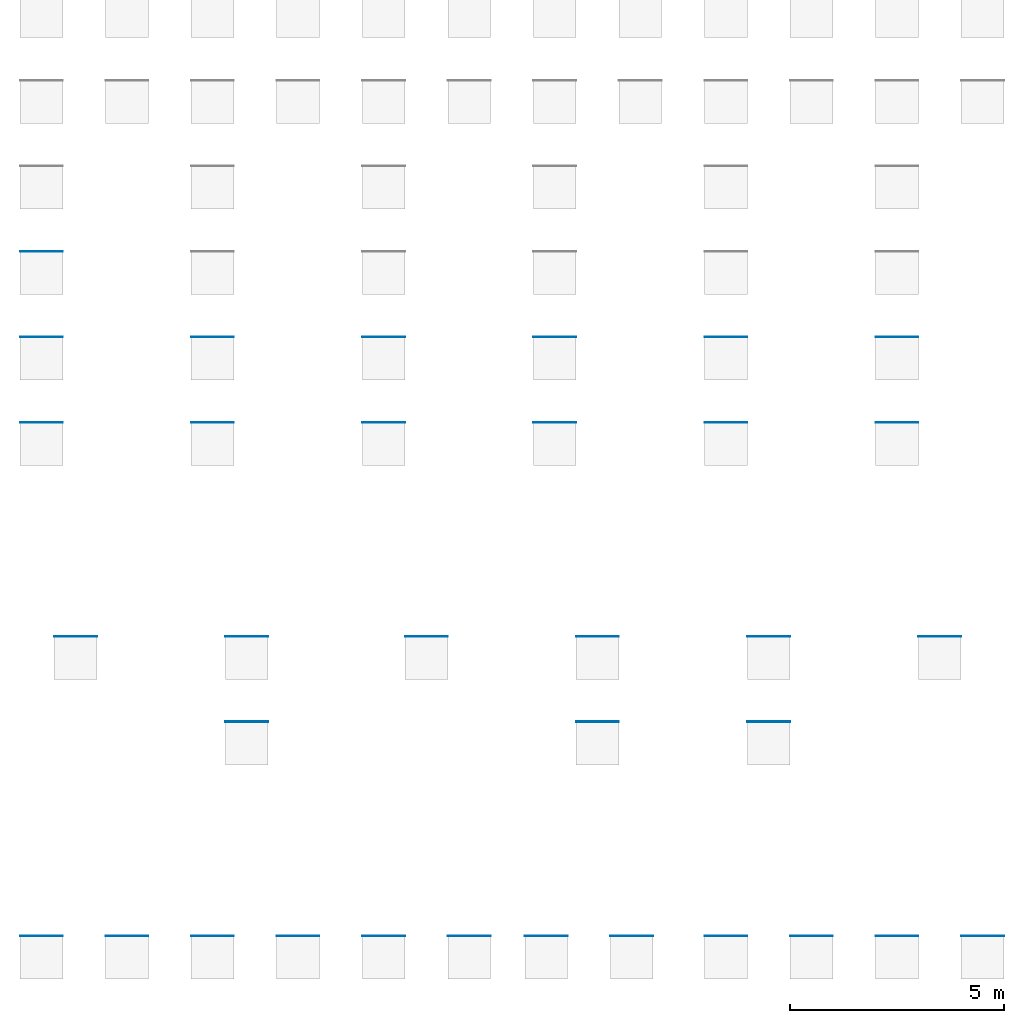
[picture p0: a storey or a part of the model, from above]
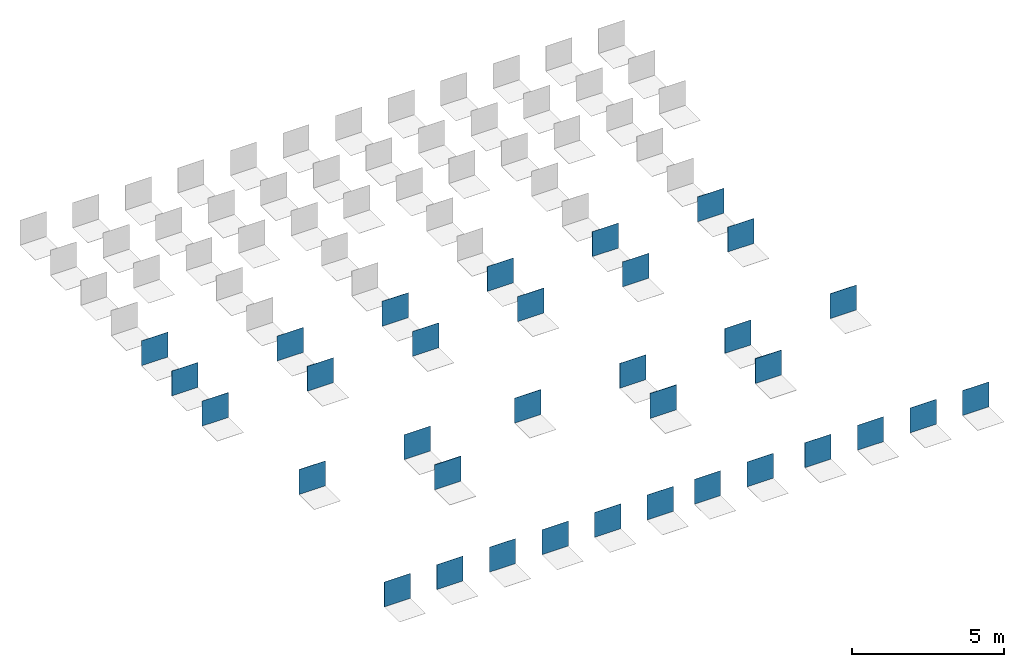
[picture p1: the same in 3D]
Properties of the parts of a building model (IFC2X3), part 1 of 12

# File
Description: ViewDefinition [CoordinationView_V2.0]
Time: 2025-06-20T15:58:34
Written by: The EXPRESS Data Manager Version 5.02.0100.07 : 28 Aug 2013
Made in: 21.1.90.15 - Exporter 21.1.90.15 - Alternate UI 21.1.90.15
Comment: STEP Physical File produced by: The EXPRESS Data Manager Version 5.02.0100.07 : 28 Aug 2013 * Module: EDMstepFileFactory/EDMstandAlone * Creation date: Fri Jun 20 15:58:34 2025 * Host: STB002 * Database: C:\Users\LARISS~1\AppData\Local\Temp\234e31d9-e186-458c-9206-d387dea7a233\3d1c4d9d-6237-41bf-87b0-bd08b7a5a8ec\ifc * Database version: 5507 * Database creation date: Fri Jun 20 15:58:30 2025 * Schema: IFC2X3 * Model: DataRepository.ifc * Model creation date: Fri Jun 20 15:58:30 2025 * Header model: DataRepository.ifc_HeaderModel * Header model creation date: Fri Jun 20 15:58:30 2025 * EDMuser: sdai-user * EDMgroup: sdai-group * License ID and type: 5605 : Permanent license. Expiry date: * EDMstepFileFactory options: 020000

# IfcSite, Default
RefLatitude: 42, 24, 53, 508911; RefLongitude: -71, -15, -29, -58837; RefElevation: 0 mm
Pset_ProductRequirements - Category: Project Information

# IfcBuilding
Pset_BuildingCommon - NumberOfStoreys: 1
Pset_ProductRequirements - Category: Project Information

# IfcBuildingStorey: Level:Level 1, Level 1
LongName: Level 1; Elevation: 0 mm
Pset_AirSideSystemInformation - Name: Level 1
Pset_ProductRequirements - Name: Level 1; Category: Levels

# IfcCovering: Floor:REVIGRÉS-URBAN-BASE-29,5X29,5-RECT-ANTRACITE, Floor:REVIGRÉS-URBAN-BASE-29,5X29,5-RECT-ANTRACITE:18907
In: Level 1
Type - PredefinedType: CLADDING; Material: REVIGRÉS-URBAN-BASE-30X30-RECT-ANTRACITE 7.7 mm
Type - Pset_CoveringCommon - Reference: 31211248U1; Material: Grés porcelânico
Type - Pset_ElementShading - Roughness: 304.8 mm
Type - Pset_ManufacturerTypeInformation - Manufacturer: REVIGRÉS
Type - Pset_ProductRequirements - Category: Floors
Type - Pset_QuantityTakeOff - Reference: 31211248U1
Type - IFC.REVIGRÉS-Dados do fabricante-Floor Covering - FabricanteURL: https://www.revigres.pt/; ReferenciaModelo: Urban; NumeroGlobalDeItemComercial: 31211248U1; Acabamento: RECT; Material: Grés porcelânico; IdentificadorDoOperadorEconomico: 501840856; UrlFabricanteArtigo: https://www.revigres.pt/colecoes/urban; PaisOrigem: Portugal
Type - IFC.REVIGRÉS-Dados de desempenho-Floor Covering - Rectilinearidade: ± 0.2% máx.± 0.8 mm; Ortogonalidade: ± 0.2% máx.± 1.5 mm; PlanaridadeDaSuperficie: ± 0.3% máx. ± 1.8 mm; QualidadeDaSuperficie: Cumpre; AbsorcaoDeAgua: < 0.05%; ModuloDeRuptura: > 45 N/mm²; ResistenciaAFlexao: > 1500 N; ResistenciaAAbrasaoProfunda: < 120 mm³; DilatacaoTermicaLinear: ≤ 8,0x10-6 °C-1; ResistenciaAoChoqueTermico: Resiste; DurabilidadeResistenciaAoGeloDegelo: Resiste; ResistenciaAoEscorregamentoDIN51130: R9; ResistenciaAoEscorregamentoDIN51097: A; ResistenciaAoEscorregamentoENV51097: A; ResistenciaAoEscorregamentoENV12633: Class 1; ResistenciaAoEscorregamentoANSIA1371: ≥0,42; ResistenciaAoDeslizamentoENV12633: Class 1; ResistenciaAsManchas: Class 5; ResistenciaABaixasConcentracoesDeAcidosEAlcalis: Classe LA; ResistenciaAAltasConcentracoesDeAcidosEAlcalis: Classe HA; LibertacaoDeCadmio: 0; LibertacaoDeChumbo: 0
Type - IFC.REVIGRÉS-Dados de especificação-Floor Covering - VariacaoTonalidade: 2; NivelDeTrafego: 5; EPavimento: Sim; ERevestimento: Sim; EExterno: Sim
Type - IFC.REVIGRÉS-Dados geométricos-Floor Covering - AlturaNominal: 7.7 mm; ComprimentoNominal: 29.5 mm; LarguraNominal: 29.5 mm
Type - IFC.REVIGRÉS-Dados de sustentabilidade-Floor Covering - EnergiaTermicaExportada: 0; ItemENovo: Sim; ItemEParcialmenteReciclado: 0.29; ItemEReciclado: Sim; VidaÚtilEsperada: 50; SubstanciasPerigosas: Não; PotencialDeEsgotamentoAbioticoDosRecursosFosseis: 203; PotencialDeEsgotamentoAbioticoDosRecursosNaoFosseisMineraisEMetais: 0.000701; PotencialDeAquecimentoGlobalBiogenico: -0.48; CombustiveisFosseisComPotencialDeAquecimentoGlobal: 13.9; PotencialDeAquecimentoGlobalUsoDoSoloEMudancaDeUsoDoSolo: 0.0246; PotencialDeEutrofizacaoFraccaoDeNutrientesQueAtingemOCompartimentoFinalDeAguaDoce: 0.000189; PotencialDeEutrofizacaoFraccaoDeNutrientesQueAtingemOCompartimentoFinalMarinho: 0.0122; EnergiaRecuperada: 0.00739; ConsumoDeAguaDoce: 0.113; UtilizacaoLiquidaDeAguaDoce: 0.113; ResiduosPerigososEliminados: 0.00221; ResiduosNaoPerigososEliminados: 1.83; MassaTotalDeResiduosRadioactivosEliminados: 0.000394; EnergiaElectricaExportada: 1.55; MateriaisParaRecuperacaoDeEnergia: 0.00739; MateriaisParaReciclagem: 0.0253; UnidadeEPD: 1 m²
Type - IFC.REVIGRÉS-Dados gerais-Floor Covering - Nome: REVIGRÉS-URBAN-BASE-29.5X29.5-RECT-URBAN ANTRACITE; TipoProduto: Prensado a seco: grupo BIa UGL | Grés porcelânico técnico; NumeroDeRegistoDAP: EPD-REV-20240006-CCC1-EN; ReferenciaDAP: -; UrlDOP: -
Classification: C3020 (Uniformat)
Pset_CoveringCommon - TotalThickness: 7.7 mm
IFC.REVIGRÉS-Dados do fabricante-Floor Covering - Type: Floor: REVIGRÉS-URBAN-BASE-29,5X29,5-RECT-ANTRACITE
IFC.REVIGRÉS-Dados de desempenho-Floor Covering - Type: Floor: REVIGRÉS-URBAN-BASE-29,5X29,5-RECT-ANTRACITE
IFC.REVIGRÉS-Dados de especificação-Floor Covering - Type: Floor: REVIGRÉS-URBAN-BASE-29,5X29,5-RECT-ANTRACITE
IFC.REVIGRÉS-Dados geométricos-Floor Covering - Type: Floor: REVIGRÉS-URBAN-BASE-29,5X29,5-RECT-ANTRACITE
IFC.REVIGRÉS-Dados de sustentabilidade-Floor Covering - Type: Floor: REVIGRÉS-URBAN-BASE-29,5X29,5-RECT-ANTRACITE

# IfcCovering: Floor:REVIGRÉS-URBAN-BASE-29,5X29,5-RECT-BONE, Floor:REVIGRÉS-URBAN-BASE-29,5X29,5-RECT-BONE:21508
In: Level 1
Type - PredefinedType: CLADDING; Material: REVIGRÉS-URBAN-BASE-30X30-RECT-BONE 7.7 mm
Type - Pset_CoveringCommon - Reference: 312112X671; Material: Grés porcelânico
Type - Pset_ElementShading - Roughness: 304.8 mm
Type - Pset_ManufacturerTypeInformation - Manufacturer: REVIGRÉS
Type - Pset_ProductRequirements - Category: Floors
Type - Pset_QuantityTakeOff - Reference: 312112X671
Type - IFC.REVIGRÉS-Dados do fabricante-Floor Covering - FabricanteURL: https://www.revigres.pt/; ReferenciaModelo: Urban; NumeroGlobalDeItemComercial: 312112X671; Acabamento: RECT; Material: Grés porcelânico; IdentificadorDoOperadorEconomico: 501840856; UrlFabricanteArtigo: https://www.revigres.pt/colecoes/urban; PaisOrigem: Portugal
Type - IFC.REVIGRÉS-Dados de desempenho-Floor Covering - Rectilinearidade: ± 0.2% máx.± 0.8 mm; Ortogonalidade: ± 0.2% máx.± 1.5 mm; PlanaridadeDaSuperficie: ± 0.3% máx. ± 1.8 mm; QualidadeDaSuperficie: Cumpre; AbsorcaoDeAgua: < 0.05%; ModuloDeRuptura: > 45 N/mm²; ResistenciaAFlexao: > 1500 N; ResistenciaAAbrasaoProfunda: < 120 mm³; DilatacaoTermicaLinear: ≤ 8,0x10-6 °C-1; ResistenciaAoChoqueTermico: Resiste; DurabilidadeResistenciaAoGeloDegelo: Resiste; ResistenciaAoEscorregamentoDIN51130: R9; ResistenciaAoEscorregamentoDIN51097: A; ResistenciaAoEscorregamentoENV51097: A; ResistenciaAoEscorregamentoENV12633: Class 1; ResistenciaAoEscorregamentoANSIA1371: ≥0,42; ResistenciaAoDeslizamentoENV12633: Class 1; ResistenciaAsManchas: Class 5; ResistenciaABaixasConcentracoesDeAcidosEAlcalis: Classe LA; ResistenciaAAltasConcentracoesDeAcidosEAlcalis: Classe HA; LibertacaoDeCadmio: 0; LibertacaoDeChumbo: 0
Type - IFC.REVIGRÉS-Dados de especificação-Floor Covering - VariacaoTonalidade: 2; NivelDeTrafego: 5; EPavimento: Sim; ERevestimento: Sim; EExterno: Sim
Type - IFC.REVIGRÉS-Dados geométricos-Floor Covering - AlturaNominal: 7.7 mm; ComprimentoNominal: 29.5 mm; LarguraNominal: 29.5 mm
Type - IFC.REVIGRÉS-Dados de sustentabilidade-Floor Covering - EnergiaTermicaExportada: 0; ItemENovo: Sim; ItemEParcialmenteReciclado: 0.03; ItemEReciclado: Sim; VidaÚtilEsperada: 50; SubstanciasPerigosas: Não; PotencialDeEsgotamentoAbioticoDosRecursosFosseis: 203; PotencialDeEsgotamentoAbioticoDosRecursosNaoFosseisMineraisEMetais: 0.000701; PotencialDeAquecimentoGlobalBiogenico: -0.48; CombustiveisFosseisComPotencialDeAquecimentoGlobal: 13.9; PotencialDeAquecimentoGlobalUsoDoSoloEMudancaDeUsoDoSolo: 0.0246; PotencialDeEutrofizacaoFraccaoDeNutrientesQueAtingemOCompartimentoFinalDeAguaDoce: 0.000189; PotencialDeEutrofizacaoFraccaoDeNutrientesQueAtingemOCompartimentoFinalMarinho: 0.0122; EnergiaRecuperada: 0.00739; ConsumoDeAguaDoce: 0.113; UtilizacaoLiquidaDeAguaDoce: 0.113; ResiduosPerigososEliminados: 0.00221; ResiduosNaoPerigososEliminados: 1.83; MassaTotalDeResiduosRadioactivosEliminados: 0.000394; EnergiaElectricaExportada: 1.55; MateriaisParaRecuperacaoDeEnergia: 0.00739; MateriaisParaReciclagem: 0.0253; UnidadeEPD: 1 m²
Type - IFC.REVIGRÉS-Dados gerais-Floor Covering - Nome: REVIGRÉS-URBAN-BASE-29.5X29.5-RECT-URBAN BONE; TipoProduto: Prensado a seco: grupo BIa UGL | Grés porcelânico técnico; NumeroDeRegistoDAP: EPD-REV-20240006-CCC1-EN; ReferenciaDAP: -; UrlDOP: -
Classification: C3020 (Uniformat)
Pset_CoveringCommon - TotalThickness: 7.7 mm
IFC.REVIGRÉS-Dados do fabricante-Floor Covering - Type: Floor: REVIGRÉS-URBAN-BASE-29,5X29,5-RECT-BONE
IFC.REVIGRÉS-Dados de desempenho-Floor Covering - Type: Floor: REVIGRÉS-URBAN-BASE-29,5X29,5-RECT-BONE
IFC.REVIGRÉS-Dados de especificação-Floor Covering - Type: Floor: REVIGRÉS-URBAN-BASE-29,5X29,5-RECT-BONE
IFC.REVIGRÉS-Dados geométricos-Floor Covering - Type: Floor: REVIGRÉS-URBAN-BASE-29,5X29,5-RECT-BONE
IFC.REVIGRÉS-Dados de sustentabilidade-Floor Covering - Type: Floor: REVIGRÉS-URBAN-BASE-29,5X29,5-RECT-BONE

# IfcCovering: Floor:REVIGRÉS-URBAN-BASE-29,5X29,5-RECT-CRAFT, Floor:REVIGRÉS-URBAN-BASE-29,5X29,5-RECT-CRAFT:21530
In: Level 1
Type - PredefinedType: CLADDING; Material: REVIGRÉS-URBAN-BASE-30X30-RECT-CRAFT 7.7 mm
Type - Pset_CoveringCommon - Reference: 31211224T1; Material: Grés porcelânico
Type - Pset_ElementShading - Roughness: 304.8 mm
Type - Pset_ManufacturerTypeInformation - Manufacturer: REVIGRÉS
Type - Pset_ProductRequirements - Category: Floors
Type - Pset_QuantityTakeOff - Reference: 31211224T1
Type - IFC.REVIGRÉS-Dados do fabricante-Floor Covering - FabricanteURL: https://www.revigres.pt/; ReferenciaModelo: Urban; NumeroGlobalDeItemComercial: 31211224T1; Acabamento: RECT; Material: Grés porcelânico; IdentificadorDoOperadorEconomico: 501840856; UrlFabricanteArtigo: https://www.revigres.pt/colecoes/urban; PaisOrigem: Portugal
Type - IFC.REVIGRÉS-Dados de desempenho-Floor Covering - Rectilinearidade: ± 0.2% máx.± 0.8 mm; Ortogonalidade: ± 0.2% máx.± 1.5 mm; PlanaridadeDaSuperficie: ± 0.3% máx. ± 1.8 mm; QualidadeDaSuperficie: Cumpre; AbsorcaoDeAgua: < 0.05%; ModuloDeRuptura: > 45 N/mm²; ResistenciaAFlexao: > 1500 N; ResistenciaAAbrasaoProfunda: < 120 mm³; DilatacaoTermicaLinear: ≤ 8,0x10-6 °C-1; ResistenciaAoChoqueTermico: Resiste; DurabilidadeResistenciaAoGeloDegelo: Resiste; ResistenciaAoEscorregamentoDIN51130: R9; ResistenciaAoEscorregamentoDIN51097: A; ResistenciaAoEscorregamentoENV51097: A; ResistenciaAoEscorregamentoENV12633: Class 1; ResistenciaAoEscorregamentoANSIA1371: ≥0,42; ResistenciaAoDeslizamentoENV12633: Class 1; ResistenciaAsManchas: Class 5; ResistenciaABaixasConcentracoesDeAcidosEAlcalis: Classe LA; ResistenciaAAltasConcentracoesDeAcidosEAlcalis: Classe HA; LibertacaoDeCadmio: 0; LibertacaoDeChumbo: 0
Type - IFC.REVIGRÉS-Dados de especificação-Floor Covering - VariacaoTonalidade: 2; NivelDeTrafego: 5; EPavimento: Sim; ERevestimento: Sim; EExterno: Sim
Type - IFC.REVIGRÉS-Dados geométricos-Floor Covering - AlturaNominal: 7.7 mm; ComprimentoNominal: 29.5 mm; LarguraNominal: 29.5 mm
Type - IFC.REVIGRÉS-Dados de sustentabilidade-Floor Covering - EnergiaTermicaExportada: 0; ItemENovo: Sim; ItemEParcialmenteReciclado: 0.19; ItemEReciclado: Sim; VidaÚtilEsperada: 50; SubstanciasPerigosas: Não; PotencialDeEsgotamentoAbioticoDosRecursosFosseis: 203; PotencialDeEsgotamentoAbioticoDosRecursosNaoFosseisMineraisEMetais: 0.000701; PotencialDeAquecimentoGlobalBiogenico: -0.48; CombustiveisFosseisComPotencialDeAquecimentoGlobal: 13.9; PotencialDeAquecimentoGlobalUsoDoSoloEMudancaDeUsoDoSolo: 0.0246; PotencialDeEutrofizacaoFraccaoDeNutrientesQueAtingemOCompartimentoFinalDeAguaDoce: 0.000189; PotencialDeEutrofizacaoFraccaoDeNutrientesQueAtingemOCompartimentoFinalMarinho: 0.0122; EnergiaRecuperada: 0.00739; ConsumoDeAguaDoce: 0.113; UtilizacaoLiquidaDeAguaDoce: 0.113; ResiduosPerigososEliminados: 0.00221; ResiduosNaoPerigososEliminados: 1.83; MassaTotalDeResiduosRadioactivosEliminados: 0.000394; EnergiaElectricaExportada: 1.55; MateriaisParaRecuperacaoDeEnergia: 0.00739; MateriaisParaReciclagem: 0.0253; UnidadeEPD: 1 m²
Type - IFC.REVIGRÉS-Dados gerais-Floor Covering - Nome: REVIGRÉS-URBAN-BASE-29.5X29.5-RECT-URBAN CRAFT; TipoProduto: Prensado a seco: grupo BIa UGL | Grés porcelânico técnico; NumeroDeRegistoDAP: EPD-REV-20240006-CCC1-EN; ReferenciaDAP: -; UrlDOP: -
Classification: C3020 (Uniformat)
Pset_CoveringCommon - TotalThickness: 7.7 mm
IFC.REVIGRÉS-Dados do fabricante-Floor Covering - Type: Floor: REVIGRÉS-URBAN-BASE-29,5X29,5-RECT-CRAFT
IFC.REVIGRÉS-Dados de desempenho-Floor Covering - Type: Floor: REVIGRÉS-URBAN-BASE-29,5X29,5-RECT-CRAFT
IFC.REVIGRÉS-Dados de especificação-Floor Covering - Type: Floor: REVIGRÉS-URBAN-BASE-29,5X29,5-RECT-CRAFT
IFC.REVIGRÉS-Dados geométricos-Floor Covering - Type: Floor: REVIGRÉS-URBAN-BASE-29,5X29,5-RECT-CRAFT
IFC.REVIGRÉS-Dados de sustentabilidade-Floor Covering - Type: Floor: REVIGRÉS-URBAN-BASE-29,5X29,5-RECT-CRAFT

# IfcCovering: Floor:REVIGRÉS-URBAN-BASE-29,5X29,5-RECT-FOG, Floor:REVIGRÉS-URBAN-BASE-29,5X29,5-RECT-FOG:21552
In: Level 1
Type - PredefinedType: CLADDING; Material: REVIGRÉS-URBAN-BASE-30X30-RECT-FOG 7.7 mm
Type - Pset_CoveringCommon - Reference: 31211221T1; Material: Grés porcelânico
Type - Pset_ElementShading - Roughness: 304.8 mm
Type - Pset_ManufacturerTypeInformation - Manufacturer: REVIGRÉS
Type - Pset_ProductRequirements - Category: Floors
Type - Pset_QuantityTakeOff - Reference: 31211221T1
Type - IFC.REVIGRÉS-Dados do fabricante-Floor Covering - FabricanteURL: https://www.revigres.pt/; ReferenciaModelo: Urban; NumeroGlobalDeItemComercial: 31211221T1; Acabamento: RECT; Material: Grés porcelânico; IdentificadorDoOperadorEconomico: 501840856; UrlFabricanteArtigo: https://www.revigres.pt/colecoes/urban; PaisOrigem: Portugal
Type - IFC.REVIGRÉS-Dados de desempenho-Floor Covering - Rectilinearidade: ± 0.2% máx.± 0.8 mm; Ortogonalidade: ± 0.2% máx.± 1.5 mm; PlanaridadeDaSuperficie: ± 0.3% máx. ± 1.8 mm; QualidadeDaSuperficie: Cumpre; AbsorcaoDeAgua: < 0.05%; ModuloDeRuptura: > 45 N/mm²; ResistenciaAFlexao: > 1500 N; ResistenciaAAbrasaoProfunda: < 120 mm³; DilatacaoTermicaLinear: ≤ 8,0x10-6 °C-1; ResistenciaAoChoqueTermico: Resiste; DurabilidadeResistenciaAoGeloDegelo: Resiste; ResistenciaAoEscorregamentoDIN51130: R9; ResistenciaAoEscorregamentoDIN51097: A; ResistenciaAoEscorregamentoENV51097: A; ResistenciaAoEscorregamentoENV12633: Class 1; ResistenciaAoEscorregamentoANSIA1371: ≥0,42; ResistenciaAoDeslizamentoENV12633: Class 1; ResistenciaAsManchas: Class 5; ResistenciaABaixasConcentracoesDeAcidosEAlcalis: Classe LA; ResistenciaAAltasConcentracoesDeAcidosEAlcalis: Classe HA; LibertacaoDeCadmio: 0; LibertacaoDeChumbo: 0
Type - IFC.REVIGRÉS-Dados de especificação-Floor Covering - VariacaoTonalidade: 2; NivelDeTrafego: 5; EPavimento: Sim; ERevestimento: Sim; EExterno: Sim
Type - IFC.REVIGRÉS-Dados geométricos-Floor Covering - AlturaNominal: 7.7 mm; ComprimentoNominal: 29.5 mm; LarguraNominal: 29.5 mm
Type - IFC.REVIGRÉS-Dados de sustentabilidade-Floor Covering - EnergiaTermicaExportada: 0; ItemENovo: Sim; ItemEParcialmenteReciclado: 0.23; ItemEReciclado: Sim; VidaÚtilEsperada: 50; SubstanciasPerigosas: Não; PotencialDeEsgotamentoAbioticoDosRecursosFosseis: 203; PotencialDeEsgotamentoAbioticoDosRecursosNaoFosseisMineraisEMetais: 0.000701; PotencialDeAquecimentoGlobalBiogenico: -0.48; CombustiveisFosseisComPotencialDeAquecimentoGlobal: 13.9; PotencialDeAquecimentoGlobalUsoDoSoloEMudancaDeUsoDoSolo: 0.0246; PotencialDeEutrofizacaoFraccaoDeNutrientesQueAtingemOCompartimentoFinalDeAguaDoce: 0.000189; PotencialDeEutrofizacaoFraccaoDeNutrientesQueAtingemOCompartimentoFinalMarinho: 0.0122; EnergiaRecuperada: 0.00739; ConsumoDeAguaDoce: 0.113; UtilizacaoLiquidaDeAguaDoce: 0.113; ResiduosPerigososEliminados: 0.00221; ResiduosNaoPerigososEliminados: 1.83; MassaTotalDeResiduosRadioactivosEliminados: 0.000394; EnergiaElectricaExportada: 1.55; MateriaisParaRecuperacaoDeEnergia: 0.00739; MateriaisParaReciclagem: 0.0253; UnidadeEPD: 1 m²
Type - IFC.REVIGRÉS-Dados gerais-Floor Covering - Nome: REVIGRÉS-URBAN-BASE-29.5X29.5-RECT-URBAN FOG; TipoProduto: Prensado a seco: grupo BIa UGL | Grés porcelânico técnico; NumeroDeRegistoDAP: EPD-REV-20240006-CCC1-EN; ReferenciaDAP: -; UrlDOP: -
Classification: C3020 (Uniformat)
Pset_CoveringCommon - TotalThickness: 7.7 mm
IFC.REVIGRÉS-Dados do fabricante-Floor Covering - Type: Floor: REVIGRÉS-URBAN-BASE-29,5X29,5-RECT-FOG
IFC.REVIGRÉS-Dados de desempenho-Floor Covering - Type: Floor: REVIGRÉS-URBAN-BASE-29,5X29,5-RECT-FOG
IFC.REVIGRÉS-Dados de especificação-Floor Covering - Type: Floor: REVIGRÉS-URBAN-BASE-29,5X29,5-RECT-FOG
IFC.REVIGRÉS-Dados geométricos-Floor Covering - Type: Floor: REVIGRÉS-URBAN-BASE-29,5X29,5-RECT-FOG
IFC.REVIGRÉS-Dados de sustentabilidade-Floor Covering - Type: Floor: REVIGRÉS-URBAN-BASE-29,5X29,5-RECT-FOG

# IfcCovering: Floor:REVIGRÉS-URBAN-BASE-29,5X29,5-RECT-GRIS, Floor:REVIGRÉS-URBAN-BASE-29,5X29,5-RECT-GRIS:21574
In: Level 1
Type - PredefinedType: CLADDING; Material: REVIGRÉS-URBAN-BASE-30X30-RECT-GRIS 7.7 mm
Type - Pset_CoveringCommon - Reference: 31211222T1; Material: Grés porcelânico
Type - Pset_ElementShading - Roughness: 304.8 mm
Type - Pset_ManufacturerTypeInformation - Manufacturer: REVIGRÉS
Type - Pset_ProductRequirements - Category: Floors
Type - Pset_QuantityTakeOff - Reference: 31211222T1
Type - IFC.REVIGRÉS-Dados do fabricante-Floor Covering - FabricanteURL: https://www.revigres.pt/; ReferenciaModelo: Urban; NumeroGlobalDeItemComercial: 31211222T1; Acabamento: RECT; Material: Grés porcelânico; IdentificadorDoOperadorEconomico: 501840856; UrlFabricanteArtigo: https://www.revigres.pt/colecoes/urban; PaisOrigem: Portugal
Type - IFC.REVIGRÉS-Dados de desempenho-Floor Covering - Rectilinearidade: ± 0.2% máx.± 0.8 mm; Ortogonalidade: ± 0.2% máx.± 1.5 mm; PlanaridadeDaSuperficie: ± 0.3% máx. ± 1.8 mm; QualidadeDaSuperficie: Cumpre; AbsorcaoDeAgua: < 0.05%; ModuloDeRuptura: > 45 N/mm²; ResistenciaAFlexao: > 1500 N; ResistenciaAAbrasaoProfunda: < 120 mm³; DilatacaoTermicaLinear: ≤ 8,0x10-6 °C-1; ResistenciaAoChoqueTermico: Resiste; DurabilidadeResistenciaAoGeloDegelo: Resiste; ResistenciaAoEscorregamentoDIN51130: R9; ResistenciaAoEscorregamentoDIN51097: A; ResistenciaAoEscorregamentoENV51097: A; ResistenciaAoEscorregamentoENV12633: Class 1; ResistenciaAoEscorregamentoANSIA1371: ≥0,42; ResistenciaAoDeslizamentoENV12633: Class 1; ResistenciaAsManchas: Class 5; ResistenciaABaixasConcentracoesDeAcidosEAlcalis: Classe LA; ResistenciaAAltasConcentracoesDeAcidosEAlcalis: Classe HA; LibertacaoDeCadmio: 0; LibertacaoDeChumbo: 0
Type - IFC.REVIGRÉS-Dados de especificação-Floor Covering - VariacaoTonalidade: 2; NivelDeTrafego: 5; EPavimento: Sim; ERevestimento: Sim; EExterno: Sim
Type - IFC.REVIGRÉS-Dados geométricos-Floor Covering - AlturaNominal: 7.7 mm; ComprimentoNominal: 29.5 mm; LarguraNominal: 29.5 mm
Type - IFC.REVIGRÉS-Dados de sustentabilidade-Floor Covering - EnergiaTermicaExportada: 0; ItemENovo: Sim; ItemEParcialmenteReciclado: 0.23; ItemEReciclado: Sim; VidaÚtilEsperada: 50; SubstanciasPerigosas: Não; PotencialDeEsgotamentoAbioticoDosRecursosFosseis: 203; PotencialDeEsgotamentoAbioticoDosRecursosNaoFosseisMineraisEMetais: 0.000701; PotencialDeAquecimentoGlobalBiogenico: -0.48; CombustiveisFosseisComPotencialDeAquecimentoGlobal: 13.9; PotencialDeAquecimentoGlobalUsoDoSoloEMudancaDeUsoDoSolo: 0.0246; PotencialDeEutrofizacaoFraccaoDeNutrientesQueAtingemOCompartimentoFinalDeAguaDoce: 0.000189; PotencialDeEutrofizacaoFraccaoDeNutrientesQueAtingemOCompartimentoFinalMarinho: 0.0122; EnergiaRecuperada: 0.00739; ConsumoDeAguaDoce: 0.113; UtilizacaoLiquidaDeAguaDoce: 0.113; ResiduosPerigososEliminados: 0.00221; ResiduosNaoPerigososEliminados: 1.83; MassaTotalDeResiduosRadioactivosEliminados: 0.000394; EnergiaElectricaExportada: 1.55; MateriaisParaRecuperacaoDeEnergia: 0.00739; MateriaisParaReciclagem: 0.0253; UnidadeEPD: 1 m²
Type - IFC.REVIGRÉS-Dados gerais-Floor Covering - Nome: REVIGRÉS-URBAN-BASE-29.5X29.5-RECT-URBAN GRIS; TipoProduto: Prensado a seco: grupo BIa UGL | Grés porcelânico técnico; NumeroDeRegistoDAP: EPD-REV-20240006-CCC1-EN; ReferenciaDAP: -; UrlDOP: -
Classification: C3020 (Uniformat)
Pset_CoveringCommon - TotalThickness: 7.7 mm
IFC.REVIGRÉS-Dados do fabricante-Floor Covering - Type: Floor: REVIGRÉS-URBAN-BASE-29,5X29,5-RECT-GRIS
IFC.REVIGRÉS-Dados de desempenho-Floor Covering - Type: Floor: REVIGRÉS-URBAN-BASE-29,5X29,5-RECT-GRIS
IFC.REVIGRÉS-Dados de especificação-Floor Covering - Type: Floor: REVIGRÉS-URBAN-BASE-29,5X29,5-RECT-GRIS
IFC.REVIGRÉS-Dados geométricos-Floor Covering - Type: Floor: REVIGRÉS-URBAN-BASE-29,5X29,5-RECT-GRIS
IFC.REVIGRÉS-Dados de sustentabilidade-Floor Covering - Type: Floor: REVIGRÉS-URBAN-BASE-29,5X29,5-RECT-GRIS

# IfcCovering: Floor:REVIGRÉS-URBAN-BASE-29,5X29,5-RECT-OFFWHITE, Floor:REVIGRÉS-URBAN-BASE-29,5X29,5-RECT-OFFWHITE:21596
In: Level 1
Type - PredefinedType: CLADDING; Material: REVIGRÉS-URBAN-BASE-30X30-RECT-OFFWHITE 7.7 mm
Type - Pset_CoveringCommon - Reference: 31211223T1; Material: Grés porcelânico
Type - Pset_ElementShading - Roughness: 304.8 mm
Type - Pset_ManufacturerTypeInformation - Manufacturer: REVIGRÉS
Type - Pset_ProductRequirements - Category: Floors
Type - Pset_QuantityTakeOff - Reference: 31211223T1
Type - IFC.REVIGRÉS-Dados do fabricante-Floor Covering - FabricanteURL: https://www.revigres.pt/; ReferenciaModelo: Urban; NumeroGlobalDeItemComercial: 31211223T1; Acabamento: RECT; Material: Grés porcelânico; IdentificadorDoOperadorEconomico: 501840856; UrlFabricanteArtigo: https://www.revigres.pt/colecoes/urban; PaisOrigem: Portugal
Type - IFC.REVIGRÉS-Dados de desempenho-Floor Covering - Rectilinearidade: ± 0.2% máx.± 0.8 mm; Ortogonalidade: ± 0.2% máx.± 1.5 mm; PlanaridadeDaSuperficie: ± 0.3% máx. ± 1.8 mm; QualidadeDaSuperficie: Cumpre; AbsorcaoDeAgua: < 0.05%; ModuloDeRuptura: > 45 N/mm²; ResistenciaAFlexao: > 1500 N; ResistenciaAAbrasaoProfunda: < 120 mm³; DilatacaoTermicaLinear: ≤ 8,0x10-6 °C-1; ResistenciaAoChoqueTermico: Resiste; DurabilidadeResistenciaAoGeloDegelo: Resiste; ResistenciaAoEscorregamentoDIN51130: R9; ResistenciaAoEscorregamentoDIN51097: A; ResistenciaAoEscorregamentoENV51097: A; ResistenciaAoEscorregamentoENV12633: Class 1; ResistenciaAoEscorregamentoANSIA1371: ≥0,42; ResistenciaAoDeslizamentoENV12633: Class 1; ResistenciaAsManchas: Class 5; ResistenciaABaixasConcentracoesDeAcidosEAlcalis: Classe LA; ResistenciaAAltasConcentracoesDeAcidosEAlcalis: Classe HA; LibertacaoDeCadmio: 0; LibertacaoDeChumbo: 0
Type - IFC.REVIGRÉS-Dados de especificação-Floor Covering - VariacaoTonalidade: 2; NivelDeTrafego: 5; EPavimento: Sim; ERevestimento: Sim; EExterno: Sim
Type - IFC.REVIGRÉS-Dados geométricos-Floor Covering - AlturaNominal: 7.7 mm; ComprimentoNominal: 29.5 mm; LarguraNominal: 29.5 mm
Type - IFC.REVIGRÉS-Dados de sustentabilidade-Floor Covering - EnergiaTermicaExportada: 0; ItemENovo: Sim; ItemEParcialmenteReciclado: 0.03; ItemEReciclado: Sim; VidaÚtilEsperada: 50; SubstanciasPerigosas: Não; PotencialDeEsgotamentoAbioticoDosRecursosFosseis: 203; PotencialDeEsgotamentoAbioticoDosRecursosNaoFosseisMineraisEMetais: 0.000701; PotencialDeAquecimentoGlobalBiogenico: -0.48; CombustiveisFosseisComPotencialDeAquecimentoGlobal: 13.9; PotencialDeAquecimentoGlobalUsoDoSoloEMudancaDeUsoDoSolo: 0.0246; PotencialDeEutrofizacaoFraccaoDeNutrientesQueAtingemOCompartimentoFinalDeAguaDoce: 0.000189; PotencialDeEutrofizacaoFraccaoDeNutrientesQueAtingemOCompartimentoFinalMarinho: 0.0122; EnergiaRecuperada: 0.00739; ConsumoDeAguaDoce: 0.113; UtilizacaoLiquidaDeAguaDoce: 0.113; ResiduosPerigososEliminados: 0.00221; ResiduosNaoPerigososEliminados: 1.83; MassaTotalDeResiduosRadioactivosEliminados: 0.000394; EnergiaElectricaExportada: 1.55; MateriaisParaRecuperacaoDeEnergia: 0.00739; MateriaisParaReciclagem: 0.0253; UnidadeEPD: 1 m²
Type - IFC.REVIGRÉS-Dados gerais-Floor Covering - Nome: REVIGRÉS-URBAN-BASE-29.5X29.5-RECT-URBAN OFFWHITE; TipoProduto: Prensado a seco: grupo BIa UGL | Grés porcelânico técnico; NumeroDeRegistoDAP: EPD-REV-20240006-CCC1-EN; ReferenciaDAP: -; UrlDOP: -
Classification: C3020 (Uniformat)
Pset_CoveringCommon - TotalThickness: 7.7 mm
IFC.REVIGRÉS-Dados do fabricante-Floor Covering - Type: Floor: REVIGRÉS-URBAN-BASE-29,5X29,5-RECT-OFFWHITE
IFC.REVIGRÉS-Dados de desempenho-Floor Covering - Type: Floor: REVIGRÉS-URBAN-BASE-29,5X29,5-RECT-OFFWHITE
IFC.REVIGRÉS-Dados de especificação-Floor Covering - Type: Floor: REVIGRÉS-URBAN-BASE-29,5X29,5-RECT-OFFWHITE
IFC.REVIGRÉS-Dados geométricos-Floor Covering - Type: Floor: REVIGRÉS-URBAN-BASE-29,5X29,5-RECT-OFFWHITE
IFC.REVIGRÉS-Dados de sustentabilidade-Floor Covering - Type: Floor: REVIGRÉS-URBAN-BASE-29,5X29,5-RECT-OFFWHITE

# IfcCovering: Floor:REVIGRÉS-URBAN-BASE-29,5X59,2-RECT-ANTRACITE, Floor:REVIGRÉS-URBAN-BASE-29,5X59,2-RECT-ANTRACITE:22474
In: Level 1
Type - PredefinedType: CLADDING; Material: REVIGRÉS-URBAN-BASE-30X60-RECT-ANTRACITE 8.5 mm
Type - Pset_CoveringCommon - Reference: 31212148U1; Material: Grés porcelânico
Type - Pset_ElementShading - Roughness: 304.8 mm
Type - Pset_ManufacturerTypeInformation - Manufacturer: REVIGRÉS
Type - Pset_ProductRequirements - Category: Floors
Type - Pset_QuantityTakeOff - Reference: 31212148U1
Type - IFC.REVIGRÉS-Dados do fabricante-Floor Covering - FabricanteURL: https://www.revigres.pt/; ReferenciaModelo: Urban; NumeroGlobalDeItemComercial: 31212148U1; Acabamento: RECT; Material: Grés porcelânico; IdentificadorDoOperadorEconomico: 501840856; UrlFabricanteArtigo: https://www.revigres.pt/colecoes/urban; PaisOrigem: Portugal
Type - IFC.REVIGRÉS-Dados de desempenho-Floor Covering - Rectilinearidade: ± 0.2% máx.± 0.8 mm; Ortogonalidade: ± 0.2% máx.± 1.5 mm; PlanaridadeDaSuperficie: ± 0.3% máx. ± 1.8 mm; QualidadeDaSuperficie: Cumpre; AbsorcaoDeAgua: < 0.05%; ModuloDeRuptura: > 45 N/mm²; ResistenciaAFlexao: > 2000 N; ResistenciaAAbrasaoProfunda: < 120 mm³; DilatacaoTermicaLinear: ≤ 8,0x10-6 °C-1; ResistenciaAoChoqueTermico: Resiste; DurabilidadeResistenciaAoGeloDegelo: Resiste; ResistenciaAoEscorregamentoDIN51130: R9; ResistenciaAoEscorregamentoDIN51097: A; ResistenciaAoEscorregamentoENV51097: A; ResistenciaAoEscorregamentoENV12633: Class 1; ResistenciaAoEscorregamentoANSIA1371: ≥0,42; ResistenciaAoDeslizamentoENV12633: Class 1; ResistenciaAsManchas: Class 5; ResistenciaABaixasConcentracoesDeAcidosEAlcalis: Classe LA; ResistenciaAAltasConcentracoesDeAcidosEAlcalis: Classe HA; LibertacaoDeCadmio: 0; LibertacaoDeChumbo: 0
Type - IFC.REVIGRÉS-Dados de especificação-Floor Covering - VariacaoTonalidade: 2; NivelDeTrafego: 5; EPavimento: Sim; ERevestimento: Sim; EExterno: Sim
Type - IFC.REVIGRÉS-Dados geométricos-Floor Covering - AlturaNominal: 8.5 mm; ComprimentoNominal: 29.5 mm; LarguraNominal: 59.2 mm
Type - IFC.REVIGRÉS-Dados de sustentabilidade-Floor Covering - EnergiaTermicaExportada: 0; ItemENovo: Sim; ItemEParcialmenteReciclado: 0.29; ItemEReciclado: Sim; VidaÚtilEsperada: 50; SubstanciasPerigosas: Não; PotencialDeEsgotamentoAbioticoDosRecursosFosseis: 203; PotencialDeEsgotamentoAbioticoDosRecursosNaoFosseisMineraisEMetais: 0.000701; PotencialDeAquecimentoGlobalBiogenico: -0.48; CombustiveisFosseisComPotencialDeAquecimentoGlobal: 13.9; PotencialDeAquecimentoGlobalUsoDoSoloEMudancaDeUsoDoSolo: 0.0246; PotencialDeEutrofizacaoFraccaoDeNutrientesQueAtingemOCompartimentoFinalDeAguaDoce: 0.000189; PotencialDeEutrofizacaoFraccaoDeNutrientesQueAtingemOCompartimentoFinalMarinho: 0.0122; EnergiaRecuperada: 0.00739; ConsumoDeAguaDoce: 0.113; UtilizacaoLiquidaDeAguaDoce: 0.113; ResiduosPerigososEliminados: 0.00221; ResiduosNaoPerigososEliminados: 1.83; MassaTotalDeResiduosRadioactivosEliminados: 0.000394; EnergiaElectricaExportada: 1.55; MateriaisParaRecuperacaoDeEnergia: 0.00739; MateriaisParaReciclagem: 0.0253; UnidadeEPD: 1 m²
Type - IFC.REVIGRÉS-Dados gerais-Floor Covering - Nome: REVIGRÉS-URBAN-BASE-29.5X59.2-RECT-URBAN ANTRACITE; TipoProduto: Prensado a seco: grupo BIa UGL | Grés porcelânico técnico; NumeroDeRegistoDAP: EPD-REV-20240006-CCC1-EN; ReferenciaDAP: -; UrlDOP: -
Classification: C3020 (Uniformat)
Pset_CoveringCommon - TotalThickness: 8.5 mm
IFC.REVIGRÉS-Dados do fabricante-Floor Covering - Type: Floor: REVIGRÉS-URBAN-BASE-29,5X59,2-RECT-ANTRACITE
IFC.REVIGRÉS-Dados de desempenho-Floor Covering - Type: Floor: REVIGRÉS-URBAN-BASE-29,5X59,2-RECT-ANTRACITE
IFC.REVIGRÉS-Dados de especificação-Floor Covering - Type: Floor: REVIGRÉS-URBAN-BASE-29,5X59,2-RECT-ANTRACITE
IFC.REVIGRÉS-Dados geométricos-Floor Covering - Type: Floor: REVIGRÉS-URBAN-BASE-29,5X59,2-RECT-ANTRACITE
IFC.REVIGRÉS-Dados de sustentabilidade-Floor Covering - Type: Floor: REVIGRÉS-URBAN-BASE-29,5X59,2-RECT-ANTRACITE

# IfcCovering: Floor:REVIGRÉS-URBAN-BASE-29,5X59,2-RECT-BONE, Floor:REVIGRÉS-URBAN-BASE-29,5X59,2-RECT-BONE:22490
In: Level 1
Type - PredefinedType: CLADDING; Material: REVIGRÉS-URBAN-BASE-30X60-RECT-BONE 8.5 mm
Type - Pset_CoveringCommon - Reference: 31212120T1; Material: Grés porcelânico
Type - Pset_ElementShading - Roughness: 304.8 mm
Type - Pset_ManufacturerTypeInformation - Manufacturer: REVIGRÉS
Type - Pset_ProductRequirements - Category: Floors
Type - Pset_QuantityTakeOff - Reference: 31212120T1
Type - IFC.REVIGRÉS-Dados do fabricante-Floor Covering - FabricanteURL: https://www.revigres.pt/; ReferenciaModelo: Urban; NumeroGlobalDeItemComercial: 31212120T1; Acabamento: RECT; Material: Grés porcelânico; IdentificadorDoOperadorEconomico: 501840856; UrlFabricanteArtigo: https://www.revigres.pt/colecoes/urban; PaisOrigem: Portugal
Type - IFC.REVIGRÉS-Dados de desempenho-Floor Covering - Rectilinearidade: ± 0.2% máx.± 0.8 mm; Ortogonalidade: ± 0.2% máx.± 1.5 mm; PlanaridadeDaSuperficie: ± 0.3% máx. ± 1.8 mm; QualidadeDaSuperficie: Cumpre; AbsorcaoDeAgua: < 0.05%; ModuloDeRuptura: > 45 N/mm²; ResistenciaAFlexao: > 2000 N; ResistenciaAAbrasaoProfunda: < 120 mm³; DilatacaoTermicaLinear: ≤ 8,0x10-6 °C-1; ResistenciaAoChoqueTermico: Resiste; DurabilidadeResistenciaAoGeloDegelo: Resiste; ResistenciaAoEscorregamentoDIN51130: R9; ResistenciaAoEscorregamentoDIN51097: A; ResistenciaAoEscorregamentoENV51097: A; ResistenciaAoEscorregamentoENV12633: Class 1; ResistenciaAoEscorregamentoANSIA1371: ≥0,42; ResistenciaAoDeslizamentoENV12633: Class 1; ResistenciaAsManchas: Class 5; ResistenciaABaixasConcentracoesDeAcidosEAlcalis: Classe LA; ResistenciaAAltasConcentracoesDeAcidosEAlcalis: Classe HA; LibertacaoDeCadmio: 0; LibertacaoDeChumbo: 0
Type - IFC.REVIGRÉS-Dados de especificação-Floor Covering - VariacaoTonalidade: 2; NivelDeTrafego: 5; EPavimento: Sim; ERevestimento: Sim; EExterno: Sim
Type - IFC.REVIGRÉS-Dados geométricos-Floor Covering - AlturaNominal: 8.5 mm; ComprimentoNominal: 29.5 mm; LarguraNominal: 59.2 mm
Type - IFC.REVIGRÉS-Dados de sustentabilidade-Floor Covering - EnergiaTermicaExportada: 0; ItemENovo: Sim; ItemEParcialmenteReciclado: 0.03; ItemEReciclado: Sim; VidaÚtilEsperada: 50; SubstanciasPerigosas: Não; PotencialDeEsgotamentoAbioticoDosRecursosFosseis: 203; PotencialDeEsgotamentoAbioticoDosRecursosNaoFosseisMineraisEMetais: 0.000701; PotencialDeAquecimentoGlobalBiogenico: -0.48; CombustiveisFosseisComPotencialDeAquecimentoGlobal: 13.9; PotencialDeAquecimentoGlobalUsoDoSoloEMudancaDeUsoDoSolo: 0.0246; PotencialDeEutrofizacaoFraccaoDeNutrientesQueAtingemOCompartimentoFinalDeAguaDoce: 0.000189; PotencialDeEutrofizacaoFraccaoDeNutrientesQueAtingemOCompartimentoFinalMarinho: 0.0122; EnergiaRecuperada: 0.00739; ConsumoDeAguaDoce: 0.113; UtilizacaoLiquidaDeAguaDoce: 0.113; ResiduosPerigososEliminados: 0.00221; ResiduosNaoPerigososEliminados: 1.83; MassaTotalDeResiduosRadioactivosEliminados: 0.000394; EnergiaElectricaExportada: 1.55; MateriaisParaRecuperacaoDeEnergia: 0.00739; MateriaisParaReciclagem: 0.0253; UnidadeEPD: 1 m²
Type - IFC.REVIGRÉS-Dados gerais-Floor Covering - Nome: REVIGRÉS-URBAN-BASE-29.5X59.2-RECT-URBAN BONE; TipoProduto: Prensado a seco: grupo BIa UGL | Grés porcelânico técnico; NumeroDeRegistoDAP: EPD-REV-20240006-CCC1-EN; ReferenciaDAP: -; UrlDOP: -
Classification: C3020 (Uniformat)
Pset_CoveringCommon - TotalThickness: 8.5 mm
IFC.REVIGRÉS-Dados do fabricante-Floor Covering - Type: Floor: REVIGRÉS-URBAN-BASE-29,5X59,2-RECT-BONE
IFC.REVIGRÉS-Dados de desempenho-Floor Covering - Type: Floor: REVIGRÉS-URBAN-BASE-29,5X59,2-RECT-BONE
IFC.REVIGRÉS-Dados de especificação-Floor Covering - Type: Floor: REVIGRÉS-URBAN-BASE-29,5X59,2-RECT-BONE
IFC.REVIGRÉS-Dados geométricos-Floor Covering - Type: Floor: REVIGRÉS-URBAN-BASE-29,5X59,2-RECT-BONE
IFC.REVIGRÉS-Dados de sustentabilidade-Floor Covering - Type: Floor: REVIGRÉS-URBAN-BASE-29,5X59,2-RECT-BONE

# IfcCovering: Floor:REVIGRÉS-URBAN-BASE-29,5X59,2-RECT-CRAFT, Floor:REVIGRÉS-URBAN-BASE-29,5X59,2-RECT-CRAFT:22506
In: Level 1
Type - PredefinedType: CLADDING; Material: REVIGRÉS-URBAN-BASE-30X60-RECT-CRAFT 8.5 mm
Type - Pset_CoveringCommon - Reference: 31212124T1; Material: Grés porcelânico
Type - Pset_ElementShading - Roughness: 304.8 mm
Type - Pset_ManufacturerTypeInformation - Manufacturer: REVIGRÉS
Type - Pset_ProductRequirements - Category: Floors
Type - Pset_QuantityTakeOff - Reference: 31212124T1
Type - IFC.REVIGRÉS-Dados do fabricante-Floor Covering - FabricanteURL: https://www.revigres.pt/; ReferenciaModelo: Urban; NumeroGlobalDeItemComercial: 31212124T1; Acabamento: RECT; Material: Grés porcelânico; IdentificadorDoOperadorEconomico: 501840856; UrlFabricanteArtigo: https://www.revigres.pt/colecoes/urban; PaisOrigem: Portugal
Type - IFC.REVIGRÉS-Dados de desempenho-Floor Covering - Rectilinearidade: ± 0.2% máx.± 0.8 mm; Ortogonalidade: ± 0.2% máx.± 1.5 mm; PlanaridadeDaSuperficie: ± 0.3% máx. ± 1.8 mm; QualidadeDaSuperficie: Cumpre; AbsorcaoDeAgua: < 0.05%; ModuloDeRuptura: > 45 N/mm²; ResistenciaAFlexao: > 2000 N; ResistenciaAAbrasaoProfunda: < 120 mm³; DilatacaoTermicaLinear: ≤ 8,0x10-6 °C-1; ResistenciaAoChoqueTermico: Resiste; DurabilidadeResistenciaAoGeloDegelo: Resiste; ResistenciaAoEscorregamentoDIN51130: R9; ResistenciaAoEscorregamentoDIN51097: A; ResistenciaAoEscorregamentoENV51097: A; ResistenciaAoEscorregamentoENV12633: Class 1; ResistenciaAoEscorregamentoANSIA1371: ≥0,42; ResistenciaAoDeslizamentoENV12633: Class 1; ResistenciaAsManchas: Class 5; ResistenciaABaixasConcentracoesDeAcidosEAlcalis: Classe LA; ResistenciaAAltasConcentracoesDeAcidosEAlcalis: Classe HA; LibertacaoDeCadmio: 0; LibertacaoDeChumbo: 0
Type - IFC.REVIGRÉS-Dados de especificação-Floor Covering - VariacaoTonalidade: 2; NivelDeTrafego: 5; EPavimento: Sim; ERevestimento: Sim; EExterno: Sim
Type - IFC.REVIGRÉS-Dados geométricos-Floor Covering - AlturaNominal: 8.5 mm; ComprimentoNominal: 29.5 mm; LarguraNominal: 59.2 mm
Type - IFC.REVIGRÉS-Dados de sustentabilidade-Floor Covering - EnergiaTermicaExportada: 0; ItemENovo: Sim; ItemEParcialmenteReciclado: 0.19; ItemEReciclado: Sim; VidaÚtilEsperada: 50; SubstanciasPerigosas: Não; PotencialDeEsgotamentoAbioticoDosRecursosFosseis: 203; PotencialDeEsgotamentoAbioticoDosRecursosNaoFosseisMineraisEMetais: 0.000701; PotencialDeAquecimentoGlobalBiogenico: -0.48; CombustiveisFosseisComPotencialDeAquecimentoGlobal: 13.9; PotencialDeAquecimentoGlobalUsoDoSoloEMudancaDeUsoDoSolo: 0.0246; PotencialDeEutrofizacaoFraccaoDeNutrientesQueAtingemOCompartimentoFinalDeAguaDoce: 0.000189; PotencialDeEutrofizacaoFraccaoDeNutrientesQueAtingemOCompartimentoFinalMarinho: 0.0122; EnergiaRecuperada: 0.00739; ConsumoDeAguaDoce: 0.113; UtilizacaoLiquidaDeAguaDoce: 0.113; ResiduosPerigososEliminados: 0.00221; ResiduosNaoPerigososEliminados: 1.83; MassaTotalDeResiduosRadioactivosEliminados: 0.000394; EnergiaElectricaExportada: 1.55; MateriaisParaRecuperacaoDeEnergia: 0.00739; MateriaisParaReciclagem: 0.0253; UnidadeEPD: 1 m²
Type - IFC.REVIGRÉS-Dados gerais-Floor Covering - Nome: REVIGRÉS-URBAN-BASE-29.5X59.2-RECT-URBAN CRAFT; TipoProduto: Prensado a seco: grupo BIa UGL | Grés porcelânico técnico; NumeroDeRegistoDAP: EPD-REV-20240006-CCC1-EN; ReferenciaDAP: -; UrlDOP: -
Classification: C3020 (Uniformat)
Pset_CoveringCommon - TotalThickness: 8.5 mm
IFC.REVIGRÉS-Dados do fabricante-Floor Covering - Type: Floor: REVIGRÉS-URBAN-BASE-29,5X59,2-RECT-CRAFT
IFC.REVIGRÉS-Dados de desempenho-Floor Covering - Type: Floor: REVIGRÉS-URBAN-BASE-29,5X59,2-RECT-CRAFT
IFC.REVIGRÉS-Dados de especificação-Floor Covering - Type: Floor: REVIGRÉS-URBAN-BASE-29,5X59,2-RECT-CRAFT
IFC.REVIGRÉS-Dados geométricos-Floor Covering - Type: Floor: REVIGRÉS-URBAN-BASE-29,5X59,2-RECT-CRAFT
IFC.REVIGRÉS-Dados de sustentabilidade-Floor Covering - Type: Floor: REVIGRÉS-URBAN-BASE-29,5X59,2-RECT-CRAFT

# IfcCovering: Floor:REVIGRÉS-URBAN-BASE-29,5X59,2-RECT-FOG, Floor:REVIGRÉS-URBAN-BASE-29,5X59,2-RECT-FOG:22522
In: Level 1
Type - PredefinedType: CLADDING; Material: REVIGRÉS-URBAN-BASE-30X60-RECT-FOG 8.5 mm
Type - Pset_CoveringCommon - Reference: 31212121T1; Material: Grés porcelânico
Type - Pset_ElementShading - Roughness: 304.8 mm
Type - Pset_ManufacturerTypeInformation - Manufacturer: REVIGRÉS
Type - Pset_ProductRequirements - Category: Floors
Type - Pset_QuantityTakeOff - Reference: 31212121T1
Type - IFC.REVIGRÉS-Dados do fabricante-Floor Covering - FabricanteURL: https://www.revigres.pt/; ReferenciaModelo: Urban; NumeroGlobalDeItemComercial: 31212121T1; Acabamento: RECT; Material: Grés porcelânico; IdentificadorDoOperadorEconomico: 501840856; UrlFabricanteArtigo: https://www.revigres.pt/colecoes/urban; PaisOrigem: Portugal
Type - IFC.REVIGRÉS-Dados de desempenho-Floor Covering - Rectilinearidade: ± 0.2% máx.± 0.8 mm; Ortogonalidade: ± 0.2% máx.± 1.5 mm; PlanaridadeDaSuperficie: ± 0.3% máx. ± 1.8 mm; QualidadeDaSuperficie: Cumpre; AbsorcaoDeAgua: < 0.05%; ModuloDeRuptura: > 45 N/mm²; ResistenciaAFlexao: > 2000 N; ResistenciaAAbrasaoProfunda: < 120 mm³; DilatacaoTermicaLinear: ≤ 8,0x10-6 °C-1; ResistenciaAoChoqueTermico: Resiste; DurabilidadeResistenciaAoGeloDegelo: Resiste; ResistenciaAoEscorregamentoDIN51130: R9; ResistenciaAoEscorregamentoDIN51097: A; ResistenciaAoEscorregamentoENV51097: A; ResistenciaAoEscorregamentoENV12633: Class 1; ResistenciaAoEscorregamentoANSIA1371: ≥0,42; ResistenciaAoDeslizamentoENV12633: Class 1; ResistenciaAsManchas: Class 5; ResistenciaABaixasConcentracoesDeAcidosEAlcalis: Classe LA; ResistenciaAAltasConcentracoesDeAcidosEAlcalis: Classe HA; LibertacaoDeCadmio: 0; LibertacaoDeChumbo: 0
Type - IFC.REVIGRÉS-Dados de especificação-Floor Covering - VariacaoTonalidade: 2; NivelDeTrafego: 5; EPavimento: Sim; ERevestimento: Sim; EExterno: Sim
Type - IFC.REVIGRÉS-Dados geométricos-Floor Covering - AlturaNominal: 8.5 mm; ComprimentoNominal: 29.5 mm; LarguraNominal: 59.2 mm
Type - IFC.REVIGRÉS-Dados de sustentabilidade-Floor Covering - EnergiaTermicaExportada: 0; ItemENovo: Sim; ItemEParcialmenteReciclado: 0.23; ItemEReciclado: Sim; VidaÚtilEsperada: 50; SubstanciasPerigosas: Não; PotencialDeEsgotamentoAbioticoDosRecursosFosseis: 203; PotencialDeEsgotamentoAbioticoDosRecursosNaoFosseisMineraisEMetais: 0.000701; PotencialDeAquecimentoGlobalBiogenico: -0.48; CombustiveisFosseisComPotencialDeAquecimentoGlobal: 13.9; PotencialDeAquecimentoGlobalUsoDoSoloEMudancaDeUsoDoSolo: 0.0246; PotencialDeEutrofizacaoFraccaoDeNutrientesQueAtingemOCompartimentoFinalDeAguaDoce: 0.000189; PotencialDeEutrofizacaoFraccaoDeNutrientesQueAtingemOCompartimentoFinalMarinho: 0.0122; EnergiaRecuperada: 0.00739; ConsumoDeAguaDoce: 0.113; UtilizacaoLiquidaDeAguaDoce: 0.113; ResiduosPerigososEliminados: 0.00221; ResiduosNaoPerigososEliminados: 1.83; MassaTotalDeResiduosRadioactivosEliminados: 0.000394; EnergiaElectricaExportada: 1.55; MateriaisParaRecuperacaoDeEnergia: 0.00739; MateriaisParaReciclagem: 0.0253; UnidadeEPD: 1 m²
Type - IFC.REVIGRÉS-Dados gerais-Floor Covering - Nome: REVIGRÉS-URBAN-BASE-29.5X59.2-RECT-URBAN FOG; TipoProduto: Prensado a seco: grupo BIa UGL | Grés porcelânico técnico; NumeroDeRegistoDAP: EPD-REV-20240006-CCC1-EN; ReferenciaDAP: -; UrlDOP: -
Classification: C3020 (Uniformat)
Pset_CoveringCommon - TotalThickness: 8.5 mm
IFC.REVIGRÉS-Dados do fabricante-Floor Covering - Type: Floor: REVIGRÉS-URBAN-BASE-29,5X59,2-RECT-FOG
IFC.REVIGRÉS-Dados de desempenho-Floor Covering - Type: Floor: REVIGRÉS-URBAN-BASE-29,5X59,2-RECT-FOG
IFC.REVIGRÉS-Dados de especificação-Floor Covering - Type: Floor: REVIGRÉS-URBAN-BASE-29,5X59,2-RECT-FOG
IFC.REVIGRÉS-Dados geométricos-Floor Covering - Type: Floor: REVIGRÉS-URBAN-BASE-29,5X59,2-RECT-FOG
IFC.REVIGRÉS-Dados de sustentabilidade-Floor Covering - Type: Floor: REVIGRÉS-URBAN-BASE-29,5X59,2-RECT-FOG

# IfcCovering: Floor:REVIGRÉS-URBAN-BASE-29,5X59,2-RECT-GRIS, Floor:REVIGRÉS-URBAN-BASE-29,5X59,2-RECT-GRIS:22538
In: Level 1
Type - PredefinedType: CLADDING; Material: REVIGRÉS-URBAN-BASE-30X60-RECT-GRIS 8.5 mm
Type - Pset_CoveringCommon - Reference: 31212122T1; Material: Grés porcelânico
Type - Pset_ElementShading - Roughness: 304.8 mm
Type - Pset_ManufacturerTypeInformation - Manufacturer: REVIGRÉS
Type - Pset_ProductRequirements - Category: Floors
Type - Pset_QuantityTakeOff - Reference: 31212122T1
Type - IFC.REVIGRÉS-Dados do fabricante-Floor Covering - FabricanteURL: https://www.revigres.pt/; ReferenciaModelo: Urban; NumeroGlobalDeItemComercial: 31212122T1; Acabamento: RECT; Material: Grés porcelânico; IdentificadorDoOperadorEconomico: 501840856; UrlFabricanteArtigo: https://www.revigres.pt/colecoes/urban; PaisOrigem: Portugal
Type - IFC.REVIGRÉS-Dados de desempenho-Floor Covering - Rectilinearidade: ± 0.2% máx.± 0.8 mm; Ortogonalidade: ± 0.2% máx.± 1.5 mm; PlanaridadeDaSuperficie: ± 0.3% máx. ± 1.8 mm; QualidadeDaSuperficie: Cumpre; AbsorcaoDeAgua: < 0.05%; ModuloDeRuptura: > 45 N/mm²; ResistenciaAFlexao: > 2000 N; ResistenciaAAbrasaoProfunda: < 120 mm³; DilatacaoTermicaLinear: ≤ 8,0x10-6 °C-1; ResistenciaAoChoqueTermico: Resiste; DurabilidadeResistenciaAoGeloDegelo: Resiste; ResistenciaAoEscorregamentoDIN51130: R9; ResistenciaAoEscorregamentoDIN51097: A; ResistenciaAoEscorregamentoENV51097: A; ResistenciaAoEscorregamentoENV12633: Class 1; ResistenciaAoEscorregamentoANSIA1371: ≥0,42; ResistenciaAoDeslizamentoENV12633: Class 1; ResistenciaAsManchas: Class 5; ResistenciaABaixasConcentracoesDeAcidosEAlcalis: Classe LA; ResistenciaAAltasConcentracoesDeAcidosEAlcalis: Classe HA; LibertacaoDeCadmio: 0; LibertacaoDeChumbo: 0
Type - IFC.REVIGRÉS-Dados de especificação-Floor Covering - VariacaoTonalidade: 2; NivelDeTrafego: 5; EPavimento: Sim; ERevestimento: Sim; EExterno: Sim
Type - IFC.REVIGRÉS-Dados geométricos-Floor Covering - AlturaNominal: 8.5 mm; ComprimentoNominal: 29.5 mm; LarguraNominal: 59.2 mm
Type - IFC.REVIGRÉS-Dados de sustentabilidade-Floor Covering - EnergiaTermicaExportada: 0; ItemENovo: Sim; ItemEParcialmenteReciclado: 0.23; ItemEReciclado: Sim; VidaÚtilEsperada: 50; SubstanciasPerigosas: Não; PotencialDeEsgotamentoAbioticoDosRecursosFosseis: 203; PotencialDeEsgotamentoAbioticoDosRecursosNaoFosseisMineraisEMetais: 0.000701; PotencialDeAquecimentoGlobalBiogenico: -0.48; CombustiveisFosseisComPotencialDeAquecimentoGlobal: 13.9; PotencialDeAquecimentoGlobalUsoDoSoloEMudancaDeUsoDoSolo: 0.0246; PotencialDeEutrofizacaoFraccaoDeNutrientesQueAtingemOCompartimentoFinalDeAguaDoce: 0.000189; PotencialDeEutrofizacaoFraccaoDeNutrientesQueAtingemOCompartimentoFinalMarinho: 0.0122; EnergiaRecuperada: 0.00739; ConsumoDeAguaDoce: 0.113; UtilizacaoLiquidaDeAguaDoce: 0.113; ResiduosPerigososEliminados: 0.00221; ResiduosNaoPerigososEliminados: 1.83; MassaTotalDeResiduosRadioactivosEliminados: 0.000394; EnergiaElectricaExportada: 1.55; MateriaisParaRecuperacaoDeEnergia: 0.00739; MateriaisParaReciclagem: 0.0253; UnidadeEPD: 1 m²
Type - IFC.REVIGRÉS-Dados gerais-Floor Covering - Nome: REVIGRÉS-URBAN-BASE-29.5X59.2-RECT-URBAN GRIS; TipoProduto: Prensado a seco: grupo BIa UGL | Grés porcelânico técnico; NumeroDeRegistoDAP: EPD-REV-20240006-CCC1-EN; ReferenciaDAP: -; UrlDOP: -
Classification: C3020 (Uniformat)
Pset_CoveringCommon - TotalThickness: 8.5 mm
IFC.REVIGRÉS-Dados do fabricante-Floor Covering - Type: Floor: REVIGRÉS-URBAN-BASE-29,5X59,2-RECT-GRIS
IFC.REVIGRÉS-Dados de desempenho-Floor Covering - Type: Floor: REVIGRÉS-URBAN-BASE-29,5X59,2-RECT-GRIS
IFC.REVIGRÉS-Dados de especificação-Floor Covering - Type: Floor: REVIGRÉS-URBAN-BASE-29,5X59,2-RECT-GRIS
IFC.REVIGRÉS-Dados geométricos-Floor Covering - Type: Floor: REVIGRÉS-URBAN-BASE-29,5X59,2-RECT-GRIS
IFC.REVIGRÉS-Dados de sustentabilidade-Floor Covering - Type: Floor: REVIGRÉS-URBAN-BASE-29,5X59,2-RECT-GRIS

# IfcCovering: Floor:REVIGRÉS-URBAN-BASE-29,5X59,2-RECT-OFFWHITE, Floor:REVIGRÉS-URBAN-BASE-29,5X59,2-RECT-OFFWHITE:22554
In: Level 1
Type - PredefinedType: CLADDING; Material: REVIGRÉS-URBAN-BASE-30X60-RECT-OFFWHITE 8.5 mm
Type - Pset_CoveringCommon - Reference: 31212123T1; Material: Grés porcelânico
Type - Pset_ElementShading - Roughness: 304.8 mm
Type - Pset_ManufacturerTypeInformation - Manufacturer: REVIGRÉS
Type - Pset_ProductRequirements - Category: Floors
Type - Pset_QuantityTakeOff - Reference: 31212123T1
Type - IFC.REVIGRÉS-Dados do fabricante-Floor Covering - FabricanteURL: https://www.revigres.pt/; ReferenciaModelo: Urban; NumeroGlobalDeItemComercial: 31212123T1; Acabamento: RECT; Material: Grés porcelânico; IdentificadorDoOperadorEconomico: 501840856; UrlFabricanteArtigo: https://www.revigres.pt/colecoes/urban; PaisOrigem: Portugal
Type - IFC.REVIGRÉS-Dados de desempenho-Floor Covering - Rectilinearidade: ± 0.2% máx.± 0.8 mm; Ortogonalidade: ± 0.2% máx.± 1.5 mm; PlanaridadeDaSuperficie: ± 0.3% máx. ± 1.8 mm; QualidadeDaSuperficie: Cumpre; AbsorcaoDeAgua: < 0.05%; ModuloDeRuptura: > 45 N/mm²; ResistenciaAFlexao: > 2000 N; ResistenciaAAbrasaoProfunda: < 120 mm³; DilatacaoTermicaLinear: ≤ 8,0x10-6 °C-1; ResistenciaAoChoqueTermico: Resiste; DurabilidadeResistenciaAoGeloDegelo: Resiste; ResistenciaAoEscorregamentoDIN51130: R9; ResistenciaAoEscorregamentoDIN51097: A; ResistenciaAoEscorregamentoENV51097: A; ResistenciaAoEscorregamentoENV12633: Class 1; ResistenciaAoEscorregamentoANSIA1371: ≥0,42; ResistenciaAoDeslizamentoENV12633: Class 1; ResistenciaAsManchas: Class 5; ResistenciaABaixasConcentracoesDeAcidosEAlcalis: Classe LA; ResistenciaAAltasConcentracoesDeAcidosEAlcalis: Classe HA; LibertacaoDeCadmio: 0; LibertacaoDeChumbo: 0
Type - IFC.REVIGRÉS-Dados de especificação-Floor Covering - VariacaoTonalidade: 2; NivelDeTrafego: 5; EPavimento: Sim; ERevestimento: Sim; EExterno: Sim
Type - IFC.REVIGRÉS-Dados geométricos-Floor Covering - AlturaNominal: 8.5 mm; ComprimentoNominal: 29.5 mm; LarguraNominal: 59.2 mm
Type - IFC.REVIGRÉS-Dados de sustentabilidade-Floor Covering - EnergiaTermicaExportada: 0; ItemENovo: Sim; ItemEParcialmenteReciclado: 0.03; ItemEReciclado: Sim; VidaÚtilEsperada: 50; SubstanciasPerigosas: Não; PotencialDeEsgotamentoAbioticoDosRecursosFosseis: 203; PotencialDeEsgotamentoAbioticoDosRecursosNaoFosseisMineraisEMetais: 0.000701; PotencialDeAquecimentoGlobalBiogenico: -0.48; CombustiveisFosseisComPotencialDeAquecimentoGlobal: 13.9; PotencialDeAquecimentoGlobalUsoDoSoloEMudancaDeUsoDoSolo: 0.0246; PotencialDeEutrofizacaoFraccaoDeNutrientesQueAtingemOCompartimentoFinalDeAguaDoce: 0.000189; PotencialDeEutrofizacaoFraccaoDeNutrientesQueAtingemOCompartimentoFinalMarinho: 0.0122; EnergiaRecuperada: 0.00739; ConsumoDeAguaDoce: 0.113; UtilizacaoLiquidaDeAguaDoce: 0.113; ResiduosPerigososEliminados: 0.00221; ResiduosNaoPerigososEliminados: 1.83; MassaTotalDeResiduosRadioactivosEliminados: 0.000394; EnergiaElectricaExportada: 1.55; MateriaisParaRecuperacaoDeEnergia: 0.00739; MateriaisParaReciclagem: 0.0253; UnidadeEPD: 1 m²
Type - IFC.REVIGRÉS-Dados gerais-Floor Covering - Nome: REVIGRÉS-URBAN-BASE-29.5X59.2-RECT-URBAN OFFWHITE; TipoProduto: Prensado a seco: grupo BIa UGL | Grés porcelânico técnico; NumeroDeRegistoDAP: EPD-REV-20240006-CCC1-EN; ReferenciaDAP: -; UrlDOP: -
Classification: C3020 (Uniformat)
Pset_CoveringCommon - TotalThickness: 8.5 mm
IFC.REVIGRÉS-Dados do fabricante-Floor Covering - Type: Floor: REVIGRÉS-URBAN-BASE-29,5X59,2-RECT-OFFWHITE
IFC.REVIGRÉS-Dados de desempenho-Floor Covering - Type: Floor: REVIGRÉS-URBAN-BASE-29,5X59,2-RECT-OFFWHITE
IFC.REVIGRÉS-Dados de especificação-Floor Covering - Type: Floor: REVIGRÉS-URBAN-BASE-29,5X59,2-RECT-OFFWHITE
IFC.REVIGRÉS-Dados geométricos-Floor Covering - Type: Floor: REVIGRÉS-URBAN-BASE-29,5X59,2-RECT-OFFWHITE
IFC.REVIGRÉS-Dados de sustentabilidade-Floor Covering - Type: Floor: REVIGRÉS-URBAN-BASE-29,5X59,2-RECT-OFFWHITE

# IfcCovering: Floor:REVIGRÉS-URBAN-BASE-30X30-NAT-ANTRACITE, Floor:REVIGRÉS-URBAN-BASE-30X30-NAT-ANTRACITE:21477
In: Level 1
Type - PredefinedType: CLADDING; Material: REVIGRÉS-URBAN-BASE-30X30-NAT-ANTRACITE 8.5 mm
Type - Pset_CoveringCommon - Reference: 31201248U1; Material: Grés porcelânico
Type - Pset_ElementShading - Roughness: 304.8 mm
Type - Pset_ManufacturerTypeInformation - Manufacturer: REVIGRÉS
Type - Pset_ProductRequirements - Category: Floors
Type - Pset_QuantityTakeOff - Reference: 31201248U1
Type - IFC.REVIGRÉS-Dados do fabricante-Floor Covering - FabricanteURL: https://www.revigres.pt/; ReferenciaModelo: Urban; NumeroGlobalDeItemComercial: 31201248U1; Acabamento: NAT; Material: Grés porcelânico; IdentificadorDoOperadorEconomico: 501840856; UrlFabricanteArtigo: https://www.revigres.pt/colecoes/urban; PaisOrigem: Portugal
Type - IFC.REVIGRÉS-Dados de desempenho-Floor Covering - Rectilinearidade: ± 0.3% máx. ± 1.5 mm; Ortogonalidade: ± 0.3% máx. ± 1.8 mm; PlanaridadeDaSuperficie: ± 0.3% máx. ± 1.8 mm; QualidadeDaSuperficie: Cumpre; AbsorcaoDeAgua: < 0.05%; ModuloDeRuptura: > 45 N/mm²; ResistenciaAFlexao: > 2000 N; ResistenciaAAbrasaoProfunda: < 120 mm³; DilatacaoTermicaLinear: ≤ 8,0x10-6 °C-1; ResistenciaAoChoqueTermico: Resiste; DurabilidadeResistenciaAoGeloDegelo: Resiste; ResistenciaAoEscorregamentoDIN51130: R9; ResistenciaAoEscorregamentoDIN51097: A; ResistenciaAoEscorregamentoENV51097: A; ResistenciaAoEscorregamentoENV12633: Class 1; ResistenciaAoEscorregamentoANSIA1371: ≥0,42; ResistenciaAoDeslizamentoENV12633: Class 1; ResistenciaAsManchas: Class 5; ResistenciaABaixasConcentracoesDeAcidosEAlcalis: Classe LA; ResistenciaAAltasConcentracoesDeAcidosEAlcalis: Classe HA; LibertacaoDeCadmio: 0; LibertacaoDeChumbo: 0
Type - IFC.REVIGRÉS-Dados de especificação-Floor Covering - VariacaoTonalidade: 2; NivelDeTrafego: 5; EPavimento: Sim; ERevestimento: Sim; EExterno: Sim
Type - IFC.REVIGRÉS-Dados geométricos-Floor Covering - AlturaNominal: 8.5 mm; ComprimentoNominal: 30 mm; LarguraNominal: 30 mm
Type - IFC.REVIGRÉS-Dados de sustentabilidade-Floor Covering - EnergiaTermicaExportada: 0; ItemENovo: Sim; ItemEParcialmenteReciclado: 0.29; ItemEReciclado: Sim; VidaÚtilEsperada: 50; SubstanciasPerigosas: Não; PotencialDeEsgotamentoAbioticoDosRecursosFosseis: 203; PotencialDeEsgotamentoAbioticoDosRecursosNaoFosseisMineraisEMetais: 0.000701; PotencialDeAquecimentoGlobalBiogenico: -0.48; CombustiveisFosseisComPotencialDeAquecimentoGlobal: 13.9; PotencialDeAquecimentoGlobalUsoDoSoloEMudancaDeUsoDoSolo: 0.0246; PotencialDeEutrofizacaoFraccaoDeNutrientesQueAtingemOCompartimentoFinalDeAguaDoce: 0.000189; PotencialDeEutrofizacaoFraccaoDeNutrientesQueAtingemOCompartimentoFinalMarinho: 0.0122; EnergiaRecuperada: 0.00739; ConsumoDeAguaDoce: 0.113; UtilizacaoLiquidaDeAguaDoce: 0.113; ResiduosPerigososEliminados: 0.00221; ResiduosNaoPerigososEliminados: 1.83; MassaTotalDeResiduosRadioactivosEliminados: 0.000394; EnergiaElectricaExportada: 1.55; MateriaisParaRecuperacaoDeEnergia: 0.00739; MateriaisParaReciclagem: 0.0253; UnidadeEPD: 1 m²
Type - IFC.REVIGRÉS-Dados gerais-Floor Covering - Nome: REVIGRÉS-URBAN-BASE-30X30-NAT-URBAN ANTRACITE; TipoProduto: Prensado a seco: grupo BIa UGL | Grés porcelânico técnico; NumeroDeRegistoDAP: EPD-REV-20240006-CCC1-EN; ReferenciaDAP: -; UrlDOP: -
Classification: C3020 (Uniformat)
Pset_CoveringCommon - TotalThickness: 8.5 mm
IFC.REVIGRÉS-Dados do fabricante-Floor Covering - Type: Floor: REVIGRÉS-URBAN-BASE-30X30-NAT-ANTRACITE
IFC.REVIGRÉS-Dados de desempenho-Floor Covering - Type: Floor: REVIGRÉS-URBAN-BASE-30X30-NAT-ANTRACITE
IFC.REVIGRÉS-Dados de especificação-Floor Covering - Type: Floor: REVIGRÉS-URBAN-BASE-30X30-NAT-ANTRACITE
IFC.REVIGRÉS-Dados geométricos-Floor Covering - Type: Floor: REVIGRÉS-URBAN-BASE-30X30-NAT-ANTRACITE
IFC.REVIGRÉS-Dados de sustentabilidade-Floor Covering - Type: Floor: REVIGRÉS-URBAN-BASE-30X30-NAT-ANTRACITE

# IfcCovering: Floor:REVIGRÉS-URBAN-BASE-30X30-NAT-BONE, Floor:REVIGRÉS-URBAN-BASE-30X30-NAT-BONE:21519
In: Level 1
Type - PredefinedType: CLADDING; Material: REVIGRÉS-URBAN-BASE-30X30-NAT-BONE 8.5 mm
Type - Pset_CoveringCommon - Reference: 31201220T1; Material: Grés porcelânico
Type - Pset_ElementShading - Roughness: 304.8 mm
Type - Pset_ManufacturerTypeInformation - Manufacturer: REVIGRÉS
Type - Pset_ProductRequirements - Category: Floors
Type - Pset_QuantityTakeOff - Reference: 31201220T1
Type - IFC.REVIGRÉS-Dados do fabricante-Floor Covering - FabricanteURL: https://www.revigres.pt/; ReferenciaModelo: Urban; NumeroGlobalDeItemComercial: 31201220T1; Acabamento: NAT; Material: Grés porcelânico; IdentificadorDoOperadorEconomico: 501840856; UrlFabricanteArtigo: https://www.revigres.pt/colecoes/urban; PaisOrigem: Portugal
Type - IFC.REVIGRÉS-Dados de desempenho-Floor Covering - Rectilinearidade: ± 0.3% máx. ± 1.5 mm; Ortogonalidade: ± 0.3% máx. ± 1.8 mm; PlanaridadeDaSuperficie: ± 0.3% máx. ± 1.8 mm; QualidadeDaSuperficie: Cumpre; AbsorcaoDeAgua: < 0.05%; ModuloDeRuptura: > 45 N/mm²; ResistenciaAFlexao: > 2000 N; ResistenciaAAbrasaoProfunda: < 120 mm³; DilatacaoTermicaLinear: ≤ 8,0x10-6 °C-1; ResistenciaAoChoqueTermico: Resiste; DurabilidadeResistenciaAoGeloDegelo: Resiste; ResistenciaAoEscorregamentoDIN51130: R9; ResistenciaAoEscorregamentoDIN51097: A; ResistenciaAoEscorregamentoENV51097: A; ResistenciaAoEscorregamentoENV12633: Class 1; ResistenciaAoEscorregamentoANSIA1371: ≥0,42; ResistenciaAoDeslizamentoENV12633: Class 1; ResistenciaAsManchas: Class 5; ResistenciaABaixasConcentracoesDeAcidosEAlcalis: Classe LA; ResistenciaAAltasConcentracoesDeAcidosEAlcalis: Classe HA; LibertacaoDeCadmio: 0; LibertacaoDeChumbo: 0
Type - IFC.REVIGRÉS-Dados de especificação-Floor Covering - VariacaoTonalidade: 2; NivelDeTrafego: 5; EPavimento: Sim; ERevestimento: Sim; EExterno: Sim
Type - IFC.REVIGRÉS-Dados geométricos-Floor Covering - AlturaNominal: 8.5 mm; ComprimentoNominal: 30 mm; LarguraNominal: 30 mm
Type - IFC.REVIGRÉS-Dados de sustentabilidade-Floor Covering - EnergiaTermicaExportada: 0; ItemENovo: Sim; ItemEParcialmenteReciclado: 0.03; ItemEReciclado: Sim; VidaÚtilEsperada: 50; SubstanciasPerigosas: Não; PotencialDeEsgotamentoAbioticoDosRecursosFosseis: 203; PotencialDeEsgotamentoAbioticoDosRecursosNaoFosseisMineraisEMetais: 0.000701; PotencialDeAquecimentoGlobalBiogenico: -0.48; CombustiveisFosseisComPotencialDeAquecimentoGlobal: 13.9; PotencialDeAquecimentoGlobalUsoDoSoloEMudancaDeUsoDoSolo: 0.0246; PotencialDeEutrofizacaoFraccaoDeNutrientesQueAtingemOCompartimentoFinalDeAguaDoce: 0.000189; PotencialDeEutrofizacaoFraccaoDeNutrientesQueAtingemOCompartimentoFinalMarinho: 0.0122; EnergiaRecuperada: 0.00739; ConsumoDeAguaDoce: 0.113; UtilizacaoLiquidaDeAguaDoce: 0.113; ResiduosPerigososEliminados: 0.00221; ResiduosNaoPerigososEliminados: 1.83; MassaTotalDeResiduosRadioactivosEliminados: 0.000394; EnergiaElectricaExportada: 1.55; MateriaisParaRecuperacaoDeEnergia: 0.00739; MateriaisParaReciclagem: 0.0253; UnidadeEPD: 1 m²
Type - IFC.REVIGRÉS-Dados gerais-Floor Covering - Nome: REVIGRÉS-URBAN-BASE-30X30-NAT-URBAN BONE; TipoProduto: Prensado a seco: grupo BIa UGL | Grés porcelânico técnico; NumeroDeRegistoDAP: EPD-REV-20240006-CCC1-EN; ReferenciaDAP: -; UrlDOP: -
Classification: C3020 (Uniformat)
Pset_CoveringCommon - TotalThickness: 8.5 mm
IFC.REVIGRÉS-Dados do fabricante-Floor Covering - Type: Floor: REVIGRÉS-URBAN-BASE-30X30-NAT-BONE
IFC.REVIGRÉS-Dados de desempenho-Floor Covering - Type: Floor: REVIGRÉS-URBAN-BASE-30X30-NAT-BONE
IFC.REVIGRÉS-Dados de especificação-Floor Covering - Type: Floor: REVIGRÉS-URBAN-BASE-30X30-NAT-BONE
IFC.REVIGRÉS-Dados geométricos-Floor Covering - Type: Floor: REVIGRÉS-URBAN-BASE-30X30-NAT-BONE
IFC.REVIGRÉS-Dados de sustentabilidade-Floor Covering - Type: Floor: REVIGRÉS-URBAN-BASE-30X30-NAT-BONE

# IfcCovering: Floor:REVIGRÉS-URBAN-BASE-30X30-NAT-CRAFT, Floor:REVIGRÉS-URBAN-BASE-30X30-NAT-CRAFT:21541
In: Level 1
Type - PredefinedType: CLADDING; Material: REVIGRÉS-URBAN-BASE-30X30-NAT-CRAFT 8.5 mm
Type - Pset_CoveringCommon - Reference: 31201224T1; Material: Grés porcelânico
Type - Pset_ElementShading - Roughness: 304.8 mm
Type - Pset_ManufacturerTypeInformation - Manufacturer: REVIGRÉS
Type - Pset_ProductRequirements - Category: Floors
Type - Pset_QuantityTakeOff - Reference: 31201224T1
Type - IFC.REVIGRÉS-Dados do fabricante-Floor Covering - FabricanteURL: https://www.revigres.pt/; ReferenciaModelo: Urban; NumeroGlobalDeItemComercial: 31201224T1; Acabamento: NAT; Material: Grés porcelânico; IdentificadorDoOperadorEconomico: 501840856; UrlFabricanteArtigo: https://www.revigres.pt/colecoes/urban; PaisOrigem: Portugal
Type - IFC.REVIGRÉS-Dados de desempenho-Floor Covering - Rectilinearidade: ± 0.3% máx. ± 1.5 mm; Ortogonalidade: ± 0.3% máx. ± 1.8 mm; PlanaridadeDaSuperficie: ± 0.3% máx. ± 1.8 mm; QualidadeDaSuperficie: Cumpre; AbsorcaoDeAgua: < 0.05%; ModuloDeRuptura: > 45 N/mm²; ResistenciaAFlexao: > 2000 N; ResistenciaAAbrasaoProfunda: < 120 mm³; DilatacaoTermicaLinear: ≤ 8,0x10-6 °C-1; ResistenciaAoChoqueTermico: Resiste; DurabilidadeResistenciaAoGeloDegelo: Resiste; ResistenciaAoEscorregamentoDIN51130: R9; ResistenciaAoEscorregamentoDIN51097: A; ResistenciaAoEscorregamentoENV51097: A; ResistenciaAoEscorregamentoENV12633: Class 1; ResistenciaAoEscorregamentoANSIA1371: ≥0,42; ResistenciaAoDeslizamentoENV12633: Class 1; ResistenciaAsManchas: Class 5; ResistenciaABaixasConcentracoesDeAcidosEAlcalis: Classe LA; ResistenciaAAltasConcentracoesDeAcidosEAlcalis: Classe HA; LibertacaoDeCadmio: 0; LibertacaoDeChumbo: 0
Type - IFC.REVIGRÉS-Dados de especificação-Floor Covering - VariacaoTonalidade: 2; NivelDeTrafego: 5; EPavimento: Sim; ERevestimento: Sim; EExterno: Sim
Type - IFC.REVIGRÉS-Dados geométricos-Floor Covering - AlturaNominal: 8.5 mm; ComprimentoNominal: 30 mm; LarguraNominal: 30 mm
Type - IFC.REVIGRÉS-Dados de sustentabilidade-Floor Covering - EnergiaTermicaExportada: 0; ItemENovo: Sim; ItemEParcialmenteReciclado: 0.19; ItemEReciclado: Sim; VidaÚtilEsperada: 50; SubstanciasPerigosas: Não; PotencialDeEsgotamentoAbioticoDosRecursosFosseis: 203; PotencialDeEsgotamentoAbioticoDosRecursosNaoFosseisMineraisEMetais: 0.000701; PotencialDeAquecimentoGlobalBiogenico: -0.48; CombustiveisFosseisComPotencialDeAquecimentoGlobal: 13.9; PotencialDeAquecimentoGlobalUsoDoSoloEMudancaDeUsoDoSolo: 0.0246; PotencialDeEutrofizacaoFraccaoDeNutrientesQueAtingemOCompartimentoFinalDeAguaDoce: 0.000189; PotencialDeEutrofizacaoFraccaoDeNutrientesQueAtingemOCompartimentoFinalMarinho: 0.0122; EnergiaRecuperada: 0.00739; ConsumoDeAguaDoce: 0.113; UtilizacaoLiquidaDeAguaDoce: 0.113; ResiduosPerigososEliminados: 0.00221; ResiduosNaoPerigososEliminados: 1.83; MassaTotalDeResiduosRadioactivosEliminados: 0.000394; EnergiaElectricaExportada: 1.55; MateriaisParaRecuperacaoDeEnergia: 0.00739; MateriaisParaReciclagem: 0.0253; UnidadeEPD: 1 m²
Type - IFC.REVIGRÉS-Dados gerais-Floor Covering - Nome: REVIGRÉS-URBAN-BASE-30X30-NAT-URBAN CRAFT; TipoProduto: Prensado a seco: grupo BIa UGL | Grés porcelânico técnico; NumeroDeRegistoDAP: EPD-REV-20240006-CCC1-EN; ReferenciaDAP: -; UrlDOP: -
Classification: C3020 (Uniformat)
Pset_CoveringCommon - TotalThickness: 8.5 mm
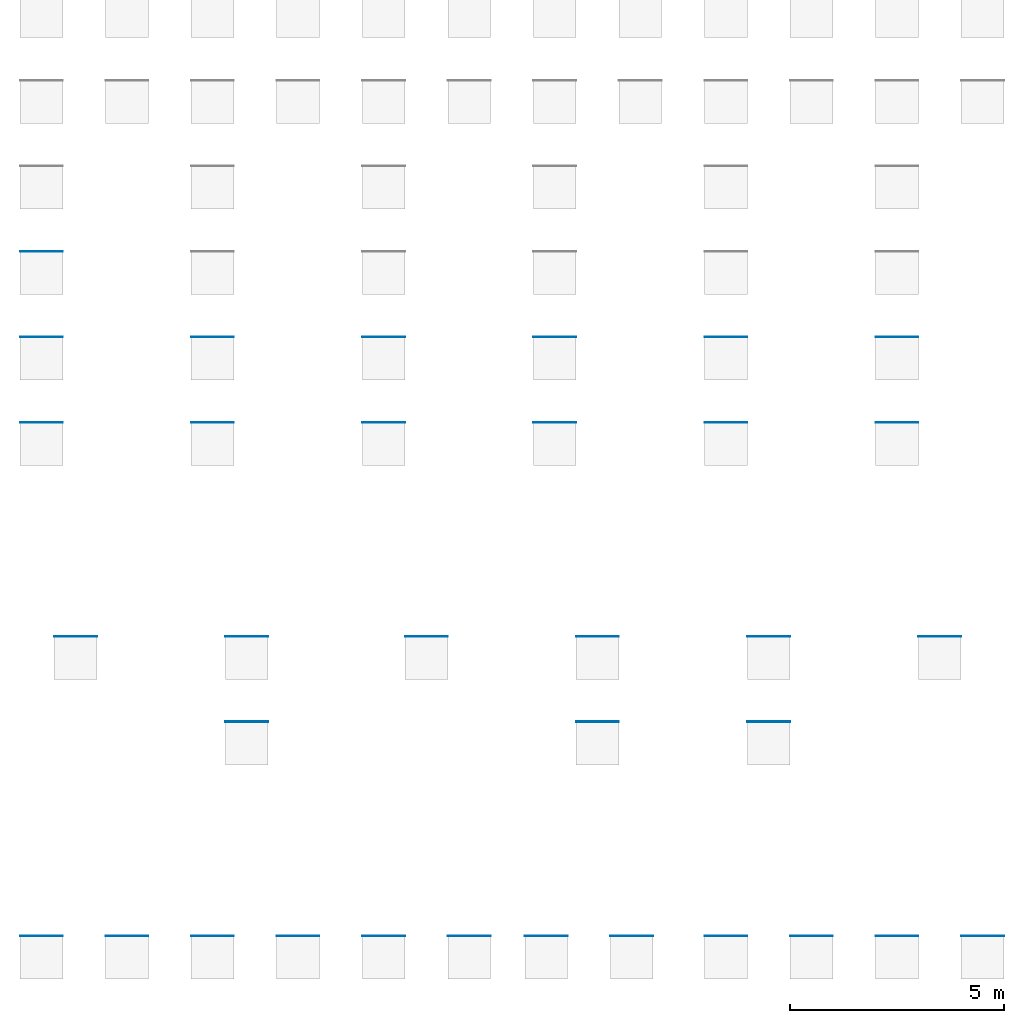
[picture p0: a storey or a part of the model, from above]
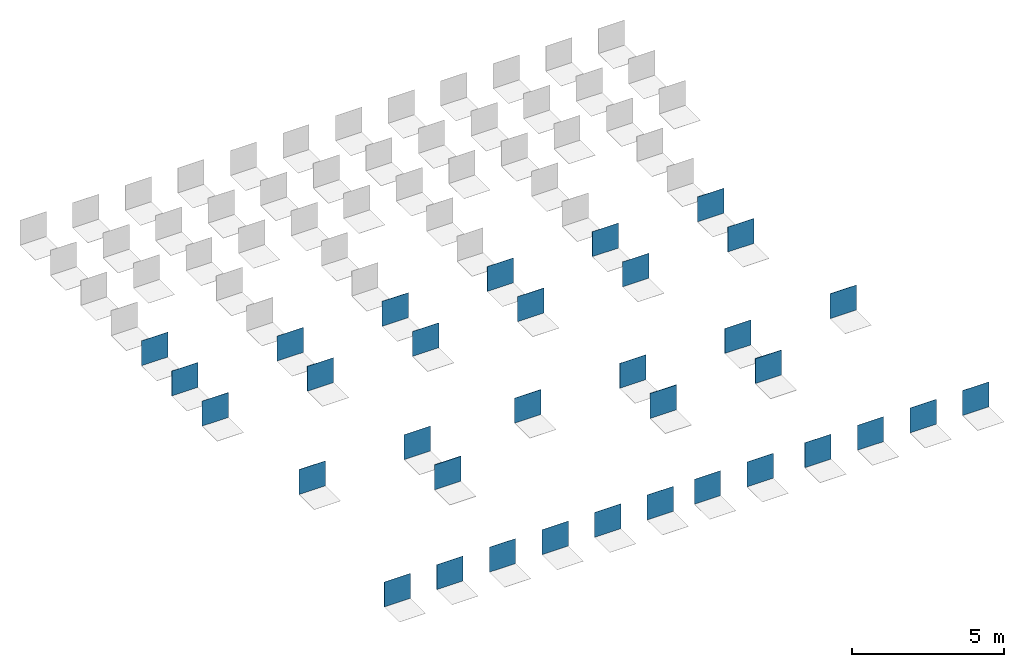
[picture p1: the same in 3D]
Properties of the parts of a building model (IFC2X3), part 2 of 12

# IfcCovering: Floor:REVIGRÉS-URBAN-BASE-30X30-NAT-CRAFT, Floor:REVIGRÉS-URBAN-BASE-30X30-NAT-CRAFT:21541
IFC.REVIGRÉS-Dados do fabricante-Floor Covering - Type: Floor: REVIGRÉS-URBAN-BASE-30X30-NAT-CRAFT
IFC.REVIGRÉS-Dados de desempenho-Floor Covering - Type: Floor: REVIGRÉS-URBAN-BASE-30X30-NAT-CRAFT
IFC.REVIGRÉS-Dados de especificação-Floor Covering - Type: Floor: REVIGRÉS-URBAN-BASE-30X30-NAT-CRAFT
IFC.REVIGRÉS-Dados geométricos-Floor Covering - Type: Floor: REVIGRÉS-URBAN-BASE-30X30-NAT-CRAFT
IFC.REVIGRÉS-Dados de sustentabilidade-Floor Covering - Type: Floor: REVIGRÉS-URBAN-BASE-30X30-NAT-CRAFT

# IfcCovering: Floor:REVIGRÉS-URBAN-BASE-30X30-NAT-FOG, Floor:REVIGRÉS-URBAN-BASE-30X30-NAT-FOG:21563
In: Level 1
Type - PredefinedType: CLADDING; Material: REVIGRÉS-URBAN-BASE-30X30-NAT-FOG 8.5 mm
Type - Pset_CoveringCommon - Reference: 31201221T1; Material: Grés porcelânico
Type - Pset_ElementShading - Roughness: 304.8 mm
Type - Pset_ManufacturerTypeInformation - Manufacturer: REVIGRÉS
Type - Pset_ProductRequirements - Category: Floors
Type - Pset_QuantityTakeOff - Reference: 31201221T1
Type - IFC.REVIGRÉS-Dados do fabricante-Floor Covering - FabricanteURL: https://www.revigres.pt/; ReferenciaModelo: Urban; NumeroGlobalDeItemComercial: 31201221T1; Acabamento: NAT; Material: Grés porcelânico; IdentificadorDoOperadorEconomico: 501840856; UrlFabricanteArtigo: https://www.revigres.pt/colecoes/urban; PaisOrigem: Portugal
Type - IFC.REVIGRÉS-Dados de desempenho-Floor Covering - Rectilinearidade: ± 0.3% máx. ± 1.5 mm; Ortogonalidade: ± 0.3% máx. ± 1.8 mm; PlanaridadeDaSuperficie: ± 0.3% máx. ± 1.8 mm; QualidadeDaSuperficie: Cumpre; AbsorcaoDeAgua: < 0.05%; ModuloDeRuptura: > 45 N/mm²; ResistenciaAFlexao: > 2000 N; ResistenciaAAbrasaoProfunda: < 120 mm³; DilatacaoTermicaLinear: ≤ 8,0x10-6 °C-1; ResistenciaAoChoqueTermico: Resiste; DurabilidadeResistenciaAoGeloDegelo: Resiste; ResistenciaAoEscorregamentoDIN51130: R9; ResistenciaAoEscorregamentoDIN51097: A; ResistenciaAoEscorregamentoENV51097: A; ResistenciaAoEscorregamentoENV12633: Class 1; ResistenciaAoEscorregamentoANSIA1371: ≥0,42; ResistenciaAoDeslizamentoENV12633: Class 1; ResistenciaAsManchas: Class 5; ResistenciaABaixasConcentracoesDeAcidosEAlcalis: Classe LA; ResistenciaAAltasConcentracoesDeAcidosEAlcalis: Classe HA; LibertacaoDeCadmio: 0; LibertacaoDeChumbo: 0
Type - IFC.REVIGRÉS-Dados de especificação-Floor Covering - VariacaoTonalidade: 2; NivelDeTrafego: 5; EPavimento: Sim; ERevestimento: Sim; EExterno: Sim
Type - IFC.REVIGRÉS-Dados geométricos-Floor Covering - AlturaNominal: 8.5 mm; ComprimentoNominal: 30 mm; LarguraNominal: 30 mm
Type - IFC.REVIGRÉS-Dados de sustentabilidade-Floor Covering - EnergiaTermicaExportada: 0; ItemENovo: Sim; ItemEParcialmenteReciclado: 0.23; ItemEReciclado: Sim; VidaÚtilEsperada: 50; SubstanciasPerigosas: Não; PotencialDeEsgotamentoAbioticoDosRecursosFosseis: 203; PotencialDeEsgotamentoAbioticoDosRecursosNaoFosseisMineraisEMetais: 0.000701; PotencialDeAquecimentoGlobalBiogenico: -0.48; CombustiveisFosseisComPotencialDeAquecimentoGlobal: 13.9; PotencialDeAquecimentoGlobalUsoDoSoloEMudancaDeUsoDoSolo: 0.0246; PotencialDeEutrofizacaoFraccaoDeNutrientesQueAtingemOCompartimentoFinalDeAguaDoce: 0.000189; PotencialDeEutrofizacaoFraccaoDeNutrientesQueAtingemOCompartimentoFinalMarinho: 0.0122; EnergiaRecuperada: 0.00739; ConsumoDeAguaDoce: 0.113; UtilizacaoLiquidaDeAguaDoce: 0.113; ResiduosPerigososEliminados: 0.00221; ResiduosNaoPerigososEliminados: 1.83; MassaTotalDeResiduosRadioactivosEliminados: 0.000394; EnergiaElectricaExportada: 1.55; MateriaisParaRecuperacaoDeEnergia: 0.00739; MateriaisParaReciclagem: 0.0253; UnidadeEPD: 1 m²
Type - IFC.REVIGRÉS-Dados gerais-Floor Covering - Nome: REVIGRÉS-URBAN-BASE-30X30-NAT-URBAN FOG; TipoProduto: Prensado a seco: grupo BIa UGL | Grés porcelânico técnico; NumeroDeRegistoDAP: EPD-REV-20240006-CCC1-EN; ReferenciaDAP: -; UrlDOP: -
Classification: C3020 (Uniformat)
Pset_CoveringCommon - TotalThickness: 8.5 mm
IFC.REVIGRÉS-Dados do fabricante-Floor Covering - Type: Floor: REVIGRÉS-URBAN-BASE-30X30-NAT-FOG
IFC.REVIGRÉS-Dados de desempenho-Floor Covering - Type: Floor: REVIGRÉS-URBAN-BASE-30X30-NAT-FOG
IFC.REVIGRÉS-Dados de especificação-Floor Covering - Type: Floor: REVIGRÉS-URBAN-BASE-30X30-NAT-FOG
IFC.REVIGRÉS-Dados geométricos-Floor Covering - Type: Floor: REVIGRÉS-URBAN-BASE-30X30-NAT-FOG
IFC.REVIGRÉS-Dados de sustentabilidade-Floor Covering - Type: Floor: REVIGRÉS-URBAN-BASE-30X30-NAT-FOG

# IfcCovering: Floor:REVIGRÉS-URBAN-BASE-30X30-NAT-GRIS, Floor:REVIGRÉS-URBAN-BASE-30X30-NAT-GRIS:21585
In: Level 1
Type - PredefinedType: CLADDING; Material: REVIGRÉS-URBAN-BASE-30X30-NAT-GRIS 8.5 mm
Type - Pset_CoveringCommon - Reference: 31201222T1; Material: Grés porcelânico
Type - Pset_ElementShading - Roughness: 304.8 mm
Type - Pset_ManufacturerTypeInformation - Manufacturer: REVIGRÉS
Type - Pset_ProductRequirements - Category: Floors
Type - Pset_QuantityTakeOff - Reference: 31201222T1
Type - IFC.REVIGRÉS-Dados do fabricante-Floor Covering - FabricanteURL: https://www.revigres.pt/; ReferenciaModelo: Urban; NumeroGlobalDeItemComercial: 31201222T1; Acabamento: NAT; Material: Grés porcelânico; IdentificadorDoOperadorEconomico: 501840856; UrlFabricanteArtigo: https://www.revigres.pt/colecoes/urban; PaisOrigem: Portugal
Type - IFC.REVIGRÉS-Dados de desempenho-Floor Covering - Rectilinearidade: ± 0.3% máx. ± 1.5 mm; Ortogonalidade: ± 0.3% máx. ± 1.8 mm; PlanaridadeDaSuperficie: ± 0.3% máx. ± 1.8 mm; QualidadeDaSuperficie: Cumpre; AbsorcaoDeAgua: < 0.05%; ModuloDeRuptura: > 45 N/mm²; ResistenciaAFlexao: > 2000 N; ResistenciaAAbrasaoProfunda: < 120 mm³; DilatacaoTermicaLinear: ≤ 8,0x10-6 °C-1; ResistenciaAoChoqueTermico: Resiste; DurabilidadeResistenciaAoGeloDegelo: Resiste; ResistenciaAoEscorregamentoDIN51130: R9; ResistenciaAoEscorregamentoDIN51097: A; ResistenciaAoEscorregamentoENV51097: A; ResistenciaAoEscorregamentoENV12633: Class 1; ResistenciaAoEscorregamentoANSIA1371: ≥0,42; ResistenciaAoDeslizamentoENV12633: Class 1; ResistenciaAsManchas: Class 5; ResistenciaABaixasConcentracoesDeAcidosEAlcalis: Classe LA; ResistenciaAAltasConcentracoesDeAcidosEAlcalis: Classe HA; LibertacaoDeCadmio: 0; LibertacaoDeChumbo: 0
Type - IFC.REVIGRÉS-Dados de especificação-Floor Covering - VariacaoTonalidade: 2; NivelDeTrafego: 5; EPavimento: Sim; ERevestimento: Sim; EExterno: Sim
Type - IFC.REVIGRÉS-Dados geométricos-Floor Covering - AlturaNominal: 8.5 mm; ComprimentoNominal: 30 mm; LarguraNominal: 30 mm
Type - IFC.REVIGRÉS-Dados de sustentabilidade-Floor Covering - EnergiaTermicaExportada: 0; ItemENovo: Sim; ItemEParcialmenteReciclado: 0.23; ItemEReciclado: Sim; VidaÚtilEsperada: 50; SubstanciasPerigosas: Não; PotencialDeEsgotamentoAbioticoDosRecursosFosseis: 203; PotencialDeEsgotamentoAbioticoDosRecursosNaoFosseisMineraisEMetais: 0.000701; PotencialDeAquecimentoGlobalBiogenico: -0.48; CombustiveisFosseisComPotencialDeAquecimentoGlobal: 13.9; PotencialDeAquecimentoGlobalUsoDoSoloEMudancaDeUsoDoSolo: 0.0246; PotencialDeEutrofizacaoFraccaoDeNutrientesQueAtingemOCompartimentoFinalDeAguaDoce: 0.000189; PotencialDeEutrofizacaoFraccaoDeNutrientesQueAtingemOCompartimentoFinalMarinho: 0.0122; EnergiaRecuperada: 0.00739; ConsumoDeAguaDoce: 0.113; UtilizacaoLiquidaDeAguaDoce: 0.113; ResiduosPerigososEliminados: 0.00221; ResiduosNaoPerigososEliminados: 1.83; MassaTotalDeResiduosRadioactivosEliminados: 0.000394; EnergiaElectricaExportada: 1.55; MateriaisParaRecuperacaoDeEnergia: 0.00739; MateriaisParaReciclagem: 0.0253; UnidadeEPD: 1 m²
Type - IFC.REVIGRÉS-Dados gerais-Floor Covering - Nome: REVIGRÉS-URBAN-BASE-30X30-NAT-URBAN GRIS; TipoProduto: Prensado a seco: grupo BIa UGL | Grés porcelânico técnico; NumeroDeRegistoDAP: EPD-REV-20240006-CCC1-EN; ReferenciaDAP: -; UrlDOP: -
Classification: C3020 (Uniformat)
Pset_CoveringCommon - TotalThickness: 8.5 mm
IFC.REVIGRÉS-Dados do fabricante-Floor Covering - Type: Floor: REVIGRÉS-URBAN-BASE-30X30-NAT-GRIS
IFC.REVIGRÉS-Dados de desempenho-Floor Covering - Type: Floor: REVIGRÉS-URBAN-BASE-30X30-NAT-GRIS
IFC.REVIGRÉS-Dados de especificação-Floor Covering - Type: Floor: REVIGRÉS-URBAN-BASE-30X30-NAT-GRIS
IFC.REVIGRÉS-Dados geométricos-Floor Covering - Type: Floor: REVIGRÉS-URBAN-BASE-30X30-NAT-GRIS
IFC.REVIGRÉS-Dados de sustentabilidade-Floor Covering - Type: Floor: REVIGRÉS-URBAN-BASE-30X30-NAT-GRIS

# IfcCovering: Floor:REVIGRÉS-URBAN-BASE-30X30-NAT-OFFWHITE, Floor:REVIGRÉS-URBAN-BASE-30X30-NAT-OFFWHITE:23715
In: Level 1
Type - PredefinedType: CLADDING; Material: REVIGRÉS-URBAN-BASE-30X30-NAT-OFFWHITE 8.5 mm
Type - Pset_CoveringCommon - Reference: 31201223T1; Material: Grés porcelânico
Type - Pset_ElementShading - Roughness: 304.8 mm
Type - Pset_ManufacturerTypeInformation - Manufacturer: REVIGRÉS
Type - Pset_ProductRequirements - Category: Floors
Type - Pset_QuantityTakeOff - Reference: 31201223T1
Type - IFC.REVIGRÉS-Dados do fabricante-Floor Covering - FabricanteURL: https://www.revigres.pt/; ReferenciaModelo: Urban; NumeroGlobalDeItemComercial: 31201223T1; Acabamento: NAT; Material: Grés porcelânico; IdentificadorDoOperadorEconomico: 501840856; UrlFabricanteArtigo: https://www.revigres.pt/colecoes/urban; PaisOrigem: Portugal
Type - IFC.REVIGRÉS-Dados de desempenho-Floor Covering - Rectilinearidade: ± 0.3% máx. ± 1.5 mm; Ortogonalidade: ± 0.3% máx. ± 1.8 mm; PlanaridadeDaSuperficie: ± 0.3% máx. ± 1.8 mm; QualidadeDaSuperficie: Cumpre; AbsorcaoDeAgua: < 0.05%; ModuloDeRuptura: > 45 N/mm²; ResistenciaAFlexao: > 2000 N; ResistenciaAAbrasaoProfunda: < 120 mm³; DilatacaoTermicaLinear: ≤ 8,0x10-6 °C-1; ResistenciaAoChoqueTermico: Resiste; DurabilidadeResistenciaAoGeloDegelo: Resiste; ResistenciaAoEscorregamentoDIN51130: R9; ResistenciaAoEscorregamentoDIN51097: A; ResistenciaAoEscorregamentoENV51097: A; ResistenciaAoEscorregamentoENV12633: Class 1; ResistenciaAoEscorregamentoANSIA1371: ≥0,42; ResistenciaAoDeslizamentoENV12633: Class 1; ResistenciaAsManchas: Class 5; ResistenciaABaixasConcentracoesDeAcidosEAlcalis: Classe LA; ResistenciaAAltasConcentracoesDeAcidosEAlcalis: Classe HA; LibertacaoDeCadmio: 0; LibertacaoDeChumbo: 0
Type - IFC.REVIGRÉS-Dados de especificação-Floor Covering - VariacaoTonalidade: 2; NivelDeTrafego: 5; EPavimento: Sim; ERevestimento: Sim; EExterno: Sim
Type - IFC.REVIGRÉS-Dados geométricos-Floor Covering - AlturaNominal: 8.5 mm; ComprimentoNominal: 30 mm; LarguraNominal: 30 mm
Type - IFC.REVIGRÉS-Dados de sustentabilidade-Floor Covering - EnergiaTermicaExportada: 0; ItemENovo: Sim; ItemEParcialmenteReciclado: 0.03; ItemEReciclado: Sim; VidaÚtilEsperada: 50; SubstanciasPerigosas: Não; PotencialDeEsgotamentoAbioticoDosRecursosFosseis: 203; PotencialDeEsgotamentoAbioticoDosRecursosNaoFosseisMineraisEMetais: 0.000701; PotencialDeAquecimentoGlobalBiogenico: -0.48; CombustiveisFosseisComPotencialDeAquecimentoGlobal: 13.9; PotencialDeAquecimentoGlobalUsoDoSoloEMudancaDeUsoDoSolo: 0.0246; PotencialDeEutrofizacaoFraccaoDeNutrientesQueAtingemOCompartimentoFinalDeAguaDoce: 0.000189; PotencialDeEutrofizacaoFraccaoDeNutrientesQueAtingemOCompartimentoFinalMarinho: 0.0122; EnergiaRecuperada: 0.00739; ConsumoDeAguaDoce: 0.113; UtilizacaoLiquidaDeAguaDoce: 0.113; ResiduosPerigososEliminados: 0.00221; ResiduosNaoPerigososEliminados: 1.83; MassaTotalDeResiduosRadioactivosEliminados: 0.000394; EnergiaElectricaExportada: 1.55; MateriaisParaRecuperacaoDeEnergia: 0.00739; MateriaisParaReciclagem: 0.0253; UnidadeEPD: 1 m²
Type - IFC.REVIGRÉS-Dados gerais-Floor Covering - Nome: REVIGRÉS-URBAN-BASE-30X30-NAT-URBAN OFFWHITE; TipoProduto: Prensado a seco: grupo BIa UGL | Grés porcelânico técnico; NumeroDeRegistoDAP: EPD-REV-20240006-CCC1-EN; ReferenciaDAP: -; UrlDOP: -
Classification: C3020 (Uniformat)
Pset_CoveringCommon - TotalThickness: 8.5 mm
IFC.REVIGRÉS-Dados do fabricante-Floor Covering - Type: Floor: REVIGRÉS-URBAN-BASE-30X30-NAT-OFFWHITE
IFC.REVIGRÉS-Dados de desempenho-Floor Covering - Type: Floor: REVIGRÉS-URBAN-BASE-30X30-NAT-OFFWHITE
IFC.REVIGRÉS-Dados de especificação-Floor Covering - Type: Floor: REVIGRÉS-URBAN-BASE-30X30-NAT-OFFWHITE
IFC.REVIGRÉS-Dados geométricos-Floor Covering - Type: Floor: REVIGRÉS-URBAN-BASE-30X30-NAT-OFFWHITE
IFC.REVIGRÉS-Dados de sustentabilidade-Floor Covering - Type: Floor: REVIGRÉS-URBAN-BASE-30X30-NAT-OFFWHITE

# IfcCovering: Floor:REVIGRÉS-URBAN-BASE-30X60-NAT-ANTRACITE, Floor:REVIGRÉS-URBAN-BASE-30X60-NAT-ANTRACITE:25908
In: Level 1
Type - PredefinedType: CLADDING; Material: REVIGRÉS-URBAN-BASE-30X60-NAT-ANTRACITE 8.5 mm
Type - Pset_CoveringCommon - Reference: 31202148U1; Material: Grés porcelânico
Type - Pset_ElementShading - Roughness: 304.8 mm
Type - Pset_ManufacturerTypeInformation - Manufacturer: REVIGRÉS
Type - Pset_ProductRequirements - Category: Floors
Type - Pset_QuantityTakeOff - Reference: 31202148U1
Type - IFC.REVIGRÉS-Dados do fabricante-Floor Covering - FabricanteURL: https://www.revigres.pt/; ReferenciaModelo: Urban; NumeroGlobalDeItemComercial: 31202148U1; Acabamento: NAT; Material: Grés porcelânico; IdentificadorDoOperadorEconomico: 501840856; UrlFabricanteArtigo: https://www.revigres.pt/colecoes/urban; PaisOrigem: Portugal
Type - IFC.REVIGRÉS-Dados de desempenho-Floor Covering - Rectilinearidade: ± 0.3% máx. ± 1.5 mm; Ortogonalidade: ± 0.3% máx. ± 1.8 mm; PlanaridadeDaSuperficie: ± 0.3% máx. ± 1.8 mm; QualidadeDaSuperficie: Cumpre; AbsorcaoDeAgua: < 0.05%; ModuloDeRuptura: > 45 N/mm²; ResistenciaAFlexao: > 2000 N; ResistenciaAAbrasaoProfunda: < 120 mm³; DilatacaoTermicaLinear: ≤ 8,0x10-6 °C-1; ResistenciaAoChoqueTermico: Resiste; DurabilidadeResistenciaAoGeloDegelo: Resiste; ResistenciaAoEscorregamentoDIN51130: R9; ResistenciaAoEscorregamentoDIN51097: A; ResistenciaAoEscorregamentoENV51097: A; ResistenciaAoEscorregamentoENV12633: Class 1; ResistenciaAoEscorregamentoANSIA1371: ≥0,42; ResistenciaAoDeslizamentoENV12633: Class 1; ResistenciaAsManchas: Class 5; ResistenciaABaixasConcentracoesDeAcidosEAlcalis: Classe LA; ResistenciaAAltasConcentracoesDeAcidosEAlcalis: Classe HA; LibertacaoDeCadmio: 0; LibertacaoDeChumbo: 0
Type - IFC.REVIGRÉS-Dados de especificação-Floor Covering - VariacaoTonalidade: 2; NivelDeTrafego: 5; EPavimento: Sim; ERevestimento: Sim; EExterno: Sim
Type - IFC.REVIGRÉS-Dados geométricos-Floor Covering - AlturaNominal: 8.5 mm; ComprimentoNominal: 30 mm; LarguraNominal: 60 mm
Type - IFC.REVIGRÉS-Dados de sustentabilidade-Floor Covering - EnergiaTermicaExportada: 0; ItemENovo: Sim; ItemEParcialmenteReciclado: 0.29; ItemEReciclado: Sim; VidaÚtilEsperada: 50; SubstanciasPerigosas: Não; PotencialDeEsgotamentoAbioticoDosRecursosFosseis: 203; PotencialDeEsgotamentoAbioticoDosRecursosNaoFosseisMineraisEMetais: 0.000701; PotencialDeAquecimentoGlobalBiogenico: -0.48; CombustiveisFosseisComPotencialDeAquecimentoGlobal: 13.9; PotencialDeAquecimentoGlobalUsoDoSoloEMudancaDeUsoDoSolo: 0.0246; PotencialDeEutrofizacaoFraccaoDeNutrientesQueAtingemOCompartimentoFinalDeAguaDoce: 0.000189; PotencialDeEutrofizacaoFraccaoDeNutrientesQueAtingemOCompartimentoFinalMarinho: 0.0122; EnergiaRecuperada: 0.00739; ConsumoDeAguaDoce: 0.113; UtilizacaoLiquidaDeAguaDoce: 0.113; ResiduosPerigososEliminados: 0.00221; ResiduosNaoPerigososEliminados: 1.83; MassaTotalDeResiduosRadioactivosEliminados: 0.000394; EnergiaElectricaExportada: 1.55; MateriaisParaRecuperacaoDeEnergia: 0.00739; MateriaisParaReciclagem: 0.0253; UnidadeEPD: 1 m²
Type - IFC.REVIGRÉS-Dados gerais-Floor Covering - Nome: REVIGRÉS-URBAN-BASE-30X60-NAT-URBAN ANTRACITE; TipoProduto: Prensado a seco: grupo BIa UGL | Grés porcelânico técnico; NumeroDeRegistoDAP: EPD-REV-20240006-CCC1-EN; ReferenciaDAP: -; UrlDOP: -
Classification: C3020 (Uniformat)
Pset_CoveringCommon - TotalThickness: 8.5 mm
IFC.REVIGRÉS-Dados do fabricante-Floor Covering - Type: Floor: REVIGRÉS-URBAN-BASE-30X60-NAT-ANTRACITE
IFC.REVIGRÉS-Dados de desempenho-Floor Covering - Type: Floor: REVIGRÉS-URBAN-BASE-30X60-NAT-ANTRACITE
IFC.REVIGRÉS-Dados de especificação-Floor Covering - Type: Floor: REVIGRÉS-URBAN-BASE-30X60-NAT-ANTRACITE
IFC.REVIGRÉS-Dados geométricos-Floor Covering - Type: Floor: REVIGRÉS-URBAN-BASE-30X60-NAT-ANTRACITE
IFC.REVIGRÉS-Dados de sustentabilidade-Floor Covering - Type: Floor: REVIGRÉS-URBAN-BASE-30X60-NAT-ANTRACITE

# IfcCovering: Floor:REVIGRÉS-URBAN-BASE-30X60-NAT-BONE, Floor:REVIGRÉS-URBAN-BASE-30X60-NAT-BONE:25916
In: Level 1
Type - PredefinedType: CLADDING; Material: REVIGRÉS-URBAN-BASE-30X60-NAT-BONE 8.5 mm
Type - Pset_CoveringCommon - Reference: 31202120T1; Material: Grés porcelânico
Type - Pset_ElementShading - Roughness: 304.8 mm
Type - Pset_ManufacturerTypeInformation - Manufacturer: REVIGRÉS
Type - Pset_ProductRequirements - Category: Floors
Type - Pset_QuantityTakeOff - Reference: 31202120T1
Type - IFC.REVIGRÉS-Dados do fabricante-Floor Covering - FabricanteURL: https://www.revigres.pt/; ReferenciaModelo: Urban; NumeroGlobalDeItemComercial: 31202120T1; Acabamento: NAT; Material: Grés porcelânico; IdentificadorDoOperadorEconomico: 501840856; UrlFabricanteArtigo: https://www.revigres.pt/colecoes/urban; PaisOrigem: Portugal
Type - IFC.REVIGRÉS-Dados de desempenho-Floor Covering - Rectilinearidade: ± 0.3% máx. ± 1.5 mm; Ortogonalidade: ± 0.3% máx. ± 1.8 mm; PlanaridadeDaSuperficie: ± 0.3% máx. ± 1.8 mm; QualidadeDaSuperficie: Cumpre; AbsorcaoDeAgua: < 0.05%; ModuloDeRuptura: > 45 N/mm²; ResistenciaAFlexao: > 2000 N; ResistenciaAAbrasaoProfunda: < 120 mm³; DilatacaoTermicaLinear: ≤ 8,0x10-6 °C-1; ResistenciaAoChoqueTermico: Resiste; DurabilidadeResistenciaAoGeloDegelo: Resiste; ResistenciaAoEscorregamentoDIN51130: R9; ResistenciaAoEscorregamentoDIN51097: A; ResistenciaAoEscorregamentoENV51097: A; ResistenciaAoEscorregamentoENV12633: Class 1; ResistenciaAoEscorregamentoANSIA1371: ≥0,42; ResistenciaAoDeslizamentoENV12633: Class 1; ResistenciaAsManchas: Class 5; ResistenciaABaixasConcentracoesDeAcidosEAlcalis: Classe LA; ResistenciaAAltasConcentracoesDeAcidosEAlcalis: Classe HA; LibertacaoDeCadmio: 0; LibertacaoDeChumbo: 0
Type - IFC.REVIGRÉS-Dados de especificação-Floor Covering - VariacaoTonalidade: 2; NivelDeTrafego: 5; EPavimento: Sim; ERevestimento: Sim; EExterno: Sim
Type - IFC.REVIGRÉS-Dados geométricos-Floor Covering - AlturaNominal: 8.5 mm; ComprimentoNominal: 30 mm; LarguraNominal: 60 mm
Type - IFC.REVIGRÉS-Dados de sustentabilidade-Floor Covering - EnergiaTermicaExportada: 0; ItemENovo: Sim; ItemEParcialmenteReciclado: 0.03; ItemEReciclado: Sim; VidaÚtilEsperada: 50; SubstanciasPerigosas: Não; PotencialDeEsgotamentoAbioticoDosRecursosFosseis: 203; PotencialDeEsgotamentoAbioticoDosRecursosNaoFosseisMineraisEMetais: 0.000701; PotencialDeAquecimentoGlobalBiogenico: -0.48; CombustiveisFosseisComPotencialDeAquecimentoGlobal: 13.9; PotencialDeAquecimentoGlobalUsoDoSoloEMudancaDeUsoDoSolo: 0.0246; PotencialDeEutrofizacaoFraccaoDeNutrientesQueAtingemOCompartimentoFinalDeAguaDoce: 0.000189; PotencialDeEutrofizacaoFraccaoDeNutrientesQueAtingemOCompartimentoFinalMarinho: 0.0122; EnergiaRecuperada: 0.00739; ConsumoDeAguaDoce: 0.113; UtilizacaoLiquidaDeAguaDoce: 0.113; ResiduosPerigososEliminados: 0.00221; ResiduosNaoPerigososEliminados: 1.83; MassaTotalDeResiduosRadioactivosEliminados: 0.000394; EnergiaElectricaExportada: 1.55; MateriaisParaRecuperacaoDeEnergia: 0.00739; MateriaisParaReciclagem: 0.0253; UnidadeEPD: 1 m²
Type - IFC.REVIGRÉS-Dados gerais-Floor Covering - Nome: REVIGRÉS-URBAN-BASE-30X60-NAT-URBAN BONE; TipoProduto: Prensado a seco: grupo BIa UGL | Grés porcelânico técnico; NumeroDeRegistoDAP: EPD-REV-20240006-CCC1-EN; ReferenciaDAP: -; UrlDOP: -
Classification: C3020 (Uniformat)
Pset_CoveringCommon - TotalThickness: 8.5 mm
IFC.REVIGRÉS-Dados do fabricante-Floor Covering - Type: Floor: REVIGRÉS-URBAN-BASE-30X60-NAT-BONE
IFC.REVIGRÉS-Dados de desempenho-Floor Covering - Type: Floor: REVIGRÉS-URBAN-BASE-30X60-NAT-BONE
IFC.REVIGRÉS-Dados de especificação-Floor Covering - Type: Floor: REVIGRÉS-URBAN-BASE-30X60-NAT-BONE
IFC.REVIGRÉS-Dados geométricos-Floor Covering - Type: Floor: REVIGRÉS-URBAN-BASE-30X60-NAT-BONE
IFC.REVIGRÉS-Dados de sustentabilidade-Floor Covering - Type: Floor: REVIGRÉS-URBAN-BASE-30X60-NAT-BONE

# IfcCovering: Floor:REVIGRÉS-URBAN-BASE-30X60-NAT-CRAFT, Floor:REVIGRÉS-URBAN-BASE-30X60-NAT-CRAFT:25924
In: Level 1
Type - PredefinedType: CLADDING; Material: REVIGRÉS-URBAN-BASE-30X60-NAT-CRAFT 8.5 mm
Type - Pset_CoveringCommon - Reference: 31202124T1; Material: Grés porcelânico
Type - Pset_ElementShading - Roughness: 304.8 mm
Type - Pset_ManufacturerTypeInformation - Manufacturer: REVIGRÉS
Type - Pset_ProductRequirements - Category: Floors
Type - Pset_QuantityTakeOff - Reference: 31202124T1
Type - IFC.REVIGRÉS-Dados do fabricante-Floor Covering - FabricanteURL: https://www.revigres.pt/; ReferenciaModelo: Urban; NumeroGlobalDeItemComercial: 31202124T1; Acabamento: NAT; Material: Grés porcelânico; IdentificadorDoOperadorEconomico: 501840856; UrlFabricanteArtigo: https://www.revigres.pt/colecoes/urban; PaisOrigem: Portugal
Type - IFC.REVIGRÉS-Dados de desempenho-Floor Covering - Rectilinearidade: ± 0.3% máx. ± 1.5 mm; Ortogonalidade: ± 0.3% máx. ± 1.8 mm; PlanaridadeDaSuperficie: ± 0.3% máx. ± 1.8 mm; QualidadeDaSuperficie: Cumpre; AbsorcaoDeAgua: < 0.05%; ModuloDeRuptura: > 45 N/mm²; ResistenciaAFlexao: > 2000 N; ResistenciaAAbrasaoProfunda: < 120 mm³; DilatacaoTermicaLinear: ≤ 8,0x10-6 °C-1; ResistenciaAoChoqueTermico: Resiste; DurabilidadeResistenciaAoGeloDegelo: Resiste; ResistenciaAoEscorregamentoDIN51130: R9; ResistenciaAoEscorregamentoDIN51097: A; ResistenciaAoEscorregamentoENV51097: A; ResistenciaAoEscorregamentoENV12633: Class 1; ResistenciaAoEscorregamentoANSIA1371: ≥0,42; ResistenciaAoDeslizamentoENV12633: Class 1; ResistenciaAsManchas: Class 5; ResistenciaABaixasConcentracoesDeAcidosEAlcalis: Classe LA; ResistenciaAAltasConcentracoesDeAcidosEAlcalis: Classe HA; LibertacaoDeCadmio: 0; LibertacaoDeChumbo: 0
Type - IFC.REVIGRÉS-Dados de especificação-Floor Covering - VariacaoTonalidade: 2; NivelDeTrafego: 5; EPavimento: Sim; ERevestimento: Sim; EExterno: Sim
Type - IFC.REVIGRÉS-Dados geométricos-Floor Covering - AlturaNominal: 8.5 mm; ComprimentoNominal: 30 mm; LarguraNominal: 60 mm
Type - IFC.REVIGRÉS-Dados de sustentabilidade-Floor Covering - EnergiaTermicaExportada: 0; ItemENovo: Sim; ItemEParcialmenteReciclado: 0.19; ItemEReciclado: Sim; VidaÚtilEsperada: 50; SubstanciasPerigosas: Não; PotencialDeEsgotamentoAbioticoDosRecursosFosseis: 203; PotencialDeEsgotamentoAbioticoDosRecursosNaoFosseisMineraisEMetais: 0.000701; PotencialDeAquecimentoGlobalBiogenico: -0.48; CombustiveisFosseisComPotencialDeAquecimentoGlobal: 13.9; PotencialDeAquecimentoGlobalUsoDoSoloEMudancaDeUsoDoSolo: 0.0246; PotencialDeEutrofizacaoFraccaoDeNutrientesQueAtingemOCompartimentoFinalDeAguaDoce: 0.000189; PotencialDeEutrofizacaoFraccaoDeNutrientesQueAtingemOCompartimentoFinalMarinho: 0.0122; EnergiaRecuperada: 0.00739; ConsumoDeAguaDoce: 0.113; UtilizacaoLiquidaDeAguaDoce: 0.113; ResiduosPerigososEliminados: 0.00221; ResiduosNaoPerigososEliminados: 1.83; MassaTotalDeResiduosRadioactivosEliminados: 0.000394; EnergiaElectricaExportada: 1.55; MateriaisParaRecuperacaoDeEnergia: 0.00739; MateriaisParaReciclagem: 0.0253; UnidadeEPD: 1 m²
Type - IFC.REVIGRÉS-Dados gerais-Floor Covering - Nome: REVIGRÉS-URBAN-BASE-30X60-NAT-URBAN CRAFT; TipoProduto: Prensado a seco: grupo BIa UGL | Grés porcelânico técnico; NumeroDeRegistoDAP: EPD-REV-20240006-CCC1-EN; ReferenciaDAP: -; UrlDOP: -
Classification: C3020 (Uniformat)
Pset_CoveringCommon - TotalThickness: 8.5 mm
IFC.REVIGRÉS-Dados do fabricante-Floor Covering - Type: Floor: REVIGRÉS-URBAN-BASE-30X60-NAT-CRAFT
IFC.REVIGRÉS-Dados de desempenho-Floor Covering - Type: Floor: REVIGRÉS-URBAN-BASE-30X60-NAT-CRAFT
IFC.REVIGRÉS-Dados de especificação-Floor Covering - Type: Floor: REVIGRÉS-URBAN-BASE-30X60-NAT-CRAFT
IFC.REVIGRÉS-Dados geométricos-Floor Covering - Type: Floor: REVIGRÉS-URBAN-BASE-30X60-NAT-CRAFT
IFC.REVIGRÉS-Dados de sustentabilidade-Floor Covering - Type: Floor: REVIGRÉS-URBAN-BASE-30X60-NAT-CRAFT

# IfcCovering: Floor:REVIGRÉS-URBAN-BASE-30X60-NAT-FOG, Floor:REVIGRÉS-URBAN-BASE-30X60-NAT-FOG:25932
In: Level 1
Type - PredefinedType: CLADDING; Material: REVIGRÉS-URBAN-BASE-30X60-NAT-FOG 8.5 mm
Type - Pset_CoveringCommon - Reference: 31202121T1; Material: Grés porcelânico
Type - Pset_ElementShading - Roughness: 304.8 mm
Type - Pset_ManufacturerTypeInformation - Manufacturer: REVIGRÉS
Type - Pset_ProductRequirements - Category: Floors
Type - Pset_QuantityTakeOff - Reference: 31202121T1
Type - IFC.REVIGRÉS-Dados do fabricante-Floor Covering - FabricanteURL: https://www.revigres.pt/; ReferenciaModelo: Urban; NumeroGlobalDeItemComercial: 31202121T1; Acabamento: NAT; Material: Grés porcelânico; IdentificadorDoOperadorEconomico: 501840856; UrlFabricanteArtigo: https://www.revigres.pt/colecoes/urban; PaisOrigem: Portugal
Type - IFC.REVIGRÉS-Dados de desempenho-Floor Covering - Rectilinearidade: ± 0.3% máx. ± 1.5 mm; Ortogonalidade: ± 0.3% máx. ± 1.8 mm; PlanaridadeDaSuperficie: ± 0.3% máx. ± 1.8 mm; QualidadeDaSuperficie: Cumpre; AbsorcaoDeAgua: < 0.05%; ModuloDeRuptura: > 45 N/mm²; ResistenciaAFlexao: > 2000 N; ResistenciaAAbrasaoProfunda: < 120 mm³; DilatacaoTermicaLinear: ≤ 8,0x10-6 °C-1; ResistenciaAoChoqueTermico: Resiste; DurabilidadeResistenciaAoGeloDegelo: Resiste; ResistenciaAoEscorregamentoDIN51130: R9; ResistenciaAoEscorregamentoDIN51097: A; ResistenciaAoEscorregamentoENV51097: A; ResistenciaAoEscorregamentoENV12633: Class 1; ResistenciaAoEscorregamentoANSIA1371: ≥0,42; ResistenciaAoDeslizamentoENV12633: Class 1; ResistenciaAsManchas: Class 5; ResistenciaABaixasConcentracoesDeAcidosEAlcalis: Classe LA; ResistenciaAAltasConcentracoesDeAcidosEAlcalis: Classe HA; LibertacaoDeCadmio: 0; LibertacaoDeChumbo: 0
Type - IFC.REVIGRÉS-Dados de especificação-Floor Covering - VariacaoTonalidade: 2; NivelDeTrafego: 5; EPavimento: Sim; ERevestimento: Sim; EExterno: Sim
Type - IFC.REVIGRÉS-Dados geométricos-Floor Covering - AlturaNominal: 8.5 mm; ComprimentoNominal: 30 mm; LarguraNominal: 60 mm
Type - IFC.REVIGRÉS-Dados de sustentabilidade-Floor Covering - EnergiaTermicaExportada: 0; ItemENovo: Sim; ItemEParcialmenteReciclado: 0.23; ItemEReciclado: Sim; VidaÚtilEsperada: 50; SubstanciasPerigosas: Não; PotencialDeEsgotamentoAbioticoDosRecursosFosseis: 203; PotencialDeEsgotamentoAbioticoDosRecursosNaoFosseisMineraisEMetais: 0.000701; PotencialDeAquecimentoGlobalBiogenico: -0.48; CombustiveisFosseisComPotencialDeAquecimentoGlobal: 13.9; PotencialDeAquecimentoGlobalUsoDoSoloEMudancaDeUsoDoSolo: 0.0246; PotencialDeEutrofizacaoFraccaoDeNutrientesQueAtingemOCompartimentoFinalDeAguaDoce: 0.000189; PotencialDeEutrofizacaoFraccaoDeNutrientesQueAtingemOCompartimentoFinalMarinho: 0.0122; EnergiaRecuperada: 0.00739; ConsumoDeAguaDoce: 0.113; UtilizacaoLiquidaDeAguaDoce: 0.113; ResiduosPerigososEliminados: 0.00221; ResiduosNaoPerigososEliminados: 1.83; MassaTotalDeResiduosRadioactivosEliminados: 0.000394; EnergiaElectricaExportada: 1.55; MateriaisParaRecuperacaoDeEnergia: 0.00739; MateriaisParaReciclagem: 0.0253; UnidadeEPD: 1 m²
Type - IFC.REVIGRÉS-Dados gerais-Floor Covering - Nome: REVIGRÉS-URBAN-BASE-30X60-NAT-URBAN FOG; TipoProduto: Prensado a seco: grupo BIa UGL | Grés porcelânico técnico; NumeroDeRegistoDAP: EPD-REV-20240006-CCC1-EN; ReferenciaDAP: -; UrlDOP: -
Classification: C3020 (Uniformat)
Pset_CoveringCommon - TotalThickness: 8.5 mm
IFC.REVIGRÉS-Dados do fabricante-Floor Covering - Type: Floor: REVIGRÉS-URBAN-BASE-30X60-NAT-FOG
IFC.REVIGRÉS-Dados de desempenho-Floor Covering - Type: Floor: REVIGRÉS-URBAN-BASE-30X60-NAT-FOG
IFC.REVIGRÉS-Dados de especificação-Floor Covering - Type: Floor: REVIGRÉS-URBAN-BASE-30X60-NAT-FOG
IFC.REVIGRÉS-Dados geométricos-Floor Covering - Type: Floor: REVIGRÉS-URBAN-BASE-30X60-NAT-FOG
IFC.REVIGRÉS-Dados de sustentabilidade-Floor Covering - Type: Floor: REVIGRÉS-URBAN-BASE-30X60-NAT-FOG

# IfcCovering: Floor:REVIGRÉS-URBAN-BASE-30X60-NAT-GRIS, Floor:REVIGRÉS-URBAN-BASE-30X60-NAT-GRIS:25940
In: Level 1
Type - PredefinedType: CLADDING; Material: REVIGRÉS-URBAN-BASE-30X60-NAT-GRIS 8.5 mm
Type - Pset_CoveringCommon - Reference: 31202122T1; Material: Grés porcelânico
Type - Pset_ElementShading - Roughness: 304.8 mm
Type - Pset_ManufacturerTypeInformation - Manufacturer: REVIGRÉS
Type - Pset_ProductRequirements - Category: Floors
Type - Pset_QuantityTakeOff - Reference: 31202122T1
Type - IFC.REVIGRÉS-Dados do fabricante-Floor Covering - FabricanteURL: https://www.revigres.pt/; ReferenciaModelo: Urban; NumeroGlobalDeItemComercial: 31202122T1; Acabamento: NAT; Material: Grés porcelânico; IdentificadorDoOperadorEconomico: 501840856; UrlFabricanteArtigo: https://www.revigres.pt/colecoes/urban; PaisOrigem: Portugal
Type - IFC.REVIGRÉS-Dados de desempenho-Floor Covering - Rectilinearidade: ± 0.3% máx. ± 1.5 mm; Ortogonalidade: ± 0.3% máx. ± 1.8 mm; PlanaridadeDaSuperficie: ± 0.3% máx. ± 1.8 mm; QualidadeDaSuperficie: Cumpre; AbsorcaoDeAgua: < 0.05%; ModuloDeRuptura: > 45 N/mm²; ResistenciaAFlexao: > 2000 N; ResistenciaAAbrasaoProfunda: < 120 mm³; DilatacaoTermicaLinear: ≤ 8,0x10-6 °C-1; ResistenciaAoChoqueTermico: Resiste; DurabilidadeResistenciaAoGeloDegelo: Resiste; ResistenciaAoEscorregamentoDIN51130: R9; ResistenciaAoEscorregamentoDIN51097: A; ResistenciaAoEscorregamentoENV51097: A; ResistenciaAoEscorregamentoENV12633: Class 1; ResistenciaAoEscorregamentoANSIA1371: ≥0,42; ResistenciaAoDeslizamentoENV12633: Class 1; ResistenciaAsManchas: Class 5; ResistenciaABaixasConcentracoesDeAcidosEAlcalis: Classe LA; ResistenciaAAltasConcentracoesDeAcidosEAlcalis: Classe HA; LibertacaoDeCadmio: 0; LibertacaoDeChumbo: 0
Type - IFC.REVIGRÉS-Dados de especificação-Floor Covering - VariacaoTonalidade: 2; NivelDeTrafego: 5; EPavimento: Sim; ERevestimento: Sim; EExterno: Sim
Type - IFC.REVIGRÉS-Dados geométricos-Floor Covering - AlturaNominal: 8.5 mm; ComprimentoNominal: 30 mm; LarguraNominal: 60 mm
Type - IFC.REVIGRÉS-Dados de sustentabilidade-Floor Covering - EnergiaTermicaExportada: 0; ItemENovo: Sim; ItemEParcialmenteReciclado: 0.23; ItemEReciclado: Sim; VidaÚtilEsperada: 50; SubstanciasPerigosas: Não; PotencialDeEsgotamentoAbioticoDosRecursosFosseis: 203; PotencialDeEsgotamentoAbioticoDosRecursosNaoFosseisMineraisEMetais: 0.000701; PotencialDeAquecimentoGlobalBiogenico: -0.48; CombustiveisFosseisComPotencialDeAquecimentoGlobal: 13.9; PotencialDeAquecimentoGlobalUsoDoSoloEMudancaDeUsoDoSolo: 0.0246; PotencialDeEutrofizacaoFraccaoDeNutrientesQueAtingemOCompartimentoFinalDeAguaDoce: 0.000189; PotencialDeEutrofizacaoFraccaoDeNutrientesQueAtingemOCompartimentoFinalMarinho: 0.0122; EnergiaRecuperada: 0.00739; ConsumoDeAguaDoce: 0.113; UtilizacaoLiquidaDeAguaDoce: 0.113; ResiduosPerigososEliminados: 0.00221; ResiduosNaoPerigososEliminados: 1.83; MassaTotalDeResiduosRadioactivosEliminados: 0.000394; EnergiaElectricaExportada: 1.55; MateriaisParaRecuperacaoDeEnergia: 0.00739; MateriaisParaReciclagem: 0.0253; UnidadeEPD: 1 m²
Type - IFC.REVIGRÉS-Dados gerais-Floor Covering - Nome: REVIGRÉS-URBAN-BASE-30X60-NAT-URBAN GRIS; TipoProduto: Prensado a seco: grupo BIa UGL | Grés porcelânico técnico; NumeroDeRegistoDAP: EPD-REV-20240006-CCC1-EN; ReferenciaDAP: -; UrlDOP: -
Classification: C3020 (Uniformat)
Pset_CoveringCommon - TotalThickness: 8.5 mm
IFC.REVIGRÉS-Dados do fabricante-Floor Covering - Type: Floor: REVIGRÉS-URBAN-BASE-30X60-NAT-GRIS
IFC.REVIGRÉS-Dados de desempenho-Floor Covering - Type: Floor: REVIGRÉS-URBAN-BASE-30X60-NAT-GRIS
IFC.REVIGRÉS-Dados de especificação-Floor Covering - Type: Floor: REVIGRÉS-URBAN-BASE-30X60-NAT-GRIS
IFC.REVIGRÉS-Dados geométricos-Floor Covering - Type: Floor: REVIGRÉS-URBAN-BASE-30X60-NAT-GRIS
IFC.REVIGRÉS-Dados de sustentabilidade-Floor Covering - Type: Floor: REVIGRÉS-URBAN-BASE-30X60-NAT-GRIS

# IfcCovering: Floor:REVIGRÉS-URBAN-BASE-30X60-NAT-OFFWHITE, Floor:REVIGRÉS-URBAN-BASE-30X60-NAT-OFFWHITE:25948
In: Level 1
Type - PredefinedType: CLADDING; Material: REVIGRÉS-URBAN-BASE-30X60-NAT-OFFWHITE 8.5 mm
Type - Pset_CoveringCommon - Reference: 31202123T1; Material: Grés porcelânico
Type - Pset_ElementShading - Roughness: 304.8 mm
Type - Pset_ManufacturerTypeInformation - Manufacturer: REVIGRÉS
Type - Pset_ProductRequirements - Category: Floors
Type - Pset_QuantityTakeOff - Reference: 31202123T1
Type - IFC.REVIGRÉS-Dados do fabricante-Floor Covering - FabricanteURL: https://www.revigres.pt/; ReferenciaModelo: Urban; NumeroGlobalDeItemComercial: 31202123T1; Acabamento: NAT; Material: Grés porcelânico; IdentificadorDoOperadorEconomico: 501840856; UrlFabricanteArtigo: https://www.revigres.pt/colecoes/urban; PaisOrigem: Portugal
Type - IFC.REVIGRÉS-Dados de desempenho-Floor Covering - Rectilinearidade: ± 0.3% máx. ± 1.5 mm; Ortogonalidade: ± 0.3% máx. ± 1.8 mm; PlanaridadeDaSuperficie: ± 0.3% máx. ± 1.8 mm; QualidadeDaSuperficie: Cumpre; AbsorcaoDeAgua: < 0.05%; ModuloDeRuptura: > 45 N/mm²; ResistenciaAFlexao: > 2000 N; ResistenciaAAbrasaoProfunda: < 120 mm³; DilatacaoTermicaLinear: ≤ 8,0x10-6 °C-1; ResistenciaAoChoqueTermico: Resiste; DurabilidadeResistenciaAoGeloDegelo: Resiste; ResistenciaAoEscorregamentoDIN51130: R9; ResistenciaAoEscorregamentoDIN51097: A; ResistenciaAoEscorregamentoENV51097: A; ResistenciaAoEscorregamentoENV12633: Class 1; ResistenciaAoEscorregamentoANSIA1371: ≥0,42; ResistenciaAoDeslizamentoENV12633: Class 1; ResistenciaAsManchas: Class 5; ResistenciaABaixasConcentracoesDeAcidosEAlcalis: Classe LA; ResistenciaAAltasConcentracoesDeAcidosEAlcalis: Classe HA; LibertacaoDeCadmio: 0; LibertacaoDeChumbo: 0
Type - IFC.REVIGRÉS-Dados de especificação-Floor Covering - VariacaoTonalidade: 2; NivelDeTrafego: 5; EPavimento: Sim; ERevestimento: Sim; EExterno: Sim
Type - IFC.REVIGRÉS-Dados geométricos-Floor Covering - AlturaNominal: 8.5 mm; ComprimentoNominal: 30 mm; LarguraNominal: 60 mm
Type - IFC.REVIGRÉS-Dados de sustentabilidade-Floor Covering - EnergiaTermicaExportada: 0; ItemENovo: Sim; ItemEParcialmenteReciclado: 0.03; ItemEReciclado: Sim; VidaÚtilEsperada: 50; SubstanciasPerigosas: Não; PotencialDeEsgotamentoAbioticoDosRecursosFosseis: 203; PotencialDeEsgotamentoAbioticoDosRecursosNaoFosseisMineraisEMetais: 0.000701; PotencialDeAquecimentoGlobalBiogenico: -0.48; CombustiveisFosseisComPotencialDeAquecimentoGlobal: 13.9; PotencialDeAquecimentoGlobalUsoDoSoloEMudancaDeUsoDoSolo: 0.0246; PotencialDeEutrofizacaoFraccaoDeNutrientesQueAtingemOCompartimentoFinalDeAguaDoce: 0.000189; PotencialDeEutrofizacaoFraccaoDeNutrientesQueAtingemOCompartimentoFinalMarinho: 0.0122; EnergiaRecuperada: 0.00739; ConsumoDeAguaDoce: 0.113; UtilizacaoLiquidaDeAguaDoce: 0.113; ResiduosPerigososEliminados: 0.00221; ResiduosNaoPerigososEliminados: 1.83; MassaTotalDeResiduosRadioactivosEliminados: 0.000394; EnergiaElectricaExportada: 1.55; MateriaisParaRecuperacaoDeEnergia: 0.00739; MateriaisParaReciclagem: 0.0253; UnidadeEPD: 1 m²
Type - IFC.REVIGRÉS-Dados gerais-Floor Covering - Nome: REVIGRÉS-URBAN-BASE-30X60-NAT-URBAN OFFWHITE; TipoProduto: Prensado a seco: grupo BIa UGL | Grés porcelânico técnico; NumeroDeRegistoDAP: EPD-REV-20240006-CCC1-EN; ReferenciaDAP: -; UrlDOP: -
Classification: C3020 (Uniformat)
Pset_CoveringCommon - TotalThickness: 8.5 mm
IFC.REVIGRÉS-Dados do fabricante-Floor Covering - Type: Floor: REVIGRÉS-URBAN-BASE-30X60-NAT-OFFWHITE
IFC.REVIGRÉS-Dados de desempenho-Floor Covering - Type: Floor: REVIGRÉS-URBAN-BASE-30X60-NAT-OFFWHITE
IFC.REVIGRÉS-Dados de especificação-Floor Covering - Type: Floor: REVIGRÉS-URBAN-BASE-30X60-NAT-OFFWHITE
IFC.REVIGRÉS-Dados geométricos-Floor Covering - Type: Floor: REVIGRÉS-URBAN-BASE-30X60-NAT-OFFWHITE
IFC.REVIGRÉS-Dados de sustentabilidade-Floor Covering - Type: Floor: REVIGRÉS-URBAN-BASE-30X60-NAT-OFFWHITE

# IfcCovering: Floor:REVIGRÉS-URBAN-BASE-44,35X44,35-RECT HYDRAULIK ANTRACITE, Floor:REVIGRÉS-URBAN-BASE-44,35X44,35-RECT HYDRAULIK ANTRACITE:26943
In: Level 1
Type - PredefinedType: CLADDING; Material: REVIGRÉS-URBAN-BASE-45X45-RECT-HYDRAULIK ANTRACITE 8.5 mm
Type - Pset_CoveringCommon - Reference: 31210752U1; Material: Grés porcelânico
Type - Pset_ElementShading - Roughness: 304.8 mm
Type - Pset_ManufacturerTypeInformation - Manufacturer: REVIGRÉS
Type - Pset_ProductRequirements - Category: Floors
Type - Pset_QuantityTakeOff - Reference: 31210752U1
Type - IFC.REVIGRÉS-Dados do fabricante-Floor Covering - FabricanteURL: https://www.revigres.pt/; ReferenciaModelo: Urban; NumeroGlobalDeItemComercial: 31210752U1; Acabamento: RECT; Material: Grés porcelânico; IdentificadorDoOperadorEconomico: 501840856; UrlFabricanteArtigo: https://www.revigres.pt/colecoes/urban; PaisOrigem: Portugal
Type - IFC.REVIGRÉS-Dados de desempenho-Floor Covering - Rectilinearidade: ± 0.2% máx.± 0.8 mm; Ortogonalidade: ± 0.2% máx.± 1.5 mm; PlanaridadeDaSuperficie: ± 0.3% máx. ± 1.8 mm; QualidadeDaSuperficie: Cumpre; AbsorcaoDeAgua: < 0.05%; ModuloDeRuptura: > 45 N/mm²; ResistenciaAFlexao: > 2000 N; ResistenciaAAbrasaoProfunda: < 120 mm³; DilatacaoTermicaLinear: ≤ 8,0x10-6 °C-1; ResistenciaAoChoqueTermico: Resiste; DurabilidadeResistenciaAoGeloDegelo: Resiste; ResistenciaAoEscorregamentoDIN51130: R9; ResistenciaAoEscorregamentoDIN51097: A; ResistenciaAoEscorregamentoENV51097: A; ResistenciaAoEscorregamentoENV12633: Class 1; ResistenciaAoEscorregamentoANSIA1371: ≥0,42; ResistenciaAoDeslizamentoENV12633: Class 1; ResistenciaAsManchas: Class 5; ResistenciaABaixasConcentracoesDeAcidosEAlcalis: Classe LA; ResistenciaAAltasConcentracoesDeAcidosEAlcalis: Classe HA; LibertacaoDeCadmio: 0; LibertacaoDeChumbo: 0
Type - IFC.REVIGRÉS-Dados de especificação-Floor Covering - VariacaoTonalidade: 2; NivelDeTrafego: 5; EPavimento: Sim; ERevestimento: Sim; EExterno: Sim
Type - IFC.REVIGRÉS-Dados geométricos-Floor Covering - AlturaNominal: 8.5 mm; ComprimentoNominal: 4435 mm; LarguraNominal: 4435 mm
Type - IFC.REVIGRÉS-Dados de sustentabilidade-Floor Covering - EnergiaTermicaExportada: 0; ItemENovo: Sim; ItemEParcialmenteReciclado: 0.29; ItemEReciclado: Sim; VidaÚtilEsperada: 50; SubstanciasPerigosas: Não; PotencialDeEsgotamentoAbioticoDosRecursosFosseis: 203; PotencialDeEsgotamentoAbioticoDosRecursosNaoFosseisMineraisEMetais: 0.000701; PotencialDeAquecimentoGlobalBiogenico: -0.48; CombustiveisFosseisComPotencialDeAquecimentoGlobal: 13.9; PotencialDeAquecimentoGlobalUsoDoSoloEMudancaDeUsoDoSolo: 0.0246; PotencialDeEutrofizacaoFraccaoDeNutrientesQueAtingemOCompartimentoFinalDeAguaDoce: 0.000189; PotencialDeEutrofizacaoFraccaoDeNutrientesQueAtingemOCompartimentoFinalMarinho: 0.0122; EnergiaRecuperada: 0.00739; ConsumoDeAguaDoce: 0.113; UtilizacaoLiquidaDeAguaDoce: 0.113; ResiduosPerigososEliminados: 0.00221; ResiduosNaoPerigososEliminados: 1.83; MassaTotalDeResiduosRadioactivosEliminados: 0.000394; EnergiaElectricaExportada: 1.55; MateriaisParaRecuperacaoDeEnergia: 0.00739; MateriaisParaReciclagem: 0.0253; UnidadeEPD: 1 m²
Type - IFC.REVIGRÉS-Dados gerais-Floor Covering - Nome: REVIGRÉS-URBAN-BASE-44.35X44.35-RECT-HYDRAULIK ANTRACITE; TipoProduto: Prensado a seco: grupo BIa UGL | Grés porcelânico técnico; NumeroDeRegistoDAP: EPD-REV-20240006-CCC1-EN; ReferenciaDAP: -; UrlDOP: -
Classification: C3020 (Uniformat)
Pset_CoveringCommon - TotalThickness: 8.5 mm
IFC.REVIGRÉS-Dados do fabricante-Floor Covering - Type: Floor: REVIGRÉS-URBAN-BASE-44,35X44,35-RECT HYDRAULIK ANTRACITE
IFC.REVIGRÉS-Dados de desempenho-Floor Covering - Type: Floor: REVIGRÉS-URBAN-BASE-44,35X44,35-RECT HYDRAULIK ANTRACITE
IFC.REVIGRÉS-Dados de especificação-Floor Covering - Type: Floor: REVIGRÉS-URBAN-BASE-44,35X44,35-RECT HYDRAULIK ANTRACITE
IFC.REVIGRÉS-Dados geométricos-Floor Covering - Type: Floor: REVIGRÉS-URBAN-BASE-44,35X44,35-RECT HYDRAULIK ANTRACITE
IFC.REVIGRÉS-Dados de sustentabilidade-Floor Covering - Type: Floor: REVIGRÉS-URBAN-BASE-44,35X44,35-RECT HYDRAULIK ANTRACITE

# IfcCovering: Floor:REVIGRÉS-URBAN-BASE-44,35X44,35-RECT HYDRAULIK BONE, Floor:REVIGRÉS-URBAN-BASE-44,35X44,35-RECT HYDRAULIK BONE:26959
In: Level 1
Type - PredefinedType: CLADDING; Material: REVIGRÉS-URBAN-BASE-45X45-RECT-HYDRAULIK BONE 8.5 mm
Type - Pset_CoveringCommon - Reference: 31210754T1; Material: Grés porcelânico
Type - Pset_ElementShading - Roughness: 304.8 mm
Type - Pset_ManufacturerTypeInformation - Manufacturer: REVIGRÉS
Type - Pset_ProductRequirements - Category: Floors
Type - Pset_QuantityTakeOff - Reference: 31210754T1
Type - IFC.REVIGRÉS-Dados do fabricante-Floor Covering - FabricanteURL: https://www.revigres.pt/; ReferenciaModelo: Urban; NumeroGlobalDeItemComercial: 31210754T1; Acabamento: RECT; Material: Grés porcelânico; IdentificadorDoOperadorEconomico: 501840856; UrlFabricanteArtigo: https://www.revigres.pt/colecoes/urban; PaisOrigem: Portugal
Type - IFC.REVIGRÉS-Dados de desempenho-Floor Covering - Rectilinearidade: ± 0.2% máx.± 0.8 mm; Ortogonalidade: ± 0.2% máx.± 1.5 mm; PlanaridadeDaSuperficie: ± 0.3% máx. ± 1.8 mm; QualidadeDaSuperficie: Cumpre; AbsorcaoDeAgua: < 0.05%; ModuloDeRuptura: > 45 N/mm²; ResistenciaAFlexao: > 2000 N; ResistenciaAAbrasaoProfunda: < 120 mm³; DilatacaoTermicaLinear: ≤ 8,0x10-6 °C-1; ResistenciaAoChoqueTermico: Resiste; DurabilidadeResistenciaAoGeloDegelo: Resiste; ResistenciaAoEscorregamentoDIN51130: R9; ResistenciaAoEscorregamentoDIN51097: A; ResistenciaAoEscorregamentoENV51097: A; ResistenciaAoEscorregamentoENV12633: Class 1; ResistenciaAoEscorregamentoANSIA1371: ≥0,42; ResistenciaAoDeslizamentoENV12633: Class 1; ResistenciaAsManchas: Class 5; ResistenciaABaixasConcentracoesDeAcidosEAlcalis: Classe LA; ResistenciaAAltasConcentracoesDeAcidosEAlcalis: Classe HA; LibertacaoDeCadmio: 0; LibertacaoDeChumbo: 0
Type - IFC.REVIGRÉS-Dados de especificação-Floor Covering - VariacaoTonalidade: 2; NivelDeTrafego: 5; EPavimento: Sim; ERevestimento: Sim; EExterno: Sim
Type - IFC.REVIGRÉS-Dados geométricos-Floor Covering - AlturaNominal: 8.5 mm; ComprimentoNominal: 4435 mm; LarguraNominal: 4435 mm
Type - IFC.REVIGRÉS-Dados de sustentabilidade-Floor Covering - EnergiaTermicaExportada: 0; ItemENovo: Sim; ItemEParcialmenteReciclado: 0.03; ItemEReciclado: Sim; VidaÚtilEsperada: 50; SubstanciasPerigosas: Não; PotencialDeEsgotamentoAbioticoDosRecursosFosseis: 203; PotencialDeEsgotamentoAbioticoDosRecursosNaoFosseisMineraisEMetais: 0.000701; PotencialDeAquecimentoGlobalBiogenico: -0.48; CombustiveisFosseisComPotencialDeAquecimentoGlobal: 13.9; PotencialDeAquecimentoGlobalUsoDoSoloEMudancaDeUsoDoSolo: 0.0246; PotencialDeEutrofizacaoFraccaoDeNutrientesQueAtingemOCompartimentoFinalDeAguaDoce: 0.000189; PotencialDeEutrofizacaoFraccaoDeNutrientesQueAtingemOCompartimentoFinalMarinho: 0.0122; EnergiaRecuperada: 0.00739; ConsumoDeAguaDoce: 0.113; UtilizacaoLiquidaDeAguaDoce: 0.113; ResiduosPerigososEliminados: 0.00221; ResiduosNaoPerigososEliminados: 1.83; MassaTotalDeResiduosRadioactivosEliminados: 0.000394; EnergiaElectricaExportada: 1.55; MateriaisParaRecuperacaoDeEnergia: 0.00739; MateriaisParaReciclagem: 0.0253; UnidadeEPD: 1 m²
Type - IFC.REVIGRÉS-Dados gerais-Floor Covering - Nome: REVIGRÉS-URBAN-BASE-44.35X44.35-RECT-HYDRAULIK BONE; TipoProduto: Prensado a seco: grupo BIa UGL | Grés porcelânico técnico; NumeroDeRegistoDAP: EPD-REV-20240006-CCC1-EN; ReferenciaDAP: -; UrlDOP: -
Classification: C3020 (Uniformat)
Pset_CoveringCommon - TotalThickness: 8.5 mm
IFC.REVIGRÉS-Dados do fabricante-Floor Covering - Type: Floor: REVIGRÉS-URBAN-BASE-44,35X44,35-RECT HYDRAULIK BONE
IFC.REVIGRÉS-Dados de desempenho-Floor Covering - Type: Floor: REVIGRÉS-URBAN-BASE-44,35X44,35-RECT HYDRAULIK BONE
IFC.REVIGRÉS-Dados de especificação-Floor Covering - Type: Floor: REVIGRÉS-URBAN-BASE-44,35X44,35-RECT HYDRAULIK BONE
IFC.REVIGRÉS-Dados geométricos-Floor Covering - Type: Floor: REVIGRÉS-URBAN-BASE-44,35X44,35-RECT HYDRAULIK BONE
IFC.REVIGRÉS-Dados de sustentabilidade-Floor Covering - Type: Floor: REVIGRÉS-URBAN-BASE-44,35X44,35-RECT HYDRAULIK BONE

# IfcCovering: Floor:REVIGRÉS-URBAN-BASE-44,35X44,35-RECT HYDRAULIK CRAFT, Floor:REVIGRÉS-URBAN-BASE-44,35X44,35-RECT HYDRAULIK CRAFT:26975
In: Level 1
Type - PredefinedType: CLADDING; Material: REVIGRÉS-URBAN-BASE-45X45-RECT-HYDRAULIK CRAFT 8.5 mm
Type - Pset_CoveringCommon - Reference: 31210755T1; Material: Grés porcelânico
Type - Pset_ElementShading - Roughness: 304.8 mm
Type - Pset_ManufacturerTypeInformation - Manufacturer: REVIGRÉS
Type - Pset_ProductRequirements - Category: Floors
Type - Pset_QuantityTakeOff - Reference: 31210755T1
Type - IFC.REVIGRÉS-Dados do fabricante-Floor Covering - FabricanteURL: https://www.revigres.pt/; ReferenciaModelo: Urban; NumeroGlobalDeItemComercial: 31210755T1; Acabamento: RECT; Material: Grés porcelânico; IdentificadorDoOperadorEconomico: 501840856; UrlFabricanteArtigo: https://www.revigres.pt/colecoes/urban; PaisOrigem: Portugal
Type - IFC.REVIGRÉS-Dados de desempenho-Floor Covering - Rectilinearidade: ± 0.2% máx.± 0.8 mm; Ortogonalidade: ± 0.2% máx.± 1.5 mm; PlanaridadeDaSuperficie: ± 0.3% máx. ± 1.8 mm; QualidadeDaSuperficie: Cumpre; AbsorcaoDeAgua: < 0.05%; ModuloDeRuptura: > 45 N/mm²; ResistenciaAFlexao: > 2000 N; ResistenciaAAbrasaoProfunda: < 120 mm³; DilatacaoTermicaLinear: ≤ 8,0x10-6 °C-1; ResistenciaAoChoqueTermico: Resiste; DurabilidadeResistenciaAoGeloDegelo: Resiste; ResistenciaAoEscorregamentoDIN51130: R9; ResistenciaAoEscorregamentoDIN51097: A; ResistenciaAoEscorregamentoENV51097: A; ResistenciaAoEscorregamentoENV12633: Class 1; ResistenciaAoEscorregamentoANSIA1371: ≥0,42; ResistenciaAoDeslizamentoENV12633: Class 1; ResistenciaAsManchas: Class 5; ResistenciaABaixasConcentracoesDeAcidosEAlcalis: Classe LA; ResistenciaAAltasConcentracoesDeAcidosEAlcalis: Classe HA; LibertacaoDeCadmio: 0; LibertacaoDeChumbo: 0
Type - IFC.REVIGRÉS-Dados de especificação-Floor Covering - VariacaoTonalidade: 2; NivelDeTrafego: 5; EPavimento: Sim; ERevestimento: Sim; EExterno: Sim
Type - IFC.REVIGRÉS-Dados geométricos-Floor Covering - AlturaNominal: 8.5 mm; ComprimentoNominal: 4435 mm; LarguraNominal: 4435 mm
Type - IFC.REVIGRÉS-Dados de sustentabilidade-Floor Covering - EnergiaTermicaExportada: 0; ItemENovo: Sim; ItemEParcialmenteReciclado: 0.19; ItemEReciclado: Sim; VidaÚtilEsperada: 50; SubstanciasPerigosas: Não; PotencialDeEsgotamentoAbioticoDosRecursosFosseis: 203; PotencialDeEsgotamentoAbioticoDosRecursosNaoFosseisMineraisEMetais: 0.000701; PotencialDeAquecimentoGlobalBiogenico: -0.48; CombustiveisFosseisComPotencialDeAquecimentoGlobal: 13.9; PotencialDeAquecimentoGlobalUsoDoSoloEMudancaDeUsoDoSolo: 0.0246; PotencialDeEutrofizacaoFraccaoDeNutrientesQueAtingemOCompartimentoFinalDeAguaDoce: 0.000189; PotencialDeEutrofizacaoFraccaoDeNutrientesQueAtingemOCompartimentoFinalMarinho: 0.0122; EnergiaRecuperada: 0.00739; ConsumoDeAguaDoce: 0.113; UtilizacaoLiquidaDeAguaDoce: 0.113; ResiduosPerigososEliminados: 0.00221; ResiduosNaoPerigososEliminados: 1.83; MassaTotalDeResiduosRadioactivosEliminados: 0.000394; EnergiaElectricaExportada: 1.55; MateriaisParaRecuperacaoDeEnergia: 0.00739; MateriaisParaReciclagem: 0.0253; UnidadeEPD: 1 m²
Type - IFC.REVIGRÉS-Dados gerais-Floor Covering - Nome: REVIGRÉS-URBAN-BASE-44.35X44.35-RECT-HYDRAULIK CRAFT; TipoProduto: Prensado a seco: grupo BIa UGL | Grés porcelânico técnico; NumeroDeRegistoDAP: EPD-REV-20240006-CCC1-EN; ReferenciaDAP: -; UrlDOP: -
Classification: C3020 (Uniformat)
Pset_CoveringCommon - TotalThickness: 8.5 mm
IFC.REVIGRÉS-Dados do fabricante-Floor Covering - Type: Floor: REVIGRÉS-URBAN-BASE-44,35X44,35-RECT HYDRAULIK CRAFT
IFC.REVIGRÉS-Dados de desempenho-Floor Covering - Type: Floor: REVIGRÉS-URBAN-BASE-44,35X44,35-RECT HYDRAULIK CRAFT
IFC.REVIGRÉS-Dados de especificação-Floor Covering - Type: Floor: REVIGRÉS-URBAN-BASE-44,35X44,35-RECT HYDRAULIK CRAFT
IFC.REVIGRÉS-Dados geométricos-Floor Covering - Type: Floor: REVIGRÉS-URBAN-BASE-44,35X44,35-RECT HYDRAULIK CRAFT
IFC.REVIGRÉS-Dados de sustentabilidade-Floor Covering - Type: Floor: REVIGRÉS-URBAN-BASE-44,35X44,35-RECT HYDRAULIK CRAFT

# IfcCovering: Floor:REVIGRÉS-URBAN-BASE-44,35X44,35-RECT HYDRAULIK FOG, Floor:REVIGRÉS-URBAN-BASE-44,35X44,35-RECT HYDRAULIK FOG:27369
In: Level 1
Type - PredefinedType: CLADDING; Material: REVIGRÉS-URBAN-BASE-45X45-RECT-HYDRAULIK FOG 8.5 mm
Type - Pset_CoveringCommon - Reference: 31210756T1; Material: Grés porcelânico
Type - Pset_ElementShading - Roughness: 304.8 mm
Type - Pset_ManufacturerTypeInformation - Manufacturer: REVIGRÉS
Type - Pset_ProductRequirements - Category: Floors
Type - Pset_QuantityTakeOff - Reference: 31210756T1
Type - IFC.REVIGRÉS-Dados do fabricante-Floor Covering - FabricanteURL: https://www.revigres.pt/; ReferenciaModelo: Urban; NumeroGlobalDeItemComercial: 31210756T1; Acabamento: RECT; Material: Grés porcelânico; IdentificadorDoOperadorEconomico: 501840856; UrlFabricanteArtigo: https://www.revigres.pt/colecoes/urban; PaisOrigem: Portugal
Type - IFC.REVIGRÉS-Dados de desempenho-Floor Covering - Rectilinearidade: ± 0.2% máx.± 0.8 mm; Ortogonalidade: ± 0.2% máx.± 1.5 mm; PlanaridadeDaSuperficie: ± 0.3% máx. ± 1.8 mm; QualidadeDaSuperficie: Cumpre; AbsorcaoDeAgua: < 0.05%; ModuloDeRuptura: > 45 N/mm²; ResistenciaAFlexao: > 2000 N; ResistenciaAAbrasaoProfunda: < 120 mm³; DilatacaoTermicaLinear: ≤ 8,0x10-6 °C-1; ResistenciaAoChoqueTermico: Resiste; DurabilidadeResistenciaAoGeloDegelo: Resiste; ResistenciaAoEscorregamentoDIN51130: R9; ResistenciaAoEscorregamentoDIN51097: A; ResistenciaAoEscorregamentoENV51097: A; ResistenciaAoEscorregamentoENV12633: Class 1; ResistenciaAoEscorregamentoANSIA1371: ≥0,42; ResistenciaAoDeslizamentoENV12633: Class 1; ResistenciaAsManchas: Class 5; ResistenciaABaixasConcentracoesDeAcidosEAlcalis: Classe LA; ResistenciaAAltasConcentracoesDeAcidosEAlcalis: Classe HA; LibertacaoDeCadmio: 0; LibertacaoDeChumbo: 0
Type - IFC.REVIGRÉS-Dados de especificação-Floor Covering - VariacaoTonalidade: 2; NivelDeTrafego: 5; EPavimento: Sim; ERevestimento: Sim; EExterno: Sim
Type - IFC.REVIGRÉS-Dados geométricos-Floor Covering - AlturaNominal: 8.5 mm; ComprimentoNominal: 4435 mm; LarguraNominal: 4435 mm
Type - IFC.REVIGRÉS-Dados de sustentabilidade-Floor Covering - EnergiaTermicaExportada: 0; ItemENovo: Sim; ItemEParcialmenteReciclado: 0.23; ItemEReciclado: Sim; VidaÚtilEsperada: 50; SubstanciasPerigosas: Não; PotencialDeEsgotamentoAbioticoDosRecursosFosseis: 203; PotencialDeEsgotamentoAbioticoDosRecursosNaoFosseisMineraisEMetais: 0.000701; PotencialDeAquecimentoGlobalBiogenico: -0.48; CombustiveisFosseisComPotencialDeAquecimentoGlobal: 13.9; PotencialDeAquecimentoGlobalUsoDoSoloEMudancaDeUsoDoSolo: 0.0246; PotencialDeEutrofizacaoFraccaoDeNutrientesQueAtingemOCompartimentoFinalDeAguaDoce: 0.000189; PotencialDeEutrofizacaoFraccaoDeNutrientesQueAtingemOCompartimentoFinalMarinho: 0.0122; EnergiaRecuperada: 0.00739; ConsumoDeAguaDoce: 0.113; UtilizacaoLiquidaDeAguaDoce: 0.113; ResiduosPerigososEliminados: 0.00221; ResiduosNaoPerigososEliminados: 1.83; MassaTotalDeResiduosRadioactivosEliminados: 0.000394; EnergiaElectricaExportada: 1.55; MateriaisParaRecuperacaoDeEnergia: 0.00739; MateriaisParaReciclagem: 0.0253; UnidadeEPD: 1 m²
Type - IFC.REVIGRÉS-Dados gerais-Floor Covering - Nome: REVIGRÉS-URBAN-BASE-44.35X44.35-RECT-HYDRAULIK FOG; TipoProduto: Prensado a seco: grupo BIa UGL | Grés porcelânico técnico; NumeroDeRegistoDAP: EPD-REV-20240006-CCC1-EN; ReferenciaDAP: -; UrlDOP: -
Classification: C3020 (Uniformat)
Pset_CoveringCommon - TotalThickness: 8.5 mm
IFC.REVIGRÉS-Dados do fabricante-Floor Covering - Type: Floor: REVIGRÉS-URBAN-BASE-44,35X44,35-RECT HYDRAULIK FOG
IFC.REVIGRÉS-Dados de desempenho-Floor Covering - Type: Floor: REVIGRÉS-URBAN-BASE-44,35X44,35-RECT HYDRAULIK FOG
IFC.REVIGRÉS-Dados de especificação-Floor Covering - Type: Floor: REVIGRÉS-URBAN-BASE-44,35X44,35-RECT HYDRAULIK FOG
IFC.REVIGRÉS-Dados geométricos-Floor Covering - Type: Floor: REVIGRÉS-URBAN-BASE-44,35X44,35-RECT HYDRAULIK FOG
IFC.REVIGRÉS-Dados de sustentabilidade-Floor Covering - Type: Floor: REVIGRÉS-URBAN-BASE-44,35X44,35-RECT HYDRAULIK FOG

# IfcCovering: Floor:REVIGRÉS-URBAN-BASE-44,35X44,35-RECT HYDRAULIK GRIS, Floor:REVIGRÉS-URBAN-BASE-44,35X44,35-RECT HYDRAULIK GRIS:27385
In: Level 1
Type - PredefinedType: CLADDING; Material: REVIGRÉS-URBAN-BASE-45X45-RECT-HYDRAULIK GRIS 8.5 mm
Type - Pset_CoveringCommon - Reference: 31210757T1; Material: Grés porcelânico
Type - Pset_ElementShading - Roughness: 304.8 mm
Type - Pset_ManufacturerTypeInformation - Manufacturer: REVIGRÉS
Type - Pset_ProductRequirements - Category: Floors
Type - Pset_QuantityTakeOff - Reference: 31210757T1
Type - IFC.REVIGRÉS-Dados do fabricante-Floor Covering - FabricanteURL: https://www.revigres.pt/; ReferenciaModelo: Urban; NumeroGlobalDeItemComercial: 31210757T1; Acabamento: RECT; Material: Grés porcelânico; IdentificadorDoOperadorEconomico: 501840856; UrlFabricanteArtigo: https://www.revigres.pt/colecoes/urban; PaisOrigem: Portugal
Type - IFC.REVIGRÉS-Dados de desempenho-Floor Covering - Rectilinearidade: ± 0.2% máx.± 0.8 mm; Ortogonalidade: ± 0.2% máx.± 1.5 mm; PlanaridadeDaSuperficie: ± 0.3% máx. ± 1.8 mm; QualidadeDaSuperficie: Cumpre; AbsorcaoDeAgua: < 0.05%; ModuloDeRuptura: > 45 N/mm²; ResistenciaAFlexao: > 2000 N; ResistenciaAAbrasaoProfunda: < 120 mm³; DilatacaoTermicaLinear: ≤ 8,0x10-6 °C-1; ResistenciaAoChoqueTermico: Resiste; DurabilidadeResistenciaAoGeloDegelo: Resiste; ResistenciaAoEscorregamentoDIN51130: R9; ResistenciaAoEscorregamentoDIN51097: A; ResistenciaAoEscorregamentoENV51097: A; ResistenciaAoEscorregamentoENV12633: Class 1; ResistenciaAoEscorregamentoANSIA1371: ≥0,42; ResistenciaAoDeslizamentoENV12633: Class 1; ResistenciaAsManchas: Class 5; ResistenciaABaixasConcentracoesDeAcidosEAlcalis: Classe LA; ResistenciaAAltasConcentracoesDeAcidosEAlcalis: Classe HA; LibertacaoDeCadmio: 0; LibertacaoDeChumbo: 0
Type - IFC.REVIGRÉS-Dados de especificação-Floor Covering - VariacaoTonalidade: 2; NivelDeTrafego: 5; EPavimento: Sim; ERevestimento: Sim; EExterno: Sim
Type - IFC.REVIGRÉS-Dados geométricos-Floor Covering - AlturaNominal: 8.5 mm; ComprimentoNominal: 4435 mm; LarguraNominal: 4435 mm
Type - IFC.REVIGRÉS-Dados de sustentabilidade-Floor Covering - EnergiaTermicaExportada: 0; ItemENovo: Sim; ItemEParcialmenteReciclado: 0.23; ItemEReciclado: Sim; VidaÚtilEsperada: 50; SubstanciasPerigosas: Não; PotencialDeEsgotamentoAbioticoDosRecursosFosseis: 203; PotencialDeEsgotamentoAbioticoDosRecursosNaoFosseisMineraisEMetais: 0.000701; PotencialDeAquecimentoGlobalBiogenico: -0.48; CombustiveisFosseisComPotencialDeAquecimentoGlobal: 13.9; PotencialDeAquecimentoGlobalUsoDoSoloEMudancaDeUsoDoSolo: 0.0246; PotencialDeEutrofizacaoFraccaoDeNutrientesQueAtingemOCompartimentoFinalDeAguaDoce: 0.000189; PotencialDeEutrofizacaoFraccaoDeNutrientesQueAtingemOCompartimentoFinalMarinho: 0.0122; EnergiaRecuperada: 0.00739; ConsumoDeAguaDoce: 0.113; UtilizacaoLiquidaDeAguaDoce: 0.113; ResiduosPerigososEliminados: 0.00221; ResiduosNaoPerigososEliminados: 1.83; MassaTotalDeResiduosRadioactivosEliminados: 0.000394; EnergiaElectricaExportada: 1.55; MateriaisParaRecuperacaoDeEnergia: 0.00739; MateriaisParaReciclagem: 0.0253; UnidadeEPD: 1 m²
Type - IFC.REVIGRÉS-Dados gerais-Floor Covering - Nome: REVIGRÉS-URBAN-BASE-44.35X44.35-RECT-HYDRAULIK GRIS; TipoProduto: Prensado a seco: grupo BIa UGL | Grés porcelânico técnico; NumeroDeRegistoDAP: EPD-REV-20240006-CCC1-EN; ReferenciaDAP: -; UrlDOP: -
Classification: C3020 (Uniformat)
Pset_CoveringCommon - TotalThickness: 8.5 mm
IFC.REVIGRÉS-Dados do fabricante-Floor Covering - Type: Floor: REVIGRÉS-URBAN-BASE-44,35X44,35-RECT HYDRAULIK GRIS
IFC.REVIGRÉS-Dados de desempenho-Floor Covering - Type: Floor: REVIGRÉS-URBAN-BASE-44,35X44,35-RECT HYDRAULIK GRIS
IFC.REVIGRÉS-Dados de especificação-Floor Covering - Type: Floor: REVIGRÉS-URBAN-BASE-44,35X44,35-RECT HYDRAULIK GRIS
IFC.REVIGRÉS-Dados geométricos-Floor Covering - Type: Floor: REVIGRÉS-URBAN-BASE-44,35X44,35-RECT HYDRAULIK GRIS
IFC.REVIGRÉS-Dados de sustentabilidade-Floor Covering - Type: Floor: REVIGRÉS-URBAN-BASE-44,35X44,35-RECT HYDRAULIK GRIS

# IfcCovering: Floor:REVIGRÉS-URBAN-BASE-44,35X44,35-RECT HYDRAULIK OFFWHITE, Floor:REVIGRÉS-URBAN-BASE-44,35X44,35-RECT HYDRAULIK OFFWHITE:27401
In: Level 1
Type - PredefinedType: CLADDING; Material: REVIGRÉS-URBAN-BASE-45X45-RECT-HYDRAULIK OFFWHITE 8.5 mm
Type - Pset_CoveringCommon - Reference: 31210758T1; Material: Grés porcelânico
Type - Pset_ElementShading - Roughness: 304.8 mm
Type - Pset_ManufacturerTypeInformation - Manufacturer: REVIGRÉS
Type - Pset_ProductRequirements - Category: Floors
Type - Pset_QuantityTakeOff - Reference: 31210758T1
Type - IFC.REVIGRÉS-Dados do fabricante-Floor Covering - FabricanteURL: https://www.revigres.pt/; ReferenciaModelo: Urban; NumeroGlobalDeItemComercial: 31210758T1; Acabamento: RECT; Material: Grés porcelânico; IdentificadorDoOperadorEconomico: 501840856; UrlFabricanteArtigo: https://www.revigres.pt/colecoes/urban; PaisOrigem: Portugal
Type - IFC.REVIGRÉS-Dados de desempenho-Floor Covering - Rectilinearidade: ± 0.2% máx.± 0.8 mm; Ortogonalidade: ± 0.2% máx.± 1.5 mm; PlanaridadeDaSuperficie: ± 0.3% máx. ± 1.8 mm; QualidadeDaSuperficie: Cumpre; AbsorcaoDeAgua: < 0.05%; ModuloDeRuptura: > 45 N/mm²; ResistenciaAFlexao: > 2000 N; ResistenciaAAbrasaoProfunda: < 120 mm³; DilatacaoTermicaLinear: ≤ 8,0x10-6 °C-1; ResistenciaAoChoqueTermico: Resiste; DurabilidadeResistenciaAoGeloDegelo: Resiste; ResistenciaAoEscorregamentoDIN51130: R9; ResistenciaAoEscorregamentoDIN51097: A; ResistenciaAoEscorregamentoENV51097: A; ResistenciaAoEscorregamentoENV12633: Class 1; ResistenciaAoEscorregamentoANSIA1371: ≥0,42; ResistenciaAoDeslizamentoENV12633: Class 1; ResistenciaAsManchas: Class 5; ResistenciaABaixasConcentracoesDeAcidosEAlcalis: Classe LA; ResistenciaAAltasConcentracoesDeAcidosEAlcalis: Classe HA; LibertacaoDeCadmio: 0; LibertacaoDeChumbo: 0
Type - IFC.REVIGRÉS-Dados de especificação-Floor Covering - VariacaoTonalidade: 2; NivelDeTrafego: 5; EPavimento: Sim; ERevestimento: Sim; EExterno: Sim
Type - IFC.REVIGRÉS-Dados geométricos-Floor Covering - AlturaNominal: 8.5 mm; ComprimentoNominal: 4435 mm; LarguraNominal: 4435 mm
Type - IFC.REVIGRÉS-Dados de sustentabilidade-Floor Covering - EnergiaTermicaExportada: 0; ItemENovo: Sim; ItemEParcialmenteReciclado: 0.03; ItemEReciclado: Sim; VidaÚtilEsperada: 50; SubstanciasPerigosas: Não; PotencialDeEsgotamentoAbioticoDosRecursosFosseis: 203; PotencialDeEsgotamentoAbioticoDosRecursosNaoFosseisMineraisEMetais: 0.000701; PotencialDeAquecimentoGlobalBiogenico: -0.48; CombustiveisFosseisComPotencialDeAquecimentoGlobal: 13.9; PotencialDeAquecimentoGlobalUsoDoSoloEMudancaDeUsoDoSolo: 0.0246; PotencialDeEutrofizacaoFraccaoDeNutrientesQueAtingemOCompartimentoFinalDeAguaDoce: 0.000189; PotencialDeEutrofizacaoFraccaoDeNutrientesQueAtingemOCompartimentoFinalMarinho: 0.0122; EnergiaRecuperada: 0.00739; ConsumoDeAguaDoce: 0.113; UtilizacaoLiquidaDeAguaDoce: 0.113; ResiduosPerigososEliminados: 0.00221; ResiduosNaoPerigososEliminados: 1.83; MassaTotalDeResiduosRadioactivosEliminados: 0.000394; EnergiaElectricaExportada: 1.55; MateriaisParaRecuperacaoDeEnergia: 0.00739; MateriaisParaReciclagem: 0.0253; UnidadeEPD: 1 m²
Type - IFC.REVIGRÉS-Dados gerais-Floor Covering - Nome: REVIGRÉS-URBAN-BASE-44.35X44.35-RECT-HYDRAULIK OFFWHITE; TipoProduto: Prensado a seco: grupo BIa UGL | Grés porcelânico técnico; NumeroDeRegistoDAP: EPD-REV-20240006-CCC1-EN; ReferenciaDAP: -; UrlDOP: -
Classification: C3020 (Uniformat)
Pset_CoveringCommon - TotalThickness: 8.5 mm
IFC.REVIGRÉS-Dados do fabricante-Floor Covering - Type: Floor: REVIGRÉS-URBAN-BASE-44,35X44,35-RECT HYDRAULIK OFFWHITE
IFC.REVIGRÉS-Dados de desempenho-Floor Covering - Type: Floor: REVIGRÉS-URBAN-BASE-44,35X44,35-RECT HYDRAULIK OFFWHITE
IFC.REVIGRÉS-Dados de especificação-Floor Covering - Type: Floor: REVIGRÉS-URBAN-BASE-44,35X44,35-RECT HYDRAULIK OFFWHITE
IFC.REVIGRÉS-Dados geométricos-Floor Covering - Type: Floor: REVIGRÉS-URBAN-BASE-44,35X44,35-RECT HYDRAULIK OFFWHITE
IFC.REVIGRÉS-Dados de sustentabilidade-Floor Covering - Type: Floor: REVIGRÉS-URBAN-BASE-44,35X44,35-RECT HYDRAULIK OFFWHITE
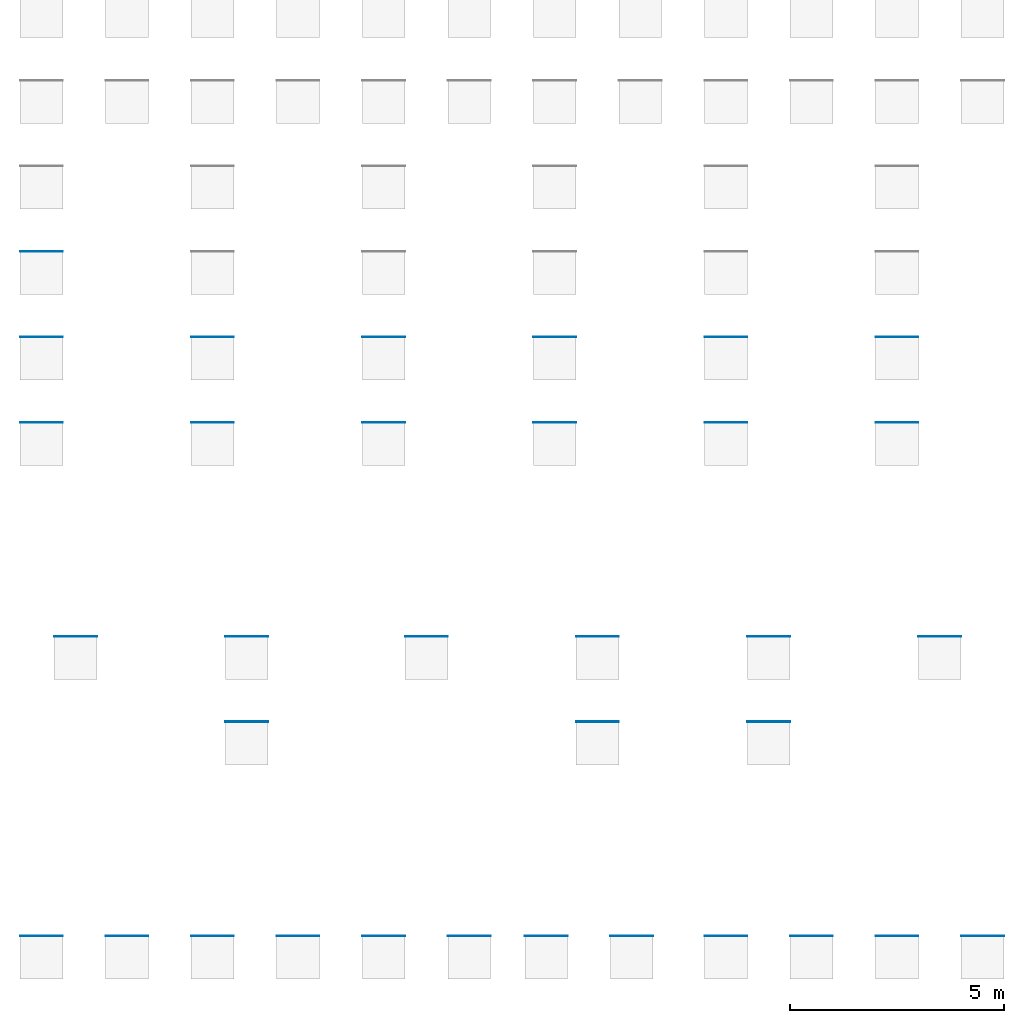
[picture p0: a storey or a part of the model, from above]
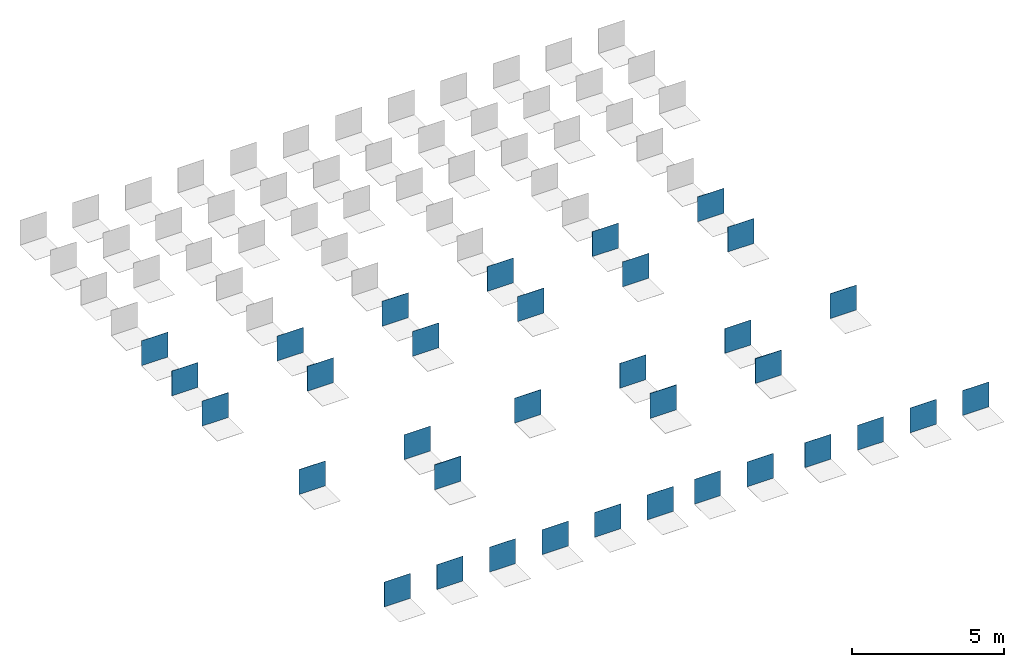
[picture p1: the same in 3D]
Properties of the parts of a building model (IFC2X3), part 3 of 12

# IfcCovering: Floor:REVIGRÉS-URBAN-BASE-44,35X44,35-RECT-ANTRACITE, Floor:REVIGRÉS-URBAN-BASE-44,35X44,35-RECT-ANTRACITE:22702
In: Level 1
Type - PredefinedType: CLADDING; Material: REVIGRÉS-URBAN-BASE-45X45-RECT-ANTRACITE 8.5 mm
Type - Pset_CoveringCommon - Reference: 31210748U1; Material: Grés porcelânico
Type - Pset_ElementShading - Roughness: 304.8 mm
Type - Pset_ManufacturerTypeInformation - Manufacturer: REVIGRÉS
Type - Pset_ProductRequirements - Category: Floors
Type - Pset_QuantityTakeOff - Reference: 31210748U1
Type - IFC.REVIGRÉS-Dados do fabricante-Floor Covering - FabricanteURL: https://www.revigres.pt/; ReferenciaModelo: Urban; NumeroGlobalDeItemComercial: 31210748U1; Acabamento: RECT; Material: Grés porcelânico; IdentificadorDoOperadorEconomico: 501840856; UrlFabricanteArtigo: https://www.revigres.pt/colecoes/urban; PaisOrigem: Portugal
Type - IFC.REVIGRÉS-Dados de desempenho-Floor Covering - Rectilinearidade: ± 0.2% máx.± 0.8 mm; Ortogonalidade: ± 0.2% máx.± 1.5 mm; PlanaridadeDaSuperficie: ± 0.3% máx. ± 1.8 mm; QualidadeDaSuperficie: Cumpre; AbsorcaoDeAgua: < 0.05%; ModuloDeRuptura: > 45 N/mm²; ResistenciaAFlexao: > 2000 N; ResistenciaAAbrasaoProfunda: < 120 mm³; DilatacaoTermicaLinear: ≤ 8,0x10-6 °C-1; ResistenciaAoChoqueTermico: Resiste; DurabilidadeResistenciaAoGeloDegelo: Resiste; ResistenciaAoEscorregamentoDIN51130: R9; ResistenciaAoEscorregamentoDIN51097: A; ResistenciaAoEscorregamentoENV51097: A; ResistenciaAoEscorregamentoENV12633: Class 1; ResistenciaAoEscorregamentoANSIA1371: ≥0,42; ResistenciaAoDeslizamentoENV12633: Class 1; ResistenciaAsManchas: Class 5; ResistenciaABaixasConcentracoesDeAcidosEAlcalis: Classe LA; ResistenciaAAltasConcentracoesDeAcidosEAlcalis: Classe HA; LibertacaoDeCadmio: 0; LibertacaoDeChumbo: 0
Type - IFC.REVIGRÉS-Dados de especificação-Floor Covering - VariacaoTonalidade: 2; NivelDeTrafego: 5; EPavimento: Sim; ERevestimento: Sim; EExterno: Sim
Type - IFC.REVIGRÉS-Dados geométricos-Floor Covering - AlturaNominal: 8.5 mm; ComprimentoNominal: 4435 mm; LarguraNominal: 4435 mm
Type - IFC.REVIGRÉS-Dados de sustentabilidade-Floor Covering - EnergiaTermicaExportada: 0; ItemENovo: Sim; ItemEParcialmenteReciclado: 0.29; ItemEReciclado: Sim; VidaÚtilEsperada: 50; SubstanciasPerigosas: Não; PotencialDeEsgotamentoAbioticoDosRecursosFosseis: 203; PotencialDeEsgotamentoAbioticoDosRecursosNaoFosseisMineraisEMetais: 0.000701; PotencialDeAquecimentoGlobalBiogenico: -0.48; CombustiveisFosseisComPotencialDeAquecimentoGlobal: 13.9; PotencialDeAquecimentoGlobalUsoDoSoloEMudancaDeUsoDoSolo: 0.0246; PotencialDeEutrofizacaoFraccaoDeNutrientesQueAtingemOCompartimentoFinalDeAguaDoce: 0.000189; PotencialDeEutrofizacaoFraccaoDeNutrientesQueAtingemOCompartimentoFinalMarinho: 0.0122; EnergiaRecuperada: 0.00739; ConsumoDeAguaDoce: 0.113; UtilizacaoLiquidaDeAguaDoce: 0.113; ResiduosPerigososEliminados: 0.00221; ResiduosNaoPerigososEliminados: 1.83; MassaTotalDeResiduosRadioactivosEliminados: 0.000394; EnergiaElectricaExportada: 1.55; MateriaisParaRecuperacaoDeEnergia: 0.00739; MateriaisParaReciclagem: 0.0253; UnidadeEPD: 1 m²
Type - IFC.REVIGRÉS-Dados gerais-Floor Covering - Nome: REVIGRÉS-URBAN-BASE-44.35X44.35-RECT-URBAN ANTRACITE; TipoProduto: Prensado a seco: grupo BIa UGL | Grés porcelânico técnico; NumeroDeRegistoDAP: EPD-REV-20240006-CCC1-EN; ReferenciaDAP: -; UrlDOP: -
Classification: C3020 (Uniformat)
Pset_CoveringCommon - TotalThickness: 8.5 mm
IFC.REVIGRÉS-Dados do fabricante-Floor Covering - Type: Floor: REVIGRÉS-URBAN-BASE-44,35X44,35-RECT-ANTRACITE
IFC.REVIGRÉS-Dados de desempenho-Floor Covering - Type: Floor: REVIGRÉS-URBAN-BASE-44,35X44,35-RECT-ANTRACITE
IFC.REVIGRÉS-Dados de especificação-Floor Covering - Type: Floor: REVIGRÉS-URBAN-BASE-44,35X44,35-RECT-ANTRACITE
IFC.REVIGRÉS-Dados geométricos-Floor Covering - Type: Floor: REVIGRÉS-URBAN-BASE-44,35X44,35-RECT-ANTRACITE
IFC.REVIGRÉS-Dados de sustentabilidade-Floor Covering - Type: Floor: REVIGRÉS-URBAN-BASE-44,35X44,35-RECT-ANTRACITE

# IfcCovering: Floor:REVIGRÉS-URBAN-BASE-44,35X44,35-RECT-BONE, Floor:REVIGRÉS-URBAN-BASE-44,35X44,35-RECT-BONE:22718
In: Level 1
Type - PredefinedType: CLADDING; Material: REVIGRÉS-URBAN-BASE-45X45-RECT-BONE 8.5 mm
Type - Pset_CoveringCommon - Reference: 31210720T1; Material: Grés porcelânico
Type - Pset_ElementShading - Roughness: 304.8 mm
Type - Pset_ManufacturerTypeInformation - Manufacturer: REVIGRÉS
Type - Pset_ProductRequirements - Category: Floors
Type - Pset_QuantityTakeOff - Reference: 31210720T1
Type - IFC.REVIGRÉS-Dados do fabricante-Floor Covering - FabricanteURL: https://www.revigres.pt/; ReferenciaModelo: Urban; NumeroGlobalDeItemComercial: 31210720T1; Acabamento: RECT; Material: Grés porcelânico; IdentificadorDoOperadorEconomico: 501840856; UrlFabricanteArtigo: https://www.revigres.pt/colecoes/urban; PaisOrigem: Portugal
Type - IFC.REVIGRÉS-Dados de desempenho-Floor Covering - Rectilinearidade: ± 0.2% máx.± 0.8 mm; Ortogonalidade: ± 0.2% máx.± 1.5 mm; PlanaridadeDaSuperficie: ± 0.3% máx. ± 1.8 mm; QualidadeDaSuperficie: Cumpre; AbsorcaoDeAgua: < 0.05%; ModuloDeRuptura: > 45 N/mm²; ResistenciaAFlexao: > 2000 N; ResistenciaAAbrasaoProfunda: < 120 mm³; DilatacaoTermicaLinear: ≤ 8,0x10-6 °C-1; ResistenciaAoChoqueTermico: Resiste; DurabilidadeResistenciaAoGeloDegelo: Resiste; ResistenciaAoEscorregamentoDIN51130: R9; ResistenciaAoEscorregamentoDIN51097: A; ResistenciaAoEscorregamentoENV51097: A; ResistenciaAoEscorregamentoENV12633: Class 1; ResistenciaAoEscorregamentoANSIA1371: ≥0,42; ResistenciaAoDeslizamentoENV12633: Class 1; ResistenciaAsManchas: Class 5; ResistenciaABaixasConcentracoesDeAcidosEAlcalis: Classe LA; ResistenciaAAltasConcentracoesDeAcidosEAlcalis: Classe HA; LibertacaoDeCadmio: 0; LibertacaoDeChumbo: 0
Type - IFC.REVIGRÉS-Dados de especificação-Floor Covering - VariacaoTonalidade: 2; NivelDeTrafego: 5; EPavimento: Sim; ERevestimento: Sim; EExterno: Sim
Type - IFC.REVIGRÉS-Dados geométricos-Floor Covering - AlturaNominal: 8.5 mm; ComprimentoNominal: 4435 mm; LarguraNominal: 4435 mm
Type - IFC.REVIGRÉS-Dados de sustentabilidade-Floor Covering - EnergiaTermicaExportada: 0; ItemENovo: Sim; ItemEParcialmenteReciclado: 0.03; ItemEReciclado: Sim; VidaÚtilEsperada: 50; SubstanciasPerigosas: Não; PotencialDeEsgotamentoAbioticoDosRecursosFosseis: 203; PotencialDeEsgotamentoAbioticoDosRecursosNaoFosseisMineraisEMetais: 0.000701; PotencialDeAquecimentoGlobalBiogenico: -0.48; CombustiveisFosseisComPotencialDeAquecimentoGlobal: 13.9; PotencialDeAquecimentoGlobalUsoDoSoloEMudancaDeUsoDoSolo: 0.0246; PotencialDeEutrofizacaoFraccaoDeNutrientesQueAtingemOCompartimentoFinalDeAguaDoce: 0.000189; PotencialDeEutrofizacaoFraccaoDeNutrientesQueAtingemOCompartimentoFinalMarinho: 0.0122; EnergiaRecuperada: 0.00739; ConsumoDeAguaDoce: 0.113; UtilizacaoLiquidaDeAguaDoce: 0.113; ResiduosPerigososEliminados: 0.00221; ResiduosNaoPerigososEliminados: 1.83; MassaTotalDeResiduosRadioactivosEliminados: 0.000394; EnergiaElectricaExportada: 1.55; MateriaisParaRecuperacaoDeEnergia: 0.00739; MateriaisParaReciclagem: 0.0253; UnidadeEPD: 1 m²
Type - IFC.REVIGRÉS-Dados gerais-Floor Covering - Nome: REVIGRÉS-URBAN-BASE-44.35X44.35-RECT-URBAN BONE; TipoProduto: Prensado a seco: grupo BIa UGL | Grés porcelânico técnico; NumeroDeRegistoDAP: EPD-REV-20240006-CCC1-EN; ReferenciaDAP: -; UrlDOP: -
Classification: C3020 (Uniformat)
Pset_CoveringCommon - TotalThickness: 8.5 mm
IFC.REVIGRÉS-Dados do fabricante-Floor Covering - Type: Floor: REVIGRÉS-URBAN-BASE-44,35X44,35-RECT-BONE
IFC.REVIGRÉS-Dados de desempenho-Floor Covering - Type: Floor: REVIGRÉS-URBAN-BASE-44,35X44,35-RECT-BONE
IFC.REVIGRÉS-Dados de especificação-Floor Covering - Type: Floor: REVIGRÉS-URBAN-BASE-44,35X44,35-RECT-BONE
IFC.REVIGRÉS-Dados geométricos-Floor Covering - Type: Floor: REVIGRÉS-URBAN-BASE-44,35X44,35-RECT-BONE
IFC.REVIGRÉS-Dados de sustentabilidade-Floor Covering - Type: Floor: REVIGRÉS-URBAN-BASE-44,35X44,35-RECT-BONE

# IfcCovering: Floor:REVIGRÉS-URBAN-BASE-44,35X44,35-RECT-CRAFT, Floor:REVIGRÉS-URBAN-BASE-44,35X44,35-RECT-CRAFT:22734
In: Level 1
Type - PredefinedType: CLADDING; Material: REVIGRÉS-URBAN-BASE-45X45-RECT-CRAFT 8.5 mm
Type - Pset_CoveringCommon - Reference: 31210724T1; Material: Grés porcelânico
Type - Pset_ElementShading - Roughness: 304.8 mm
Type - Pset_ManufacturerTypeInformation - Manufacturer: REVIGRÉS
Type - Pset_ProductRequirements - Category: Floors
Type - Pset_QuantityTakeOff - Reference: 31210724T1
Type - IFC.REVIGRÉS-Dados do fabricante-Floor Covering - FabricanteURL: https://www.revigres.pt/; ReferenciaModelo: Urban; NumeroGlobalDeItemComercial: 31210724T1; Acabamento: RECT; Material: Grés porcelânico; IdentificadorDoOperadorEconomico: 501840856; UrlFabricanteArtigo: https://www.revigres.pt/colecoes/urban; PaisOrigem: Portugal
Type - IFC.REVIGRÉS-Dados de desempenho-Floor Covering - Rectilinearidade: ± 0.2% máx.± 0.8 mm; Ortogonalidade: ± 0.2% máx.± 1.5 mm; PlanaridadeDaSuperficie: ± 0.3% máx. ± 1.8 mm; QualidadeDaSuperficie: Cumpre; AbsorcaoDeAgua: < 0.05%; ModuloDeRuptura: > 45 N/mm²; ResistenciaAFlexao: > 2000 N; ResistenciaAAbrasaoProfunda: < 120 mm³; DilatacaoTermicaLinear: ≤ 8,0x10-6 °C-1; ResistenciaAoChoqueTermico: Resiste; DurabilidadeResistenciaAoGeloDegelo: Resiste; ResistenciaAoEscorregamentoDIN51130: R9; ResistenciaAoEscorregamentoDIN51097: A; ResistenciaAoEscorregamentoENV51097: A; ResistenciaAoEscorregamentoENV12633: Class 1; ResistenciaAoEscorregamentoANSIA1371: ≥0,42; ResistenciaAoDeslizamentoENV12633: Class 1; ResistenciaAsManchas: Class 5; ResistenciaABaixasConcentracoesDeAcidosEAlcalis: Classe LA; ResistenciaAAltasConcentracoesDeAcidosEAlcalis: Classe HA; LibertacaoDeCadmio: 0; LibertacaoDeChumbo: 0
Type - IFC.REVIGRÉS-Dados de especificação-Floor Covering - VariacaoTonalidade: 2; NivelDeTrafego: 5; EPavimento: Sim; ERevestimento: Sim; EExterno: Sim
Type - IFC.REVIGRÉS-Dados geométricos-Floor Covering - AlturaNominal: 8.5 mm; ComprimentoNominal: 4435 mm; LarguraNominal: 4435 mm
Type - IFC.REVIGRÉS-Dados de sustentabilidade-Floor Covering - EnergiaTermicaExportada: 0; ItemENovo: Sim; ItemEParcialmenteReciclado: 0.19; ItemEReciclado: Sim; VidaÚtilEsperada: 50; SubstanciasPerigosas: Não; PotencialDeEsgotamentoAbioticoDosRecursosFosseis: 203; PotencialDeEsgotamentoAbioticoDosRecursosNaoFosseisMineraisEMetais: 0.000701; PotencialDeAquecimentoGlobalBiogenico: -0.48; CombustiveisFosseisComPotencialDeAquecimentoGlobal: 13.9; PotencialDeAquecimentoGlobalUsoDoSoloEMudancaDeUsoDoSolo: 0.0246; PotencialDeEutrofizacaoFraccaoDeNutrientesQueAtingemOCompartimentoFinalDeAguaDoce: 0.000189; PotencialDeEutrofizacaoFraccaoDeNutrientesQueAtingemOCompartimentoFinalMarinho: 0.0122; EnergiaRecuperada: 0.00739; ConsumoDeAguaDoce: 0.113; UtilizacaoLiquidaDeAguaDoce: 0.113; ResiduosPerigososEliminados: 0.00221; ResiduosNaoPerigososEliminados: 1.83; MassaTotalDeResiduosRadioactivosEliminados: 0.000394; EnergiaElectricaExportada: 1.55; MateriaisParaRecuperacaoDeEnergia: 0.00739; MateriaisParaReciclagem: 0.0253; UnidadeEPD: 1 m²
Type - IFC.REVIGRÉS-Dados gerais-Floor Covering - Nome: REVIGRÉS-URBAN-BASE-44.35X44.35-RECT-URBAN CRAFT; TipoProduto: Prensado a seco: grupo BIa UGL | Grés porcelânico técnico; NumeroDeRegistoDAP: EPD-REV-20240006-CCC1-EN; ReferenciaDAP: -; UrlDOP: -
Classification: C3020 (Uniformat)
Pset_CoveringCommon - TotalThickness: 8.5 mm
IFC.REVIGRÉS-Dados do fabricante-Floor Covering - Type: Floor: REVIGRÉS-URBAN-BASE-44,35X44,35-RECT-CRAFT
IFC.REVIGRÉS-Dados de desempenho-Floor Covering - Type: Floor: REVIGRÉS-URBAN-BASE-44,35X44,35-RECT-CRAFT
IFC.REVIGRÉS-Dados de especificação-Floor Covering - Type: Floor: REVIGRÉS-URBAN-BASE-44,35X44,35-RECT-CRAFT
IFC.REVIGRÉS-Dados geométricos-Floor Covering - Type: Floor: REVIGRÉS-URBAN-BASE-44,35X44,35-RECT-CRAFT
IFC.REVIGRÉS-Dados de sustentabilidade-Floor Covering - Type: Floor: REVIGRÉS-URBAN-BASE-44,35X44,35-RECT-CRAFT

# IfcCovering: Floor:REVIGRÉS-URBAN-BASE-44,35X44,35-RECT-FOG, Floor:REVIGRÉS-URBAN-BASE-44,35X44,35-RECT-FOG:22750
In: Level 1
Type - PredefinedType: CLADDING; Material: REVIGRÉS-URBAN-BASE-45X45-RECT-FOG 8.5 mm
Type - Pset_CoveringCommon - Reference: 31210721T1; Material: Grés porcelânico
Type - Pset_ElementShading - Roughness: 304.8 mm
Type - Pset_ManufacturerTypeInformation - Manufacturer: REVIGRÉS
Type - Pset_ProductRequirements - Category: Floors
Type - Pset_QuantityTakeOff - Reference: 31210721T1
Type - IFC.REVIGRÉS-Dados do fabricante-Floor Covering - FabricanteURL: https://www.revigres.pt/; ReferenciaModelo: Urban; NumeroGlobalDeItemComercial: 31210721T1; Acabamento: RECT; Material: Grés porcelânico; IdentificadorDoOperadorEconomico: 501840856; UrlFabricanteArtigo: https://www.revigres.pt/colecoes/urban; PaisOrigem: Portugal
Type - IFC.REVIGRÉS-Dados de desempenho-Floor Covering - Rectilinearidade: ± 0.2% máx.± 0.8 mm; Ortogonalidade: ± 0.2% máx.± 1.5 mm; PlanaridadeDaSuperficie: ± 0.3% máx. ± 1.8 mm; QualidadeDaSuperficie: Cumpre; AbsorcaoDeAgua: < 0.05%; ModuloDeRuptura: > 45 N/mm²; ResistenciaAFlexao: > 2000 N; ResistenciaAAbrasaoProfunda: < 120 mm³; DilatacaoTermicaLinear: ≤ 8,0x10-6 °C-1; ResistenciaAoChoqueTermico: Resiste; DurabilidadeResistenciaAoGeloDegelo: Resiste; ResistenciaAoEscorregamentoDIN51130: R9; ResistenciaAoEscorregamentoDIN51097: A; ResistenciaAoEscorregamentoENV51097: A; ResistenciaAoEscorregamentoENV12633: Class 1; ResistenciaAoEscorregamentoANSIA1371: ≥0,42; ResistenciaAoDeslizamentoENV12633: Class 1; ResistenciaAsManchas: Class 5; ResistenciaABaixasConcentracoesDeAcidosEAlcalis: Classe LA; ResistenciaAAltasConcentracoesDeAcidosEAlcalis: Classe HA; LibertacaoDeCadmio: 0; LibertacaoDeChumbo: 0
Type - IFC.REVIGRÉS-Dados de especificação-Floor Covering - VariacaoTonalidade: 2; NivelDeTrafego: 5; EPavimento: Sim; ERevestimento: Sim; EExterno: Sim
Type - IFC.REVIGRÉS-Dados geométricos-Floor Covering - AlturaNominal: 8.5 mm; ComprimentoNominal: 4435 mm; LarguraNominal: 4435 mm
Type - IFC.REVIGRÉS-Dados de sustentabilidade-Floor Covering - EnergiaTermicaExportada: 0; ItemENovo: Sim; ItemEParcialmenteReciclado: 0.23; ItemEReciclado: Sim; VidaÚtilEsperada: 50; SubstanciasPerigosas: Não; PotencialDeEsgotamentoAbioticoDosRecursosFosseis: 203; PotencialDeEsgotamentoAbioticoDosRecursosNaoFosseisMineraisEMetais: 0.000701; PotencialDeAquecimentoGlobalBiogenico: -0.48; CombustiveisFosseisComPotencialDeAquecimentoGlobal: 13.9; PotencialDeAquecimentoGlobalUsoDoSoloEMudancaDeUsoDoSolo: 0.0246; PotencialDeEutrofizacaoFraccaoDeNutrientesQueAtingemOCompartimentoFinalDeAguaDoce: 0.000189; PotencialDeEutrofizacaoFraccaoDeNutrientesQueAtingemOCompartimentoFinalMarinho: 0.0122; EnergiaRecuperada: 0.00739; ConsumoDeAguaDoce: 0.113; UtilizacaoLiquidaDeAguaDoce: 0.113; ResiduosPerigososEliminados: 0.00221; ResiduosNaoPerigososEliminados: 1.83; MassaTotalDeResiduosRadioactivosEliminados: 0.000394; EnergiaElectricaExportada: 1.55; MateriaisParaRecuperacaoDeEnergia: 0.00739; MateriaisParaReciclagem: 0.0253; UnidadeEPD: 1 m²
Type - IFC.REVIGRÉS-Dados gerais-Floor Covering - Nome: REVIGRÉS-URBAN-BASE-44.35X44.35-RECT-URBAN FOG; TipoProduto: Prensado a seco: grupo BIa UGL | Grés porcelânico técnico; NumeroDeRegistoDAP: EPD-REV-20240006-CCC1-EN; ReferenciaDAP: -; UrlDOP: -
Classification: C3020 (Uniformat)
Pset_CoveringCommon - TotalThickness: 8.5 mm
IFC.REVIGRÉS-Dados do fabricante-Floor Covering - Type: Floor: REVIGRÉS-URBAN-BASE-44,35X44,35-RECT-FOG
IFC.REVIGRÉS-Dados de desempenho-Floor Covering - Type: Floor: REVIGRÉS-URBAN-BASE-44,35X44,35-RECT-FOG
IFC.REVIGRÉS-Dados de especificação-Floor Covering - Type: Floor: REVIGRÉS-URBAN-BASE-44,35X44,35-RECT-FOG
IFC.REVIGRÉS-Dados geométricos-Floor Covering - Type: Floor: REVIGRÉS-URBAN-BASE-44,35X44,35-RECT-FOG
IFC.REVIGRÉS-Dados de sustentabilidade-Floor Covering - Type: Floor: REVIGRÉS-URBAN-BASE-44,35X44,35-RECT-FOG

# IfcCovering: Floor:REVIGRÉS-URBAN-BASE-44,35X44,35-RECT-GRIS, Floor:REVIGRÉS-URBAN-BASE-44,35X44,35-RECT-GRIS:22766
In: Level 1
Type - PredefinedType: CLADDING; Material: REVIGRÉS-URBAN-BASE-45X45-RECT-GRIS 8.5 mm
Type - Pset_CoveringCommon - Reference: 31210722T1; Material: Grés porcelânico
Type - Pset_ElementShading - Roughness: 304.8 mm
Type - Pset_ManufacturerTypeInformation - Manufacturer: REVIGRÉS
Type - Pset_ProductRequirements - Category: Floors
Type - Pset_QuantityTakeOff - Reference: 31210722T1
Type - IFC.REVIGRÉS-Dados do fabricante-Floor Covering - FabricanteURL: https://www.revigres.pt/; ReferenciaModelo: Urban; NumeroGlobalDeItemComercial: 31210722T1; Acabamento: RECT; Material: Grés porcelânico; IdentificadorDoOperadorEconomico: 501840856; UrlFabricanteArtigo: https://www.revigres.pt/colecoes/urban; PaisOrigem: Portugal
Type - IFC.REVIGRÉS-Dados de desempenho-Floor Covering - Rectilinearidade: ± 0.2% máx.± 0.8 mm; Ortogonalidade: ± 0.2% máx.± 1.5 mm; PlanaridadeDaSuperficie: ± 0.3% máx. ± 1.8 mm; QualidadeDaSuperficie: Cumpre; AbsorcaoDeAgua: < 0.05%; ModuloDeRuptura: > 45 N/mm²; ResistenciaAFlexao: > 2000 N; ResistenciaAAbrasaoProfunda: < 120 mm³; DilatacaoTermicaLinear: ≤ 8,0x10-6 °C-1; ResistenciaAoChoqueTermico: Resiste; DurabilidadeResistenciaAoGeloDegelo: Resiste; ResistenciaAoEscorregamentoDIN51130: R9; ResistenciaAoEscorregamentoDIN51097: A; ResistenciaAoEscorregamentoENV51097: A; ResistenciaAoEscorregamentoENV12633: Class 1; ResistenciaAoEscorregamentoANSIA1371: ≥0,42; ResistenciaAoDeslizamentoENV12633: Class 1; ResistenciaAsManchas: Class 5; ResistenciaABaixasConcentracoesDeAcidosEAlcalis: Classe LA; ResistenciaAAltasConcentracoesDeAcidosEAlcalis: Classe HA; LibertacaoDeCadmio: 0; LibertacaoDeChumbo: 0
Type - IFC.REVIGRÉS-Dados de especificação-Floor Covering - VariacaoTonalidade: 2; NivelDeTrafego: 5; EPavimento: Sim; ERevestimento: Sim; EExterno: Sim
Type - IFC.REVIGRÉS-Dados geométricos-Floor Covering - AlturaNominal: 8.5 mm; ComprimentoNominal: 4435 mm; LarguraNominal: 4435 mm
Type - IFC.REVIGRÉS-Dados de sustentabilidade-Floor Covering - EnergiaTermicaExportada: 0; ItemENovo: Sim; ItemEParcialmenteReciclado: 0.23; ItemEReciclado: Sim; VidaÚtilEsperada: 50; SubstanciasPerigosas: Não; PotencialDeEsgotamentoAbioticoDosRecursosFosseis: 203; PotencialDeEsgotamentoAbioticoDosRecursosNaoFosseisMineraisEMetais: 0.000701; PotencialDeAquecimentoGlobalBiogenico: -0.48; CombustiveisFosseisComPotencialDeAquecimentoGlobal: 13.9; PotencialDeAquecimentoGlobalUsoDoSoloEMudancaDeUsoDoSolo: 0.0246; PotencialDeEutrofizacaoFraccaoDeNutrientesQueAtingemOCompartimentoFinalDeAguaDoce: 0.000189; PotencialDeEutrofizacaoFraccaoDeNutrientesQueAtingemOCompartimentoFinalMarinho: 0.0122; EnergiaRecuperada: 0.00739; ConsumoDeAguaDoce: 0.113; UtilizacaoLiquidaDeAguaDoce: 0.113; ResiduosPerigososEliminados: 0.00221; ResiduosNaoPerigososEliminados: 1.83; MassaTotalDeResiduosRadioactivosEliminados: 0.000394; EnergiaElectricaExportada: 1.55; MateriaisParaRecuperacaoDeEnergia: 0.00739; MateriaisParaReciclagem: 0.0253; UnidadeEPD: 1 m²
Type - IFC.REVIGRÉS-Dados gerais-Floor Covering - Nome: REVIGRÉS-URBAN-BASE-44.35X44.35-RECT-URBAN GRIS; TipoProduto: Prensado a seco: grupo BIa UGL | Grés porcelânico técnico; NumeroDeRegistoDAP: EPD-REV-20240006-CCC1-EN; ReferenciaDAP: -; UrlDOP: -
Classification: C3020 (Uniformat)
Pset_CoveringCommon - TotalThickness: 8.5 mm
IFC.REVIGRÉS-Dados do fabricante-Floor Covering - Type: Floor: REVIGRÉS-URBAN-BASE-44,35X44,35-RECT-GRIS
IFC.REVIGRÉS-Dados de desempenho-Floor Covering - Type: Floor: REVIGRÉS-URBAN-BASE-44,35X44,35-RECT-GRIS
IFC.REVIGRÉS-Dados de especificação-Floor Covering - Type: Floor: REVIGRÉS-URBAN-BASE-44,35X44,35-RECT-GRIS
IFC.REVIGRÉS-Dados geométricos-Floor Covering - Type: Floor: REVIGRÉS-URBAN-BASE-44,35X44,35-RECT-GRIS
IFC.REVIGRÉS-Dados de sustentabilidade-Floor Covering - Type: Floor: REVIGRÉS-URBAN-BASE-44,35X44,35-RECT-GRIS

# IfcCovering: Floor:REVIGRÉS-URBAN-BASE-44,35X44,35-RECT-OFFWHITE, Floor:REVIGRÉS-URBAN-BASE-44,35X44,35-RECT-OFFWHITE:22782
In: Level 1
Type - PredefinedType: CLADDING; Material: REVIGRÉS-URBAN-BASE-45X45-RECT-OFFWHITE 8.5 mm
Type - Pset_CoveringCommon - Reference: 31210723T1; Material: Grés porcelânico
Type - Pset_ElementShading - Roughness: 304.8 mm
Type - Pset_ManufacturerTypeInformation - Manufacturer: REVIGRÉS
Type - Pset_ProductRequirements - Category: Floors
Type - Pset_QuantityTakeOff - Reference: 31210723T1
Type - IFC.REVIGRÉS-Dados do fabricante-Floor Covering - FabricanteURL: https://www.revigres.pt/; ReferenciaModelo: Urban; NumeroGlobalDeItemComercial: 31210723T1; Acabamento: RECT; Material: Grés porcelânico; IdentificadorDoOperadorEconomico: 501840856; UrlFabricanteArtigo: https://www.revigres.pt/colecoes/urban; PaisOrigem: Portugal
Type - IFC.REVIGRÉS-Dados de desempenho-Floor Covering - Rectilinearidade: ± 0.2% máx.± 0.8 mm; Ortogonalidade: ± 0.2% máx.± 1.5 mm; PlanaridadeDaSuperficie: ± 0.3% máx. ± 1.8 mm; QualidadeDaSuperficie: Cumpre; AbsorcaoDeAgua: < 0.05%; ModuloDeRuptura: > 45 N/mm²; ResistenciaAFlexao: > 2000 N; ResistenciaAAbrasaoProfunda: < 120 mm³; DilatacaoTermicaLinear: ≤ 8,0x10-6 °C-1; ResistenciaAoChoqueTermico: Resiste; DurabilidadeResistenciaAoGeloDegelo: Resiste; ResistenciaAoEscorregamentoDIN51130: R9; ResistenciaAoEscorregamentoDIN51097: A; ResistenciaAoEscorregamentoENV51097: A; ResistenciaAoEscorregamentoENV12633: Class 1; ResistenciaAoEscorregamentoANSIA1371: ≥0,42; ResistenciaAoDeslizamentoENV12633: Class 1; ResistenciaAsManchas: Class 5; ResistenciaABaixasConcentracoesDeAcidosEAlcalis: Classe LA; ResistenciaAAltasConcentracoesDeAcidosEAlcalis: Classe HA; LibertacaoDeCadmio: 0; LibertacaoDeChumbo: 0
Type - IFC.REVIGRÉS-Dados de especificação-Floor Covering - VariacaoTonalidade: 2; NivelDeTrafego: 5; EPavimento: Sim; ERevestimento: Sim; EExterno: Sim
Type - IFC.REVIGRÉS-Dados geométricos-Floor Covering - AlturaNominal: 8.5 mm; ComprimentoNominal: 4435 mm; LarguraNominal: 4435 mm
Type - IFC.REVIGRÉS-Dados de sustentabilidade-Floor Covering - EnergiaTermicaExportada: 0; ItemENovo: Sim; ItemEParcialmenteReciclado: 0.03; ItemEReciclado: Sim; VidaÚtilEsperada: 50; SubstanciasPerigosas: Não; PotencialDeEsgotamentoAbioticoDosRecursosFosseis: 203; PotencialDeEsgotamentoAbioticoDosRecursosNaoFosseisMineraisEMetais: 0.000701; PotencialDeAquecimentoGlobalBiogenico: -0.48; CombustiveisFosseisComPotencialDeAquecimentoGlobal: 13.9; PotencialDeAquecimentoGlobalUsoDoSoloEMudancaDeUsoDoSolo: 0.0246; PotencialDeEutrofizacaoFraccaoDeNutrientesQueAtingemOCompartimentoFinalDeAguaDoce: 0.000189; PotencialDeEutrofizacaoFraccaoDeNutrientesQueAtingemOCompartimentoFinalMarinho: 0.0122; EnergiaRecuperada: 0.00739; ConsumoDeAguaDoce: 0.113; UtilizacaoLiquidaDeAguaDoce: 0.113; ResiduosPerigososEliminados: 0.00221; ResiduosNaoPerigososEliminados: 1.83; MassaTotalDeResiduosRadioactivosEliminados: 0.000394; EnergiaElectricaExportada: 1.55; MateriaisParaRecuperacaoDeEnergia: 0.00739; MateriaisParaReciclagem: 0.0253; UnidadeEPD: 1 m²
Type - IFC.REVIGRÉS-Dados gerais-Floor Covering - Nome: REVIGRÉS-URBAN-BASE-44.35X44.35-RECT-URBAN OFFWHITE; TipoProduto: Prensado a seco: grupo BIa UGL | Grés porcelânico técnico; NumeroDeRegistoDAP: EPD-REV-20240006-CCC1-EN; ReferenciaDAP: -; UrlDOP: -
Classification: C3020 (Uniformat)
Pset_CoveringCommon - TotalThickness: 8.5 mm
IFC.REVIGRÉS-Dados do fabricante-Floor Covering - Type: Floor: REVIGRÉS-URBAN-BASE-44,35X44,35-RECT-OFFWHITE
IFC.REVIGRÉS-Dados de desempenho-Floor Covering - Type: Floor: REVIGRÉS-URBAN-BASE-44,35X44,35-RECT-OFFWHITE
IFC.REVIGRÉS-Dados de especificação-Floor Covering - Type: Floor: REVIGRÉS-URBAN-BASE-44,35X44,35-RECT-OFFWHITE
IFC.REVIGRÉS-Dados geométricos-Floor Covering - Type: Floor: REVIGRÉS-URBAN-BASE-44,35X44,35-RECT-OFFWHITE
IFC.REVIGRÉS-Dados de sustentabilidade-Floor Covering - Type: Floor: REVIGRÉS-URBAN-BASE-44,35X44,35-RECT-OFFWHITE

# IfcCovering: Floor:REVIGRÉS-URBAN-BASE-44,35X88,9-RECT-ANTRACITE, Floor:REVIGRÉS-URBAN-BASE-44,35X88,9-RECT-ANTRACITE:22803
In: Level 1
Type - PredefinedType: CLADDING; Material: REVIGRÉS-URBAN-BASE-45X90-RECT-ANTRACITE 10.5 mm
Type - Pset_CoveringCommon - Reference: 3121H848U1; Material: Grés porcelânico
Type - Pset_ElementShading - Roughness: 304.8 mm
Type - Pset_ManufacturerTypeInformation - Manufacturer: REVIGRÉS
Type - Pset_ProductRequirements - Category: Floors
Type - Pset_QuantityTakeOff - Reference: 3121H848U1
Type - IFC.REVIGRÉS-Dados do fabricante-Floor Covering - FabricanteURL: https://www.revigres.pt/; ReferenciaModelo: Urban; NumeroGlobalDeItemComercial: 3121H848U1; Acabamento: RECT; Material: Grés porcelânico; IdentificadorDoOperadorEconomico: 501840856; UrlFabricanteArtigo: https://www.revigres.pt/colecoes/urban; PaisOrigem: Portugal
Type - IFC.REVIGRÉS-Dados de desempenho-Floor Covering - Rectilinearidade: ± 0.2% máx.± 0.8 mm; Ortogonalidade: ± 0.2% máx.± 1.5 mm; PlanaridadeDaSuperficie: ± 0.3% máx. ± 1.8 mm; QualidadeDaSuperficie: Cumpre; AbsorcaoDeAgua: < 0.05%; ModuloDeRuptura: > 45 N/mm²; ResistenciaAFlexao: > 3500 N; ResistenciaAAbrasaoProfunda: < 120 mm³; DilatacaoTermicaLinear: ≤ 8,0x10-6 °C-1; ResistenciaAoChoqueTermico: Resiste; DurabilidadeResistenciaAoGeloDegelo: Resiste; ResistenciaAoEscorregamentoDIN51130: R9; ResistenciaAoEscorregamentoDIN51097: A; ResistenciaAoEscorregamentoENV51097: A; ResistenciaAoEscorregamentoENV12633: Class 1; ResistenciaAoEscorregamentoANSIA1371: ≥0,42; ResistenciaAoDeslizamentoENV12633: Class 1; ResistenciaAsManchas: Class 5; ResistenciaABaixasConcentracoesDeAcidosEAlcalis: Classe LA; ResistenciaAAltasConcentracoesDeAcidosEAlcalis: Classe HA; LibertacaoDeCadmio: 0; LibertacaoDeChumbo: 0
Type - IFC.REVIGRÉS-Dados de especificação-Floor Covering - VariacaoTonalidade: 2; NivelDeTrafego: 5; EPavimento: Sim; ERevestimento: Sim; EExterno: Sim
Type - IFC.REVIGRÉS-Dados geométricos-Floor Covering - AlturaNominal: 10.5 mm; ComprimentoNominal: 4435 mm; LarguraNominal: 88.9 mm
Type - IFC.REVIGRÉS-Dados de sustentabilidade-Floor Covering - EnergiaTermicaExportada: 0; ItemENovo: Sim; ItemEParcialmenteReciclado: 0.29; ItemEReciclado: Sim; VidaÚtilEsperada: 50; SubstanciasPerigosas: Não; PotencialDeEsgotamentoAbioticoDosRecursosFosseis: 203; PotencialDeEsgotamentoAbioticoDosRecursosNaoFosseisMineraisEMetais: 0.000701; PotencialDeAquecimentoGlobalBiogenico: -0.48; CombustiveisFosseisComPotencialDeAquecimentoGlobal: 13.9; PotencialDeAquecimentoGlobalUsoDoSoloEMudancaDeUsoDoSolo: 0.0246; PotencialDeEutrofizacaoFraccaoDeNutrientesQueAtingemOCompartimentoFinalDeAguaDoce: 0.000189; PotencialDeEutrofizacaoFraccaoDeNutrientesQueAtingemOCompartimentoFinalMarinho: 0.0122; EnergiaRecuperada: 0.00739; ConsumoDeAguaDoce: 0.113; UtilizacaoLiquidaDeAguaDoce: 0.113; ResiduosPerigososEliminados: 0.00221; ResiduosNaoPerigososEliminados: 1.83; MassaTotalDeResiduosRadioactivosEliminados: 0.000394; EnergiaElectricaExportada: 1.55; MateriaisParaRecuperacaoDeEnergia: 0.00739; MateriaisParaReciclagem: 0.0253; UnidadeEPD: 1 m²
Type - IFC.REVIGRÉS-Dados gerais-Floor Covering - Nome: REVIGRÉS-URBAN-BASE-44.35X88.9-RECT-URBAN ANTRACITE; TipoProduto: Prensado a seco: grupo BIa UGL | Grés porcelânico técnico; NumeroDeRegistoDAP: EPD-REV-20240006-CCC1-EN; ReferenciaDAP: -; UrlDOP: -
Classification: C3020 (Uniformat)
Pset_CoveringCommon - TotalThickness: 10.5 mm
IFC.REVIGRÉS-Dados do fabricante-Floor Covering - Type: Floor: REVIGRÉS-URBAN-BASE-44,35X88,9-RECT-ANTRACITE
IFC.REVIGRÉS-Dados de desempenho-Floor Covering - Type: Floor: REVIGRÉS-URBAN-BASE-44,35X88,9-RECT-ANTRACITE
IFC.REVIGRÉS-Dados de especificação-Floor Covering - Type: Floor: REVIGRÉS-URBAN-BASE-44,35X88,9-RECT-ANTRACITE
IFC.REVIGRÉS-Dados geométricos-Floor Covering - Type: Floor: REVIGRÉS-URBAN-BASE-44,35X88,9-RECT-ANTRACITE
IFC.REVIGRÉS-Dados de sustentabilidade-Floor Covering - Type: Floor: REVIGRÉS-URBAN-BASE-44,35X88,9-RECT-ANTRACITE

# IfcCovering: Floor:REVIGRÉS-URBAN-BASE-44,35X88,9-RECT-BONE, Floor:REVIGRÉS-URBAN-BASE-44,35X88,9-RECT-BONE:22819
In: Level 1
Type - PredefinedType: CLADDING; Material: REVIGRÉS-URBAN-BASE-45X90-RECT-BONE 10.5 mm
Type - Pset_CoveringCommon - Reference: 3121H820T1; Material: Grés porcelânico
Type - Pset_ElementShading - Roughness: 304.8 mm
Type - Pset_ManufacturerTypeInformation - Manufacturer: REVIGRÉS
Type - Pset_ProductRequirements - Category: Floors
Type - Pset_QuantityTakeOff - Reference: 3121H820T1
Type - IFC.REVIGRÉS-Dados do fabricante-Floor Covering - FabricanteURL: https://www.revigres.pt/; ReferenciaModelo: Urban; NumeroGlobalDeItemComercial: 3121H820T1; Acabamento: RECT; Material: Grés porcelânico; IdentificadorDoOperadorEconomico: 501840856; UrlFabricanteArtigo: https://www.revigres.pt/colecoes/urban; PaisOrigem: Portugal
Type - IFC.REVIGRÉS-Dados de desempenho-Floor Covering - Rectilinearidade: ± 0.2% máx.± 0.8 mm; Ortogonalidade: ± 0.2% máx.± 1.5 mm; PlanaridadeDaSuperficie: ± 0.3% máx. ± 1.8 mm; QualidadeDaSuperficie: Cumpre; AbsorcaoDeAgua: < 0.05%; ModuloDeRuptura: > 45 N/mm²; ResistenciaAFlexao: > 3500 N; ResistenciaAAbrasaoProfunda: < 120 mm³; DilatacaoTermicaLinear: ≤ 8,0x10-6 °C-1; ResistenciaAoChoqueTermico: Resiste; DurabilidadeResistenciaAoGeloDegelo: Resiste; ResistenciaAoEscorregamentoDIN51130: R9; ResistenciaAoEscorregamentoDIN51097: A; ResistenciaAoEscorregamentoENV51097: A; ResistenciaAoEscorregamentoENV12633: Class 1; ResistenciaAoEscorregamentoANSIA1371: ≥0,42; ResistenciaAoDeslizamentoENV12633: Class 1; ResistenciaAsManchas: Class 5; ResistenciaABaixasConcentracoesDeAcidosEAlcalis: Classe LA; ResistenciaAAltasConcentracoesDeAcidosEAlcalis: Classe HA; LibertacaoDeCadmio: 0; LibertacaoDeChumbo: 0
Type - IFC.REVIGRÉS-Dados de especificação-Floor Covering - VariacaoTonalidade: 2; NivelDeTrafego: 5; EPavimento: Sim; ERevestimento: Sim; EExterno: Sim
Type - IFC.REVIGRÉS-Dados geométricos-Floor Covering - AlturaNominal: 10.5 mm; ComprimentoNominal: 4435 mm; LarguraNominal: 88.9 mm
Type - IFC.REVIGRÉS-Dados de sustentabilidade-Floor Covering - EnergiaTermicaExportada: 0; ItemENovo: Sim; ItemEParcialmenteReciclado: 0.03; ItemEReciclado: Sim; VidaÚtilEsperada: 50; SubstanciasPerigosas: Não; PotencialDeEsgotamentoAbioticoDosRecursosFosseis: 203; PotencialDeEsgotamentoAbioticoDosRecursosNaoFosseisMineraisEMetais: 0.000701; PotencialDeAquecimentoGlobalBiogenico: -0.48; CombustiveisFosseisComPotencialDeAquecimentoGlobal: 13.9; PotencialDeAquecimentoGlobalUsoDoSoloEMudancaDeUsoDoSolo: 0.0246; PotencialDeEutrofizacaoFraccaoDeNutrientesQueAtingemOCompartimentoFinalDeAguaDoce: 0.000189; PotencialDeEutrofizacaoFraccaoDeNutrientesQueAtingemOCompartimentoFinalMarinho: 0.0122; EnergiaRecuperada: 0.00739; ConsumoDeAguaDoce: 0.113; UtilizacaoLiquidaDeAguaDoce: 0.113; ResiduosPerigososEliminados: 0.00221; ResiduosNaoPerigososEliminados: 1.83; MassaTotalDeResiduosRadioactivosEliminados: 0.000394; EnergiaElectricaExportada: 1.55; MateriaisParaRecuperacaoDeEnergia: 0.00739; MateriaisParaReciclagem: 0.0253; UnidadeEPD: 1 m²
Type - IFC.REVIGRÉS-Dados gerais-Floor Covering - Nome: REVIGRÉS-URBAN-BASE-44.35X88.9-RECT-URBAN BONE; TipoProduto: Prensado a seco: grupo BIa UGL | Grés porcelânico técnico; NumeroDeRegistoDAP: EPD-REV-20240006-CCC1-EN; ReferenciaDAP: -; UrlDOP: -
Classification: C3020 (Uniformat)
Pset_CoveringCommon - TotalThickness: 10.5 mm
IFC.REVIGRÉS-Dados do fabricante-Floor Covering - Type: Floor: REVIGRÉS-URBAN-BASE-44,35X88,9-RECT-BONE
IFC.REVIGRÉS-Dados de desempenho-Floor Covering - Type: Floor: REVIGRÉS-URBAN-BASE-44,35X88,9-RECT-BONE
IFC.REVIGRÉS-Dados de especificação-Floor Covering - Type: Floor: REVIGRÉS-URBAN-BASE-44,35X88,9-RECT-BONE
IFC.REVIGRÉS-Dados geométricos-Floor Covering - Type: Floor: REVIGRÉS-URBAN-BASE-44,35X88,9-RECT-BONE
IFC.REVIGRÉS-Dados de sustentabilidade-Floor Covering - Type: Floor: REVIGRÉS-URBAN-BASE-44,35X88,9-RECT-BONE

# IfcCovering: Floor:REVIGRÉS-URBAN-BASE-44,35X88,9-RECT-CRAFT, Floor:REVIGRÉS-URBAN-BASE-44,35X88,9-RECT-CRAFT:22835
In: Level 1
Type - PredefinedType: CLADDING; Material: REVIGRÉS-URBAN-BASE-45X90-RECT-CRAFT 10.5 mm
Type - Pset_CoveringCommon - Reference: 3121H824T1; Material: Grés porcelânico
Type - Pset_ElementShading - Roughness: 304.8 mm
Type - Pset_ManufacturerTypeInformation - Manufacturer: REVIGRÉS
Type - Pset_ProductRequirements - Category: Floors
Type - Pset_QuantityTakeOff - Reference: 3121H824T1
Type - IFC.REVIGRÉS-Dados do fabricante-Floor Covering - FabricanteURL: https://www.revigres.pt/; ReferenciaModelo: Urban; NumeroGlobalDeItemComercial: 3121H824T1; Acabamento: RECT; Material: Grés porcelânico; IdentificadorDoOperadorEconomico: 501840856; UrlFabricanteArtigo: https://www.revigres.pt/colecoes/urban; PaisOrigem: Portugal
Type - IFC.REVIGRÉS-Dados de desempenho-Floor Covering - Rectilinearidade: ± 0.2% máx.± 0.8 mm; Ortogonalidade: ± 0.2% máx.± 1.5 mm; PlanaridadeDaSuperficie: ± 0.3% máx. ± 1.8 mm; QualidadeDaSuperficie: Cumpre; AbsorcaoDeAgua: < 0.05%; ModuloDeRuptura: > 45 N/mm²; ResistenciaAFlexao: > 3500 N; ResistenciaAAbrasaoProfunda: < 120 mm³; DilatacaoTermicaLinear: ≤ 8,0x10-6 °C-1; ResistenciaAoChoqueTermico: Resiste; DurabilidadeResistenciaAoGeloDegelo: Resiste; ResistenciaAoEscorregamentoDIN51130: R9; ResistenciaAoEscorregamentoDIN51097: A; ResistenciaAoEscorregamentoENV51097: A; ResistenciaAoEscorregamentoENV12633: Class 1; ResistenciaAoEscorregamentoANSIA1371: ≥0,42; ResistenciaAoDeslizamentoENV12633: Class 1; ResistenciaAsManchas: Class 5; ResistenciaABaixasConcentracoesDeAcidosEAlcalis: Classe LA; ResistenciaAAltasConcentracoesDeAcidosEAlcalis: Classe HA; LibertacaoDeCadmio: 0; LibertacaoDeChumbo: 0
Type - IFC.REVIGRÉS-Dados de especificação-Floor Covering - VariacaoTonalidade: 2; NivelDeTrafego: 5; EPavimento: Sim; ERevestimento: Sim; EExterno: Sim
Type - IFC.REVIGRÉS-Dados geométricos-Floor Covering - AlturaNominal: 10.5 mm; ComprimentoNominal: 4435 mm; LarguraNominal: 88.9 mm
Type - IFC.REVIGRÉS-Dados de sustentabilidade-Floor Covering - EnergiaTermicaExportada: 0; ItemENovo: Sim; ItemEParcialmenteReciclado: 0.19; ItemEReciclado: Sim; VidaÚtilEsperada: 50; SubstanciasPerigosas: Não; PotencialDeEsgotamentoAbioticoDosRecursosFosseis: 203; PotencialDeEsgotamentoAbioticoDosRecursosNaoFosseisMineraisEMetais: 0.000701; PotencialDeAquecimentoGlobalBiogenico: -0.48; CombustiveisFosseisComPotencialDeAquecimentoGlobal: 13.9; PotencialDeAquecimentoGlobalUsoDoSoloEMudancaDeUsoDoSolo: 0.0246; PotencialDeEutrofizacaoFraccaoDeNutrientesQueAtingemOCompartimentoFinalDeAguaDoce: 0.000189; PotencialDeEutrofizacaoFraccaoDeNutrientesQueAtingemOCompartimentoFinalMarinho: 0.0122; EnergiaRecuperada: 0.00739; ConsumoDeAguaDoce: 0.113; UtilizacaoLiquidaDeAguaDoce: 0.113; ResiduosPerigososEliminados: 0.00221; ResiduosNaoPerigososEliminados: 1.83; MassaTotalDeResiduosRadioactivosEliminados: 0.000394; EnergiaElectricaExportada: 1.55; MateriaisParaRecuperacaoDeEnergia: 0.00739; MateriaisParaReciclagem: 0.0253; UnidadeEPD: 1 m²
Type - IFC.REVIGRÉS-Dados gerais-Floor Covering - Nome: REVIGRÉS-URBAN-BASE-44.35X88.9-RECT-URBAN CRAFT; TipoProduto: Prensado a seco: grupo BIa UGL | Grés porcelânico técnico; NumeroDeRegistoDAP: EPD-REV-20240006-CCC1-EN; ReferenciaDAP: -; UrlDOP: -
Classification: C3020 (Uniformat)
Pset_CoveringCommon - TotalThickness: 10.5 mm
IFC.REVIGRÉS-Dados do fabricante-Floor Covering - Type: Floor: REVIGRÉS-URBAN-BASE-44,35X88,9-RECT-CRAFT
IFC.REVIGRÉS-Dados de desempenho-Floor Covering - Type: Floor: REVIGRÉS-URBAN-BASE-44,35X88,9-RECT-CRAFT
IFC.REVIGRÉS-Dados de especificação-Floor Covering - Type: Floor: REVIGRÉS-URBAN-BASE-44,35X88,9-RECT-CRAFT
IFC.REVIGRÉS-Dados geométricos-Floor Covering - Type: Floor: REVIGRÉS-URBAN-BASE-44,35X88,9-RECT-CRAFT
IFC.REVIGRÉS-Dados de sustentabilidade-Floor Covering - Type: Floor: REVIGRÉS-URBAN-BASE-44,35X88,9-RECT-CRAFT

# IfcCovering: Floor:REVIGRÉS-URBAN-BASE-44,35X88,9-RECT-FOG, Floor:REVIGRÉS-URBAN-BASE-44,35X88,9-RECT-FOG:22851
In: Level 1
Type - PredefinedType: CLADDING; Material: REVIGRÉS-URBAN-BASE-45X90-RECT-FOG 10.5 mm
Type - Pset_CoveringCommon - Reference: 3121H821T1; Material: Grés porcelânico
Type - Pset_ElementShading - Roughness: 304.8 mm
Type - Pset_ManufacturerTypeInformation - Manufacturer: REVIGRÉS
Type - Pset_ProductRequirements - Category: Floors
Type - Pset_QuantityTakeOff - Reference: 3121H821T1
Type - IFC.REVIGRÉS-Dados do fabricante-Floor Covering - FabricanteURL: https://www.revigres.pt/; ReferenciaModelo: Urban; NumeroGlobalDeItemComercial: 3121H821T1; Acabamento: RECT; Material: Grés porcelânico; IdentificadorDoOperadorEconomico: 501840856; UrlFabricanteArtigo: https://www.revigres.pt/colecoes/urban; PaisOrigem: Portugal
Type - IFC.REVIGRÉS-Dados de desempenho-Floor Covering - Rectilinearidade: ± 0.2% máx.± 0.8 mm; Ortogonalidade: ± 0.2% máx.± 1.5 mm; PlanaridadeDaSuperficie: ± 0.3% máx. ± 1.8 mm; QualidadeDaSuperficie: Cumpre; AbsorcaoDeAgua: < 0.05%; ModuloDeRuptura: > 45 N/mm²; ResistenciaAFlexao: > 3500 N; ResistenciaAAbrasaoProfunda: < 120 mm³; DilatacaoTermicaLinear: ≤ 8,0x10-6 °C-1; ResistenciaAoChoqueTermico: Resiste; DurabilidadeResistenciaAoGeloDegelo: Resiste; ResistenciaAoEscorregamentoDIN51130: R9; ResistenciaAoEscorregamentoDIN51097: A; ResistenciaAoEscorregamentoENV51097: A; ResistenciaAoEscorregamentoENV12633: Class 1; ResistenciaAoEscorregamentoANSIA1371: ≥0,42; ResistenciaAoDeslizamentoENV12633: Class 1; ResistenciaAsManchas: Class 5; ResistenciaABaixasConcentracoesDeAcidosEAlcalis: Classe LA; ResistenciaAAltasConcentracoesDeAcidosEAlcalis: Classe HA; LibertacaoDeCadmio: 0; LibertacaoDeChumbo: 0
Type - IFC.REVIGRÉS-Dados de especificação-Floor Covering - VariacaoTonalidade: 2; NivelDeTrafego: 5; EPavimento: Sim; ERevestimento: Sim; EExterno: Sim
Type - IFC.REVIGRÉS-Dados geométricos-Floor Covering - AlturaNominal: 10.5 mm; ComprimentoNominal: 4435 mm; LarguraNominal: 88.9 mm
Type - IFC.REVIGRÉS-Dados de sustentabilidade-Floor Covering - EnergiaTermicaExportada: 0; ItemENovo: Sim; ItemEParcialmenteReciclado: 0.23; ItemEReciclado: Sim; VidaÚtilEsperada: 50; SubstanciasPerigosas: Não; PotencialDeEsgotamentoAbioticoDosRecursosFosseis: 203; PotencialDeEsgotamentoAbioticoDosRecursosNaoFosseisMineraisEMetais: 0.000701; PotencialDeAquecimentoGlobalBiogenico: -0.48; CombustiveisFosseisComPotencialDeAquecimentoGlobal: 13.9; PotencialDeAquecimentoGlobalUsoDoSoloEMudancaDeUsoDoSolo: 0.0246; PotencialDeEutrofizacaoFraccaoDeNutrientesQueAtingemOCompartimentoFinalDeAguaDoce: 0.000189; PotencialDeEutrofizacaoFraccaoDeNutrientesQueAtingemOCompartimentoFinalMarinho: 0.0122; EnergiaRecuperada: 0.00739; ConsumoDeAguaDoce: 0.113; UtilizacaoLiquidaDeAguaDoce: 0.113; ResiduosPerigososEliminados: 0.00221; ResiduosNaoPerigososEliminados: 1.83; MassaTotalDeResiduosRadioactivosEliminados: 0.000394; EnergiaElectricaExportada: 1.55; MateriaisParaRecuperacaoDeEnergia: 0.00739; MateriaisParaReciclagem: 0.0253; UnidadeEPD: 1 m²
Type - IFC.REVIGRÉS-Dados gerais-Floor Covering - Nome: REVIGRÉS-URBAN-BASE-44.35X88.9-RECT-URBAN FOG; TipoProduto: Prensado a seco: grupo BIa UGL | Grés porcelânico técnico; NumeroDeRegistoDAP: EPD-REV-20240006-CCC1-EN; ReferenciaDAP: -; UrlDOP: -
Classification: C3020 (Uniformat)
Pset_CoveringCommon - TotalThickness: 10.5 mm
IFC.REVIGRÉS-Dados do fabricante-Floor Covering - Type: Floor: REVIGRÉS-URBAN-BASE-44,35X88,9-RECT-FOG
IFC.REVIGRÉS-Dados de desempenho-Floor Covering - Type: Floor: REVIGRÉS-URBAN-BASE-44,35X88,9-RECT-FOG
IFC.REVIGRÉS-Dados de especificação-Floor Covering - Type: Floor: REVIGRÉS-URBAN-BASE-44,35X88,9-RECT-FOG
IFC.REVIGRÉS-Dados geométricos-Floor Covering - Type: Floor: REVIGRÉS-URBAN-BASE-44,35X88,9-RECT-FOG
IFC.REVIGRÉS-Dados de sustentabilidade-Floor Covering - Type: Floor: REVIGRÉS-URBAN-BASE-44,35X88,9-RECT-FOG

# IfcCovering: Floor:REVIGRÉS-URBAN-BASE-44,35X88,9-RECT-GRIS, Floor:REVIGRÉS-URBAN-BASE-44,35X88,9-RECT-GRIS:22867
In: Level 1
Type - PredefinedType: CLADDING; Material: REVIGRÉS-URBAN-BASE-45X90-RECT-GRIS 10.5 mm
Type - Pset_CoveringCommon - Reference: 3121H822T1; Material: Grés porcelânico
Type - Pset_ElementShading - Roughness: 304.8 mm
Type - Pset_ManufacturerTypeInformation - Manufacturer: REVIGRÉS
Type - Pset_ProductRequirements - Category: Floors
Type - Pset_QuantityTakeOff - Reference: 3121H822T1
Type - IFC.REVIGRÉS-Dados do fabricante-Floor Covering - FabricanteURL: https://www.revigres.pt/; ReferenciaModelo: Urban; NumeroGlobalDeItemComercial: 3121H822T1; Acabamento: RECT; Material: Grés porcelânico; IdentificadorDoOperadorEconomico: 501840856; UrlFabricanteArtigo: https://www.revigres.pt/colecoes/urban; PaisOrigem: Portugal
Type - IFC.REVIGRÉS-Dados de desempenho-Floor Covering - Rectilinearidade: ± 0.2% máx.± 0.8 mm; Ortogonalidade: ± 0.2% máx.± 1.5 mm; PlanaridadeDaSuperficie: ± 0.3% máx. ± 1.8 mm; QualidadeDaSuperficie: Cumpre; AbsorcaoDeAgua: < 0.05%; ModuloDeRuptura: > 45 N/mm²; ResistenciaAFlexao: > 3500 N; ResistenciaAAbrasaoProfunda: < 120 mm³; DilatacaoTermicaLinear: ≤ 8,0x10-6 °C-1; ResistenciaAoChoqueTermico: Resiste; DurabilidadeResistenciaAoGeloDegelo: Resiste; ResistenciaAoEscorregamentoDIN51130: R9; ResistenciaAoEscorregamentoDIN51097: A; ResistenciaAoEscorregamentoENV51097: A; ResistenciaAoEscorregamentoENV12633: Class 1; ResistenciaAoEscorregamentoANSIA1371: ≥0,42; ResistenciaAoDeslizamentoENV12633: Class 1; ResistenciaAsManchas: Class 5; ResistenciaABaixasConcentracoesDeAcidosEAlcalis: Classe LA; ResistenciaAAltasConcentracoesDeAcidosEAlcalis: Classe HA; LibertacaoDeCadmio: 0; LibertacaoDeChumbo: 0
Type - IFC.REVIGRÉS-Dados de especificação-Floor Covering - VariacaoTonalidade: 2; NivelDeTrafego: 5; EPavimento: Sim; ERevestimento: Sim; EExterno: Sim
Type - IFC.REVIGRÉS-Dados geométricos-Floor Covering - AlturaNominal: 10.5 mm; ComprimentoNominal: 4435 mm; LarguraNominal: 88.9 mm
Type - IFC.REVIGRÉS-Dados de sustentabilidade-Floor Covering - EnergiaTermicaExportada: 0; ItemENovo: Sim; ItemEParcialmenteReciclado: 0.23; ItemEReciclado: Sim; VidaÚtilEsperada: 50; SubstanciasPerigosas: Não; PotencialDeEsgotamentoAbioticoDosRecursosFosseis: 203; PotencialDeEsgotamentoAbioticoDosRecursosNaoFosseisMineraisEMetais: 0.000701; PotencialDeAquecimentoGlobalBiogenico: -0.48; CombustiveisFosseisComPotencialDeAquecimentoGlobal: 13.9; PotencialDeAquecimentoGlobalUsoDoSoloEMudancaDeUsoDoSolo: 0.0246; PotencialDeEutrofizacaoFraccaoDeNutrientesQueAtingemOCompartimentoFinalDeAguaDoce: 0.000189; PotencialDeEutrofizacaoFraccaoDeNutrientesQueAtingemOCompartimentoFinalMarinho: 0.0122; EnergiaRecuperada: 0.00739; ConsumoDeAguaDoce: 0.113; UtilizacaoLiquidaDeAguaDoce: 0.113; ResiduosPerigososEliminados: 0.00221; ResiduosNaoPerigososEliminados: 1.83; MassaTotalDeResiduosRadioactivosEliminados: 0.000394; EnergiaElectricaExportada: 1.55; MateriaisParaRecuperacaoDeEnergia: 0.00739; MateriaisParaReciclagem: 0.0253; UnidadeEPD: 1 m²
Type - IFC.REVIGRÉS-Dados gerais-Floor Covering - Nome: REVIGRÉS-URBAN-BASE-44.35X88.9-RECT-URBAN GRIS; TipoProduto: Prensado a seco: grupo BIa UGL | Grés porcelânico técnico; NumeroDeRegistoDAP: EPD-REV-20240006-CCC1-EN; ReferenciaDAP: -; UrlDOP: -
Classification: C3020 (Uniformat)
Pset_CoveringCommon - TotalThickness: 10.5 mm
IFC.REVIGRÉS-Dados do fabricante-Floor Covering - Type: Floor: REVIGRÉS-URBAN-BASE-44,35X88,9-RECT-GRIS
IFC.REVIGRÉS-Dados de desempenho-Floor Covering - Type: Floor: REVIGRÉS-URBAN-BASE-44,35X88,9-RECT-GRIS
IFC.REVIGRÉS-Dados de especificação-Floor Covering - Type: Floor: REVIGRÉS-URBAN-BASE-44,35X88,9-RECT-GRIS
IFC.REVIGRÉS-Dados geométricos-Floor Covering - Type: Floor: REVIGRÉS-URBAN-BASE-44,35X88,9-RECT-GRIS
IFC.REVIGRÉS-Dados de sustentabilidade-Floor Covering - Type: Floor: REVIGRÉS-URBAN-BASE-44,35X88,9-RECT-GRIS

# IfcCovering: Floor:REVIGRÉS-URBAN-BASE-44,35X88,9-RECT-OFFWHITE, Floor:REVIGRÉS-URBAN-BASE-44,35X88,9-RECT-OFFWHITE:22883
In: Level 1
Type - PredefinedType: CLADDING; Material: REVIGRÉS-URBAN-BASE-45X90-RECT-OFFWHITE 10.5 mm
Type - Pset_CoveringCommon - Reference: 3121H823T1; Material: Grés porcelânico
Type - Pset_ElementShading - Roughness: 304.8 mm
Type - Pset_ManufacturerTypeInformation - Manufacturer: REVIGRÉS
Type - Pset_ProductRequirements - Category: Floors
Type - Pset_QuantityTakeOff - Reference: 3121H823T1
Type - IFC.REVIGRÉS-Dados do fabricante-Floor Covering - FabricanteURL: https://www.revigres.pt/; ReferenciaModelo: Urban; NumeroGlobalDeItemComercial: 3121H823T1; Acabamento: RECT; Material: Grés porcelânico; IdentificadorDoOperadorEconomico: 501840856; UrlFabricanteArtigo: https://www.revigres.pt/colecoes/urban; PaisOrigem: Portugal
Type - IFC.REVIGRÉS-Dados de desempenho-Floor Covering - Rectilinearidade: ± 0.2% máx.± 0.8 mm; Ortogonalidade: ± 0.2% máx.± 1.5 mm; PlanaridadeDaSuperficie: ± 0.3% máx. ± 1.8 mm; QualidadeDaSuperficie: Cumpre; AbsorcaoDeAgua: < 0.05%; ModuloDeRuptura: > 45 N/mm²; ResistenciaAFlexao: > 3500 N; ResistenciaAAbrasaoProfunda: < 120 mm³; DilatacaoTermicaLinear: ≤ 8,0x10-6 °C-1; ResistenciaAoChoqueTermico: Resiste; DurabilidadeResistenciaAoGeloDegelo: Resiste; ResistenciaAoEscorregamentoDIN51130: R9; ResistenciaAoEscorregamentoDIN51097: A; ResistenciaAoEscorregamentoENV51097: A; ResistenciaAoEscorregamentoENV12633: Class 1; ResistenciaAoEscorregamentoANSIA1371: ≥0,42; ResistenciaAoDeslizamentoENV12633: Class 1; ResistenciaAsManchas: Class 5; ResistenciaABaixasConcentracoesDeAcidosEAlcalis: Classe LA; ResistenciaAAltasConcentracoesDeAcidosEAlcalis: Classe HA; LibertacaoDeCadmio: 0; LibertacaoDeChumbo: 0
Type - IFC.REVIGRÉS-Dados de especificação-Floor Covering - VariacaoTonalidade: 2; NivelDeTrafego: 5; EPavimento: Sim; ERevestimento: Sim; EExterno: Sim
Type - IFC.REVIGRÉS-Dados geométricos-Floor Covering - AlturaNominal: 10.5 mm; ComprimentoNominal: 4435 mm; LarguraNominal: 88.9 mm
Type - IFC.REVIGRÉS-Dados de sustentabilidade-Floor Covering - EnergiaTermicaExportada: 0; ItemENovo: Sim; ItemEParcialmenteReciclado: 0.03; ItemEReciclado: Sim; VidaÚtilEsperada: 50; SubstanciasPerigosas: Não; PotencialDeEsgotamentoAbioticoDosRecursosFosseis: 203; PotencialDeEsgotamentoAbioticoDosRecursosNaoFosseisMineraisEMetais: 0.000701; PotencialDeAquecimentoGlobalBiogenico: -0.48; CombustiveisFosseisComPotencialDeAquecimentoGlobal: 13.9; PotencialDeAquecimentoGlobalUsoDoSoloEMudancaDeUsoDoSolo: 0.0246; PotencialDeEutrofizacaoFraccaoDeNutrientesQueAtingemOCompartimentoFinalDeAguaDoce: 0.000189; PotencialDeEutrofizacaoFraccaoDeNutrientesQueAtingemOCompartimentoFinalMarinho: 0.0122; EnergiaRecuperada: 0.00739; ConsumoDeAguaDoce: 0.113; UtilizacaoLiquidaDeAguaDoce: 0.113; ResiduosPerigososEliminados: 0.00221; ResiduosNaoPerigososEliminados: 1.83; MassaTotalDeResiduosRadioactivosEliminados: 0.000394; EnergiaElectricaExportada: 1.55; MateriaisParaRecuperacaoDeEnergia: 0.00739; MateriaisParaReciclagem: 0.0253; UnidadeEPD: 1 m²
Type - IFC.REVIGRÉS-Dados gerais-Floor Covering - Nome: REVIGRÉS-URBAN-BASE-44.35X88.9-RECT-URBAN OFFWHITE; TipoProduto: Prensado a seco: grupo BIa UGL | Grés porcelânico técnico; NumeroDeRegistoDAP: EPD-REV-20240006-CCC1-EN; ReferenciaDAP: -; UrlDOP: -
Classification: C3020 (Uniformat)
Pset_CoveringCommon - TotalThickness: 10.5 mm
IFC.REVIGRÉS-Dados do fabricante-Floor Covering - Type: Floor: REVIGRÉS-URBAN-BASE-44,35X88,9-RECT-OFFWHITE
IFC.REVIGRÉS-Dados de desempenho-Floor Covering - Type: Floor: REVIGRÉS-URBAN-BASE-44,35X88,9-RECT-OFFWHITE
IFC.REVIGRÉS-Dados de especificação-Floor Covering - Type: Floor: REVIGRÉS-URBAN-BASE-44,35X88,9-RECT-OFFWHITE
IFC.REVIGRÉS-Dados geométricos-Floor Covering - Type: Floor: REVIGRÉS-URBAN-BASE-44,35X88,9-RECT-OFFWHITE
IFC.REVIGRÉS-Dados de sustentabilidade-Floor Covering - Type: Floor: REVIGRÉS-URBAN-BASE-44,35X88,9-RECT-OFFWHITE

# IfcCovering: Floor:REVIGRÉS-URBAN-BASE-45X45-NAT HYDRAULIK ANTRACITE, Floor:REVIGRÉS-URBAN-BASE-45X45-NAT HYDRAULIK ANTRACITE:26951
In: Level 1
Type - PredefinedType: CLADDING; Material: REVIGRÉS-URBAN-BASE-45X45-NAT-HYDRAULIK ANTRACITE 8.5 mm
Type - Pset_CoveringCommon - Reference: 31200752U1; Material: Grés porcelânico
Type - Pset_ElementShading - Roughness: 304.8 mm
Type - Pset_ManufacturerTypeInformation - Manufacturer: REVIGRÉS
Type - Pset_ProductRequirements - Category: Floors
Type - Pset_QuantityTakeOff - Reference: 31200752U1
Type - IFC.REVIGRÉS-Dados do fabricante-Floor Covering - FabricanteURL: https://www.revigres.pt/; ReferenciaModelo: Urban; NumeroGlobalDeItemComercial: 31200752U1; Acabamento: NAT; Material: Grés porcelânico; IdentificadorDoOperadorEconomico: 501840856; UrlFabricanteArtigo: https://www.revigres.pt/colecoes/urban; PaisOrigem: Portugal
Type - IFC.REVIGRÉS-Dados de desempenho-Floor Covering - Rectilinearidade: ± 0.3% máx. ± 1.5 mm; Ortogonalidade: ± 0.3% máx. ± 1.8 mm; PlanaridadeDaSuperficie: ± 0.3% máx. ± 1.8 mm; QualidadeDaSuperficie: Cumpre; AbsorcaoDeAgua: < 0.05%; ModuloDeRuptura: > 45 N/mm²; ResistenciaAFlexao: > 2000 N; ResistenciaAAbrasaoProfunda: < 120 mm³; DilatacaoTermicaLinear: ≤ 8,0x10-6 °C-1; ResistenciaAoChoqueTermico: Resiste; DurabilidadeResistenciaAoGeloDegelo: Resiste; ResistenciaAoEscorregamentoDIN51130: R9; ResistenciaAoEscorregamentoDIN51097: A; ResistenciaAoEscorregamentoENV51097: A; ResistenciaAoEscorregamentoENV12633: Class 1; ResistenciaAoEscorregamentoANSIA1371: ≥0,42; ResistenciaAoDeslizamentoENV12633: Class 1; ResistenciaAsManchas: Class 5; ResistenciaABaixasConcentracoesDeAcidosEAlcalis: Classe LA; ResistenciaAAltasConcentracoesDeAcidosEAlcalis: Classe HA; LibertacaoDeCadmio: 0; LibertacaoDeChumbo: 0
Type - IFC.REVIGRÉS-Dados de especificação-Floor Covering - VariacaoTonalidade: 3; NivelDeTrafego: 4; EPavimento: Sim; ERevestimento: Sim; EExterno: Sim
Type - IFC.REVIGRÉS-Dados geométricos-Floor Covering - AlturaNominal: 8.5 mm; ComprimentoNominal: 45 mm; LarguraNominal: 45 mm
Type - IFC.REVIGRÉS-Dados de sustentabilidade-Floor Covering - EnergiaTermicaExportada: 0; ItemENovo: Sim; ItemEParcialmenteReciclado: 0.29; ItemEReciclado: Sim; VidaÚtilEsperada: 50; SubstanciasPerigosas: Não; PotencialDeEsgotamentoAbioticoDosRecursosFosseis: 203; PotencialDeEsgotamentoAbioticoDosRecursosNaoFosseisMineraisEMetais: 0.000701; PotencialDeAquecimentoGlobalBiogenico: -0.48; CombustiveisFosseisComPotencialDeAquecimentoGlobal: 13.9; PotencialDeAquecimentoGlobalUsoDoSoloEMudancaDeUsoDoSolo: 0.0246; PotencialDeEutrofizacaoFraccaoDeNutrientesQueAtingemOCompartimentoFinalDeAguaDoce: 0.000189; PotencialDeEutrofizacaoFraccaoDeNutrientesQueAtingemOCompartimentoFinalMarinho: 0.0122; EnergiaRecuperada: 0.00739; ConsumoDeAguaDoce: 0.113; UtilizacaoLiquidaDeAguaDoce: 0.113; ResiduosPerigososEliminados: 0.00221; ResiduosNaoPerigososEliminados: 1.83; MassaTotalDeResiduosRadioactivosEliminados: 0.000394; EnergiaElectricaExportada: 1.55; MateriaisParaRecuperacaoDeEnergia: 0.00739; MateriaisParaReciclagem: 0.0253; UnidadeEPD: 1 m²
Type - IFC.REVIGRÉS-Dados gerais-Floor Covering - Nome: REVIGRÉS-URBAN-BASE-45X45-NAT-HYDRAULIK ANTRACITE; TipoProduto: Prensado a seco: grupo BIa UGL | Grés porcelânico técnico; NumeroDeRegistoDAP: EPD-REV-20240006-CCC1-EN; ReferenciaDAP: -; UrlDOP: -
Classification: C3020 (Uniformat)
Pset_CoveringCommon - TotalThickness: 8.5 mm
IFC.REVIGRÉS-Dados do fabricante-Floor Covering - Type: Floor: REVIGRÉS-URBAN-BASE-45X45-NAT HYDRAULIK ANTRACITE
IFC.REVIGRÉS-Dados de desempenho-Floor Covering - Type: Floor: REVIGRÉS-URBAN-BASE-45X45-NAT HYDRAULIK ANTRACITE
IFC.REVIGRÉS-Dados de especificação-Floor Covering - Type: Floor: REVIGRÉS-URBAN-BASE-45X45-NAT HYDRAULIK ANTRACITE
IFC.REVIGRÉS-Dados geométricos-Floor Covering - Type: Floor: REVIGRÉS-URBAN-BASE-45X45-NAT HYDRAULIK ANTRACITE
IFC.REVIGRÉS-Dados de sustentabilidade-Floor Covering - Type: Floor: REVIGRÉS-URBAN-BASE-45X45-NAT HYDRAULIK ANTRACITE

# IfcCovering: Floor:REVIGRÉS-URBAN-BASE-45X45-NAT HYDRAULIK BONE, Floor:REVIGRÉS-URBAN-BASE-45X45-NAT HYDRAULIK BONE:26967
In: Level 1
Type - PredefinedType: CLADDING; Material: REVIGRÉS-URBAN-BASE-45X45-NAT-HYDRAULIK BONE 8.5 mm
Type - Pset_CoveringCommon - Reference: 31200754T1; Material: Grés porcelânico
Type - Pset_ElementShading - Roughness: 304.8 mm
Type - Pset_ManufacturerTypeInformation - Manufacturer: REVIGRÉS
Type - Pset_ProductRequirements - Category: Floors
Type - Pset_QuantityTakeOff - Reference: 31200754T1
Type - IFC.REVIGRÉS-Dados do fabricante-Floor Covering - FabricanteURL: https://www.revigres.pt/; ReferenciaModelo: Urban; NumeroGlobalDeItemComercial: 31200754T1; Acabamento: NAT; Material: Grés porcelânico; IdentificadorDoOperadorEconomico: 501840856; UrlFabricanteArtigo: https://www.revigres.pt/colecoes/urban; PaisOrigem: Portugal
Type - IFC.REVIGRÉS-Dados de desempenho-Floor Covering - Rectilinearidade: ± 0.3% máx. ± 1.5 mm; Ortogonalidade: ± 0.3% máx. ± 1.8 mm; PlanaridadeDaSuperficie: ± 0.3% máx. ± 1.8 mm; QualidadeDaSuperficie: Cumpre; AbsorcaoDeAgua: < 0.05%; ModuloDeRuptura: > 45 N/mm²; ResistenciaAFlexao: > 2000 N; ResistenciaAAbrasaoProfunda: < 120 mm³; DilatacaoTermicaLinear: ≤ 8,0x10-6 °C-1; ResistenciaAoChoqueTermico: Resiste; DurabilidadeResistenciaAoGeloDegelo: Resiste; ResistenciaAoEscorregamentoDIN51130: R9; ResistenciaAoEscorregamentoDIN51097: A; ResistenciaAoEscorregamentoENV51097: A; ResistenciaAoEscorregamentoENV12633: Class 1; ResistenciaAoEscorregamentoANSIA1371: ≥0,42; ResistenciaAoDeslizamentoENV12633: Class 1; ResistenciaAsManchas: Class 5; ResistenciaABaixasConcentracoesDeAcidosEAlcalis: Classe LA; ResistenciaAAltasConcentracoesDeAcidosEAlcalis: Classe HA; LibertacaoDeCadmio: 0; LibertacaoDeChumbo: 0
Type - IFC.REVIGRÉS-Dados de especificação-Floor Covering - VariacaoTonalidade: 3; NivelDeTrafego: 4; EPavimento: Sim; ERevestimento: Sim; EExterno: Sim
Type - IFC.REVIGRÉS-Dados geométricos-Floor Covering - AlturaNominal: 8.5 mm; ComprimentoNominal: 45 mm; LarguraNominal: 45 mm
Type - IFC.REVIGRÉS-Dados de sustentabilidade-Floor Covering - EnergiaTermicaExportada: 0; ItemENovo: Sim; ItemEParcialmenteReciclado: 0.03; ItemEReciclado: Sim; VidaÚtilEsperada: 50; SubstanciasPerigosas: Não; PotencialDeEsgotamentoAbioticoDosRecursosFosseis: 203; PotencialDeEsgotamentoAbioticoDosRecursosNaoFosseisMineraisEMetais: 0.000701; PotencialDeAquecimentoGlobalBiogenico: -0.48; CombustiveisFosseisComPotencialDeAquecimentoGlobal: 13.9; PotencialDeAquecimentoGlobalUsoDoSoloEMudancaDeUsoDoSolo: 0.0246; PotencialDeEutrofizacaoFraccaoDeNutrientesQueAtingemOCompartimentoFinalDeAguaDoce: 0.000189; PotencialDeEutrofizacaoFraccaoDeNutrientesQueAtingemOCompartimentoFinalMarinho: 0.0122; EnergiaRecuperada: 0.00739; ConsumoDeAguaDoce: 0.113; UtilizacaoLiquidaDeAguaDoce: 0.113; ResiduosPerigososEliminados: 0.00221; ResiduosNaoPerigososEliminados: 1.83; MassaTotalDeResiduosRadioactivosEliminados: 0.000394; EnergiaElectricaExportada: 1.55; MateriaisParaRecuperacaoDeEnergia: 0.00739; MateriaisParaReciclagem: 0.0253; UnidadeEPD: 1 m²
Type - IFC.REVIGRÉS-Dados gerais-Floor Covering - Nome: REVIGRÉS-URBAN-BASE-45X45-NAT-HYDRAULIK BONE; TipoProduto: Prensado a seco: grupo BIa UGL | Grés porcelânico técnico; NumeroDeRegistoDAP: EPD-REV-20240006-CCC1-EN; ReferenciaDAP: -; UrlDOP: -
Classification: C3020 (Uniformat)
Pset_CoveringCommon - TotalThickness: 8.5 mm
IFC.REVIGRÉS-Dados do fabricante-Floor Covering - Type: Floor: REVIGRÉS-URBAN-BASE-45X45-NAT HYDRAULIK BONE
IFC.REVIGRÉS-Dados de desempenho-Floor Covering - Type: Floor: REVIGRÉS-URBAN-BASE-45X45-NAT HYDRAULIK BONE
IFC.REVIGRÉS-Dados de especificação-Floor Covering - Type: Floor: REVIGRÉS-URBAN-BASE-45X45-NAT HYDRAULIK BONE
IFC.REVIGRÉS-Dados geométricos-Floor Covering - Type: Floor: REVIGRÉS-URBAN-BASE-45X45-NAT HYDRAULIK BONE
IFC.REVIGRÉS-Dados de sustentabilidade-Floor Covering - Type: Floor: REVIGRÉS-URBAN-BASE-45X45-NAT HYDRAULIK BONE

# IfcCovering: Floor:REVIGRÉS-URBAN-BASE-45X45-NAT HYDRAULIK CRAFT, Floor:REVIGRÉS-URBAN-BASE-45X45-NAT HYDRAULIK CRAFT:26983
In: Level 1
Type - PredefinedType: CLADDING; Material: REVIGRÉS-URBAN-BASE-45X45-NAT-HYDRAULIK CRAFT 8.5 mm
Type - Pset_CoveringCommon - Reference: 31200755T1; Material: Grés porcelânico
Type - Pset_ElementShading - Roughness: 304.8 mm
Type - Pset_ManufacturerTypeInformation - Manufacturer: REVIGRÉS
Type - Pset_ProductRequirements - Category: Floors
Type - Pset_QuantityTakeOff - Reference: 31200755T1
Type - IFC.REVIGRÉS-Dados do fabricante-Floor Covering - FabricanteURL: https://www.revigres.pt/; ReferenciaModelo: Urban; NumeroGlobalDeItemComercial: 31200755T1; Acabamento: NAT; Material: Grés porcelânico; IdentificadorDoOperadorEconomico: 501840856; UrlFabricanteArtigo: https://www.revigres.pt/colecoes/urban; PaisOrigem: Portugal
Type - IFC.REVIGRÉS-Dados de desempenho-Floor Covering - Rectilinearidade: ± 0.3% máx. ± 1.5 mm; Ortogonalidade: ± 0.3% máx. ± 1.8 mm; PlanaridadeDaSuperficie: ± 0.3% máx. ± 1.8 mm; QualidadeDaSuperficie: Cumpre; AbsorcaoDeAgua: < 0.05%; ModuloDeRuptura: > 45 N/mm²; ResistenciaAFlexao: > 2000 N; ResistenciaAAbrasaoProfunda: < 120 mm³; DilatacaoTermicaLinear: ≤ 8,0x10-6 °C-1; ResistenciaAoChoqueTermico: Resiste; DurabilidadeResistenciaAoGeloDegelo: Resiste; ResistenciaAoEscorregamentoDIN51130: R9; ResistenciaAoEscorregamentoDIN51097: A; ResistenciaAoEscorregamentoENV51097: A; ResistenciaAoEscorregamentoENV12633: Class 1; ResistenciaAoEscorregamentoANSIA1371: ≥0,42; ResistenciaAoDeslizamentoENV12633: Class 1; ResistenciaAsManchas: Class 5; ResistenciaABaixasConcentracoesDeAcidosEAlcalis: Classe LA; ResistenciaAAltasConcentracoesDeAcidosEAlcalis: Classe HA; LibertacaoDeCadmio: 0; LibertacaoDeChumbo: 0
Type - IFC.REVIGRÉS-Dados de especificação-Floor Covering - VariacaoTonalidade: 3; NivelDeTrafego: 4; EPavimento: Sim; ERevestimento: Sim; EExterno: Sim
Type - IFC.REVIGRÉS-Dados geométricos-Floor Covering - AlturaNominal: 8.5 mm; ComprimentoNominal: 45 mm; LarguraNominal: 45 mm
Type - IFC.REVIGRÉS-Dados de sustentabilidade-Floor Covering - EnergiaTermicaExportada: 0; ItemENovo: Sim; ItemEParcialmenteReciclado: 0.19; ItemEReciclado: Sim; VidaÚtilEsperada: 50; SubstanciasPerigosas: Não; PotencialDeEsgotamentoAbioticoDosRecursosFosseis: 203; PotencialDeEsgotamentoAbioticoDosRecursosNaoFosseisMineraisEMetais: 0.000701; PotencialDeAquecimentoGlobalBiogenico: -0.48; CombustiveisFosseisComPotencialDeAquecimentoGlobal: 13.9; PotencialDeAquecimentoGlobalUsoDoSoloEMudancaDeUsoDoSolo: 0.0246; PotencialDeEutrofizacaoFraccaoDeNutrientesQueAtingemOCompartimentoFinalDeAguaDoce: 0.000189; PotencialDeEutrofizacaoFraccaoDeNutrientesQueAtingemOCompartimentoFinalMarinho: 0.0122; EnergiaRecuperada: 0.00739; ConsumoDeAguaDoce: 0.113; UtilizacaoLiquidaDeAguaDoce: 0.113; ResiduosPerigososEliminados: 0.00221; ResiduosNaoPerigososEliminados: 1.83; MassaTotalDeResiduosRadioactivosEliminados: 0.000394; EnergiaElectricaExportada: 1.55; MateriaisParaRecuperacaoDeEnergia: 0.00739; MateriaisParaReciclagem: 0.0253; UnidadeEPD: 1 m²
Type - IFC.REVIGRÉS-Dados gerais-Floor Covering - Nome: REVIGRÉS-URBAN-BASE-45X45-NAT-HYDRAULIK CRAFT; TipoProduto: Prensado a seco: grupo BIa UGL | Grés porcelânico técnico; NumeroDeRegistoDAP: EPD-REV-20240006-CCC1-EN; ReferenciaDAP: -; UrlDOP: -
Classification: C3020 (Uniformat)
Pset_CoveringCommon - TotalThickness: 8.5 mm
IFC.REVIGRÉS-Dados do fabricante-Floor Covering - Type: Floor: REVIGRÉS-URBAN-BASE-45X45-NAT HYDRAULIK CRAFT
IFC.REVIGRÉS-Dados de desempenho-Floor Covering - Type: Floor: REVIGRÉS-URBAN-BASE-45X45-NAT HYDRAULIK CRAFT
IFC.REVIGRÉS-Dados de especificação-Floor Covering - Type: Floor: REVIGRÉS-URBAN-BASE-45X45-NAT HYDRAULIK CRAFT
IFC.REVIGRÉS-Dados geométricos-Floor Covering - Type: Floor: REVIGRÉS-URBAN-BASE-45X45-NAT HYDRAULIK CRAFT
IFC.REVIGRÉS-Dados de sustentabilidade-Floor Covering - Type: Floor: REVIGRÉS-URBAN-BASE-45X45-NAT HYDRAULIK CRAFT

# IfcCovering: Floor:REVIGRÉS-URBAN-BASE-45X45-NAT HYDRAULIK FOG, Floor:REVIGRÉS-URBAN-BASE-45X45-NAT HYDRAULIK FOG:27377
In: Level 1
Type - PredefinedType: CLADDING; Material: REVIGRÉS-URBAN-BASE-45X45-NAT-HYDRAULIK FOG 8.5 mm
Type - Pset_CoveringCommon - Reference: 31200756T1; Material: Grés porcelânico
Type - Pset_ElementShading - Roughness: 304.8 mm
Type - Pset_ManufacturerTypeInformation - Manufacturer: REVIGRÉS
Type - Pset_ProductRequirements - Category: Floors
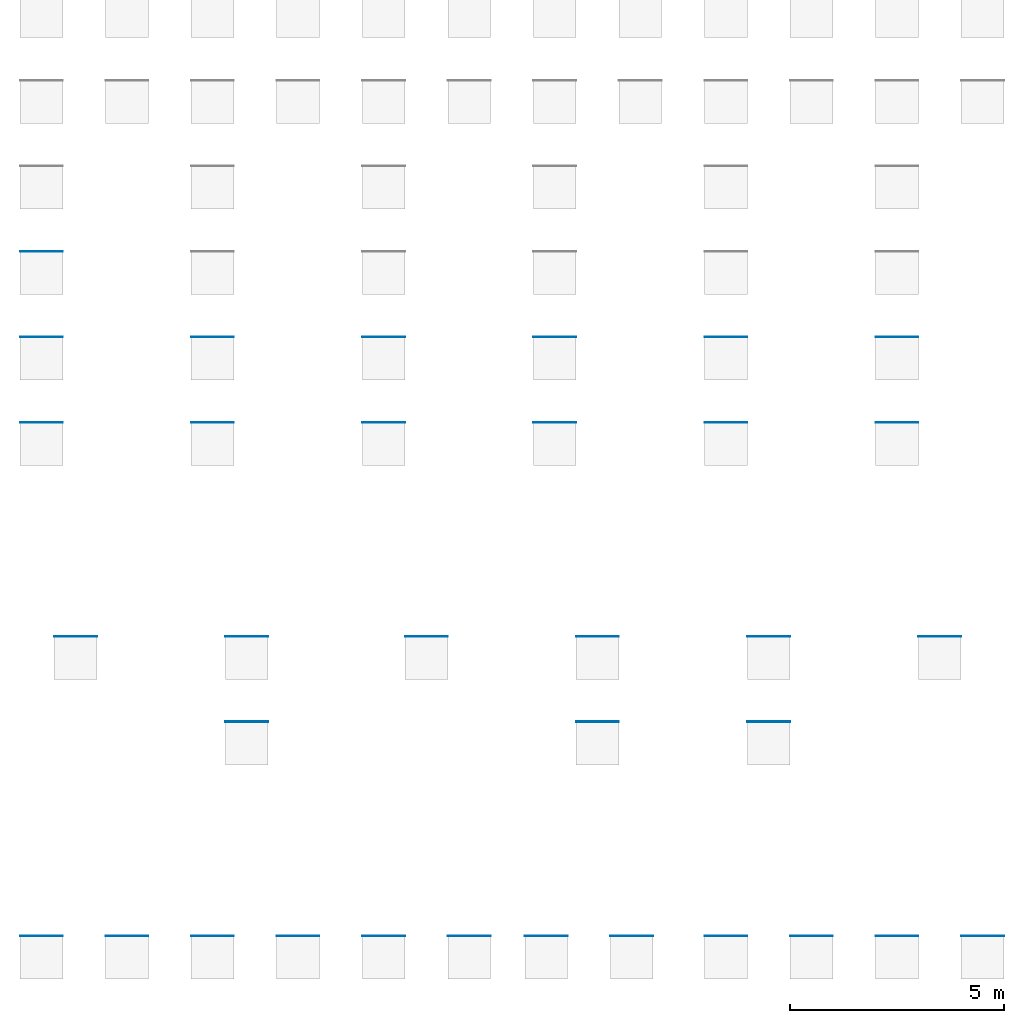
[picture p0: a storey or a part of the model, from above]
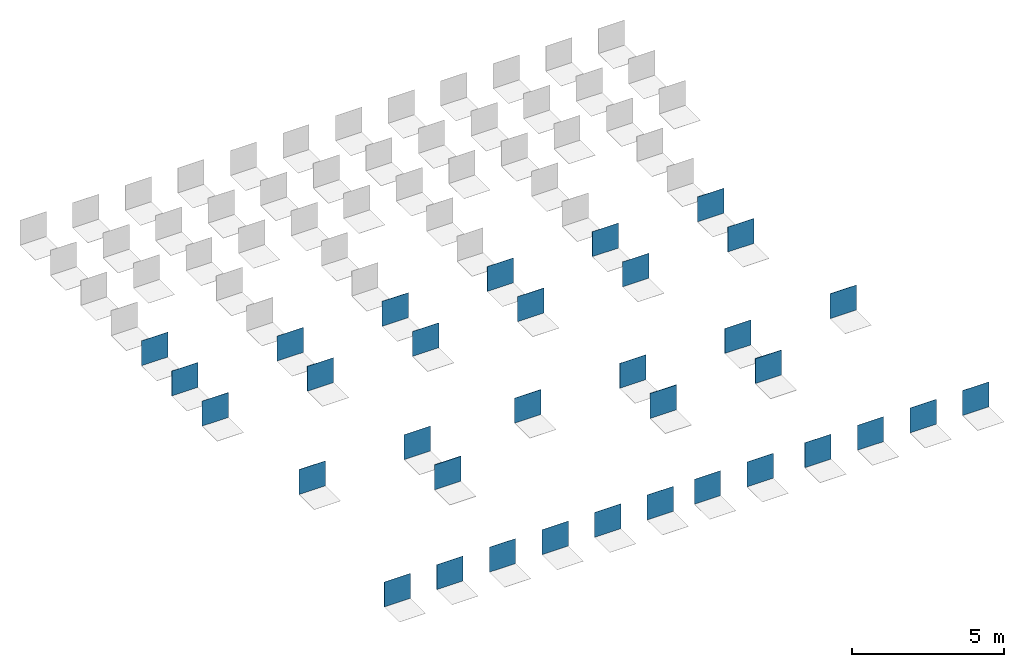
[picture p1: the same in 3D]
Properties of the parts of a building model (IFC2X3), part 4 of 12

# IfcCovering: Floor:REVIGRÉS-URBAN-BASE-45X45-NAT HYDRAULIK FOG, Floor:REVIGRÉS-URBAN-BASE-45X45-NAT HYDRAULIK FOG:27377
Type - Pset_QuantityTakeOff - Reference: 31200756T1
Type - IFC.REVIGRÉS-Dados do fabricante-Floor Covering - FabricanteURL: https://www.revigres.pt/; ReferenciaModelo: Urban; NumeroGlobalDeItemComercial: 31200756T1; Acabamento: NAT; Material: Grés porcelânico; IdentificadorDoOperadorEconomico: 501840856; UrlFabricanteArtigo: https://www.revigres.pt/colecoes/urban; PaisOrigem: Portugal
Type - IFC.REVIGRÉS-Dados de desempenho-Floor Covering - Rectilinearidade: ± 0.3% máx. ± 1.5 mm; Ortogonalidade: ± 0.3% máx. ± 1.8 mm; PlanaridadeDaSuperficie: ± 0.3% máx. ± 1.8 mm; QualidadeDaSuperficie: Cumpre; AbsorcaoDeAgua: < 0.05%; ModuloDeRuptura: > 45 N/mm²; ResistenciaAFlexao: > 2000 N; ResistenciaAAbrasaoProfunda: < 120 mm³; DilatacaoTermicaLinear: ≤ 8,0x10-6 °C-1; ResistenciaAoChoqueTermico: Resiste; DurabilidadeResistenciaAoGeloDegelo: Resiste; ResistenciaAoEscorregamentoDIN51130: R9; ResistenciaAoEscorregamentoDIN51097: A; ResistenciaAoEscorregamentoENV51097: A; ResistenciaAoEscorregamentoENV12633: Class 1; ResistenciaAoEscorregamentoANSIA1371: ≥0,42; ResistenciaAoDeslizamentoENV12633: Class 1; ResistenciaAsManchas: Class 5; ResistenciaABaixasConcentracoesDeAcidosEAlcalis: Classe LA; ResistenciaAAltasConcentracoesDeAcidosEAlcalis: Classe HA; LibertacaoDeCadmio: 0; LibertacaoDeChumbo: 0
Type - IFC.REVIGRÉS-Dados de especificação-Floor Covering - VariacaoTonalidade: 3; NivelDeTrafego: 4; EPavimento: Sim; ERevestimento: Sim; EExterno: Sim
Type - IFC.REVIGRÉS-Dados geométricos-Floor Covering - AlturaNominal: 8.5 mm; ComprimentoNominal: 45 mm; LarguraNominal: 45 mm
Type - IFC.REVIGRÉS-Dados de sustentabilidade-Floor Covering - EnergiaTermicaExportada: 0; ItemENovo: Sim; ItemEParcialmenteReciclado: 0.23; ItemEReciclado: Sim; VidaÚtilEsperada: 50; SubstanciasPerigosas: Não; PotencialDeEsgotamentoAbioticoDosRecursosFosseis: 203; PotencialDeEsgotamentoAbioticoDosRecursosNaoFosseisMineraisEMetais: 0.000701; PotencialDeAquecimentoGlobalBiogenico: -0.48; CombustiveisFosseisComPotencialDeAquecimentoGlobal: 13.9; PotencialDeAquecimentoGlobalUsoDoSoloEMudancaDeUsoDoSolo: 0.0246; PotencialDeEutrofizacaoFraccaoDeNutrientesQueAtingemOCompartimentoFinalDeAguaDoce: 0.000189; PotencialDeEutrofizacaoFraccaoDeNutrientesQueAtingemOCompartimentoFinalMarinho: 0.0122; EnergiaRecuperada: 0.00739; ConsumoDeAguaDoce: 0.113; UtilizacaoLiquidaDeAguaDoce: 0.113; ResiduosPerigososEliminados: 0.00221; ResiduosNaoPerigososEliminados: 1.83; MassaTotalDeResiduosRadioactivosEliminados: 0.000394; EnergiaElectricaExportada: 1.55; MateriaisParaRecuperacaoDeEnergia: 0.00739; MateriaisParaReciclagem: 0.0253; UnidadeEPD: 1 m²
Type - IFC.REVIGRÉS-Dados gerais-Floor Covering - Nome: REVIGRÉS-URBAN-BASE-45X45-NAT-HYDRAULIK FOG; TipoProduto: Prensado a seco: grupo BIa UGL | Grés porcelânico técnico; NumeroDeRegistoDAP: EPD-REV-20240006-CCC1-EN; ReferenciaDAP: -; UrlDOP: -
Classification: C3020 (Uniformat)
Pset_CoveringCommon - TotalThickness: 8.5 mm
IFC.REVIGRÉS-Dados do fabricante-Floor Covering - Type: Floor: REVIGRÉS-URBAN-BASE-45X45-NAT HYDRAULIK FOG
IFC.REVIGRÉS-Dados de desempenho-Floor Covering - Type: Floor: REVIGRÉS-URBAN-BASE-45X45-NAT HYDRAULIK FOG
IFC.REVIGRÉS-Dados de especificação-Floor Covering - Type: Floor: REVIGRÉS-URBAN-BASE-45X45-NAT HYDRAULIK FOG
IFC.REVIGRÉS-Dados geométricos-Floor Covering - Type: Floor: REVIGRÉS-URBAN-BASE-45X45-NAT HYDRAULIK FOG
IFC.REVIGRÉS-Dados de sustentabilidade-Floor Covering - Type: Floor: REVIGRÉS-URBAN-BASE-45X45-NAT HYDRAULIK FOG

# IfcCovering: Floor:REVIGRÉS-URBAN-BASE-45X45-NAT HYDRAULIK GRIS, Floor:REVIGRÉS-URBAN-BASE-45X45-NAT HYDRAULIK GRIS:27393
In: Level 1
Type - PredefinedType: CLADDING; Material: REVIGRÉS-URBAN-BASE-45X45-NAT-HYDRAULIK GRIS 8.5 mm
Type - Pset_CoveringCommon - Reference: 31200757T1; Material: Grés porcelânico
Type - Pset_ElementShading - Roughness: 304.8 mm
Type - Pset_ManufacturerTypeInformation - Manufacturer: REVIGRÉS
Type - Pset_ProductRequirements - Category: Floors
Type - Pset_QuantityTakeOff - Reference: 31200757T1
Type - IFC.REVIGRÉS-Dados do fabricante-Floor Covering - FabricanteURL: https://www.revigres.pt/; ReferenciaModelo: Urban; NumeroGlobalDeItemComercial: 31200757T1; Acabamento: NAT; Material: Grés porcelânico; IdentificadorDoOperadorEconomico: 501840856; UrlFabricanteArtigo: https://www.revigres.pt/colecoes/urban; PaisOrigem: Portugal
Type - IFC.REVIGRÉS-Dados de desempenho-Floor Covering - Rectilinearidade: ± 0.3% máx. ± 1.5 mm; Ortogonalidade: ± 0.3% máx. ± 1.8 mm; PlanaridadeDaSuperficie: ± 0.3% máx. ± 1.8 mm; QualidadeDaSuperficie: Cumpre; AbsorcaoDeAgua: < 0.05%; ModuloDeRuptura: > 45 N/mm²; ResistenciaAFlexao: > 2000 N; ResistenciaAAbrasaoProfunda: < 120 mm³; DilatacaoTermicaLinear: ≤ 8,0x10-6 °C-1; ResistenciaAoChoqueTermico: Resiste; DurabilidadeResistenciaAoGeloDegelo: Resiste; ResistenciaAoEscorregamentoDIN51130: R9; ResistenciaAoEscorregamentoDIN51097: A; ResistenciaAoEscorregamentoENV51097: A; ResistenciaAoEscorregamentoENV12633: Class 1; ResistenciaAoEscorregamentoANSIA1371: ≥0,42; ResistenciaAoDeslizamentoENV12633: Class 1; ResistenciaAsManchas: Class 5; ResistenciaABaixasConcentracoesDeAcidosEAlcalis: Classe LA; ResistenciaAAltasConcentracoesDeAcidosEAlcalis: Classe HA; LibertacaoDeCadmio: 0; LibertacaoDeChumbo: 0
Type - IFC.REVIGRÉS-Dados de especificação-Floor Covering - VariacaoTonalidade: 3; NivelDeTrafego: 4; EPavimento: Sim; ERevestimento: Sim; EExterno: Sim
Type - IFC.REVIGRÉS-Dados geométricos-Floor Covering - AlturaNominal: 8.5 mm; ComprimentoNominal: 45 mm; LarguraNominal: 45 mm
Type - IFC.REVIGRÉS-Dados de sustentabilidade-Floor Covering - EnergiaTermicaExportada: 0; ItemENovo: Sim; ItemEParcialmenteReciclado: 0.23; ItemEReciclado: Sim; VidaÚtilEsperada: 50; SubstanciasPerigosas: Não; PotencialDeEsgotamentoAbioticoDosRecursosFosseis: 203; PotencialDeEsgotamentoAbioticoDosRecursosNaoFosseisMineraisEMetais: 0.000701; PotencialDeAquecimentoGlobalBiogenico: -0.48; CombustiveisFosseisComPotencialDeAquecimentoGlobal: 13.9; PotencialDeAquecimentoGlobalUsoDoSoloEMudancaDeUsoDoSolo: 0.0246; PotencialDeEutrofizacaoFraccaoDeNutrientesQueAtingemOCompartimentoFinalDeAguaDoce: 0.000189; PotencialDeEutrofizacaoFraccaoDeNutrientesQueAtingemOCompartimentoFinalMarinho: 0.0122; EnergiaRecuperada: 0.00739; ConsumoDeAguaDoce: 0.113; UtilizacaoLiquidaDeAguaDoce: 0.113; ResiduosPerigososEliminados: 0.00221; ResiduosNaoPerigososEliminados: 1.83; MassaTotalDeResiduosRadioactivosEliminados: 0.000394; EnergiaElectricaExportada: 1.55; MateriaisParaRecuperacaoDeEnergia: 0.00739; MateriaisParaReciclagem: 0.0253; UnidadeEPD: 1 m²
Type - IFC.REVIGRÉS-Dados gerais-Floor Covering - Nome: REVIGRÉS-URBAN-BASE-45X45-NAT-HYDRAULIK GRIS; TipoProduto: Prensado a seco: grupo BIa UGL | Grés porcelânico técnico; NumeroDeRegistoDAP: EPD-REV-20240006-CCC1-EN; ReferenciaDAP: -; UrlDOP: -
Classification: C3020 (Uniformat)
Pset_CoveringCommon - TotalThickness: 8.5 mm
IFC.REVIGRÉS-Dados do fabricante-Floor Covering - Type: Floor: REVIGRÉS-URBAN-BASE-45X45-NAT HYDRAULIK GRIS
IFC.REVIGRÉS-Dados de desempenho-Floor Covering - Type: Floor: REVIGRÉS-URBAN-BASE-45X45-NAT HYDRAULIK GRIS
IFC.REVIGRÉS-Dados de especificação-Floor Covering - Type: Floor: REVIGRÉS-URBAN-BASE-45X45-NAT HYDRAULIK GRIS
IFC.REVIGRÉS-Dados geométricos-Floor Covering - Type: Floor: REVIGRÉS-URBAN-BASE-45X45-NAT HYDRAULIK GRIS
IFC.REVIGRÉS-Dados de sustentabilidade-Floor Covering - Type: Floor: REVIGRÉS-URBAN-BASE-45X45-NAT HYDRAULIK GRIS

# IfcCovering: Floor:REVIGRÉS-URBAN-BASE-45X45-NAT HYDRAULIK OFFWHITE, Floor:REVIGRÉS-URBAN-BASE-45X45-NAT HYDRAULIK OFFWHITE:27409
In: Level 1
Type - PredefinedType: CLADDING; Material: REVIGRÉS-URBAN-BASE-45X45-NAT-HYDRAULIK OFFWHITE 8.5 mm
Type - Pset_CoveringCommon - Reference: 31200758T1; Material: Grés porcelânico
Type - Pset_ElementShading - Roughness: 304.8 mm
Type - Pset_ManufacturerTypeInformation - Manufacturer: REVIGRÉS
Type - Pset_ProductRequirements - Category: Floors
Type - Pset_QuantityTakeOff - Reference: 31200758T1
Type - IFC.REVIGRÉS-Dados do fabricante-Floor Covering - FabricanteURL: https://www.revigres.pt/; ReferenciaModelo: Urban; NumeroGlobalDeItemComercial: 31200758T1; Acabamento: NAT; Material: Grés porcelânico; IdentificadorDoOperadorEconomico: 501840856; UrlFabricanteArtigo: https://www.revigres.pt/colecoes/urban; PaisOrigem: Portugal
Type - IFC.REVIGRÉS-Dados de desempenho-Floor Covering - Rectilinearidade: ± 0.3% máx. ± 1.5 mm; Ortogonalidade: ± 0.3% máx. ± 1.8 mm; PlanaridadeDaSuperficie: ± 0.3% máx. ± 1.8 mm; QualidadeDaSuperficie: Cumpre; AbsorcaoDeAgua: < 0.05%; ModuloDeRuptura: > 45 N/mm²; ResistenciaAFlexao: > 2000 N; ResistenciaAAbrasaoProfunda: < 120 mm³; DilatacaoTermicaLinear: ≤ 8,0x10-6 °C-1; ResistenciaAoChoqueTermico: Resiste; DurabilidadeResistenciaAoGeloDegelo: Resiste; ResistenciaAoEscorregamentoDIN51130: R9; ResistenciaAoEscorregamentoDIN51097: A; ResistenciaAoEscorregamentoENV51097: A; ResistenciaAoEscorregamentoENV12633: Class 1; ResistenciaAoEscorregamentoANSIA1371: ≥0,42; ResistenciaAoDeslizamentoENV12633: Class 1; ResistenciaAsManchas: Class 5; ResistenciaABaixasConcentracoesDeAcidosEAlcalis: Classe LA; ResistenciaAAltasConcentracoesDeAcidosEAlcalis: Classe HA; LibertacaoDeCadmio: 0; LibertacaoDeChumbo: 0
Type - IFC.REVIGRÉS-Dados de especificação-Floor Covering - VariacaoTonalidade: 3; NivelDeTrafego: 4; EPavimento: Sim; ERevestimento: Sim; EExterno: Sim
Type - IFC.REVIGRÉS-Dados geométricos-Floor Covering - AlturaNominal: 8.5 mm; ComprimentoNominal: 45 mm; LarguraNominal: 45 mm
Type - IFC.REVIGRÉS-Dados de sustentabilidade-Floor Covering - EnergiaTermicaExportada: 0; ItemENovo: Sim; ItemEParcialmenteReciclado: 0.03; ItemEReciclado: Sim; VidaÚtilEsperada: 50; SubstanciasPerigosas: Não; PotencialDeEsgotamentoAbioticoDosRecursosFosseis: 203; PotencialDeEsgotamentoAbioticoDosRecursosNaoFosseisMineraisEMetais: 0.000701; PotencialDeAquecimentoGlobalBiogenico: -0.48; CombustiveisFosseisComPotencialDeAquecimentoGlobal: 13.9; PotencialDeAquecimentoGlobalUsoDoSoloEMudancaDeUsoDoSolo: 0.0246; PotencialDeEutrofizacaoFraccaoDeNutrientesQueAtingemOCompartimentoFinalDeAguaDoce: 0.000189; PotencialDeEutrofizacaoFraccaoDeNutrientesQueAtingemOCompartimentoFinalMarinho: 0.0122; EnergiaRecuperada: 0.00739; ConsumoDeAguaDoce: 0.113; UtilizacaoLiquidaDeAguaDoce: 0.113; ResiduosPerigososEliminados: 0.00221; ResiduosNaoPerigososEliminados: 1.83; MassaTotalDeResiduosRadioactivosEliminados: 0.000394; EnergiaElectricaExportada: 1.55; MateriaisParaRecuperacaoDeEnergia: 0.00739; MateriaisParaReciclagem: 0.0253; UnidadeEPD: 1 m²
Type - IFC.REVIGRÉS-Dados gerais-Floor Covering - Nome: REVIGRÉS-URBAN-BASE-45X45-NAT-HYDRAULIK OFFWHITE; TipoProduto: Prensado a seco: grupo BIa UGL | Grés porcelânico técnico; NumeroDeRegistoDAP: EPD-REV-20240006-CCC1-EN; ReferenciaDAP: -; UrlDOP: -
Classification: C3020 (Uniformat)
Pset_CoveringCommon - TotalThickness: 8.5 mm
IFC.REVIGRÉS-Dados do fabricante-Floor Covering - Type: Floor: REVIGRÉS-URBAN-BASE-45X45-NAT HYDRAULIK OFFWHITE
IFC.REVIGRÉS-Dados de desempenho-Floor Covering - Type: Floor: REVIGRÉS-URBAN-BASE-45X45-NAT HYDRAULIK OFFWHITE
IFC.REVIGRÉS-Dados de especificação-Floor Covering - Type: Floor: REVIGRÉS-URBAN-BASE-45X45-NAT HYDRAULIK OFFWHITE
IFC.REVIGRÉS-Dados geométricos-Floor Covering - Type: Floor: REVIGRÉS-URBAN-BASE-45X45-NAT HYDRAULIK OFFWHITE
IFC.REVIGRÉS-Dados de sustentabilidade-Floor Covering - Type: Floor: REVIGRÉS-URBAN-BASE-45X45-NAT HYDRAULIK OFFWHITE

# IfcCovering: Floor:REVIGRÉS-URBAN-BASE-45X45-NAT-ANTRACITE, Floor:REVIGRÉS-URBAN-BASE-45X45-NAT-ANTRACITE:22710
In: Level 1
Type - PredefinedType: CLADDING; Material: REVIGRÉS-URBAN-BASE-45X45-NAT-ANTRACITE 8.5 mm
Type - Pset_CoveringCommon - Reference: 31200748U1; Material: Grés porcelânico
Type - Pset_ElementShading - Roughness: 304.8 mm
Type - Pset_ManufacturerTypeInformation - Manufacturer: REVIGRÉS
Type - Pset_ProductRequirements - Category: Floors
Type - Pset_QuantityTakeOff - Reference: 31200748U1
Type - IFC.REVIGRÉS-Dados do fabricante-Floor Covering - FabricanteURL: https://www.revigres.pt/; ReferenciaModelo: Urban; NumeroGlobalDeItemComercial: 31200748U1; Acabamento: NAT; Material: Grés porcelânico; IdentificadorDoOperadorEconomico: 501840856; UrlFabricanteArtigo: https://www.revigres.pt/colecoes/urban; PaisOrigem: Portugal
Type - IFC.REVIGRÉS-Dados de desempenho-Floor Covering - Rectilinearidade: ± 0.3% máx. ± 1.5 mm; Ortogonalidade: ± 0.3% máx. ± 1.8 mm; PlanaridadeDaSuperficie: ± 0.3% máx. ± 1.8 mm; QualidadeDaSuperficie: Cumpre; AbsorcaoDeAgua: < 0.05%; ModuloDeRuptura: > 45 N/mm²; ResistenciaAFlexao: > 2000 N; ResistenciaAAbrasaoProfunda: < 120 mm³; DilatacaoTermicaLinear: ≤ 8,0x10-6 °C-1; ResistenciaAoChoqueTermico: Resiste; DurabilidadeResistenciaAoGeloDegelo: Resiste; ResistenciaAoEscorregamentoDIN51130: R9; ResistenciaAoEscorregamentoDIN51097: A; ResistenciaAoEscorregamentoENV51097: A; ResistenciaAoEscorregamentoENV12633: Class 1; ResistenciaAoEscorregamentoANSIA1371: ≥0,42; ResistenciaAoDeslizamentoENV12633: Class 1; ResistenciaAsManchas: Class 5; ResistenciaABaixasConcentracoesDeAcidosEAlcalis: Classe LA; ResistenciaAAltasConcentracoesDeAcidosEAlcalis: Classe HA; LibertacaoDeCadmio: 0; LibertacaoDeChumbo: 0
Type - IFC.REVIGRÉS-Dados de especificação-Floor Covering - VariacaoTonalidade: 2; NivelDeTrafego: 5; EPavimento: Sim; ERevestimento: Sim; EExterno: Sim
Type - IFC.REVIGRÉS-Dados geométricos-Floor Covering - AlturaNominal: 8.5 mm; ComprimentoNominal: 45 mm; LarguraNominal: 45 mm
Type - IFC.REVIGRÉS-Dados de sustentabilidade-Floor Covering - EnergiaTermicaExportada: 0; ItemENovo: Sim; ItemEParcialmenteReciclado: 0.29; ItemEReciclado: Sim; VidaÚtilEsperada: 50; SubstanciasPerigosas: Não; PotencialDeEsgotamentoAbioticoDosRecursosFosseis: 203; PotencialDeEsgotamentoAbioticoDosRecursosNaoFosseisMineraisEMetais: 0.000701; PotencialDeAquecimentoGlobalBiogenico: -0.48; CombustiveisFosseisComPotencialDeAquecimentoGlobal: 13.9; PotencialDeAquecimentoGlobalUsoDoSoloEMudancaDeUsoDoSolo: 0.0246; PotencialDeEutrofizacaoFraccaoDeNutrientesQueAtingemOCompartimentoFinalDeAguaDoce: 0.000189; PotencialDeEutrofizacaoFraccaoDeNutrientesQueAtingemOCompartimentoFinalMarinho: 0.0122; EnergiaRecuperada: 0.00739; ConsumoDeAguaDoce: 0.113; UtilizacaoLiquidaDeAguaDoce: 0.113; ResiduosPerigososEliminados: 0.00221; ResiduosNaoPerigososEliminados: 1.83; MassaTotalDeResiduosRadioactivosEliminados: 0.000394; EnergiaElectricaExportada: 1.55; MateriaisParaRecuperacaoDeEnergia: 0.00739; MateriaisParaReciclagem: 0.0253; UnidadeEPD: 1 m²
Type - IFC.REVIGRÉS-Dados gerais-Floor Covering - Nome: REVIGRÉS-URBAN-BASE-45X45-NAT-URBAN ANTRACITE; TipoProduto: Prensado a seco: grupo BIa UGL | Grés porcelânico técnico; NumeroDeRegistoDAP: EPD-REV-20240006-CCC1-EN; ReferenciaDAP: -; UrlDOP: -
Classification: C3020 (Uniformat)
Pset_CoveringCommon - TotalThickness: 8.5 mm
IFC.REVIGRÉS-Dados do fabricante-Floor Covering - Type: Floor: REVIGRÉS-URBAN-BASE-45X45-NAT-ANTRACITE
IFC.REVIGRÉS-Dados de desempenho-Floor Covering - Type: Floor: REVIGRÉS-URBAN-BASE-45X45-NAT-ANTRACITE
IFC.REVIGRÉS-Dados de especificação-Floor Covering - Type: Floor: REVIGRÉS-URBAN-BASE-45X45-NAT-ANTRACITE
IFC.REVIGRÉS-Dados geométricos-Floor Covering - Type: Floor: REVIGRÉS-URBAN-BASE-45X45-NAT-ANTRACITE
IFC.REVIGRÉS-Dados de sustentabilidade-Floor Covering - Type: Floor: REVIGRÉS-URBAN-BASE-45X45-NAT-ANTRACITE

# IfcCovering: Floor:REVIGRÉS-URBAN-BASE-45X45-NAT-BONE, Floor:REVIGRÉS-URBAN-BASE-45X45-NAT-BONE:22726
In: Level 1
Type - PredefinedType: CLADDING; Material: REVIGRÉS-URBAN-BASE-45X45-NAT-BONE 8.5 mm
Type - Pset_CoveringCommon - Reference: 31200720T1; Material: Grés porcelânico
Type - Pset_ElementShading - Roughness: 304.8 mm
Type - Pset_ManufacturerTypeInformation - Manufacturer: REVIGRÉS
Type - Pset_ProductRequirements - Category: Floors
Type - Pset_QuantityTakeOff - Reference: 31200720T1
Type - IFC.REVIGRÉS-Dados do fabricante-Floor Covering - FabricanteURL: https://www.revigres.pt/; ReferenciaModelo: Urban; NumeroGlobalDeItemComercial: 31200720T1; Acabamento: NAT; Material: Grés porcelânico; IdentificadorDoOperadorEconomico: 501840856; UrlFabricanteArtigo: https://www.revigres.pt/colecoes/urban; PaisOrigem: Portugal
Type - IFC.REVIGRÉS-Dados de desempenho-Floor Covering - Rectilinearidade: ± 0.3% máx. ± 1.5 mm; Ortogonalidade: ± 0.3% máx. ± 1.8 mm; PlanaridadeDaSuperficie: ± 0.3% máx. ± 1.8 mm; QualidadeDaSuperficie: Cumpre; AbsorcaoDeAgua: < 0.05%; ModuloDeRuptura: > 45 N/mm²; ResistenciaAFlexao: > 2000 N; ResistenciaAAbrasaoProfunda: < 120 mm³; DilatacaoTermicaLinear: ≤ 8,0x10-6 °C-1; ResistenciaAoChoqueTermico: Resiste; DurabilidadeResistenciaAoGeloDegelo: Resiste; ResistenciaAoEscorregamentoDIN51130: R9; ResistenciaAoEscorregamentoDIN51097: A; ResistenciaAoEscorregamentoENV51097: A; ResistenciaAoEscorregamentoENV12633: Class 1; ResistenciaAoEscorregamentoANSIA1371: ≥0,42; ResistenciaAoDeslizamentoENV12633: Class 1; ResistenciaAsManchas: Class 5; ResistenciaABaixasConcentracoesDeAcidosEAlcalis: Classe LA; ResistenciaAAltasConcentracoesDeAcidosEAlcalis: Classe HA; LibertacaoDeCadmio: 0; LibertacaoDeChumbo: 0
Type - IFC.REVIGRÉS-Dados de especificação-Floor Covering - VariacaoTonalidade: 2; NivelDeTrafego: 5; EPavimento: Sim; ERevestimento: Sim; EExterno: Sim
Type - IFC.REVIGRÉS-Dados geométricos-Floor Covering - AlturaNominal: 8.5 mm; ComprimentoNominal: 45 mm; LarguraNominal: 45 mm
Type - IFC.REVIGRÉS-Dados de sustentabilidade-Floor Covering - EnergiaTermicaExportada: 0; ItemENovo: Sim; ItemEParcialmenteReciclado: 0.03; ItemEReciclado: Sim; VidaÚtilEsperada: 50; SubstanciasPerigosas: Não; PotencialDeEsgotamentoAbioticoDosRecursosFosseis: 203; PotencialDeEsgotamentoAbioticoDosRecursosNaoFosseisMineraisEMetais: 0.000701; PotencialDeAquecimentoGlobalBiogenico: -0.48; CombustiveisFosseisComPotencialDeAquecimentoGlobal: 13.9; PotencialDeAquecimentoGlobalUsoDoSoloEMudancaDeUsoDoSolo: 0.0246; PotencialDeEutrofizacaoFraccaoDeNutrientesQueAtingemOCompartimentoFinalDeAguaDoce: 0.000189; PotencialDeEutrofizacaoFraccaoDeNutrientesQueAtingemOCompartimentoFinalMarinho: 0.0122; EnergiaRecuperada: 0.00739; ConsumoDeAguaDoce: 0.113; UtilizacaoLiquidaDeAguaDoce: 0.113; ResiduosPerigososEliminados: 0.00221; ResiduosNaoPerigososEliminados: 1.83; MassaTotalDeResiduosRadioactivosEliminados: 0.000394; EnergiaElectricaExportada: 1.55; MateriaisParaRecuperacaoDeEnergia: 0.00739; MateriaisParaReciclagem: 0.0253; UnidadeEPD: 1 m²
Type - IFC.REVIGRÉS-Dados gerais-Floor Covering - Nome: REVIGRÉS-URBAN-BASE-45X45-NAT-URBAN BONE; TipoProduto: Prensado a seco: grupo BIa UGL | Grés porcelânico técnico; NumeroDeRegistoDAP: EPD-REV-20240006-CCC1-EN; ReferenciaDAP: -; UrlDOP: -
Classification: C3020 (Uniformat)
Pset_CoveringCommon - TotalThickness: 8.5 mm
IFC.REVIGRÉS-Dados do fabricante-Floor Covering - Type: Floor: REVIGRÉS-URBAN-BASE-45X45-NAT-BONE
IFC.REVIGRÉS-Dados de desempenho-Floor Covering - Type: Floor: REVIGRÉS-URBAN-BASE-45X45-NAT-BONE
IFC.REVIGRÉS-Dados de especificação-Floor Covering - Type: Floor: REVIGRÉS-URBAN-BASE-45X45-NAT-BONE
IFC.REVIGRÉS-Dados geométricos-Floor Covering - Type: Floor: REVIGRÉS-URBAN-BASE-45X45-NAT-BONE
IFC.REVIGRÉS-Dados de sustentabilidade-Floor Covering - Type: Floor: REVIGRÉS-URBAN-BASE-45X45-NAT-BONE

# IfcCovering: Floor:REVIGRÉS-URBAN-BASE-45X45-NAT-CRAFT, Floor:REVIGRÉS-URBAN-BASE-45X45-NAT-CRAFT:22742
In: Level 1
Type - PredefinedType: CLADDING; Material: REVIGRÉS-URBAN-BASE-45X45-NAT-CRAFT 8.5 mm
Type - Pset_CoveringCommon - Reference: 31200724T1; Material: Grés porcelânico
Type - Pset_ElementShading - Roughness: 304.8 mm
Type - Pset_ManufacturerTypeInformation - Manufacturer: REVIGRÉS
Type - Pset_ProductRequirements - Category: Floors
Type - Pset_QuantityTakeOff - Reference: 31200724T1
Type - IFC.REVIGRÉS-Dados do fabricante-Floor Covering - FabricanteURL: https://www.revigres.pt/; ReferenciaModelo: Urban; NumeroGlobalDeItemComercial: 31200724T1; Acabamento: NAT; Material: Grés porcelânico; IdentificadorDoOperadorEconomico: 501840856; UrlFabricanteArtigo: https://www.revigres.pt/colecoes/urban; PaisOrigem: Portugal
Type - IFC.REVIGRÉS-Dados de desempenho-Floor Covering - Rectilinearidade: ± 0.3% máx. ± 1.5 mm; Ortogonalidade: ± 0.3% máx. ± 1.8 mm; PlanaridadeDaSuperficie: ± 0.3% máx. ± 1.8 mm; QualidadeDaSuperficie: Cumpre; AbsorcaoDeAgua: < 0.05%; ModuloDeRuptura: > 45 N/mm²; ResistenciaAFlexao: > 2000 N; ResistenciaAAbrasaoProfunda: < 120 mm³; DilatacaoTermicaLinear: ≤ 8,0x10-6 °C-1; ResistenciaAoChoqueTermico: Resiste; DurabilidadeResistenciaAoGeloDegelo: Resiste; ResistenciaAoEscorregamentoDIN51130: R9; ResistenciaAoEscorregamentoDIN51097: A; ResistenciaAoEscorregamentoENV51097: A; ResistenciaAoEscorregamentoENV12633: Class 1; ResistenciaAoEscorregamentoANSIA1371: ≥0,42; ResistenciaAoDeslizamentoENV12633: Class 1; ResistenciaAsManchas: Class 5; ResistenciaABaixasConcentracoesDeAcidosEAlcalis: Classe LA; ResistenciaAAltasConcentracoesDeAcidosEAlcalis: Classe HA; LibertacaoDeCadmio: 0; LibertacaoDeChumbo: 0
Type - IFC.REVIGRÉS-Dados de especificação-Floor Covering - VariacaoTonalidade: 2; NivelDeTrafego: 5; EPavimento: Sim; ERevestimento: Sim; EExterno: Sim
Type - IFC.REVIGRÉS-Dados geométricos-Floor Covering - AlturaNominal: 8.5 mm; ComprimentoNominal: 45 mm; LarguraNominal: 45 mm
Type - IFC.REVIGRÉS-Dados de sustentabilidade-Floor Covering - EnergiaTermicaExportada: 0; ItemENovo: Sim; ItemEParcialmenteReciclado: 0.19; ItemEReciclado: Sim; VidaÚtilEsperada: 50; SubstanciasPerigosas: Não; PotencialDeEsgotamentoAbioticoDosRecursosFosseis: 203; PotencialDeEsgotamentoAbioticoDosRecursosNaoFosseisMineraisEMetais: 0.000701; PotencialDeAquecimentoGlobalBiogenico: -0.48; CombustiveisFosseisComPotencialDeAquecimentoGlobal: 13.9; PotencialDeAquecimentoGlobalUsoDoSoloEMudancaDeUsoDoSolo: 0.0246; PotencialDeEutrofizacaoFraccaoDeNutrientesQueAtingemOCompartimentoFinalDeAguaDoce: 0.000189; PotencialDeEutrofizacaoFraccaoDeNutrientesQueAtingemOCompartimentoFinalMarinho: 0.0122; EnergiaRecuperada: 0.00739; ConsumoDeAguaDoce: 0.113; UtilizacaoLiquidaDeAguaDoce: 0.113; ResiduosPerigososEliminados: 0.00221; ResiduosNaoPerigososEliminados: 1.83; MassaTotalDeResiduosRadioactivosEliminados: 0.000394; EnergiaElectricaExportada: 1.55; MateriaisParaRecuperacaoDeEnergia: 0.00739; MateriaisParaReciclagem: 0.0253; UnidadeEPD: 1 m²
Type - IFC.REVIGRÉS-Dados gerais-Floor Covering - Nome: REVIGRÉS-URBAN-BASE-45X45-NAT-URBAN CRAFT; TipoProduto: Prensado a seco: grupo BIa UGL | Grés porcelânico técnico; NumeroDeRegistoDAP: EPD-REV-20240006-CCC1-EN; ReferenciaDAP: -; UrlDOP: -
Classification: C3020 (Uniformat)
Pset_CoveringCommon - TotalThickness: 8.5 mm
IFC.REVIGRÉS-Dados do fabricante-Floor Covering - Type: Floor: REVIGRÉS-URBAN-BASE-45X45-NAT-CRAFT
IFC.REVIGRÉS-Dados de desempenho-Floor Covering - Type: Floor: REVIGRÉS-URBAN-BASE-45X45-NAT-CRAFT
IFC.REVIGRÉS-Dados de especificação-Floor Covering - Type: Floor: REVIGRÉS-URBAN-BASE-45X45-NAT-CRAFT
IFC.REVIGRÉS-Dados geométricos-Floor Covering - Type: Floor: REVIGRÉS-URBAN-BASE-45X45-NAT-CRAFT
IFC.REVIGRÉS-Dados de sustentabilidade-Floor Covering - Type: Floor: REVIGRÉS-URBAN-BASE-45X45-NAT-CRAFT

# IfcCovering: Floor:REVIGRÉS-URBAN-BASE-45X45-NAT-FOG, Floor:REVIGRÉS-URBAN-BASE-45X45-NAT-FOG:22758
In: Level 1
Type - PredefinedType: CLADDING; Material: REVIGRÉS-URBAN-BASE-45X45-NAT-FOG 8.5 mm
Type - Pset_CoveringCommon - Reference: 31200721T1; Material: Grés porcelânico
Type - Pset_ElementShading - Roughness: 304.8 mm
Type - Pset_ManufacturerTypeInformation - Manufacturer: REVIGRÉS
Type - Pset_ProductRequirements - Category: Floors
Type - Pset_QuantityTakeOff - Reference: 31200721T1
Type - IFC.REVIGRÉS-Dados do fabricante-Floor Covering - FabricanteURL: https://www.revigres.pt/; ReferenciaModelo: Urban; NumeroGlobalDeItemComercial: 31200721T1; Acabamento: NAT; Material: Grés porcelânico; IdentificadorDoOperadorEconomico: 501840856; UrlFabricanteArtigo: https://www.revigres.pt/colecoes/urban; PaisOrigem: Portugal
Type - IFC.REVIGRÉS-Dados de desempenho-Floor Covering - Rectilinearidade: ± 0.3% máx. ± 1.5 mm; Ortogonalidade: ± 0.3% máx. ± 1.8 mm; PlanaridadeDaSuperficie: ± 0.3% máx. ± 1.8 mm; QualidadeDaSuperficie: Cumpre; AbsorcaoDeAgua: < 0.05%; ModuloDeRuptura: > 45 N/mm²; ResistenciaAFlexao: > 2000 N; ResistenciaAAbrasaoProfunda: < 120 mm³; DilatacaoTermicaLinear: ≤ 8,0x10-6 °C-1; ResistenciaAoChoqueTermico: Resiste; DurabilidadeResistenciaAoGeloDegelo: Resiste; ResistenciaAoEscorregamentoDIN51130: R9; ResistenciaAoEscorregamentoDIN51097: A; ResistenciaAoEscorregamentoENV51097: A; ResistenciaAoEscorregamentoENV12633: Class 1; ResistenciaAoEscorregamentoANSIA1371: ≥0,42; ResistenciaAoDeslizamentoENV12633: Class 1; ResistenciaAsManchas: Class 5; ResistenciaABaixasConcentracoesDeAcidosEAlcalis: Classe LA; ResistenciaAAltasConcentracoesDeAcidosEAlcalis: Classe HA; LibertacaoDeCadmio: 0; LibertacaoDeChumbo: 0
Type - IFC.REVIGRÉS-Dados de especificação-Floor Covering - VariacaoTonalidade: 2; NivelDeTrafego: 5; EPavimento: Sim; ERevestimento: Sim; EExterno: Sim
Type - IFC.REVIGRÉS-Dados geométricos-Floor Covering - AlturaNominal: 8.5 mm; ComprimentoNominal: 45 mm; LarguraNominal: 45 mm
Type - IFC.REVIGRÉS-Dados de sustentabilidade-Floor Covering - EnergiaTermicaExportada: 0; ItemENovo: Sim; ItemEParcialmenteReciclado: 0.23; ItemEReciclado: Sim; VidaÚtilEsperada: 50; SubstanciasPerigosas: Não; PotencialDeEsgotamentoAbioticoDosRecursosFosseis: 203; PotencialDeEsgotamentoAbioticoDosRecursosNaoFosseisMineraisEMetais: 0.000701; PotencialDeAquecimentoGlobalBiogenico: -0.48; CombustiveisFosseisComPotencialDeAquecimentoGlobal: 13.9; PotencialDeAquecimentoGlobalUsoDoSoloEMudancaDeUsoDoSolo: 0.0246; PotencialDeEutrofizacaoFraccaoDeNutrientesQueAtingemOCompartimentoFinalDeAguaDoce: 0.000189; PotencialDeEutrofizacaoFraccaoDeNutrientesQueAtingemOCompartimentoFinalMarinho: 0.0122; EnergiaRecuperada: 0.00739; ConsumoDeAguaDoce: 0.113; UtilizacaoLiquidaDeAguaDoce: 0.113; ResiduosPerigososEliminados: 0.00221; ResiduosNaoPerigososEliminados: 1.83; MassaTotalDeResiduosRadioactivosEliminados: 0.000394; EnergiaElectricaExportada: 1.55; MateriaisParaRecuperacaoDeEnergia: 0.00739; MateriaisParaReciclagem: 0.0253; UnidadeEPD: 1 m²
Type - IFC.REVIGRÉS-Dados gerais-Floor Covering - Nome: REVIGRÉS-URBAN-BASE-45X45-NAT-URBAN FOG; TipoProduto: Prensado a seco: grupo BIa UGL | Grés porcelânico técnico; NumeroDeRegistoDAP: EPD-REV-20240006-CCC1-EN; ReferenciaDAP: -; UrlDOP: -
Classification: C3020 (Uniformat)
Pset_CoveringCommon - TotalThickness: 8.5 mm
IFC.REVIGRÉS-Dados do fabricante-Floor Covering - Type: Floor: REVIGRÉS-URBAN-BASE-45X45-NAT-FOG
IFC.REVIGRÉS-Dados de desempenho-Floor Covering - Type: Floor: REVIGRÉS-URBAN-BASE-45X45-NAT-FOG
IFC.REVIGRÉS-Dados de especificação-Floor Covering - Type: Floor: REVIGRÉS-URBAN-BASE-45X45-NAT-FOG
IFC.REVIGRÉS-Dados geométricos-Floor Covering - Type: Floor: REVIGRÉS-URBAN-BASE-45X45-NAT-FOG
IFC.REVIGRÉS-Dados de sustentabilidade-Floor Covering - Type: Floor: REVIGRÉS-URBAN-BASE-45X45-NAT-FOG

# IfcCovering: Floor:REVIGRÉS-URBAN-BASE-45X45-NAT-GRIS, Floor:REVIGRÉS-URBAN-BASE-45X45-NAT-GRIS:22774
In: Level 1
Type - PredefinedType: CLADDING; Material: REVIGRÉS-URBAN-BASE-45X45-NAT-GRIS 8.5 mm
Type - Pset_CoveringCommon - Reference: 31200722T1; Material: Grés porcelânico
Type - Pset_ElementShading - Roughness: 304.8 mm
Type - Pset_ManufacturerTypeInformation - Manufacturer: REVIGRÉS
Type - Pset_ProductRequirements - Category: Floors
Type - Pset_QuantityTakeOff - Reference: 31200722T1
Type - IFC.REVIGRÉS-Dados do fabricante-Floor Covering - FabricanteURL: https://www.revigres.pt/; ReferenciaModelo: Urban; NumeroGlobalDeItemComercial: 31200722T1; Acabamento: NAT; Material: Grés porcelânico; IdentificadorDoOperadorEconomico: 501840856; UrlFabricanteArtigo: https://www.revigres.pt/colecoes/urban; PaisOrigem: Portugal
Type - IFC.REVIGRÉS-Dados de desempenho-Floor Covering - Rectilinearidade: ± 0.3% máx. ± 1.5 mm; Ortogonalidade: ± 0.3% máx. ± 1.8 mm; PlanaridadeDaSuperficie: ± 0.3% máx. ± 1.8 mm; QualidadeDaSuperficie: Cumpre; AbsorcaoDeAgua: < 0.05%; ModuloDeRuptura: > 45 N/mm²; ResistenciaAFlexao: > 2000 N; ResistenciaAAbrasaoProfunda: < 120 mm³; DilatacaoTermicaLinear: ≤ 8,0x10-6 °C-1; ResistenciaAoChoqueTermico: Resiste; DurabilidadeResistenciaAoGeloDegelo: Resiste; ResistenciaAoEscorregamentoDIN51130: R9; ResistenciaAoEscorregamentoDIN51097: A; ResistenciaAoEscorregamentoENV51097: A; ResistenciaAoEscorregamentoENV12633: Class 1; ResistenciaAoEscorregamentoANSIA1371: ≥0,42; ResistenciaAoDeslizamentoENV12633: Class 1; ResistenciaAsManchas: Class 5; ResistenciaABaixasConcentracoesDeAcidosEAlcalis: Classe LA; ResistenciaAAltasConcentracoesDeAcidosEAlcalis: Classe HA; LibertacaoDeCadmio: 0; LibertacaoDeChumbo: 0
Type - IFC.REVIGRÉS-Dados de especificação-Floor Covering - VariacaoTonalidade: 2; NivelDeTrafego: 5; EPavimento: Sim; ERevestimento: Sim; EExterno: Sim
Type - IFC.REVIGRÉS-Dados geométricos-Floor Covering - AlturaNominal: 8.5 mm; ComprimentoNominal: 45 mm; LarguraNominal: 45 mm
Type - IFC.REVIGRÉS-Dados de sustentabilidade-Floor Covering - EnergiaTermicaExportada: 0; ItemENovo: Sim; ItemEParcialmenteReciclado: 0.23; ItemEReciclado: Sim; VidaÚtilEsperada: 50; SubstanciasPerigosas: Não; PotencialDeEsgotamentoAbioticoDosRecursosFosseis: 203; PotencialDeEsgotamentoAbioticoDosRecursosNaoFosseisMineraisEMetais: 0.000701; PotencialDeAquecimentoGlobalBiogenico: -0.48; CombustiveisFosseisComPotencialDeAquecimentoGlobal: 13.9; PotencialDeAquecimentoGlobalUsoDoSoloEMudancaDeUsoDoSolo: 0.0246; PotencialDeEutrofizacaoFraccaoDeNutrientesQueAtingemOCompartimentoFinalDeAguaDoce: 0.000189; PotencialDeEutrofizacaoFraccaoDeNutrientesQueAtingemOCompartimentoFinalMarinho: 0.0122; EnergiaRecuperada: 0.00739; ConsumoDeAguaDoce: 0.113; UtilizacaoLiquidaDeAguaDoce: 0.113; ResiduosPerigososEliminados: 0.00221; ResiduosNaoPerigososEliminados: 1.83; MassaTotalDeResiduosRadioactivosEliminados: 0.000394; EnergiaElectricaExportada: 1.55; MateriaisParaRecuperacaoDeEnergia: 0.00739; MateriaisParaReciclagem: 0.0253; UnidadeEPD: 1 m²
Type - IFC.REVIGRÉS-Dados gerais-Floor Covering - Nome: REVIGRÉS-URBAN-BASE-45X45-NAT-URBAN GRIS; TipoProduto: Prensado a seco: grupo BIa UGL | Grés porcelânico técnico; NumeroDeRegistoDAP: EPD-REV-20240006-CCC1-EN; ReferenciaDAP: -; UrlDOP: -
Classification: C3020 (Uniformat)
Pset_CoveringCommon - TotalThickness: 8.5 mm
IFC.REVIGRÉS-Dados do fabricante-Floor Covering - Type: Floor: REVIGRÉS-URBAN-BASE-45X45-NAT-GRIS
IFC.REVIGRÉS-Dados de desempenho-Floor Covering - Type: Floor: REVIGRÉS-URBAN-BASE-45X45-NAT-GRIS
IFC.REVIGRÉS-Dados de especificação-Floor Covering - Type: Floor: REVIGRÉS-URBAN-BASE-45X45-NAT-GRIS
IFC.REVIGRÉS-Dados geométricos-Floor Covering - Type: Floor: REVIGRÉS-URBAN-BASE-45X45-NAT-GRIS
IFC.REVIGRÉS-Dados de sustentabilidade-Floor Covering - Type: Floor: REVIGRÉS-URBAN-BASE-45X45-NAT-GRIS

# IfcCovering: Floor:REVIGRÉS-URBAN-BASE-45X45-NAT-OFFWHITE, Floor:REVIGRÉS-URBAN-BASE-45X45-NAT-OFFWHITE:23732
In: Level 1
Type - PredefinedType: CLADDING; Material: REVIGRÉS-URBAN-BASE-45X45-NAT-OFFWHITE 8.5 mm
Type - Pset_CoveringCommon - Reference: 31200723T1; Material: Grés porcelânico
Type - Pset_ElementShading - Roughness: 304.8 mm
Type - Pset_ManufacturerTypeInformation - Manufacturer: REVIGRÉS
Type - Pset_ProductRequirements - Category: Floors
Type - Pset_QuantityTakeOff - Reference: 31200723T1
Type - IFC.REVIGRÉS-Dados do fabricante-Floor Covering - FabricanteURL: https://www.revigres.pt/; ReferenciaModelo: Urban; NumeroGlobalDeItemComercial: 31200723T1; Acabamento: NAT; Material: Grés porcelânico; IdentificadorDoOperadorEconomico: 501840856; UrlFabricanteArtigo: https://www.revigres.pt/colecoes/urban; PaisOrigem: Portugal
Type - IFC.REVIGRÉS-Dados de desempenho-Floor Covering - Rectilinearidade: ± 0.3% máx. ± 1.5 mm; Ortogonalidade: ± 0.3% máx. ± 1.8 mm; PlanaridadeDaSuperficie: ± 0.3% máx. ± 1.8 mm; QualidadeDaSuperficie: Cumpre; AbsorcaoDeAgua: < 0.05%; ModuloDeRuptura: > 45 N/mm²; ResistenciaAFlexao: > 2000 N; ResistenciaAAbrasaoProfunda: < 120 mm³; DilatacaoTermicaLinear: ≤ 8,0x10-6 °C-1; ResistenciaAoChoqueTermico: Resiste; DurabilidadeResistenciaAoGeloDegelo: Resiste; ResistenciaAoEscorregamentoDIN51130: R9; ResistenciaAoEscorregamentoDIN51097: A; ResistenciaAoEscorregamentoENV51097: A; ResistenciaAoEscorregamentoENV12633: Class 1; ResistenciaAoEscorregamentoANSIA1371: ≥0,42; ResistenciaAoDeslizamentoENV12633: Class 1; ResistenciaAsManchas: Class 5; ResistenciaABaixasConcentracoesDeAcidosEAlcalis: Classe LA; ResistenciaAAltasConcentracoesDeAcidosEAlcalis: Classe HA; LibertacaoDeCadmio: 0; LibertacaoDeChumbo: 0
Type - IFC.REVIGRÉS-Dados de especificação-Floor Covering - VariacaoTonalidade: 2; NivelDeTrafego: 5; EPavimento: Sim; ERevestimento: Sim; EExterno: Sim
Type - IFC.REVIGRÉS-Dados geométricos-Floor Covering - AlturaNominal: 8.5 mm; ComprimentoNominal: 45 mm; LarguraNominal: 45 mm
Type - IFC.REVIGRÉS-Dados de sustentabilidade-Floor Covering - EnergiaTermicaExportada: 0; ItemENovo: Sim; ItemEParcialmenteReciclado: 0.03; ItemEReciclado: Sim; VidaÚtilEsperada: 50; SubstanciasPerigosas: Não; PotencialDeEsgotamentoAbioticoDosRecursosFosseis: 203; PotencialDeEsgotamentoAbioticoDosRecursosNaoFosseisMineraisEMetais: 0.000701; PotencialDeAquecimentoGlobalBiogenico: -0.48; CombustiveisFosseisComPotencialDeAquecimentoGlobal: 13.9; PotencialDeAquecimentoGlobalUsoDoSoloEMudancaDeUsoDoSolo: 0.0246; PotencialDeEutrofizacaoFraccaoDeNutrientesQueAtingemOCompartimentoFinalDeAguaDoce: 0.000189; PotencialDeEutrofizacaoFraccaoDeNutrientesQueAtingemOCompartimentoFinalMarinho: 0.0122; EnergiaRecuperada: 0.00739; ConsumoDeAguaDoce: 0.113; UtilizacaoLiquidaDeAguaDoce: 0.113; ResiduosPerigososEliminados: 0.00221; ResiduosNaoPerigososEliminados: 1.83; MassaTotalDeResiduosRadioactivosEliminados: 0.000394; EnergiaElectricaExportada: 1.55; MateriaisParaRecuperacaoDeEnergia: 0.00739; MateriaisParaReciclagem: 0.0253; UnidadeEPD: 1 m²
Type - IFC.REVIGRÉS-Dados gerais-Floor Covering - Nome: REVIGRÉS-URBAN-BASE-45X45-NAT-URBAN OFFWHITE; TipoProduto: Prensado a seco: grupo BIa UGL | Grés porcelânico técnico; NumeroDeRegistoDAP: EPD-REV-20240006-CCC1-EN; ReferenciaDAP: -; UrlDOP: -
Classification: C3020 (Uniformat)
Pset_CoveringCommon - TotalThickness: 8.5 mm
IFC.REVIGRÉS-Dados do fabricante-Floor Covering - Type: Floor: REVIGRÉS-URBAN-BASE-45X45-NAT-OFFWHITE
IFC.REVIGRÉS-Dados de desempenho-Floor Covering - Type: Floor: REVIGRÉS-URBAN-BASE-45X45-NAT-OFFWHITE
IFC.REVIGRÉS-Dados de especificação-Floor Covering - Type: Floor: REVIGRÉS-URBAN-BASE-45X45-NAT-OFFWHITE
IFC.REVIGRÉS-Dados geométricos-Floor Covering - Type: Floor: REVIGRÉS-URBAN-BASE-45X45-NAT-OFFWHITE
IFC.REVIGRÉS-Dados de sustentabilidade-Floor Covering - Type: Floor: REVIGRÉS-URBAN-BASE-45X45-NAT-OFFWHITE

# IfcCovering: Floor:REVIGRÉS-URBAN-BASE-59,2X118,6-RECT-ANTRACITE, Floor:REVIGRÉS-URBAN-BASE-59,2X118,6-RECT-ANTRACITE:23005
In: Level 1
Type - PredefinedType: CLADDING; Material: REVIGRÉS-URBAN-BASE-60X120-RECT-ANTRACITE 9.8 mm
Type - Pset_CoveringCommon - Reference: 3121D348U1; Material: Grés porcelânico
Type - Pset_ElementShading - Roughness: 304.8 mm
Type - Pset_ManufacturerTypeInformation - Manufacturer: REVIGRÉS
Type - Pset_ProductRequirements - Category: Floors
Type - Pset_QuantityTakeOff - Reference: 3121D348U1
Type - IFC.REVIGRÉS-Dados do fabricante-Floor Covering - FabricanteURL: https://www.revigres.pt/; ReferenciaModelo: Urban; NumeroGlobalDeItemComercial: 3121D348U1; Acabamento: RECT; Material: Grés porcelânico; IdentificadorDoOperadorEconomico: 501840856; UrlFabricanteArtigo: https://www.revigres.pt/colecoes/urban; PaisOrigem: Portugal
Type - IFC.REVIGRÉS-Dados de desempenho-Floor Covering - Rectilinearidade: ± 0.2% máx.± 0.8 mm; Ortogonalidade: ± 0.2% máx.± 1.5 mm; PlanaridadeDaSuperficie: ± 0.3% máx. ± 1.8 mm; QualidadeDaSuperficie: Cumpre; AbsorcaoDeAgua: < 0.05%; ModuloDeRuptura: > 45 N/mm²; ResistenciaAFlexao: > 3500 N; ResistenciaAAbrasaoProfunda: < 120 mm³; DilatacaoTermicaLinear: ≤ 8,0x10-6 °C-1; ResistenciaAoChoqueTermico: Resiste; DurabilidadeResistenciaAoGeloDegelo: Resiste; ResistenciaAoEscorregamentoDIN51130: R9; ResistenciaAoEscorregamentoDIN51097: A; ResistenciaAoEscorregamentoENV51097: A; ResistenciaAoEscorregamentoENV12633: Class 1; ResistenciaAoEscorregamentoANSIA1371: ≥0,42; ResistenciaAoDeslizamentoENV12633: Class 1; ResistenciaAsManchas: Class 5; ResistenciaABaixasConcentracoesDeAcidosEAlcalis: Classe LA; ResistenciaAAltasConcentracoesDeAcidosEAlcalis: Classe HA; LibertacaoDeCadmio: 0; LibertacaoDeChumbo: 0
Type - IFC.REVIGRÉS-Dados de especificação-Floor Covering - VariacaoTonalidade: 2; NivelDeTrafego: 5; EPavimento: Sim; ERevestimento: Sim; EExterno: Sim
Type - IFC.REVIGRÉS-Dados geométricos-Floor Covering - AlturaNominal: 9.8 mm; ComprimentoNominal: 592 mm; LarguraNominal: 1186 mm
Type - IFC.REVIGRÉS-Dados de sustentabilidade-Floor Covering - EnergiaTermicaExportada: 0; ItemENovo: Sim; ItemEParcialmenteReciclado: 0.29; ItemEReciclado: Sim; VidaÚtilEsperada: 50; SubstanciasPerigosas: Não; PotencialDeEsgotamentoAbioticoDosRecursosFosseis: 203; PotencialDeEsgotamentoAbioticoDosRecursosNaoFosseisMineraisEMetais: 0.000701; PotencialDeAquecimentoGlobalBiogenico: -0.48; CombustiveisFosseisComPotencialDeAquecimentoGlobal: 13.9; PotencialDeAquecimentoGlobalUsoDoSoloEMudancaDeUsoDoSolo: 0.0246; PotencialDeEutrofizacaoFraccaoDeNutrientesQueAtingemOCompartimentoFinalDeAguaDoce: 0.000189; PotencialDeEutrofizacaoFraccaoDeNutrientesQueAtingemOCompartimentoFinalMarinho: 0.0122; EnergiaRecuperada: 0.00739; ConsumoDeAguaDoce: 0.113; UtilizacaoLiquidaDeAguaDoce: 0.113; ResiduosPerigososEliminados: 0.00221; ResiduosNaoPerigososEliminados: 1.83; MassaTotalDeResiduosRadioactivosEliminados: 0.000394; EnergiaElectricaExportada: 1.55; MateriaisParaRecuperacaoDeEnergia: 0.00739; MateriaisParaReciclagem: 0.0253; UnidadeEPD: 1 m²
Type - IFC.REVIGRÉS-Dados gerais-Floor Covering - Nome: REVIGRÉS-URBAN-BASE-59.2X118.6-RECT-URBAN ANTRACITE; TipoProduto: Prensado a seco: grupo BIa UGL | Grés porcelânico técnico; NumeroDeRegistoDAP: EPD-REV-20240006-CCC1-EN; ReferenciaDAP: -; UrlDOP: -
Classification: C3020 (Uniformat)
Pset_CoveringCommon - TotalThickness: 9.8 mm
IFC.REVIGRÉS-Dados do fabricante-Floor Covering - Type: Floor: REVIGRÉS-URBAN-BASE-59,2X118,6-RECT-ANTRACITE
IFC.REVIGRÉS-Dados de desempenho-Floor Covering - Type: Floor: REVIGRÉS-URBAN-BASE-59,2X118,6-RECT-ANTRACITE
IFC.REVIGRÉS-Dados de especificação-Floor Covering - Type: Floor: REVIGRÉS-URBAN-BASE-59,2X118,6-RECT-ANTRACITE
IFC.REVIGRÉS-Dados geométricos-Floor Covering - Type: Floor: REVIGRÉS-URBAN-BASE-59,2X118,6-RECT-ANTRACITE
IFC.REVIGRÉS-Dados de sustentabilidade-Floor Covering - Type: Floor: REVIGRÉS-URBAN-BASE-59,2X118,6-RECT-ANTRACITE

# IfcCovering: Floor:REVIGRÉS-URBAN-BASE-59,2X118,6-RECT-BONE, Floor:REVIGRÉS-URBAN-BASE-59,2X118,6-RECT-BONE:23021
In: Level 1
Type - PredefinedType: CLADDING; Material: REVIGRÉS-URBAN-BASE-60X120-RECT-BONE 9.8 mm
Type - Pset_CoveringCommon - Reference: 3121D320T1; Material: Grés porcelânico
Type - Pset_ElementShading - Roughness: 304.8 mm
Type - Pset_ManufacturerTypeInformation - Manufacturer: REVIGRÉS
Type - Pset_ProductRequirements - Category: Floors
Type - Pset_QuantityTakeOff - Reference: 3121D320T1
Type - IFC.REVIGRÉS-Dados do fabricante-Floor Covering - FabricanteURL: https://www.revigres.pt/; ReferenciaModelo: Urban; NumeroGlobalDeItemComercial: 3121D320T1; Acabamento: RECT; Material: Grés porcelânico; IdentificadorDoOperadorEconomico: 501840856; UrlFabricanteArtigo: https://www.revigres.pt/colecoes/urban; PaisOrigem: Portugal
Type - IFC.REVIGRÉS-Dados de desempenho-Floor Covering - Rectilinearidade: ± 0.2% máx.± 0.8 mm; Ortogonalidade: ± 0.2% máx.± 1.5 mm; PlanaridadeDaSuperficie: ± 0.3% máx. ± 1.8 mm; QualidadeDaSuperficie: Cumpre; AbsorcaoDeAgua: < 0.05%; ModuloDeRuptura: > 45 N/mm²; ResistenciaAFlexao: > 3500 N; ResistenciaAAbrasaoProfunda: < 120 mm³; DilatacaoTermicaLinear: ≤ 8,0x10-6 °C-1; ResistenciaAoChoqueTermico: Resiste; DurabilidadeResistenciaAoGeloDegelo: Resiste; ResistenciaAoEscorregamentoDIN51130: R9; ResistenciaAoEscorregamentoDIN51097: A; ResistenciaAoEscorregamentoENV51097: A; ResistenciaAoEscorregamentoENV12633: Class 1; ResistenciaAoEscorregamentoANSIA1371: ≥0,42; ResistenciaAoDeslizamentoENV12633: Class 1; ResistenciaAsManchas: Class 5; ResistenciaABaixasConcentracoesDeAcidosEAlcalis: Classe LA; ResistenciaAAltasConcentracoesDeAcidosEAlcalis: Classe HA; LibertacaoDeCadmio: 0; LibertacaoDeChumbo: 0
Type - IFC.REVIGRÉS-Dados de especificação-Floor Covering - VariacaoTonalidade: 2; NivelDeTrafego: 5; EPavimento: Sim; ERevestimento: Sim; EExterno: Sim
Type - IFC.REVIGRÉS-Dados geométricos-Floor Covering - AlturaNominal: 9.8 mm; ComprimentoNominal: 592 mm; LarguraNominal: 1186 mm
Type - IFC.REVIGRÉS-Dados de sustentabilidade-Floor Covering - EnergiaTermicaExportada: 0; ItemENovo: Sim; ItemEParcialmenteReciclado: 0.03; ItemEReciclado: Sim; VidaÚtilEsperada: 50; SubstanciasPerigosas: Não; PotencialDeEsgotamentoAbioticoDosRecursosFosseis: 203; PotencialDeEsgotamentoAbioticoDosRecursosNaoFosseisMineraisEMetais: 0.000701; PotencialDeAquecimentoGlobalBiogenico: -0.48; CombustiveisFosseisComPotencialDeAquecimentoGlobal: 13.9; PotencialDeAquecimentoGlobalUsoDoSoloEMudancaDeUsoDoSolo: 0.0246; PotencialDeEutrofizacaoFraccaoDeNutrientesQueAtingemOCompartimentoFinalDeAguaDoce: 0.000189; PotencialDeEutrofizacaoFraccaoDeNutrientesQueAtingemOCompartimentoFinalMarinho: 0.0122; EnergiaRecuperada: 0.00739; ConsumoDeAguaDoce: 0.113; UtilizacaoLiquidaDeAguaDoce: 0.113; ResiduosPerigososEliminados: 0.00221; ResiduosNaoPerigososEliminados: 1.83; MassaTotalDeResiduosRadioactivosEliminados: 0.000394; EnergiaElectricaExportada: 1.55; MateriaisParaRecuperacaoDeEnergia: 0.00739; MateriaisParaReciclagem: 0.0253; UnidadeEPD: 1 m²
Type - IFC.REVIGRÉS-Dados gerais-Floor Covering - Nome: REVIGRÉS-URBAN-BASE-59.2X118.6-RECT-URBAN BONE; TipoProduto: Prensado a seco: grupo BIa UGL | Grés porcelânico técnico; NumeroDeRegistoDAP: EPD-REV-20240006-CCC1-EN; ReferenciaDAP: -; UrlDOP: -
Classification: C3020 (Uniformat)
Pset_CoveringCommon - TotalThickness: 9.8 mm
IFC.REVIGRÉS-Dados do fabricante-Floor Covering - Type: Floor: REVIGRÉS-URBAN-BASE-59,2X118,6-RECT-BONE
IFC.REVIGRÉS-Dados de desempenho-Floor Covering - Type: Floor: REVIGRÉS-URBAN-BASE-59,2X118,6-RECT-BONE
IFC.REVIGRÉS-Dados de especificação-Floor Covering - Type: Floor: REVIGRÉS-URBAN-BASE-59,2X118,6-RECT-BONE
IFC.REVIGRÉS-Dados geométricos-Floor Covering - Type: Floor: REVIGRÉS-URBAN-BASE-59,2X118,6-RECT-BONE
IFC.REVIGRÉS-Dados de sustentabilidade-Floor Covering - Type: Floor: REVIGRÉS-URBAN-BASE-59,2X118,6-RECT-BONE

# IfcCovering: Floor:REVIGRÉS-URBAN-BASE-59,2X118,6-RECT-CRAFT, Floor:REVIGRÉS-URBAN-BASE-59,2X118,6-RECT-CRAFT:23037
In: Level 1
Type - PredefinedType: CLADDING; Material: REVIGRÉS-URBAN-BASE-60X120-RECT-CRAFT 9.8 mm
Type - Pset_CoveringCommon - Reference: 3121D324T1; Material: Grés porcelânico
Type - Pset_ElementShading - Roughness: 304.8 mm
Type - Pset_ManufacturerTypeInformation - Manufacturer: REVIGRÉS
Type - Pset_ProductRequirements - Category: Floors
Type - Pset_QuantityTakeOff - Reference: 3121D324T1
Type - IFC.REVIGRÉS-Dados do fabricante-Floor Covering - FabricanteURL: https://www.revigres.pt/; ReferenciaModelo: Urban; NumeroGlobalDeItemComercial: 3121D324T1; Acabamento: RECT; Material: Grés porcelânico; IdentificadorDoOperadorEconomico: 501840856; UrlFabricanteArtigo: https://www.revigres.pt/colecoes/urban; PaisOrigem: Portugal
Type - IFC.REVIGRÉS-Dados de desempenho-Floor Covering - Rectilinearidade: ± 0.2% máx.± 0.8 mm; Ortogonalidade: ± 0.2% máx.± 1.5 mm; PlanaridadeDaSuperficie: ± 0.3% máx. ± 1.8 mm; QualidadeDaSuperficie: Cumpre; AbsorcaoDeAgua: < 0.05%; ModuloDeRuptura: > 45 N/mm²; ResistenciaAFlexao: > 3500 N; ResistenciaAAbrasaoProfunda: < 120 mm³; DilatacaoTermicaLinear: ≤ 8,0x10-6 °C-1; ResistenciaAoChoqueTermico: Resiste; DurabilidadeResistenciaAoGeloDegelo: Resiste; ResistenciaAoEscorregamentoDIN51130: R9; ResistenciaAoEscorregamentoDIN51097: A; ResistenciaAoEscorregamentoENV51097: A; ResistenciaAoEscorregamentoENV12633: Class 1; ResistenciaAoEscorregamentoANSIA1371: ≥0,42; ResistenciaAoDeslizamentoENV12633: Class 1; ResistenciaAsManchas: Class 5; ResistenciaABaixasConcentracoesDeAcidosEAlcalis: Classe LA; ResistenciaAAltasConcentracoesDeAcidosEAlcalis: Classe HA; LibertacaoDeCadmio: 0; LibertacaoDeChumbo: 0
Type - IFC.REVIGRÉS-Dados de especificação-Floor Covering - VariacaoTonalidade: 2; NivelDeTrafego: 5; EPavimento: Sim; ERevestimento: Sim; EExterno: Sim
Type - IFC.REVIGRÉS-Dados geométricos-Floor Covering - AlturaNominal: 9.8 mm; ComprimentoNominal: 592 mm; LarguraNominal: 1186 mm
Type - IFC.REVIGRÉS-Dados de sustentabilidade-Floor Covering - EnergiaTermicaExportada: 0; ItemENovo: Sim; ItemEParcialmenteReciclado: 0.19; ItemEReciclado: Sim; VidaÚtilEsperada: 50; SubstanciasPerigosas: Não; PotencialDeEsgotamentoAbioticoDosRecursosFosseis: 203; PotencialDeEsgotamentoAbioticoDosRecursosNaoFosseisMineraisEMetais: 0.000701; PotencialDeAquecimentoGlobalBiogenico: -0.48; CombustiveisFosseisComPotencialDeAquecimentoGlobal: 13.9; PotencialDeAquecimentoGlobalUsoDoSoloEMudancaDeUsoDoSolo: 0.0246; PotencialDeEutrofizacaoFraccaoDeNutrientesQueAtingemOCompartimentoFinalDeAguaDoce: 0.000189; PotencialDeEutrofizacaoFraccaoDeNutrientesQueAtingemOCompartimentoFinalMarinho: 0.0122; EnergiaRecuperada: 0.00739; ConsumoDeAguaDoce: 0.113; UtilizacaoLiquidaDeAguaDoce: 0.113; ResiduosPerigososEliminados: 0.00221; ResiduosNaoPerigososEliminados: 1.83; MassaTotalDeResiduosRadioactivosEliminados: 0.000394; EnergiaElectricaExportada: 1.55; MateriaisParaRecuperacaoDeEnergia: 0.00739; MateriaisParaReciclagem: 0.0253; UnidadeEPD: 1 m²
Type - IFC.REVIGRÉS-Dados gerais-Floor Covering - Nome: REVIGRÉS-URBAN-BASE-59.2X118.6-RECT-URBAN CRAFT; TipoProduto: Prensado a seco: grupo BIa UGL | Grés porcelânico técnico; NumeroDeRegistoDAP: EPD-REV-20240006-CCC1-EN; ReferenciaDAP: -; UrlDOP: -
Classification: C3020 (Uniformat)
Pset_CoveringCommon - TotalThickness: 9.8 mm
IFC.REVIGRÉS-Dados do fabricante-Floor Covering - Type: Floor: REVIGRÉS-URBAN-BASE-59,2X118,6-RECT-CRAFT
IFC.REVIGRÉS-Dados de desempenho-Floor Covering - Type: Floor: REVIGRÉS-URBAN-BASE-59,2X118,6-RECT-CRAFT
IFC.REVIGRÉS-Dados de especificação-Floor Covering - Type: Floor: REVIGRÉS-URBAN-BASE-59,2X118,6-RECT-CRAFT
IFC.REVIGRÉS-Dados geométricos-Floor Covering - Type: Floor: REVIGRÉS-URBAN-BASE-59,2X118,6-RECT-CRAFT
IFC.REVIGRÉS-Dados de sustentabilidade-Floor Covering - Type: Floor: REVIGRÉS-URBAN-BASE-59,2X118,6-RECT-CRAFT

# IfcCovering: Floor:REVIGRÉS-URBAN-BASE-59,2X118,6-RECT-FOG, Floor:REVIGRÉS-URBAN-BASE-59,2X118,6-RECT-FOG:23053
In: Level 1
Type - PredefinedType: CLADDING; Material: REVIGRÉS-URBAN-BASE-60X120-RECT-FOG 9.8 mm
Type - Pset_CoveringCommon - Reference: 3121D321T1; Material: Grés porcelânico
Type - Pset_ElementShading - Roughness: 304.8 mm
Type - Pset_ManufacturerTypeInformation - Manufacturer: REVIGRÉS
Type - Pset_ProductRequirements - Category: Floors
Type - Pset_QuantityTakeOff - Reference: 3121D321T1
Type - IFC.REVIGRÉS-Dados do fabricante-Floor Covering - FabricanteURL: https://www.revigres.pt/; ReferenciaModelo: Urban; NumeroGlobalDeItemComercial: 3121D321T1; Acabamento: RECT; Material: Grés porcelânico; IdentificadorDoOperadorEconomico: 501840856; UrlFabricanteArtigo: https://www.revigres.pt/colecoes/urban; PaisOrigem: Portugal
Type - IFC.REVIGRÉS-Dados de desempenho-Floor Covering - Rectilinearidade: ± 0.2% máx.± 0.8 mm; Ortogonalidade: ± 0.2% máx.± 1.5 mm; PlanaridadeDaSuperficie: ± 0.3% máx. ± 1.8 mm; QualidadeDaSuperficie: Cumpre; AbsorcaoDeAgua: < 0.05%; ModuloDeRuptura: > 45 N/mm²; ResistenciaAFlexao: > 3500 N; ResistenciaAAbrasaoProfunda: < 120 mm³; DilatacaoTermicaLinear: ≤ 8,0x10-6 °C-1; ResistenciaAoChoqueTermico: Resiste; DurabilidadeResistenciaAoGeloDegelo: Resiste; ResistenciaAoEscorregamentoDIN51130: R9; ResistenciaAoEscorregamentoDIN51097: A; ResistenciaAoEscorregamentoENV51097: A; ResistenciaAoEscorregamentoENV12633: Class 1; ResistenciaAoEscorregamentoANSIA1371: ≥0,42; ResistenciaAoDeslizamentoENV12633: Class 1; ResistenciaAsManchas: Class 5; ResistenciaABaixasConcentracoesDeAcidosEAlcalis: Classe LA; ResistenciaAAltasConcentracoesDeAcidosEAlcalis: Classe HA; LibertacaoDeCadmio: 0; LibertacaoDeChumbo: 0
Type - IFC.REVIGRÉS-Dados de especificação-Floor Covering - VariacaoTonalidade: 2; NivelDeTrafego: 5; EPavimento: Sim; ERevestimento: Sim; EExterno: Sim
Type - IFC.REVIGRÉS-Dados geométricos-Floor Covering - AlturaNominal: 9.8 mm; ComprimentoNominal: 592 mm; LarguraNominal: 1186 mm
Type - IFC.REVIGRÉS-Dados de sustentabilidade-Floor Covering - EnergiaTermicaExportada: 0; ItemENovo: Sim; ItemEParcialmenteReciclado: 0.23; ItemEReciclado: Sim; VidaÚtilEsperada: 50; SubstanciasPerigosas: Não; PotencialDeEsgotamentoAbioticoDosRecursosFosseis: 203; PotencialDeEsgotamentoAbioticoDosRecursosNaoFosseisMineraisEMetais: 0.000701; PotencialDeAquecimentoGlobalBiogenico: -0.48; CombustiveisFosseisComPotencialDeAquecimentoGlobal: 13.9; PotencialDeAquecimentoGlobalUsoDoSoloEMudancaDeUsoDoSolo: 0.0246; PotencialDeEutrofizacaoFraccaoDeNutrientesQueAtingemOCompartimentoFinalDeAguaDoce: 0.000189; PotencialDeEutrofizacaoFraccaoDeNutrientesQueAtingemOCompartimentoFinalMarinho: 0.0122; EnergiaRecuperada: 0.00739; ConsumoDeAguaDoce: 0.113; UtilizacaoLiquidaDeAguaDoce: 0.113; ResiduosPerigososEliminados: 0.00221; ResiduosNaoPerigososEliminados: 1.83; MassaTotalDeResiduosRadioactivosEliminados: 0.000394; EnergiaElectricaExportada: 1.55; MateriaisParaRecuperacaoDeEnergia: 0.00739; MateriaisParaReciclagem: 0.0253; UnidadeEPD: 1 m²
Type - IFC.REVIGRÉS-Dados gerais-Floor Covering - Nome: REVIGRÉS-URBAN-BASE-59.2X118.6-RECT-URBAN FOG; TipoProduto: Prensado a seco: grupo BIa UGL | Grés porcelânico técnico; NumeroDeRegistoDAP: EPD-REV-20240006-CCC1-EN; ReferenciaDAP: -; UrlDOP: -
Classification: C3020 (Uniformat)
Pset_CoveringCommon - TotalThickness: 9.8 mm
IFC.REVIGRÉS-Dados do fabricante-Floor Covering - Type: Floor: REVIGRÉS-URBAN-BASE-59,2X118,6-RECT-FOG
IFC.REVIGRÉS-Dados de desempenho-Floor Covering - Type: Floor: REVIGRÉS-URBAN-BASE-59,2X118,6-RECT-FOG
IFC.REVIGRÉS-Dados de especificação-Floor Covering - Type: Floor: REVIGRÉS-URBAN-BASE-59,2X118,6-RECT-FOG
IFC.REVIGRÉS-Dados geométricos-Floor Covering - Type: Floor: REVIGRÉS-URBAN-BASE-59,2X118,6-RECT-FOG
IFC.REVIGRÉS-Dados de sustentabilidade-Floor Covering - Type: Floor: REVIGRÉS-URBAN-BASE-59,2X118,6-RECT-FOG

# IfcCovering: Floor:REVIGRÉS-URBAN-BASE-59,2X118,6-RECT-GRIS, Floor:REVIGRÉS-URBAN-BASE-59,2X118,6-RECT-GRIS:23069
In: Level 1
Type - PredefinedType: CLADDING; Material: REVIGRÉS-URBAN-BASE-60X120-RECT-GRIS 9.8 mm
Type - Pset_CoveringCommon - Reference: 3121D322T1; Material: Grés porcelânico
Type - Pset_ElementShading - Roughness: 304.8 mm
Type - Pset_ManufacturerTypeInformation - Manufacturer: REVIGRÉS
Type - Pset_ProductRequirements - Category: Floors
Type - Pset_QuantityTakeOff - Reference: 3121D322T1
Type - IFC.REVIGRÉS-Dados do fabricante-Floor Covering - FabricanteURL: https://www.revigres.pt/; ReferenciaModelo: Urban; NumeroGlobalDeItemComercial: 3121D322T1; Acabamento: RECT; Material: Grés porcelânico; IdentificadorDoOperadorEconomico: 501840856; UrlFabricanteArtigo: https://www.revigres.pt/colecoes/urban; PaisOrigem: Portugal
Type - IFC.REVIGRÉS-Dados de desempenho-Floor Covering - Rectilinearidade: ± 0.2% máx.± 0.8 mm; Ortogonalidade: ± 0.2% máx.± 1.5 mm; PlanaridadeDaSuperficie: ± 0.3% máx. ± 1.8 mm; QualidadeDaSuperficie: Cumpre; AbsorcaoDeAgua: < 0.05%; ModuloDeRuptura: > 45 N/mm²; ResistenciaAFlexao: > 3500 N; ResistenciaAAbrasaoProfunda: < 120 mm³; DilatacaoTermicaLinear: ≤ 8,0x10-6 °C-1; ResistenciaAoChoqueTermico: Resiste; DurabilidadeResistenciaAoGeloDegelo: Resiste; ResistenciaAoEscorregamentoDIN51130: R9; ResistenciaAoEscorregamentoDIN51097: A; ResistenciaAoEscorregamentoENV51097: A; ResistenciaAoEscorregamentoENV12633: Class 1; ResistenciaAoEscorregamentoANSIA1371: ≥0,42; ResistenciaAoDeslizamentoENV12633: Class 1; ResistenciaAsManchas: Class 5; ResistenciaABaixasConcentracoesDeAcidosEAlcalis: Classe LA; ResistenciaAAltasConcentracoesDeAcidosEAlcalis: Classe HA; LibertacaoDeCadmio: 0; LibertacaoDeChumbo: 0
Type - IFC.REVIGRÉS-Dados de especificação-Floor Covering - VariacaoTonalidade: 2; NivelDeTrafego: 5; EPavimento: Sim; ERevestimento: Sim; EExterno: Sim
Type - IFC.REVIGRÉS-Dados geométricos-Floor Covering - AlturaNominal: 9.8 mm; ComprimentoNominal: 592 mm; LarguraNominal: 1186 mm
Type - IFC.REVIGRÉS-Dados de sustentabilidade-Floor Covering - EnergiaTermicaExportada: 0; ItemENovo: Sim; ItemEParcialmenteReciclado: 0.23; ItemEReciclado: Sim; VidaÚtilEsperada: 50; SubstanciasPerigosas: Não; PotencialDeEsgotamentoAbioticoDosRecursosFosseis: 203; PotencialDeEsgotamentoAbioticoDosRecursosNaoFosseisMineraisEMetais: 0.000701; PotencialDeAquecimentoGlobalBiogenico: -0.48; CombustiveisFosseisComPotencialDeAquecimentoGlobal: 13.9; PotencialDeAquecimentoGlobalUsoDoSoloEMudancaDeUsoDoSolo: 0.0246; PotencialDeEutrofizacaoFraccaoDeNutrientesQueAtingemOCompartimentoFinalDeAguaDoce: 0.000189; PotencialDeEutrofizacaoFraccaoDeNutrientesQueAtingemOCompartimentoFinalMarinho: 0.0122; EnergiaRecuperada: 0.00739; ConsumoDeAguaDoce: 0.113; UtilizacaoLiquidaDeAguaDoce: 0.113; ResiduosPerigososEliminados: 0.00221; ResiduosNaoPerigososEliminados: 1.83; MassaTotalDeResiduosRadioactivosEliminados: 0.000394; EnergiaElectricaExportada: 1.55; MateriaisParaRecuperacaoDeEnergia: 0.00739; MateriaisParaReciclagem: 0.0253; UnidadeEPD: 1 m²
Type - IFC.REVIGRÉS-Dados gerais-Floor Covering - Nome: REVIGRÉS-URBAN-BASE-59.2X118.6-RECT-URBAN GRIS; TipoProduto: Prensado a seco: grupo BIa UGL | Grés porcelânico técnico; NumeroDeRegistoDAP: EPD-REV-20240006-CCC1-EN; ReferenciaDAP: -; UrlDOP: -
Classification: C3020 (Uniformat)
Pset_CoveringCommon - TotalThickness: 9.8 mm
IFC.REVIGRÉS-Dados do fabricante-Floor Covering - Type: Floor: REVIGRÉS-URBAN-BASE-59,2X118,6-RECT-GRIS
IFC.REVIGRÉS-Dados de desempenho-Floor Covering - Type: Floor: REVIGRÉS-URBAN-BASE-59,2X118,6-RECT-GRIS
IFC.REVIGRÉS-Dados de especificação-Floor Covering - Type: Floor: REVIGRÉS-URBAN-BASE-59,2X118,6-RECT-GRIS
IFC.REVIGRÉS-Dados geométricos-Floor Covering - Type: Floor: REVIGRÉS-URBAN-BASE-59,2X118,6-RECT-GRIS
IFC.REVIGRÉS-Dados de sustentabilidade-Floor Covering - Type: Floor: REVIGRÉS-URBAN-BASE-59,2X118,6-RECT-GRIS

# IfcCovering: Floor:REVIGRÉS-URBAN-BASE-59,2X118,6-RECT-OFFWHITE, Floor:REVIGRÉS-URBAN-BASE-59,2X118,6-RECT-OFFWHITE:23085
In: Level 1
Type - PredefinedType: CLADDING; Material: REVIGRÉS-URBAN-BASE-60X120-RECT-OFFWHITE 9.8 mm
Type - Pset_CoveringCommon - Reference: 3121D323T1; Material: Grés porcelânico
Type - Pset_ElementShading - Roughness: 304.8 mm
Type - Pset_ManufacturerTypeInformation - Manufacturer: REVIGRÉS
Type - Pset_ProductRequirements - Category: Floors
Type - Pset_QuantityTakeOff - Reference: 3121D323T1
Type - IFC.REVIGRÉS-Dados do fabricante-Floor Covering - FabricanteURL: https://www.revigres.pt/; ReferenciaModelo: Urban; NumeroGlobalDeItemComercial: 3121D323T1; Acabamento: RECT; Material: Grés porcelânico; IdentificadorDoOperadorEconomico: 501840856; UrlFabricanteArtigo: https://www.revigres.pt/colecoes/urban; PaisOrigem: Portugal
Type - IFC.REVIGRÉS-Dados de desempenho-Floor Covering - Rectilinearidade: ± 0.2% máx.± 0.8 mm; Ortogonalidade: ± 0.2% máx.± 1.5 mm; PlanaridadeDaSuperficie: ± 0.3% máx. ± 1.8 mm; QualidadeDaSuperficie: Cumpre; AbsorcaoDeAgua: < 0.05%; ModuloDeRuptura: > 45 N/mm²; ResistenciaAFlexao: > 3500 N; ResistenciaAAbrasaoProfunda: < 120 mm³; DilatacaoTermicaLinear: ≤ 8,0x10-6 °C-1; ResistenciaAoChoqueTermico: Resiste; DurabilidadeResistenciaAoGeloDegelo: Resiste; ResistenciaAoEscorregamentoDIN51130: R9; ResistenciaAoEscorregamentoDIN51097: A; ResistenciaAoEscorregamentoENV51097: A; ResistenciaAoEscorregamentoENV12633: Class 1; ResistenciaAoEscorregamentoANSIA1371: ≥0,42; ResistenciaAoDeslizamentoENV12633: Class 1; ResistenciaAsManchas: Class 5; ResistenciaABaixasConcentracoesDeAcidosEAlcalis: Classe LA; ResistenciaAAltasConcentracoesDeAcidosEAlcalis: Classe HA; LibertacaoDeCadmio: 0; LibertacaoDeChumbo: 0
Type - IFC.REVIGRÉS-Dados de especificação-Floor Covering - VariacaoTonalidade: 2; NivelDeTrafego: 5; EPavimento: Sim; ERevestimento: Sim; EExterno: Sim
Type - IFC.REVIGRÉS-Dados geométricos-Floor Covering - AlturaNominal: 9.8 mm; ComprimentoNominal: 592 mm; LarguraNominal: 1186 mm
Type - IFC.REVIGRÉS-Dados de sustentabilidade-Floor Covering - EnergiaTermicaExportada: 0; ItemENovo: Sim; ItemEParcialmenteReciclado: 0.03; ItemEReciclado: Sim; VidaÚtilEsperada: 50; SubstanciasPerigosas: Não; PotencialDeEsgotamentoAbioticoDosRecursosFosseis: 203; PotencialDeEsgotamentoAbioticoDosRecursosNaoFosseisMineraisEMetais: 0.000701; PotencialDeAquecimentoGlobalBiogenico: -0.48; CombustiveisFosseisComPotencialDeAquecimentoGlobal: 13.9; PotencialDeAquecimentoGlobalUsoDoSoloEMudancaDeUsoDoSolo: 0.0246; PotencialDeEutrofizacaoFraccaoDeNutrientesQueAtingemOCompartimentoFinalDeAguaDoce: 0.000189; PotencialDeEutrofizacaoFraccaoDeNutrientesQueAtingemOCompartimentoFinalMarinho: 0.0122; EnergiaRecuperada: 0.00739; ConsumoDeAguaDoce: 0.113; UtilizacaoLiquidaDeAguaDoce: 0.113; ResiduosPerigososEliminados: 0.00221; ResiduosNaoPerigososEliminados: 1.83; MassaTotalDeResiduosRadioactivosEliminados: 0.000394; EnergiaElectricaExportada: 1.55; MateriaisParaRecuperacaoDeEnergia: 0.00739; MateriaisParaReciclagem: 0.0253; UnidadeEPD: 1 m²
Type - IFC.REVIGRÉS-Dados gerais-Floor Covering - Nome: REVIGRÉS-URBAN-BASE-59.2X118.6-RECT-URBAN OFFWHITE; TipoProduto: Prensado a seco: grupo BIa UGL | Grés porcelânico técnico; NumeroDeRegistoDAP: EPD-REV-20240006-CCC1-EN; ReferenciaDAP: -; UrlDOP: -
Classification: C3020 (Uniformat)
Pset_CoveringCommon - TotalThickness: 9.8 mm
IFC.REVIGRÉS-Dados do fabricante-Floor Covering - Type: Floor: REVIGRÉS-URBAN-BASE-59,2X118,6-RECT-OFFWHITE
IFC.REVIGRÉS-Dados de desempenho-Floor Covering - Type: Floor: REVIGRÉS-URBAN-BASE-59,2X118,6-RECT-OFFWHITE
IFC.REVIGRÉS-Dados de especificação-Floor Covering - Type: Floor: REVIGRÉS-URBAN-BASE-59,2X118,6-RECT-OFFWHITE
IFC.REVIGRÉS-Dados geométricos-Floor Covering - Type: Floor: REVIGRÉS-URBAN-BASE-59,2X118,6-RECT-OFFWHITE
IFC.REVIGRÉS-Dados de sustentabilidade-Floor Covering - Type: Floor: REVIGRÉS-URBAN-BASE-59,2X118,6-RECT-OFFWHITE

# IfcCovering: Floor:REVIGRÉS-URBAN-BASE-59,2X59,2-RECT-ANTISLIP ANTRACITE, Floor:REVIGRÉS-URBAN-BASE-59,2X59,2-RECT-ANTISLIP ANTRACITE:26602
In: Level 1
Type - PredefinedType: CLADDING; Material: REVIGRÉS-URBAN-BASE-60X60-RECT-ANTISLIP ANTRACITE 10.5 mm
Type - Pset_CoveringCommon - Reference: 31211349U1; Material: Grés porcelânico
Type - Pset_ElementShading - Roughness: 304.8 mm
Type - Pset_ManufacturerTypeInformation - Manufacturer: REVIGRÉS
Type - Pset_ProductRequirements - Category: Floors
Type - Pset_QuantityTakeOff - Reference: 31211349U1
Type - IFC.REVIGRÉS-Dados do fabricante-Floor Covering - FabricanteURL: https://www.revigres.pt/; ReferenciaModelo: Urban; NumeroGlobalDeItemComercial: 31211349U1; Acabamento: RECT; Material: Grés porcelânico; IdentificadorDoOperadorEconomico: 501840856; UrlFabricanteArtigo: https://www.revigres.pt/colecoes/urban; PaisOrigem: Portugal
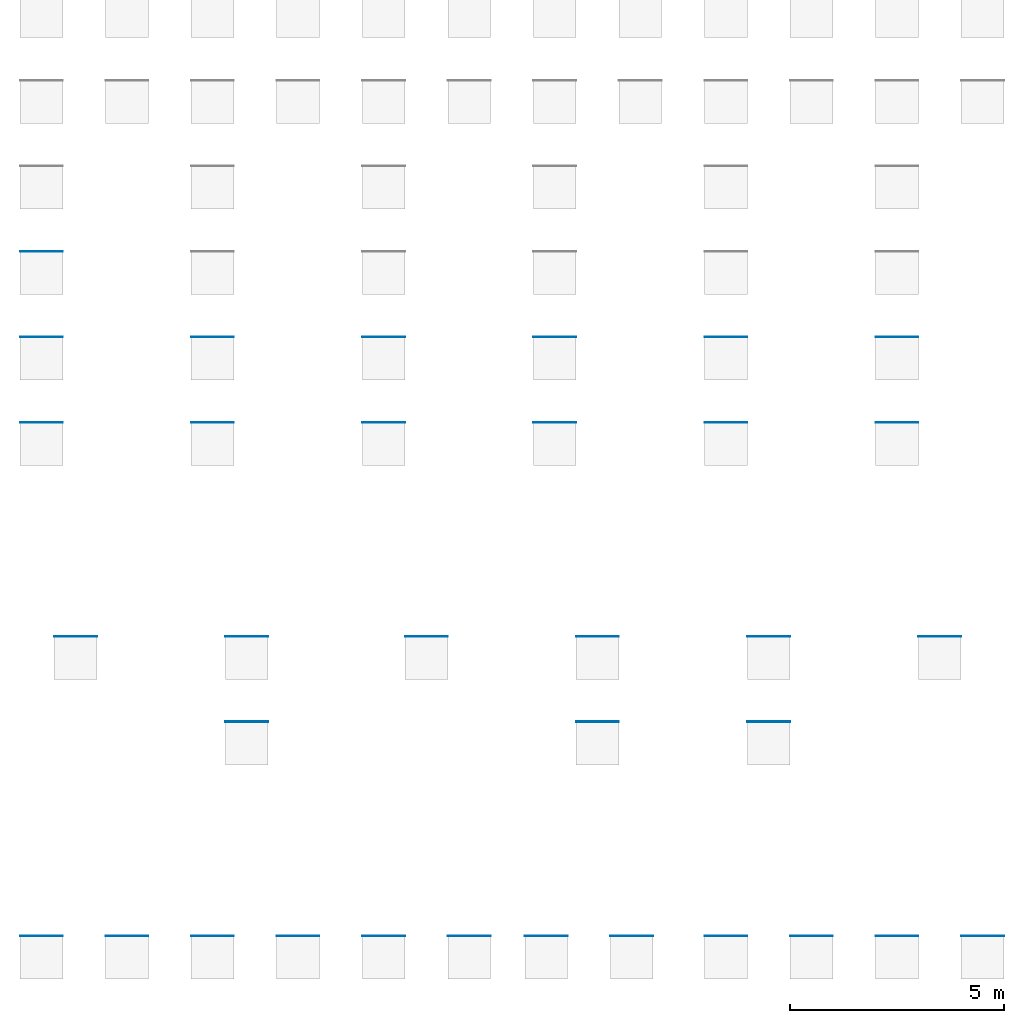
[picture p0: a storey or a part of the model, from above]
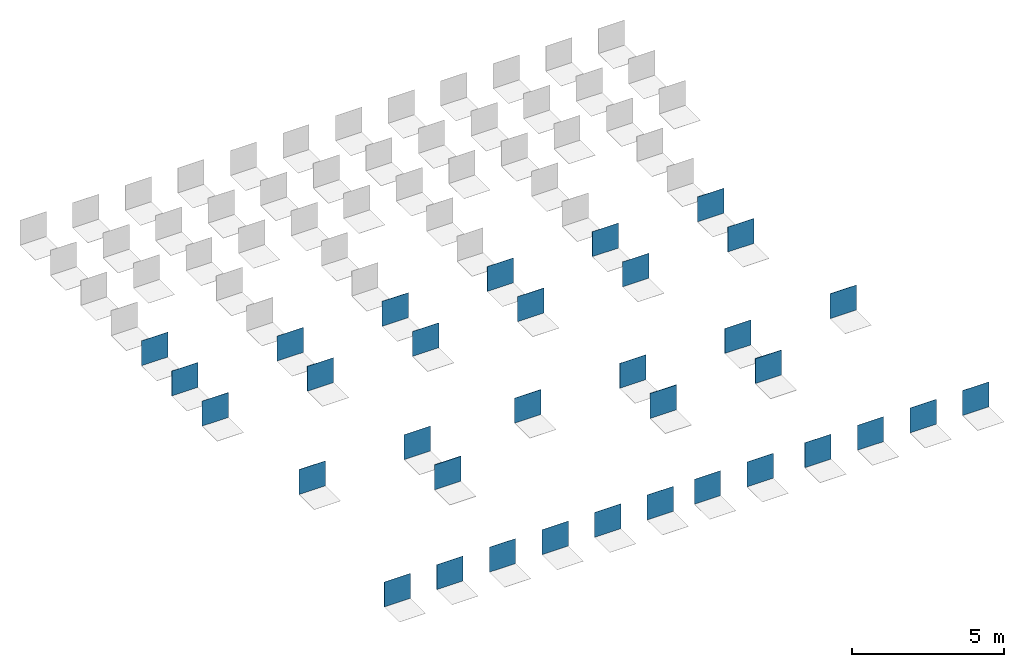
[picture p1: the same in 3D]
Properties of the parts of a building model (IFC2X3), part 5 of 12

# IfcCovering: Floor:REVIGRÉS-URBAN-BASE-59,2X59,2-RECT-ANTISLIP ANTRACITE, Floor:REVIGRÉS-URBAN-BASE-59,2X59,2-RECT-ANTISLIP ANTRACITE:26602
Type - IFC.REVIGRÉS-Dados de desempenho-Floor Covering - Rectilinearidade: ± 0.2% máx.± 0.8 mm; Ortogonalidade: ± 0.2% máx.± 1.5 mm; PlanaridadeDaSuperficie: ± 0.3% máx. ± 1.8 mm; QualidadeDaSuperficie: Cumpre; AbsorcaoDeAgua: < 0.05%; ModuloDeRuptura: > 45 N/mm²; ResistenciaAFlexao: > 3500 N; ResistenciaAAbrasaoProfunda: < 120 mm³; DilatacaoTermicaLinear: ≤ 8,0x10-6 °C-1; ResistenciaAoChoqueTermico: Resiste; DurabilidadeResistenciaAoGeloDegelo: Resiste; ResistenciaAoEscorregamentoDIN51130: R9; ResistenciaAoEscorregamentoDIN51097: A; ResistenciaAoEscorregamentoENV51097: A; ResistenciaAoEscorregamentoENV12633: Class 1; ResistenciaAoEscorregamentoANSIA1371: ≥0,42; ResistenciaAoDeslizamentoENV12633: Class 1; ResistenciaAsManchas: Class 5; ResistenciaABaixasConcentracoesDeAcidosEAlcalis: Classe LA; ResistenciaAAltasConcentracoesDeAcidosEAlcalis: Classe HA; LibertacaoDeCadmio: 0; LibertacaoDeChumbo: 0
Type - IFC.REVIGRÉS-Dados de especificação-Floor Covering - VariacaoTonalidade: 2; NivelDeTrafego: 5; EPavimento: Sim; ERevestimento: Sim; EExterno: Sim
Type - IFC.REVIGRÉS-Dados geométricos-Floor Covering - AlturaNominal: 8.5 mm; ComprimentoNominal: 59.2 mm; LarguraNominal: 59.2 mm
Type - IFC.REVIGRÉS-Dados de sustentabilidade-Floor Covering - EnergiaTermicaExportada: 0; ItemENovo: Sim; ItemEParcialmenteReciclado: 0.03; ItemEReciclado: Sim; VidaÚtilEsperada: 50; SubstanciasPerigosas: Não; PotencialDeEsgotamentoAbioticoDosRecursosFosseis: 203; PotencialDeEsgotamentoAbioticoDosRecursosNaoFosseisMineraisEMetais: 0.000701; PotencialDeAquecimentoGlobalBiogenico: -0.48; CombustiveisFosseisComPotencialDeAquecimentoGlobal: 13.9; PotencialDeAquecimentoGlobalUsoDoSoloEMudancaDeUsoDoSolo: 0.0246; PotencialDeEutrofizacaoFraccaoDeNutrientesQueAtingemOCompartimentoFinalDeAguaDoce: 0.000189; PotencialDeEutrofizacaoFraccaoDeNutrientesQueAtingemOCompartimentoFinalMarinho: 0.0122; EnergiaRecuperada: 0.00739; ConsumoDeAguaDoce: 0.113; UtilizacaoLiquidaDeAguaDoce: 0.113; ResiduosPerigososEliminados: 0.00221; ResiduosNaoPerigososEliminados: 1.83; MassaTotalDeResiduosRadioactivosEliminados: 0.000394; EnergiaElectricaExportada: 1.55; MateriaisParaRecuperacaoDeEnergia: 0.00739; MateriaisParaReciclagem: 0.0253; UnidadeEPD: 1 m²
Type - IFC.REVIGRÉS-Dados gerais-Floor Covering - Nome: REVIGRÉS-URBAN-BASE-59.2X59.2-RECT-ANTISLIP URBAN ANTRACITE; TipoProduto: Prensado a seco: grupo BIa UGL | Grés porcelânico técnico; NumeroDeRegistoDAP: EPD-REV-20240006-CCC1-EN; ReferenciaDAP: -; UrlDOP: -
Classification: C3020 (Uniformat)
Pset_CoveringCommon - TotalThickness: 10.5 mm
IFC.REVIGRÉS-Dados do fabricante-Floor Covering - Type: Floor: REVIGRÉS-URBAN-BASE-59,2X59,2-RECT-ANTISLIP ANTRACITE
IFC.REVIGRÉS-Dados de desempenho-Floor Covering - Type: Floor: REVIGRÉS-URBAN-BASE-59,2X59,2-RECT-ANTISLIP ANTRACITE
IFC.REVIGRÉS-Dados de especificação-Floor Covering - Type: Floor: REVIGRÉS-URBAN-BASE-59,2X59,2-RECT-ANTISLIP ANTRACITE
IFC.REVIGRÉS-Dados geométricos-Floor Covering - Type: Floor: REVIGRÉS-URBAN-BASE-59,2X59,2-RECT-ANTISLIP ANTRACITE
IFC.REVIGRÉS-Dados de sustentabilidade-Floor Covering - Type: Floor: REVIGRÉS-URBAN-BASE-59,2X59,2-RECT-ANTISLIP ANTRACITE

# IfcCovering: Floor:REVIGRÉS-URBAN-BASE-59,2X59,2-RECT-ANTISLIP BONE, Floor:REVIGRÉS-URBAN-BASE-59,2X59,2-RECT-ANTISLIP BONE:26610
In: Level 1
Type - PredefinedType: CLADDING; Material: REVIGRÉS-URBAN-BASE-60X60-RECT-ANTISLIP BONE 10.5 mm
Type - Pset_CoveringCommon - Reference: 31211331T1; Material: Grés porcelânico
Type - Pset_ElementShading - Roughness: 304.8 mm
Type - Pset_ManufacturerTypeInformation - Manufacturer: REVIGRÉS
Type - Pset_ProductRequirements - Category: Floors
Type - Pset_QuantityTakeOff - Reference: 31211331T1
Type - IFC.REVIGRÉS-Dados do fabricante-Floor Covering - FabricanteURL: https://www.revigres.pt/; ReferenciaModelo: Urban; NumeroGlobalDeItemComercial: 31211331T1; Acabamento: RECT; Material: Grés porcelânico; IdentificadorDoOperadorEconomico: 501840856; UrlFabricanteArtigo: https://www.revigres.pt/colecoes/urban; PaisOrigem: Portugal
Type - IFC.REVIGRÉS-Dados de desempenho-Floor Covering - Rectilinearidade: ± 0.2% máx.± 0.8 mm; Ortogonalidade: ± 0.2% máx.± 1.5 mm; PlanaridadeDaSuperficie: ± 0.3% máx. ± 1.8 mm; QualidadeDaSuperficie: Cumpre; AbsorcaoDeAgua: < 0.05%; ModuloDeRuptura: > 45 N/mm²; ResistenciaAFlexao: > 3500 N; ResistenciaAAbrasaoProfunda: < 120 mm³; DilatacaoTermicaLinear: ≤ 8,0x10-6 °C-1; ResistenciaAoChoqueTermico: Resiste; DurabilidadeResistenciaAoGeloDegelo: Resiste; ResistenciaAoEscorregamentoDIN51130: R9; ResistenciaAoEscorregamentoDIN51097: A; ResistenciaAoEscorregamentoENV51097: A; ResistenciaAoEscorregamentoENV12633: Class 1; ResistenciaAoEscorregamentoANSIA1371: ≥0,42; ResistenciaAoDeslizamentoENV12633: Class 1; ResistenciaAsManchas: Class 5; ResistenciaABaixasConcentracoesDeAcidosEAlcalis: Classe LA; ResistenciaAAltasConcentracoesDeAcidosEAlcalis: Classe HA; LibertacaoDeCadmio: 0; LibertacaoDeChumbo: 0
Type - IFC.REVIGRÉS-Dados de especificação-Floor Covering - VariacaoTonalidade: 2; NivelDeTrafego: 5; EPavimento: Sim; ERevestimento: Sim; EExterno: Sim
Type - IFC.REVIGRÉS-Dados geométricos-Floor Covering - AlturaNominal: 8.5 mm; ComprimentoNominal: 59.2 mm; LarguraNominal: 59.2 mm
Type - IFC.REVIGRÉS-Dados de sustentabilidade-Floor Covering - EnergiaTermicaExportada: 0; ItemENovo: Sim; ItemEParcialmenteReciclado: 0.19; ItemEReciclado: Sim; VidaÚtilEsperada: 50; SubstanciasPerigosas: Não; PotencialDeEsgotamentoAbioticoDosRecursosFosseis: 203; PotencialDeEsgotamentoAbioticoDosRecursosNaoFosseisMineraisEMetais: 0.000701; PotencialDeAquecimentoGlobalBiogenico: -0.48; CombustiveisFosseisComPotencialDeAquecimentoGlobal: 13.9; PotencialDeAquecimentoGlobalUsoDoSoloEMudancaDeUsoDoSolo: 0.0246; PotencialDeEutrofizacaoFraccaoDeNutrientesQueAtingemOCompartimentoFinalDeAguaDoce: 0.000189; PotencialDeEutrofizacaoFraccaoDeNutrientesQueAtingemOCompartimentoFinalMarinho: 0.0122; EnergiaRecuperada: 0.00739; ConsumoDeAguaDoce: 0.113; UtilizacaoLiquidaDeAguaDoce: 0.113; ResiduosPerigososEliminados: 0.00221; ResiduosNaoPerigososEliminados: 1.83; MassaTotalDeResiduosRadioactivosEliminados: 0.000394; EnergiaElectricaExportada: 1.55; MateriaisParaRecuperacaoDeEnergia: 0.00739; MateriaisParaReciclagem: 0.0253; UnidadeEPD: 1 m²
Type - IFC.REVIGRÉS-Dados gerais-Floor Covering - Nome: REVIGRÉS-URBAN-BASE-59.2X59.2-RECT-ANTISLIP URBAN BONE; TipoProduto: Prensado a seco: grupo BIa UGL | Grés porcelânico técnico; NumeroDeRegistoDAP: EPD-REV-20240006-CCC1-EN; ReferenciaDAP: -; UrlDOP: -
Classification: C3020 (Uniformat)
Pset_CoveringCommon - TotalThickness: 10.5 mm
IFC.REVIGRÉS-Dados do fabricante-Floor Covering - Type: Floor: REVIGRÉS-URBAN-BASE-59,2X59,2-RECT-ANTISLIP BONE
IFC.REVIGRÉS-Dados de desempenho-Floor Covering - Type: Floor: REVIGRÉS-URBAN-BASE-59,2X59,2-RECT-ANTISLIP BONE
IFC.REVIGRÉS-Dados de especificação-Floor Covering - Type: Floor: REVIGRÉS-URBAN-BASE-59,2X59,2-RECT-ANTISLIP BONE
IFC.REVIGRÉS-Dados geométricos-Floor Covering - Type: Floor: REVIGRÉS-URBAN-BASE-59,2X59,2-RECT-ANTISLIP BONE
IFC.REVIGRÉS-Dados de sustentabilidade-Floor Covering - Type: Floor: REVIGRÉS-URBAN-BASE-59,2X59,2-RECT-ANTISLIP BONE

# IfcCovering: Floor:REVIGRÉS-URBAN-BASE-59,2X59,2-RECT-ANTISLIP CRAFT, Floor:REVIGRÉS-URBAN-BASE-59,2X59,2-RECT-ANTISLIP CRAFT:26618
In: Level 1
Type - PredefinedType: CLADDING; Material: REVIGRÉS-URBAN-BASE-60X60-RECT-ANTISLIP CRAFT 10.5 mm
Type - Pset_CoveringCommon - Reference: 31211335T1; Material: Grés porcelânico
Type - Pset_ElementShading - Roughness: 304.8 mm
Type - Pset_ManufacturerTypeInformation - Manufacturer: REVIGRÉS
Type - Pset_ProductRequirements - Category: Floors
Type - Pset_QuantityTakeOff - Reference: 31211335T1
Type - IFC.REVIGRÉS-Dados do fabricante-Floor Covering - FabricanteURL: https://www.revigres.pt/; ReferenciaModelo: Urban; NumeroGlobalDeItemComercial: 31211335T1; Acabamento: RECT; Material: Grés porcelânico; IdentificadorDoOperadorEconomico: 501840856; UrlFabricanteArtigo: https://www.revigres.pt/colecoes/urban; PaisOrigem: Portugal
Type - IFC.REVIGRÉS-Dados de desempenho-Floor Covering - Rectilinearidade: ± 0.2% máx.± 0.8 mm; Ortogonalidade: ± 0.2% máx.± 1.5 mm; PlanaridadeDaSuperficie: ± 0.3% máx. ± 1.8 mm; QualidadeDaSuperficie: Cumpre; AbsorcaoDeAgua: < 0.05%; ModuloDeRuptura: > 45 N/mm²; ResistenciaAFlexao: > 3500 N; ResistenciaAAbrasaoProfunda: < 120 mm³; DilatacaoTermicaLinear: ≤ 8,0x10-6 °C-1; ResistenciaAoChoqueTermico: Resiste; DurabilidadeResistenciaAoGeloDegelo: Resiste; ResistenciaAoEscorregamentoDIN51130: R9; ResistenciaAoEscorregamentoDIN51097: A; ResistenciaAoEscorregamentoENV51097: A; ResistenciaAoEscorregamentoENV12633: Class 1; ResistenciaAoEscorregamentoANSIA1371: ≥0,42; ResistenciaAoDeslizamentoENV12633: Class 1; ResistenciaAsManchas: Class 5; ResistenciaABaixasConcentracoesDeAcidosEAlcalis: Classe LA; ResistenciaAAltasConcentracoesDeAcidosEAlcalis: Classe HA; LibertacaoDeCadmio: 0; LibertacaoDeChumbo: 0
Type - IFC.REVIGRÉS-Dados de especificação-Floor Covering - VariacaoTonalidade: 2; NivelDeTrafego: 5; EPavimento: Sim; ERevestimento: Sim; EExterno: Sim
Type - IFC.REVIGRÉS-Dados geométricos-Floor Covering - AlturaNominal: 8.5 mm; ComprimentoNominal: 59.2 mm; LarguraNominal: 59.2 mm
Type - IFC.REVIGRÉS-Dados de sustentabilidade-Floor Covering - EnergiaTermicaExportada: 0; ItemENovo: Sim; ItemEParcialmenteReciclado: 0.23; ItemEReciclado: Sim; VidaÚtilEsperada: 50; SubstanciasPerigosas: Não; PotencialDeEsgotamentoAbioticoDosRecursosFosseis: 203; PotencialDeEsgotamentoAbioticoDosRecursosNaoFosseisMineraisEMetais: 0.000701; PotencialDeAquecimentoGlobalBiogenico: -0.48; CombustiveisFosseisComPotencialDeAquecimentoGlobal: 13.9; PotencialDeAquecimentoGlobalUsoDoSoloEMudancaDeUsoDoSolo: 0.0246; PotencialDeEutrofizacaoFraccaoDeNutrientesQueAtingemOCompartimentoFinalDeAguaDoce: 0.000189; PotencialDeEutrofizacaoFraccaoDeNutrientesQueAtingemOCompartimentoFinalMarinho: 0.0122; EnergiaRecuperada: 0.00739; ConsumoDeAguaDoce: 0.113; UtilizacaoLiquidaDeAguaDoce: 0.113; ResiduosPerigososEliminados: 0.00221; ResiduosNaoPerigososEliminados: 1.83; MassaTotalDeResiduosRadioactivosEliminados: 0.000394; EnergiaElectricaExportada: 1.55; MateriaisParaRecuperacaoDeEnergia: 0.00739; MateriaisParaReciclagem: 0.0253; UnidadeEPD: 1 m²
Type - IFC.REVIGRÉS-Dados gerais-Floor Covering - Nome: REVIGRÉS-URBAN-BASE-59.2X59.2-RECT-ANTISLIP URBAN CRAFT; TipoProduto: Prensado a seco: grupo BIa UGL | Grés porcelânico técnico; NumeroDeRegistoDAP: EPD-REV-20240006-CCC1-EN; ReferenciaDAP: -; UrlDOP: -
Classification: C3020 (Uniformat)
Pset_CoveringCommon - TotalThickness: 10.5 mm
IFC.REVIGRÉS-Dados do fabricante-Floor Covering - Type: Floor: REVIGRÉS-URBAN-BASE-59,2X59,2-RECT-ANTISLIP CRAFT
IFC.REVIGRÉS-Dados de desempenho-Floor Covering - Type: Floor: REVIGRÉS-URBAN-BASE-59,2X59,2-RECT-ANTISLIP CRAFT
IFC.REVIGRÉS-Dados de especificação-Floor Covering - Type: Floor: REVIGRÉS-URBAN-BASE-59,2X59,2-RECT-ANTISLIP CRAFT
IFC.REVIGRÉS-Dados geométricos-Floor Covering - Type: Floor: REVIGRÉS-URBAN-BASE-59,2X59,2-RECT-ANTISLIP CRAFT
IFC.REVIGRÉS-Dados de sustentabilidade-Floor Covering - Type: Floor: REVIGRÉS-URBAN-BASE-59,2X59,2-RECT-ANTISLIP CRAFT

# IfcCovering: Floor:REVIGRÉS-URBAN-BASE-59,2X59,2-RECT-ANTISLIP FOG, Floor:REVIGRÉS-URBAN-BASE-59,2X59,2-RECT-ANTISLIP FOG:26626
In: Level 1
Type - PredefinedType: CLADDING; Material: REVIGRÉS-URBAN-BASE-60X60-RECT-ANTISLIP FOG 10.5 mm
Type - Pset_CoveringCommon - Reference: 31211332T1; Material: Grés porcelânico
Type - Pset_ElementShading - Roughness: 304.8 mm
Type - Pset_ManufacturerTypeInformation - Manufacturer: REVIGRÉS
Type - Pset_ProductRequirements - Category: Floors
Type - Pset_QuantityTakeOff - Reference: 31211332T1
Type - IFC.REVIGRÉS-Dados do fabricante-Floor Covering - FabricanteURL: https://www.revigres.pt/; ReferenciaModelo: Urban; NumeroGlobalDeItemComercial: 31211332T1; Acabamento: RECT; Material: Grés porcelânico; IdentificadorDoOperadorEconomico: 501840856; UrlFabricanteArtigo: https://www.revigres.pt/colecoes/urban; PaisOrigem: Portugal
Type - IFC.REVIGRÉS-Dados de desempenho-Floor Covering - Rectilinearidade: ± 0.2% máx.± 0.8 mm; Ortogonalidade: ± 0.2% máx.± 1.5 mm; PlanaridadeDaSuperficie: ± 0.3% máx. ± 1.8 mm; QualidadeDaSuperficie: Cumpre; AbsorcaoDeAgua: < 0.05%; ModuloDeRuptura: > 45 N/mm²; ResistenciaAFlexao: > 3500 N; ResistenciaAAbrasaoProfunda: < 120 mm³; DilatacaoTermicaLinear: ≤ 8,0x10-6 °C-1; ResistenciaAoChoqueTermico: Resiste; DurabilidadeResistenciaAoGeloDegelo: Resiste; ResistenciaAoEscorregamentoDIN51130: R9; ResistenciaAoEscorregamentoDIN51097: A; ResistenciaAoEscorregamentoENV51097: A; ResistenciaAoEscorregamentoENV12633: Class 1; ResistenciaAoEscorregamentoANSIA1371: ≥0,42; ResistenciaAoDeslizamentoENV12633: Class 1; ResistenciaAsManchas: Class 5; ResistenciaABaixasConcentracoesDeAcidosEAlcalis: Classe LA; ResistenciaAAltasConcentracoesDeAcidosEAlcalis: Classe HA; LibertacaoDeCadmio: 0; LibertacaoDeChumbo: 0
Type - IFC.REVIGRÉS-Dados de especificação-Floor Covering - VariacaoTonalidade: 2; NivelDeTrafego: 5; EPavimento: Sim; ERevestimento: Sim; EExterno: Sim
Type - IFC.REVIGRÉS-Dados geométricos-Floor Covering - AlturaNominal: 8.5 mm; ComprimentoNominal: 59.2 mm; LarguraNominal: 59.2 mm
Type - IFC.REVIGRÉS-Dados de sustentabilidade-Floor Covering - EnergiaTermicaExportada: 0; ItemENovo: Sim; ItemEParcialmenteReciclado: 0.23; ItemEReciclado: Sim; VidaÚtilEsperada: 50; SubstanciasPerigosas: Não; PotencialDeEsgotamentoAbioticoDosRecursosFosseis: 203; PotencialDeEsgotamentoAbioticoDosRecursosNaoFosseisMineraisEMetais: 0.000701; PotencialDeAquecimentoGlobalBiogenico: -0.48; CombustiveisFosseisComPotencialDeAquecimentoGlobal: 13.9; PotencialDeAquecimentoGlobalUsoDoSoloEMudancaDeUsoDoSolo: 0.0246; PotencialDeEutrofizacaoFraccaoDeNutrientesQueAtingemOCompartimentoFinalDeAguaDoce: 0.000189; PotencialDeEutrofizacaoFraccaoDeNutrientesQueAtingemOCompartimentoFinalMarinho: 0.0122; EnergiaRecuperada: 0.00739; ConsumoDeAguaDoce: 0.113; UtilizacaoLiquidaDeAguaDoce: 0.113; ResiduosPerigososEliminados: 0.00221; ResiduosNaoPerigososEliminados: 1.83; MassaTotalDeResiduosRadioactivosEliminados: 0.000394; EnergiaElectricaExportada: 1.55; MateriaisParaRecuperacaoDeEnergia: 0.00739; MateriaisParaReciclagem: 0.0253; UnidadeEPD: 1 m²
Type - IFC.REVIGRÉS-Dados gerais-Floor Covering - Nome: REVIGRÉS-URBAN-BASE-59.2X59.2-RECT-ANTISLIP URBAN FOG; TipoProduto: Prensado a seco: grupo BIa UGL | Grés porcelânico técnico; NumeroDeRegistoDAP: EPD-REV-20240006-CCC1-EN; ReferenciaDAP: -; UrlDOP: -
Classification: C3020 (Uniformat)
Pset_CoveringCommon - TotalThickness: 10.5 mm
IFC.REVIGRÉS-Dados do fabricante-Floor Covering - Type: Floor: REVIGRÉS-URBAN-BASE-59,2X59,2-RECT-ANTISLIP FOG
IFC.REVIGRÉS-Dados de desempenho-Floor Covering - Type: Floor: REVIGRÉS-URBAN-BASE-59,2X59,2-RECT-ANTISLIP FOG
IFC.REVIGRÉS-Dados de especificação-Floor Covering - Type: Floor: REVIGRÉS-URBAN-BASE-59,2X59,2-RECT-ANTISLIP FOG
IFC.REVIGRÉS-Dados geométricos-Floor Covering - Type: Floor: REVIGRÉS-URBAN-BASE-59,2X59,2-RECT-ANTISLIP FOG
IFC.REVIGRÉS-Dados de sustentabilidade-Floor Covering - Type: Floor: REVIGRÉS-URBAN-BASE-59,2X59,2-RECT-ANTISLIP FOG

# IfcCovering: Floor:REVIGRÉS-URBAN-BASE-59,2X59,2-RECT-ANTISLIP GRIS, Floor:REVIGRÉS-URBAN-BASE-59,2X59,2-RECT-ANTISLIP GRIS:26634
In: Level 1
Type - PredefinedType: CLADDING; Material: REVIGRÉS-URBAN-BASE-60X60-RECT-ANTISLIP GRIS 10.5 mm
Type - Pset_CoveringCommon - Reference: 31211333T1; Material: Grés porcelânico
Type - Pset_ElementShading - Roughness: 304.8 mm
Type - Pset_ManufacturerTypeInformation - Manufacturer: REVIGRÉS
Type - Pset_ProductRequirements - Category: Floors
Type - Pset_QuantityTakeOff - Reference: 31211333T1
Type - IFC.REVIGRÉS-Dados do fabricante-Floor Covering - FabricanteURL: https://www.revigres.pt/; ReferenciaModelo: Urban; NumeroGlobalDeItemComercial: 31211333T1; Acabamento: RECT; Material: Grés porcelânico; IdentificadorDoOperadorEconomico: 501840856; UrlFabricanteArtigo: https://www.revigres.pt/colecoes/urban; PaisOrigem: Portugal
Type - IFC.REVIGRÉS-Dados de desempenho-Floor Covering - Rectilinearidade: ± 0.2% máx.± 0.8 mm; Ortogonalidade: ± 0.2% máx.± 1.5 mm; PlanaridadeDaSuperficie: ± 0.3% máx. ± 1.8 mm; QualidadeDaSuperficie: Cumpre; AbsorcaoDeAgua: < 0.05%; ModuloDeRuptura: > 45 N/mm²; ResistenciaAFlexao: > 3500 N; ResistenciaAAbrasaoProfunda: < 120 mm³; DilatacaoTermicaLinear: ≤ 8,0x10-6 °C-1; ResistenciaAoChoqueTermico: Resiste; DurabilidadeResistenciaAoGeloDegelo: Resiste; ResistenciaAoEscorregamentoDIN51130: R9; ResistenciaAoEscorregamentoDIN51097: A; ResistenciaAoEscorregamentoENV51097: A; ResistenciaAoEscorregamentoENV12633: Class 1; ResistenciaAoEscorregamentoANSIA1371: ≥0,42; ResistenciaAoDeslizamentoENV12633: Class 1; ResistenciaAsManchas: Class 5; ResistenciaABaixasConcentracoesDeAcidosEAlcalis: Classe LA; ResistenciaAAltasConcentracoesDeAcidosEAlcalis: Classe HA; LibertacaoDeCadmio: 0; LibertacaoDeChumbo: 0
Type - IFC.REVIGRÉS-Dados de especificação-Floor Covering - VariacaoTonalidade: 2; NivelDeTrafego: 5; EPavimento: Sim; ERevestimento: Sim; EExterno: Sim
Type - IFC.REVIGRÉS-Dados geométricos-Floor Covering - AlturaNominal: 8.5 mm; ComprimentoNominal: 59.2 mm; LarguraNominal: 59.2 mm
Type - IFC.REVIGRÉS-Dados de sustentabilidade-Floor Covering - EnergiaTermicaExportada: 0; ItemENovo: Sim; ItemEParcialmenteReciclado: 0.03; ItemEReciclado: Sim; VidaÚtilEsperada: 50; SubstanciasPerigosas: Não; PotencialDeEsgotamentoAbioticoDosRecursosFosseis: 203; PotencialDeEsgotamentoAbioticoDosRecursosNaoFosseisMineraisEMetais: 0.000701; PotencialDeAquecimentoGlobalBiogenico: -0.48; CombustiveisFosseisComPotencialDeAquecimentoGlobal: 13.9; PotencialDeAquecimentoGlobalUsoDoSoloEMudancaDeUsoDoSolo: 0.0246; PotencialDeEutrofizacaoFraccaoDeNutrientesQueAtingemOCompartimentoFinalDeAguaDoce: 0.000189; PotencialDeEutrofizacaoFraccaoDeNutrientesQueAtingemOCompartimentoFinalMarinho: 0.0122; EnergiaRecuperada: 0.00739; ConsumoDeAguaDoce: 0.113; UtilizacaoLiquidaDeAguaDoce: 0.113; ResiduosPerigososEliminados: 0.00221; ResiduosNaoPerigososEliminados: 1.83; MassaTotalDeResiduosRadioactivosEliminados: 0.000394; EnergiaElectricaExportada: 1.55; MateriaisParaRecuperacaoDeEnergia: 0.00739; MateriaisParaReciclagem: 0.0253; UnidadeEPD: 1 m²
Type - IFC.REVIGRÉS-Dados gerais-Floor Covering - Nome: REVIGRÉS-URBAN-BASE-59.2X59.2-RECT-ANTISLIP URBAN GRIS; TipoProduto: Prensado a seco: grupo BIa UGL | Grés porcelânico técnico; NumeroDeRegistoDAP: EPD-REV-20240006-CCC1-EN; ReferenciaDAP: -; UrlDOP: -
Classification: C3020 (Uniformat)
Pset_CoveringCommon - TotalThickness: 10.5 mm
IFC.REVIGRÉS-Dados do fabricante-Floor Covering - Type: Floor: REVIGRÉS-URBAN-BASE-59,2X59,2-RECT-ANTISLIP GRIS
IFC.REVIGRÉS-Dados de desempenho-Floor Covering - Type: Floor: REVIGRÉS-URBAN-BASE-59,2X59,2-RECT-ANTISLIP GRIS
IFC.REVIGRÉS-Dados de especificação-Floor Covering - Type: Floor: REVIGRÉS-URBAN-BASE-59,2X59,2-RECT-ANTISLIP GRIS
IFC.REVIGRÉS-Dados geométricos-Floor Covering - Type: Floor: REVIGRÉS-URBAN-BASE-59,2X59,2-RECT-ANTISLIP GRIS
IFC.REVIGRÉS-Dados de sustentabilidade-Floor Covering - Type: Floor: REVIGRÉS-URBAN-BASE-59,2X59,2-RECT-ANTISLIP GRIS

# IfcCovering: Floor:REVIGRÉS-URBAN-BASE-59,2X59,2-RECT-ANTISLIP OFFWHITE, Floor:REVIGRÉS-URBAN-BASE-59,2X59,2-RECT-ANTISLIP OFFWHITE:26642
In: Level 1
Type - PredefinedType: CLADDING; Material: REVIGRÉS-URBAN-BASE-60X60-RECT-ANTISLIP OFFWHITE 10.5 mm
Type - Pset_CoveringCommon - Reference: 31211334T1; Material: Grés porcelânico
Type - Pset_ElementShading - Roughness: 304.8 mm
Type - Pset_ManufacturerTypeInformation - Manufacturer: REVIGRÉS
Type - Pset_ProductRequirements - Category: Floors
Type - Pset_QuantityTakeOff - Reference: 31211334T1
Type - IFC.REVIGRÉS-Dados do fabricante-Floor Covering - FabricanteURL: https://www.revigres.pt/; ReferenciaModelo: Urban; NumeroGlobalDeItemComercial: 31211334T1; Acabamento: RECT; Material: Grés porcelânico; IdentificadorDoOperadorEconomico: 501840856; UrlFabricanteArtigo: https://www.revigres.pt/colecoes/urban; PaisOrigem: Portugal
Type - IFC.REVIGRÉS-Dados de desempenho-Floor Covering - Rectilinearidade: ± 0.2% máx.± 0.8 mm; Ortogonalidade: ± 0.2% máx.± 1.5 mm; PlanaridadeDaSuperficie: ± 0.3% máx. ± 1.8 mm; QualidadeDaSuperficie: Cumpre; AbsorcaoDeAgua: < 0.05%; ModuloDeRuptura: > 45 N/mm²; ResistenciaAFlexao: > 3500 N; ResistenciaAAbrasaoProfunda: < 120 mm³; DilatacaoTermicaLinear: ≤ 8,0x10-6 °C-1; ResistenciaAoChoqueTermico: Resiste; DurabilidadeResistenciaAoGeloDegelo: Resiste; ResistenciaAoEscorregamentoDIN51130: R9; ResistenciaAoEscorregamentoDIN51097: A; ResistenciaAoEscorregamentoENV51097: A; ResistenciaAoEscorregamentoENV12633: Class 1; ResistenciaAoEscorregamentoANSIA1371: ≥0,42; ResistenciaAoDeslizamentoENV12633: Class 1; ResistenciaAsManchas: Class 5; ResistenciaABaixasConcentracoesDeAcidosEAlcalis: Classe LA; ResistenciaAAltasConcentracoesDeAcidosEAlcalis: Classe HA; LibertacaoDeCadmio: 0; LibertacaoDeChumbo: 0
Type - IFC.REVIGRÉS-Dados de especificação-Floor Covering - VariacaoTonalidade: 2; NivelDeTrafego: 5; EPavimento: Sim; ERevestimento: Sim; EExterno: Sim
Type - IFC.REVIGRÉS-Dados geométricos-Floor Covering - AlturaNominal: 8.5 mm; ComprimentoNominal: 59.2 mm; LarguraNominal: 59.2 mm
Type - IFC.REVIGRÉS-Dados de sustentabilidade-Floor Covering - EnergiaTermicaExportada: 0; ItemENovo: Sim; ItemEParcialmenteReciclado: 0.29; ItemEReciclado: Sim; VidaÚtilEsperada: 50; SubstanciasPerigosas: Não; PotencialDeEsgotamentoAbioticoDosRecursosFosseis: 203; PotencialDeEsgotamentoAbioticoDosRecursosNaoFosseisMineraisEMetais: 0.000701; PotencialDeAquecimentoGlobalBiogenico: -0.48; CombustiveisFosseisComPotencialDeAquecimentoGlobal: 13.9; PotencialDeAquecimentoGlobalUsoDoSoloEMudancaDeUsoDoSolo: 0.0246; PotencialDeEutrofizacaoFraccaoDeNutrientesQueAtingemOCompartimentoFinalDeAguaDoce: 0.000189; PotencialDeEutrofizacaoFraccaoDeNutrientesQueAtingemOCompartimentoFinalMarinho: 0.0122; EnergiaRecuperada: 0.00739; ConsumoDeAguaDoce: 0.113; UtilizacaoLiquidaDeAguaDoce: 0.113; ResiduosPerigososEliminados: 0.00221; ResiduosNaoPerigososEliminados: 1.83; MassaTotalDeResiduosRadioactivosEliminados: 0.000394; EnergiaElectricaExportada: 1.55; MateriaisParaRecuperacaoDeEnergia: 0.00739; MateriaisParaReciclagem: 0.0253; UnidadeEPD: 1 m²
Type - IFC.REVIGRÉS-Dados gerais-Floor Covering - Nome: REVIGRÉS-URBAN-BASE-59.2X59.2-RECT-ANTISLIP URBAN OFFWHITE; TipoProduto: Prensado a seco: grupo BIa UGL | Grés porcelânico técnico; NumeroDeRegistoDAP: EPD-REV-20240006-CCC1-EN; ReferenciaDAP: -; UrlDOP: -
Classification: C3020 (Uniformat)
Pset_CoveringCommon - TotalThickness: 10.5 mm
IFC.REVIGRÉS-Dados do fabricante-Floor Covering - Type: Floor: REVIGRÉS-URBAN-BASE-59,2X59,2-RECT-ANTISLIP OFFWHITE
IFC.REVIGRÉS-Dados de desempenho-Floor Covering - Type: Floor: REVIGRÉS-URBAN-BASE-59,2X59,2-RECT-ANTISLIP OFFWHITE
IFC.REVIGRÉS-Dados de especificação-Floor Covering - Type: Floor: REVIGRÉS-URBAN-BASE-59,2X59,2-RECT-ANTISLIP OFFWHITE
IFC.REVIGRÉS-Dados geométricos-Floor Covering - Type: Floor: REVIGRÉS-URBAN-BASE-59,2X59,2-RECT-ANTISLIP OFFWHITE
IFC.REVIGRÉS-Dados de sustentabilidade-Floor Covering - Type: Floor: REVIGRÉS-URBAN-BASE-59,2X59,2-RECT-ANTISLIP OFFWHITE

# IfcCovering: Floor:REVIGRÉS-URBAN-BASE-59,2X59,2-RECT-ANTRACITE, Floor:REVIGRÉS-URBAN-BASE-59,2X59,2-RECT-ANTRACITE:22904
In: Level 1
Type - PredefinedType: CLADDING; Material: REVIGRÉS-URBAN-BASE-60X60-RECT-ANTRACITE 10.5 mm
Type - Pset_CoveringCommon - Reference: 31211348U1; Material: Grés porcelânico
Type - Pset_ElementShading - Roughness: 304.8 mm
Type - Pset_ManufacturerTypeInformation - Manufacturer: REVIGRÉS
Type - Pset_ProductRequirements - Category: Floors
Type - Pset_QuantityTakeOff - Reference: 31211348U1
Type - IFC.REVIGRÉS-Dados do fabricante-Floor Covering - FabricanteURL: https://www.revigres.pt/; ReferenciaModelo: Urban; NumeroGlobalDeItemComercial: 31211348U1; Acabamento: RECT; Material: Grés porcelânico; IdentificadorDoOperadorEconomico: 501840856; UrlFabricanteArtigo: https://www.revigres.pt/colecoes/urban; PaisOrigem: Portugal
Type - IFC.REVIGRÉS-Dados de desempenho-Floor Covering - Rectilinearidade: ± 0.2% máx.± 0.8 mm; Ortogonalidade: ± 0.2% máx.± 1.5 mm; PlanaridadeDaSuperficie: ± 0.3% máx. ± 1.8 mm; QualidadeDaSuperficie: Cumpre; AbsorcaoDeAgua: < 0.05%; ModuloDeRuptura: > 45 N/mm²; ResistenciaAFlexao: > 3500 N; ResistenciaAAbrasaoProfunda: < 120 mm³; DilatacaoTermicaLinear: ≤ 8,0x10-6 °C-1; ResistenciaAoChoqueTermico: Resiste; DurabilidadeResistenciaAoGeloDegelo: Resiste; ResistenciaAoEscorregamentoDIN51130: R9; ResistenciaAoEscorregamentoDIN51097: A; ResistenciaAoEscorregamentoENV51097: A; ResistenciaAoEscorregamentoENV12633: Class 1; ResistenciaAoEscorregamentoANSIA1371: ≥0,42; ResistenciaAoDeslizamentoENV12633: Class 1; ResistenciaAsManchas: Class 5; ResistenciaABaixasConcentracoesDeAcidosEAlcalis: Classe LA; ResistenciaAAltasConcentracoesDeAcidosEAlcalis: Classe HA; LibertacaoDeCadmio: 0; LibertacaoDeChumbo: 0
Type - IFC.REVIGRÉS-Dados de especificação-Floor Covering - VariacaoTonalidade: 2; NivelDeTrafego: 5; EPavimento: Sim; ERevestimento: Sim; EExterno: Sim
Type - IFC.REVIGRÉS-Dados geométricos-Floor Covering - AlturaNominal: 8.5 mm; ComprimentoNominal: 59.2 mm; LarguraNominal: 59.2 mm
Type - IFC.REVIGRÉS-Dados de sustentabilidade-Floor Covering - EnergiaTermicaExportada: 0; ItemENovo: Sim; ItemEParcialmenteReciclado: 0.03; ItemEReciclado: Sim; VidaÚtilEsperada: 50; SubstanciasPerigosas: Não; PotencialDeEsgotamentoAbioticoDosRecursosFosseis: 203; PotencialDeEsgotamentoAbioticoDosRecursosNaoFosseisMineraisEMetais: 0.000701; PotencialDeAquecimentoGlobalBiogenico: -0.48; CombustiveisFosseisComPotencialDeAquecimentoGlobal: 13.9; PotencialDeAquecimentoGlobalUsoDoSoloEMudancaDeUsoDoSolo: 0.0246; PotencialDeEutrofizacaoFraccaoDeNutrientesQueAtingemOCompartimentoFinalDeAguaDoce: 0.000189; PotencialDeEutrofizacaoFraccaoDeNutrientesQueAtingemOCompartimentoFinalMarinho: 0.0122; EnergiaRecuperada: 0.00739; ConsumoDeAguaDoce: 0.113; UtilizacaoLiquidaDeAguaDoce: 0.113; ResiduosPerigososEliminados: 0.00221; ResiduosNaoPerigososEliminados: 1.83; MassaTotalDeResiduosRadioactivosEliminados: 0.000394; EnergiaElectricaExportada: 1.55; MateriaisParaRecuperacaoDeEnergia: 0.00739; MateriaisParaReciclagem: 0.0253; UnidadeEPD: 1 m²
Type - IFC.REVIGRÉS-Dados gerais-Floor Covering - Nome: REVIGRÉS-URBAN-BASE-59.2X59.2-RECT-URBAN ANTRACITE; TipoProduto: Prensado a seco: grupo BIa UGL | Grés porcelânico técnico; NumeroDeRegistoDAP: EPD-REV-20240006-CCC1-EN; ReferenciaDAP: -; UrlDOP: -
Classification: C3020 (Uniformat)
Pset_CoveringCommon - TotalThickness: 10.5 mm
IFC.REVIGRÉS-Dados do fabricante-Floor Covering - Type: Floor: REVIGRÉS-URBAN-BASE-59,2X59,2-RECT-ANTRACITE
IFC.REVIGRÉS-Dados de desempenho-Floor Covering - Type: Floor: REVIGRÉS-URBAN-BASE-59,2X59,2-RECT-ANTRACITE
IFC.REVIGRÉS-Dados de especificação-Floor Covering - Type: Floor: REVIGRÉS-URBAN-BASE-59,2X59,2-RECT-ANTRACITE
IFC.REVIGRÉS-Dados geométricos-Floor Covering - Type: Floor: REVIGRÉS-URBAN-BASE-59,2X59,2-RECT-ANTRACITE
IFC.REVIGRÉS-Dados de sustentabilidade-Floor Covering - Type: Floor: REVIGRÉS-URBAN-BASE-59,2X59,2-RECT-ANTRACITE

# IfcCovering: Floor:REVIGRÉS-URBAN-BASE-59,2X59,2-RECT-BONE, Floor:REVIGRÉS-URBAN-BASE-59,2X59,2-RECT-BONE:22920
In: Level 1
Type - PredefinedType: CLADDING; Material: REVIGRÉS-URBAN-BASE-60X60-RECT-BONE 10.5 mm
Type - Pset_CoveringCommon - Reference: 31211320T1; Material: Grés porcelânico
Type - Pset_ElementShading - Roughness: 304.8 mm
Type - Pset_ManufacturerTypeInformation - Manufacturer: REVIGRÉS
Type - Pset_ProductRequirements - Category: Floors
Type - Pset_QuantityTakeOff - Reference: 31211320T1
Type - IFC.REVIGRÉS-Dados do fabricante-Floor Covering - FabricanteURL: https://www.revigres.pt/; ReferenciaModelo: Urban; NumeroGlobalDeItemComercial: 31211320T1; Acabamento: RECT; Material: Grés porcelânico; IdentificadorDoOperadorEconomico: 501840856; UrlFabricanteArtigo: https://www.revigres.pt/colecoes/urban; PaisOrigem: Portugal
Type - IFC.REVIGRÉS-Dados de desempenho-Floor Covering - Rectilinearidade: ± 0.2% máx.± 0.8 mm; Ortogonalidade: ± 0.2% máx.± 1.5 mm; PlanaridadeDaSuperficie: ± 0.3% máx. ± 1.8 mm; QualidadeDaSuperficie: Cumpre; AbsorcaoDeAgua: < 0.05%; ModuloDeRuptura: > 45 N/mm²; ResistenciaAFlexao: > 3500 N; ResistenciaAAbrasaoProfunda: < 120 mm³; DilatacaoTermicaLinear: ≤ 8,0x10-6 °C-1; ResistenciaAoChoqueTermico: Resiste; DurabilidadeResistenciaAoGeloDegelo: Resiste; ResistenciaAoEscorregamentoDIN51130: R9; ResistenciaAoEscorregamentoDIN51097: A; ResistenciaAoEscorregamentoENV51097: A; ResistenciaAoEscorregamentoENV12633: Class 1; ResistenciaAoEscorregamentoANSIA1371: ≥0,42; ResistenciaAoDeslizamentoENV12633: Class 1; ResistenciaAsManchas: Class 5; ResistenciaABaixasConcentracoesDeAcidosEAlcalis: Classe LA; ResistenciaAAltasConcentracoesDeAcidosEAlcalis: Classe HA; LibertacaoDeCadmio: 0; LibertacaoDeChumbo: 0
Type - IFC.REVIGRÉS-Dados de especificação-Floor Covering - VariacaoTonalidade: 2; NivelDeTrafego: 5; EPavimento: Sim; ERevestimento: Sim; EExterno: Sim
Type - IFC.REVIGRÉS-Dados geométricos-Floor Covering - AlturaNominal: 8.5 mm; ComprimentoNominal: 59.2 mm; LarguraNominal: 59.2 mm
Type - IFC.REVIGRÉS-Dados de sustentabilidade-Floor Covering - EnergiaTermicaExportada: 0; ItemENovo: Sim; ItemEParcialmenteReciclado: 0.19; ItemEReciclado: Sim; VidaÚtilEsperada: 50; SubstanciasPerigosas: Não; PotencialDeEsgotamentoAbioticoDosRecursosFosseis: 203; PotencialDeEsgotamentoAbioticoDosRecursosNaoFosseisMineraisEMetais: 0.000701; PotencialDeAquecimentoGlobalBiogenico: -0.48; CombustiveisFosseisComPotencialDeAquecimentoGlobal: 13.9; PotencialDeAquecimentoGlobalUsoDoSoloEMudancaDeUsoDoSolo: 0.0246; PotencialDeEutrofizacaoFraccaoDeNutrientesQueAtingemOCompartimentoFinalDeAguaDoce: 0.000189; PotencialDeEutrofizacaoFraccaoDeNutrientesQueAtingemOCompartimentoFinalMarinho: 0.0122; EnergiaRecuperada: 0.00739; ConsumoDeAguaDoce: 0.113; UtilizacaoLiquidaDeAguaDoce: 0.113; ResiduosPerigososEliminados: 0.00221; ResiduosNaoPerigososEliminados: 1.83; MassaTotalDeResiduosRadioactivosEliminados: 0.000394; EnergiaElectricaExportada: 1.55; MateriaisParaRecuperacaoDeEnergia: 0.00739; MateriaisParaReciclagem: 0.0253; UnidadeEPD: 1 m²
Type - IFC.REVIGRÉS-Dados gerais-Floor Covering - Nome: REVIGRÉS-URBAN-BASE-59.2X59.2-RECT-URBAN BONE; TipoProduto: Prensado a seco: grupo BIa UGL | Grés porcelânico técnico; NumeroDeRegistoDAP: EPD-REV-20240006-CCC1-EN; ReferenciaDAP: -; UrlDOP: -
Classification: C3020 (Uniformat)
Pset_CoveringCommon - TotalThickness: 10.5 mm
IFC.REVIGRÉS-Dados do fabricante-Floor Covering - Type: Floor: REVIGRÉS-URBAN-BASE-59,2X59,2-RECT-BONE
IFC.REVIGRÉS-Dados de desempenho-Floor Covering - Type: Floor: REVIGRÉS-URBAN-BASE-59,2X59,2-RECT-BONE
IFC.REVIGRÉS-Dados de especificação-Floor Covering - Type: Floor: REVIGRÉS-URBAN-BASE-59,2X59,2-RECT-BONE
IFC.REVIGRÉS-Dados geométricos-Floor Covering - Type: Floor: REVIGRÉS-URBAN-BASE-59,2X59,2-RECT-BONE
IFC.REVIGRÉS-Dados de sustentabilidade-Floor Covering - Type: Floor: REVIGRÉS-URBAN-BASE-59,2X59,2-RECT-BONE

# IfcCovering: Floor:REVIGRÉS-URBAN-BASE-59,2X59,2-RECT-CRAFT, Floor:REVIGRÉS-URBAN-BASE-59,2X59,2-RECT-CRAFT:22936
In: Level 1
Type - PredefinedType: CLADDING; Material: REVIGRÉS-URBAN-BASE-60X60-RECT-CRAFT 10.5 mm
Type - Pset_CoveringCommon - Reference: 31211324T1; Material: Grés porcelânico
Type - Pset_ElementShading - Roughness: 304.8 mm
Type - Pset_ManufacturerTypeInformation - Manufacturer: REVIGRÉS
Type - Pset_ProductRequirements - Category: Floors
Type - Pset_QuantityTakeOff - Reference: 31211324T1
Type - IFC.REVIGRÉS-Dados do fabricante-Floor Covering - FabricanteURL: https://www.revigres.pt/; ReferenciaModelo: Urban; NumeroGlobalDeItemComercial: 31211324T1; Acabamento: RECT; Material: Grés porcelânico; IdentificadorDoOperadorEconomico: 501840856; UrlFabricanteArtigo: https://www.revigres.pt/colecoes/urban; PaisOrigem: Portugal
Type - IFC.REVIGRÉS-Dados de desempenho-Floor Covering - Rectilinearidade: ± 0.2% máx.± 0.8 mm; Ortogonalidade: ± 0.2% máx.± 1.5 mm; PlanaridadeDaSuperficie: ± 0.3% máx. ± 1.8 mm; QualidadeDaSuperficie: Cumpre; AbsorcaoDeAgua: < 0.05%; ModuloDeRuptura: > 45 N/mm²; ResistenciaAFlexao: > 3500 N; ResistenciaAAbrasaoProfunda: < 120 mm³; DilatacaoTermicaLinear: ≤ 8,0x10-6 °C-1; ResistenciaAoChoqueTermico: Resiste; DurabilidadeResistenciaAoGeloDegelo: Resiste; ResistenciaAoEscorregamentoDIN51130: R9; ResistenciaAoEscorregamentoDIN51097: A; ResistenciaAoEscorregamentoENV51097: A; ResistenciaAoEscorregamentoENV12633: Class 1; ResistenciaAoEscorregamentoANSIA1371: ≥0,42; ResistenciaAoDeslizamentoENV12633: Class 1; ResistenciaAsManchas: Class 5; ResistenciaABaixasConcentracoesDeAcidosEAlcalis: Classe LA; ResistenciaAAltasConcentracoesDeAcidosEAlcalis: Classe HA; LibertacaoDeCadmio: 0; LibertacaoDeChumbo: 0
Type - IFC.REVIGRÉS-Dados de especificação-Floor Covering - VariacaoTonalidade: 2; NivelDeTrafego: 5; EPavimento: Sim; ERevestimento: Sim; EExterno: Sim
Type - IFC.REVIGRÉS-Dados geométricos-Floor Covering - AlturaNominal: 8.5 mm; ComprimentoNominal: 59.2 mm; LarguraNominal: 59.2 mm
Type - IFC.REVIGRÉS-Dados de sustentabilidade-Floor Covering - EnergiaTermicaExportada: 0; ItemENovo: Sim; ItemEParcialmenteReciclado: 0.23; ItemEReciclado: Sim; VidaÚtilEsperada: 50; SubstanciasPerigosas: Não; PotencialDeEsgotamentoAbioticoDosRecursosFosseis: 203; PotencialDeEsgotamentoAbioticoDosRecursosNaoFosseisMineraisEMetais: 0.000701; PotencialDeAquecimentoGlobalBiogenico: -0.48; CombustiveisFosseisComPotencialDeAquecimentoGlobal: 13.9; PotencialDeAquecimentoGlobalUsoDoSoloEMudancaDeUsoDoSolo: 0.0246; PotencialDeEutrofizacaoFraccaoDeNutrientesQueAtingemOCompartimentoFinalDeAguaDoce: 0.000189; PotencialDeEutrofizacaoFraccaoDeNutrientesQueAtingemOCompartimentoFinalMarinho: 0.0122; EnergiaRecuperada: 0.00739; ConsumoDeAguaDoce: 0.113; UtilizacaoLiquidaDeAguaDoce: 0.113; ResiduosPerigososEliminados: 0.00221; ResiduosNaoPerigososEliminados: 1.83; MassaTotalDeResiduosRadioactivosEliminados: 0.000394; EnergiaElectricaExportada: 1.55; MateriaisParaRecuperacaoDeEnergia: 0.00739; MateriaisParaReciclagem: 0.0253; UnidadeEPD: 1 m²
Type - IFC.REVIGRÉS-Dados gerais-Floor Covering - Nome: REVIGRÉS-URBAN-BASE-59.2X59.2-RECT-URBAN CRAFT; TipoProduto: Prensado a seco: grupo BIa UGL | Grés porcelânico técnico; NumeroDeRegistoDAP: EPD-REV-20240006-CCC1-EN; ReferenciaDAP: -; UrlDOP: -
Classification: C3020 (Uniformat)
Pset_CoveringCommon - TotalThickness: 10.5 mm
IFC.REVIGRÉS-Dados do fabricante-Floor Covering - Type: Floor: REVIGRÉS-URBAN-BASE-59,2X59,2-RECT-CRAFT
IFC.REVIGRÉS-Dados de desempenho-Floor Covering - Type: Floor: REVIGRÉS-URBAN-BASE-59,2X59,2-RECT-CRAFT
IFC.REVIGRÉS-Dados de especificação-Floor Covering - Type: Floor: REVIGRÉS-URBAN-BASE-59,2X59,2-RECT-CRAFT
IFC.REVIGRÉS-Dados geométricos-Floor Covering - Type: Floor: REVIGRÉS-URBAN-BASE-59,2X59,2-RECT-CRAFT
IFC.REVIGRÉS-Dados de sustentabilidade-Floor Covering - Type: Floor: REVIGRÉS-URBAN-BASE-59,2X59,2-RECT-CRAFT

# IfcCovering: Floor:REVIGRÉS-URBAN-BASE-59,2X59,2-RECT-FOG, Floor:REVIGRÉS-URBAN-BASE-59,2X59,2-RECT-FOG:22952
In: Level 1
Type - PredefinedType: CLADDING; Material: REVIGRÉS-URBAN-BASE-60X60-RECT-FOG 10.5 mm
Type - Pset_CoveringCommon - Reference: 31211321T1; Material: Grés porcelânico
Type - Pset_ElementShading - Roughness: 304.8 mm
Type - Pset_ManufacturerTypeInformation - Manufacturer: REVIGRÉS
Type - Pset_ProductRequirements - Category: Floors
Type - Pset_QuantityTakeOff - Reference: 31211321T1
Type - IFC.REVIGRÉS-Dados do fabricante-Floor Covering - FabricanteURL: https://www.revigres.pt/; ReferenciaModelo: Urban; NumeroGlobalDeItemComercial: 31211321T1; Acabamento: RECT; Material: Grés porcelânico; IdentificadorDoOperadorEconomico: 501840856; UrlFabricanteArtigo: https://www.revigres.pt/colecoes/urban; PaisOrigem: Portugal
Type - IFC.REVIGRÉS-Dados de desempenho-Floor Covering - Rectilinearidade: ± 0.2% máx.± 0.8 mm; Ortogonalidade: ± 0.2% máx.± 1.5 mm; PlanaridadeDaSuperficie: ± 0.3% máx. ± 1.8 mm; QualidadeDaSuperficie: Cumpre; AbsorcaoDeAgua: < 0.05%; ModuloDeRuptura: > 45 N/mm²; ResistenciaAFlexao: > 3500 N; ResistenciaAAbrasaoProfunda: < 120 mm³; DilatacaoTermicaLinear: ≤ 8,0x10-6 °C-1; ResistenciaAoChoqueTermico: Resiste; DurabilidadeResistenciaAoGeloDegelo: Resiste; ResistenciaAoEscorregamentoDIN51130: R9; ResistenciaAoEscorregamentoDIN51097: A; ResistenciaAoEscorregamentoENV51097: A; ResistenciaAoEscorregamentoENV12633: Class 1; ResistenciaAoEscorregamentoANSIA1371: ≥0,42; ResistenciaAoDeslizamentoENV12633: Class 1; ResistenciaAsManchas: Class 5; ResistenciaABaixasConcentracoesDeAcidosEAlcalis: Classe LA; ResistenciaAAltasConcentracoesDeAcidosEAlcalis: Classe HA; LibertacaoDeCadmio: 0; LibertacaoDeChumbo: 0
Type - IFC.REVIGRÉS-Dados de especificação-Floor Covering - VariacaoTonalidade: 2; NivelDeTrafego: 5; EPavimento: Sim; ERevestimento: Sim; EExterno: Sim
Type - IFC.REVIGRÉS-Dados geométricos-Floor Covering - AlturaNominal: 8.5 mm; ComprimentoNominal: 59.2 mm; LarguraNominal: 59.2 mm
Type - IFC.REVIGRÉS-Dados de sustentabilidade-Floor Covering - EnergiaTermicaExportada: 0; ItemENovo: Sim; ItemEParcialmenteReciclado: 0.23; ItemEReciclado: Sim; VidaÚtilEsperada: 50; SubstanciasPerigosas: Não; PotencialDeEsgotamentoAbioticoDosRecursosFosseis: 203; PotencialDeEsgotamentoAbioticoDosRecursosNaoFosseisMineraisEMetais: 0.000701; PotencialDeAquecimentoGlobalBiogenico: -0.48; CombustiveisFosseisComPotencialDeAquecimentoGlobal: 13.9; PotencialDeAquecimentoGlobalUsoDoSoloEMudancaDeUsoDoSolo: 0.0246; PotencialDeEutrofizacaoFraccaoDeNutrientesQueAtingemOCompartimentoFinalDeAguaDoce: 0.000189; PotencialDeEutrofizacaoFraccaoDeNutrientesQueAtingemOCompartimentoFinalMarinho: 0.0122; EnergiaRecuperada: 0.00739; ConsumoDeAguaDoce: 0.113; UtilizacaoLiquidaDeAguaDoce: 0.113; ResiduosPerigososEliminados: 0.00221; ResiduosNaoPerigososEliminados: 1.83; MassaTotalDeResiduosRadioactivosEliminados: 0.000394; EnergiaElectricaExportada: 1.55; MateriaisParaRecuperacaoDeEnergia: 0.00739; MateriaisParaReciclagem: 0.0253; UnidadeEPD: 1 m²
Type - IFC.REVIGRÉS-Dados gerais-Floor Covering - Nome: REVIGRÉS-URBAN-BASE-59.2X59.2-RECT-URBAN FOG; TipoProduto: Prensado a seco: grupo BIa UGL | Grés porcelânico técnico; NumeroDeRegistoDAP: EPD-REV-20240006-CCC1-EN; ReferenciaDAP: -; UrlDOP: -
Classification: C3020 (Uniformat)
Pset_CoveringCommon - TotalThickness: 10.5 mm
IFC.REVIGRÉS-Dados do fabricante-Floor Covering - Type: Floor: REVIGRÉS-URBAN-BASE-59,2X59,2-RECT-FOG
IFC.REVIGRÉS-Dados de desempenho-Floor Covering - Type: Floor: REVIGRÉS-URBAN-BASE-59,2X59,2-RECT-FOG
IFC.REVIGRÉS-Dados de especificação-Floor Covering - Type: Floor: REVIGRÉS-URBAN-BASE-59,2X59,2-RECT-FOG
IFC.REVIGRÉS-Dados geométricos-Floor Covering - Type: Floor: REVIGRÉS-URBAN-BASE-59,2X59,2-RECT-FOG
IFC.REVIGRÉS-Dados de sustentabilidade-Floor Covering - Type: Floor: REVIGRÉS-URBAN-BASE-59,2X59,2-RECT-FOG

# IfcCovering: Floor:REVIGRÉS-URBAN-BASE-59,2X59,2-RECT-GRIS, Floor:REVIGRÉS-URBAN-BASE-59,2X59,2-RECT-GRIS:22968
In: Level 1
Type - PredefinedType: CLADDING; Material: REVIGRÉS-URBAN-BASE-60X60-RECT-GRIS 10.5 mm
Type - Pset_CoveringCommon - Reference: 31211322T1; Material: Grés porcelânico
Type - Pset_ElementShading - Roughness: 304.8 mm
Type - Pset_ManufacturerTypeInformation - Manufacturer: REVIGRÉS
Type - Pset_ProductRequirements - Category: Floors
Type - Pset_QuantityTakeOff - Reference: 31211322T1
Type - IFC.REVIGRÉS-Dados do fabricante-Floor Covering - FabricanteURL: https://www.revigres.pt/; ReferenciaModelo: Urban; NumeroGlobalDeItemComercial: 31211322T1; Acabamento: RECT; Material: Grés porcelânico; IdentificadorDoOperadorEconomico: 501840856; UrlFabricanteArtigo: https://www.revigres.pt/colecoes/urban; PaisOrigem: Portugal
Type - IFC.REVIGRÉS-Dados de desempenho-Floor Covering - Rectilinearidade: ± 0.2% máx.± 0.8 mm; Ortogonalidade: ± 0.2% máx.± 1.5 mm; PlanaridadeDaSuperficie: ± 0.3% máx. ± 1.8 mm; QualidadeDaSuperficie: Cumpre; AbsorcaoDeAgua: < 0.05%; ModuloDeRuptura: > 45 N/mm²; ResistenciaAFlexao: > 3500 N; ResistenciaAAbrasaoProfunda: < 120 mm³; DilatacaoTermicaLinear: ≤ 8,0x10-6 °C-1; ResistenciaAoChoqueTermico: Resiste; DurabilidadeResistenciaAoGeloDegelo: Resiste; ResistenciaAoEscorregamentoDIN51130: R9; ResistenciaAoEscorregamentoDIN51097: A; ResistenciaAoEscorregamentoENV51097: A; ResistenciaAoEscorregamentoENV12633: Class 1; ResistenciaAoEscorregamentoANSIA1371: ≥0,42; ResistenciaAoDeslizamentoENV12633: Class 1; ResistenciaAsManchas: Class 5; ResistenciaABaixasConcentracoesDeAcidosEAlcalis: Classe LA; ResistenciaAAltasConcentracoesDeAcidosEAlcalis: Classe HA; LibertacaoDeCadmio: 0; LibertacaoDeChumbo: 0
Type - IFC.REVIGRÉS-Dados de especificação-Floor Covering - VariacaoTonalidade: 2; NivelDeTrafego: 5; EPavimento: Sim; ERevestimento: Sim; EExterno: Sim
Type - IFC.REVIGRÉS-Dados geométricos-Floor Covering - AlturaNominal: 8.5 mm; ComprimentoNominal: 59.2 mm; LarguraNominal: 59.2 mm
Type - IFC.REVIGRÉS-Dados de sustentabilidade-Floor Covering - EnergiaTermicaExportada: 0; ItemENovo: Sim; ItemEParcialmenteReciclado: 0.29; ItemEReciclado: Sim; VidaÚtilEsperada: 50; SubstanciasPerigosas: Não; PotencialDeEsgotamentoAbioticoDosRecursosFosseis: 203; PotencialDeEsgotamentoAbioticoDosRecursosNaoFosseisMineraisEMetais: 0.000701; PotencialDeAquecimentoGlobalBiogenico: -0.48; CombustiveisFosseisComPotencialDeAquecimentoGlobal: 13.9; PotencialDeAquecimentoGlobalUsoDoSoloEMudancaDeUsoDoSolo: 0.0246; PotencialDeEutrofizacaoFraccaoDeNutrientesQueAtingemOCompartimentoFinalDeAguaDoce: 0.000189; PotencialDeEutrofizacaoFraccaoDeNutrientesQueAtingemOCompartimentoFinalMarinho: 0.0122; EnergiaRecuperada: 0.00739; ConsumoDeAguaDoce: 0.113; UtilizacaoLiquidaDeAguaDoce: 0.113; ResiduosPerigososEliminados: 0.00221; ResiduosNaoPerigososEliminados: 1.83; MassaTotalDeResiduosRadioactivosEliminados: 0.000394; EnergiaElectricaExportada: 1.55; MateriaisParaRecuperacaoDeEnergia: 0.00739; MateriaisParaReciclagem: 0.0253; UnidadeEPD: 1 m²
Type - IFC.REVIGRÉS-Dados gerais-Floor Covering - Nome: REVIGRÉS-URBAN-BASE-59.2X59.2-RECT-URBAN GRIS; TipoProduto: Prensado a seco: grupo BIa UGL | Grés porcelânico técnico; NumeroDeRegistoDAP: EPD-REV-20240006-CCC1-EN; ReferenciaDAP: -; UrlDOP: -
Classification: C3020 (Uniformat)
Pset_CoveringCommon - TotalThickness: 10.5 mm
IFC.REVIGRÉS-Dados do fabricante-Floor Covering - Type: Floor: REVIGRÉS-URBAN-BASE-59,2X59,2-RECT-GRIS
IFC.REVIGRÉS-Dados de desempenho-Floor Covering - Type: Floor: REVIGRÉS-URBAN-BASE-59,2X59,2-RECT-GRIS
IFC.REVIGRÉS-Dados de especificação-Floor Covering - Type: Floor: REVIGRÉS-URBAN-BASE-59,2X59,2-RECT-GRIS
IFC.REVIGRÉS-Dados geométricos-Floor Covering - Type: Floor: REVIGRÉS-URBAN-BASE-59,2X59,2-RECT-GRIS
IFC.REVIGRÉS-Dados de sustentabilidade-Floor Covering - Type: Floor: REVIGRÉS-URBAN-BASE-59,2X59,2-RECT-GRIS

# IfcCovering: Floor:REVIGRÉS-URBAN-BASE-59,2X59,2-RECT-OFFWHITE, Floor:REVIGRÉS-URBAN-BASE-59,2X59,2-RECT-OFFWHITE:22984
In: Level 1
Type - PredefinedType: CLADDING; Material: REVIGRÉS-URBAN-BASE-60X60-RECT-OFFWHITE 10.5 mm
Type - Pset_CoveringCommon - Reference: 31211323T1; Material: Grés porcelânico
Type - Pset_ElementShading - Roughness: 304.8 mm
Type - Pset_ManufacturerTypeInformation - Manufacturer: REVIGRÉS
Type - Pset_ProductRequirements - Category: Floors
Type - Pset_QuantityTakeOff - Reference: 31211323T1
Type - IFC.REVIGRÉS-Dados do fabricante-Floor Covering - FabricanteURL: https://www.revigres.pt/; ReferenciaModelo: Urban; NumeroGlobalDeItemComercial: 31211323T1; Acabamento: RECT; Material: Grés porcelânico; IdentificadorDoOperadorEconomico: 501840856; UrlFabricanteArtigo: https://www.revigres.pt/colecoes/urban; PaisOrigem: Portugal
Type - IFC.REVIGRÉS-Dados de desempenho-Floor Covering - Rectilinearidade: ± 0.2% máx.± 0.8 mm; Ortogonalidade: ± 0.2% máx.± 1.5 mm; PlanaridadeDaSuperficie: ± 0.3% máx. ± 1.8 mm; QualidadeDaSuperficie: Cumpre; AbsorcaoDeAgua: < 0.05%; ModuloDeRuptura: > 45 N/mm²; ResistenciaAFlexao: > 3500 N; ResistenciaAAbrasaoProfunda: < 120 mm³; DilatacaoTermicaLinear: ≤ 8,0x10-6 °C-1; ResistenciaAoChoqueTermico: Resiste; DurabilidadeResistenciaAoGeloDegelo: Resiste; ResistenciaAoEscorregamentoDIN51130: R9; ResistenciaAoEscorregamentoDIN51097: A; ResistenciaAoEscorregamentoENV51097: A; ResistenciaAoEscorregamentoENV12633: Class 1; ResistenciaAoEscorregamentoANSIA1371: ≥0,42; ResistenciaAoDeslizamentoENV12633: Class 1; ResistenciaAsManchas: Class 5; ResistenciaABaixasConcentracoesDeAcidosEAlcalis: Classe LA; ResistenciaAAltasConcentracoesDeAcidosEAlcalis: Classe HA; LibertacaoDeCadmio: 0; LibertacaoDeChumbo: 0
Type - IFC.REVIGRÉS-Dados de especificação-Floor Covering - VariacaoTonalidade: 2; NivelDeTrafego: 5; EPavimento: Sim; ERevestimento: Sim; EExterno: Sim
Type - IFC.REVIGRÉS-Dados geométricos-Floor Covering - AlturaNominal: 8.5 mm; ComprimentoNominal: 59.2 mm; LarguraNominal: 59.2 mm
Type - IFC.REVIGRÉS-Dados de sustentabilidade-Floor Covering - EnergiaTermicaExportada: 0; ItemENovo: Sim; ItemEParcialmenteReciclado: 0.03; ItemEReciclado: Sim; VidaÚtilEsperada: 50; SubstanciasPerigosas: Não; PotencialDeEsgotamentoAbioticoDosRecursosFosseis: 203; PotencialDeEsgotamentoAbioticoDosRecursosNaoFosseisMineraisEMetais: 0.000701; PotencialDeAquecimentoGlobalBiogenico: -0.48; CombustiveisFosseisComPotencialDeAquecimentoGlobal: 13.9; PotencialDeAquecimentoGlobalUsoDoSoloEMudancaDeUsoDoSolo: 0.0246; PotencialDeEutrofizacaoFraccaoDeNutrientesQueAtingemOCompartimentoFinalDeAguaDoce: 0.000189; PotencialDeEutrofizacaoFraccaoDeNutrientesQueAtingemOCompartimentoFinalMarinho: 0.0122; EnergiaRecuperada: 0.00739; ConsumoDeAguaDoce: 0.113; UtilizacaoLiquidaDeAguaDoce: 0.113; ResiduosPerigososEliminados: 0.00221; ResiduosNaoPerigososEliminados: 1.83; MassaTotalDeResiduosRadioactivosEliminados: 0.000394; EnergiaElectricaExportada: 1.55; MateriaisParaRecuperacaoDeEnergia: 0.00739; MateriaisParaReciclagem: 0.0253; UnidadeEPD: 1 m²
Type - IFC.REVIGRÉS-Dados gerais-Floor Covering - Nome: REVIGRÉS-URBAN-BASE-59.2X59.2-RECT-URBAN OFFWHITE; TipoProduto: Prensado a seco: grupo BIa UGL | Grés porcelânico técnico; NumeroDeRegistoDAP: EPD-REV-20240006-CCC1-EN; ReferenciaDAP: -; UrlDOP: -
Classification: C3020 (Uniformat)
Pset_CoveringCommon - TotalThickness: 10.5 mm
IFC.REVIGRÉS-Dados do fabricante-Floor Covering - Type: Floor: REVIGRÉS-URBAN-BASE-59,2X59,2-RECT-OFFWHITE
IFC.REVIGRÉS-Dados de desempenho-Floor Covering - Type: Floor: REVIGRÉS-URBAN-BASE-59,2X59,2-RECT-OFFWHITE
IFC.REVIGRÉS-Dados de especificação-Floor Covering - Type: Floor: REVIGRÉS-URBAN-BASE-59,2X59,2-RECT-OFFWHITE
IFC.REVIGRÉS-Dados geométricos-Floor Covering - Type: Floor: REVIGRÉS-URBAN-BASE-59,2X59,2-RECT-OFFWHITE
IFC.REVIGRÉS-Dados de sustentabilidade-Floor Covering - Type: Floor: REVIGRÉS-URBAN-BASE-59,2X59,2-RECT-OFFWHITE

# IfcCovering: Floor:REVIGRÉS-URBAN-BASE-59,8X59,8X2-RECT-ANTISLIP BONE, Floor:REVIGRÉS-URBAN-BASE-59,8X59,8X2-RECT-ANTISLIP BONE:79676
In: Level 1
Type - PredefinedType: CLADDING; Material: REVIGRÉS-URBAN-BASE-60X60X2-RECT-ANTISLIP BONE 20 mm
Type - Pset_CoveringCommon - Reference: 302D1348V1; Material: Grés porcelânico
Type - Pset_ElementShading - Roughness: 304.8 mm
Type - Pset_ManufacturerTypeInformation - Manufacturer: REVIGRÉS
Type - Pset_ProductRequirements - Category: Floors
Type - Pset_QuantityTakeOff - Reference: 302D1348V1
Type - IFC.REVIGRÉS-Dados do fabricante-Floor Covering - FabricanteURL: https://www.revigres.pt/; ReferenciaModelo: Urban; NumeroGlobalDeItemComercial: 31211331T1; Acabamento: RECT; Material: Grés porcelânico; IdentificadorDoOperadorEconomico: 501840856; UrlFabricanteArtigo: https://www.revigres.pt/colecoes/urban; PaisOrigem: Portugal
Type - IFC.REVIGRÉS-Dados de desempenho-Floor Covering - Rectilinearidade: ± 0.2% máx.± 0.8 mm; Ortogonalidade: ± 0.2% máx.± 1.5 mm; PlanaridadeDaSuperficie: ± 0.3% máx. ± 1.8 mm; QualidadeDaSuperficie: Cumpre; AbsorcaoDeAgua: < 0.05%; ModuloDeRuptura: > 45 N/mm²; ResistenciaAFlexao: > 3500 N; ResistenciaAAbrasaoProfunda: < 120 mm³; DilatacaoTermicaLinear: ≤ 8,0x10-6 °C-1; ResistenciaAoChoqueTermico: Resiste; DurabilidadeResistenciaAoGeloDegelo: Resiste; ResistenciaAoEscorregamentoDIN51130: R9; ResistenciaAoEscorregamentoDIN51097: A; ResistenciaAoEscorregamentoENV51097: A; ResistenciaAoEscorregamentoENV12633: Class 1; ResistenciaAoEscorregamentoANSIA1371: ≥0,42; ResistenciaAoDeslizamentoENV12633: Class 1; ResistenciaAsManchas: Class 5; ResistenciaABaixasConcentracoesDeAcidosEAlcalis: Classe LA; ResistenciaAAltasConcentracoesDeAcidosEAlcalis: Classe HA; LibertacaoDeCadmio: 0; LibertacaoDeChumbo: 0
Type - IFC.REVIGRÉS-Dados de especificação-Floor Covering - VariacaoTonalidade: 2; NivelDeTrafego: 4; EPavimento: Sim; ERevestimento: Sim; EExterno: Sim
Type - IFC.REVIGRÉS-Dados geométricos-Floor Covering - AlturaNominal: 20 mm; ComprimentoNominal: 59.8 mm; LarguraNominal: 59.8 mm
Type - IFC.REVIGRÉS-Dados de sustentabilidade-Floor Covering - EnergiaTermicaExportada: 0; ItemENovo: Sim; ItemEParcialmenteReciclado: 0.19; ItemEReciclado: Sim; VidaÚtilEsperada: 50; SubstanciasPerigosas: Não; PotencialDeEsgotamentoAbioticoDosRecursosFosseis: 203; PotencialDeEsgotamentoAbioticoDosRecursosNaoFosseisMineraisEMetais: 0.000701; PotencialDeAquecimentoGlobalBiogenico: -0.48; CombustiveisFosseisComPotencialDeAquecimentoGlobal: 13.9; PotencialDeAquecimentoGlobalUsoDoSoloEMudancaDeUsoDoSolo: 0.0246; PotencialDeEutrofizacaoFraccaoDeNutrientesQueAtingemOCompartimentoFinalDeAguaDoce: 0.000189; PotencialDeEutrofizacaoFraccaoDeNutrientesQueAtingemOCompartimentoFinalMarinho: 0.0122; EnergiaRecuperada: 0.00739; ConsumoDeAguaDoce: 0.113; UtilizacaoLiquidaDeAguaDoce: 0.113; ResiduosPerigososEliminados: 0.00221; ResiduosNaoPerigososEliminados: 1.83; MassaTotalDeResiduosRadioactivosEliminados: 0.000394; EnergiaElectricaExportada: 1.55; MateriaisParaRecuperacaoDeEnergia: 0.00739; MateriaisParaReciclagem: 0.0253; UnidadeEPD: 1 m²
Type - IFC.REVIGRÉS-Dados gerais-Floor Covering - Nome: REVIGRÉS-URBAN-BASE-59.8X59.8X2-RECT-ANTISLIP URBAN BONE; TipoProduto: Prensado a seco: grupo BIa UGL | Grés porcelânico técnico; NumeroDeRegistoDAP: EPD-REV-20240006-CCC1-EN; ReferenciaDAP: -; UrlDOP: -
Classification: C3020 (Uniformat)
Pset_CoveringCommon - TotalThickness: 20 mm
IFC.REVIGRÉS-Dados do fabricante-Floor Covering - Type: Floor: REVIGRÉS-URBAN-BASE-59,8X59,8X2-RECT-ANTISLIP BONE
IFC.REVIGRÉS-Dados de desempenho-Floor Covering - Type: Floor: REVIGRÉS-URBAN-BASE-59,8X59,8X2-RECT-ANTISLIP BONE
IFC.REVIGRÉS-Dados de especificação-Floor Covering - Type: Floor: REVIGRÉS-URBAN-BASE-59,8X59,8X2-RECT-ANTISLIP BONE
IFC.REVIGRÉS-Dados geométricos-Floor Covering - Type: Floor: REVIGRÉS-URBAN-BASE-59,8X59,8X2-RECT-ANTISLIP BONE
IFC.REVIGRÉS-Dados de sustentabilidade-Floor Covering - Type: Floor: REVIGRÉS-URBAN-BASE-59,8X59,8X2-RECT-ANTISLIP BONE

# IfcCovering: Floor:REVIGRÉS-URBAN-BASE-59,8X59,8X2-RECT-ANTISLIP FOG, Floor:REVIGRÉS-URBAN-BASE-59,8X59,8X2-RECT-ANTISLIP FOG:79692
In: Level 1
Type - PredefinedType: CLADDING; Material: REVIGRÉS-URBAN-BASE-60X60X2-RECT-ANTISLIP FOG 20 mm
Type - Pset_CoveringCommon - Reference: 302D1349V1; Material: Grés porcelânico
Type - Pset_ElementShading - Roughness: 304.8 mm
Type - Pset_ManufacturerTypeInformation - Manufacturer: REVIGRÉS
Type - Pset_ProductRequirements - Category: Floors
Type - Pset_QuantityTakeOff - Reference: 302D1349V1
Type - IFC.REVIGRÉS-Dados do fabricante-Floor Covering - FabricanteURL: https://www.revigres.pt/; ReferenciaModelo: Urban; NumeroGlobalDeItemComercial: 31211332T1; Acabamento: RECT; Material: Grés porcelânico; IdentificadorDoOperadorEconomico: 501840856; UrlFabricanteArtigo: https://www.revigres.pt/colecoes/urban; PaisOrigem: Portugal
Type - IFC.REVIGRÉS-Dados de desempenho-Floor Covering - Rectilinearidade: ± 0.2% máx.± 0.8 mm; Ortogonalidade: ± 0.2% máx.± 1.5 mm; PlanaridadeDaSuperficie: ± 0.3% máx. ± 1.8 mm; QualidadeDaSuperficie: Cumpre; AbsorcaoDeAgua: < 0.05%; ModuloDeRuptura: > 45 N/mm²; ResistenciaAFlexao: > 3500 N; ResistenciaAAbrasaoProfunda: < 120 mm³; DilatacaoTermicaLinear: ≤ 8,0x10-6 °C-1; ResistenciaAoChoqueTermico: Resiste; DurabilidadeResistenciaAoGeloDegelo: Resiste; ResistenciaAoEscorregamentoDIN51130: R9; ResistenciaAoEscorregamentoDIN51097: A; ResistenciaAoEscorregamentoENV51097: A; ResistenciaAoEscorregamentoENV12633: Class 1; ResistenciaAoEscorregamentoANSIA1371: ≥0,42; ResistenciaAoDeslizamentoENV12633: Class 1; ResistenciaAsManchas: Class 5; ResistenciaABaixasConcentracoesDeAcidosEAlcalis: Classe LA; ResistenciaAAltasConcentracoesDeAcidosEAlcalis: Classe HA; LibertacaoDeCadmio: 0; LibertacaoDeChumbo: 0
Type - IFC.REVIGRÉS-Dados de especificação-Floor Covering - VariacaoTonalidade: 2; NivelDeTrafego: 4; EPavimento: Sim; ERevestimento: Sim; EExterno: Sim
Type - IFC.REVIGRÉS-Dados geométricos-Floor Covering - AlturaNominal: 20 mm; ComprimentoNominal: 59.8 mm; LarguraNominal: 59.8 mm
Type - IFC.REVIGRÉS-Dados de sustentabilidade-Floor Covering - EnergiaTermicaExportada: 0; ItemENovo: Sim; ItemEParcialmenteReciclado: 0.23; ItemEReciclado: Sim; VidaÚtilEsperada: 50; SubstanciasPerigosas: Não; PotencialDeEsgotamentoAbioticoDosRecursosFosseis: 203; PotencialDeEsgotamentoAbioticoDosRecursosNaoFosseisMineraisEMetais: 0.000701; PotencialDeAquecimentoGlobalBiogenico: -0.48; CombustiveisFosseisComPotencialDeAquecimentoGlobal: 13.9; PotencialDeAquecimentoGlobalUsoDoSoloEMudancaDeUsoDoSolo: 0.0246; PotencialDeEutrofizacaoFraccaoDeNutrientesQueAtingemOCompartimentoFinalDeAguaDoce: 0.000189; PotencialDeEutrofizacaoFraccaoDeNutrientesQueAtingemOCompartimentoFinalMarinho: 0.0122; EnergiaRecuperada: 0.00739; ConsumoDeAguaDoce: 0.113; UtilizacaoLiquidaDeAguaDoce: 0.113; ResiduosPerigososEliminados: 0.00221; ResiduosNaoPerigososEliminados: 1.83; MassaTotalDeResiduosRadioactivosEliminados: 0.000394; EnergiaElectricaExportada: 1.55; MateriaisParaRecuperacaoDeEnergia: 0.00739; MateriaisParaReciclagem: 0.0253; UnidadeEPD: 1 m²
Type - IFC.REVIGRÉS-Dados gerais-Floor Covering - Nome: REVIGRÉS-URBAN-BASE-59.8X59.8X2-RECT-ANTISLIP URBAN FOG; TipoProduto: Prensado a seco: grupo BIa UGL | Grés porcelânico técnico; NumeroDeRegistoDAP: EPD-REV-20240006-CCC1-EN; ReferenciaDAP: -; UrlDOP: -
Classification: C3020 (Uniformat)
Pset_CoveringCommon - TotalThickness: 20 mm
IFC.REVIGRÉS-Dados do fabricante-Floor Covering - Type: Floor: REVIGRÉS-URBAN-BASE-59,8X59,8X2-RECT-ANTISLIP FOG
IFC.REVIGRÉS-Dados de desempenho-Floor Covering - Type: Floor: REVIGRÉS-URBAN-BASE-59,8X59,8X2-RECT-ANTISLIP FOG
IFC.REVIGRÉS-Dados de especificação-Floor Covering - Type: Floor: REVIGRÉS-URBAN-BASE-59,8X59,8X2-RECT-ANTISLIP FOG
IFC.REVIGRÉS-Dados geométricos-Floor Covering - Type: Floor: REVIGRÉS-URBAN-BASE-59,8X59,8X2-RECT-ANTISLIP FOG
IFC.REVIGRÉS-Dados de sustentabilidade-Floor Covering - Type: Floor: REVIGRÉS-URBAN-BASE-59,8X59,8X2-RECT-ANTISLIP FOG

# IfcCovering: Floor:REVIGRÉS-URBAN-BASE-59,8X59,8X2-RECT-ANTISLIP GRIS, Floor:REVIGRÉS-URBAN-BASE-59,8X59,8X2-RECT-ANTISLIP GRIS:79700
In: Level 1
Type - PredefinedType: CLADDING; Material: REVIGRÉS-URBAN-BASE-60X60X2-RECT-ANTISLIP GRIS 20 mm
Type - Pset_CoveringCommon - Reference: 302D1350V1; Material: Grés porcelânico
Type - Pset_ElementShading - Roughness: 304.8 mm
Type - Pset_ManufacturerTypeInformation - Manufacturer: REVIGRÉS
Type - Pset_ProductRequirements - Category: Floors
Type - Pset_QuantityTakeOff - Reference: 302D1350V1
Type - IFC.REVIGRÉS-Dados do fabricante-Floor Covering - FabricanteURL: https://www.revigres.pt/; ReferenciaModelo: Urban; NumeroGlobalDeItemComercial: 31211333T1; Acabamento: RECT; Material: Grés porcelânico; IdentificadorDoOperadorEconomico: 501840856; UrlFabricanteArtigo: https://www.revigres.pt/colecoes/urban; PaisOrigem: Portugal
Type - IFC.REVIGRÉS-Dados de desempenho-Floor Covering - Rectilinearidade: ± 0.2% máx.± 0.8 mm; Ortogonalidade: ± 0.2% máx.± 1.5 mm; PlanaridadeDaSuperficie: ± 0.3% máx. ± 1.8 mm; QualidadeDaSuperficie: Cumpre; AbsorcaoDeAgua: < 0.05%; ModuloDeRuptura: > 45 N/mm²; ResistenciaAFlexao: > 3500 N; ResistenciaAAbrasaoProfunda: < 120 mm³; DilatacaoTermicaLinear: ≤ 8,0x10-6 °C-1; ResistenciaAoChoqueTermico: Resiste; DurabilidadeResistenciaAoGeloDegelo: Resiste; ResistenciaAoEscorregamentoDIN51130: R9; ResistenciaAoEscorregamentoDIN51097: A; ResistenciaAoEscorregamentoENV51097: A; ResistenciaAoEscorregamentoENV12633: Class 1; ResistenciaAoEscorregamentoANSIA1371: ≥0,42; ResistenciaAoDeslizamentoENV12633: Class 1; ResistenciaAsManchas: Class 5; ResistenciaABaixasConcentracoesDeAcidosEAlcalis: Classe LA; ResistenciaAAltasConcentracoesDeAcidosEAlcalis: Classe HA; LibertacaoDeCadmio: 0; LibertacaoDeChumbo: 0
Type - IFC.REVIGRÉS-Dados de especificação-Floor Covering - VariacaoTonalidade: 2; NivelDeTrafego: 4; EPavimento: Sim; ERevestimento: Sim; EExterno: Sim
Type - IFC.REVIGRÉS-Dados geométricos-Floor Covering - AlturaNominal: 20 mm; ComprimentoNominal: 59.8 mm; LarguraNominal: 59.8 mm
Type - IFC.REVIGRÉS-Dados de sustentabilidade-Floor Covering - EnergiaTermicaExportada: 0; ItemENovo: Sim; ItemEParcialmenteReciclado: 0.03; ItemEReciclado: Sim; VidaÚtilEsperada: 50; SubstanciasPerigosas: Não; PotencialDeEsgotamentoAbioticoDosRecursosFosseis: 203; PotencialDeEsgotamentoAbioticoDosRecursosNaoFosseisMineraisEMetais: 0.000701; PotencialDeAquecimentoGlobalBiogenico: -0.48; CombustiveisFosseisComPotencialDeAquecimentoGlobal: 13.9; PotencialDeAquecimentoGlobalUsoDoSoloEMudancaDeUsoDoSolo: 0.0246; PotencialDeEutrofizacaoFraccaoDeNutrientesQueAtingemOCompartimentoFinalDeAguaDoce: 0.000189; PotencialDeEutrofizacaoFraccaoDeNutrientesQueAtingemOCompartimentoFinalMarinho: 0.0122; EnergiaRecuperada: 0.00739; ConsumoDeAguaDoce: 0.113; UtilizacaoLiquidaDeAguaDoce: 0.113; ResiduosPerigososEliminados: 0.00221; ResiduosNaoPerigososEliminados: 1.83; MassaTotalDeResiduosRadioactivosEliminados: 0.000394; EnergiaElectricaExportada: 1.55; MateriaisParaRecuperacaoDeEnergia: 0.00739; MateriaisParaReciclagem: 0.0253; UnidadeEPD: 1 m²
Type - IFC.REVIGRÉS-Dados gerais-Floor Covering - Nome: REVIGRÉS-URBAN-BASE-59.8X59.8X2-RECT-ANTISLIP URBAN GRIS; TipoProduto: Prensado a seco: grupo BIa UGL | Grés porcelânico técnico; NumeroDeRegistoDAP: EPD-REV-20240006-CCC1-EN; ReferenciaDAP: -; UrlDOP: -
Classification: C3020 (Uniformat)
Pset_CoveringCommon - TotalThickness: 20 mm
IFC.REVIGRÉS-Dados do fabricante-Floor Covering - Type: Floor: REVIGRÉS-URBAN-BASE-59,8X59,8X2-RECT-ANTISLIP GRIS
IFC.REVIGRÉS-Dados de desempenho-Floor Covering - Type: Floor: REVIGRÉS-URBAN-BASE-59,8X59,8X2-RECT-ANTISLIP GRIS
IFC.REVIGRÉS-Dados de especificação-Floor Covering - Type: Floor: REVIGRÉS-URBAN-BASE-59,8X59,8X2-RECT-ANTISLIP GRIS
IFC.REVIGRÉS-Dados geométricos-Floor Covering - Type: Floor: REVIGRÉS-URBAN-BASE-59,8X59,8X2-RECT-ANTISLIP GRIS
IFC.REVIGRÉS-Dados de sustentabilidade-Floor Covering - Type: Floor: REVIGRÉS-URBAN-BASE-59,8X59,8X2-RECT-ANTISLIP GRIS

# IfcCovering: Floor:REVIGRÉS-URBAN-BASE-88,9X88,9-RECT-ANTRACITE, Floor:REVIGRÉS-URBAN-BASE-88,9X88,9-RECT-ANTRACITE:23106
In: Level 1
Type - PredefinedType: CLADDING; Material: REVIGRÉS-URBAN-BASE-90X90-RECT-ANTRACITE 10.5 mm
Type - Pset_CoveringCommon - Reference: 3121K748U1; Material: Grés porcelânico
Type - Pset_ElementShading - Roughness: 304.8 mm
Type - Pset_ManufacturerTypeInformation - Manufacturer: REVIGRÉS
Type - Pset_ProductRequirements - Category: Floors
Type - Pset_QuantityTakeOff - Reference: 3121K748U1
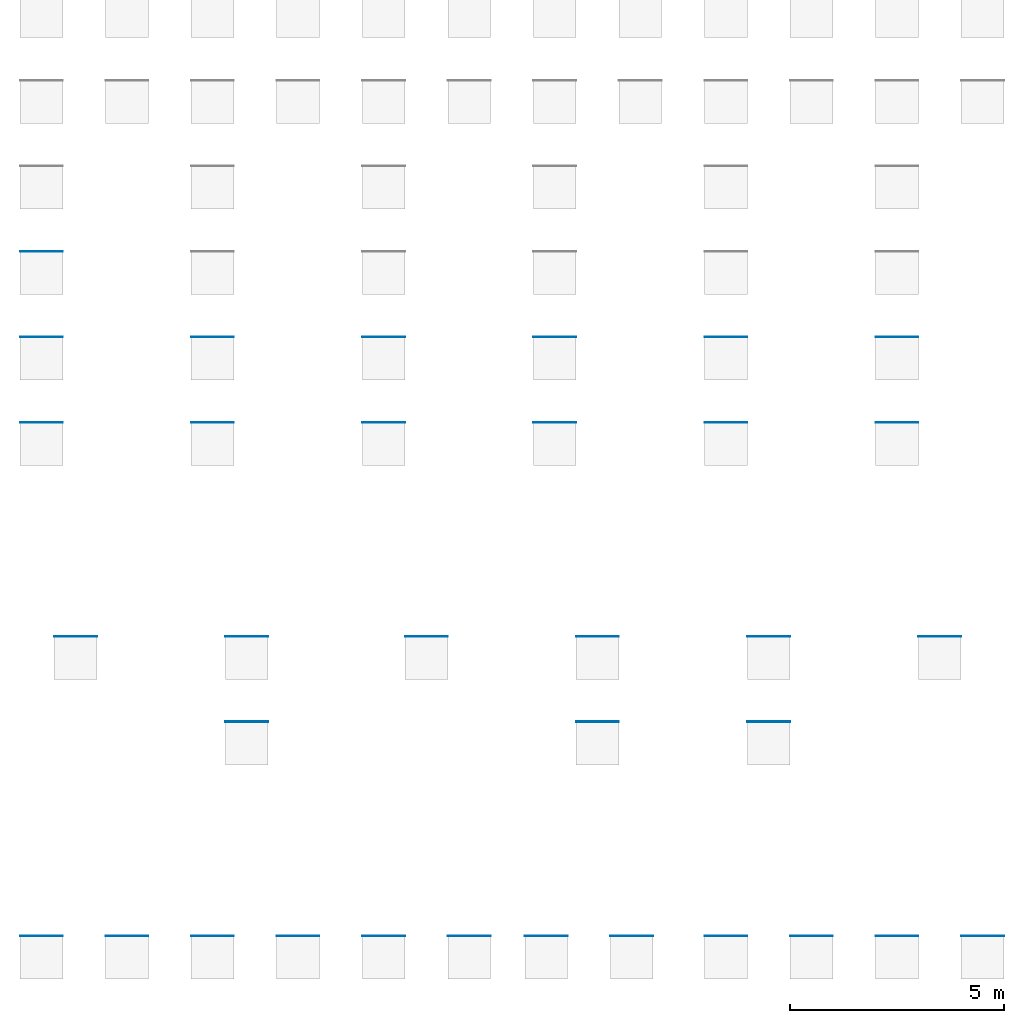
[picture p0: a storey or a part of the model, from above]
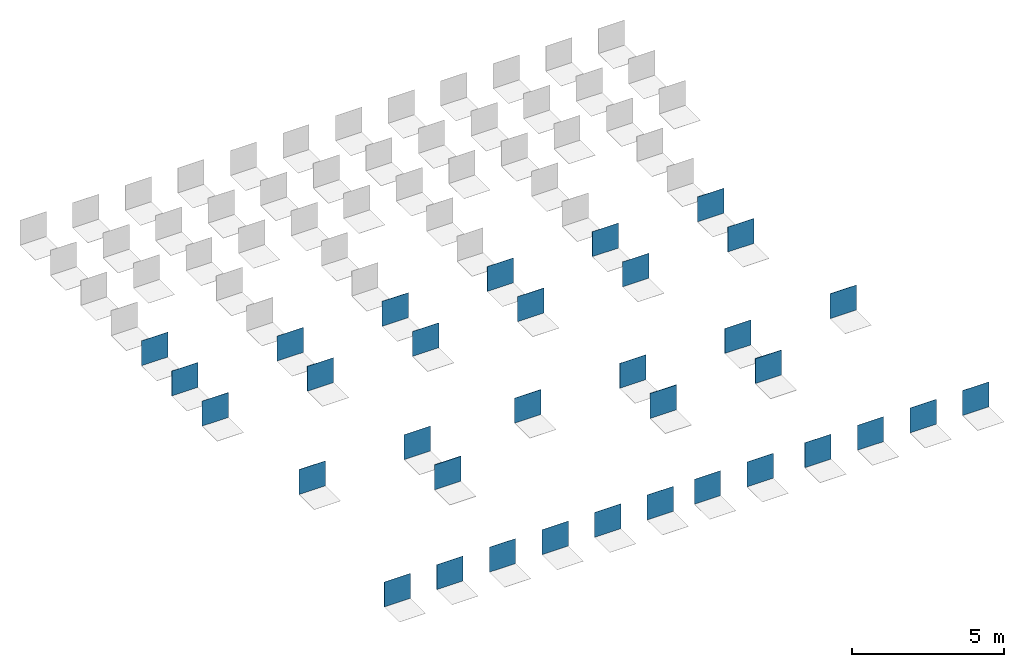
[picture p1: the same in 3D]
Properties of the parts of a building model (IFC2X3), part 7 of 12

# IfcWallStandardCase: Basic Wall:REVIGRÉS-URBAN-BASE-29,5X59,2-RECT-CRAFT, Basic Wall:REVIGRÉS-URBAN-BASE-29,5X59,2-RECT-CRAFT:22503
IFC.REVIGRÉS-Dados do fabricante-Wall Covering - Type: Basic Wall: REVIGRÉS-URBAN-BASE-29,5X59,2-RECT-CRAFT
IFC.REVIGRÉS-Dados de desempenho-Wall Covering - Type: Basic Wall: REVIGRÉS-URBAN-BASE-29,5X59,2-RECT-CRAFT
IFC.REVIGRÉS-Dados de especificação-Wall Covering - Type: Basic Wall: REVIGRÉS-URBAN-BASE-29,5X59,2-RECT-CRAFT
IFC.REVIGRÉS-Dados geométricos-Wall Covering - Type: Basic Wall: REVIGRÉS-URBAN-BASE-29,5X59,2-RECT-CRAFT
IFC.REVIGRÉS-Dados de sustentabilidade-Wall Covering - Type: Basic Wall: REVIGRÉS-URBAN-BASE-29,5X59,2-RECT-CRAFT

# IfcWallStandardCase: Basic Wall:REVIGRÉS-URBAN-BASE-29,5X59,2-RECT-FOG, Basic Wall:REVIGRÉS-URBAN-BASE-29,5X59,2-RECT-FOG:22519
In: Level 1
Type - PredefinedType: STANDARD; Material: REVIGRÉS-URBAN-BASE-30X60-RECT-FOG 8.5 mm
Type - Pset_ElementShading - Roughness: 304.8 mm
Type - Pset_ManufacturerTypeInformation - Manufacturer: REVIGRÉS
Type - Pset_ProductRequirements - Category: Walls
Type - Pset_QuantityTakeOff - Reference: 31212121T1
Type - Pset_ReinforcementBarPitchOfWall - Reference: 31212121T1
Type - Pset_WallCommon - IsExternal: no; Reference: 31212121T1
Type - IFC.REVIGRÉS-Dados do fabricante-Wall Covering - FabricanteURL: https://www.revigres.pt/; ReferenciaModelo: Urban; NumeroGlobalDeItemComercial: 31212121T1; Acabamento: RECT; Material: Grés porcelânico; IdentificadorDoOperadorEconomico: 501840856; UrlFabricanteArtigo: https://www.revigres.pt/colecoes/urban; PaisOrigem: Portugal
Type - IFC.REVIGRÉS-Dados de desempenho-Wall Covering - Rectilinearidade: ± 0.2% máx.± 0.8 mm; Ortogonalidade: ± 0.2% máx.± 1.5 mm; PlanaridadeDaSuperficie: ± 0.3% máx. ± 1.8 mm; QualidadeDaSuperficie: Cumpre; AbsorcaoDeAgua: < 0.05%; ModuloDeRuptura: > 45 N/mm²; ResistenciaAFlexao: > 2000 N; ResistenciaAAbrasaoProfunda: < 120 mm³; DilatacaoTermicaLinear: ≤ 8,0x10-6 °C-1; ResistenciaAoChoqueTermico: Resiste; DurabilidadeResistenciaAoGeloDegelo: Resiste; ResistenciaAoEscorregamentoDIN51130: R9; ResistenciaAoEscorregamentoDIN51097: A; ResistenciaAoEscorregamentoENV51097: A; ResistenciaAoEscorregamentoENV12633: Class 1; ResistenciaAoEscorregamentoANSIA1371: ≥0,42; ResistenciaAoDeslizamentoENV12633: Class 1; ResistenciaAsManchas: Class 5; ResistenciaABaixasConcentracoesDeAcidosEAlcalis: Classe LA; ResistenciaAAltasConcentracoesDeAcidosEAlcalis: Classe HA; LibertacaoDeCadmio: 0; LibertacaoDeChumbo: 0
Type - IFC.REVIGRÉS-Dados de especificação-Wall Covering - VariacaoTonalidade: 2; NivelDeTrafego: 5; EPavimento: Sim; ERevestimento: Sim; EExterno: Sim
Type - IFC.REVIGRÉS-Dados geométricos-Wall Covering - AlturaNominal: 8.5 mm; ComprimentoNominal: 29.5 mm; LarguraNominal: 59.2 mm
Type - IFC.REVIGRÉS-Dados de sustentabilidade-Wall Covering - PotencialPrivacaoDeAguaConsumoDeAguaPonderado: 4.5; EnergiaTermicaExportada: 0; ItemENovo: Sim; ItemEParcialmenteReciclado: 0.23; ItemEReciclado: Sim; VidaÚtilEsperada: 50; SubstanciasPerigosas: Não; PotencialDeEsgotamentoAbioticoDosRecursosFosseis: 203; PotencialDeEsgotamentoAbioticoDosRecursosNaoFosseisMineraisEMetais: 0.000701; PotencialDeAquecimentoGlobalBiogenico: -0.48; CombustiveisFosseisComPotencialDeAquecimentoGlobal: 13.9; PotencialDeAquecimentoGlobalUsoDoSoloEMudancaDeUsoDoSolo: 0.0246; PotencialDeEutrofizacaoFraccaoDeNutrientesQueAtingemOCompartimentoFinalDeAguaDoce: 0.000189; PotencialDeEutrofizacaoFraccaoDeNutrientesQueAtingemOCompartimentoFinalMarinho: 0.0122; EnergiaRecuperada: 0.00739; ConsumoDeAguaDoce: 0.113; UtilizacaoLiquidaDeAguaDoce: 0.113; ResiduosPerigososEliminados: 0.00221; ResiduosNaoPerigososEliminados: 1.83; MassaTotalDeResiduosRadioactivosEliminados: 0.000394; EnergiaElectricaExportada: 1.55; MateriaisParaRecuperacaoDeEnergia: 0.00739; MateriaisParaReciclagem: 0.0253; UnidadeEPD: 1 m²
Type - IFC.REVIGRÉS-Dados gerais-Wall Covering - Nome: REVIGRÉS-URBAN-BASE-29.5X59.2-RECT-URBAN FOG; TipoProduto: Prensado a seco: grupo BIa UGL | Grés porcelânico técnico; NumeroDeRegistoDAP: EPD-REV-20240006-CCC1-EN; ReferenciaDAP: -; UrlDOP: -
Classification: C3010 (Uniformat)
Pset_QuantityTakeOff - sets with these values: 2
Pset_WallCommon - ExtendToStructure: no; LoadBearing: no
IFC.REVIGRÉS-Dados do fabricante-Wall Covering - Type: Basic Wall: REVIGRÉS-URBAN-BASE-29,5X59,2-RECT-FOG
IFC.REVIGRÉS-Dados de desempenho-Wall Covering - Type: Basic Wall: REVIGRÉS-URBAN-BASE-29,5X59,2-RECT-FOG
IFC.REVIGRÉS-Dados de especificação-Wall Covering - Type: Basic Wall: REVIGRÉS-URBAN-BASE-29,5X59,2-RECT-FOG
IFC.REVIGRÉS-Dados geométricos-Wall Covering - Type: Basic Wall: REVIGRÉS-URBAN-BASE-29,5X59,2-RECT-FOG
IFC.REVIGRÉS-Dados de sustentabilidade-Wall Covering - Type: Basic Wall: REVIGRÉS-URBAN-BASE-29,5X59,2-RECT-FOG

# IfcWallStandardCase: Basic Wall:REVIGRÉS-URBAN-BASE-29,5X59,2-RECT-GRIS, Basic Wall:REVIGRÉS-URBAN-BASE-29,5X59,2-RECT-GRIS:22535
In: Level 1
Type - PredefinedType: STANDARD; Material: REVIGRÉS-URBAN-BASE-30X60-RECT-GRIS 8.5 mm
Type - Pset_ElementShading - Roughness: 304.8 mm
Type - Pset_ManufacturerTypeInformation - Manufacturer: REVIGRÉS
Type - Pset_ProductRequirements - Category: Walls
Type - Pset_QuantityTakeOff - Reference: 31212122T1
Type - Pset_ReinforcementBarPitchOfWall - Reference: 31212122T1
Type - Pset_WallCommon - IsExternal: no; Reference: 31212122T1
Type - IFC.REVIGRÉS-Dados do fabricante-Wall Covering - FabricanteURL: https://www.revigres.pt/; ReferenciaModelo: Urban; NumeroGlobalDeItemComercial: 31212122T1; Acabamento: RECT; Material: Grés porcelânico; IdentificadorDoOperadorEconomico: 501840856; UrlFabricanteArtigo: https://www.revigres.pt/colecoes/urban; PaisOrigem: Portugal
Type - IFC.REVIGRÉS-Dados de desempenho-Wall Covering - Rectilinearidade: ± 0.2% máx.± 0.8 mm; Ortogonalidade: ± 0.2% máx.± 1.5 mm; PlanaridadeDaSuperficie: ± 0.3% máx. ± 1.8 mm; QualidadeDaSuperficie: Cumpre; AbsorcaoDeAgua: < 0.05%; ModuloDeRuptura: > 45 N/mm²; ResistenciaAFlexao: > 2000 N; ResistenciaAAbrasaoProfunda: < 120 mm³; DilatacaoTermicaLinear: ≤ 8,0x10-6 °C-1; ResistenciaAoChoqueTermico: Resiste; DurabilidadeResistenciaAoGeloDegelo: Resiste; ResistenciaAoEscorregamentoDIN51130: R9; ResistenciaAoEscorregamentoDIN51097: A; ResistenciaAoEscorregamentoENV51097: A; ResistenciaAoEscorregamentoENV12633: Class 1; ResistenciaAoEscorregamentoANSIA1371: ≥0,42; ResistenciaAoDeslizamentoENV12633: Class 1; ResistenciaAsManchas: Class 5; ResistenciaABaixasConcentracoesDeAcidosEAlcalis: Classe LA; ResistenciaAAltasConcentracoesDeAcidosEAlcalis: Classe HA; LibertacaoDeCadmio: 0; LibertacaoDeChumbo: 0
Type - IFC.REVIGRÉS-Dados de especificação-Wall Covering - VariacaoTonalidade: 2; NivelDeTrafego: 5; EPavimento: Sim; ERevestimento: Sim; EExterno: Sim
Type - IFC.REVIGRÉS-Dados geométricos-Wall Covering - AlturaNominal: 8.5 mm; ComprimentoNominal: 29.5 mm; LarguraNominal: 59.2 mm
Type - IFC.REVIGRÉS-Dados de sustentabilidade-Wall Covering - PotencialPrivacaoDeAguaConsumoDeAguaPonderado: 4.5; EnergiaTermicaExportada: 0; ItemENovo: Sim; ItemEParcialmenteReciclado: 0.23; ItemEReciclado: Sim; VidaÚtilEsperada: 50; SubstanciasPerigosas: Não; PotencialDeEsgotamentoAbioticoDosRecursosFosseis: 203; PotencialDeEsgotamentoAbioticoDosRecursosNaoFosseisMineraisEMetais: 0.000701; PotencialDeAquecimentoGlobalBiogenico: -0.48; CombustiveisFosseisComPotencialDeAquecimentoGlobal: 13.9; PotencialDeAquecimentoGlobalUsoDoSoloEMudancaDeUsoDoSolo: 0.0246; PotencialDeEutrofizacaoFraccaoDeNutrientesQueAtingemOCompartimentoFinalDeAguaDoce: 0.000189; PotencialDeEutrofizacaoFraccaoDeNutrientesQueAtingemOCompartimentoFinalMarinho: 0.0122; EnergiaRecuperada: 0.00739; ConsumoDeAguaDoce: 0.113; UtilizacaoLiquidaDeAguaDoce: 0.113; ResiduosPerigososEliminados: 0.00221; ResiduosNaoPerigososEliminados: 1.83; MassaTotalDeResiduosRadioactivosEliminados: 0.000394; EnergiaElectricaExportada: 1.55; MateriaisParaRecuperacaoDeEnergia: 0.00739; MateriaisParaReciclagem: 0.0253; UnidadeEPD: 1 m²
Type - IFC.REVIGRÉS-Dados gerais-Wall Covering - Nome: REVIGRÉS-URBAN-BASE-29.5X59.2-RECT-URBAN GRIS; TipoProduto: Prensado a seco: grupo BIa UGL | Grés porcelânico técnico; NumeroDeRegistoDAP: EPD-REV-20240006-CCC1-EN; ReferenciaDAP: -; UrlDOP: -
Classification: C3010 (Uniformat)
Pset_QuantityTakeOff - sets with these values: 2
Pset_WallCommon - ExtendToStructure: no; LoadBearing: no
IFC.REVIGRÉS-Dados do fabricante-Wall Covering - Type: Basic Wall: REVIGRÉS-URBAN-BASE-29,5X59,2-RECT-GRIS
IFC.REVIGRÉS-Dados de desempenho-Wall Covering - Type: Basic Wall: REVIGRÉS-URBAN-BASE-29,5X59,2-RECT-GRIS
IFC.REVIGRÉS-Dados de especificação-Wall Covering - Type: Basic Wall: REVIGRÉS-URBAN-BASE-29,5X59,2-RECT-GRIS
IFC.REVIGRÉS-Dados geométricos-Wall Covering - Type: Basic Wall: REVIGRÉS-URBAN-BASE-29,5X59,2-RECT-GRIS
IFC.REVIGRÉS-Dados de sustentabilidade-Wall Covering - Type: Basic Wall: REVIGRÉS-URBAN-BASE-29,5X59,2-RECT-GRIS

# IfcWallStandardCase: Basic Wall:REVIGRÉS-URBAN-BASE-29,5X59,2-RECT-OFFWHITE, Basic Wall:REVIGRÉS-URBAN-BASE-29,5X59,2-RECT-OFFWHITE:22551
In: Level 1
Type - PredefinedType: STANDARD; Material: REVIGRÉS-URBAN-BASE-30X60-RECT-OFFWHITE 8.5 mm
Type - Pset_ElementShading - Roughness: 304.8 mm
Type - Pset_ManufacturerTypeInformation - Manufacturer: REVIGRÉS
Type - Pset_ProductRequirements - Category: Walls
Type - Pset_QuantityTakeOff - Reference: 31212123T1
Type - Pset_ReinforcementBarPitchOfWall - Reference: 31212123T1
Type - Pset_WallCommon - IsExternal: no; Reference: 31212123T1
Type - IFC.REVIGRÉS-Dados do fabricante-Wall Covering - FabricanteURL: https://www.revigres.pt/; ReferenciaModelo: Urban; NumeroGlobalDeItemComercial: 31212123T1; Acabamento: RECT; Material: Grés porcelânico; IdentificadorDoOperadorEconomico: 501840856; UrlFabricanteArtigo: https://www.revigres.pt/colecoes/urban; PaisOrigem: Portugal
Type - IFC.REVIGRÉS-Dados de desempenho-Wall Covering - Rectilinearidade: ± 0.2% máx.± 0.8 mm; Ortogonalidade: ± 0.2% máx.± 1.5 mm; PlanaridadeDaSuperficie: ± 0.3% máx. ± 1.8 mm; QualidadeDaSuperficie: Cumpre; AbsorcaoDeAgua: < 0.05%; ModuloDeRuptura: > 45 N/mm²; ResistenciaAFlexao: > 2000 N; ResistenciaAAbrasaoProfunda: < 120 mm³; DilatacaoTermicaLinear: ≤ 8,0x10-6 °C-1; ResistenciaAoChoqueTermico: Resiste; DurabilidadeResistenciaAoGeloDegelo: Resiste; ResistenciaAoEscorregamentoDIN51130: R9; ResistenciaAoEscorregamentoDIN51097: A; ResistenciaAoEscorregamentoENV51097: A; ResistenciaAoEscorregamentoENV12633: Class 1; ResistenciaAoEscorregamentoANSIA1371: ≥0,42; ResistenciaAoDeslizamentoENV12633: Class 1; ResistenciaAsManchas: Class 5; ResistenciaABaixasConcentracoesDeAcidosEAlcalis: Classe LA; ResistenciaAAltasConcentracoesDeAcidosEAlcalis: Classe HA; LibertacaoDeCadmio: 0; LibertacaoDeChumbo: 0
Type - IFC.REVIGRÉS-Dados de especificação-Wall Covering - VariacaoTonalidade: 2; NivelDeTrafego: 5; EPavimento: Sim; ERevestimento: Sim; EExterno: Sim
Type - IFC.REVIGRÉS-Dados geométricos-Wall Covering - AlturaNominal: 8.5 mm; ComprimentoNominal: 29.5 mm; LarguraNominal: 59.2 mm
Type - IFC.REVIGRÉS-Dados de sustentabilidade-Wall Covering - PotencialPrivacaoDeAguaConsumoDeAguaPonderado: 4.5; EnergiaTermicaExportada: 0; ItemENovo: Sim; ItemEParcialmenteReciclado: 0.03; ItemEReciclado: Sim; VidaÚtilEsperada: 50; SubstanciasPerigosas: Não; PotencialDeEsgotamentoAbioticoDosRecursosFosseis: 203; PotencialDeEsgotamentoAbioticoDosRecursosNaoFosseisMineraisEMetais: 0.000701; PotencialDeAquecimentoGlobalBiogenico: -0.48; CombustiveisFosseisComPotencialDeAquecimentoGlobal: 13.9; PotencialDeAquecimentoGlobalUsoDoSoloEMudancaDeUsoDoSolo: 0.0246; PotencialDeEutrofizacaoFraccaoDeNutrientesQueAtingemOCompartimentoFinalDeAguaDoce: 0.000189; PotencialDeEutrofizacaoFraccaoDeNutrientesQueAtingemOCompartimentoFinalMarinho: 0.0122; EnergiaRecuperada: 0.00739; ConsumoDeAguaDoce: 0.113; UtilizacaoLiquidaDeAguaDoce: 0.113; ResiduosPerigososEliminados: 0.00221; ResiduosNaoPerigososEliminados: 1.83; MassaTotalDeResiduosRadioactivosEliminados: 0.000394; EnergiaElectricaExportada: 1.55; MateriaisParaRecuperacaoDeEnergia: 0.00739; MateriaisParaReciclagem: 0.0253; UnidadeEPD: 1 m²
Type - IFC.REVIGRÉS-Dados gerais-Wall Covering - Nome: REVIGRÉS-URBAN-BASE-29.5X59.2-RECT-URBAN OFFWHITE; TipoProduto: Prensado a seco: grupo BIa UGL | Grés porcelânico técnico; NumeroDeRegistoDAP: EPD-REV-20240006-CCC1-EN; ReferenciaDAP: -; UrlDOP: -
Classification: C3010 (Uniformat)
Pset_QuantityTakeOff - sets with these values: 2
Pset_WallCommon - ExtendToStructure: no; LoadBearing: no
IFC.REVIGRÉS-Dados do fabricante-Wall Covering - Type: Basic Wall: REVIGRÉS-URBAN-BASE-29,5X59,2-RECT-OFFWHITE
IFC.REVIGRÉS-Dados de desempenho-Wall Covering - Type: Basic Wall: REVIGRÉS-URBAN-BASE-29,5X59,2-RECT-OFFWHITE
IFC.REVIGRÉS-Dados de especificação-Wall Covering - Type: Basic Wall: REVIGRÉS-URBAN-BASE-29,5X59,2-RECT-OFFWHITE
IFC.REVIGRÉS-Dados geométricos-Wall Covering - Type: Basic Wall: REVIGRÉS-URBAN-BASE-29,5X59,2-RECT-OFFWHITE
IFC.REVIGRÉS-Dados de sustentabilidade-Wall Covering - Type: Basic Wall: REVIGRÉS-URBAN-BASE-29,5X59,2-RECT-OFFWHITE

# IfcWallStandardCase: Basic Wall:REVIGRÉS-URBAN-BASE-30X30-NAT-ANTRACITE, Basic Wall:REVIGRÉS-URBAN-BASE-30X30-NAT-ANTRACITE:21474
In: Level 1
Type - PredefinedType: STANDARD; Material: REVIGRÉS-URBAN-BASE-30X30-NAT-ANTRACITE 8.5 mm
Type - Pset_ElementShading - Roughness: 304.8 mm
Type - Pset_ManufacturerTypeInformation - Manufacturer: REVIGRÉS
Type - Pset_ProductRequirements - Category: Walls
Type - Pset_QuantityTakeOff - Reference: 31201248U1
Type - Pset_ReinforcementBarPitchOfWall - Reference: 31201248U1
Type - Pset_WallCommon - IsExternal: no; Reference: 31201248U1
Type - IFC.REVIGRÉS-Dados do fabricante-Wall Covering - FabricanteURL: https://www.revigres.pt/; ReferenciaModelo: Urban; NumeroGlobalDeItemComercial: 31201248U1; Acabamento: NAT; Material: Grés porcelânico; IdentificadorDoOperadorEconomico: 501840856; UrlFabricanteArtigo: https://www.revigres.pt/colecoes/urban; PaisOrigem: Portugal
Type - IFC.REVIGRÉS-Dados de desempenho-Wall Covering - Rectilinearidade: ± 0.3% máx. ± 1.5 mm; Ortogonalidade: ± 0.3% máx. ± 1.8 mm; PlanaridadeDaSuperficie: ± 0.3% máx. ± 1.8 mm; QualidadeDaSuperficie: Cumpre; AbsorcaoDeAgua: < 0.05%; ModuloDeRuptura: > 45 N/mm²; ResistenciaAFlexao: > 2000 N; ResistenciaAAbrasaoProfunda: < 120 mm³; DilatacaoTermicaLinear: ≤ 8,0x10-6 °C-1; ResistenciaAoChoqueTermico: Resiste; DurabilidadeResistenciaAoGeloDegelo: Resiste; ResistenciaAoEscorregamentoDIN51130: R9; ResistenciaAoEscorregamentoDIN51097: A; ResistenciaAoEscorregamentoENV51097: A; ResistenciaAoEscorregamentoENV12633: Class 1; ResistenciaAoEscorregamentoANSIA1371: ≥0,42; ResistenciaAoDeslizamentoENV12633: Class 1; ResistenciaAsManchas: Class 5; ResistenciaABaixasConcentracoesDeAcidosEAlcalis: Classe LA; ResistenciaAAltasConcentracoesDeAcidosEAlcalis: Classe HA; LibertacaoDeCadmio: 0; LibertacaoDeChumbo: 0
Type - IFC.REVIGRÉS-Dados de especificação-Wall Covering - VariacaoTonalidade: 2; NivelDeTrafego: 5; EPavimento: Sim; ERevestimento: Sim; EExterno: Sim
Type - IFC.REVIGRÉS-Dados geométricos-Wall Covering - AlturaNominal: 8.5 mm; ComprimentoNominal: 30 mm; LarguraNominal: 30 mm
Type - IFC.REVIGRÉS-Dados de sustentabilidade-Wall Covering - PotencialPrivacaoDeAguaConsumoDeAguaPonderado: 4.5; EnergiaTermicaExportada: 0; ItemENovo: Sim; ItemEParcialmenteReciclado: 0.29; ItemEReciclado: Sim; VidaÚtilEsperada: 50; SubstanciasPerigosas: Não; PotencialDeEsgotamentoAbioticoDosRecursosFosseis: 203; PotencialDeEsgotamentoAbioticoDosRecursosNaoFosseisMineraisEMetais: 0.000701; PotencialDeAquecimentoGlobalBiogenico: -0.48; CombustiveisFosseisComPotencialDeAquecimentoGlobal: 13.9; PotencialDeAquecimentoGlobalUsoDoSoloEMudancaDeUsoDoSolo: 0.0246; PotencialDeEutrofizacaoFraccaoDeNutrientesQueAtingemOCompartimentoFinalDeAguaDoce: 0.000189; PotencialDeEutrofizacaoFraccaoDeNutrientesQueAtingemOCompartimentoFinalMarinho: 0.0122; EnergiaRecuperada: 0.00739; ConsumoDeAguaDoce: 0.113; UtilizacaoLiquidaDeAguaDoce: 0.113; ResiduosPerigososEliminados: 0.00221; ResiduosNaoPerigososEliminados: 1.83; MassaTotalDeResiduosRadioactivosEliminados: 0.000394; EnergiaElectricaExportada: 1.55; MateriaisParaRecuperacaoDeEnergia: 0.00739; MateriaisParaReciclagem: 0.0253; UnidadeEPD: 1 m²
Type - IFC.REVIGRÉS-Dados gerais-Wall Covering - Nome: REVIGRÉS-URBAN-BASE-30X30-NAT-URBAN ANTRACITE; TipoProduto: Prensado a seco: grupo BIa UGL | Grés porcelânico técnico; NumeroDeRegistoDAP: EPD-REV-20240006-CCC1-EN; ReferenciaDAP: -; UrlDOP: -
Classification: C3010 (Uniformat)
Pset_QuantityTakeOff - sets with these values: 2
Pset_WallCommon - ExtendToStructure: no; LoadBearing: no
IFC.REVIGRÉS-Dados do fabricante-Wall Covering - Type: Basic Wall: REVIGRÉS-URBAN-BASE-30X30-NAT-ANTRACITE
IFC.REVIGRÉS-Dados de desempenho-Wall Covering - Type: Basic Wall: REVIGRÉS-URBAN-BASE-30X30-NAT-ANTRACITE
IFC.REVIGRÉS-Dados de especificação-Wall Covering - Type: Basic Wall: REVIGRÉS-URBAN-BASE-30X30-NAT-ANTRACITE
IFC.REVIGRÉS-Dados geométricos-Wall Covering - Type: Basic Wall: REVIGRÉS-URBAN-BASE-30X30-NAT-ANTRACITE
IFC.REVIGRÉS-Dados de sustentabilidade-Wall Covering - Type: Basic Wall: REVIGRÉS-URBAN-BASE-30X30-NAT-ANTRACITE

# IfcWallStandardCase: Basic Wall:REVIGRÉS-URBAN-BASE-30X30-NAT-BONE, Basic Wall:REVIGRÉS-URBAN-BASE-30X30-NAT-BONE:21516
In: Level 1
Type - PredefinedType: STANDARD; Material: REVIGRÉS-URBAN-BASE-30X30-NAT-BONE 8.5 mm
Type - Pset_ElementShading - Roughness: 304.8 mm
Type - Pset_ManufacturerTypeInformation - Manufacturer: REVIGRÉS
Type - Pset_ProductRequirements - Category: Walls
Type - Pset_QuantityTakeOff - Reference: 31201220T1
Type - Pset_ReinforcementBarPitchOfWall - Reference: 31201220T1
Type - Pset_WallCommon - IsExternal: no; Reference: 31201220T1
Type - IFC.REVIGRÉS-Dados do fabricante-Wall Covering - FabricanteURL: https://www.revigres.pt/; ReferenciaModelo: Urban; NumeroGlobalDeItemComercial: 31201220T1; Acabamento: NAT; Material: Grés porcelânico; IdentificadorDoOperadorEconomico: 501840856; UrlFabricanteArtigo: https://www.revigres.pt/colecoes/urban; PaisOrigem: Portugal
Type - IFC.REVIGRÉS-Dados de desempenho-Wall Covering - Rectilinearidade: ± 0.3% máx. ± 1.5 mm; Ortogonalidade: ± 0.3% máx. ± 1.8 mm; PlanaridadeDaSuperficie: ± 0.3% máx. ± 1.8 mm; QualidadeDaSuperficie: Cumpre; AbsorcaoDeAgua: < 0.05%; ModuloDeRuptura: > 45 N/mm²; ResistenciaAFlexao: > 2000 N; ResistenciaAAbrasaoProfunda: < 120 mm³; DilatacaoTermicaLinear: ≤ 8,0x10-6 °C-1; ResistenciaAoChoqueTermico: Resiste; DurabilidadeResistenciaAoGeloDegelo: Resiste; ResistenciaAoEscorregamentoDIN51130: R9; ResistenciaAoEscorregamentoDIN51097: A; ResistenciaAoEscorregamentoENV51097: A; ResistenciaAoEscorregamentoENV12633: Class 1; ResistenciaAoEscorregamentoANSIA1371: ≥0,42; ResistenciaAoDeslizamentoENV12633: Class 1; ResistenciaAsManchas: Class 5; ResistenciaABaixasConcentracoesDeAcidosEAlcalis: Classe LA; ResistenciaAAltasConcentracoesDeAcidosEAlcalis: Classe HA; LibertacaoDeCadmio: 0; LibertacaoDeChumbo: 0
Type - IFC.REVIGRÉS-Dados de especificação-Wall Covering - VariacaoTonalidade: 2; NivelDeTrafego: 5; EPavimento: Sim; ERevestimento: Sim; EExterno: Sim
Type - IFC.REVIGRÉS-Dados geométricos-Wall Covering - AlturaNominal: 8.5 mm; ComprimentoNominal: 30 mm; LarguraNominal: 30 mm
Type - IFC.REVIGRÉS-Dados de sustentabilidade-Wall Covering - PotencialPrivacaoDeAguaConsumoDeAguaPonderado: 4.5; EnergiaTermicaExportada: 0; ItemENovo: Sim; ItemEParcialmenteReciclado: 0.03; ItemEReciclado: Sim; VidaÚtilEsperada: 50; SubstanciasPerigosas: Não; PotencialDeEsgotamentoAbioticoDosRecursosFosseis: 203; PotencialDeEsgotamentoAbioticoDosRecursosNaoFosseisMineraisEMetais: 0.000701; PotencialDeAquecimentoGlobalBiogenico: -0.48; CombustiveisFosseisComPotencialDeAquecimentoGlobal: 13.9; PotencialDeAquecimentoGlobalUsoDoSoloEMudancaDeUsoDoSolo: 0.0246; PotencialDeEutrofizacaoFraccaoDeNutrientesQueAtingemOCompartimentoFinalDeAguaDoce: 0.000189; PotencialDeEutrofizacaoFraccaoDeNutrientesQueAtingemOCompartimentoFinalMarinho: 0.0122; EnergiaRecuperada: 0.00739; ConsumoDeAguaDoce: 0.113; UtilizacaoLiquidaDeAguaDoce: 0.113; ResiduosPerigososEliminados: 0.00221; ResiduosNaoPerigososEliminados: 1.83; MassaTotalDeResiduosRadioactivosEliminados: 0.000394; EnergiaElectricaExportada: 1.55; MateriaisParaRecuperacaoDeEnergia: 0.00739; MateriaisParaReciclagem: 0.0253; UnidadeEPD: 1 m²
Type - IFC.REVIGRÉS-Dados gerais-Wall Covering - Nome: REVIGRÉS-URBAN-BASE-30X30-NAT-URBAN BONE; TipoProduto: Prensado a seco: grupo BIa UGL | Grés porcelânico técnico; NumeroDeRegistoDAP: EPD-REV-20240006-CCC1-EN; ReferenciaDAP: -; UrlDOP: -
Classification: C3010 (Uniformat)
Pset_QuantityTakeOff - sets with these values: 2
Pset_WallCommon - ExtendToStructure: no; LoadBearing: no
IFC.REVIGRÉS-Dados do fabricante-Wall Covering - Type: Basic Wall: REVIGRÉS-URBAN-BASE-30X30-NAT-BONE
IFC.REVIGRÉS-Dados de desempenho-Wall Covering - Type: Basic Wall: REVIGRÉS-URBAN-BASE-30X30-NAT-BONE
IFC.REVIGRÉS-Dados de especificação-Wall Covering - Type: Basic Wall: REVIGRÉS-URBAN-BASE-30X30-NAT-BONE
IFC.REVIGRÉS-Dados geométricos-Wall Covering - Type: Basic Wall: REVIGRÉS-URBAN-BASE-30X30-NAT-BONE
IFC.REVIGRÉS-Dados de sustentabilidade-Wall Covering - Type: Basic Wall: REVIGRÉS-URBAN-BASE-30X30-NAT-BONE

# IfcWallStandardCase: Basic Wall:REVIGRÉS-URBAN-BASE-30X30-NAT-CRAFT, Basic Wall:REVIGRÉS-URBAN-BASE-30X30-NAT-CRAFT:21538
In: Level 1
Type - PredefinedType: STANDARD; Material: REVIGRÉS-URBAN-BASE-30X30-NAT-CRAFT 8.5 mm
Type - Pset_ElementShading - Roughness: 304.8 mm
Type - Pset_ManufacturerTypeInformation - Manufacturer: REVIGRÉS
Type - Pset_ProductRequirements - Category: Walls
Type - Pset_QuantityTakeOff - Reference: 31201224T1
Type - Pset_ReinforcementBarPitchOfWall - Reference: 31201224T1
Type - Pset_WallCommon - IsExternal: no; Reference: 31201224T1
Type - IFC.REVIGRÉS-Dados do fabricante-Wall Covering - FabricanteURL: https://www.revigres.pt/; ReferenciaModelo: Urban; NumeroGlobalDeItemComercial: 31201224T1; Acabamento: NAT; Material: Grés porcelânico; IdentificadorDoOperadorEconomico: 501840856; UrlFabricanteArtigo: https://www.revigres.pt/colecoes/urban; PaisOrigem: Portugal
Type - IFC.REVIGRÉS-Dados de desempenho-Wall Covering - Rectilinearidade: ± 0.3% máx. ± 1.5 mm; Ortogonalidade: ± 0.3% máx. ± 1.8 mm; PlanaridadeDaSuperficie: ± 0.3% máx. ± 1.8 mm; QualidadeDaSuperficie: Cumpre; AbsorcaoDeAgua: < 0.05%; ModuloDeRuptura: > 45 N/mm²; ResistenciaAFlexao: > 2000 N; ResistenciaAAbrasaoProfunda: < 120 mm³; DilatacaoTermicaLinear: ≤ 8,0x10-6 °C-1; ResistenciaAoChoqueTermico: Resiste; DurabilidadeResistenciaAoGeloDegelo: Resiste; ResistenciaAoEscorregamentoDIN51130: R9; ResistenciaAoEscorregamentoDIN51097: A; ResistenciaAoEscorregamentoENV51097: A; ResistenciaAoEscorregamentoENV12633: Class 1; ResistenciaAoEscorregamentoANSIA1371: ≥0,42; ResistenciaAoDeslizamentoENV12633: Class 1; ResistenciaAsManchas: Class 5; ResistenciaABaixasConcentracoesDeAcidosEAlcalis: Classe LA; ResistenciaAAltasConcentracoesDeAcidosEAlcalis: Classe HA; LibertacaoDeCadmio: 0; LibertacaoDeChumbo: 0
Type - IFC.REVIGRÉS-Dados de especificação-Wall Covering - VariacaoTonalidade: 2; NivelDeTrafego: 5; EPavimento: Sim; ERevestimento: Sim; EExterno: Sim
Type - IFC.REVIGRÉS-Dados geométricos-Wall Covering - AlturaNominal: 8.5 mm; ComprimentoNominal: 30 mm; LarguraNominal: 30 mm
Type - IFC.REVIGRÉS-Dados de sustentabilidade-Wall Covering - PotencialPrivacaoDeAguaConsumoDeAguaPonderado: 4.5; EnergiaTermicaExportada: 0; ItemENovo: Sim; ItemEParcialmenteReciclado: 0.19; ItemEReciclado: Sim; VidaÚtilEsperada: 50; SubstanciasPerigosas: Não; PotencialDeEsgotamentoAbioticoDosRecursosFosseis: 203; PotencialDeEsgotamentoAbioticoDosRecursosNaoFosseisMineraisEMetais: 0.000701; PotencialDeAquecimentoGlobalBiogenico: -0.48; CombustiveisFosseisComPotencialDeAquecimentoGlobal: 13.9; PotencialDeAquecimentoGlobalUsoDoSoloEMudancaDeUsoDoSolo: 0.0246; PotencialDeEutrofizacaoFraccaoDeNutrientesQueAtingemOCompartimentoFinalDeAguaDoce: 0.000189; PotencialDeEutrofizacaoFraccaoDeNutrientesQueAtingemOCompartimentoFinalMarinho: 0.0122; EnergiaRecuperada: 0.00739; ConsumoDeAguaDoce: 0.113; UtilizacaoLiquidaDeAguaDoce: 0.113; ResiduosPerigososEliminados: 0.00221; ResiduosNaoPerigososEliminados: 1.83; MassaTotalDeResiduosRadioactivosEliminados: 0.000394; EnergiaElectricaExportada: 1.55; MateriaisParaRecuperacaoDeEnergia: 0.00739; MateriaisParaReciclagem: 0.0253; UnidadeEPD: 1 m²
Type - IFC.REVIGRÉS-Dados gerais-Wall Covering - Nome: REVIGRÉS-URBAN-BASE-30X30-NAT-URBAN CRAFT; TipoProduto: Prensado a seco: grupo BIa UGL | Grés porcelânico técnico; NumeroDeRegistoDAP: EPD-REV-20240006-CCC1-EN; ReferenciaDAP: -; UrlDOP: -
Classification: C3010 (Uniformat)
Pset_QuantityTakeOff - sets with these values: 2
Pset_WallCommon - ExtendToStructure: no; LoadBearing: no
IFC.REVIGRÉS-Dados do fabricante-Wall Covering - Type: Basic Wall: REVIGRÉS-URBAN-BASE-30X30-NAT-CRAFT
IFC.REVIGRÉS-Dados de desempenho-Wall Covering - Type: Basic Wall: REVIGRÉS-URBAN-BASE-30X30-NAT-CRAFT
IFC.REVIGRÉS-Dados de especificação-Wall Covering - Type: Basic Wall: REVIGRÉS-URBAN-BASE-30X30-NAT-CRAFT
IFC.REVIGRÉS-Dados geométricos-Wall Covering - Type: Basic Wall: REVIGRÉS-URBAN-BASE-30X30-NAT-CRAFT
IFC.REVIGRÉS-Dados de sustentabilidade-Wall Covering - Type: Basic Wall: REVIGRÉS-URBAN-BASE-30X30-NAT-CRAFT

# IfcWallStandardCase: Basic Wall:REVIGRÉS-URBAN-BASE-30X30-NAT-FOG, Basic Wall:REVIGRÉS-URBAN-BASE-30X30-NAT-FOG:21560
In: Level 1
Type - PredefinedType: STANDARD; Material: REVIGRÉS-URBAN-BASE-30X30-NAT-FOG 8.5 mm
Type - Pset_ElementShading - Roughness: 304.8 mm
Type - Pset_ManufacturerTypeInformation - Manufacturer: REVIGRÉS
Type - Pset_ProductRequirements - Category: Walls
Type - Pset_QuantityTakeOff - Reference: 31201221T1
Type - Pset_ReinforcementBarPitchOfWall - Reference: 31201221T1
Type - Pset_WallCommon - IsExternal: no; Reference: 31201221T1
Type - IFC.REVIGRÉS-Dados do fabricante-Wall Covering - FabricanteURL: https://www.revigres.pt/; ReferenciaModelo: Urban; NumeroGlobalDeItemComercial: 31201221T1; Acabamento: NAT; Material: Grés porcelânico; IdentificadorDoOperadorEconomico: 501840856; UrlFabricanteArtigo: https://www.revigres.pt/colecoes/urban; PaisOrigem: Portugal
Type - IFC.REVIGRÉS-Dados de desempenho-Wall Covering - Rectilinearidade: ± 0.3% máx. ± 1.5 mm; Ortogonalidade: ± 0.3% máx. ± 1.8 mm; PlanaridadeDaSuperficie: ± 0.3% máx. ± 1.8 mm; QualidadeDaSuperficie: Cumpre; AbsorcaoDeAgua: < 0.05%; ModuloDeRuptura: > 45 N/mm²; ResistenciaAFlexao: > 2000 N; ResistenciaAAbrasaoProfunda: < 120 mm³; DilatacaoTermicaLinear: ≤ 8,0x10-6 °C-1; ResistenciaAoChoqueTermico: Resiste; DurabilidadeResistenciaAoGeloDegelo: Resiste; ResistenciaAoEscorregamentoDIN51130: R9; ResistenciaAoEscorregamentoDIN51097: A; ResistenciaAoEscorregamentoENV51097: A; ResistenciaAoEscorregamentoENV12633: Class 1; ResistenciaAoEscorregamentoANSIA1371: ≥0,42; ResistenciaAoDeslizamentoENV12633: Class 1; ResistenciaAsManchas: Class 5; ResistenciaABaixasConcentracoesDeAcidosEAlcalis: Classe LA; ResistenciaAAltasConcentracoesDeAcidosEAlcalis: Classe HA; LibertacaoDeCadmio: 0; LibertacaoDeChumbo: 0
Type - IFC.REVIGRÉS-Dados de especificação-Wall Covering - VariacaoTonalidade: 2; NivelDeTrafego: 5; EPavimento: Sim; ERevestimento: Sim; EExterno: Sim
Type - IFC.REVIGRÉS-Dados geométricos-Wall Covering - AlturaNominal: 8.5 mm; ComprimentoNominal: 30 mm; LarguraNominal: 30 mm
Type - IFC.REVIGRÉS-Dados de sustentabilidade-Wall Covering - PotencialPrivacaoDeAguaConsumoDeAguaPonderado: 4.5; EnergiaTermicaExportada: 0; ItemENovo: Sim; ItemEParcialmenteReciclado: 0.23; ItemEReciclado: Sim; VidaÚtilEsperada: 50; SubstanciasPerigosas: Não; PotencialDeEsgotamentoAbioticoDosRecursosFosseis: 203; PotencialDeEsgotamentoAbioticoDosRecursosNaoFosseisMineraisEMetais: 0.000701; PotencialDeAquecimentoGlobalBiogenico: -0.48; CombustiveisFosseisComPotencialDeAquecimentoGlobal: 13.9; PotencialDeAquecimentoGlobalUsoDoSoloEMudancaDeUsoDoSolo: 0.0246; PotencialDeEutrofizacaoFraccaoDeNutrientesQueAtingemOCompartimentoFinalDeAguaDoce: 0.000189; PotencialDeEutrofizacaoFraccaoDeNutrientesQueAtingemOCompartimentoFinalMarinho: 0.0122; EnergiaRecuperada: 0.00739; ConsumoDeAguaDoce: 0.113; UtilizacaoLiquidaDeAguaDoce: 0.113; ResiduosPerigososEliminados: 0.00221; ResiduosNaoPerigososEliminados: 1.83; MassaTotalDeResiduosRadioactivosEliminados: 0.000394; EnergiaElectricaExportada: 1.55; MateriaisParaRecuperacaoDeEnergia: 0.00739; MateriaisParaReciclagem: 0.0253; UnidadeEPD: 1 m²
Type - IFC.REVIGRÉS-Dados gerais-Wall Covering - Nome: REVIGRÉS-URBAN-BASE-30X30-NAT-URBAN FOG; TipoProduto: Prensado a seco: grupo BIa UGL | Grés porcelânico técnico; NumeroDeRegistoDAP: EPD-REV-20240006-CCC1-EN; ReferenciaDAP: -; UrlDOP: -
Classification: C3010 (Uniformat)
Pset_QuantityTakeOff - sets with these values: 2
Pset_WallCommon - ExtendToStructure: no; LoadBearing: no
IFC.REVIGRÉS-Dados do fabricante-Wall Covering - Type: Basic Wall: REVIGRÉS-URBAN-BASE-30X30-NAT-FOG
IFC.REVIGRÉS-Dados de desempenho-Wall Covering - Type: Basic Wall: REVIGRÉS-URBAN-BASE-30X30-NAT-FOG
IFC.REVIGRÉS-Dados de especificação-Wall Covering - Type: Basic Wall: REVIGRÉS-URBAN-BASE-30X30-NAT-FOG
IFC.REVIGRÉS-Dados geométricos-Wall Covering - Type: Basic Wall: REVIGRÉS-URBAN-BASE-30X30-NAT-FOG
IFC.REVIGRÉS-Dados de sustentabilidade-Wall Covering - Type: Basic Wall: REVIGRÉS-URBAN-BASE-30X30-NAT-FOG

# IfcWallStandardCase: Basic Wall:REVIGRÉS-URBAN-BASE-30X30-NAT-GRIS, Basic Wall:REVIGRÉS-URBAN-BASE-30X30-NAT-GRIS:21582
In: Level 1
Type - PredefinedType: STANDARD; Material: REVIGRÉS-URBAN-BASE-30X30-NAT-GRIS 8.5 mm
Type - Pset_ElementShading - Roughness: 304.8 mm
Type - Pset_ManufacturerTypeInformation - Manufacturer: REVIGRÉS
Type - Pset_ProductRequirements - Category: Walls
Type - Pset_QuantityTakeOff - Reference: 31201222T1
Type - Pset_ReinforcementBarPitchOfWall - Reference: 31201222T1
Type - Pset_WallCommon - IsExternal: no; Reference: 31201222T1
Type - IFC.REVIGRÉS-Dados do fabricante-Wall Covering - FabricanteURL: https://www.revigres.pt/; ReferenciaModelo: Urban; NumeroGlobalDeItemComercial: 31201222T1; Acabamento: NAT; Material: Grés porcelânico; IdentificadorDoOperadorEconomico: 501840856; UrlFabricanteArtigo: https://www.revigres.pt/colecoes/urban; PaisOrigem: Portugal
Type - IFC.REVIGRÉS-Dados de desempenho-Wall Covering - Rectilinearidade: ± 0.3% máx. ± 1.5 mm; Ortogonalidade: ± 0.3% máx. ± 1.8 mm; PlanaridadeDaSuperficie: ± 0.3% máx. ± 1.8 mm; QualidadeDaSuperficie: Cumpre; AbsorcaoDeAgua: < 0.05%; ModuloDeRuptura: > 45 N/mm²; ResistenciaAFlexao: > 2000 N; ResistenciaAAbrasaoProfunda: < 120 mm³; DilatacaoTermicaLinear: ≤ 8,0x10-6 °C-1; ResistenciaAoChoqueTermico: Resiste; DurabilidadeResistenciaAoGeloDegelo: Resiste; ResistenciaAoEscorregamentoDIN51130: R9; ResistenciaAoEscorregamentoDIN51097: A; ResistenciaAoEscorregamentoENV51097: A; ResistenciaAoEscorregamentoENV12633: Class 1; ResistenciaAoEscorregamentoANSIA1371: ≥0,42; ResistenciaAoDeslizamentoENV12633: Class 1; ResistenciaAsManchas: Class 5; ResistenciaABaixasConcentracoesDeAcidosEAlcalis: Classe LA; ResistenciaAAltasConcentracoesDeAcidosEAlcalis: Classe HA; LibertacaoDeCadmio: 0; LibertacaoDeChumbo: 0
Type - IFC.REVIGRÉS-Dados de especificação-Wall Covering - VariacaoTonalidade: 2; NivelDeTrafego: 5; EPavimento: Sim; ERevestimento: Sim; EExterno: Sim
Type - IFC.REVIGRÉS-Dados geométricos-Wall Covering - AlturaNominal: 8.5 mm; ComprimentoNominal: 30 mm; LarguraNominal: 30 mm
Type - IFC.REVIGRÉS-Dados de sustentabilidade-Wall Covering - PotencialPrivacaoDeAguaConsumoDeAguaPonderado: 4.5; EnergiaTermicaExportada: 0; ItemENovo: Sim; ItemEParcialmenteReciclado: 0.23; ItemEReciclado: Sim; VidaÚtilEsperada: 50; SubstanciasPerigosas: Não; PotencialDeEsgotamentoAbioticoDosRecursosFosseis: 203; PotencialDeEsgotamentoAbioticoDosRecursosNaoFosseisMineraisEMetais: 0.000701; PotencialDeAquecimentoGlobalBiogenico: -0.48; CombustiveisFosseisComPotencialDeAquecimentoGlobal: 13.9; PotencialDeAquecimentoGlobalUsoDoSoloEMudancaDeUsoDoSolo: 0.0246; PotencialDeEutrofizacaoFraccaoDeNutrientesQueAtingemOCompartimentoFinalDeAguaDoce: 0.000189; PotencialDeEutrofizacaoFraccaoDeNutrientesQueAtingemOCompartimentoFinalMarinho: 0.0122; EnergiaRecuperada: 0.00739; ConsumoDeAguaDoce: 0.113; UtilizacaoLiquidaDeAguaDoce: 0.113; ResiduosPerigososEliminados: 0.00221; ResiduosNaoPerigososEliminados: 1.83; MassaTotalDeResiduosRadioactivosEliminados: 0.000394; EnergiaElectricaExportada: 1.55; MateriaisParaRecuperacaoDeEnergia: 0.00739; MateriaisParaReciclagem: 0.0253; UnidadeEPD: 1 m²
Type - IFC.REVIGRÉS-Dados gerais-Wall Covering - Nome: REVIGRÉS-URBAN-BASE-30X30-NAT-URBAN GRIS; TipoProduto: Prensado a seco: grupo BIa UGL | Grés porcelânico técnico; NumeroDeRegistoDAP: EPD-REV-20240006-CCC1-EN; ReferenciaDAP: -; UrlDOP: -
Classification: C3010 (Uniformat)
Pset_QuantityTakeOff - sets with these values: 2
Pset_WallCommon - ExtendToStructure: no; LoadBearing: no
IFC.REVIGRÉS-Dados do fabricante-Wall Covering - Type: Basic Wall: REVIGRÉS-URBAN-BASE-30X30-NAT-GRIS
IFC.REVIGRÉS-Dados de desempenho-Wall Covering - Type: Basic Wall: REVIGRÉS-URBAN-BASE-30X30-NAT-GRIS
IFC.REVIGRÉS-Dados de especificação-Wall Covering - Type: Basic Wall: REVIGRÉS-URBAN-BASE-30X30-NAT-GRIS
IFC.REVIGRÉS-Dados geométricos-Wall Covering - Type: Basic Wall: REVIGRÉS-URBAN-BASE-30X30-NAT-GRIS
IFC.REVIGRÉS-Dados de sustentabilidade-Wall Covering - Type: Basic Wall: REVIGRÉS-URBAN-BASE-30X30-NAT-GRIS

# IfcWallStandardCase: Basic Wall:REVIGRÉS-URBAN-BASE-30X30-NAT-OFFWHITE, Basic Wall:REVIGRÉS-URBAN-BASE-30X30-NAT-OFFWHITE:23712
In: Level 1
Type - PredefinedType: STANDARD; Material: REVIGRÉS-URBAN-BASE-30X30-NAT-OFFWHITE 8.5 mm
Type - Pset_ElementShading - Roughness: 304.8 mm
Type - Pset_ManufacturerTypeInformation - Manufacturer: REVIGRÉS
Type - Pset_ProductRequirements - Category: Walls
Type - Pset_QuantityTakeOff - Reference: 31201223T1
Type - Pset_ReinforcementBarPitchOfWall - Reference: 31201223T1
Type - Pset_WallCommon - IsExternal: no; Reference: 31201223T1
Type - IFC.REVIGRÉS-Dados do fabricante-Wall Covering - FabricanteURL: https://www.revigres.pt/; ReferenciaModelo: Urban; NumeroGlobalDeItemComercial: 31201223T1; Acabamento: NAT; Material: Grés porcelânico; IdentificadorDoOperadorEconomico: 501840856; UrlFabricanteArtigo: https://www.revigres.pt/colecoes/urban; PaisOrigem: Portugal
Type - IFC.REVIGRÉS-Dados de desempenho-Wall Covering - Rectilinearidade: ± 0.3% máx. ± 1.5 mm; Ortogonalidade: ± 0.3% máx. ± 1.8 mm; PlanaridadeDaSuperficie: ± 0.3% máx. ± 1.8 mm; QualidadeDaSuperficie: Cumpre; AbsorcaoDeAgua: < 0.05%; ModuloDeRuptura: > 45 N/mm²; ResistenciaAFlexao: > 2000 N; ResistenciaAAbrasaoProfunda: < 120 mm³; DilatacaoTermicaLinear: ≤ 8,0x10-6 °C-1; ResistenciaAoChoqueTermico: Resiste; DurabilidadeResistenciaAoGeloDegelo: Resiste; ResistenciaAoEscorregamentoDIN51130: R9; ResistenciaAoEscorregamentoDIN51097: A; ResistenciaAoEscorregamentoENV51097: A; ResistenciaAoEscorregamentoENV12633: Class 1; ResistenciaAoEscorregamentoANSIA1371: ≥0,42; ResistenciaAoDeslizamentoENV12633: Class 1; ResistenciaAsManchas: Class 5; ResistenciaABaixasConcentracoesDeAcidosEAlcalis: Classe LA; ResistenciaAAltasConcentracoesDeAcidosEAlcalis: Classe HA; LibertacaoDeCadmio: 0; LibertacaoDeChumbo: 0
Type - IFC.REVIGRÉS-Dados de especificação-Wall Covering - VariacaoTonalidade: 2; NivelDeTrafego: 5; EPavimento: Sim; ERevestimento: Sim; EExterno: Sim
Type - IFC.REVIGRÉS-Dados geométricos-Wall Covering - AlturaNominal: 8.5 mm; ComprimentoNominal: 30 mm; LarguraNominal: 30 mm
Type - IFC.REVIGRÉS-Dados de sustentabilidade-Wall Covering - PotencialPrivacaoDeAguaConsumoDeAguaPonderado: 4.5; EnergiaTermicaExportada: 0; ItemENovo: Sim; ItemEParcialmenteReciclado: 0.03; ItemEReciclado: Sim; VidaÚtilEsperada: 50; SubstanciasPerigosas: Não; PotencialDeEsgotamentoAbioticoDosRecursosFosseis: 203; PotencialDeEsgotamentoAbioticoDosRecursosNaoFosseisMineraisEMetais: 0.000701; PotencialDeAquecimentoGlobalBiogenico: -0.48; CombustiveisFosseisComPotencialDeAquecimentoGlobal: 13.9; PotencialDeAquecimentoGlobalUsoDoSoloEMudancaDeUsoDoSolo: 0.0246; PotencialDeEutrofizacaoFraccaoDeNutrientesQueAtingemOCompartimentoFinalDeAguaDoce: 0.000189; PotencialDeEutrofizacaoFraccaoDeNutrientesQueAtingemOCompartimentoFinalMarinho: 0.0122; EnergiaRecuperada: 0.00739; ConsumoDeAguaDoce: 0.113; UtilizacaoLiquidaDeAguaDoce: 0.113; ResiduosPerigososEliminados: 0.00221; ResiduosNaoPerigososEliminados: 1.83; MassaTotalDeResiduosRadioactivosEliminados: 0.000394; EnergiaElectricaExportada: 1.55; MateriaisParaRecuperacaoDeEnergia: 0.00739; MateriaisParaReciclagem: 0.0253; UnidadeEPD: 1 m²
Type - IFC.REVIGRÉS-Dados gerais-Wall Covering - Nome: REVIGRÉS-URBAN-BASE-30X30-NAT-URBAN OFFWHITE; TipoProduto: Prensado a seco: grupo BIa UGL | Grés porcelânico técnico; NumeroDeRegistoDAP: EPD-REV-20240006-CCC1-EN; ReferenciaDAP: -; UrlDOP: -
Classification: C3010 (Uniformat)
Pset_QuantityTakeOff - sets with these values: 2
Pset_WallCommon - ExtendToStructure: no; LoadBearing: no
IFC.REVIGRÉS-Dados do fabricante-Wall Covering - Type: Basic Wall: REVIGRÉS-URBAN-BASE-30X30-NAT-OFFWHITE
IFC.REVIGRÉS-Dados de desempenho-Wall Covering - Type: Basic Wall: REVIGRÉS-URBAN-BASE-30X30-NAT-OFFWHITE
IFC.REVIGRÉS-Dados de especificação-Wall Covering - Type: Basic Wall: REVIGRÉS-URBAN-BASE-30X30-NAT-OFFWHITE
IFC.REVIGRÉS-Dados geométricos-Wall Covering - Type: Basic Wall: REVIGRÉS-URBAN-BASE-30X30-NAT-OFFWHITE
IFC.REVIGRÉS-Dados de sustentabilidade-Wall Covering - Type: Basic Wall: REVIGRÉS-URBAN-BASE-30X30-NAT-OFFWHITE

# IfcWallStandardCase: Basic Wall:REVIGRÉS-URBAN-BASE-30X60-NAT-ANTRACITE, Basic Wall:REVIGRÉS-URBAN-BASE-30X60-NAT-ANTRACITE:25905
In: Level 1
Type - PredefinedType: STANDARD; Material: REVIGRÉS-URBAN-BASE-30X60-NAT-ANTRACITE 8.5 mm
Type - Pset_ElementShading - Roughness: 304.8 mm
Type - Pset_ManufacturerTypeInformation - Manufacturer: REVIGRÉS
Type - Pset_ProductRequirements - Category: Walls
Type - Pset_QuantityTakeOff - Reference: 31202148U1
Type - Pset_ReinforcementBarPitchOfWall - Reference: 31202148U1
Type - Pset_WallCommon - IsExternal: no; Reference: 31202148U1
Type - IFC.REVIGRÉS-Dados do fabricante-Wall Covering - FabricanteURL: https://www.revigres.pt/; ReferenciaModelo: Urban; NumeroGlobalDeItemComercial: 31202148U1; Acabamento: NAT; Material: Grés porcelânico; IdentificadorDoOperadorEconomico: 501840856; UrlFabricanteArtigo: https://www.revigres.pt/colecoes/urban; PaisOrigem: Portugal
Type - IFC.REVIGRÉS-Dados de desempenho-Wall Covering - Rectilinearidade: ± 0.3% máx. ± 1.5 mm; Ortogonalidade: ± 0.3% máx. ± 1.8 mm; PlanaridadeDaSuperficie: ± 0.3% máx. ± 1.8 mm; QualidadeDaSuperficie: Cumpre; AbsorcaoDeAgua: < 0.05%; ModuloDeRuptura: > 45 N/mm²; ResistenciaAFlexao: > 2000 N; ResistenciaAAbrasaoProfunda: < 120 mm³; DilatacaoTermicaLinear: ≤ 8,0x10-6 °C-1; ResistenciaAoChoqueTermico: Resiste; DurabilidadeResistenciaAoGeloDegelo: Resiste; ResistenciaAoEscorregamentoDIN51130: R9; ResistenciaAoEscorregamentoDIN51097: A; ResistenciaAoEscorregamentoENV51097: A; ResistenciaAoEscorregamentoENV12633: Class 1; ResistenciaAoEscorregamentoANSIA1371: ≥0,42; ResistenciaAoDeslizamentoENV12633: Class 1; ResistenciaAsManchas: Class 5; ResistenciaABaixasConcentracoesDeAcidosEAlcalis: Classe LA; ResistenciaAAltasConcentracoesDeAcidosEAlcalis: Classe HA; LibertacaoDeCadmio: 0; LibertacaoDeChumbo: 0
Type - IFC.REVIGRÉS-Dados de especificação-Wall Covering - VariacaoTonalidade: 2; NivelDeTrafego: 5; EPavimento: Sim; ERevestimento: Sim; EExterno: Sim
Type - IFC.REVIGRÉS-Dados geométricos-Wall Covering - AlturaNominal: 8.5 mm; ComprimentoNominal: 30 mm; LarguraNominal: 60 mm
Type - IFC.REVIGRÉS-Dados de sustentabilidade-Wall Covering - PotencialPrivacaoDeAguaConsumoDeAguaPonderado: 4.5; EnergiaTermicaExportada: 0; ItemENovo: Sim; ItemEParcialmenteReciclado: 0.29; ItemEReciclado: Sim; VidaÚtilEsperada: 50; SubstanciasPerigosas: Não; PotencialDeEsgotamentoAbioticoDosRecursosFosseis: 203; PotencialDeEsgotamentoAbioticoDosRecursosNaoFosseisMineraisEMetais: 0.000701; PotencialDeAquecimentoGlobalBiogenico: -0.48; CombustiveisFosseisComPotencialDeAquecimentoGlobal: 13.9; PotencialDeAquecimentoGlobalUsoDoSoloEMudancaDeUsoDoSolo: 0.0246; PotencialDeEutrofizacaoFraccaoDeNutrientesQueAtingemOCompartimentoFinalDeAguaDoce: 0.000189; PotencialDeEutrofizacaoFraccaoDeNutrientesQueAtingemOCompartimentoFinalMarinho: 0.0122; EnergiaRecuperada: 0.00739; ConsumoDeAguaDoce: 0.113; UtilizacaoLiquidaDeAguaDoce: 0.113; ResiduosPerigososEliminados: 0.00221; ResiduosNaoPerigososEliminados: 1.83; MassaTotalDeResiduosRadioactivosEliminados: 0.000394; EnergiaElectricaExportada: 1.55; MateriaisParaRecuperacaoDeEnergia: 0.00739; MateriaisParaReciclagem: 0.0253; UnidadeEPD: 1 m²
Type - IFC.REVIGRÉS-Dados gerais-Wall Covering - Nome: REVIGRÉS-URBAN-BASE-30X60-NAT-URBAN ANTRACITE; TipoProduto: Prensado a seco: grupo BIa UGL | Grés porcelânico técnico; NumeroDeRegistoDAP: EPD-REV-20240006-CCC1-EN; ReferenciaDAP: -; UrlDOP: -
Classification: C3010 (Uniformat)
Pset_QuantityTakeOff - sets with these values: 2
Pset_WallCommon - ExtendToStructure: no; LoadBearing: no
IFC.REVIGRÉS-Dados do fabricante-Wall Covering - Type: Basic Wall: REVIGRÉS-URBAN-BASE-30X60-NAT-ANTRACITE
IFC.REVIGRÉS-Dados de desempenho-Wall Covering - Type: Basic Wall: REVIGRÉS-URBAN-BASE-30X60-NAT-ANTRACITE
IFC.REVIGRÉS-Dados de especificação-Wall Covering - Type: Basic Wall: REVIGRÉS-URBAN-BASE-30X60-NAT-ANTRACITE
IFC.REVIGRÉS-Dados geométricos-Wall Covering - Type: Basic Wall: REVIGRÉS-URBAN-BASE-30X60-NAT-ANTRACITE
IFC.REVIGRÉS-Dados de sustentabilidade-Wall Covering - Type: Basic Wall: REVIGRÉS-URBAN-BASE-30X60-NAT-ANTRACITE

# IfcWallStandardCase: Basic Wall:REVIGRÉS-URBAN-BASE-30X60-NAT-BONE, Basic Wall:REVIGRÉS-URBAN-BASE-30X60-NAT-BONE:25913
In: Level 1
Type - PredefinedType: STANDARD; Material: REVIGRÉS-URBAN-BASE-30X60-NAT-BONE 8.5 mm
Type - Pset_ElementShading - Roughness: 304.8 mm
Type - Pset_ManufacturerTypeInformation - Manufacturer: REVIGRÉS
Type - Pset_ProductRequirements - Category: Walls
Type - Pset_QuantityTakeOff - Reference: 31202120T1
Type - Pset_ReinforcementBarPitchOfWall - Reference: 31202120T1
Type - Pset_WallCommon - IsExternal: no; Reference: 31202120T1
Type - IFC.REVIGRÉS-Dados do fabricante-Wall Covering - FabricanteURL: https://www.revigres.pt/; ReferenciaModelo: Urban; NumeroGlobalDeItemComercial: 31202120T1; Acabamento: NAT; Material: Grés porcelânico; IdentificadorDoOperadorEconomico: 501840856; UrlFabricanteArtigo: https://www.revigres.pt/colecoes/urban; PaisOrigem: Portugal
Type - IFC.REVIGRÉS-Dados de desempenho-Wall Covering - Rectilinearidade: ± 0.3% máx. ± 1.5 mm; Ortogonalidade: ± 0.3% máx. ± 1.8 mm; PlanaridadeDaSuperficie: ± 0.3% máx. ± 1.8 mm; QualidadeDaSuperficie: Cumpre; AbsorcaoDeAgua: < 0.05%; ModuloDeRuptura: > 45 N/mm²; ResistenciaAFlexao: > 2000 N; ResistenciaAAbrasaoProfunda: < 120 mm³; DilatacaoTermicaLinear: ≤ 8,0x10-6 °C-1; ResistenciaAoChoqueTermico: Resiste; DurabilidadeResistenciaAoGeloDegelo: Resiste; ResistenciaAoEscorregamentoDIN51130: R9; ResistenciaAoEscorregamentoDIN51097: A; ResistenciaAoEscorregamentoENV51097: A; ResistenciaAoEscorregamentoENV12633: Class 1; ResistenciaAoEscorregamentoANSIA1371: ≥0,42; ResistenciaAoDeslizamentoENV12633: Class 1; ResistenciaAsManchas: Class 5; ResistenciaABaixasConcentracoesDeAcidosEAlcalis: Classe LA; ResistenciaAAltasConcentracoesDeAcidosEAlcalis: Classe HA; LibertacaoDeCadmio: 0; LibertacaoDeChumbo: 0
Type - IFC.REVIGRÉS-Dados de especificação-Wall Covering - VariacaoTonalidade: 2; NivelDeTrafego: 5; EPavimento: Sim; ERevestimento: Sim; EExterno: Sim
Type - IFC.REVIGRÉS-Dados geométricos-Wall Covering - AlturaNominal: 8.5 mm; ComprimentoNominal: 30 mm; LarguraNominal: 60 mm
Type - IFC.REVIGRÉS-Dados de sustentabilidade-Wall Covering - PotencialPrivacaoDeAguaConsumoDeAguaPonderado: 4.5; EnergiaTermicaExportada: 0; ItemENovo: Sim; ItemEParcialmenteReciclado: 0.03; ItemEReciclado: Sim; VidaÚtilEsperada: 50; SubstanciasPerigosas: Não; PotencialDeEsgotamentoAbioticoDosRecursosFosseis: 203; PotencialDeEsgotamentoAbioticoDosRecursosNaoFosseisMineraisEMetais: 0.000701; PotencialDeAquecimentoGlobalBiogenico: -0.48; CombustiveisFosseisComPotencialDeAquecimentoGlobal: 13.9; PotencialDeAquecimentoGlobalUsoDoSoloEMudancaDeUsoDoSolo: 0.0246; PotencialDeEutrofizacaoFraccaoDeNutrientesQueAtingemOCompartimentoFinalDeAguaDoce: 0.000189; PotencialDeEutrofizacaoFraccaoDeNutrientesQueAtingemOCompartimentoFinalMarinho: 0.0122; EnergiaRecuperada: 0.00739; ConsumoDeAguaDoce: 0.113; UtilizacaoLiquidaDeAguaDoce: 0.113; ResiduosPerigososEliminados: 0.00221; ResiduosNaoPerigososEliminados: 1.83; MassaTotalDeResiduosRadioactivosEliminados: 0.000394; EnergiaElectricaExportada: 1.55; MateriaisParaRecuperacaoDeEnergia: 0.00739; MateriaisParaReciclagem: 0.0253; UnidadeEPD: 1 m²
Type - IFC.REVIGRÉS-Dados gerais-Wall Covering - Nome: REVIGRÉS-URBAN-BASE-30X60-NAT-URBAN BONE; TipoProduto: Prensado a seco: grupo BIa UGL | Grés porcelânico técnico; NumeroDeRegistoDAP: EPD-REV-20240006-CCC1-EN; ReferenciaDAP: -; UrlDOP: -
Classification: C3010 (Uniformat)
Pset_QuantityTakeOff - sets with these values: 2
Pset_WallCommon - ExtendToStructure: no; LoadBearing: no
IFC.REVIGRÉS-Dados do fabricante-Wall Covering - Type: Basic Wall: REVIGRÉS-URBAN-BASE-30X60-NAT-BONE
IFC.REVIGRÉS-Dados de desempenho-Wall Covering - Type: Basic Wall: REVIGRÉS-URBAN-BASE-30X60-NAT-BONE
IFC.REVIGRÉS-Dados de especificação-Wall Covering - Type: Basic Wall: REVIGRÉS-URBAN-BASE-30X60-NAT-BONE
IFC.REVIGRÉS-Dados geométricos-Wall Covering - Type: Basic Wall: REVIGRÉS-URBAN-BASE-30X60-NAT-BONE
IFC.REVIGRÉS-Dados de sustentabilidade-Wall Covering - Type: Basic Wall: REVIGRÉS-URBAN-BASE-30X60-NAT-BONE

# IfcWallStandardCase: Basic Wall:REVIGRÉS-URBAN-BASE-30X60-NAT-CRAFT, Basic Wall:REVIGRÉS-URBAN-BASE-30X60-NAT-CRAFT:25921
In: Level 1
Type - PredefinedType: STANDARD; Material: REVIGRÉS-URBAN-BASE-30X60-NAT-CRAFT 8.5 mm
Type - Pset_ElementShading - Roughness: 304.8 mm
Type - Pset_ManufacturerTypeInformation - Manufacturer: REVIGRÉS
Type - Pset_ProductRequirements - Category: Walls
Type - Pset_QuantityTakeOff - Reference: 31202124T1
Type - Pset_ReinforcementBarPitchOfWall - Reference: 31202124T1
Type - Pset_WallCommon - IsExternal: no; Reference: 31202124T1
Type - IFC.REVIGRÉS-Dados do fabricante-Wall Covering - FabricanteURL: https://www.revigres.pt/; ReferenciaModelo: Urban; NumeroGlobalDeItemComercial: 31202124T1; Acabamento: NAT; Material: Grés porcelânico; IdentificadorDoOperadorEconomico: 501840856; UrlFabricanteArtigo: https://www.revigres.pt/colecoes/urban; PaisOrigem: Portugal
Type - IFC.REVIGRÉS-Dados de desempenho-Wall Covering - Rectilinearidade: ± 0.3% máx. ± 1.5 mm; Ortogonalidade: ± 0.3% máx. ± 1.8 mm; PlanaridadeDaSuperficie: ± 0.3% máx. ± 1.8 mm; QualidadeDaSuperficie: Cumpre; AbsorcaoDeAgua: < 0.05%; ModuloDeRuptura: > 45 N/mm²; ResistenciaAFlexao: > 2000 N; ResistenciaAAbrasaoProfunda: < 120 mm³; DilatacaoTermicaLinear: ≤ 8,0x10-6 °C-1; ResistenciaAoChoqueTermico: Resiste; DurabilidadeResistenciaAoGeloDegelo: Resiste; ResistenciaAoEscorregamentoDIN51130: R9; ResistenciaAoEscorregamentoDIN51097: A; ResistenciaAoEscorregamentoENV51097: A; ResistenciaAoEscorregamentoENV12633: Class 1; ResistenciaAoEscorregamentoANSIA1371: ≥0,42; ResistenciaAoDeslizamentoENV12633: Class 1; ResistenciaAsManchas: Class 5; ResistenciaABaixasConcentracoesDeAcidosEAlcalis: Classe LA; ResistenciaAAltasConcentracoesDeAcidosEAlcalis: Classe HA; LibertacaoDeCadmio: 0; LibertacaoDeChumbo: 0
Type - IFC.REVIGRÉS-Dados de especificação-Wall Covering - VariacaoTonalidade: 2; NivelDeTrafego: 5; EPavimento: Sim; ERevestimento: Sim; EExterno: Sim
Type - IFC.REVIGRÉS-Dados geométricos-Wall Covering - AlturaNominal: 8.5 mm; ComprimentoNominal: 30 mm; LarguraNominal: 60 mm
Type - IFC.REVIGRÉS-Dados de sustentabilidade-Wall Covering - PotencialPrivacaoDeAguaConsumoDeAguaPonderado: 4.5; EnergiaTermicaExportada: 0; ItemENovo: Sim; ItemEParcialmenteReciclado: 0.19; ItemEReciclado: Sim; VidaÚtilEsperada: 50; SubstanciasPerigosas: Não; PotencialDeEsgotamentoAbioticoDosRecursosFosseis: 203; PotencialDeEsgotamentoAbioticoDosRecursosNaoFosseisMineraisEMetais: 0.000701; PotencialDeAquecimentoGlobalBiogenico: -0.48; CombustiveisFosseisComPotencialDeAquecimentoGlobal: 13.9; PotencialDeAquecimentoGlobalUsoDoSoloEMudancaDeUsoDoSolo: 0.0246; PotencialDeEutrofizacaoFraccaoDeNutrientesQueAtingemOCompartimentoFinalDeAguaDoce: 0.000189; PotencialDeEutrofizacaoFraccaoDeNutrientesQueAtingemOCompartimentoFinalMarinho: 0.0122; EnergiaRecuperada: 0.00739; ConsumoDeAguaDoce: 0.113; UtilizacaoLiquidaDeAguaDoce: 0.113; ResiduosPerigososEliminados: 0.00221; ResiduosNaoPerigososEliminados: 1.83; MassaTotalDeResiduosRadioactivosEliminados: 0.000394; EnergiaElectricaExportada: 1.55; MateriaisParaRecuperacaoDeEnergia: 0.00739; MateriaisParaReciclagem: 0.0253; UnidadeEPD: 1 m²
Type - IFC.REVIGRÉS-Dados gerais-Wall Covering - Nome: REVIGRÉS-URBAN-BASE-30X60-NAT-URBAN CRAFT; TipoProduto: Prensado a seco: grupo BIa UGL | Grés porcelânico técnico; NumeroDeRegistoDAP: EPD-REV-20240006-CCC1-EN; ReferenciaDAP: -; UrlDOP: -
Classification: C3010 (Uniformat)
Pset_QuantityTakeOff - sets with these values: 2
Pset_WallCommon - ExtendToStructure: no; LoadBearing: no
IFC.REVIGRÉS-Dados do fabricante-Wall Covering - Type: Basic Wall: REVIGRÉS-URBAN-BASE-30X60-NAT-CRAFT
IFC.REVIGRÉS-Dados de desempenho-Wall Covering - Type: Basic Wall: REVIGRÉS-URBAN-BASE-30X60-NAT-CRAFT
IFC.REVIGRÉS-Dados de especificação-Wall Covering - Type: Basic Wall: REVIGRÉS-URBAN-BASE-30X60-NAT-CRAFT
IFC.REVIGRÉS-Dados geométricos-Wall Covering - Type: Basic Wall: REVIGRÉS-URBAN-BASE-30X60-NAT-CRAFT
IFC.REVIGRÉS-Dados de sustentabilidade-Wall Covering - Type: Basic Wall: REVIGRÉS-URBAN-BASE-30X60-NAT-CRAFT

# IfcWallStandardCase: Basic Wall:REVIGRÉS-URBAN-BASE-30X60-NAT-FOG, Basic Wall:REVIGRÉS-URBAN-BASE-30X60-NAT-FOG:25929
In: Level 1
Type - PredefinedType: STANDARD; Material: REVIGRÉS-URBAN-BASE-30X60-NAT-FOG 8.5 mm
Type - Pset_ElementShading - Roughness: 304.8 mm
Type - Pset_ManufacturerTypeInformation - Manufacturer: REVIGRÉS
Type - Pset_ProductRequirements - Category: Walls
Type - Pset_QuantityTakeOff - Reference: 31202121T1
Type - Pset_ReinforcementBarPitchOfWall - Reference: 31202121T1
Type - Pset_WallCommon - IsExternal: no; Reference: 31202121T1
Type - IFC.REVIGRÉS-Dados do fabricante-Wall Covering - FabricanteURL: https://www.revigres.pt/; ReferenciaModelo: Urban; NumeroGlobalDeItemComercial: 31202121T1; Acabamento: NAT; Material: Grés porcelânico; IdentificadorDoOperadorEconomico: 501840856; UrlFabricanteArtigo: https://www.revigres.pt/colecoes/urban; PaisOrigem: Portugal
Type - IFC.REVIGRÉS-Dados de desempenho-Wall Covering - Rectilinearidade: ± 0.3% máx. ± 1.5 mm; Ortogonalidade: ± 0.3% máx. ± 1.8 mm; PlanaridadeDaSuperficie: ± 0.3% máx. ± 1.8 mm; QualidadeDaSuperficie: Cumpre; AbsorcaoDeAgua: < 0.05%; ModuloDeRuptura: > 45 N/mm²; ResistenciaAFlexao: > 2000 N; ResistenciaAAbrasaoProfunda: < 120 mm³; DilatacaoTermicaLinear: ≤ 8,0x10-6 °C-1; ResistenciaAoChoqueTermico: Resiste; DurabilidadeResistenciaAoGeloDegelo: Resiste; ResistenciaAoEscorregamentoDIN51130: R9; ResistenciaAoEscorregamentoDIN51097: A; ResistenciaAoEscorregamentoENV51097: A; ResistenciaAoEscorregamentoENV12633: Class 1; ResistenciaAoEscorregamentoANSIA1371: ≥0,42; ResistenciaAoDeslizamentoENV12633: Class 1; ResistenciaAsManchas: Class 5; ResistenciaABaixasConcentracoesDeAcidosEAlcalis: Classe LA; ResistenciaAAltasConcentracoesDeAcidosEAlcalis: Classe HA; LibertacaoDeCadmio: 0; LibertacaoDeChumbo: 0
Type - IFC.REVIGRÉS-Dados de especificação-Wall Covering - VariacaoTonalidade: 2; NivelDeTrafego: 5; EPavimento: Sim; ERevestimento: Sim; EExterno: Sim
Type - IFC.REVIGRÉS-Dados geométricos-Wall Covering - AlturaNominal: 8.5 mm; ComprimentoNominal: 30 mm; LarguraNominal: 60 mm
Type - IFC.REVIGRÉS-Dados de sustentabilidade-Wall Covering - PotencialPrivacaoDeAguaConsumoDeAguaPonderado: 4.5; EnergiaTermicaExportada: 0; ItemENovo: Sim; ItemEParcialmenteReciclado: 0.23; ItemEReciclado: Sim; VidaÚtilEsperada: 50; SubstanciasPerigosas: Não; PotencialDeEsgotamentoAbioticoDosRecursosFosseis: 203; PotencialDeEsgotamentoAbioticoDosRecursosNaoFosseisMineraisEMetais: 0.000701; PotencialDeAquecimentoGlobalBiogenico: -0.48; CombustiveisFosseisComPotencialDeAquecimentoGlobal: 13.9; PotencialDeAquecimentoGlobalUsoDoSoloEMudancaDeUsoDoSolo: 0.0246; PotencialDeEutrofizacaoFraccaoDeNutrientesQueAtingemOCompartimentoFinalDeAguaDoce: 0.000189; PotencialDeEutrofizacaoFraccaoDeNutrientesQueAtingemOCompartimentoFinalMarinho: 0.0122; EnergiaRecuperada: 0.00739; ConsumoDeAguaDoce: 0.113; UtilizacaoLiquidaDeAguaDoce: 0.113; ResiduosPerigososEliminados: 0.00221; ResiduosNaoPerigososEliminados: 1.83; MassaTotalDeResiduosRadioactivosEliminados: 0.000394; EnergiaElectricaExportada: 1.55; MateriaisParaRecuperacaoDeEnergia: 0.00739; MateriaisParaReciclagem: 0.0253; UnidadeEPD: 1 m²
Type - IFC.REVIGRÉS-Dados gerais-Wall Covering - Nome: REVIGRÉS-URBAN-BASE-30X60-NAT-URBAN FOG; TipoProduto: Prensado a seco: grupo BIa UGL | Grés porcelânico técnico; NumeroDeRegistoDAP: EPD-REV-20240006-CCC1-EN; ReferenciaDAP: -; UrlDOP: -
Classification: C3010 (Uniformat)
Pset_QuantityTakeOff - sets with these values: 2
Pset_WallCommon - ExtendToStructure: no; LoadBearing: no
IFC.REVIGRÉS-Dados do fabricante-Wall Covering - Type: Basic Wall: REVIGRÉS-URBAN-BASE-30X60-NAT-FOG
IFC.REVIGRÉS-Dados de desempenho-Wall Covering - Type: Basic Wall: REVIGRÉS-URBAN-BASE-30X60-NAT-FOG
IFC.REVIGRÉS-Dados de especificação-Wall Covering - Type: Basic Wall: REVIGRÉS-URBAN-BASE-30X60-NAT-FOG
IFC.REVIGRÉS-Dados geométricos-Wall Covering - Type: Basic Wall: REVIGRÉS-URBAN-BASE-30X60-NAT-FOG
IFC.REVIGRÉS-Dados de sustentabilidade-Wall Covering - Type: Basic Wall: REVIGRÉS-URBAN-BASE-30X60-NAT-FOG

# IfcWallStandardCase: Basic Wall:REVIGRÉS-URBAN-BASE-30X60-NAT-GRIS, Basic Wall:REVIGRÉS-URBAN-BASE-30X60-NAT-GRIS:25937
In: Level 1
Type - PredefinedType: STANDARD; Material: REVIGRÉS-URBAN-BASE-30X60-NAT-GRIS 8.5 mm
Type - Pset_ElementShading - Roughness: 304.8 mm
Type - Pset_ManufacturerTypeInformation - Manufacturer: REVIGRÉS
Type - Pset_ProductRequirements - Category: Walls
Type - Pset_QuantityTakeOff - Reference: 31202122T1
Type - Pset_ReinforcementBarPitchOfWall - Reference: 31202122T1
Type - Pset_WallCommon - IsExternal: no; Reference: 31202122T1
Type - IFC.REVIGRÉS-Dados do fabricante-Wall Covering - FabricanteURL: https://www.revigres.pt/; ReferenciaModelo: Urban; NumeroGlobalDeItemComercial: 31202122T1; Acabamento: NAT; Material: Grés porcelânico; IdentificadorDoOperadorEconomico: 501840856; UrlFabricanteArtigo: https://www.revigres.pt/colecoes/urban; PaisOrigem: Portugal
Type - IFC.REVIGRÉS-Dados de desempenho-Wall Covering - Rectilinearidade: ± 0.3% máx. ± 1.5 mm; Ortogonalidade: ± 0.3% máx. ± 1.8 mm; PlanaridadeDaSuperficie: ± 0.3% máx. ± 1.8 mm; QualidadeDaSuperficie: Cumpre; AbsorcaoDeAgua: < 0.05%; ModuloDeRuptura: > 45 N/mm²; ResistenciaAFlexao: > 2000 N; ResistenciaAAbrasaoProfunda: < 120 mm³; DilatacaoTermicaLinear: ≤ 8,0x10-6 °C-1; ResistenciaAoChoqueTermico: Resiste; DurabilidadeResistenciaAoGeloDegelo: Resiste; ResistenciaAoEscorregamentoDIN51130: R9; ResistenciaAoEscorregamentoDIN51097: A; ResistenciaAoEscorregamentoENV51097: A; ResistenciaAoEscorregamentoENV12633: Class 1; ResistenciaAoEscorregamentoANSIA1371: ≥0,42; ResistenciaAoDeslizamentoENV12633: Class 1; ResistenciaAsManchas: Class 5; ResistenciaABaixasConcentracoesDeAcidosEAlcalis: Classe LA; ResistenciaAAltasConcentracoesDeAcidosEAlcalis: Classe HA; LibertacaoDeCadmio: 0; LibertacaoDeChumbo: 0
Type - IFC.REVIGRÉS-Dados de especificação-Wall Covering - VariacaoTonalidade: 2; NivelDeTrafego: 5; EPavimento: Sim; ERevestimento: Sim; EExterno: Sim
Type - IFC.REVIGRÉS-Dados geométricos-Wall Covering - AlturaNominal: 8.5 mm; ComprimentoNominal: 30 mm; LarguraNominal: 60 mm
Type - IFC.REVIGRÉS-Dados de sustentabilidade-Wall Covering - PotencialPrivacaoDeAguaConsumoDeAguaPonderado: 4.5; EnergiaTermicaExportada: 0; ItemENovo: Sim; ItemEParcialmenteReciclado: 0.23; ItemEReciclado: Sim; VidaÚtilEsperada: 50; SubstanciasPerigosas: Não; PotencialDeEsgotamentoAbioticoDosRecursosFosseis: 203; PotencialDeEsgotamentoAbioticoDosRecursosNaoFosseisMineraisEMetais: 0.000701; PotencialDeAquecimentoGlobalBiogenico: -0.48; CombustiveisFosseisComPotencialDeAquecimentoGlobal: 13.9; PotencialDeAquecimentoGlobalUsoDoSoloEMudancaDeUsoDoSolo: 0.0246; PotencialDeEutrofizacaoFraccaoDeNutrientesQueAtingemOCompartimentoFinalDeAguaDoce: 0.000189; PotencialDeEutrofizacaoFraccaoDeNutrientesQueAtingemOCompartimentoFinalMarinho: 0.0122; EnergiaRecuperada: 0.00739; ConsumoDeAguaDoce: 0.113; UtilizacaoLiquidaDeAguaDoce: 0.113; ResiduosPerigososEliminados: 0.00221; ResiduosNaoPerigososEliminados: 1.83; MassaTotalDeResiduosRadioactivosEliminados: 0.000394; EnergiaElectricaExportada: 1.55; MateriaisParaRecuperacaoDeEnergia: 0.00739; MateriaisParaReciclagem: 0.0253; UnidadeEPD: 1 m²
Type - IFC.REVIGRÉS-Dados gerais-Wall Covering - Nome: REVIGRÉS-URBAN-BASE-30X60-NAT-URBAN GRIS; TipoProduto: Prensado a seco: grupo BIa UGL | Grés porcelânico técnico; NumeroDeRegistoDAP: EPD-REV-20240006-CCC1-EN; ReferenciaDAP: -; UrlDOP: -
Classification: C3010 (Uniformat)
Pset_QuantityTakeOff - sets with these values: 2
Pset_WallCommon - ExtendToStructure: no; LoadBearing: no
IFC.REVIGRÉS-Dados do fabricante-Wall Covering - Type: Basic Wall: REVIGRÉS-URBAN-BASE-30X60-NAT-GRIS
IFC.REVIGRÉS-Dados de desempenho-Wall Covering - Type: Basic Wall: REVIGRÉS-URBAN-BASE-30X60-NAT-GRIS
IFC.REVIGRÉS-Dados de especificação-Wall Covering - Type: Basic Wall: REVIGRÉS-URBAN-BASE-30X60-NAT-GRIS
IFC.REVIGRÉS-Dados geométricos-Wall Covering - Type: Basic Wall: REVIGRÉS-URBAN-BASE-30X60-NAT-GRIS
IFC.REVIGRÉS-Dados de sustentabilidade-Wall Covering - Type: Basic Wall: REVIGRÉS-URBAN-BASE-30X60-NAT-GRIS

# IfcWallStandardCase: Basic Wall:REVIGRÉS-URBAN-BASE-30X60-NAT-OFFWHITE, Basic Wall:REVIGRÉS-URBAN-BASE-30X60-NAT-OFFWHITE:25945
In: Level 1
Type - PredefinedType: STANDARD; Material: REVIGRÉS-URBAN-BASE-30X60-NAT-OFFWHITE 8.5 mm
Type - Pset_ElementShading - Roughness: 304.8 mm
Type - Pset_ManufacturerTypeInformation - Manufacturer: REVIGRÉS
Type - Pset_ProductRequirements - Category: Walls
Type - Pset_QuantityTakeOff - Reference: 31202123T1
Type - Pset_ReinforcementBarPitchOfWall - Reference: 31202123T1
Type - Pset_WallCommon - IsExternal: no; Reference: 31202123T1
Type - IFC.REVIGRÉS-Dados do fabricante-Wall Covering - FabricanteURL: https://www.revigres.pt/; ReferenciaModelo: Urban; NumeroGlobalDeItemComercial: 31202123T1; Acabamento: NAT; Material: Grés porcelânico; IdentificadorDoOperadorEconomico: 501840856; UrlFabricanteArtigo: https://www.revigres.pt/colecoes/urban; PaisOrigem: Portugal
Type - IFC.REVIGRÉS-Dados de desempenho-Wall Covering - Rectilinearidade: ± 0.3% máx. ± 1.5 mm; Ortogonalidade: ± 0.3% máx. ± 1.8 mm; PlanaridadeDaSuperficie: ± 0.3% máx. ± 1.8 mm; QualidadeDaSuperficie: Cumpre; AbsorcaoDeAgua: < 0.05%; ModuloDeRuptura: > 45 N/mm²; ResistenciaAFlexao: > 2000 N; ResistenciaAAbrasaoProfunda: < 120 mm³; DilatacaoTermicaLinear: ≤ 8,0x10-6 °C-1; ResistenciaAoChoqueTermico: Resiste; DurabilidadeResistenciaAoGeloDegelo: Resiste; ResistenciaAoEscorregamentoDIN51130: R9; ResistenciaAoEscorregamentoDIN51097: A; ResistenciaAoEscorregamentoENV51097: A; ResistenciaAoEscorregamentoENV12633: Class 1; ResistenciaAoEscorregamentoANSIA1371: ≥0,42; ResistenciaAoDeslizamentoENV12633: Class 1; ResistenciaAsManchas: Class 5; ResistenciaABaixasConcentracoesDeAcidosEAlcalis: Classe LA; ResistenciaAAltasConcentracoesDeAcidosEAlcalis: Classe HA; LibertacaoDeCadmio: 0; LibertacaoDeChumbo: 0
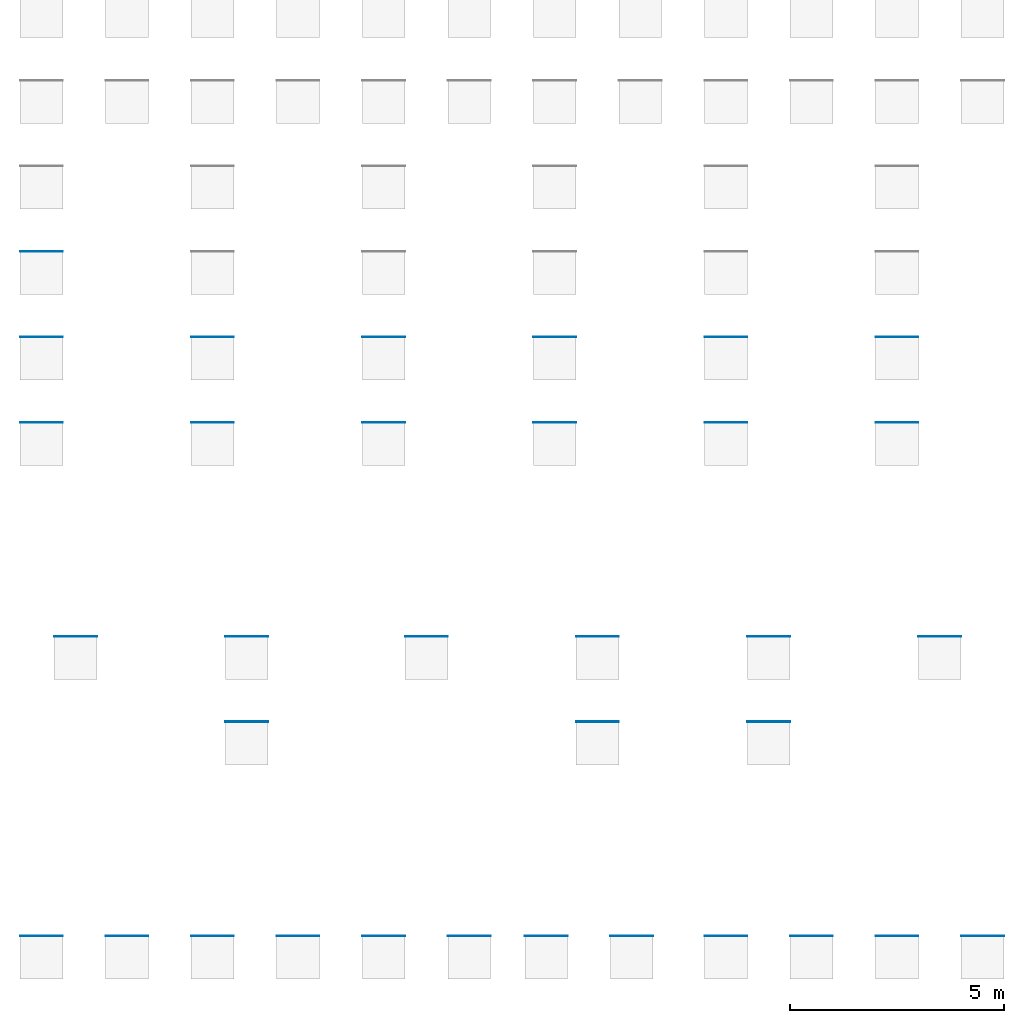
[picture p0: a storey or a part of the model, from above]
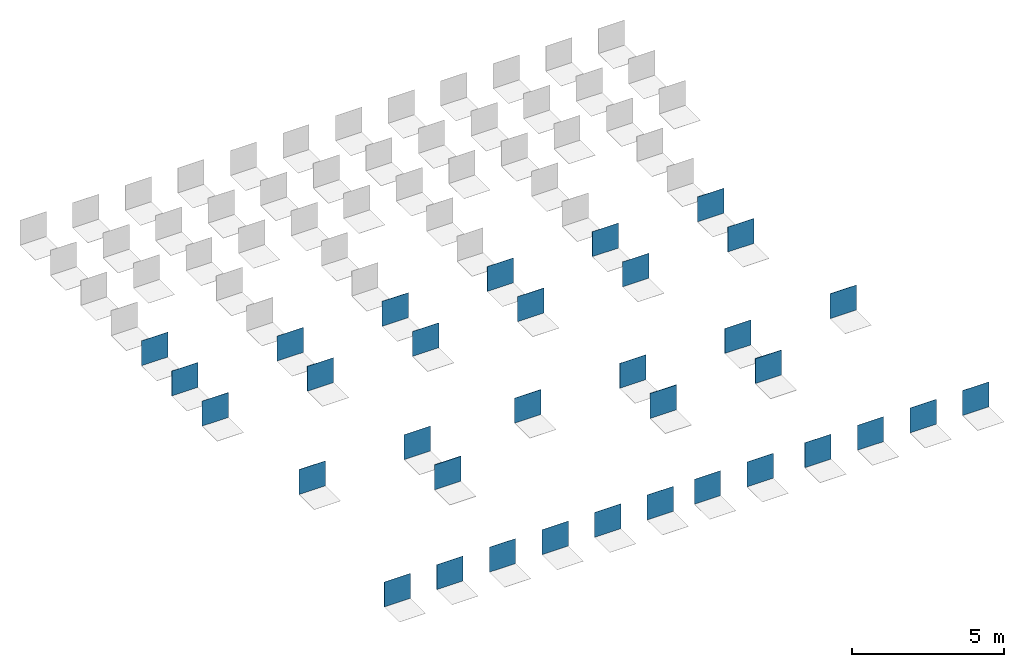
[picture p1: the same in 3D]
Properties of the parts of a building model (IFC2X3), part 8 of 12

# IfcWallStandardCase: Basic Wall:REVIGRÉS-URBAN-BASE-30X60-NAT-OFFWHITE, Basic Wall:REVIGRÉS-URBAN-BASE-30X60-NAT-OFFWHITE:25945
Type - IFC.REVIGRÉS-Dados de especificação-Wall Covering - VariacaoTonalidade: 2; NivelDeTrafego: 5; EPavimento: Sim; ERevestimento: Sim; EExterno: Sim
Type - IFC.REVIGRÉS-Dados geométricos-Wall Covering - AlturaNominal: 8.5 mm; ComprimentoNominal: 30 mm; LarguraNominal: 60 mm
Type - IFC.REVIGRÉS-Dados de sustentabilidade-Wall Covering - PotencialPrivacaoDeAguaConsumoDeAguaPonderado: 4.5; EnergiaTermicaExportada: 0; ItemENovo: Sim; ItemEParcialmenteReciclado: 0.03; ItemEReciclado: Sim; VidaÚtilEsperada: 50; SubstanciasPerigosas: Não; PotencialDeEsgotamentoAbioticoDosRecursosFosseis: 203; PotencialDeEsgotamentoAbioticoDosRecursosNaoFosseisMineraisEMetais: 0.000701; PotencialDeAquecimentoGlobalBiogenico: -0.48; CombustiveisFosseisComPotencialDeAquecimentoGlobal: 13.9; PotencialDeAquecimentoGlobalUsoDoSoloEMudancaDeUsoDoSolo: 0.0246; PotencialDeEutrofizacaoFraccaoDeNutrientesQueAtingemOCompartimentoFinalDeAguaDoce: 0.000189; PotencialDeEutrofizacaoFraccaoDeNutrientesQueAtingemOCompartimentoFinalMarinho: 0.0122; EnergiaRecuperada: 0.00739; ConsumoDeAguaDoce: 0.113; UtilizacaoLiquidaDeAguaDoce: 0.113; ResiduosPerigososEliminados: 0.00221; ResiduosNaoPerigososEliminados: 1.83; MassaTotalDeResiduosRadioactivosEliminados: 0.000394; EnergiaElectricaExportada: 1.55; MateriaisParaRecuperacaoDeEnergia: 0.00739; MateriaisParaReciclagem: 0.0253; UnidadeEPD: 1 m²
Type - IFC.REVIGRÉS-Dados gerais-Wall Covering - Nome: REVIGRÉS-URBAN-BASE-30X60-NAT-URBAN OFFWHITE; TipoProduto: Prensado a seco: grupo BIa UGL | Grés porcelânico técnico; NumeroDeRegistoDAP: EPD-REV-20240006-CCC1-EN; ReferenciaDAP: -; UrlDOP: -
Classification: C3010 (Uniformat)
Pset_QuantityTakeOff - sets with these values: 2
Pset_WallCommon - ExtendToStructure: no; LoadBearing: no
IFC.REVIGRÉS-Dados do fabricante-Wall Covering - Type: Basic Wall: REVIGRÉS-URBAN-BASE-30X60-NAT-OFFWHITE
IFC.REVIGRÉS-Dados de desempenho-Wall Covering - Type: Basic Wall: REVIGRÉS-URBAN-BASE-30X60-NAT-OFFWHITE
IFC.REVIGRÉS-Dados de especificação-Wall Covering - Type: Basic Wall: REVIGRÉS-URBAN-BASE-30X60-NAT-OFFWHITE
IFC.REVIGRÉS-Dados geométricos-Wall Covering - Type: Basic Wall: REVIGRÉS-URBAN-BASE-30X60-NAT-OFFWHITE
IFC.REVIGRÉS-Dados de sustentabilidade-Wall Covering - Type: Basic Wall: REVIGRÉS-URBAN-BASE-30X60-NAT-OFFWHITE

# IfcWallStandardCase: Basic Wall:REVIGRÉS-URBAN-BASE-44,35X44,35-RECT HYDRAULIK ANTRACITE, Basic Wall:REVIGRÉS-URBAN-BASE-44,35X44,35-RECT HYDRAULIK ANTRACITE:26940
In: Level 1
Type - PredefinedType: STANDARD; Material: REVIGRÉS-URBAN-BASE-45X45-RECT-HYDRAULIK ANTRACITE 8.5 mm
Type - Pset_ElementShading - Roughness: 304.8 mm
Type - Pset_ManufacturerTypeInformation - Manufacturer: REVIGRÉS
Type - Pset_ProductRequirements - Category: Walls
Type - Pset_QuantityTakeOff - Reference: 31210752U1
Type - Pset_ReinforcementBarPitchOfWall - Reference: 31210752U1
Type - Pset_WallCommon - IsExternal: no; Reference: 31210752U1
Type - IFC.REVIGRÉS-Dados do fabricante-Wall Covering - FabricanteURL: https://www.revigres.pt/; ReferenciaModelo: Urban; NumeroGlobalDeItemComercial: 31210752U1; Acabamento: RECT; Material: Grés porcelânico; IdentificadorDoOperadorEconomico: 501840856; UrlFabricanteArtigo: https://www.revigres.pt/colecoes/urban; PaisOrigem: Portugal
Type - IFC.REVIGRÉS-Dados de desempenho-Wall Covering - Rectilinearidade: ± 0.2% máx.± 0.8 mm; Ortogonalidade: ± 0.2% máx.± 1.5 mm; PlanaridadeDaSuperficie: ± 0.3% máx. ± 1.8 mm; QualidadeDaSuperficie: Cumpre; AbsorcaoDeAgua: < 0.05%; ModuloDeRuptura: > 45 N/mm²; ResistenciaAFlexao: > 2000 N; ResistenciaAAbrasaoProfunda: < 120 mm³; DilatacaoTermicaLinear: ≤ 8,0x10-6 °C-1; ResistenciaAoChoqueTermico: Resiste; DurabilidadeResistenciaAoGeloDegelo: Resiste; ResistenciaAoEscorregamentoDIN51130: R9; ResistenciaAoEscorregamentoDIN51097: A; ResistenciaAoEscorregamentoENV51097: A; ResistenciaAoEscorregamentoENV12633: Class 1; ResistenciaAoEscorregamentoANSIA1371: ≥0,42; ResistenciaAoDeslizamentoENV12633: Class 1; ResistenciaAsManchas: Class 5; ResistenciaABaixasConcentracoesDeAcidosEAlcalis: Classe LA; ResistenciaAAltasConcentracoesDeAcidosEAlcalis: Classe HA; LibertacaoDeCadmio: 0; LibertacaoDeChumbo: 0
Type - IFC.REVIGRÉS-Dados de especificação-Wall Covering - VariacaoTonalidade: 2; NivelDeTrafego: 5; EPavimento: Sim; ERevestimento: Sim; EExterno: Sim
Type - IFC.REVIGRÉS-Dados geométricos-Wall Covering - AlturaNominal: 8.5 mm; ComprimentoNominal: 4435 mm; LarguraNominal: 4435 mm
Type - IFC.REVIGRÉS-Dados de sustentabilidade-Wall Covering - PotencialPrivacaoDeAguaConsumoDeAguaPonderado: 4.5; EnergiaTermicaExportada: 0; ItemENovo: Sim; ItemEParcialmenteReciclado: 0.29; ItemEReciclado: Sim; VidaÚtilEsperada: 50; SubstanciasPerigosas: Não; PotencialDeEsgotamentoAbioticoDosRecursosFosseis: 203; PotencialDeEsgotamentoAbioticoDosRecursosNaoFosseisMineraisEMetais: 0.000701; PotencialDeAquecimentoGlobalBiogenico: -0.48; CombustiveisFosseisComPotencialDeAquecimentoGlobal: 13.9; PotencialDeAquecimentoGlobalUsoDoSoloEMudancaDeUsoDoSolo: 0.0246; PotencialDeEutrofizacaoFraccaoDeNutrientesQueAtingemOCompartimentoFinalDeAguaDoce: 0.000189; PotencialDeEutrofizacaoFraccaoDeNutrientesQueAtingemOCompartimentoFinalMarinho: 0.0122; EnergiaRecuperada: 0.00739; ConsumoDeAguaDoce: 0.113; UtilizacaoLiquidaDeAguaDoce: 0.113; ResiduosPerigososEliminados: 0.00221; ResiduosNaoPerigososEliminados: 1.83; MassaTotalDeResiduosRadioactivosEliminados: 0.000394; EnergiaElectricaExportada: 1.55; MateriaisParaRecuperacaoDeEnergia: 0.00739; MateriaisParaReciclagem: 0.0253; UnidadeEPD: 1 m²
Type - IFC.REVIGRÉS-Dados gerais-Wall Covering - Nome: REVIGRÉS-URBAN-BASE-44.35X44.35-RECT-HYDRAULIK ANTRACITE; TipoProduto: Prensado a seco: grupo BIa UGL | Grés porcelânico técnico; NumeroDeRegistoDAP: EPD-REV-20240006-CCC1-EN; ReferenciaDAP: -; UrlDOP: -
Classification: C3010 (Uniformat)
Pset_QuantityTakeOff - sets with these values: 2
Pset_WallCommon - ExtendToStructure: no; LoadBearing: no
IFC.REVIGRÉS-Dados do fabricante-Wall Covering - Type: Basic Wall: REVIGRÉS-URBAN-BASE-44,35X44,35-RECT HYDRAULIK ANTRACITE
IFC.REVIGRÉS-Dados de desempenho-Wall Covering - Type: Basic Wall: REVIGRÉS-URBAN-BASE-44,35X44,35-RECT HYDRAULIK ANTRACITE
IFC.REVIGRÉS-Dados de especificação-Wall Covering - Type: Basic Wall: REVIGRÉS-URBAN-BASE-44,35X44,35-RECT HYDRAULIK ANTRACITE
IFC.REVIGRÉS-Dados geométricos-Wall Covering - Type: Basic Wall: REVIGRÉS-URBAN-BASE-44,35X44,35-RECT HYDRAULIK ANTRACITE
IFC.REVIGRÉS-Dados de sustentabilidade-Wall Covering - Type: Basic Wall: REVIGRÉS-URBAN-BASE-44,35X44,35-RECT HYDRAULIK ANTRACITE

# IfcWallStandardCase: Basic Wall:REVIGRÉS-URBAN-BASE-44,35X44,35-RECT HYDRAULIK BONE, Basic Wall:REVIGRÉS-URBAN-BASE-44,35X44,35-RECT HYDRAULIK BONE:26956
In: Level 1
Type - PredefinedType: STANDARD; Material: REVIGRÉS-URBAN-BASE-45X45-RECT-HYDRAULIK BONE 8.5 mm
Type - Pset_ElementShading - Roughness: 304.8 mm
Type - Pset_ManufacturerTypeInformation - Manufacturer: REVIGRÉS
Type - Pset_ProductRequirements - Category: Walls
Type - Pset_QuantityTakeOff - Reference: 31210754T1
Type - Pset_ReinforcementBarPitchOfWall - Reference: 31210754T1
Type - Pset_WallCommon - IsExternal: no; Reference: 31210754T1
Type - IFC.REVIGRÉS-Dados do fabricante-Wall Covering - FabricanteURL: https://www.revigres.pt/; ReferenciaModelo: Urban; NumeroGlobalDeItemComercial: 31210754T1; Acabamento: RECT; Material: Grés porcelânico; IdentificadorDoOperadorEconomico: 501840856; UrlFabricanteArtigo: https://www.revigres.pt/colecoes/urban; PaisOrigem: Portugal
Type - IFC.REVIGRÉS-Dados de desempenho-Wall Covering - Rectilinearidade: ± 0.2% máx.± 0.8 mm; Ortogonalidade: ± 0.2% máx.± 1.5 mm; PlanaridadeDaSuperficie: ± 0.3% máx. ± 1.8 mm; QualidadeDaSuperficie: Cumpre; AbsorcaoDeAgua: < 0.05%; ModuloDeRuptura: > 45 N/mm²; ResistenciaAFlexao: > 2000 N; ResistenciaAAbrasaoProfunda: < 120 mm³; DilatacaoTermicaLinear: ≤ 8,0x10-6 °C-1; ResistenciaAoChoqueTermico: Resiste; DurabilidadeResistenciaAoGeloDegelo: Resiste; ResistenciaAoEscorregamentoDIN51130: R9; ResistenciaAoEscorregamentoDIN51097: A; ResistenciaAoEscorregamentoENV51097: A; ResistenciaAoEscorregamentoENV12633: Class 1; ResistenciaAoEscorregamentoANSIA1371: ≥0,42; ResistenciaAoDeslizamentoENV12633: Class 1; ResistenciaAsManchas: Class 5; ResistenciaABaixasConcentracoesDeAcidosEAlcalis: Classe LA; ResistenciaAAltasConcentracoesDeAcidosEAlcalis: Classe HA; LibertacaoDeCadmio: 0; LibertacaoDeChumbo: 0
Type - IFC.REVIGRÉS-Dados de especificação-Wall Covering - VariacaoTonalidade: 2; NivelDeTrafego: 5; EPavimento: Sim; ERevestimento: Sim; EExterno: Sim
Type - IFC.REVIGRÉS-Dados geométricos-Wall Covering - AlturaNominal: 8.5 mm; ComprimentoNominal: 4435 mm; LarguraNominal: 4435 mm
Type - IFC.REVIGRÉS-Dados de sustentabilidade-Wall Covering - PotencialPrivacaoDeAguaConsumoDeAguaPonderado: 4.5; EnergiaTermicaExportada: 0; ItemENovo: Sim; ItemEParcialmenteReciclado: 0.03; ItemEReciclado: Sim; VidaÚtilEsperada: 50; SubstanciasPerigosas: Não; PotencialDeEsgotamentoAbioticoDosRecursosFosseis: 203; PotencialDeEsgotamentoAbioticoDosRecursosNaoFosseisMineraisEMetais: 0.000701; PotencialDeAquecimentoGlobalBiogenico: -0.48; CombustiveisFosseisComPotencialDeAquecimentoGlobal: 13.9; PotencialDeAquecimentoGlobalUsoDoSoloEMudancaDeUsoDoSolo: 0.0246; PotencialDeEutrofizacaoFraccaoDeNutrientesQueAtingemOCompartimentoFinalDeAguaDoce: 0.000189; PotencialDeEutrofizacaoFraccaoDeNutrientesQueAtingemOCompartimentoFinalMarinho: 0.0122; EnergiaRecuperada: 0.00739; ConsumoDeAguaDoce: 0.113; UtilizacaoLiquidaDeAguaDoce: 0.113; ResiduosPerigososEliminados: 0.00221; ResiduosNaoPerigososEliminados: 1.83; MassaTotalDeResiduosRadioactivosEliminados: 0.000394; EnergiaElectricaExportada: 1.55; MateriaisParaRecuperacaoDeEnergia: 0.00739; MateriaisParaReciclagem: 0.0253; UnidadeEPD: 1 m²
Type - IFC.REVIGRÉS-Dados gerais-Wall Covering - Nome: REVIGRÉS-URBAN-BASE-44.35X44.35-RECT-HYDRAULIK BONE; TipoProduto: Prensado a seco: grupo BIa UGL | Grés porcelânico técnico; NumeroDeRegistoDAP: EPD-REV-20240006-CCC1-EN; ReferenciaDAP: -; UrlDOP: -
Classification: C3010 (Uniformat)
Pset_QuantityTakeOff - sets with these values: 2
Pset_WallCommon - ExtendToStructure: no; LoadBearing: no
IFC.REVIGRÉS-Dados do fabricante-Wall Covering - Type: Basic Wall: REVIGRÉS-URBAN-BASE-44,35X44,35-RECT HYDRAULIK BONE
IFC.REVIGRÉS-Dados de desempenho-Wall Covering - Type: Basic Wall: REVIGRÉS-URBAN-BASE-44,35X44,35-RECT HYDRAULIK BONE
IFC.REVIGRÉS-Dados de especificação-Wall Covering - Type: Basic Wall: REVIGRÉS-URBAN-BASE-44,35X44,35-RECT HYDRAULIK BONE
IFC.REVIGRÉS-Dados geométricos-Wall Covering - Type: Basic Wall: REVIGRÉS-URBAN-BASE-44,35X44,35-RECT HYDRAULIK BONE
IFC.REVIGRÉS-Dados de sustentabilidade-Wall Covering - Type: Basic Wall: REVIGRÉS-URBAN-BASE-44,35X44,35-RECT HYDRAULIK BONE

# IfcWallStandardCase: Basic Wall:REVIGRÉS-URBAN-BASE-44,35X44,35-RECT HYDRAULIK CRAFT, Basic Wall:REVIGRÉS-URBAN-BASE-44,35X44,35-RECT HYDRAULIK CRAFT:26972
In: Level 1
Type - PredefinedType: STANDARD; Material: REVIGRÉS-URBAN-BASE-45X45-RECT-HYDRAULIK CRAFT 8.5 mm
Type - Pset_ElementShading - Roughness: 304.8 mm
Type - Pset_ManufacturerTypeInformation - Manufacturer: REVIGRÉS
Type - Pset_ProductRequirements - Category: Walls
Type - Pset_QuantityTakeOff - Reference: 31210755T1
Type - Pset_ReinforcementBarPitchOfWall - Reference: 31210755T1
Type - Pset_WallCommon - IsExternal: no; Reference: 31210755T1
Type - IFC.REVIGRÉS-Dados do fabricante-Wall Covering - FabricanteURL: https://www.revigres.pt/; ReferenciaModelo: Urban; NumeroGlobalDeItemComercial: 31210755T1; Acabamento: RECT; Material: Grés porcelânico; IdentificadorDoOperadorEconomico: 501840856; UrlFabricanteArtigo: https://www.revigres.pt/colecoes/urban; PaisOrigem: Portugal
Type - IFC.REVIGRÉS-Dados de desempenho-Wall Covering - Rectilinearidade: ± 0.2% máx.± 0.8 mm; Ortogonalidade: ± 0.2% máx.± 1.5 mm; PlanaridadeDaSuperficie: ± 0.3% máx. ± 1.8 mm; QualidadeDaSuperficie: Cumpre; AbsorcaoDeAgua: < 0.05%; ModuloDeRuptura: > 45 N/mm²; ResistenciaAFlexao: > 2000 N; ResistenciaAAbrasaoProfunda: < 120 mm³; DilatacaoTermicaLinear: ≤ 8,0x10-6 °C-1; ResistenciaAoChoqueTermico: Resiste; DurabilidadeResistenciaAoGeloDegelo: Resiste; ResistenciaAoEscorregamentoDIN51130: R9; ResistenciaAoEscorregamentoDIN51097: A; ResistenciaAoEscorregamentoENV51097: A; ResistenciaAoEscorregamentoENV12633: Class 1; ResistenciaAoEscorregamentoANSIA1371: ≥0,42; ResistenciaAoDeslizamentoENV12633: Class 1; ResistenciaAsManchas: Class 5; ResistenciaABaixasConcentracoesDeAcidosEAlcalis: Classe LA; ResistenciaAAltasConcentracoesDeAcidosEAlcalis: Classe HA; LibertacaoDeCadmio: 0; LibertacaoDeChumbo: 0
Type - IFC.REVIGRÉS-Dados de especificação-Wall Covering - VariacaoTonalidade: 2; NivelDeTrafego: 5; EPavimento: Sim; ERevestimento: Sim; EExterno: Sim
Type - IFC.REVIGRÉS-Dados geométricos-Wall Covering - AlturaNominal: 8.5 mm; ComprimentoNominal: 4435 mm; LarguraNominal: 4435 mm
Type - IFC.REVIGRÉS-Dados de sustentabilidade-Wall Covering - PotencialPrivacaoDeAguaConsumoDeAguaPonderado: 4.5; EnergiaTermicaExportada: 0; ItemENovo: Sim; ItemEParcialmenteReciclado: 0.19; ItemEReciclado: Sim; VidaÚtilEsperada: 50; SubstanciasPerigosas: Não; PotencialDeEsgotamentoAbioticoDosRecursosFosseis: 203; PotencialDeEsgotamentoAbioticoDosRecursosNaoFosseisMineraisEMetais: 0.000701; PotencialDeAquecimentoGlobalBiogenico: -0.48; CombustiveisFosseisComPotencialDeAquecimentoGlobal: 13.9; PotencialDeAquecimentoGlobalUsoDoSoloEMudancaDeUsoDoSolo: 0.0246; PotencialDeEutrofizacaoFraccaoDeNutrientesQueAtingemOCompartimentoFinalDeAguaDoce: 0.000189; PotencialDeEutrofizacaoFraccaoDeNutrientesQueAtingemOCompartimentoFinalMarinho: 0.0122; EnergiaRecuperada: 0.00739; ConsumoDeAguaDoce: 0.113; UtilizacaoLiquidaDeAguaDoce: 0.113; ResiduosPerigososEliminados: 0.00221; ResiduosNaoPerigososEliminados: 1.83; MassaTotalDeResiduosRadioactivosEliminados: 0.000394; EnergiaElectricaExportada: 1.55; MateriaisParaRecuperacaoDeEnergia: 0.00739; MateriaisParaReciclagem: 0.0253; UnidadeEPD: 1 m²
Type - IFC.REVIGRÉS-Dados gerais-Wall Covering - Nome: REVIGRÉS-URBAN-BASE-44.35X44.35-RECT-HYDRAULIK CRAFT; TipoProduto: Prensado a seco: grupo BIa UGL | Grés porcelânico técnico; NumeroDeRegistoDAP: EPD-REV-20240006-CCC1-EN; ReferenciaDAP: -; UrlDOP: -
Classification: C3010 (Uniformat)
Pset_QuantityTakeOff - sets with these values: 2
Pset_WallCommon - ExtendToStructure: no; LoadBearing: no
IFC.REVIGRÉS-Dados do fabricante-Wall Covering - Type: Basic Wall: REVIGRÉS-URBAN-BASE-44,35X44,35-RECT HYDRAULIK CRAFT
IFC.REVIGRÉS-Dados de desempenho-Wall Covering - Type: Basic Wall: REVIGRÉS-URBAN-BASE-44,35X44,35-RECT HYDRAULIK CRAFT
IFC.REVIGRÉS-Dados de especificação-Wall Covering - Type: Basic Wall: REVIGRÉS-URBAN-BASE-44,35X44,35-RECT HYDRAULIK CRAFT
IFC.REVIGRÉS-Dados geométricos-Wall Covering - Type: Basic Wall: REVIGRÉS-URBAN-BASE-44,35X44,35-RECT HYDRAULIK CRAFT
IFC.REVIGRÉS-Dados de sustentabilidade-Wall Covering - Type: Basic Wall: REVIGRÉS-URBAN-BASE-44,35X44,35-RECT HYDRAULIK CRAFT

# IfcWallStandardCase: Basic Wall:REVIGRÉS-URBAN-BASE-44,35X44,35-RECT HYDRAULIK FOG, Basic Wall:REVIGRÉS-URBAN-BASE-44,35X44,35-RECT HYDRAULIK FOG:27366
In: Level 1
Type - PredefinedType: STANDARD; Material: REVIGRÉS-URBAN-BASE-45X45-RECT-HYDRAULIK FOG 8.5 mm
Type - Pset_ElementShading - Roughness: 304.8 mm
Type - Pset_ManufacturerTypeInformation - Manufacturer: REVIGRÉS
Type - Pset_ProductRequirements - Category: Walls
Type - Pset_QuantityTakeOff - Reference: 31210756T1
Type - Pset_ReinforcementBarPitchOfWall - Reference: 31210756T1
Type - Pset_WallCommon - IsExternal: no; Reference: 31210756T1
Type - IFC.REVIGRÉS-Dados do fabricante-Wall Covering - FabricanteURL: https://www.revigres.pt/; ReferenciaModelo: Urban; NumeroGlobalDeItemComercial: 31210756T1; Acabamento: RECT; Material: Grés porcelânico; IdentificadorDoOperadorEconomico: 501840856; UrlFabricanteArtigo: https://www.revigres.pt/colecoes/urban; PaisOrigem: Portugal
Type - IFC.REVIGRÉS-Dados de desempenho-Wall Covering - Rectilinearidade: ± 0.2% máx.± 0.8 mm; Ortogonalidade: ± 0.2% máx.± 1.5 mm; PlanaridadeDaSuperficie: ± 0.3% máx. ± 1.8 mm; QualidadeDaSuperficie: Cumpre; AbsorcaoDeAgua: < 0.05%; ModuloDeRuptura: > 45 N/mm²; ResistenciaAFlexao: > 2000 N; ResistenciaAAbrasaoProfunda: < 120 mm³; DilatacaoTermicaLinear: ≤ 8,0x10-6 °C-1; ResistenciaAoChoqueTermico: Resiste; DurabilidadeResistenciaAoGeloDegelo: Resiste; ResistenciaAoEscorregamentoDIN51130: R9; ResistenciaAoEscorregamentoDIN51097: A; ResistenciaAoEscorregamentoENV51097: A; ResistenciaAoEscorregamentoENV12633: Class 1; ResistenciaAoEscorregamentoANSIA1371: ≥0,42; ResistenciaAoDeslizamentoENV12633: Class 1; ResistenciaAsManchas: Class 5; ResistenciaABaixasConcentracoesDeAcidosEAlcalis: Classe LA; ResistenciaAAltasConcentracoesDeAcidosEAlcalis: Classe HA; LibertacaoDeCadmio: 0; LibertacaoDeChumbo: 0
Type - IFC.REVIGRÉS-Dados de especificação-Wall Covering - VariacaoTonalidade: 2; NivelDeTrafego: 5; EPavimento: Sim; ERevestimento: Sim; EExterno: Sim
Type - IFC.REVIGRÉS-Dados geométricos-Wall Covering - AlturaNominal: 8.5 mm; ComprimentoNominal: 4435 mm; LarguraNominal: 4435 mm
Type - IFC.REVIGRÉS-Dados de sustentabilidade-Wall Covering - PotencialPrivacaoDeAguaConsumoDeAguaPonderado: 4.5; EnergiaTermicaExportada: 0; ItemENovo: Sim; ItemEParcialmenteReciclado: 0.23; ItemEReciclado: Sim; VidaÚtilEsperada: 50; SubstanciasPerigosas: Não; PotencialDeEsgotamentoAbioticoDosRecursosFosseis: 203; PotencialDeEsgotamentoAbioticoDosRecursosNaoFosseisMineraisEMetais: 0.000701; PotencialDeAquecimentoGlobalBiogenico: -0.48; CombustiveisFosseisComPotencialDeAquecimentoGlobal: 13.9; PotencialDeAquecimentoGlobalUsoDoSoloEMudancaDeUsoDoSolo: 0.0246; PotencialDeEutrofizacaoFraccaoDeNutrientesQueAtingemOCompartimentoFinalDeAguaDoce: 0.000189; PotencialDeEutrofizacaoFraccaoDeNutrientesQueAtingemOCompartimentoFinalMarinho: 0.0122; EnergiaRecuperada: 0.00739; ConsumoDeAguaDoce: 0.113; UtilizacaoLiquidaDeAguaDoce: 0.113; ResiduosPerigososEliminados: 0.00221; ResiduosNaoPerigososEliminados: 1.83; MassaTotalDeResiduosRadioactivosEliminados: 0.000394; EnergiaElectricaExportada: 1.55; MateriaisParaRecuperacaoDeEnergia: 0.00739; MateriaisParaReciclagem: 0.0253; UnidadeEPD: 1 m²
Type - IFC.REVIGRÉS-Dados gerais-Wall Covering - Nome: REVIGRÉS-URBAN-BASE-44.35X44.35-RECT-HYDRAULIK FOG; TipoProduto: Prensado a seco: grupo BIa UGL | Grés porcelânico técnico; NumeroDeRegistoDAP: EPD-REV-20240006-CCC1-EN; ReferenciaDAP: -; UrlDOP: -
Classification: C3010 (Uniformat)
Pset_QuantityTakeOff - sets with these values: 2
Pset_WallCommon - ExtendToStructure: no; LoadBearing: no
IFC.REVIGRÉS-Dados do fabricante-Wall Covering - Type: Basic Wall: REVIGRÉS-URBAN-BASE-44,35X44,35-RECT HYDRAULIK FOG
IFC.REVIGRÉS-Dados de desempenho-Wall Covering - Type: Basic Wall: REVIGRÉS-URBAN-BASE-44,35X44,35-RECT HYDRAULIK FOG
IFC.REVIGRÉS-Dados de especificação-Wall Covering - Type: Basic Wall: REVIGRÉS-URBAN-BASE-44,35X44,35-RECT HYDRAULIK FOG
IFC.REVIGRÉS-Dados geométricos-Wall Covering - Type: Basic Wall: REVIGRÉS-URBAN-BASE-44,35X44,35-RECT HYDRAULIK FOG
IFC.REVIGRÉS-Dados de sustentabilidade-Wall Covering - Type: Basic Wall: REVIGRÉS-URBAN-BASE-44,35X44,35-RECT HYDRAULIK FOG

# IfcWallStandardCase: Basic Wall:REVIGRÉS-URBAN-BASE-44,35X44,35-RECT HYDRAULIK GRIS, Basic Wall:REVIGRÉS-URBAN-BASE-44,35X44,35-RECT HYDRAULIK GRIS:27382
In: Level 1
Type - PredefinedType: STANDARD; Material: REVIGRÉS-URBAN-BASE-45X45-RECT-HYDRAULIK GRIS 8.5 mm
Type - Pset_ElementShading - Roughness: 304.8 mm
Type - Pset_ManufacturerTypeInformation - Manufacturer: REVIGRÉS
Type - Pset_ProductRequirements - Category: Walls
Type - Pset_QuantityTakeOff - Reference: 31210757T1
Type - Pset_ReinforcementBarPitchOfWall - Reference: 31210757T1
Type - Pset_WallCommon - IsExternal: no; Reference: 31210757T1
Type - IFC.REVIGRÉS-Dados do fabricante-Wall Covering - FabricanteURL: https://www.revigres.pt/; ReferenciaModelo: Urban; NumeroGlobalDeItemComercial: 31210757T1; Acabamento: RECT; Material: Grés porcelânico; IdentificadorDoOperadorEconomico: 501840856; UrlFabricanteArtigo: https://www.revigres.pt/colecoes/urban; PaisOrigem: Portugal
Type - IFC.REVIGRÉS-Dados de desempenho-Wall Covering - Rectilinearidade: ± 0.2% máx.± 0.8 mm; Ortogonalidade: ± 0.2% máx.± 1.5 mm; PlanaridadeDaSuperficie: ± 0.3% máx. ± 1.8 mm; QualidadeDaSuperficie: Cumpre; AbsorcaoDeAgua: < 0.05%; ModuloDeRuptura: > 45 N/mm²; ResistenciaAFlexao: > 2000 N; ResistenciaAAbrasaoProfunda: < 120 mm³; DilatacaoTermicaLinear: ≤ 8,0x10-6 °C-1; ResistenciaAoChoqueTermico: Resiste; DurabilidadeResistenciaAoGeloDegelo: Resiste; ResistenciaAoEscorregamentoDIN51130: R9; ResistenciaAoEscorregamentoDIN51097: A; ResistenciaAoEscorregamentoENV51097: A; ResistenciaAoEscorregamentoENV12633: Class 1; ResistenciaAoEscorregamentoANSIA1371: ≥0,42; ResistenciaAoDeslizamentoENV12633: Class 1; ResistenciaAsManchas: Class 5; ResistenciaABaixasConcentracoesDeAcidosEAlcalis: Classe LA; ResistenciaAAltasConcentracoesDeAcidosEAlcalis: Classe HA; LibertacaoDeCadmio: 0; LibertacaoDeChumbo: 0
Type - IFC.REVIGRÉS-Dados de especificação-Wall Covering - VariacaoTonalidade: 2; NivelDeTrafego: 5; EPavimento: Sim; ERevestimento: Sim; EExterno: Sim
Type - IFC.REVIGRÉS-Dados geométricos-Wall Covering - AlturaNominal: 8.5 mm; ComprimentoNominal: 4435 mm; LarguraNominal: 4435 mm
Type - IFC.REVIGRÉS-Dados de sustentabilidade-Wall Covering - PotencialPrivacaoDeAguaConsumoDeAguaPonderado: 4.5; EnergiaTermicaExportada: 0; ItemENovo: Sim; ItemEParcialmenteReciclado: 0.23; ItemEReciclado: Sim; VidaÚtilEsperada: 50; SubstanciasPerigosas: Não; PotencialDeEsgotamentoAbioticoDosRecursosFosseis: 203; PotencialDeEsgotamentoAbioticoDosRecursosNaoFosseisMineraisEMetais: 0.000701; PotencialDeAquecimentoGlobalBiogenico: -0.48; CombustiveisFosseisComPotencialDeAquecimentoGlobal: 13.9; PotencialDeAquecimentoGlobalUsoDoSoloEMudancaDeUsoDoSolo: 0.0246; PotencialDeEutrofizacaoFraccaoDeNutrientesQueAtingemOCompartimentoFinalDeAguaDoce: 0.000189; PotencialDeEutrofizacaoFraccaoDeNutrientesQueAtingemOCompartimentoFinalMarinho: 0.0122; EnergiaRecuperada: 0.00739; ConsumoDeAguaDoce: 0.113; UtilizacaoLiquidaDeAguaDoce: 0.113; ResiduosPerigososEliminados: 0.00221; ResiduosNaoPerigososEliminados: 1.83; MassaTotalDeResiduosRadioactivosEliminados: 0.000394; EnergiaElectricaExportada: 1.55; MateriaisParaRecuperacaoDeEnergia: 0.00739; MateriaisParaReciclagem: 0.0253; UnidadeEPD: 1 m²
Type - IFC.REVIGRÉS-Dados gerais-Wall Covering - Nome: REVIGRÉS-URBAN-BASE-44.35X44.35-RECT-HYDRAULIK GRIS; TipoProduto: Prensado a seco: grupo BIa UGL | Grés porcelânico técnico; NumeroDeRegistoDAP: EPD-REV-20240006-CCC1-EN; ReferenciaDAP: -; UrlDOP: -
Classification: C3010 (Uniformat)
Pset_QuantityTakeOff - sets with these values: 2
Pset_WallCommon - ExtendToStructure: no; LoadBearing: no
IFC.REVIGRÉS-Dados do fabricante-Wall Covering - Type: Basic Wall: REVIGRÉS-URBAN-BASE-44,35X44,35-RECT HYDRAULIK GRIS
IFC.REVIGRÉS-Dados de desempenho-Wall Covering - Type: Basic Wall: REVIGRÉS-URBAN-BASE-44,35X44,35-RECT HYDRAULIK GRIS
IFC.REVIGRÉS-Dados de especificação-Wall Covering - Type: Basic Wall: REVIGRÉS-URBAN-BASE-44,35X44,35-RECT HYDRAULIK GRIS
IFC.REVIGRÉS-Dados geométricos-Wall Covering - Type: Basic Wall: REVIGRÉS-URBAN-BASE-44,35X44,35-RECT HYDRAULIK GRIS
IFC.REVIGRÉS-Dados de sustentabilidade-Wall Covering - Type: Basic Wall: REVIGRÉS-URBAN-BASE-44,35X44,35-RECT HYDRAULIK GRIS

# IfcWallStandardCase: Basic Wall:REVIGRÉS-URBAN-BASE-44,35X44,35-RECT HYDRAULIK OFFWHITE, Basic Wall:REVIGRÉS-URBAN-BASE-44,35X44,35-RECT HYDRAULIK OFFWHITE:27398
In: Level 1
Type - PredefinedType: STANDARD; Material: REVIGRÉS-URBAN-BASE-45X45-RECT-HYDRAULIK OFFWHITE 8.5 mm
Type - Pset_ElementShading - Roughness: 304.8 mm
Type - Pset_ManufacturerTypeInformation - Manufacturer: REVIGRÉS
Type - Pset_ProductRequirements - Category: Walls
Type - Pset_QuantityTakeOff - Reference: 31210758T1
Type - Pset_ReinforcementBarPitchOfWall - Reference: 31210758T1
Type - Pset_WallCommon - IsExternal: no; Reference: 31210758T1
Type - IFC.REVIGRÉS-Dados do fabricante-Wall Covering - FabricanteURL: https://www.revigres.pt/; ReferenciaModelo: Urban; NumeroGlobalDeItemComercial: 31210758T1; Acabamento: RECT; Material: Grés porcelânico; IdentificadorDoOperadorEconomico: 501840856; UrlFabricanteArtigo: https://www.revigres.pt/colecoes/urban; PaisOrigem: Portugal
Type - IFC.REVIGRÉS-Dados de desempenho-Wall Covering - Rectilinearidade: ± 0.2% máx.± 0.8 mm; Ortogonalidade: ± 0.2% máx.± 1.5 mm; PlanaridadeDaSuperficie: ± 0.3% máx. ± 1.8 mm; QualidadeDaSuperficie: Cumpre; AbsorcaoDeAgua: < 0.05%; ModuloDeRuptura: > 45 N/mm²; ResistenciaAFlexao: > 2000 N; ResistenciaAAbrasaoProfunda: < 120 mm³; DilatacaoTermicaLinear: ≤ 8,0x10-6 °C-1; ResistenciaAoChoqueTermico: Resiste; DurabilidadeResistenciaAoGeloDegelo: Resiste; ResistenciaAoEscorregamentoDIN51130: R9; ResistenciaAoEscorregamentoDIN51097: A; ResistenciaAoEscorregamentoENV51097: A; ResistenciaAoEscorregamentoENV12633: Class 1; ResistenciaAoEscorregamentoANSIA1371: ≥0,42; ResistenciaAoDeslizamentoENV12633: Class 1; ResistenciaAsManchas: Class 5; ResistenciaABaixasConcentracoesDeAcidosEAlcalis: Classe LA; ResistenciaAAltasConcentracoesDeAcidosEAlcalis: Classe HA; LibertacaoDeCadmio: 0; LibertacaoDeChumbo: 0
Type - IFC.REVIGRÉS-Dados de especificação-Wall Covering - VariacaoTonalidade: 2; NivelDeTrafego: 5; EPavimento: Sim; ERevestimento: Sim; EExterno: Sim
Type - IFC.REVIGRÉS-Dados geométricos-Wall Covering - AlturaNominal: 8.5 mm; ComprimentoNominal: 4435 mm; LarguraNominal: 4435 mm
Type - IFC.REVIGRÉS-Dados de sustentabilidade-Wall Covering - PotencialPrivacaoDeAguaConsumoDeAguaPonderado: 4.5; EnergiaTermicaExportada: 0; ItemENovo: Sim; ItemEParcialmenteReciclado: 0.03; ItemEReciclado: Sim; VidaÚtilEsperada: 50; SubstanciasPerigosas: Não; PotencialDeEsgotamentoAbioticoDosRecursosFosseis: 203; PotencialDeEsgotamentoAbioticoDosRecursosNaoFosseisMineraisEMetais: 0.000701; PotencialDeAquecimentoGlobalBiogenico: -0.48; CombustiveisFosseisComPotencialDeAquecimentoGlobal: 13.9; PotencialDeAquecimentoGlobalUsoDoSoloEMudancaDeUsoDoSolo: 0.0246; PotencialDeEutrofizacaoFraccaoDeNutrientesQueAtingemOCompartimentoFinalDeAguaDoce: 0.000189; PotencialDeEutrofizacaoFraccaoDeNutrientesQueAtingemOCompartimentoFinalMarinho: 0.0122; EnergiaRecuperada: 0.00739; ConsumoDeAguaDoce: 0.113; UtilizacaoLiquidaDeAguaDoce: 0.113; ResiduosPerigososEliminados: 0.00221; ResiduosNaoPerigososEliminados: 1.83; MassaTotalDeResiduosRadioactivosEliminados: 0.000394; EnergiaElectricaExportada: 1.55; MateriaisParaRecuperacaoDeEnergia: 0.00739; MateriaisParaReciclagem: 0.0253; UnidadeEPD: 1 m²
Type - IFC.REVIGRÉS-Dados gerais-Wall Covering - Nome: REVIGRÉS-URBAN-BASE-44.35X44.35-RECT-HYDRAULIK OFFWHITE; TipoProduto: Prensado a seco: grupo BIa UGL | Grés porcelânico técnico; NumeroDeRegistoDAP: EPD-REV-20240006-CCC1-EN; ReferenciaDAP: -; UrlDOP: -
Classification: C3010 (Uniformat)
Pset_QuantityTakeOff - sets with these values: 2
Pset_WallCommon - ExtendToStructure: no; LoadBearing: no
IFC.REVIGRÉS-Dados do fabricante-Wall Covering - Type: Basic Wall: REVIGRÉS-URBAN-BASE-44,35X44,35-RECT HYDRAULIK OFFWHITE
IFC.REVIGRÉS-Dados de desempenho-Wall Covering - Type: Basic Wall: REVIGRÉS-URBAN-BASE-44,35X44,35-RECT HYDRAULIK OFFWHITE
IFC.REVIGRÉS-Dados de especificação-Wall Covering - Type: Basic Wall: REVIGRÉS-URBAN-BASE-44,35X44,35-RECT HYDRAULIK OFFWHITE
IFC.REVIGRÉS-Dados geométricos-Wall Covering - Type: Basic Wall: REVIGRÉS-URBAN-BASE-44,35X44,35-RECT HYDRAULIK OFFWHITE
IFC.REVIGRÉS-Dados de sustentabilidade-Wall Covering - Type: Basic Wall: REVIGRÉS-URBAN-BASE-44,35X44,35-RECT HYDRAULIK OFFWHITE

# IfcWallStandardCase: Basic Wall:REVIGRÉS-URBAN-BASE-44,35X44,35-RECT-ANTRACITE, Basic Wall:REVIGRÉS-URBAN-BASE-44,35X44,35-RECT-ANTRACITE:22699
In: Level 1
Type - PredefinedType: STANDARD; Material: REVIGRÉS-URBAN-BASE-45X45-RECT-ANTRACITE 8.5 mm
Type - Pset_ElementShading - Roughness: 304.8 mm
Type - Pset_ManufacturerTypeInformation - Manufacturer: REVIGRÉS
Type - Pset_ProductRequirements - Category: Walls
Type - Pset_QuantityTakeOff - Reference: 31210748U1
Type - Pset_ReinforcementBarPitchOfWall - Reference: 31210748U1
Type - Pset_WallCommon - IsExternal: no; Reference: 31210748U1
Type - IFC.REVIGRÉS-Dados do fabricante-Wall Covering - FabricanteURL: https://www.revigres.pt/; ReferenciaModelo: Urban; NumeroGlobalDeItemComercial: 31210748U1; Acabamento: RECT; Material: Grés porcelânico; IdentificadorDoOperadorEconomico: 501840856; UrlFabricanteArtigo: https://www.revigres.pt/colecoes/urban; PaisOrigem: Portugal
Type - IFC.REVIGRÉS-Dados de desempenho-Wall Covering - Rectilinearidade: ± 0.2% máx.± 0.8 mm; Ortogonalidade: ± 0.2% máx.± 1.5 mm; PlanaridadeDaSuperficie: ± 0.3% máx. ± 1.8 mm; QualidadeDaSuperficie: Cumpre; AbsorcaoDeAgua: < 0.05%; ModuloDeRuptura: > 45 N/mm²; ResistenciaAFlexao: > 2000 N; ResistenciaAAbrasaoProfunda: < 120 mm³; DilatacaoTermicaLinear: ≤ 8,0x10-6 °C-1; ResistenciaAoChoqueTermico: Resiste; DurabilidadeResistenciaAoGeloDegelo: Resiste; ResistenciaAoEscorregamentoDIN51130: R9; ResistenciaAoEscorregamentoDIN51097: A; ResistenciaAoEscorregamentoENV51097: A; ResistenciaAoEscorregamentoENV12633: Class 1; ResistenciaAoEscorregamentoANSIA1371: ≥0,42; ResistenciaAoDeslizamentoENV12633: Class 1; ResistenciaAsManchas: Class 5; ResistenciaABaixasConcentracoesDeAcidosEAlcalis: Classe LA; ResistenciaAAltasConcentracoesDeAcidosEAlcalis: Classe HA; LibertacaoDeCadmio: 0; LibertacaoDeChumbo: 0
Type - IFC.REVIGRÉS-Dados de especificação-Wall Covering - VariacaoTonalidade: 2; NivelDeTrafego: 5; EPavimento: Sim; ERevestimento: Sim; EExterno: Sim
Type - IFC.REVIGRÉS-Dados geométricos-Wall Covering - AlturaNominal: 8.5 mm; ComprimentoNominal: 4435 mm; LarguraNominal: 4435 mm
Type - IFC.REVIGRÉS-Dados de sustentabilidade-Wall Covering - PotencialPrivacaoDeAguaConsumoDeAguaPonderado: 4.5; EnergiaTermicaExportada: 0; ItemENovo: Sim; ItemEParcialmenteReciclado: 0.29; ItemEReciclado: Sim; VidaÚtilEsperada: 50; SubstanciasPerigosas: Não; PotencialDeEsgotamentoAbioticoDosRecursosFosseis: 203; PotencialDeEsgotamentoAbioticoDosRecursosNaoFosseisMineraisEMetais: 0.000701; PotencialDeAquecimentoGlobalBiogenico: -0.48; CombustiveisFosseisComPotencialDeAquecimentoGlobal: 13.9; PotencialDeAquecimentoGlobalUsoDoSoloEMudancaDeUsoDoSolo: 0.0246; PotencialDeEutrofizacaoFraccaoDeNutrientesQueAtingemOCompartimentoFinalDeAguaDoce: 0.000189; PotencialDeEutrofizacaoFraccaoDeNutrientesQueAtingemOCompartimentoFinalMarinho: 0.0122; EnergiaRecuperada: 0.00739; ConsumoDeAguaDoce: 0.113; UtilizacaoLiquidaDeAguaDoce: 0.113; ResiduosPerigososEliminados: 0.00221; ResiduosNaoPerigososEliminados: 1.83; MassaTotalDeResiduosRadioactivosEliminados: 0.000394; EnergiaElectricaExportada: 1.55; MateriaisParaRecuperacaoDeEnergia: 0.00739; MateriaisParaReciclagem: 0.0253; UnidadeEPD: 1 m²
Type - IFC.REVIGRÉS-Dados gerais-Wall Covering - Nome: REVIGRÉS-URBAN-BASE-44.35X44.35-RECT-URBAN ANTRACITE; TipoProduto: Prensado a seco: grupo BIa UGL | Grés porcelânico técnico; NumeroDeRegistoDAP: EPD-REV-20240006-CCC1-EN; ReferenciaDAP: -; UrlDOP: -
Classification: C3010 (Uniformat)
Pset_QuantityTakeOff - sets with these values: 2
Pset_WallCommon - ExtendToStructure: no; LoadBearing: no
IFC.REVIGRÉS-Dados do fabricante-Wall Covering - Type: Basic Wall: REVIGRÉS-URBAN-BASE-44,35X44,35-RECT-ANTRACITE
IFC.REVIGRÉS-Dados de desempenho-Wall Covering - Type: Basic Wall: REVIGRÉS-URBAN-BASE-44,35X44,35-RECT-ANTRACITE
IFC.REVIGRÉS-Dados de especificação-Wall Covering - Type: Basic Wall: REVIGRÉS-URBAN-BASE-44,35X44,35-RECT-ANTRACITE
IFC.REVIGRÉS-Dados geométricos-Wall Covering - Type: Basic Wall: REVIGRÉS-URBAN-BASE-44,35X44,35-RECT-ANTRACITE
IFC.REVIGRÉS-Dados de sustentabilidade-Wall Covering - Type: Basic Wall: REVIGRÉS-URBAN-BASE-44,35X44,35-RECT-ANTRACITE

# IfcWallStandardCase: Basic Wall:REVIGRÉS-URBAN-BASE-44,35X44,35-RECT-BONE, Basic Wall:REVIGRÉS-URBAN-BASE-44,35X44,35-RECT-BONE:22715
In: Level 1
Type - PredefinedType: STANDARD; Material: REVIGRÉS-URBAN-BASE-45X45-RECT-BONE 8.5 mm
Type - Pset_ElementShading - Roughness: 304.8 mm
Type - Pset_ManufacturerTypeInformation - Manufacturer: REVIGRÉS
Type - Pset_ProductRequirements - Category: Walls
Type - Pset_QuantityTakeOff - Reference: 31210720T1
Type - Pset_ReinforcementBarPitchOfWall - Reference: 31210720T1
Type - Pset_WallCommon - IsExternal: no; Reference: 31210720T1
Type - IFC.REVIGRÉS-Dados do fabricante-Wall Covering - FabricanteURL: https://www.revigres.pt/; ReferenciaModelo: Urban; NumeroGlobalDeItemComercial: 31210720T1; Acabamento: RECT; Material: Grés porcelânico; IdentificadorDoOperadorEconomico: 501840856; UrlFabricanteArtigo: https://www.revigres.pt/colecoes/urban; PaisOrigem: Portugal
Type - IFC.REVIGRÉS-Dados de desempenho-Wall Covering - Rectilinearidade: ± 0.2% máx.± 0.8 mm; Ortogonalidade: ± 0.2% máx.± 1.5 mm; PlanaridadeDaSuperficie: ± 0.3% máx. ± 1.8 mm; QualidadeDaSuperficie: Cumpre; AbsorcaoDeAgua: < 0.05%; ModuloDeRuptura: > 45 N/mm²; ResistenciaAFlexao: > 2000 N; ResistenciaAAbrasaoProfunda: < 120 mm³; DilatacaoTermicaLinear: ≤ 8,0x10-6 °C-1; ResistenciaAoChoqueTermico: Resiste; DurabilidadeResistenciaAoGeloDegelo: Resiste; ResistenciaAoEscorregamentoDIN51130: R9; ResistenciaAoEscorregamentoDIN51097: A; ResistenciaAoEscorregamentoENV51097: A; ResistenciaAoEscorregamentoENV12633: Class 1; ResistenciaAoEscorregamentoANSIA1371: ≥0,42; ResistenciaAoDeslizamentoENV12633: Class 1; ResistenciaAsManchas: Class 5; ResistenciaABaixasConcentracoesDeAcidosEAlcalis: Classe LA; ResistenciaAAltasConcentracoesDeAcidosEAlcalis: Classe HA; LibertacaoDeCadmio: 0; LibertacaoDeChumbo: 0
Type - IFC.REVIGRÉS-Dados de especificação-Wall Covering - VariacaoTonalidade: 2; NivelDeTrafego: 5; EPavimento: Sim; ERevestimento: Sim; EExterno: Sim
Type - IFC.REVIGRÉS-Dados geométricos-Wall Covering - AlturaNominal: 8.5 mm; ComprimentoNominal: 4435 mm; LarguraNominal: 4435 mm
Type - IFC.REVIGRÉS-Dados de sustentabilidade-Wall Covering - PotencialPrivacaoDeAguaConsumoDeAguaPonderado: 4.5; EnergiaTermicaExportada: 0; ItemENovo: Sim; ItemEParcialmenteReciclado: 0.03; ItemEReciclado: Sim; VidaÚtilEsperada: 50; SubstanciasPerigosas: Não; PotencialDeEsgotamentoAbioticoDosRecursosFosseis: 203; PotencialDeEsgotamentoAbioticoDosRecursosNaoFosseisMineraisEMetais: 0.000701; PotencialDeAquecimentoGlobalBiogenico: -0.48; CombustiveisFosseisComPotencialDeAquecimentoGlobal: 13.9; PotencialDeAquecimentoGlobalUsoDoSoloEMudancaDeUsoDoSolo: 0.0246; PotencialDeEutrofizacaoFraccaoDeNutrientesQueAtingemOCompartimentoFinalDeAguaDoce: 0.000189; PotencialDeEutrofizacaoFraccaoDeNutrientesQueAtingemOCompartimentoFinalMarinho: 0.0122; EnergiaRecuperada: 0.00739; ConsumoDeAguaDoce: 0.113; UtilizacaoLiquidaDeAguaDoce: 0.113; ResiduosPerigososEliminados: 0.00221; ResiduosNaoPerigososEliminados: 1.83; MassaTotalDeResiduosRadioactivosEliminados: 0.000394; EnergiaElectricaExportada: 1.55; MateriaisParaRecuperacaoDeEnergia: 0.00739; MateriaisParaReciclagem: 0.0253; UnidadeEPD: 1 m²
Type - IFC.REVIGRÉS-Dados gerais-Wall Covering - Nome: REVIGRÉS-URBAN-BASE-44.35X44.35-RECT-URBAN BONE; TipoProduto: Prensado a seco: grupo BIa UGL | Grés porcelânico técnico; NumeroDeRegistoDAP: EPD-REV-20240006-CCC1-EN; ReferenciaDAP: -; UrlDOP: -
Classification: C3010 (Uniformat)
Pset_QuantityTakeOff - sets with these values: 2
Pset_WallCommon - ExtendToStructure: no; LoadBearing: no
IFC.REVIGRÉS-Dados do fabricante-Wall Covering - Type: Basic Wall: REVIGRÉS-URBAN-BASE-44,35X44,35-RECT-BONE
IFC.REVIGRÉS-Dados de desempenho-Wall Covering - Type: Basic Wall: REVIGRÉS-URBAN-BASE-44,35X44,35-RECT-BONE
IFC.REVIGRÉS-Dados de especificação-Wall Covering - Type: Basic Wall: REVIGRÉS-URBAN-BASE-44,35X44,35-RECT-BONE
IFC.REVIGRÉS-Dados geométricos-Wall Covering - Type: Basic Wall: REVIGRÉS-URBAN-BASE-44,35X44,35-RECT-BONE
IFC.REVIGRÉS-Dados de sustentabilidade-Wall Covering - Type: Basic Wall: REVIGRÉS-URBAN-BASE-44,35X44,35-RECT-BONE

# IfcWallStandardCase: Basic Wall:REVIGRÉS-URBAN-BASE-44,35X44,35-RECT-CRAFT, Basic Wall:REVIGRÉS-URBAN-BASE-44,35X44,35-RECT-CRAFT:22731
In: Level 1
Type - PredefinedType: STANDARD; Material: REVIGRÉS-URBAN-BASE-45X45-RECT-CRAFT 8.5 mm
Type - Pset_ElementShading - Roughness: 304.8 mm
Type - Pset_ManufacturerTypeInformation - Manufacturer: REVIGRÉS
Type - Pset_ProductRequirements - Category: Walls
Type - Pset_QuantityTakeOff - Reference: 31210724T1
Type - Pset_ReinforcementBarPitchOfWall - Reference: 31210724T1
Type - Pset_WallCommon - IsExternal: no; Reference: 31210724T1
Type - IFC.REVIGRÉS-Dados do fabricante-Wall Covering - FabricanteURL: https://www.revigres.pt/; ReferenciaModelo: Urban; NumeroGlobalDeItemComercial: 31210724T1; Acabamento: RECT; Material: Grés porcelânico; IdentificadorDoOperadorEconomico: 501840856; UrlFabricanteArtigo: https://www.revigres.pt/colecoes/urban; PaisOrigem: Portugal
Type - IFC.REVIGRÉS-Dados de desempenho-Wall Covering - Rectilinearidade: ± 0.2% máx.± 0.8 mm; Ortogonalidade: ± 0.2% máx.± 1.5 mm; PlanaridadeDaSuperficie: ± 0.3% máx. ± 1.8 mm; QualidadeDaSuperficie: Cumpre; AbsorcaoDeAgua: < 0.05%; ModuloDeRuptura: > 45 N/mm²; ResistenciaAFlexao: > 2000 N; ResistenciaAAbrasaoProfunda: < 120 mm³; DilatacaoTermicaLinear: ≤ 8,0x10-6 °C-1; ResistenciaAoChoqueTermico: Resiste; DurabilidadeResistenciaAoGeloDegelo: Resiste; ResistenciaAoEscorregamentoDIN51130: R9; ResistenciaAoEscorregamentoDIN51097: A; ResistenciaAoEscorregamentoENV51097: A; ResistenciaAoEscorregamentoENV12633: Class 1; ResistenciaAoEscorregamentoANSIA1371: ≥0,42; ResistenciaAoDeslizamentoENV12633: Class 1; ResistenciaAsManchas: Class 5; ResistenciaABaixasConcentracoesDeAcidosEAlcalis: Classe LA; ResistenciaAAltasConcentracoesDeAcidosEAlcalis: Classe HA; LibertacaoDeCadmio: 0; LibertacaoDeChumbo: 0
Type - IFC.REVIGRÉS-Dados de especificação-Wall Covering - VariacaoTonalidade: 2; NivelDeTrafego: 5; EPavimento: Sim; ERevestimento: Sim; EExterno: Sim
Type - IFC.REVIGRÉS-Dados geométricos-Wall Covering - AlturaNominal: 8.5 mm; ComprimentoNominal: 4435 mm; LarguraNominal: 4435 mm
Type - IFC.REVIGRÉS-Dados de sustentabilidade-Wall Covering - PotencialPrivacaoDeAguaConsumoDeAguaPonderado: 4.5; EnergiaTermicaExportada: 0; ItemENovo: Sim; ItemEParcialmenteReciclado: 0.19; ItemEReciclado: Sim; VidaÚtilEsperada: 50; SubstanciasPerigosas: Não; PotencialDeEsgotamentoAbioticoDosRecursosFosseis: 203; PotencialDeEsgotamentoAbioticoDosRecursosNaoFosseisMineraisEMetais: 0.000701; PotencialDeAquecimentoGlobalBiogenico: -0.48; CombustiveisFosseisComPotencialDeAquecimentoGlobal: 13.9; PotencialDeAquecimentoGlobalUsoDoSoloEMudancaDeUsoDoSolo: 0.0246; PotencialDeEutrofizacaoFraccaoDeNutrientesQueAtingemOCompartimentoFinalDeAguaDoce: 0.000189; PotencialDeEutrofizacaoFraccaoDeNutrientesQueAtingemOCompartimentoFinalMarinho: 0.0122; EnergiaRecuperada: 0.00739; ConsumoDeAguaDoce: 0.113; UtilizacaoLiquidaDeAguaDoce: 0.113; ResiduosPerigososEliminados: 0.00221; ResiduosNaoPerigososEliminados: 1.83; MassaTotalDeResiduosRadioactivosEliminados: 0.000394; EnergiaElectricaExportada: 1.55; MateriaisParaRecuperacaoDeEnergia: 0.00739; MateriaisParaReciclagem: 0.0253; UnidadeEPD: 1 m²
Type - IFC.REVIGRÉS-Dados gerais-Wall Covering - Nome: REVIGRÉS-URBAN-BASE-44.35X44.35-RECT-URBAN CRAFT; TipoProduto: Prensado a seco: grupo BIa UGL | Grés porcelânico técnico; NumeroDeRegistoDAP: EPD-REV-20240006-CCC1-EN; ReferenciaDAP: -; UrlDOP: -
Classification: C3010 (Uniformat)
Pset_QuantityTakeOff - sets with these values: 2
Pset_WallCommon - ExtendToStructure: no; LoadBearing: no
IFC.REVIGRÉS-Dados do fabricante-Wall Covering - Type: Basic Wall: REVIGRÉS-URBAN-BASE-44,35X44,35-RECT-CRAFT
IFC.REVIGRÉS-Dados de desempenho-Wall Covering - Type: Basic Wall: REVIGRÉS-URBAN-BASE-44,35X44,35-RECT-CRAFT
IFC.REVIGRÉS-Dados de especificação-Wall Covering - Type: Basic Wall: REVIGRÉS-URBAN-BASE-44,35X44,35-RECT-CRAFT
IFC.REVIGRÉS-Dados geométricos-Wall Covering - Type: Basic Wall: REVIGRÉS-URBAN-BASE-44,35X44,35-RECT-CRAFT
IFC.REVIGRÉS-Dados de sustentabilidade-Wall Covering - Type: Basic Wall: REVIGRÉS-URBAN-BASE-44,35X44,35-RECT-CRAFT

# IfcWallStandardCase: Basic Wall:REVIGRÉS-URBAN-BASE-44,35X44,35-RECT-FOG, Basic Wall:REVIGRÉS-URBAN-BASE-44,35X44,35-RECT-FOG:22747
In: Level 1
Type - PredefinedType: STANDARD; Material: REVIGRÉS-URBAN-BASE-45X45-RECT-FOG 8.5 mm
Type - Pset_ElementShading - Roughness: 304.8 mm
Type - Pset_ManufacturerTypeInformation - Manufacturer: REVIGRÉS
Type - Pset_ProductRequirements - Category: Walls
Type - Pset_QuantityTakeOff - Reference: 31210721T1
Type - Pset_ReinforcementBarPitchOfWall - Reference: 31210721T1
Type - Pset_WallCommon - IsExternal: no; Reference: 31210721T1
Type - IFC.REVIGRÉS-Dados do fabricante-Wall Covering - FabricanteURL: https://www.revigres.pt/; ReferenciaModelo: Urban; NumeroGlobalDeItemComercial: 31210721T1; Acabamento: RECT; Material: Grés porcelânico; IdentificadorDoOperadorEconomico: 501840856; UrlFabricanteArtigo: https://www.revigres.pt/colecoes/urban; PaisOrigem: Portugal
Type - IFC.REVIGRÉS-Dados de desempenho-Wall Covering - Rectilinearidade: ± 0.2% máx.± 0.8 mm; Ortogonalidade: ± 0.2% máx.± 1.5 mm; PlanaridadeDaSuperficie: ± 0.3% máx. ± 1.8 mm; QualidadeDaSuperficie: Cumpre; AbsorcaoDeAgua: < 0.05%; ModuloDeRuptura: > 45 N/mm²; ResistenciaAFlexao: > 2000 N; ResistenciaAAbrasaoProfunda: < 120 mm³; DilatacaoTermicaLinear: ≤ 8,0x10-6 °C-1; ResistenciaAoChoqueTermico: Resiste; DurabilidadeResistenciaAoGeloDegelo: Resiste; ResistenciaAoEscorregamentoDIN51130: R9; ResistenciaAoEscorregamentoDIN51097: A; ResistenciaAoEscorregamentoENV51097: A; ResistenciaAoEscorregamentoENV12633: Class 1; ResistenciaAoEscorregamentoANSIA1371: ≥0,42; ResistenciaAoDeslizamentoENV12633: Class 1; ResistenciaAsManchas: Class 5; ResistenciaABaixasConcentracoesDeAcidosEAlcalis: Classe LA; ResistenciaAAltasConcentracoesDeAcidosEAlcalis: Classe HA; LibertacaoDeCadmio: 0; LibertacaoDeChumbo: 0
Type - IFC.REVIGRÉS-Dados de especificação-Wall Covering - VariacaoTonalidade: 2; NivelDeTrafego: 5; EPavimento: Sim; ERevestimento: Sim; EExterno: Sim
Type - IFC.REVIGRÉS-Dados geométricos-Wall Covering - AlturaNominal: 8.5 mm; ComprimentoNominal: 4435 mm; LarguraNominal: 4435 mm
Type - IFC.REVIGRÉS-Dados de sustentabilidade-Wall Covering - PotencialPrivacaoDeAguaConsumoDeAguaPonderado: 4.5; EnergiaTermicaExportada: 0; ItemENovo: Sim; ItemEParcialmenteReciclado: 0.23; ItemEReciclado: Sim; VidaÚtilEsperada: 50; SubstanciasPerigosas: Não; PotencialDeEsgotamentoAbioticoDosRecursosFosseis: 203; PotencialDeEsgotamentoAbioticoDosRecursosNaoFosseisMineraisEMetais: 0.000701; PotencialDeAquecimentoGlobalBiogenico: -0.48; CombustiveisFosseisComPotencialDeAquecimentoGlobal: 13.9; PotencialDeAquecimentoGlobalUsoDoSoloEMudancaDeUsoDoSolo: 0.0246; PotencialDeEutrofizacaoFraccaoDeNutrientesQueAtingemOCompartimentoFinalDeAguaDoce: 0.000189; PotencialDeEutrofizacaoFraccaoDeNutrientesQueAtingemOCompartimentoFinalMarinho: 0.0122; EnergiaRecuperada: 0.00739; ConsumoDeAguaDoce: 0.113; UtilizacaoLiquidaDeAguaDoce: 0.113; ResiduosPerigososEliminados: 0.00221; ResiduosNaoPerigososEliminados: 1.83; MassaTotalDeResiduosRadioactivosEliminados: 0.000394; EnergiaElectricaExportada: 1.55; MateriaisParaRecuperacaoDeEnergia: 0.00739; MateriaisParaReciclagem: 0.0253; UnidadeEPD: 1 m²
Type - IFC.REVIGRÉS-Dados gerais-Wall Covering - Nome: REVIGRÉS-URBAN-BASE-44.35X44.35-RECT-URBAN FOG; TipoProduto: Prensado a seco: grupo BIa UGL | Grés porcelânico técnico; NumeroDeRegistoDAP: EPD-REV-20240006-CCC1-EN; ReferenciaDAP: -; UrlDOP: -
Classification: C3010 (Uniformat)
Pset_QuantityTakeOff - sets with these values: 2
Pset_WallCommon - ExtendToStructure: no; LoadBearing: no
IFC.REVIGRÉS-Dados do fabricante-Wall Covering - Type: Basic Wall: REVIGRÉS-URBAN-BASE-44,35X44,35-RECT-FOG
IFC.REVIGRÉS-Dados de desempenho-Wall Covering - Type: Basic Wall: REVIGRÉS-URBAN-BASE-44,35X44,35-RECT-FOG
IFC.REVIGRÉS-Dados de especificação-Wall Covering - Type: Basic Wall: REVIGRÉS-URBAN-BASE-44,35X44,35-RECT-FOG
IFC.REVIGRÉS-Dados geométricos-Wall Covering - Type: Basic Wall: REVIGRÉS-URBAN-BASE-44,35X44,35-RECT-FOG
IFC.REVIGRÉS-Dados de sustentabilidade-Wall Covering - Type: Basic Wall: REVIGRÉS-URBAN-BASE-44,35X44,35-RECT-FOG

# IfcWallStandardCase: Basic Wall:REVIGRÉS-URBAN-BASE-44,35X44,35-RECT-GRIS, Basic Wall:REVIGRÉS-URBAN-BASE-44,35X44,35-RECT-GRIS:22763
In: Level 1
Type - PredefinedType: STANDARD; Material: REVIGRÉS-URBAN-BASE-45X45-RECT-GRIS 8.5 mm
Type - Pset_ElementShading - Roughness: 304.8 mm
Type - Pset_ManufacturerTypeInformation - Manufacturer: REVIGRÉS
Type - Pset_ProductRequirements - Category: Walls
Type - Pset_QuantityTakeOff - Reference: 31210722T1
Type - Pset_ReinforcementBarPitchOfWall - Reference: 31210722T1
Type - Pset_WallCommon - IsExternal: no; Reference: 31210722T1
Type - IFC.REVIGRÉS-Dados do fabricante-Wall Covering - FabricanteURL: https://www.revigres.pt/; ReferenciaModelo: Urban; NumeroGlobalDeItemComercial: 31210722T1; Acabamento: RECT; Material: Grés porcelânico; IdentificadorDoOperadorEconomico: 501840856; UrlFabricanteArtigo: https://www.revigres.pt/colecoes/urban; PaisOrigem: Portugal
Type - IFC.REVIGRÉS-Dados de desempenho-Wall Covering - Rectilinearidade: ± 0.2% máx.± 0.8 mm; Ortogonalidade: ± 0.2% máx.± 1.5 mm; PlanaridadeDaSuperficie: ± 0.3% máx. ± 1.8 mm; QualidadeDaSuperficie: Cumpre; AbsorcaoDeAgua: < 0.05%; ModuloDeRuptura: > 45 N/mm²; ResistenciaAFlexao: > 2000 N; ResistenciaAAbrasaoProfunda: < 120 mm³; DilatacaoTermicaLinear: ≤ 8,0x10-6 °C-1; ResistenciaAoChoqueTermico: Resiste; DurabilidadeResistenciaAoGeloDegelo: Resiste; ResistenciaAoEscorregamentoDIN51130: R9; ResistenciaAoEscorregamentoDIN51097: A; ResistenciaAoEscorregamentoENV51097: A; ResistenciaAoEscorregamentoENV12633: Class 1; ResistenciaAoEscorregamentoANSIA1371: ≥0,42; ResistenciaAoDeslizamentoENV12633: Class 1; ResistenciaAsManchas: Class 5; ResistenciaABaixasConcentracoesDeAcidosEAlcalis: Classe LA; ResistenciaAAltasConcentracoesDeAcidosEAlcalis: Classe HA; LibertacaoDeCadmio: 0; LibertacaoDeChumbo: 0
Type - IFC.REVIGRÉS-Dados de especificação-Wall Covering - VariacaoTonalidade: 2; NivelDeTrafego: 5; EPavimento: Sim; ERevestimento: Sim; EExterno: Sim
Type - IFC.REVIGRÉS-Dados geométricos-Wall Covering - AlturaNominal: 8.5 mm; ComprimentoNominal: 4435 mm; LarguraNominal: 4435 mm
Type - IFC.REVIGRÉS-Dados de sustentabilidade-Wall Covering - PotencialPrivacaoDeAguaConsumoDeAguaPonderado: 4.5; EnergiaTermicaExportada: 0; ItemENovo: Sim; ItemEParcialmenteReciclado: 0.23; ItemEReciclado: Sim; VidaÚtilEsperada: 50; SubstanciasPerigosas: Não; PotencialDeEsgotamentoAbioticoDosRecursosFosseis: 203; PotencialDeEsgotamentoAbioticoDosRecursosNaoFosseisMineraisEMetais: 0.000701; PotencialDeAquecimentoGlobalBiogenico: -0.48; CombustiveisFosseisComPotencialDeAquecimentoGlobal: 13.9; PotencialDeAquecimentoGlobalUsoDoSoloEMudancaDeUsoDoSolo: 0.0246; PotencialDeEutrofizacaoFraccaoDeNutrientesQueAtingemOCompartimentoFinalDeAguaDoce: 0.000189; PotencialDeEutrofizacaoFraccaoDeNutrientesQueAtingemOCompartimentoFinalMarinho: 0.0122; EnergiaRecuperada: 0.00739; ConsumoDeAguaDoce: 0.113; UtilizacaoLiquidaDeAguaDoce: 0.113; ResiduosPerigososEliminados: 0.00221; ResiduosNaoPerigososEliminados: 1.83; MassaTotalDeResiduosRadioactivosEliminados: 0.000394; EnergiaElectricaExportada: 1.55; MateriaisParaRecuperacaoDeEnergia: 0.00739; MateriaisParaReciclagem: 0.0253; UnidadeEPD: 1 m²
Type - IFC.REVIGRÉS-Dados gerais-Wall Covering - Nome: REVIGRÉS-URBAN-BASE-44.35X44.35-RECT-URBAN GRIS; TipoProduto: Prensado a seco: grupo BIa UGL | Grés porcelânico técnico; NumeroDeRegistoDAP: EPD-REV-20240006-CCC1-EN; ReferenciaDAP: -; UrlDOP: -
Classification: C3010 (Uniformat)
Pset_QuantityTakeOff - sets with these values: 2
Pset_WallCommon - ExtendToStructure: no; LoadBearing: no
IFC.REVIGRÉS-Dados do fabricante-Wall Covering - Type: Basic Wall: REVIGRÉS-URBAN-BASE-44,35X44,35-RECT-GRIS
IFC.REVIGRÉS-Dados de desempenho-Wall Covering - Type: Basic Wall: REVIGRÉS-URBAN-BASE-44,35X44,35-RECT-GRIS
IFC.REVIGRÉS-Dados de especificação-Wall Covering - Type: Basic Wall: REVIGRÉS-URBAN-BASE-44,35X44,35-RECT-GRIS
IFC.REVIGRÉS-Dados geométricos-Wall Covering - Type: Basic Wall: REVIGRÉS-URBAN-BASE-44,35X44,35-RECT-GRIS
IFC.REVIGRÉS-Dados de sustentabilidade-Wall Covering - Type: Basic Wall: REVIGRÉS-URBAN-BASE-44,35X44,35-RECT-GRIS

# IfcWallStandardCase: Basic Wall:REVIGRÉS-URBAN-BASE-44,35X44,35-RECT-OFFWHITE, Basic Wall:REVIGRÉS-URBAN-BASE-44,35X44,35-RECT-OFFWHITE:22779
In: Level 1
Type - PredefinedType: STANDARD; Material: REVIGRÉS-URBAN-BASE-45X45-RECT-OFFWHITE 8.5 mm
Type - Pset_ElementShading - Roughness: 304.8 mm
Type - Pset_ManufacturerTypeInformation - Manufacturer: REVIGRÉS
Type - Pset_ProductRequirements - Category: Walls
Type - Pset_QuantityTakeOff - Reference: 31210723T1
Type - Pset_ReinforcementBarPitchOfWall - Reference: 31210723T1
Type - Pset_WallCommon - IsExternal: no; Reference: 31210723T1
Type - IFC.REVIGRÉS-Dados do fabricante-Wall Covering - FabricanteURL: https://www.revigres.pt/; ReferenciaModelo: Urban; NumeroGlobalDeItemComercial: 31210723T1; Acabamento: RECT; Material: Grés porcelânico; IdentificadorDoOperadorEconomico: 501840856; UrlFabricanteArtigo: https://www.revigres.pt/colecoes/urban; PaisOrigem: Portugal
Type - IFC.REVIGRÉS-Dados de desempenho-Wall Covering - Rectilinearidade: ± 0.2% máx.± 0.8 mm; Ortogonalidade: ± 0.2% máx.± 1.5 mm; PlanaridadeDaSuperficie: ± 0.3% máx. ± 1.8 mm; QualidadeDaSuperficie: Cumpre; AbsorcaoDeAgua: < 0.05%; ModuloDeRuptura: > 45 N/mm²; ResistenciaAFlexao: > 2000 N; ResistenciaAAbrasaoProfunda: < 120 mm³; DilatacaoTermicaLinear: ≤ 8,0x10-6 °C-1; ResistenciaAoChoqueTermico: Resiste; DurabilidadeResistenciaAoGeloDegelo: Resiste; ResistenciaAoEscorregamentoDIN51130: R9; ResistenciaAoEscorregamentoDIN51097: A; ResistenciaAoEscorregamentoENV51097: A; ResistenciaAoEscorregamentoENV12633: Class 1; ResistenciaAoEscorregamentoANSIA1371: ≥0,42; ResistenciaAoDeslizamentoENV12633: Class 1; ResistenciaAsManchas: Class 5; ResistenciaABaixasConcentracoesDeAcidosEAlcalis: Classe LA; ResistenciaAAltasConcentracoesDeAcidosEAlcalis: Classe HA; LibertacaoDeCadmio: 0; LibertacaoDeChumbo: 0
Type - IFC.REVIGRÉS-Dados de especificação-Wall Covering - VariacaoTonalidade: 2; NivelDeTrafego: 5; EPavimento: Sim; ERevestimento: Sim; EExterno: Sim
Type - IFC.REVIGRÉS-Dados geométricos-Wall Covering - AlturaNominal: 8.5 mm; ComprimentoNominal: 4435 mm; LarguraNominal: 4435 mm
Type - IFC.REVIGRÉS-Dados de sustentabilidade-Wall Covering - PotencialPrivacaoDeAguaConsumoDeAguaPonderado: 4.5; EnergiaTermicaExportada: 0; ItemENovo: Sim; ItemEParcialmenteReciclado: 0.03; ItemEReciclado: Sim; VidaÚtilEsperada: 50; SubstanciasPerigosas: Não; PotencialDeEsgotamentoAbioticoDosRecursosFosseis: 203; PotencialDeEsgotamentoAbioticoDosRecursosNaoFosseisMineraisEMetais: 0.000701; PotencialDeAquecimentoGlobalBiogenico: -0.48; CombustiveisFosseisComPotencialDeAquecimentoGlobal: 13.9; PotencialDeAquecimentoGlobalUsoDoSoloEMudancaDeUsoDoSolo: 0.0246; PotencialDeEutrofizacaoFraccaoDeNutrientesQueAtingemOCompartimentoFinalDeAguaDoce: 0.000189; PotencialDeEutrofizacaoFraccaoDeNutrientesQueAtingemOCompartimentoFinalMarinho: 0.0122; EnergiaRecuperada: 0.00739; ConsumoDeAguaDoce: 0.113; UtilizacaoLiquidaDeAguaDoce: 0.113; ResiduosPerigososEliminados: 0.00221; ResiduosNaoPerigososEliminados: 1.83; MassaTotalDeResiduosRadioactivosEliminados: 0.000394; EnergiaElectricaExportada: 1.55; MateriaisParaRecuperacaoDeEnergia: 0.00739; MateriaisParaReciclagem: 0.0253; UnidadeEPD: 1 m²
Type - IFC.REVIGRÉS-Dados gerais-Wall Covering - Nome: REVIGRÉS-URBAN-BASE-44.35X44.35-RECT-URBAN OFFWHITE; TipoProduto: Prensado a seco: grupo BIa UGL | Grés porcelânico técnico; NumeroDeRegistoDAP: EPD-REV-20240006-CCC1-EN; ReferenciaDAP: -; UrlDOP: -
Classification: C3010 (Uniformat)
Pset_QuantityTakeOff - sets with these values: 2
Pset_WallCommon - ExtendToStructure: no; LoadBearing: no
IFC.REVIGRÉS-Dados do fabricante-Wall Covering - Type: Basic Wall: REVIGRÉS-URBAN-BASE-44,35X44,35-RECT-OFFWHITE
IFC.REVIGRÉS-Dados de desempenho-Wall Covering - Type: Basic Wall: REVIGRÉS-URBAN-BASE-44,35X44,35-RECT-OFFWHITE
IFC.REVIGRÉS-Dados de especificação-Wall Covering - Type: Basic Wall: REVIGRÉS-URBAN-BASE-44,35X44,35-RECT-OFFWHITE
IFC.REVIGRÉS-Dados geométricos-Wall Covering - Type: Basic Wall: REVIGRÉS-URBAN-BASE-44,35X44,35-RECT-OFFWHITE
IFC.REVIGRÉS-Dados de sustentabilidade-Wall Covering - Type: Basic Wall: REVIGRÉS-URBAN-BASE-44,35X44,35-RECT-OFFWHITE

# IfcWallStandardCase: Basic Wall:REVIGRÉS-URBAN-BASE-44,35X88,9-RECT-ANTRACITE, Basic Wall:REVIGRÉS-URBAN-BASE-44,35X88,9-RECT-ANTRACITE:22800
In: Level 1
Type - PredefinedType: STANDARD; Material: REVIGRÉS-URBAN-BASE-45X90-RECT-ANTRACITE 10.5 mm
Type - Pset_ElementShading - Roughness: 304.8 mm
Type - Pset_ManufacturerTypeInformation - Manufacturer: REVIGRÉS
Type - Pset_ProductRequirements - Category: Walls
Type - Pset_QuantityTakeOff - Reference: 3121H848U1
Type - Pset_ReinforcementBarPitchOfWall - Reference: 3121H848U1
Type - Pset_WallCommon - IsExternal: no; Reference: 3121H848U1
Type - IFC.REVIGRÉS-Dados do fabricante-Wall Covering - FabricanteURL: https://www.revigres.pt/; ReferenciaModelo: Urban; NumeroGlobalDeItemComercial: 3121H848U1; Acabamento: RECT; Material: Grés porcelânico; IdentificadorDoOperadorEconomico: 501840856; UrlFabricanteArtigo: https://www.revigres.pt/colecoes/urban; PaisOrigem: Portugal
Type - IFC.REVIGRÉS-Dados de desempenho-Wall Covering - Rectilinearidade: ± 0.2% máx.± 0.8 mm; Ortogonalidade: ± 0.2% máx.± 1.5 mm; PlanaridadeDaSuperficie: ± 0.3% máx. ± 1.8 mm; QualidadeDaSuperficie: Cumpre; AbsorcaoDeAgua: < 0.05%; ModuloDeRuptura: > 45 N/mm²; ResistenciaAFlexao: > 3500 N; ResistenciaAAbrasaoProfunda: < 120 mm³; DilatacaoTermicaLinear: ≤ 8,0x10-6 °C-1; ResistenciaAoChoqueTermico: Resiste; DurabilidadeResistenciaAoGeloDegelo: Resiste; ResistenciaAoEscorregamentoDIN51130: R9; ResistenciaAoEscorregamentoDIN51097: A; ResistenciaAoEscorregamentoENV51097: A; ResistenciaAoEscorregamentoENV12633: Class 1; ResistenciaAoEscorregamentoANSIA1371: ≥0,42; ResistenciaAoDeslizamentoENV12633: Class 1; ResistenciaAsManchas: Class 5; ResistenciaABaixasConcentracoesDeAcidosEAlcalis: Classe LA; ResistenciaAAltasConcentracoesDeAcidosEAlcalis: Classe HA; LibertacaoDeCadmio: 0; LibertacaoDeChumbo: 0
Type - IFC.REVIGRÉS-Dados de especificação-Wall Covering - VariacaoTonalidade: 2; NivelDeTrafego: 5; EPavimento: Sim; ERevestimento: Sim; EExterno: Sim
Type - IFC.REVIGRÉS-Dados geométricos-Wall Covering - AlturaNominal: 10.5 mm; ComprimentoNominal: 4435 mm; LarguraNominal: 88.9 mm
Type - IFC.REVIGRÉS-Dados de sustentabilidade-Wall Covering - PotencialPrivacaoDeAguaConsumoDeAguaPonderado: 4.5; EnergiaTermicaExportada: 0; ItemENovo: Sim; ItemEParcialmenteReciclado: 0.29; ItemEReciclado: Sim; VidaÚtilEsperada: 50; SubstanciasPerigosas: Não; PotencialDeEsgotamentoAbioticoDosRecursosFosseis: 203; PotencialDeEsgotamentoAbioticoDosRecursosNaoFosseisMineraisEMetais: 0.000701; PotencialDeAquecimentoGlobalBiogenico: -0.48; CombustiveisFosseisComPotencialDeAquecimentoGlobal: 13.9; PotencialDeAquecimentoGlobalUsoDoSoloEMudancaDeUsoDoSolo: 0.0246; PotencialDeEutrofizacaoFraccaoDeNutrientesQueAtingemOCompartimentoFinalDeAguaDoce: 0.000189; PotencialDeEutrofizacaoFraccaoDeNutrientesQueAtingemOCompartimentoFinalMarinho: 0.0122; EnergiaRecuperada: 0.00739; ConsumoDeAguaDoce: 0.113; UtilizacaoLiquidaDeAguaDoce: 0.113; ResiduosPerigososEliminados: 0.00221; ResiduosNaoPerigososEliminados: 1.83; MassaTotalDeResiduosRadioactivosEliminados: 0.000394; EnergiaElectricaExportada: 1.55; MateriaisParaRecuperacaoDeEnergia: 0.00739; MateriaisParaReciclagem: 0.0253; UnidadeEPD: 1 m²
Type - IFC.REVIGRÉS-Dados gerais-Wall Covering - Nome: REVIGRÉS-URBAN-BASE-44.35X88.9-RECT-URBAN ANTRACITE; TipoProduto: Prensado a seco: grupo BIa UGL | Grés porcelânico técnico; NumeroDeRegistoDAP: EPD-REV-20240006-CCC1-EN; ReferenciaDAP: -; UrlDOP: -
Classification: C3010 (Uniformat)
Pset_QuantityTakeOff - sets with these values: 2
Pset_WallCommon - ExtendToStructure: no; LoadBearing: no
IFC.REVIGRÉS-Dados do fabricante-Wall Covering - Type: Basic Wall: REVIGRÉS-URBAN-BASE-44,35X88,9-RECT-ANTRACITE
IFC.REVIGRÉS-Dados de desempenho-Wall Covering - Type: Basic Wall: REVIGRÉS-URBAN-BASE-44,35X88,9-RECT-ANTRACITE
IFC.REVIGRÉS-Dados de especificação-Wall Covering - Type: Basic Wall: REVIGRÉS-URBAN-BASE-44,35X88,9-RECT-ANTRACITE
IFC.REVIGRÉS-Dados geométricos-Wall Covering - Type: Basic Wall: REVIGRÉS-URBAN-BASE-44,35X88,9-RECT-ANTRACITE
IFC.REVIGRÉS-Dados de sustentabilidade-Wall Covering - Type: Basic Wall: REVIGRÉS-URBAN-BASE-44,35X88,9-RECT-ANTRACITE

# IfcWallStandardCase: Basic Wall:REVIGRÉS-URBAN-BASE-44,35X88,9-RECT-BONE, Basic Wall:REVIGRÉS-URBAN-BASE-44,35X88,9-RECT-BONE:22816
In: Level 1
Type - PredefinedType: STANDARD; Material: REVIGRÉS-URBAN-BASE-45X90-RECT-BONE 10.5 mm
Type - Pset_ElementShading - Roughness: 304.8 mm
Type - Pset_ManufacturerTypeInformation - Manufacturer: REVIGRÉS
Type - Pset_ProductRequirements - Category: Walls
Type - Pset_QuantityTakeOff - Reference: 3121H820T1
Type - Pset_ReinforcementBarPitchOfWall - Reference: 3121H820T1
Type - Pset_WallCommon - IsExternal: no; Reference: 3121H820T1
Type - IFC.REVIGRÉS-Dados do fabricante-Wall Covering - FabricanteURL: https://www.revigres.pt/; ReferenciaModelo: Urban; NumeroGlobalDeItemComercial: 3121H820T1; Acabamento: RECT; Material: Grés porcelânico; IdentificadorDoOperadorEconomico: 501840856; UrlFabricanteArtigo: https://www.revigres.pt/colecoes/urban; PaisOrigem: Portugal
Type - IFC.REVIGRÉS-Dados de desempenho-Wall Covering - Rectilinearidade: ± 0.2% máx.± 0.8 mm; Ortogonalidade: ± 0.2% máx.± 1.5 mm; PlanaridadeDaSuperficie: ± 0.3% máx. ± 1.8 mm; QualidadeDaSuperficie: Cumpre; AbsorcaoDeAgua: < 0.05%; ModuloDeRuptura: > 45 N/mm²; ResistenciaAFlexao: > 3500 N; ResistenciaAAbrasaoProfunda: < 120 mm³; DilatacaoTermicaLinear: ≤ 8,0x10-6 °C-1; ResistenciaAoChoqueTermico: Resiste; DurabilidadeResistenciaAoGeloDegelo: Resiste; ResistenciaAoEscorregamentoDIN51130: R9; ResistenciaAoEscorregamentoDIN51097: A; ResistenciaAoEscorregamentoENV51097: A; ResistenciaAoEscorregamentoENV12633: Class 1; ResistenciaAoEscorregamentoANSIA1371: ≥0,42; ResistenciaAoDeslizamentoENV12633: Class 1; ResistenciaAsManchas: Class 5; ResistenciaABaixasConcentracoesDeAcidosEAlcalis: Classe LA; ResistenciaAAltasConcentracoesDeAcidosEAlcalis: Classe HA; LibertacaoDeCadmio: 0; LibertacaoDeChumbo: 0
Type - IFC.REVIGRÉS-Dados de especificação-Wall Covering - VariacaoTonalidade: 2; NivelDeTrafego: 5; EPavimento: Sim; ERevestimento: Sim; EExterno: Sim
Type - IFC.REVIGRÉS-Dados geométricos-Wall Covering - AlturaNominal: 10.5 mm; ComprimentoNominal: 4435 mm; LarguraNominal: 88.9 mm
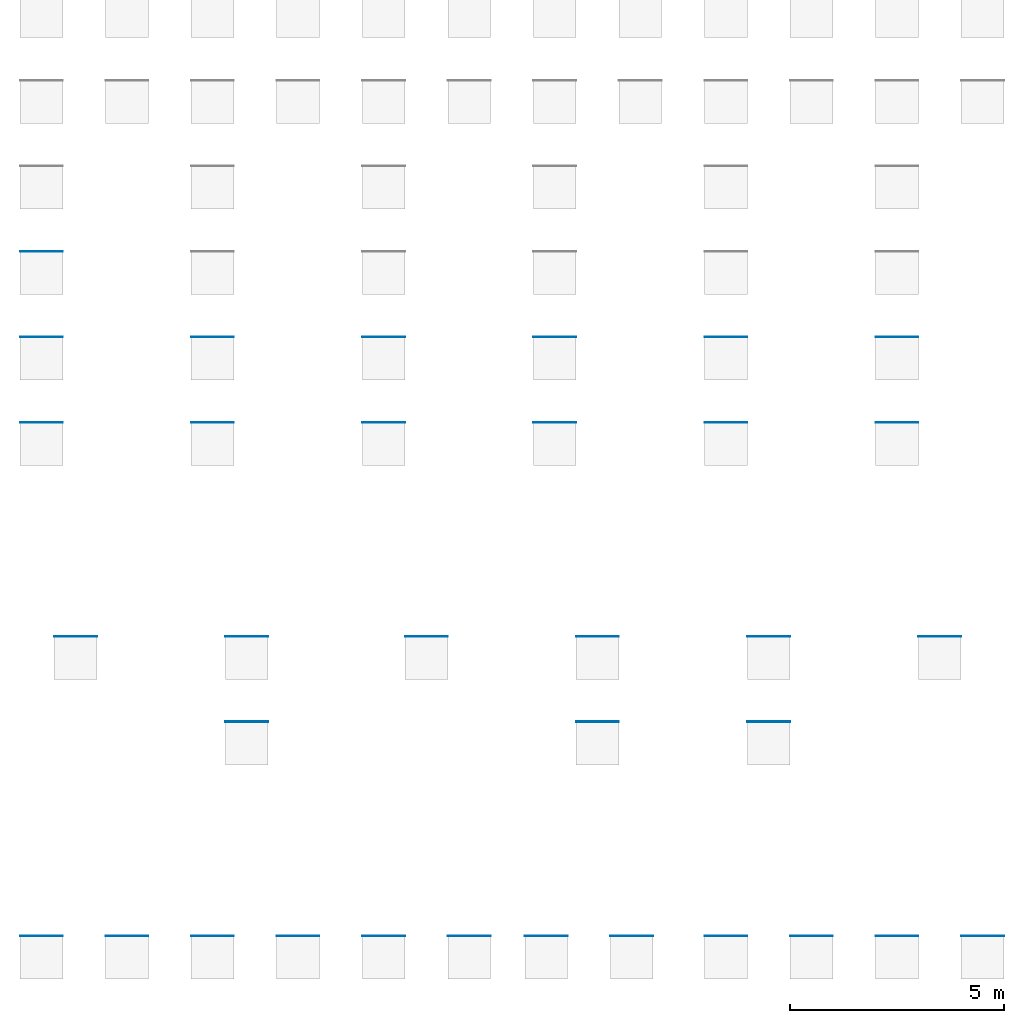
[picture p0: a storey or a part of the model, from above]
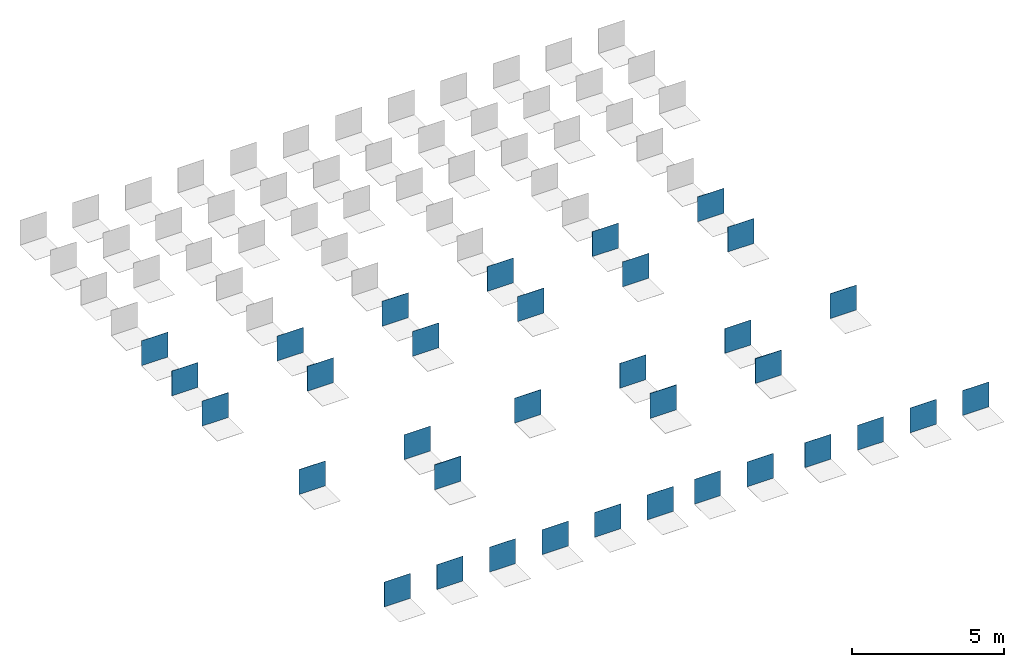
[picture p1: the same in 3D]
Properties of the parts of a building model (IFC2X3), part 9 of 12

# IfcWallStandardCase: Basic Wall:REVIGRÉS-URBAN-BASE-44,35X88,9-RECT-BONE, Basic Wall:REVIGRÉS-URBAN-BASE-44,35X88,9-RECT-BONE:22816
Type - IFC.REVIGRÉS-Dados de sustentabilidade-Wall Covering - PotencialPrivacaoDeAguaConsumoDeAguaPonderado: 4.5; EnergiaTermicaExportada: 0; ItemENovo: Sim; ItemEParcialmenteReciclado: 0.03; ItemEReciclado: Sim; VidaÚtilEsperada: 50; SubstanciasPerigosas: Não; PotencialDeEsgotamentoAbioticoDosRecursosFosseis: 203; PotencialDeEsgotamentoAbioticoDosRecursosNaoFosseisMineraisEMetais: 0.000701; PotencialDeAquecimentoGlobalBiogenico: -0.48; CombustiveisFosseisComPotencialDeAquecimentoGlobal: 13.9; PotencialDeAquecimentoGlobalUsoDoSoloEMudancaDeUsoDoSolo: 0.0246; PotencialDeEutrofizacaoFraccaoDeNutrientesQueAtingemOCompartimentoFinalDeAguaDoce: 0.000189; PotencialDeEutrofizacaoFraccaoDeNutrientesQueAtingemOCompartimentoFinalMarinho: 0.0122; EnergiaRecuperada: 0.00739; ConsumoDeAguaDoce: 0.113; UtilizacaoLiquidaDeAguaDoce: 0.113; ResiduosPerigososEliminados: 0.00221; ResiduosNaoPerigososEliminados: 1.83; MassaTotalDeResiduosRadioactivosEliminados: 0.000394; EnergiaElectricaExportada: 1.55; MateriaisParaRecuperacaoDeEnergia: 0.00739; MateriaisParaReciclagem: 0.0253; UnidadeEPD: 1 m²
Type - IFC.REVIGRÉS-Dados gerais-Wall Covering - Nome: REVIGRÉS-URBAN-BASE-44.35X88.9-RECT-URBAN BONE; TipoProduto: Prensado a seco: grupo BIa UGL | Grés porcelânico técnico; NumeroDeRegistoDAP: EPD-REV-20240006-CCC1-EN; ReferenciaDAP: -; UrlDOP: -
Classification: C3010 (Uniformat)
Pset_QuantityTakeOff - sets with these values: 2
Pset_WallCommon - ExtendToStructure: no; LoadBearing: no
IFC.REVIGRÉS-Dados do fabricante-Wall Covering - Type: Basic Wall: REVIGRÉS-URBAN-BASE-44,35X88,9-RECT-BONE
IFC.REVIGRÉS-Dados de desempenho-Wall Covering - Type: Basic Wall: REVIGRÉS-URBAN-BASE-44,35X88,9-RECT-BONE
IFC.REVIGRÉS-Dados de especificação-Wall Covering - Type: Basic Wall: REVIGRÉS-URBAN-BASE-44,35X88,9-RECT-BONE
IFC.REVIGRÉS-Dados geométricos-Wall Covering - Type: Basic Wall: REVIGRÉS-URBAN-BASE-44,35X88,9-RECT-BONE
IFC.REVIGRÉS-Dados de sustentabilidade-Wall Covering - Type: Basic Wall: REVIGRÉS-URBAN-BASE-44,35X88,9-RECT-BONE

# IfcWallStandardCase: Basic Wall:REVIGRÉS-URBAN-BASE-44,35X88,9-RECT-CRAFT, Basic Wall:REVIGRÉS-URBAN-BASE-44,35X88,9-RECT-CRAFT:22832
In: Level 1
Type - PredefinedType: STANDARD; Material: REVIGRÉS-URBAN-BASE-45X90-RECT-CRAFT 10.5 mm
Type - Pset_ElementShading - Roughness: 304.8 mm
Type - Pset_ManufacturerTypeInformation - Manufacturer: REVIGRÉS
Type - Pset_ProductRequirements - Category: Walls
Type - Pset_QuantityTakeOff - Reference: 3121H824T1
Type - Pset_ReinforcementBarPitchOfWall - Reference: 3121H824T1
Type - Pset_WallCommon - IsExternal: no; Reference: 3121H824T1
Type - IFC.REVIGRÉS-Dados do fabricante-Wall Covering - FabricanteURL: https://www.revigres.pt/; ReferenciaModelo: Urban; NumeroGlobalDeItemComercial: 3121H824T1; Acabamento: RECT; Material: Grés porcelânico; IdentificadorDoOperadorEconomico: 501840856; UrlFabricanteArtigo: https://www.revigres.pt/colecoes/urban; PaisOrigem: Portugal
Type - IFC.REVIGRÉS-Dados de desempenho-Wall Covering - Rectilinearidade: ± 0.2% máx.± 0.8 mm; Ortogonalidade: ± 0.2% máx.± 1.5 mm; PlanaridadeDaSuperficie: ± 0.3% máx. ± 1.8 mm; QualidadeDaSuperficie: Cumpre; AbsorcaoDeAgua: < 0.05%; ModuloDeRuptura: > 45 N/mm²; ResistenciaAFlexao: > 3500 N; ResistenciaAAbrasaoProfunda: < 120 mm³; DilatacaoTermicaLinear: ≤ 8,0x10-6 °C-1; ResistenciaAoChoqueTermico: Resiste; DurabilidadeResistenciaAoGeloDegelo: Resiste; ResistenciaAoEscorregamentoDIN51130: R9; ResistenciaAoEscorregamentoDIN51097: A; ResistenciaAoEscorregamentoENV51097: A; ResistenciaAoEscorregamentoENV12633: Class 1; ResistenciaAoEscorregamentoANSIA1371: ≥0,42; ResistenciaAoDeslizamentoENV12633: Class 1; ResistenciaAsManchas: Class 5; ResistenciaABaixasConcentracoesDeAcidosEAlcalis: Classe LA; ResistenciaAAltasConcentracoesDeAcidosEAlcalis: Classe HA; LibertacaoDeCadmio: 0; LibertacaoDeChumbo: 0
Type - IFC.REVIGRÉS-Dados de especificação-Wall Covering - VariacaoTonalidade: 2; NivelDeTrafego: 5; EPavimento: Sim; ERevestimento: Sim; EExterno: Sim
Type - IFC.REVIGRÉS-Dados geométricos-Wall Covering - AlturaNominal: 10.5 mm; ComprimentoNominal: 4435 mm; LarguraNominal: 88.9 mm
Type - IFC.REVIGRÉS-Dados de sustentabilidade-Wall Covering - PotencialPrivacaoDeAguaConsumoDeAguaPonderado: 4.5; EnergiaTermicaExportada: 0; ItemENovo: Sim; ItemEParcialmenteReciclado: 0.19; ItemEReciclado: Sim; VidaÚtilEsperada: 50; SubstanciasPerigosas: Não; PotencialDeEsgotamentoAbioticoDosRecursosFosseis: 203; PotencialDeEsgotamentoAbioticoDosRecursosNaoFosseisMineraisEMetais: 0.000701; PotencialDeAquecimentoGlobalBiogenico: -0.48; CombustiveisFosseisComPotencialDeAquecimentoGlobal: 13.9; PotencialDeAquecimentoGlobalUsoDoSoloEMudancaDeUsoDoSolo: 0.0246; PotencialDeEutrofizacaoFraccaoDeNutrientesQueAtingemOCompartimentoFinalDeAguaDoce: 0.000189; PotencialDeEutrofizacaoFraccaoDeNutrientesQueAtingemOCompartimentoFinalMarinho: 0.0122; EnergiaRecuperada: 0.00739; ConsumoDeAguaDoce: 0.113; UtilizacaoLiquidaDeAguaDoce: 0.113; ResiduosPerigososEliminados: 0.00221; ResiduosNaoPerigososEliminados: 1.83; MassaTotalDeResiduosRadioactivosEliminados: 0.000394; EnergiaElectricaExportada: 1.55; MateriaisParaRecuperacaoDeEnergia: 0.00739; MateriaisParaReciclagem: 0.0253; UnidadeEPD: 1 m²
Type - IFC.REVIGRÉS-Dados gerais-Wall Covering - Nome: REVIGRÉS-URBAN-BASE-44.35X88.9-RECT-URBAN CRAFT; TipoProduto: Prensado a seco: grupo BIa UGL | Grés porcelânico técnico; NumeroDeRegistoDAP: EPD-REV-20240006-CCC1-EN; ReferenciaDAP: -; UrlDOP: -
Classification: C3010 (Uniformat)
Pset_QuantityTakeOff - sets with these values: 2
Pset_WallCommon - ExtendToStructure: no; LoadBearing: no
IFC.REVIGRÉS-Dados do fabricante-Wall Covering - Type: Basic Wall: REVIGRÉS-URBAN-BASE-44,35X88,9-RECT-CRAFT
IFC.REVIGRÉS-Dados de desempenho-Wall Covering - Type: Basic Wall: REVIGRÉS-URBAN-BASE-44,35X88,9-RECT-CRAFT
IFC.REVIGRÉS-Dados de especificação-Wall Covering - Type: Basic Wall: REVIGRÉS-URBAN-BASE-44,35X88,9-RECT-CRAFT
IFC.REVIGRÉS-Dados geométricos-Wall Covering - Type: Basic Wall: REVIGRÉS-URBAN-BASE-44,35X88,9-RECT-CRAFT
IFC.REVIGRÉS-Dados de sustentabilidade-Wall Covering - Type: Basic Wall: REVIGRÉS-URBAN-BASE-44,35X88,9-RECT-CRAFT

# IfcWallStandardCase: Basic Wall:REVIGRÉS-URBAN-BASE-44,35X88,9-RECT-FOG, Basic Wall:REVIGRÉS-URBAN-BASE-44,35X88,9-RECT-FOG:22848
In: Level 1
Type - PredefinedType: STANDARD; Material: REVIGRÉS-URBAN-BASE-45X90-RECT-FOG 10.5 mm
Type - Pset_ElementShading - Roughness: 304.8 mm
Type - Pset_ManufacturerTypeInformation - Manufacturer: REVIGRÉS
Type - Pset_ProductRequirements - Category: Walls
Type - Pset_QuantityTakeOff - Reference: 3121H821T1
Type - Pset_ReinforcementBarPitchOfWall - Reference: 3121H821T1
Type - Pset_WallCommon - IsExternal: no; Reference: 3121H821T1
Type - IFC.REVIGRÉS-Dados do fabricante-Wall Covering - FabricanteURL: https://www.revigres.pt/; ReferenciaModelo: Urban; NumeroGlobalDeItemComercial: 3121H821T1; Acabamento: RECT; Material: Grés porcelânico; IdentificadorDoOperadorEconomico: 501840856; UrlFabricanteArtigo: https://www.revigres.pt/colecoes/urban; PaisOrigem: Portugal
Type - IFC.REVIGRÉS-Dados de desempenho-Wall Covering - Rectilinearidade: ± 0.2% máx.± 0.8 mm; Ortogonalidade: ± 0.2% máx.± 1.5 mm; PlanaridadeDaSuperficie: ± 0.3% máx. ± 1.8 mm; QualidadeDaSuperficie: Cumpre; AbsorcaoDeAgua: < 0.05%; ModuloDeRuptura: > 45 N/mm²; ResistenciaAFlexao: > 3500 N; ResistenciaAAbrasaoProfunda: < 120 mm³; DilatacaoTermicaLinear: ≤ 8,0x10-6 °C-1; ResistenciaAoChoqueTermico: Resiste; DurabilidadeResistenciaAoGeloDegelo: Resiste; ResistenciaAoEscorregamentoDIN51130: R9; ResistenciaAoEscorregamentoDIN51097: A; ResistenciaAoEscorregamentoENV51097: A; ResistenciaAoEscorregamentoENV12633: Class 1; ResistenciaAoEscorregamentoANSIA1371: ≥0,42; ResistenciaAoDeslizamentoENV12633: Class 1; ResistenciaAsManchas: Class 5; ResistenciaABaixasConcentracoesDeAcidosEAlcalis: Classe LA; ResistenciaAAltasConcentracoesDeAcidosEAlcalis: Classe HA; LibertacaoDeCadmio: 0; LibertacaoDeChumbo: 0
Type - IFC.REVIGRÉS-Dados de especificação-Wall Covering - VariacaoTonalidade: 2; NivelDeTrafego: 5; EPavimento: Sim; ERevestimento: Sim; EExterno: Sim
Type - IFC.REVIGRÉS-Dados geométricos-Wall Covering - AlturaNominal: 10.5 mm; ComprimentoNominal: 4435 mm; LarguraNominal: 88.9 mm
Type - IFC.REVIGRÉS-Dados de sustentabilidade-Wall Covering - PotencialPrivacaoDeAguaConsumoDeAguaPonderado: 4.5; EnergiaTermicaExportada: 0; ItemENovo: Sim; ItemEParcialmenteReciclado: 0.23; ItemEReciclado: Sim; VidaÚtilEsperada: 50; SubstanciasPerigosas: Não; PotencialDeEsgotamentoAbioticoDosRecursosFosseis: 203; PotencialDeEsgotamentoAbioticoDosRecursosNaoFosseisMineraisEMetais: 0.000701; PotencialDeAquecimentoGlobalBiogenico: -0.48; CombustiveisFosseisComPotencialDeAquecimentoGlobal: 13.9; PotencialDeAquecimentoGlobalUsoDoSoloEMudancaDeUsoDoSolo: 0.0246; PotencialDeEutrofizacaoFraccaoDeNutrientesQueAtingemOCompartimentoFinalDeAguaDoce: 0.000189; PotencialDeEutrofizacaoFraccaoDeNutrientesQueAtingemOCompartimentoFinalMarinho: 0.0122; EnergiaRecuperada: 0.00739; ConsumoDeAguaDoce: 0.113; UtilizacaoLiquidaDeAguaDoce: 0.113; ResiduosPerigososEliminados: 0.00221; ResiduosNaoPerigososEliminados: 1.83; MassaTotalDeResiduosRadioactivosEliminados: 0.000394; EnergiaElectricaExportada: 1.55; MateriaisParaRecuperacaoDeEnergia: 0.00739; MateriaisParaReciclagem: 0.0253; UnidadeEPD: 1 m²
Type - IFC.REVIGRÉS-Dados gerais-Wall Covering - Nome: REVIGRÉS-URBAN-BASE-44.35X88.9-RECT-URBAN FOG; TipoProduto: Prensado a seco: grupo BIa UGL | Grés porcelânico técnico; NumeroDeRegistoDAP: EPD-REV-20240006-CCC1-EN; ReferenciaDAP: -; UrlDOP: -
Classification: C3010 (Uniformat)
Pset_QuantityTakeOff - sets with these values: 2
Pset_WallCommon - ExtendToStructure: no; LoadBearing: no
IFC.REVIGRÉS-Dados do fabricante-Wall Covering - Type: Basic Wall: REVIGRÉS-URBAN-BASE-44,35X88,9-RECT-FOG
IFC.REVIGRÉS-Dados de desempenho-Wall Covering - Type: Basic Wall: REVIGRÉS-URBAN-BASE-44,35X88,9-RECT-FOG
IFC.REVIGRÉS-Dados de especificação-Wall Covering - Type: Basic Wall: REVIGRÉS-URBAN-BASE-44,35X88,9-RECT-FOG
IFC.REVIGRÉS-Dados geométricos-Wall Covering - Type: Basic Wall: REVIGRÉS-URBAN-BASE-44,35X88,9-RECT-FOG
IFC.REVIGRÉS-Dados de sustentabilidade-Wall Covering - Type: Basic Wall: REVIGRÉS-URBAN-BASE-44,35X88,9-RECT-FOG

# IfcWallStandardCase: Basic Wall:REVIGRÉS-URBAN-BASE-44,35X88,9-RECT-GRIS, Basic Wall:REVIGRÉS-URBAN-BASE-44,35X88,9-RECT-GRIS:22864
In: Level 1
Type - PredefinedType: STANDARD; Material: REVIGRÉS-URBAN-BASE-45X90-RECT-GRIS 10.5 mm
Type - Pset_ElementShading - Roughness: 304.8 mm
Type - Pset_ManufacturerTypeInformation - Manufacturer: REVIGRÉS
Type - Pset_ProductRequirements - Category: Walls
Type - Pset_QuantityTakeOff - Reference: 3121H822T1
Type - Pset_ReinforcementBarPitchOfWall - Reference: 3121H822T1
Type - Pset_WallCommon - IsExternal: no; Reference: 3121H822T1
Type - IFC.REVIGRÉS-Dados do fabricante-Wall Covering - FabricanteURL: https://www.revigres.pt/; ReferenciaModelo: Urban; NumeroGlobalDeItemComercial: 3121H822T1; Acabamento: RECT; Material: Grés porcelânico; IdentificadorDoOperadorEconomico: 501840856; UrlFabricanteArtigo: https://www.revigres.pt/colecoes/urban; PaisOrigem: Portugal
Type - IFC.REVIGRÉS-Dados de desempenho-Wall Covering - Rectilinearidade: ± 0.2% máx.± 0.8 mm; Ortogonalidade: ± 0.2% máx.± 1.5 mm; PlanaridadeDaSuperficie: ± 0.3% máx. ± 1.8 mm; QualidadeDaSuperficie: Cumpre; AbsorcaoDeAgua: < 0.05%; ModuloDeRuptura: > 45 N/mm²; ResistenciaAFlexao: > 3500 N; ResistenciaAAbrasaoProfunda: < 120 mm³; DilatacaoTermicaLinear: ≤ 8,0x10-6 °C-1; ResistenciaAoChoqueTermico: Resiste; DurabilidadeResistenciaAoGeloDegelo: Resiste; ResistenciaAoEscorregamentoDIN51130: R9; ResistenciaAoEscorregamentoDIN51097: A; ResistenciaAoEscorregamentoENV51097: A; ResistenciaAoEscorregamentoENV12633: Class 1; ResistenciaAoEscorregamentoANSIA1371: ≥0,42; ResistenciaAoDeslizamentoENV12633: Class 1; ResistenciaAsManchas: Class 5; ResistenciaABaixasConcentracoesDeAcidosEAlcalis: Classe LA; ResistenciaAAltasConcentracoesDeAcidosEAlcalis: Classe HA; LibertacaoDeCadmio: 0; LibertacaoDeChumbo: 0
Type - IFC.REVIGRÉS-Dados de especificação-Wall Covering - VariacaoTonalidade: 2; NivelDeTrafego: 5; EPavimento: Sim; ERevestimento: Sim; EExterno: Sim
Type - IFC.REVIGRÉS-Dados geométricos-Wall Covering - AlturaNominal: 10.5 mm; ComprimentoNominal: 4435 mm; LarguraNominal: 88.9 mm
Type - IFC.REVIGRÉS-Dados de sustentabilidade-Wall Covering - PotencialPrivacaoDeAguaConsumoDeAguaPonderado: 4.5; EnergiaTermicaExportada: 0; ItemENovo: Sim; ItemEParcialmenteReciclado: 0.23; ItemEReciclado: Sim; VidaÚtilEsperada: 50; SubstanciasPerigosas: Não; PotencialDeEsgotamentoAbioticoDosRecursosFosseis: 203; PotencialDeEsgotamentoAbioticoDosRecursosNaoFosseisMineraisEMetais: 0.000701; PotencialDeAquecimentoGlobalBiogenico: -0.48; CombustiveisFosseisComPotencialDeAquecimentoGlobal: 13.9; PotencialDeAquecimentoGlobalUsoDoSoloEMudancaDeUsoDoSolo: 0.0246; PotencialDeEutrofizacaoFraccaoDeNutrientesQueAtingemOCompartimentoFinalDeAguaDoce: 0.000189; PotencialDeEutrofizacaoFraccaoDeNutrientesQueAtingemOCompartimentoFinalMarinho: 0.0122; EnergiaRecuperada: 0.00739; ConsumoDeAguaDoce: 0.113; UtilizacaoLiquidaDeAguaDoce: 0.113; ResiduosPerigososEliminados: 0.00221; ResiduosNaoPerigososEliminados: 1.83; MassaTotalDeResiduosRadioactivosEliminados: 0.000394; EnergiaElectricaExportada: 1.55; MateriaisParaRecuperacaoDeEnergia: 0.00739; MateriaisParaReciclagem: 0.0253; UnidadeEPD: 1 m²
Type - IFC.REVIGRÉS-Dados gerais-Wall Covering - Nome: REVIGRÉS-URBAN-BASE-44.35X88.9-RECT-URBAN GRIS; TipoProduto: Prensado a seco: grupo BIa UGL | Grés porcelânico técnico; NumeroDeRegistoDAP: EPD-REV-20240006-CCC1-EN; ReferenciaDAP: -; UrlDOP: -
Classification: C3010 (Uniformat)
Pset_QuantityTakeOff - sets with these values: 2
Pset_WallCommon - ExtendToStructure: no; LoadBearing: no
IFC.REVIGRÉS-Dados do fabricante-Wall Covering - Type: Basic Wall: REVIGRÉS-URBAN-BASE-44,35X88,9-RECT-GRIS
IFC.REVIGRÉS-Dados de desempenho-Wall Covering - Type: Basic Wall: REVIGRÉS-URBAN-BASE-44,35X88,9-RECT-GRIS
IFC.REVIGRÉS-Dados de especificação-Wall Covering - Type: Basic Wall: REVIGRÉS-URBAN-BASE-44,35X88,9-RECT-GRIS
IFC.REVIGRÉS-Dados geométricos-Wall Covering - Type: Basic Wall: REVIGRÉS-URBAN-BASE-44,35X88,9-RECT-GRIS
IFC.REVIGRÉS-Dados de sustentabilidade-Wall Covering - Type: Basic Wall: REVIGRÉS-URBAN-BASE-44,35X88,9-RECT-GRIS

# IfcWallStandardCase: Basic Wall:REVIGRÉS-URBAN-BASE-44,35X88,9-RECT-OFFWHITE, Basic Wall:REVIGRÉS-URBAN-BASE-44,35X88,9-RECT-OFFWHITE:22880
In: Level 1
Type - PredefinedType: STANDARD; Material: REVIGRÉS-URBAN-BASE-45X90-RECT-OFFWHITE 10.5 mm
Type - Pset_ElementShading - Roughness: 304.8 mm
Type - Pset_ManufacturerTypeInformation - Manufacturer: REVIGRÉS
Type - Pset_ProductRequirements - Category: Walls
Type - Pset_QuantityTakeOff - Reference: 3121H823T1
Type - Pset_ReinforcementBarPitchOfWall - Reference: 3121H823T1
Type - Pset_WallCommon - IsExternal: no; Reference: 3121H823T1
Type - IFC.REVIGRÉS-Dados do fabricante-Wall Covering - FabricanteURL: https://www.revigres.pt/; ReferenciaModelo: Urban; NumeroGlobalDeItemComercial: 3121H823T1; Acabamento: RECT; Material: Grés porcelânico; IdentificadorDoOperadorEconomico: 501840856; UrlFabricanteArtigo: https://www.revigres.pt/colecoes/urban; PaisOrigem: Portugal
Type - IFC.REVIGRÉS-Dados de desempenho-Wall Covering - Rectilinearidade: ± 0.2% máx.± 0.8 mm; Ortogonalidade: ± 0.2% máx.± 1.5 mm; PlanaridadeDaSuperficie: ± 0.3% máx. ± 1.8 mm; QualidadeDaSuperficie: Cumpre; AbsorcaoDeAgua: < 0.05%; ModuloDeRuptura: > 45 N/mm²; ResistenciaAFlexao: > 3500 N; ResistenciaAAbrasaoProfunda: < 120 mm³; DilatacaoTermicaLinear: ≤ 8,0x10-6 °C-1; ResistenciaAoChoqueTermico: Resiste; DurabilidadeResistenciaAoGeloDegelo: Resiste; ResistenciaAoEscorregamentoDIN51130: R9; ResistenciaAoEscorregamentoDIN51097: A; ResistenciaAoEscorregamentoENV51097: A; ResistenciaAoEscorregamentoENV12633: Class 1; ResistenciaAoEscorregamentoANSIA1371: ≥0,42; ResistenciaAoDeslizamentoENV12633: Class 1; ResistenciaAsManchas: Class 5; ResistenciaABaixasConcentracoesDeAcidosEAlcalis: Classe LA; ResistenciaAAltasConcentracoesDeAcidosEAlcalis: Classe HA; LibertacaoDeCadmio: 0; LibertacaoDeChumbo: 0
Type - IFC.REVIGRÉS-Dados de especificação-Wall Covering - VariacaoTonalidade: 2; NivelDeTrafego: 5; EPavimento: Sim; ERevestimento: Sim; EExterno: Sim
Type - IFC.REVIGRÉS-Dados geométricos-Wall Covering - AlturaNominal: 10.5 mm; ComprimentoNominal: 4435 mm; LarguraNominal: 88.9 mm
Type - IFC.REVIGRÉS-Dados de sustentabilidade-Wall Covering - PotencialPrivacaoDeAguaConsumoDeAguaPonderado: 4.5; EnergiaTermicaExportada: 0; ItemENovo: Sim; ItemEParcialmenteReciclado: 0.03; ItemEReciclado: Sim; VidaÚtilEsperada: 50; SubstanciasPerigosas: Não; PotencialDeEsgotamentoAbioticoDosRecursosFosseis: 203; PotencialDeEsgotamentoAbioticoDosRecursosNaoFosseisMineraisEMetais: 0.000701; PotencialDeAquecimentoGlobalBiogenico: -0.48; CombustiveisFosseisComPotencialDeAquecimentoGlobal: 13.9; PotencialDeAquecimentoGlobalUsoDoSoloEMudancaDeUsoDoSolo: 0.0246; PotencialDeEutrofizacaoFraccaoDeNutrientesQueAtingemOCompartimentoFinalDeAguaDoce: 0.000189; PotencialDeEutrofizacaoFraccaoDeNutrientesQueAtingemOCompartimentoFinalMarinho: 0.0122; EnergiaRecuperada: 0.00739; ConsumoDeAguaDoce: 0.113; UtilizacaoLiquidaDeAguaDoce: 0.113; ResiduosPerigososEliminados: 0.00221; ResiduosNaoPerigososEliminados: 1.83; MassaTotalDeResiduosRadioactivosEliminados: 0.000394; EnergiaElectricaExportada: 1.55; MateriaisParaRecuperacaoDeEnergia: 0.00739; MateriaisParaReciclagem: 0.0253; UnidadeEPD: 1 m²
Type - IFC.REVIGRÉS-Dados gerais-Wall Covering - Nome: REVIGRÉS-URBAN-BASE-44.35X88.9-RECT-URBAN OFFWHITE; TipoProduto: Prensado a seco: grupo BIa UGL | Grés porcelânico técnico; NumeroDeRegistoDAP: EPD-REV-20240006-CCC1-EN; ReferenciaDAP: -; UrlDOP: -
Classification: C3010 (Uniformat)
Pset_QuantityTakeOff - sets with these values: 2
Pset_WallCommon - ExtendToStructure: no; LoadBearing: no
IFC.REVIGRÉS-Dados do fabricante-Wall Covering - Type: Basic Wall: REVIGRÉS-URBAN-BASE-44,35X88,9-RECT-OFFWHITE
IFC.REVIGRÉS-Dados de desempenho-Wall Covering - Type: Basic Wall: REVIGRÉS-URBAN-BASE-44,35X88,9-RECT-OFFWHITE
IFC.REVIGRÉS-Dados de especificação-Wall Covering - Type: Basic Wall: REVIGRÉS-URBAN-BASE-44,35X88,9-RECT-OFFWHITE
IFC.REVIGRÉS-Dados geométricos-Wall Covering - Type: Basic Wall: REVIGRÉS-URBAN-BASE-44,35X88,9-RECT-OFFWHITE
IFC.REVIGRÉS-Dados de sustentabilidade-Wall Covering - Type: Basic Wall: REVIGRÉS-URBAN-BASE-44,35X88,9-RECT-OFFWHITE

# IfcWallStandardCase: Basic Wall:REVIGRÉS-URBAN-BASE-45X45-NAT HYDRAULIK ANTRACITE, Basic Wall:REVIGRÉS-URBAN-BASE-45X45-NAT HYDRAULIK ANTRACITE:26948
In: Level 1
Type - PredefinedType: STANDARD; Material: REVIGRÉS-URBAN-BASE-45X45-NAT-HYDRAULIK ANTRACITE 8.5 mm
Type - Pset_ElementShading - Roughness: 304.8 mm
Type - Pset_ManufacturerTypeInformation - Manufacturer: REVIGRÉS
Type - Pset_ProductRequirements - Category: Walls
Type - Pset_QuantityTakeOff - Reference: 31200752U1
Type - Pset_ReinforcementBarPitchOfWall - Reference: 31200752U1
Type - Pset_WallCommon - IsExternal: no; Reference: 31200752U1
Type - IFC.REVIGRÉS-Dados do fabricante-Wall Covering - FabricanteURL: https://www.revigres.pt/; ReferenciaModelo: Urban; NumeroGlobalDeItemComercial: 31200752U1; Acabamento: NAT; Material: Grés porcelânico; IdentificadorDoOperadorEconomico: 501840856; UrlFabricanteArtigo: https://www.revigres.pt/colecoes/urban; PaisOrigem: Portugal
Type - IFC.REVIGRÉS-Dados de desempenho-Wall Covering - Rectilinearidade: ± 0.3% máx. ± 1.5 mm; Ortogonalidade: ± 0.3% máx. ± 1.8 mm; PlanaridadeDaSuperficie: ± 0.3% máx. ± 1.8 mm; QualidadeDaSuperficie: Cumpre; AbsorcaoDeAgua: < 0.05%; ModuloDeRuptura: > 45 N/mm²; ResistenciaAFlexao: > 2000 N; ResistenciaAAbrasaoProfunda: < 120 mm³; DilatacaoTermicaLinear: ≤ 8,0x10-6 °C-1; ResistenciaAoChoqueTermico: Resiste; DurabilidadeResistenciaAoGeloDegelo: Resiste; ResistenciaAoEscorregamentoDIN51130: R9; ResistenciaAoEscorregamentoDIN51097: A; ResistenciaAoEscorregamentoENV51097: A; ResistenciaAoEscorregamentoENV12633: Class 1; ResistenciaAoEscorregamentoANSIA1371: ≥0,42; ResistenciaAoDeslizamentoENV12633: Class 1; ResistenciaAsManchas: Class 5; ResistenciaABaixasConcentracoesDeAcidosEAlcalis: Classe LA; ResistenciaAAltasConcentracoesDeAcidosEAlcalis: Classe HA; LibertacaoDeCadmio: 0; LibertacaoDeChumbo: 0
Type - IFC.REVIGRÉS-Dados de especificação-Wall Covering - VariacaoTonalidade: 3; NivelDeTrafego: 4; EPavimento: Sim; ERevestimento: Sim; EExterno: Sim
Type - IFC.REVIGRÉS-Dados geométricos-Wall Covering - AlturaNominal: 8.5 mm; ComprimentoNominal: 45 mm; LarguraNominal: 45 mm
Type - IFC.REVIGRÉS-Dados de sustentabilidade-Wall Covering - PotencialPrivacaoDeAguaConsumoDeAguaPonderado: 4.5; EnergiaTermicaExportada: 0; ItemENovo: Sim; ItemEParcialmenteReciclado: 0.29; ItemEReciclado: Sim; VidaÚtilEsperada: 50; SubstanciasPerigosas: Não; PotencialDeEsgotamentoAbioticoDosRecursosFosseis: 203; PotencialDeEsgotamentoAbioticoDosRecursosNaoFosseisMineraisEMetais: 0.000701; PotencialDeAquecimentoGlobalBiogenico: -0.48; CombustiveisFosseisComPotencialDeAquecimentoGlobal: 13.9; PotencialDeAquecimentoGlobalUsoDoSoloEMudancaDeUsoDoSolo: 0.0246; PotencialDeEutrofizacaoFraccaoDeNutrientesQueAtingemOCompartimentoFinalDeAguaDoce: 0.000189; PotencialDeEutrofizacaoFraccaoDeNutrientesQueAtingemOCompartimentoFinalMarinho: 0.0122; EnergiaRecuperada: 0.00739; ConsumoDeAguaDoce: 0.113; UtilizacaoLiquidaDeAguaDoce: 0.113; ResiduosPerigososEliminados: 0.00221; ResiduosNaoPerigososEliminados: 1.83; MassaTotalDeResiduosRadioactivosEliminados: 0.000394; EnergiaElectricaExportada: 1.55; MateriaisParaRecuperacaoDeEnergia: 0.00739; MateriaisParaReciclagem: 0.0253; UnidadeEPD: 1 m²
Type - IFC.REVIGRÉS-Dados gerais-Wall Covering - Nome: REVIGRÉS-URBAN-BASE-45X45-NAT-HYDRAULIK ANTRACITE; TipoProduto: Prensado a seco: grupo BIa UGL | Grés porcelânico técnico; NumeroDeRegistoDAP: EPD-REV-20240006-CCC1-EN; ReferenciaDAP: -; UrlDOP: -
Classification: C3010 (Uniformat)
Pset_QuantityTakeOff - sets with these values: 2
Pset_WallCommon - ExtendToStructure: no; LoadBearing: no
IFC.REVIGRÉS-Dados do fabricante-Wall Covering - Type: Basic Wall: REVIGRÉS-URBAN-BASE-45X45-NAT HYDRAULIK ANTRACITE
IFC.REVIGRÉS-Dados de desempenho-Wall Covering - Type: Basic Wall: REVIGRÉS-URBAN-BASE-45X45-NAT HYDRAULIK ANTRACITE
IFC.REVIGRÉS-Dados de especificação-Wall Covering - Type: Basic Wall: REVIGRÉS-URBAN-BASE-45X45-NAT HYDRAULIK ANTRACITE
IFC.REVIGRÉS-Dados geométricos-Wall Covering - Type: Basic Wall: REVIGRÉS-URBAN-BASE-45X45-NAT HYDRAULIK ANTRACITE
IFC.REVIGRÉS-Dados de sustentabilidade-Wall Covering - Type: Basic Wall: REVIGRÉS-URBAN-BASE-45X45-NAT HYDRAULIK ANTRACITE

# IfcWallStandardCase: Basic Wall:REVIGRÉS-URBAN-BASE-45X45-NAT HYDRAULIK BONE, Basic Wall:REVIGRÉS-URBAN-BASE-45X45-NAT HYDRAULIK BONE:26964
In: Level 1
Type - PredefinedType: STANDARD; Material: REVIGRÉS-URBAN-BASE-45X45-NAT-HYDRAULIK BONE 8.5 mm
Type - Pset_ElementShading - Roughness: 304.8 mm
Type - Pset_ManufacturerTypeInformation - Manufacturer: REVIGRÉS
Type - Pset_ProductRequirements - Category: Walls
Type - Pset_QuantityTakeOff - Reference: 31200754T1
Type - Pset_ReinforcementBarPitchOfWall - Reference: 31200754T1
Type - Pset_WallCommon - IsExternal: no; Reference: 31200754T1
Type - IFC.REVIGRÉS-Dados do fabricante-Wall Covering - FabricanteURL: https://www.revigres.pt/; ReferenciaModelo: Urban; NumeroGlobalDeItemComercial: 31200754T1; Acabamento: NAT; Material: Grés porcelânico; IdentificadorDoOperadorEconomico: 501840856; UrlFabricanteArtigo: https://www.revigres.pt/colecoes/urban; PaisOrigem: Portugal
Type - IFC.REVIGRÉS-Dados de desempenho-Wall Covering - Rectilinearidade: ± 0.3% máx. ± 1.5 mm; Ortogonalidade: ± 0.3% máx. ± 1.8 mm; PlanaridadeDaSuperficie: ± 0.3% máx. ± 1.8 mm; QualidadeDaSuperficie: Cumpre; AbsorcaoDeAgua: < 0.05%; ModuloDeRuptura: > 45 N/mm²; ResistenciaAFlexao: > 2000 N; ResistenciaAAbrasaoProfunda: < 120 mm³; DilatacaoTermicaLinear: ≤ 8,0x10-6 °C-1; ResistenciaAoChoqueTermico: Resiste; DurabilidadeResistenciaAoGeloDegelo: Resiste; ResistenciaAoEscorregamentoDIN51130: R9; ResistenciaAoEscorregamentoDIN51097: A; ResistenciaAoEscorregamentoENV51097: A; ResistenciaAoEscorregamentoENV12633: Class 1; ResistenciaAoEscorregamentoANSIA1371: ≥0,42; ResistenciaAoDeslizamentoENV12633: Class 1; ResistenciaAsManchas: Class 5; ResistenciaABaixasConcentracoesDeAcidosEAlcalis: Classe LA; ResistenciaAAltasConcentracoesDeAcidosEAlcalis: Classe HA; LibertacaoDeCadmio: 0; LibertacaoDeChumbo: 0
Type - IFC.REVIGRÉS-Dados de especificação-Wall Covering - VariacaoTonalidade: 3; NivelDeTrafego: 4; EPavimento: Sim; ERevestimento: Sim; EExterno: Sim
Type - IFC.REVIGRÉS-Dados geométricos-Wall Covering - AlturaNominal: 8.5 mm; ComprimentoNominal: 45 mm; LarguraNominal: 45 mm
Type - IFC.REVIGRÉS-Dados de sustentabilidade-Wall Covering - PotencialPrivacaoDeAguaConsumoDeAguaPonderado: 4.5; EnergiaTermicaExportada: 0; ItemENovo: Sim; ItemEParcialmenteReciclado: 0.03; ItemEReciclado: Sim; VidaÚtilEsperada: 50; SubstanciasPerigosas: Não; PotencialDeEsgotamentoAbioticoDosRecursosFosseis: 203; PotencialDeEsgotamentoAbioticoDosRecursosNaoFosseisMineraisEMetais: 0.000701; PotencialDeAquecimentoGlobalBiogenico: -0.48; CombustiveisFosseisComPotencialDeAquecimentoGlobal: 13.9; PotencialDeAquecimentoGlobalUsoDoSoloEMudancaDeUsoDoSolo: 0.0246; PotencialDeEutrofizacaoFraccaoDeNutrientesQueAtingemOCompartimentoFinalDeAguaDoce: 0.000189; PotencialDeEutrofizacaoFraccaoDeNutrientesQueAtingemOCompartimentoFinalMarinho: 0.0122; EnergiaRecuperada: 0.00739; ConsumoDeAguaDoce: 0.113; UtilizacaoLiquidaDeAguaDoce: 0.113; ResiduosPerigososEliminados: 0.00221; ResiduosNaoPerigososEliminados: 1.83; MassaTotalDeResiduosRadioactivosEliminados: 0.000394; EnergiaElectricaExportada: 1.55; MateriaisParaRecuperacaoDeEnergia: 0.00739; MateriaisParaReciclagem: 0.0253; UnidadeEPD: 1 m²
Type - IFC.REVIGRÉS-Dados gerais-Wall Covering - Nome: REVIGRÉS-URBAN-BASE-45X45-NAT-HYDRAULIK BONE; TipoProduto: Prensado a seco: grupo BIa UGL | Grés porcelânico técnico; NumeroDeRegistoDAP: EPD-REV-20240006-CCC1-EN; ReferenciaDAP: -; UrlDOP: -
Classification: C3010 (Uniformat)
Pset_QuantityTakeOff - sets with these values: 2
Pset_WallCommon - ExtendToStructure: no; LoadBearing: no
IFC.REVIGRÉS-Dados do fabricante-Wall Covering - Type: Basic Wall: REVIGRÉS-URBAN-BASE-45X45-NAT HYDRAULIK BONE
IFC.REVIGRÉS-Dados de desempenho-Wall Covering - Type: Basic Wall: REVIGRÉS-URBAN-BASE-45X45-NAT HYDRAULIK BONE
IFC.REVIGRÉS-Dados de especificação-Wall Covering - Type: Basic Wall: REVIGRÉS-URBAN-BASE-45X45-NAT HYDRAULIK BONE
IFC.REVIGRÉS-Dados geométricos-Wall Covering - Type: Basic Wall: REVIGRÉS-URBAN-BASE-45X45-NAT HYDRAULIK BONE
IFC.REVIGRÉS-Dados de sustentabilidade-Wall Covering - Type: Basic Wall: REVIGRÉS-URBAN-BASE-45X45-NAT HYDRAULIK BONE

# IfcWallStandardCase: Basic Wall:REVIGRÉS-URBAN-BASE-45X45-NAT HYDRAULIK CRAFT, Basic Wall:REVIGRÉS-URBAN-BASE-45X45-NAT HYDRAULIK CRAFT:26980
In: Level 1
Type - PredefinedType: STANDARD; Material: REVIGRÉS-URBAN-BASE-45X45-NAT-HYDRAULIK CRAFT 8.5 mm
Type - Pset_ElementShading - Roughness: 304.8 mm
Type - Pset_ManufacturerTypeInformation - Manufacturer: REVIGRÉS
Type - Pset_ProductRequirements - Category: Walls
Type - Pset_QuantityTakeOff - Reference: 31200755T1
Type - Pset_ReinforcementBarPitchOfWall - Reference: 31200755T1
Type - Pset_WallCommon - IsExternal: no; Reference: 31200755T1
Type - IFC.REVIGRÉS-Dados do fabricante-Wall Covering - FabricanteURL: https://www.revigres.pt/; ReferenciaModelo: Urban; NumeroGlobalDeItemComercial: 31200755T1; Acabamento: NAT; Material: Grés porcelânico; IdentificadorDoOperadorEconomico: 501840856; UrlFabricanteArtigo: https://www.revigres.pt/colecoes/urban; PaisOrigem: Portugal
Type - IFC.REVIGRÉS-Dados de desempenho-Wall Covering - Rectilinearidade: ± 0.3% máx. ± 1.5 mm; Ortogonalidade: ± 0.3% máx. ± 1.8 mm; PlanaridadeDaSuperficie: ± 0.3% máx. ± 1.8 mm; QualidadeDaSuperficie: Cumpre; AbsorcaoDeAgua: < 0.05%; ModuloDeRuptura: > 45 N/mm²; ResistenciaAFlexao: > 2000 N; ResistenciaAAbrasaoProfunda: < 120 mm³; DilatacaoTermicaLinear: ≤ 8,0x10-6 °C-1; ResistenciaAoChoqueTermico: Resiste; DurabilidadeResistenciaAoGeloDegelo: Resiste; ResistenciaAoEscorregamentoDIN51130: R9; ResistenciaAoEscorregamentoDIN51097: A; ResistenciaAoEscorregamentoENV51097: A; ResistenciaAoEscorregamentoENV12633: Class 1; ResistenciaAoEscorregamentoANSIA1371: ≥0,42; ResistenciaAoDeslizamentoENV12633: Class 1; ResistenciaAsManchas: Class 5; ResistenciaABaixasConcentracoesDeAcidosEAlcalis: Classe LA; ResistenciaAAltasConcentracoesDeAcidosEAlcalis: Classe HA; LibertacaoDeCadmio: 0; LibertacaoDeChumbo: 0
Type - IFC.REVIGRÉS-Dados de especificação-Wall Covering - VariacaoTonalidade: 3; NivelDeTrafego: 4; EPavimento: Sim; ERevestimento: Sim; EExterno: Sim
Type - IFC.REVIGRÉS-Dados geométricos-Wall Covering - AlturaNominal: 8.5 mm; ComprimentoNominal: 45 mm; LarguraNominal: 45 mm
Type - IFC.REVIGRÉS-Dados de sustentabilidade-Wall Covering - PotencialPrivacaoDeAguaConsumoDeAguaPonderado: 4.5; EnergiaTermicaExportada: 0; ItemENovo: Sim; ItemEParcialmenteReciclado: 0.19; ItemEReciclado: Sim; VidaÚtilEsperada: 50; SubstanciasPerigosas: Não; PotencialDeEsgotamentoAbioticoDosRecursosFosseis: 203; PotencialDeEsgotamentoAbioticoDosRecursosNaoFosseisMineraisEMetais: 0.000701; PotencialDeAquecimentoGlobalBiogenico: -0.48; CombustiveisFosseisComPotencialDeAquecimentoGlobal: 13.9; PotencialDeAquecimentoGlobalUsoDoSoloEMudancaDeUsoDoSolo: 0.0246; PotencialDeEutrofizacaoFraccaoDeNutrientesQueAtingemOCompartimentoFinalDeAguaDoce: 0.000189; PotencialDeEutrofizacaoFraccaoDeNutrientesQueAtingemOCompartimentoFinalMarinho: 0.0122; EnergiaRecuperada: 0.00739; ConsumoDeAguaDoce: 0.113; UtilizacaoLiquidaDeAguaDoce: 0.113; ResiduosPerigososEliminados: 0.00221; ResiduosNaoPerigososEliminados: 1.83; MassaTotalDeResiduosRadioactivosEliminados: 0.000394; EnergiaElectricaExportada: 1.55; MateriaisParaRecuperacaoDeEnergia: 0.00739; MateriaisParaReciclagem: 0.0253; UnidadeEPD: 1 m²
Type - IFC.REVIGRÉS-Dados gerais-Wall Covering - Nome: REVIGRÉS-URBAN-BASE-45X45-NAT-HYDRAULIK CRAFT; TipoProduto: Prensado a seco: grupo BIa UGL | Grés porcelânico técnico; NumeroDeRegistoDAP: EPD-REV-20240006-CCC1-EN; ReferenciaDAP: -; UrlDOP: -
Classification: C3010 (Uniformat)
Pset_QuantityTakeOff - sets with these values: 2
Pset_WallCommon - ExtendToStructure: no; LoadBearing: no
IFC.REVIGRÉS-Dados do fabricante-Wall Covering - Type: Basic Wall: REVIGRÉS-URBAN-BASE-45X45-NAT HYDRAULIK CRAFT
IFC.REVIGRÉS-Dados de desempenho-Wall Covering - Type: Basic Wall: REVIGRÉS-URBAN-BASE-45X45-NAT HYDRAULIK CRAFT
IFC.REVIGRÉS-Dados de especificação-Wall Covering - Type: Basic Wall: REVIGRÉS-URBAN-BASE-45X45-NAT HYDRAULIK CRAFT
IFC.REVIGRÉS-Dados geométricos-Wall Covering - Type: Basic Wall: REVIGRÉS-URBAN-BASE-45X45-NAT HYDRAULIK CRAFT
IFC.REVIGRÉS-Dados de sustentabilidade-Wall Covering - Type: Basic Wall: REVIGRÉS-URBAN-BASE-45X45-NAT HYDRAULIK CRAFT

# IfcWallStandardCase: Basic Wall:REVIGRÉS-URBAN-BASE-45X45-NAT HYDRAULIK FOG, Basic Wall:REVIGRÉS-URBAN-BASE-45X45-NAT HYDRAULIK FOG:27374
In: Level 1
Type - PredefinedType: STANDARD; Material: REVIGRÉS-URBAN-BASE-45X45-NAT-HYDRAULIK FOG 8.5 mm
Type - Pset_ElementShading - Roughness: 304.8 mm
Type - Pset_ManufacturerTypeInformation - Manufacturer: REVIGRÉS
Type - Pset_ProductRequirements - Category: Walls
Type - Pset_QuantityTakeOff - Reference: 31200756T1
Type - Pset_ReinforcementBarPitchOfWall - Reference: 31200756T1
Type - Pset_WallCommon - IsExternal: no; Reference: 31200756T1
Type - IFC.REVIGRÉS-Dados do fabricante-Wall Covering - FabricanteURL: https://www.revigres.pt/; ReferenciaModelo: Urban; NumeroGlobalDeItemComercial: 31200756T1; Acabamento: NAT; Material: Grés porcelânico; IdentificadorDoOperadorEconomico: 501840856; UrlFabricanteArtigo: https://www.revigres.pt/colecoes/urban; PaisOrigem: Portugal
Type - IFC.REVIGRÉS-Dados de desempenho-Wall Covering - Rectilinearidade: ± 0.3% máx. ± 1.5 mm; Ortogonalidade: ± 0.3% máx. ± 1.8 mm; PlanaridadeDaSuperficie: ± 0.3% máx. ± 1.8 mm; QualidadeDaSuperficie: Cumpre; AbsorcaoDeAgua: < 0.05%; ModuloDeRuptura: > 45 N/mm²; ResistenciaAFlexao: > 2000 N; ResistenciaAAbrasaoProfunda: < 120 mm³; DilatacaoTermicaLinear: ≤ 8,0x10-6 °C-1; ResistenciaAoChoqueTermico: Resiste; DurabilidadeResistenciaAoGeloDegelo: Resiste; ResistenciaAoEscorregamentoDIN51130: R9; ResistenciaAoEscorregamentoDIN51097: A; ResistenciaAoEscorregamentoENV51097: A; ResistenciaAoEscorregamentoENV12633: Class 1; ResistenciaAoEscorregamentoANSIA1371: ≥0,42; ResistenciaAoDeslizamentoENV12633: Class 1; ResistenciaAsManchas: Class 5; ResistenciaABaixasConcentracoesDeAcidosEAlcalis: Classe LA; ResistenciaAAltasConcentracoesDeAcidosEAlcalis: Classe HA; LibertacaoDeCadmio: 0; LibertacaoDeChumbo: 0
Type - IFC.REVIGRÉS-Dados de especificação-Wall Covering - VariacaoTonalidade: 3; NivelDeTrafego: 4; EPavimento: Sim; ERevestimento: Sim; EExterno: Sim
Type - IFC.REVIGRÉS-Dados geométricos-Wall Covering - AlturaNominal: 8.5 mm; ComprimentoNominal: 45 mm; LarguraNominal: 45 mm
Type - IFC.REVIGRÉS-Dados de sustentabilidade-Wall Covering - PotencialPrivacaoDeAguaConsumoDeAguaPonderado: 4.5; EnergiaTermicaExportada: 0; ItemENovo: Sim; ItemEParcialmenteReciclado: 0.23; ItemEReciclado: Sim; VidaÚtilEsperada: 50; SubstanciasPerigosas: Não; PotencialDeEsgotamentoAbioticoDosRecursosFosseis: 203; PotencialDeEsgotamentoAbioticoDosRecursosNaoFosseisMineraisEMetais: 0.000701; PotencialDeAquecimentoGlobalBiogenico: -0.48; CombustiveisFosseisComPotencialDeAquecimentoGlobal: 13.9; PotencialDeAquecimentoGlobalUsoDoSoloEMudancaDeUsoDoSolo: 0.0246; PotencialDeEutrofizacaoFraccaoDeNutrientesQueAtingemOCompartimentoFinalDeAguaDoce: 0.000189; PotencialDeEutrofizacaoFraccaoDeNutrientesQueAtingemOCompartimentoFinalMarinho: 0.0122; EnergiaRecuperada: 0.00739; ConsumoDeAguaDoce: 0.113; UtilizacaoLiquidaDeAguaDoce: 0.113; ResiduosPerigososEliminados: 0.00221; ResiduosNaoPerigososEliminados: 1.83; MassaTotalDeResiduosRadioactivosEliminados: 0.000394; EnergiaElectricaExportada: 1.55; MateriaisParaRecuperacaoDeEnergia: 0.00739; MateriaisParaReciclagem: 0.0253; UnidadeEPD: 1 m²
Type - IFC.REVIGRÉS-Dados gerais-Wall Covering - Nome: REVIGRÉS-URBAN-BASE-45X45-NAT-HYDRAULIK FOG; TipoProduto: Prensado a seco: grupo BIa UGL | Grés porcelânico técnico; NumeroDeRegistoDAP: EPD-REV-20240006-CCC1-EN; ReferenciaDAP: -; UrlDOP: -
Classification: C3010 (Uniformat)
Pset_QuantityTakeOff - sets with these values: 2
Pset_WallCommon - ExtendToStructure: no; LoadBearing: no
IFC.REVIGRÉS-Dados do fabricante-Wall Covering - Type: Basic Wall: REVIGRÉS-URBAN-BASE-45X45-NAT HYDRAULIK FOG
IFC.REVIGRÉS-Dados de desempenho-Wall Covering - Type: Basic Wall: REVIGRÉS-URBAN-BASE-45X45-NAT HYDRAULIK FOG
IFC.REVIGRÉS-Dados de especificação-Wall Covering - Type: Basic Wall: REVIGRÉS-URBAN-BASE-45X45-NAT HYDRAULIK FOG
IFC.REVIGRÉS-Dados geométricos-Wall Covering - Type: Basic Wall: REVIGRÉS-URBAN-BASE-45X45-NAT HYDRAULIK FOG
IFC.REVIGRÉS-Dados de sustentabilidade-Wall Covering - Type: Basic Wall: REVIGRÉS-URBAN-BASE-45X45-NAT HYDRAULIK FOG

# IfcWallStandardCase: Basic Wall:REVIGRÉS-URBAN-BASE-45X45-NAT HYDRAULIK GRIS, Basic Wall:REVIGRÉS-URBAN-BASE-45X45-NAT HYDRAULIK GRIS:27390
In: Level 1
Type - PredefinedType: STANDARD; Material: REVIGRÉS-URBAN-BASE-45X45-NAT-HYDRAULIK GRIS 8.5 mm
Type - Pset_ElementShading - Roughness: 304.8 mm
Type - Pset_ManufacturerTypeInformation - Manufacturer: REVIGRÉS
Type - Pset_ProductRequirements - Category: Walls
Type - Pset_QuantityTakeOff - Reference: 31200757T1
Type - Pset_ReinforcementBarPitchOfWall - Reference: 31200757T1
Type - Pset_WallCommon - IsExternal: no; Reference: 31200757T1
Type - IFC.REVIGRÉS-Dados do fabricante-Wall Covering - FabricanteURL: https://www.revigres.pt/; ReferenciaModelo: Urban; NumeroGlobalDeItemComercial: 31200757T1; Acabamento: NAT; Material: Grés porcelânico; IdentificadorDoOperadorEconomico: 501840856; UrlFabricanteArtigo: https://www.revigres.pt/colecoes/urban; PaisOrigem: Portugal
Type - IFC.REVIGRÉS-Dados de desempenho-Wall Covering - Rectilinearidade: ± 0.3% máx. ± 1.5 mm; Ortogonalidade: ± 0.3% máx. ± 1.8 mm; PlanaridadeDaSuperficie: ± 0.3% máx. ± 1.8 mm; QualidadeDaSuperficie: Cumpre; AbsorcaoDeAgua: < 0.05%; ModuloDeRuptura: > 45 N/mm²; ResistenciaAFlexao: > 2000 N; ResistenciaAAbrasaoProfunda: < 120 mm³; DilatacaoTermicaLinear: ≤ 8,0x10-6 °C-1; ResistenciaAoChoqueTermico: Resiste; DurabilidadeResistenciaAoGeloDegelo: Resiste; ResistenciaAoEscorregamentoDIN51130: R9; ResistenciaAoEscorregamentoDIN51097: A; ResistenciaAoEscorregamentoENV51097: A; ResistenciaAoEscorregamentoENV12633: Class 1; ResistenciaAoEscorregamentoANSIA1371: ≥0,42; ResistenciaAoDeslizamentoENV12633: Class 1; ResistenciaAsManchas: Class 5; ResistenciaABaixasConcentracoesDeAcidosEAlcalis: Classe LA; ResistenciaAAltasConcentracoesDeAcidosEAlcalis: Classe HA; LibertacaoDeCadmio: 0; LibertacaoDeChumbo: 0
Type - IFC.REVIGRÉS-Dados de especificação-Wall Covering - VariacaoTonalidade: 3; NivelDeTrafego: 4; EPavimento: Sim; ERevestimento: Sim; EExterno: Sim
Type - IFC.REVIGRÉS-Dados geométricos-Wall Covering - AlturaNominal: 8.5 mm; ComprimentoNominal: 45 mm; LarguraNominal: 45 mm
Type - IFC.REVIGRÉS-Dados de sustentabilidade-Wall Covering - PotencialPrivacaoDeAguaConsumoDeAguaPonderado: 4.5; EnergiaTermicaExportada: 0; ItemENovo: Sim; ItemEParcialmenteReciclado: 0.23; ItemEReciclado: Sim; VidaÚtilEsperada: 50; SubstanciasPerigosas: Não; PotencialDeEsgotamentoAbioticoDosRecursosFosseis: 203; PotencialDeEsgotamentoAbioticoDosRecursosNaoFosseisMineraisEMetais: 0.000701; PotencialDeAquecimentoGlobalBiogenico: -0.48; CombustiveisFosseisComPotencialDeAquecimentoGlobal: 13.9; PotencialDeAquecimentoGlobalUsoDoSoloEMudancaDeUsoDoSolo: 0.0246; PotencialDeEutrofizacaoFraccaoDeNutrientesQueAtingemOCompartimentoFinalDeAguaDoce: 0.000189; PotencialDeEutrofizacaoFraccaoDeNutrientesQueAtingemOCompartimentoFinalMarinho: 0.0122; EnergiaRecuperada: 0.00739; ConsumoDeAguaDoce: 0.113; UtilizacaoLiquidaDeAguaDoce: 0.113; ResiduosPerigososEliminados: 0.00221; ResiduosNaoPerigososEliminados: 1.83; MassaTotalDeResiduosRadioactivosEliminados: 0.000394; EnergiaElectricaExportada: 1.55; MateriaisParaRecuperacaoDeEnergia: 0.00739; MateriaisParaReciclagem: 0.0253; UnidadeEPD: 1 m²
Type - IFC.REVIGRÉS-Dados gerais-Wall Covering - Nome: REVIGRÉS-URBAN-BASE-45X45-NAT-HYDRAULIK GRIS; TipoProduto: Prensado a seco: grupo BIa UGL | Grés porcelânico técnico; NumeroDeRegistoDAP: EPD-REV-20240006-CCC1-EN; ReferenciaDAP: -; UrlDOP: -
Classification: C3010 (Uniformat)
Pset_QuantityTakeOff - sets with these values: 2
Pset_WallCommon - ExtendToStructure: no; LoadBearing: no
IFC.REVIGRÉS-Dados do fabricante-Wall Covering - Type: Basic Wall: REVIGRÉS-URBAN-BASE-45X45-NAT HYDRAULIK GRIS
IFC.REVIGRÉS-Dados de desempenho-Wall Covering - Type: Basic Wall: REVIGRÉS-URBAN-BASE-45X45-NAT HYDRAULIK GRIS
IFC.REVIGRÉS-Dados de especificação-Wall Covering - Type: Basic Wall: REVIGRÉS-URBAN-BASE-45X45-NAT HYDRAULIK GRIS
IFC.REVIGRÉS-Dados geométricos-Wall Covering - Type: Basic Wall: REVIGRÉS-URBAN-BASE-45X45-NAT HYDRAULIK GRIS
IFC.REVIGRÉS-Dados de sustentabilidade-Wall Covering - Type: Basic Wall: REVIGRÉS-URBAN-BASE-45X45-NAT HYDRAULIK GRIS

# IfcWallStandardCase: Basic Wall:REVIGRÉS-URBAN-BASE-45X45-NAT HYDRAULIK OFFWHITE, Basic Wall:REVIGRÉS-URBAN-BASE-45X45-NAT HYDRAULIK OFFWHITE:27406
In: Level 1
Type - PredefinedType: STANDARD; Material: REVIGRÉS-URBAN-BASE-45X45-NAT-HYDRAULIK OFFWHITE 8.5 mm
Type - Pset_ElementShading - Roughness: 304.8 mm
Type - Pset_ManufacturerTypeInformation - Manufacturer: REVIGRÉS
Type - Pset_ProductRequirements - Category: Walls
Type - Pset_QuantityTakeOff - Reference: 31200758T1
Type - Pset_ReinforcementBarPitchOfWall - Reference: 31200758T1
Type - Pset_WallCommon - IsExternal: no; Reference: 31200758T1
Type - IFC.REVIGRÉS-Dados do fabricante-Wall Covering - FabricanteURL: https://www.revigres.pt/; ReferenciaModelo: Urban; NumeroGlobalDeItemComercial: 31200758T1; Acabamento: NAT; Material: Grés porcelânico; IdentificadorDoOperadorEconomico: 501840856; UrlFabricanteArtigo: https://www.revigres.pt/colecoes/urban; PaisOrigem: Portugal
Type - IFC.REVIGRÉS-Dados de desempenho-Wall Covering - Rectilinearidade: ± 0.3% máx. ± 1.5 mm; Ortogonalidade: ± 0.3% máx. ± 1.8 mm; PlanaridadeDaSuperficie: ± 0.3% máx. ± 1.8 mm; QualidadeDaSuperficie: Cumpre; AbsorcaoDeAgua: < 0.05%; ModuloDeRuptura: > 45 N/mm²; ResistenciaAFlexao: > 2000 N; ResistenciaAAbrasaoProfunda: < 120 mm³; DilatacaoTermicaLinear: ≤ 8,0x10-6 °C-1; ResistenciaAoChoqueTermico: Resiste; DurabilidadeResistenciaAoGeloDegelo: Resiste; ResistenciaAoEscorregamentoDIN51130: R9; ResistenciaAoEscorregamentoDIN51097: A; ResistenciaAoEscorregamentoENV51097: A; ResistenciaAoEscorregamentoENV12633: Class 1; ResistenciaAoEscorregamentoANSIA1371: ≥0,42; ResistenciaAoDeslizamentoENV12633: Class 1; ResistenciaAsManchas: Class 5; ResistenciaABaixasConcentracoesDeAcidosEAlcalis: Classe LA; ResistenciaAAltasConcentracoesDeAcidosEAlcalis: Classe HA; LibertacaoDeCadmio: 0; LibertacaoDeChumbo: 0
Type - IFC.REVIGRÉS-Dados de especificação-Wall Covering - VariacaoTonalidade: 3; NivelDeTrafego: 4; EPavimento: Sim; ERevestimento: Sim; EExterno: Sim
Type - IFC.REVIGRÉS-Dados geométricos-Wall Covering - AlturaNominal: 8.5 mm; ComprimentoNominal: 45 mm; LarguraNominal: 45 mm
Type - IFC.REVIGRÉS-Dados de sustentabilidade-Wall Covering - PotencialPrivacaoDeAguaConsumoDeAguaPonderado: 4.5; EnergiaTermicaExportada: 0; ItemENovo: Sim; ItemEParcialmenteReciclado: 0.03; ItemEReciclado: Sim; VidaÚtilEsperada: 50; SubstanciasPerigosas: Não; PotencialDeEsgotamentoAbioticoDosRecursosFosseis: 203; PotencialDeEsgotamentoAbioticoDosRecursosNaoFosseisMineraisEMetais: 0.000701; PotencialDeAquecimentoGlobalBiogenico: -0.48; CombustiveisFosseisComPotencialDeAquecimentoGlobal: 13.9; PotencialDeAquecimentoGlobalUsoDoSoloEMudancaDeUsoDoSolo: 0.0246; PotencialDeEutrofizacaoFraccaoDeNutrientesQueAtingemOCompartimentoFinalDeAguaDoce: 0.000189; PotencialDeEutrofizacaoFraccaoDeNutrientesQueAtingemOCompartimentoFinalMarinho: 0.0122; EnergiaRecuperada: 0.00739; ConsumoDeAguaDoce: 0.113; UtilizacaoLiquidaDeAguaDoce: 0.113; ResiduosPerigososEliminados: 0.00221; ResiduosNaoPerigososEliminados: 1.83; MassaTotalDeResiduosRadioactivosEliminados: 0.000394; EnergiaElectricaExportada: 1.55; MateriaisParaRecuperacaoDeEnergia: 0.00739; MateriaisParaReciclagem: 0.0253; UnidadeEPD: 1 m²
Type - IFC.REVIGRÉS-Dados gerais-Wall Covering - Nome: REVIGRÉS-URBAN-BASE-45X45-NAT-HYDRAULIK OFFWHITE; TipoProduto: Prensado a seco: grupo BIa UGL | Grés porcelânico técnico; NumeroDeRegistoDAP: EPD-REV-20240006-CCC1-EN; ReferenciaDAP: -; UrlDOP: -
Classification: C3010 (Uniformat)
Pset_QuantityTakeOff - sets with these values: 2
Pset_WallCommon - ExtendToStructure: no; LoadBearing: no
IFC.REVIGRÉS-Dados do fabricante-Wall Covering - Type: Basic Wall: REVIGRÉS-URBAN-BASE-45X45-NAT HYDRAULIK OFFWHITE
IFC.REVIGRÉS-Dados de desempenho-Wall Covering - Type: Basic Wall: REVIGRÉS-URBAN-BASE-45X45-NAT HYDRAULIK OFFWHITE
IFC.REVIGRÉS-Dados de especificação-Wall Covering - Type: Basic Wall: REVIGRÉS-URBAN-BASE-45X45-NAT HYDRAULIK OFFWHITE
IFC.REVIGRÉS-Dados geométricos-Wall Covering - Type: Basic Wall: REVIGRÉS-URBAN-BASE-45X45-NAT HYDRAULIK OFFWHITE
IFC.REVIGRÉS-Dados de sustentabilidade-Wall Covering - Type: Basic Wall: REVIGRÉS-URBAN-BASE-45X45-NAT HYDRAULIK OFFWHITE

# IfcWallStandardCase: Basic Wall:REVIGRÉS-URBAN-BASE-45X45-NAT-ANTRACITE, Basic Wall:REVIGRÉS-URBAN-BASE-45X45-NAT-ANTRACITE:22707
In: Level 1
Type - PredefinedType: STANDARD; Material: REVIGRÉS-URBAN-BASE-45X45-NAT-ANTRACITE 8.5 mm
Type - Pset_ElementShading - Roughness: 304.8 mm
Type - Pset_ManufacturerTypeInformation - Manufacturer: REVIGRÉS
Type - Pset_ProductRequirements - Category: Walls
Type - Pset_QuantityTakeOff - Reference: 31200748U1
Type - Pset_ReinforcementBarPitchOfWall - Reference: 31200748U1
Type - Pset_WallCommon - IsExternal: no; Reference: 31200748U1
Type - IFC.REVIGRÉS-Dados do fabricante-Wall Covering - FabricanteURL: https://www.revigres.pt/; ReferenciaModelo: Urban; NumeroGlobalDeItemComercial: 31200748U1; Acabamento: NAT; Material: Grés porcelânico; IdentificadorDoOperadorEconomico: 501840856; UrlFabricanteArtigo: https://www.revigres.pt/colecoes/urban; PaisOrigem: Portugal
Type - IFC.REVIGRÉS-Dados de desempenho-Wall Covering - Rectilinearidade: ± 0.3% máx. ± 1.5 mm; Ortogonalidade: ± 0.3% máx. ± 1.8 mm; PlanaridadeDaSuperficie: ± 0.3% máx. ± 1.8 mm; QualidadeDaSuperficie: Cumpre; AbsorcaoDeAgua: < 0.05%; ModuloDeRuptura: > 45 N/mm²; ResistenciaAFlexao: > 2000 N; ResistenciaAAbrasaoProfunda: < 120 mm³; DilatacaoTermicaLinear: ≤ 8,0x10-6 °C-1; ResistenciaAoChoqueTermico: Resiste; DurabilidadeResistenciaAoGeloDegelo: Resiste; ResistenciaAoEscorregamentoDIN51130: R9; ResistenciaAoEscorregamentoDIN51097: A; ResistenciaAoEscorregamentoENV51097: A; ResistenciaAoEscorregamentoENV12633: Class 1; ResistenciaAoEscorregamentoANSIA1371: ≥0,42; ResistenciaAoDeslizamentoENV12633: Class 1; ResistenciaAsManchas: Class 5; ResistenciaABaixasConcentracoesDeAcidosEAlcalis: Classe LA; ResistenciaAAltasConcentracoesDeAcidosEAlcalis: Classe HA; LibertacaoDeCadmio: 0; LibertacaoDeChumbo: 0
Type - IFC.REVIGRÉS-Dados de especificação-Wall Covering - VariacaoTonalidade: 2; NivelDeTrafego: 5; EPavimento: Sim; ERevestimento: Sim; EExterno: Sim
Type - IFC.REVIGRÉS-Dados geométricos-Wall Covering - AlturaNominal: 8.5 mm; ComprimentoNominal: 45 mm; LarguraNominal: 45 mm
Type - IFC.REVIGRÉS-Dados de sustentabilidade-Wall Covering - PotencialPrivacaoDeAguaConsumoDeAguaPonderado: 4.5; EnergiaTermicaExportada: 0; ItemENovo: Sim; ItemEParcialmenteReciclado: 0.29; ItemEReciclado: Sim; VidaÚtilEsperada: 50; SubstanciasPerigosas: Não; PotencialDeEsgotamentoAbioticoDosRecursosFosseis: 203; PotencialDeEsgotamentoAbioticoDosRecursosNaoFosseisMineraisEMetais: 0.000701; PotencialDeAquecimentoGlobalBiogenico: -0.48; CombustiveisFosseisComPotencialDeAquecimentoGlobal: 13.9; PotencialDeAquecimentoGlobalUsoDoSoloEMudancaDeUsoDoSolo: 0.0246; PotencialDeEutrofizacaoFraccaoDeNutrientesQueAtingemOCompartimentoFinalDeAguaDoce: 0.000189; PotencialDeEutrofizacaoFraccaoDeNutrientesQueAtingemOCompartimentoFinalMarinho: 0.0122; EnergiaRecuperada: 0.00739; ConsumoDeAguaDoce: 0.113; UtilizacaoLiquidaDeAguaDoce: 0.113; ResiduosPerigososEliminados: 0.00221; ResiduosNaoPerigososEliminados: 1.83; MassaTotalDeResiduosRadioactivosEliminados: 0.000394; EnergiaElectricaExportada: 1.55; MateriaisParaRecuperacaoDeEnergia: 0.00739; MateriaisParaReciclagem: 0.0253; UnidadeEPD: 1 m²
Type - IFC.REVIGRÉS-Dados gerais-Wall Covering - Nome: REVIGRÉS-URBAN-BASE-45X45-NAT-URBAN ANTRACITE; TipoProduto: Prensado a seco: grupo BIa UGL | Grés porcelânico técnico; NumeroDeRegistoDAP: EPD-REV-20240006-CCC1-EN; ReferenciaDAP: -; UrlDOP: -
Classification: C3010 (Uniformat)
Pset_QuantityTakeOff - sets with these values: 2
Pset_WallCommon - ExtendToStructure: no; LoadBearing: no
IFC.REVIGRÉS-Dados do fabricante-Wall Covering - Type: Basic Wall: REVIGRÉS-URBAN-BASE-45X45-NAT-ANTRACITE
IFC.REVIGRÉS-Dados de desempenho-Wall Covering - Type: Basic Wall: REVIGRÉS-URBAN-BASE-45X45-NAT-ANTRACITE
IFC.REVIGRÉS-Dados de especificação-Wall Covering - Type: Basic Wall: REVIGRÉS-URBAN-BASE-45X45-NAT-ANTRACITE
IFC.REVIGRÉS-Dados geométricos-Wall Covering - Type: Basic Wall: REVIGRÉS-URBAN-BASE-45X45-NAT-ANTRACITE
IFC.REVIGRÉS-Dados de sustentabilidade-Wall Covering - Type: Basic Wall: REVIGRÉS-URBAN-BASE-45X45-NAT-ANTRACITE

# IfcWallStandardCase: Basic Wall:REVIGRÉS-URBAN-BASE-45X45-NAT-BONE, Basic Wall:REVIGRÉS-URBAN-BASE-45X45-NAT-BONE:22723
In: Level 1
Type - PredefinedType: STANDARD; Material: REVIGRÉS-URBAN-BASE-45X45-NAT-BONE 8.5 mm
Type - Pset_ElementShading - Roughness: 304.8 mm
Type - Pset_ManufacturerTypeInformation - Manufacturer: REVIGRÉS
Type - Pset_ProductRequirements - Category: Walls
Type - Pset_QuantityTakeOff - Reference: 31200720T1
Type - Pset_ReinforcementBarPitchOfWall - Reference: 31200720T1
Type - Pset_WallCommon - IsExternal: no; Reference: 31200720T1
Type - IFC.REVIGRÉS-Dados do fabricante-Wall Covering - FabricanteURL: https://www.revigres.pt/; ReferenciaModelo: Urban; NumeroGlobalDeItemComercial: 31200720T1; Acabamento: NAT; Material: Grés porcelânico; IdentificadorDoOperadorEconomico: 501840856; UrlFabricanteArtigo: https://www.revigres.pt/colecoes/urban; PaisOrigem: Portugal
Type - IFC.REVIGRÉS-Dados de desempenho-Wall Covering - Rectilinearidade: ± 0.3% máx. ± 1.5 mm; Ortogonalidade: ± 0.3% máx. ± 1.8 mm; PlanaridadeDaSuperficie: ± 0.3% máx. ± 1.8 mm; QualidadeDaSuperficie: Cumpre; AbsorcaoDeAgua: < 0.05%; ModuloDeRuptura: > 45 N/mm²; ResistenciaAFlexao: > 2000 N; ResistenciaAAbrasaoProfunda: < 120 mm³; DilatacaoTermicaLinear: ≤ 8,0x10-6 °C-1; ResistenciaAoChoqueTermico: Resiste; DurabilidadeResistenciaAoGeloDegelo: Resiste; ResistenciaAoEscorregamentoDIN51130: R9; ResistenciaAoEscorregamentoDIN51097: A; ResistenciaAoEscorregamentoENV51097: A; ResistenciaAoEscorregamentoENV12633: Class 1; ResistenciaAoEscorregamentoANSIA1371: ≥0,42; ResistenciaAoDeslizamentoENV12633: Class 1; ResistenciaAsManchas: Class 5; ResistenciaABaixasConcentracoesDeAcidosEAlcalis: Classe LA; ResistenciaAAltasConcentracoesDeAcidosEAlcalis: Classe HA; LibertacaoDeCadmio: 0; LibertacaoDeChumbo: 0
Type - IFC.REVIGRÉS-Dados de especificação-Wall Covering - VariacaoTonalidade: 2; NivelDeTrafego: 5; EPavimento: Sim; ERevestimento: Sim; EExterno: Sim
Type - IFC.REVIGRÉS-Dados geométricos-Wall Covering - AlturaNominal: 8.5 mm; ComprimentoNominal: 45 mm; LarguraNominal: 45 mm
Type - IFC.REVIGRÉS-Dados de sustentabilidade-Wall Covering - PotencialPrivacaoDeAguaConsumoDeAguaPonderado: 4.5; EnergiaTermicaExportada: 0; ItemENovo: Sim; ItemEParcialmenteReciclado: 0.03; ItemEReciclado: Sim; VidaÚtilEsperada: 50; SubstanciasPerigosas: Não; PotencialDeEsgotamentoAbioticoDosRecursosFosseis: 203; PotencialDeEsgotamentoAbioticoDosRecursosNaoFosseisMineraisEMetais: 0.000701; PotencialDeAquecimentoGlobalBiogenico: -0.48; CombustiveisFosseisComPotencialDeAquecimentoGlobal: 13.9; PotencialDeAquecimentoGlobalUsoDoSoloEMudancaDeUsoDoSolo: 0.0246; PotencialDeEutrofizacaoFraccaoDeNutrientesQueAtingemOCompartimentoFinalDeAguaDoce: 0.000189; PotencialDeEutrofizacaoFraccaoDeNutrientesQueAtingemOCompartimentoFinalMarinho: 0.0122; EnergiaRecuperada: 0.00739; ConsumoDeAguaDoce: 0.113; UtilizacaoLiquidaDeAguaDoce: 0.113; ResiduosPerigososEliminados: 0.00221; ResiduosNaoPerigososEliminados: 1.83; MassaTotalDeResiduosRadioactivosEliminados: 0.000394; EnergiaElectricaExportada: 1.55; MateriaisParaRecuperacaoDeEnergia: 0.00739; MateriaisParaReciclagem: 0.0253; UnidadeEPD: 1 m²
Type - IFC.REVIGRÉS-Dados gerais-Wall Covering - Nome: REVIGRÉS-URBAN-BASE-45X45-NAT-URBAN BONE; TipoProduto: Prensado a seco: grupo BIa UGL | Grés porcelânico técnico; NumeroDeRegistoDAP: EPD-REV-20240006-CCC1-EN; ReferenciaDAP: -; UrlDOP: -
Classification: C3010 (Uniformat)
Pset_QuantityTakeOff - sets with these values: 2
Pset_WallCommon - ExtendToStructure: no; LoadBearing: no
IFC.REVIGRÉS-Dados do fabricante-Wall Covering - Type: Basic Wall: REVIGRÉS-URBAN-BASE-45X45-NAT-BONE
IFC.REVIGRÉS-Dados de desempenho-Wall Covering - Type: Basic Wall: REVIGRÉS-URBAN-BASE-45X45-NAT-BONE
IFC.REVIGRÉS-Dados de especificação-Wall Covering - Type: Basic Wall: REVIGRÉS-URBAN-BASE-45X45-NAT-BONE
IFC.REVIGRÉS-Dados geométricos-Wall Covering - Type: Basic Wall: REVIGRÉS-URBAN-BASE-45X45-NAT-BONE
IFC.REVIGRÉS-Dados de sustentabilidade-Wall Covering - Type: Basic Wall: REVIGRÉS-URBAN-BASE-45X45-NAT-BONE

# IfcWallStandardCase: Basic Wall:REVIGRÉS-URBAN-BASE-45X45-NAT-CRAFT, Basic Wall:REVIGRÉS-URBAN-BASE-45X45-NAT-CRAFT:22739
In: Level 1
Type - PredefinedType: STANDARD; Material: REVIGRÉS-URBAN-BASE-45X45-NAT-CRAFT 8.5 mm
Type - Pset_ElementShading - Roughness: 304.8 mm
Type - Pset_ManufacturerTypeInformation - Manufacturer: REVIGRÉS
Type - Pset_ProductRequirements - Category: Walls
Type - Pset_QuantityTakeOff - Reference: 31200724T1
Type - Pset_ReinforcementBarPitchOfWall - Reference: 31200724T1
Type - Pset_WallCommon - IsExternal: no; Reference: 31200724T1
Type - IFC.REVIGRÉS-Dados do fabricante-Wall Covering - FabricanteURL: https://www.revigres.pt/; ReferenciaModelo: Urban; NumeroGlobalDeItemComercial: 31200724T1; Acabamento: NAT; Material: Grés porcelânico; IdentificadorDoOperadorEconomico: 501840856; UrlFabricanteArtigo: https://www.revigres.pt/colecoes/urban; PaisOrigem: Portugal
Type - IFC.REVIGRÉS-Dados de desempenho-Wall Covering - Rectilinearidade: ± 0.3% máx. ± 1.5 mm; Ortogonalidade: ± 0.3% máx. ± 1.8 mm; PlanaridadeDaSuperficie: ± 0.3% máx. ± 1.8 mm; QualidadeDaSuperficie: Cumpre; AbsorcaoDeAgua: < 0.05%; ModuloDeRuptura: > 45 N/mm²; ResistenciaAFlexao: > 2000 N; ResistenciaAAbrasaoProfunda: < 120 mm³; DilatacaoTermicaLinear: ≤ 8,0x10-6 °C-1; ResistenciaAoChoqueTermico: Resiste; DurabilidadeResistenciaAoGeloDegelo: Resiste; ResistenciaAoEscorregamentoDIN51130: R9; ResistenciaAoEscorregamentoDIN51097: A; ResistenciaAoEscorregamentoENV51097: A; ResistenciaAoEscorregamentoENV12633: Class 1; ResistenciaAoEscorregamentoANSIA1371: ≥0,42; ResistenciaAoDeslizamentoENV12633: Class 1; ResistenciaAsManchas: Class 5; ResistenciaABaixasConcentracoesDeAcidosEAlcalis: Classe LA; ResistenciaAAltasConcentracoesDeAcidosEAlcalis: Classe HA; LibertacaoDeCadmio: 0; LibertacaoDeChumbo: 0
Type - IFC.REVIGRÉS-Dados de especificação-Wall Covering - VariacaoTonalidade: 2; NivelDeTrafego: 5; EPavimento: Sim; ERevestimento: Sim; EExterno: Sim
Type - IFC.REVIGRÉS-Dados geométricos-Wall Covering - AlturaNominal: 8.5 mm; ComprimentoNominal: 45 mm; LarguraNominal: 45 mm
Type - IFC.REVIGRÉS-Dados de sustentabilidade-Wall Covering - PotencialPrivacaoDeAguaConsumoDeAguaPonderado: 4.5; EnergiaTermicaExportada: 0; ItemENovo: Sim; ItemEParcialmenteReciclado: 0.19; ItemEReciclado: Sim; VidaÚtilEsperada: 50; SubstanciasPerigosas: Não; PotencialDeEsgotamentoAbioticoDosRecursosFosseis: 203; PotencialDeEsgotamentoAbioticoDosRecursosNaoFosseisMineraisEMetais: 0.000701; PotencialDeAquecimentoGlobalBiogenico: -0.48; CombustiveisFosseisComPotencialDeAquecimentoGlobal: 13.9; PotencialDeAquecimentoGlobalUsoDoSoloEMudancaDeUsoDoSolo: 0.0246; PotencialDeEutrofizacaoFraccaoDeNutrientesQueAtingemOCompartimentoFinalDeAguaDoce: 0.000189; PotencialDeEutrofizacaoFraccaoDeNutrientesQueAtingemOCompartimentoFinalMarinho: 0.0122; EnergiaRecuperada: 0.00739; ConsumoDeAguaDoce: 0.113; UtilizacaoLiquidaDeAguaDoce: 0.113; ResiduosPerigososEliminados: 0.00221; ResiduosNaoPerigososEliminados: 1.83; MassaTotalDeResiduosRadioactivosEliminados: 0.000394; EnergiaElectricaExportada: 1.55; MateriaisParaRecuperacaoDeEnergia: 0.00739; MateriaisParaReciclagem: 0.0253; UnidadeEPD: 1 m²
Type - IFC.REVIGRÉS-Dados gerais-Wall Covering - Nome: REVIGRÉS-URBAN-BASE-45X45-NAT-URBAN CRAFT; TipoProduto: Prensado a seco: grupo BIa UGL | Grés porcelânico técnico; NumeroDeRegistoDAP: EPD-REV-20240006-CCC1-EN; ReferenciaDAP: -; UrlDOP: -
Classification: C3010 (Uniformat)
Pset_QuantityTakeOff - sets with these values: 2
Pset_WallCommon - ExtendToStructure: no; LoadBearing: no
IFC.REVIGRÉS-Dados do fabricante-Wall Covering - Type: Basic Wall: REVIGRÉS-URBAN-BASE-45X45-NAT-CRAFT
IFC.REVIGRÉS-Dados de desempenho-Wall Covering - Type: Basic Wall: REVIGRÉS-URBAN-BASE-45X45-NAT-CRAFT
IFC.REVIGRÉS-Dados de especificação-Wall Covering - Type: Basic Wall: REVIGRÉS-URBAN-BASE-45X45-NAT-CRAFT
IFC.REVIGRÉS-Dados geométricos-Wall Covering - Type: Basic Wall: REVIGRÉS-URBAN-BASE-45X45-NAT-CRAFT
IFC.REVIGRÉS-Dados de sustentabilidade-Wall Covering - Type: Basic Wall: REVIGRÉS-URBAN-BASE-45X45-NAT-CRAFT

# IfcWallStandardCase: Basic Wall:REVIGRÉS-URBAN-BASE-45X45-NAT-FOG, Basic Wall:REVIGRÉS-URBAN-BASE-45X45-NAT-FOG:22755
In: Level 1
Type - PredefinedType: STANDARD; Material: REVIGRÉS-URBAN-BASE-45X45-NAT-FOG 8.5 mm
Type - Pset_ElementShading - Roughness: 304.8 mm
Type - Pset_ManufacturerTypeInformation - Manufacturer: REVIGRÉS
Type - Pset_ProductRequirements - Category: Walls
Type - Pset_QuantityTakeOff - Reference: 31200721T1
Type - Pset_ReinforcementBarPitchOfWall - Reference: 31200721T1
Type - Pset_WallCommon - IsExternal: no; Reference: 31200721T1
Type - IFC.REVIGRÉS-Dados do fabricante-Wall Covering - FabricanteURL: https://www.revigres.pt/; ReferenciaModelo: Urban; NumeroGlobalDeItemComercial: 31200721T1; Acabamento: NAT; Material: Grés porcelânico; IdentificadorDoOperadorEconomico: 501840856; UrlFabricanteArtigo: https://www.revigres.pt/colecoes/urban; PaisOrigem: Portugal
Type - IFC.REVIGRÉS-Dados de desempenho-Wall Covering - Rectilinearidade: ± 0.3% máx. ± 1.5 mm; Ortogonalidade: ± 0.3% máx. ± 1.8 mm; PlanaridadeDaSuperficie: ± 0.3% máx. ± 1.8 mm; QualidadeDaSuperficie: Cumpre; AbsorcaoDeAgua: < 0.05%; ModuloDeRuptura: > 45 N/mm²; ResistenciaAFlexao: > 2000 N; ResistenciaAAbrasaoProfunda: < 120 mm³; DilatacaoTermicaLinear: ≤ 8,0x10-6 °C-1; ResistenciaAoChoqueTermico: Resiste; DurabilidadeResistenciaAoGeloDegelo: Resiste; ResistenciaAoEscorregamentoDIN51130: R9; ResistenciaAoEscorregamentoDIN51097: A; ResistenciaAoEscorregamentoENV51097: A; ResistenciaAoEscorregamentoENV12633: Class 1; ResistenciaAoEscorregamentoANSIA1371: ≥0,42; ResistenciaAoDeslizamentoENV12633: Class 1; ResistenciaAsManchas: Class 5; ResistenciaABaixasConcentracoesDeAcidosEAlcalis: Classe LA; ResistenciaAAltasConcentracoesDeAcidosEAlcalis: Classe HA; LibertacaoDeCadmio: 0; LibertacaoDeChumbo: 0
Type - IFC.REVIGRÉS-Dados de especificação-Wall Covering - VariacaoTonalidade: 2; NivelDeTrafego: 5; EPavimento: Sim; ERevestimento: Sim; EExterno: Sim
Type - IFC.REVIGRÉS-Dados geométricos-Wall Covering - AlturaNominal: 8.5 mm; ComprimentoNominal: 45 mm; LarguraNominal: 45 mm
Type - IFC.REVIGRÉS-Dados de sustentabilidade-Wall Covering - PotencialPrivacaoDeAguaConsumoDeAguaPonderado: 4.5; EnergiaTermicaExportada: 0; ItemENovo: Sim; ItemEParcialmenteReciclado: 0.23; ItemEReciclado: Sim; VidaÚtilEsperada: 50; SubstanciasPerigosas: Não; PotencialDeEsgotamentoAbioticoDosRecursosFosseis: 203; PotencialDeEsgotamentoAbioticoDosRecursosNaoFosseisMineraisEMetais: 0.000701; PotencialDeAquecimentoGlobalBiogenico: -0.48; CombustiveisFosseisComPotencialDeAquecimentoGlobal: 13.9; PotencialDeAquecimentoGlobalUsoDoSoloEMudancaDeUsoDoSolo: 0.0246; PotencialDeEutrofizacaoFraccaoDeNutrientesQueAtingemOCompartimentoFinalDeAguaDoce: 0.000189; PotencialDeEutrofizacaoFraccaoDeNutrientesQueAtingemOCompartimentoFinalMarinho: 0.0122; EnergiaRecuperada: 0.00739; ConsumoDeAguaDoce: 0.113; UtilizacaoLiquidaDeAguaDoce: 0.113; ResiduosPerigososEliminados: 0.00221; ResiduosNaoPerigososEliminados: 1.83; MassaTotalDeResiduosRadioactivosEliminados: 0.000394; EnergiaElectricaExportada: 1.55; MateriaisParaRecuperacaoDeEnergia: 0.00739; MateriaisParaReciclagem: 0.0253; UnidadeEPD: 1 m²
Type - IFC.REVIGRÉS-Dados gerais-Wall Covering - Nome: REVIGRÉS-URBAN-BASE-45X45-NAT-URBAN FOG; TipoProduto: Prensado a seco: grupo BIa UGL | Grés porcelânico técnico; NumeroDeRegistoDAP: EPD-REV-20240006-CCC1-EN; ReferenciaDAP: -; UrlDOP: -
Classification: C3010 (Uniformat)
Pset_QuantityTakeOff - sets with these values: 2
Pset_WallCommon - ExtendToStructure: no; LoadBearing: no
IFC.REVIGRÉS-Dados do fabricante-Wall Covering - Type: Basic Wall: REVIGRÉS-URBAN-BASE-45X45-NAT-FOG
IFC.REVIGRÉS-Dados de desempenho-Wall Covering - Type: Basic Wall: REVIGRÉS-URBAN-BASE-45X45-NAT-FOG
IFC.REVIGRÉS-Dados de especificação-Wall Covering - Type: Basic Wall: REVIGRÉS-URBAN-BASE-45X45-NAT-FOG
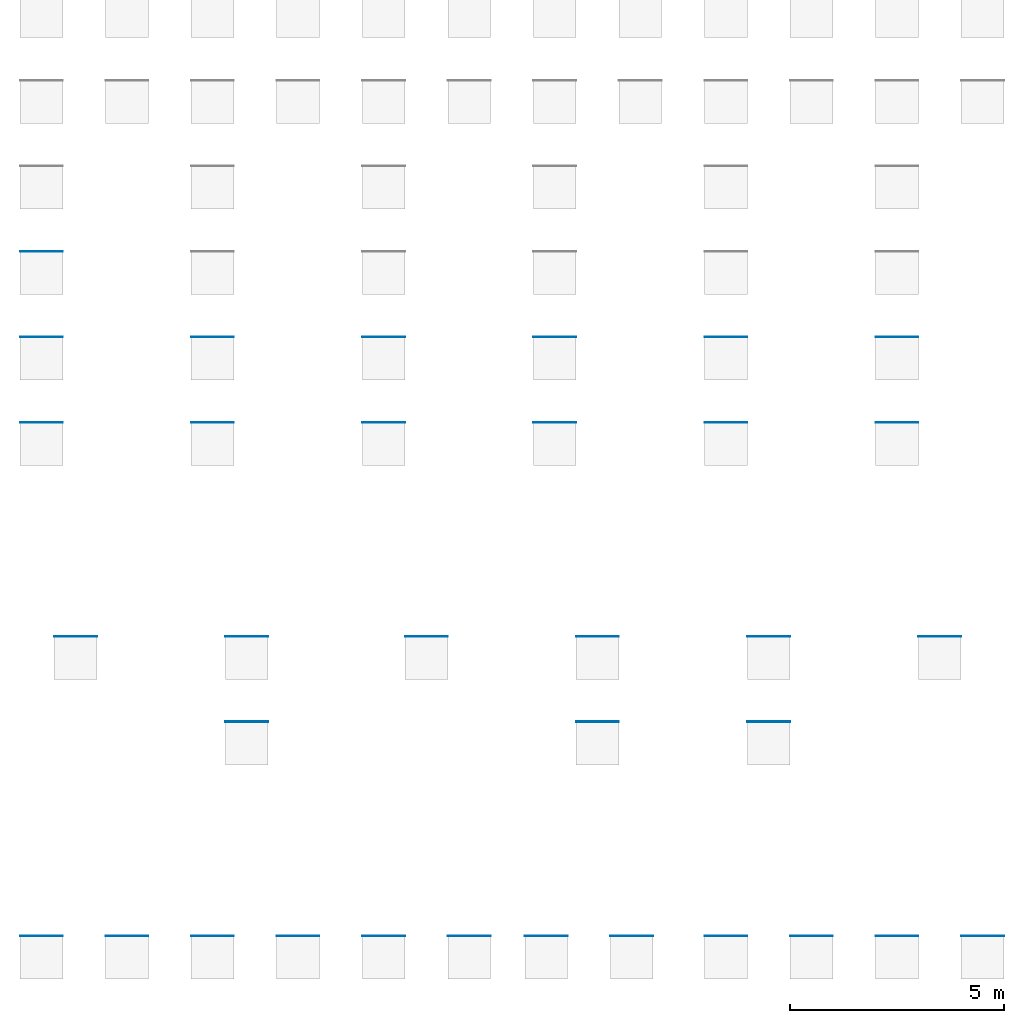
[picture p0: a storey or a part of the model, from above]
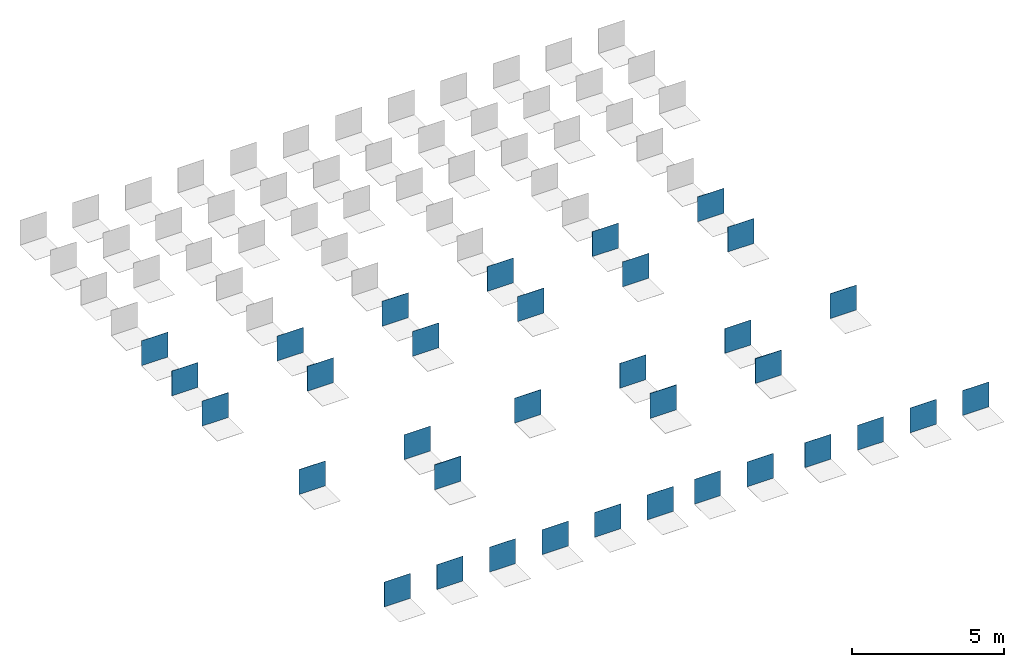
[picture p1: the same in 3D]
Properties of the parts of a building model (IFC2X3), part 10 of 12

# IfcWallStandardCase: Basic Wall:REVIGRÉS-URBAN-BASE-45X45-NAT-FOG, Basic Wall:REVIGRÉS-URBAN-BASE-45X45-NAT-FOG:22755
IFC.REVIGRÉS-Dados geométricos-Wall Covering - Type: Basic Wall: REVIGRÉS-URBAN-BASE-45X45-NAT-FOG
IFC.REVIGRÉS-Dados de sustentabilidade-Wall Covering - Type: Basic Wall: REVIGRÉS-URBAN-BASE-45X45-NAT-FOG

# IfcWallStandardCase: Basic Wall:REVIGRÉS-URBAN-BASE-45X45-NAT-GRIS, Basic Wall:REVIGRÉS-URBAN-BASE-45X45-NAT-GRIS:22771
In: Level 1
Type - PredefinedType: STANDARD; Material: REVIGRÉS-URBAN-BASE-45X45-NAT-GRIS 8.5 mm
Type - Pset_ElementShading - Roughness: 304.8 mm
Type - Pset_ManufacturerTypeInformation - Manufacturer: REVIGRÉS
Type - Pset_ProductRequirements - Category: Walls
Type - Pset_QuantityTakeOff - Reference: 31200722T1
Type - Pset_ReinforcementBarPitchOfWall - Reference: 31200722T1
Type - Pset_WallCommon - IsExternal: no; Reference: 31200722T1
Type - IFC.REVIGRÉS-Dados do fabricante-Wall Covering - FabricanteURL: https://www.revigres.pt/; ReferenciaModelo: Urban; NumeroGlobalDeItemComercial: 31200722T1; Acabamento: NAT; Material: Grés porcelânico; IdentificadorDoOperadorEconomico: 501840856; UrlFabricanteArtigo: https://www.revigres.pt/colecoes/urban; PaisOrigem: Portugal
Type - IFC.REVIGRÉS-Dados de desempenho-Wall Covering - Rectilinearidade: ± 0.3% máx. ± 1.5 mm; Ortogonalidade: ± 0.3% máx. ± 1.8 mm; PlanaridadeDaSuperficie: ± 0.3% máx. ± 1.8 mm; QualidadeDaSuperficie: Cumpre; AbsorcaoDeAgua: < 0.05%; ModuloDeRuptura: > 45 N/mm²; ResistenciaAFlexao: > 2000 N; ResistenciaAAbrasaoProfunda: < 120 mm³; DilatacaoTermicaLinear: ≤ 8,0x10-6 °C-1; ResistenciaAoChoqueTermico: Resiste; DurabilidadeResistenciaAoGeloDegelo: Resiste; ResistenciaAoEscorregamentoDIN51130: R9; ResistenciaAoEscorregamentoDIN51097: A; ResistenciaAoEscorregamentoENV51097: A; ResistenciaAoEscorregamentoENV12633: Class 1; ResistenciaAoEscorregamentoANSIA1371: ≥0,42; ResistenciaAoDeslizamentoENV12633: Class 1; ResistenciaAsManchas: Class 5; ResistenciaABaixasConcentracoesDeAcidosEAlcalis: Classe LA; ResistenciaAAltasConcentracoesDeAcidosEAlcalis: Classe HA; LibertacaoDeCadmio: 0; LibertacaoDeChumbo: 0
Type - IFC.REVIGRÉS-Dados de especificação-Wall Covering - VariacaoTonalidade: 2; NivelDeTrafego: 5; EPavimento: Sim; ERevestimento: Sim; EExterno: Sim
Type - IFC.REVIGRÉS-Dados geométricos-Wall Covering - AlturaNominal: 8.5 mm; ComprimentoNominal: 45 mm; LarguraNominal: 45 mm
Type - IFC.REVIGRÉS-Dados de sustentabilidade-Wall Covering - PotencialPrivacaoDeAguaConsumoDeAguaPonderado: 4.5; EnergiaTermicaExportada: 0; ItemENovo: Sim; ItemEParcialmenteReciclado: 0.23; ItemEReciclado: Sim; VidaÚtilEsperada: 50; SubstanciasPerigosas: Não; PotencialDeEsgotamentoAbioticoDosRecursosFosseis: 203; PotencialDeEsgotamentoAbioticoDosRecursosNaoFosseisMineraisEMetais: 0.000701; PotencialDeAquecimentoGlobalBiogenico: -0.48; CombustiveisFosseisComPotencialDeAquecimentoGlobal: 13.9; PotencialDeAquecimentoGlobalUsoDoSoloEMudancaDeUsoDoSolo: 0.0246; PotencialDeEutrofizacaoFraccaoDeNutrientesQueAtingemOCompartimentoFinalDeAguaDoce: 0.000189; PotencialDeEutrofizacaoFraccaoDeNutrientesQueAtingemOCompartimentoFinalMarinho: 0.0122; EnergiaRecuperada: 0.00739; ConsumoDeAguaDoce: 0.113; UtilizacaoLiquidaDeAguaDoce: 0.113; ResiduosPerigososEliminados: 0.00221; ResiduosNaoPerigososEliminados: 1.83; MassaTotalDeResiduosRadioactivosEliminados: 0.000394; EnergiaElectricaExportada: 1.55; MateriaisParaRecuperacaoDeEnergia: 0.00739; MateriaisParaReciclagem: 0.0253; UnidadeEPD: 1 m²
Type - IFC.REVIGRÉS-Dados gerais-Wall Covering - Nome: REVIGRÉS-URBAN-BASE-45X45-NAT-URBAN GRIS; TipoProduto: Prensado a seco: grupo BIa UGL | Grés porcelânico técnico; NumeroDeRegistoDAP: EPD-REV-20240006-CCC1-EN; ReferenciaDAP: -; UrlDOP: -
Classification: C3010 (Uniformat)
Pset_QuantityTakeOff - sets with these values: 2
Pset_WallCommon - ExtendToStructure: no; LoadBearing: no
IFC.REVIGRÉS-Dados do fabricante-Wall Covering - Type: Basic Wall: REVIGRÉS-URBAN-BASE-45X45-NAT-GRIS
IFC.REVIGRÉS-Dados de desempenho-Wall Covering - Type: Basic Wall: REVIGRÉS-URBAN-BASE-45X45-NAT-GRIS
IFC.REVIGRÉS-Dados de especificação-Wall Covering - Type: Basic Wall: REVIGRÉS-URBAN-BASE-45X45-NAT-GRIS
IFC.REVIGRÉS-Dados geométricos-Wall Covering - Type: Basic Wall: REVIGRÉS-URBAN-BASE-45X45-NAT-GRIS
IFC.REVIGRÉS-Dados de sustentabilidade-Wall Covering - Type: Basic Wall: REVIGRÉS-URBAN-BASE-45X45-NAT-GRIS

# IfcWallStandardCase: Basic Wall:REVIGRÉS-URBAN-BASE-45X45-NAT-OFFWHITE, Basic Wall:REVIGRÉS-URBAN-BASE-45X45-NAT-OFFWHITE:23729
In: Level 1
Type - PredefinedType: STANDARD; Material: REVIGRÉS-URBAN-BASE-45X45-NAT-OFFWHITE 8.5 mm
Type - Pset_ElementShading - Roughness: 304.8 mm
Type - Pset_ManufacturerTypeInformation - Manufacturer: REVIGRÉS
Type - Pset_ProductRequirements - Category: Walls
Type - Pset_QuantityTakeOff - Reference: 31200723T1
Type - Pset_ReinforcementBarPitchOfWall - Reference: 31200723T1
Type - Pset_WallCommon - IsExternal: no; Reference: 31200723T1
Type - IFC.REVIGRÉS-Dados do fabricante-Wall Covering - FabricanteURL: https://www.revigres.pt/; ReferenciaModelo: Urban; NumeroGlobalDeItemComercial: 31200723T1; Acabamento: NAT; Material: Grés porcelânico; IdentificadorDoOperadorEconomico: 501840856; UrlFabricanteArtigo: https://www.revigres.pt/colecoes/urban; PaisOrigem: Portugal
Type - IFC.REVIGRÉS-Dados de desempenho-Wall Covering - Rectilinearidade: ± 0.3% máx. ± 1.5 mm; Ortogonalidade: ± 0.3% máx. ± 1.8 mm; PlanaridadeDaSuperficie: ± 0.3% máx. ± 1.8 mm; QualidadeDaSuperficie: Cumpre; AbsorcaoDeAgua: < 0.05%; ModuloDeRuptura: > 45 N/mm²; ResistenciaAFlexao: > 2000 N; ResistenciaAAbrasaoProfunda: < 120 mm³; DilatacaoTermicaLinear: ≤ 8,0x10-6 °C-1; ResistenciaAoChoqueTermico: Resiste; DurabilidadeResistenciaAoGeloDegelo: Resiste; ResistenciaAoEscorregamentoDIN51130: R9; ResistenciaAoEscorregamentoDIN51097: A; ResistenciaAoEscorregamentoENV51097: A; ResistenciaAoEscorregamentoENV12633: Class 1; ResistenciaAoEscorregamentoANSIA1371: ≥0,42; ResistenciaAoDeslizamentoENV12633: Class 1; ResistenciaAsManchas: Class 5; ResistenciaABaixasConcentracoesDeAcidosEAlcalis: Classe LA; ResistenciaAAltasConcentracoesDeAcidosEAlcalis: Classe HA; LibertacaoDeCadmio: 0; LibertacaoDeChumbo: 0
Type - IFC.REVIGRÉS-Dados de especificação-Wall Covering - VariacaoTonalidade: 2; NivelDeTrafego: 5; EPavimento: Sim; ERevestimento: Sim; EExterno: Sim
Type - IFC.REVIGRÉS-Dados geométricos-Wall Covering - AlturaNominal: 8.5 mm; ComprimentoNominal: 45 mm; LarguraNominal: 45 mm
Type - IFC.REVIGRÉS-Dados de sustentabilidade-Wall Covering - PotencialPrivacaoDeAguaConsumoDeAguaPonderado: 4.5; EnergiaTermicaExportada: 0; ItemENovo: Sim; ItemEParcialmenteReciclado: 0.03; ItemEReciclado: Sim; VidaÚtilEsperada: 50; SubstanciasPerigosas: Não; PotencialDeEsgotamentoAbioticoDosRecursosFosseis: 203; PotencialDeEsgotamentoAbioticoDosRecursosNaoFosseisMineraisEMetais: 0.000701; PotencialDeAquecimentoGlobalBiogenico: -0.48; CombustiveisFosseisComPotencialDeAquecimentoGlobal: 13.9; PotencialDeAquecimentoGlobalUsoDoSoloEMudancaDeUsoDoSolo: 0.0246; PotencialDeEutrofizacaoFraccaoDeNutrientesQueAtingemOCompartimentoFinalDeAguaDoce: 0.000189; PotencialDeEutrofizacaoFraccaoDeNutrientesQueAtingemOCompartimentoFinalMarinho: 0.0122; EnergiaRecuperada: 0.00739; ConsumoDeAguaDoce: 0.113; UtilizacaoLiquidaDeAguaDoce: 0.113; ResiduosPerigososEliminados: 0.00221; ResiduosNaoPerigososEliminados: 1.83; MassaTotalDeResiduosRadioactivosEliminados: 0.000394; EnergiaElectricaExportada: 1.55; MateriaisParaRecuperacaoDeEnergia: 0.00739; MateriaisParaReciclagem: 0.0253; UnidadeEPD: 1 m²
Type - IFC.REVIGRÉS-Dados gerais-Wall Covering - Nome: REVIGRÉS-URBAN-BASE-45X45-NAT-URBAN OFFWHITE; TipoProduto: Prensado a seco: grupo BIa UGL | Grés porcelânico técnico; NumeroDeRegistoDAP: EPD-REV-20240006-CCC1-EN; ReferenciaDAP: -; UrlDOP: -
Classification: C3010 (Uniformat)
Pset_QuantityTakeOff - sets with these values: 2
Pset_WallCommon - ExtendToStructure: no; LoadBearing: no
IFC.REVIGRÉS-Dados do fabricante-Wall Covering - Type: Basic Wall: REVIGRÉS-URBAN-BASE-45X45-NAT-OFFWHITE
IFC.REVIGRÉS-Dados de desempenho-Wall Covering - Type: Basic Wall: REVIGRÉS-URBAN-BASE-45X45-NAT-OFFWHITE
IFC.REVIGRÉS-Dados de especificação-Wall Covering - Type: Basic Wall: REVIGRÉS-URBAN-BASE-45X45-NAT-OFFWHITE
IFC.REVIGRÉS-Dados geométricos-Wall Covering - Type: Basic Wall: REVIGRÉS-URBAN-BASE-45X45-NAT-OFFWHITE
IFC.REVIGRÉS-Dados de sustentabilidade-Wall Covering - Type: Basic Wall: REVIGRÉS-URBAN-BASE-45X45-NAT-OFFWHITE

# IfcWallStandardCase: Basic Wall:REVIGRÉS-URBAN-BASE-59,2X118,6-RECT-ANTRACITE, Basic Wall:REVIGRÉS-URBAN-BASE-59,2X118,6-RECT-ANTRACITE:23002
In: Level 1
Type - PredefinedType: STANDARD; Material: REVIGRÉS-URBAN-BASE-60X120-RECT-ANTRACITE 9.8 mm
Type - Pset_ElementShading - Roughness: 304.8 mm
Type - Pset_ManufacturerTypeInformation - Manufacturer: REVIGRÉS
Type - Pset_ProductRequirements - Category: Walls
Type - Pset_QuantityTakeOff - Reference: 3121D348U1
Type - Pset_ReinforcementBarPitchOfWall - Reference: 3121D348U1
Type - Pset_WallCommon - IsExternal: no; Reference: 3121D348U1
Type - IFC.REVIGRÉS-Dados do fabricante-Wall Covering - FabricanteURL: https://www.revigres.pt/; ReferenciaModelo: Urban; NumeroGlobalDeItemComercial: 3121D348U1; Acabamento: RECT; Material: Grés porcelânico; IdentificadorDoOperadorEconomico: 501840856; UrlFabricanteArtigo: https://www.revigres.pt/colecoes/urban; PaisOrigem: Portugal
Type - IFC.REVIGRÉS-Dados de desempenho-Wall Covering - Rectilinearidade: ± 0.2% máx.± 0.8 mm; Ortogonalidade: ± 0.2% máx.± 1.5 mm; PlanaridadeDaSuperficie: ± 0.3% máx. ± 1.8 mm; QualidadeDaSuperficie: Cumpre; AbsorcaoDeAgua: < 0.05%; ModuloDeRuptura: > 45 N/mm²; ResistenciaAFlexao: > 3500 N; ResistenciaAAbrasaoProfunda: < 120 mm³; DilatacaoTermicaLinear: ≤ 8,0x10-6 °C-1; ResistenciaAoChoqueTermico: Resiste; DurabilidadeResistenciaAoGeloDegelo: Resiste; ResistenciaAoEscorregamentoDIN51130: R9; ResistenciaAoEscorregamentoDIN51097: A; ResistenciaAoEscorregamentoENV51097: A; ResistenciaAoEscorregamentoENV12633: Class 1; ResistenciaAoEscorregamentoANSIA1371: ≥0,42; ResistenciaAoDeslizamentoENV12633: Class 1; ResistenciaAsManchas: Class 5; ResistenciaABaixasConcentracoesDeAcidosEAlcalis: Classe LA; ResistenciaAAltasConcentracoesDeAcidosEAlcalis: Classe HA; LibertacaoDeCadmio: 0; LibertacaoDeChumbo: 0
Type - IFC.REVIGRÉS-Dados de especificação-Wall Covering - VariacaoTonalidade: 2; NivelDeTrafego: 5; EPavimento: Sim; ERevestimento: Sim; EExterno: Sim
Type - IFC.REVIGRÉS-Dados geométricos-Wall Covering - AlturaNominal: 9.8 mm; ComprimentoNominal: 592 mm; LarguraNominal: 1186 mm
Type - IFC.REVIGRÉS-Dados de sustentabilidade-Wall Covering - PotencialPrivacaoDeAguaConsumoDeAguaPonderado: 4.5; EnergiaTermicaExportada: 0; ItemENovo: Sim; ItemEParcialmenteReciclado: 0.29; ItemEReciclado: Sim; VidaÚtilEsperada: 50; SubstanciasPerigosas: Não; PotencialDeEsgotamentoAbioticoDosRecursosFosseis: 203; PotencialDeEsgotamentoAbioticoDosRecursosNaoFosseisMineraisEMetais: 0.000701; PotencialDeAquecimentoGlobalBiogenico: -0.48; CombustiveisFosseisComPotencialDeAquecimentoGlobal: 13.9; PotencialDeAquecimentoGlobalUsoDoSoloEMudancaDeUsoDoSolo: 0.0246; PotencialDeEutrofizacaoFraccaoDeNutrientesQueAtingemOCompartimentoFinalDeAguaDoce: 0.000189; PotencialDeEutrofizacaoFraccaoDeNutrientesQueAtingemOCompartimentoFinalMarinho: 0.0122; EnergiaRecuperada: 0.00739; ConsumoDeAguaDoce: 0.113; UtilizacaoLiquidaDeAguaDoce: 0.113; ResiduosPerigososEliminados: 0.00221; ResiduosNaoPerigososEliminados: 1.83; MassaTotalDeResiduosRadioactivosEliminados: 0.000394; EnergiaElectricaExportada: 1.55; MateriaisParaRecuperacaoDeEnergia: 0.00739; MateriaisParaReciclagem: 0.0253; UnidadeEPD: 1 m²
Type - IFC.REVIGRÉS-Dados gerais-Wall Covering - Nome: REVIGRÉS-URBAN-BASE-59.2X118.6-RECT-URBAN ANTRACITE; TipoProduto: Prensado a seco: grupo BIa UGL | Grés porcelânico técnico; NumeroDeRegistoDAP: EPD-REV-20240006-CCC1-EN; ReferenciaDAP: -; UrlDOP: -
Classification: C3010 (Uniformat)
Pset_QuantityTakeOff - sets with these values: 2
Pset_WallCommon - ExtendToStructure: no; LoadBearing: no
IFC.REVIGRÉS-Dados do fabricante-Wall Covering - Type: Basic Wall: REVIGRÉS-URBAN-BASE-59,2X118,6-RECT-ANTRACITE
IFC.REVIGRÉS-Dados de desempenho-Wall Covering - Type: Basic Wall: REVIGRÉS-URBAN-BASE-59,2X118,6-RECT-ANTRACITE
IFC.REVIGRÉS-Dados de especificação-Wall Covering - Type: Basic Wall: REVIGRÉS-URBAN-BASE-59,2X118,6-RECT-ANTRACITE
IFC.REVIGRÉS-Dados geométricos-Wall Covering - Type: Basic Wall: REVIGRÉS-URBAN-BASE-59,2X118,6-RECT-ANTRACITE
IFC.REVIGRÉS-Dados de sustentabilidade-Wall Covering - Type: Basic Wall: REVIGRÉS-URBAN-BASE-59,2X118,6-RECT-ANTRACITE

# IfcWallStandardCase: Basic Wall:REVIGRÉS-URBAN-BASE-59,2X118,6-RECT-BONE, Basic Wall:REVIGRÉS-URBAN-BASE-59,2X118,6-RECT-BONE:23018
In: Level 1
Type - PredefinedType: STANDARD; Material: REVIGRÉS-URBAN-BASE-60X120-RECT-BONE 9.8 mm
Type - Pset_ElementShading - Roughness: 304.8 mm
Type - Pset_ManufacturerTypeInformation - Manufacturer: REVIGRÉS
Type - Pset_ProductRequirements - Category: Walls
Type - Pset_QuantityTakeOff - Reference: 3121D320T1
Type - Pset_ReinforcementBarPitchOfWall - Reference: 3121D320T1
Type - Pset_WallCommon - IsExternal: no; Reference: 3121D320T1
Type - IFC.REVIGRÉS-Dados do fabricante-Wall Covering - FabricanteURL: https://www.revigres.pt/; ReferenciaModelo: Urban; NumeroGlobalDeItemComercial: 3121D320T1; Acabamento: RECT; Material: Grés porcelânico; IdentificadorDoOperadorEconomico: 501840856; UrlFabricanteArtigo: https://www.revigres.pt/colecoes/urban; PaisOrigem: Portugal
Type - IFC.REVIGRÉS-Dados de desempenho-Wall Covering - Rectilinearidade: ± 0.2% máx.± 0.8 mm; Ortogonalidade: ± 0.2% máx.± 1.5 mm; PlanaridadeDaSuperficie: ± 0.3% máx. ± 1.8 mm; QualidadeDaSuperficie: Cumpre; AbsorcaoDeAgua: < 0.05%; ModuloDeRuptura: > 45 N/mm²; ResistenciaAFlexao: > 3500 N; ResistenciaAAbrasaoProfunda: < 120 mm³; DilatacaoTermicaLinear: ≤ 8,0x10-6 °C-1; ResistenciaAoChoqueTermico: Resiste; DurabilidadeResistenciaAoGeloDegelo: Resiste; ResistenciaAoEscorregamentoDIN51130: R9; ResistenciaAoEscorregamentoDIN51097: A; ResistenciaAoEscorregamentoENV51097: A; ResistenciaAoEscorregamentoENV12633: Class 1; ResistenciaAoEscorregamentoANSIA1371: ≥0,42; ResistenciaAoDeslizamentoENV12633: Class 1; ResistenciaAsManchas: Class 5; ResistenciaABaixasConcentracoesDeAcidosEAlcalis: Classe LA; ResistenciaAAltasConcentracoesDeAcidosEAlcalis: Classe HA; LibertacaoDeCadmio: 0; LibertacaoDeChumbo: 0
Type - IFC.REVIGRÉS-Dados de especificação-Wall Covering - VariacaoTonalidade: 2; NivelDeTrafego: 5; EPavimento: Sim; ERevestimento: Sim; EExterno: Sim
Type - IFC.REVIGRÉS-Dados geométricos-Wall Covering - AlturaNominal: 9.8 mm; ComprimentoNominal: 592 mm; LarguraNominal: 1186 mm
Type - IFC.REVIGRÉS-Dados de sustentabilidade-Wall Covering - PotencialPrivacaoDeAguaConsumoDeAguaPonderado: 4.5; EnergiaTermicaExportada: 0; ItemENovo: Sim; ItemEParcialmenteReciclado: 0.03; ItemEReciclado: Sim; VidaÚtilEsperada: 50; SubstanciasPerigosas: Não; PotencialDeEsgotamentoAbioticoDosRecursosFosseis: 203; PotencialDeEsgotamentoAbioticoDosRecursosNaoFosseisMineraisEMetais: 0.000701; PotencialDeAquecimentoGlobalBiogenico: -0.48; CombustiveisFosseisComPotencialDeAquecimentoGlobal: 13.9; PotencialDeAquecimentoGlobalUsoDoSoloEMudancaDeUsoDoSolo: 0.0246; PotencialDeEutrofizacaoFraccaoDeNutrientesQueAtingemOCompartimentoFinalDeAguaDoce: 0.000189; PotencialDeEutrofizacaoFraccaoDeNutrientesQueAtingemOCompartimentoFinalMarinho: 0.0122; EnergiaRecuperada: 0.00739; ConsumoDeAguaDoce: 0.113; UtilizacaoLiquidaDeAguaDoce: 0.113; ResiduosPerigososEliminados: 0.00221; ResiduosNaoPerigososEliminados: 1.83; MassaTotalDeResiduosRadioactivosEliminados: 0.000394; EnergiaElectricaExportada: 1.55; MateriaisParaRecuperacaoDeEnergia: 0.00739; MateriaisParaReciclagem: 0.0253; UnidadeEPD: 1 m²
Type - IFC.REVIGRÉS-Dados gerais-Wall Covering - Nome: REVIGRÉS-URBAN-BASE-59.2X118.6-RECT-URBAN BONE; TipoProduto: Prensado a seco: grupo BIa UGL | Grés porcelânico técnico; NumeroDeRegistoDAP: EPD-REV-20240006-CCC1-EN; ReferenciaDAP: -; UrlDOP: -
Classification: C3010 (Uniformat)
Pset_QuantityTakeOff - sets with these values: 2
Pset_WallCommon - ExtendToStructure: no; LoadBearing: no
IFC.REVIGRÉS-Dados do fabricante-Wall Covering - Type: Basic Wall: REVIGRÉS-URBAN-BASE-59,2X118,6-RECT-BONE
IFC.REVIGRÉS-Dados de desempenho-Wall Covering - Type: Basic Wall: REVIGRÉS-URBAN-BASE-59,2X118,6-RECT-BONE
IFC.REVIGRÉS-Dados de especificação-Wall Covering - Type: Basic Wall: REVIGRÉS-URBAN-BASE-59,2X118,6-RECT-BONE
IFC.REVIGRÉS-Dados geométricos-Wall Covering - Type: Basic Wall: REVIGRÉS-URBAN-BASE-59,2X118,6-RECT-BONE
IFC.REVIGRÉS-Dados de sustentabilidade-Wall Covering - Type: Basic Wall: REVIGRÉS-URBAN-BASE-59,2X118,6-RECT-BONE

# IfcWallStandardCase: Basic Wall:REVIGRÉS-URBAN-BASE-59,2X118,6-RECT-CRAFT, Basic Wall:REVIGRÉS-URBAN-BASE-59,2X118,6-RECT-CRAFT:23034
In: Level 1
Type - PredefinedType: STANDARD; Material: REVIGRÉS-URBAN-BASE-60X120-RECT-CRAFT 9.8 mm
Type - Pset_ElementShading - Roughness: 304.8 mm
Type - Pset_ManufacturerTypeInformation - Manufacturer: REVIGRÉS
Type - Pset_ProductRequirements - Category: Walls
Type - Pset_QuantityTakeOff - Reference: 3121D324T1
Type - Pset_ReinforcementBarPitchOfWall - Reference: 3121D324T1
Type - Pset_WallCommon - IsExternal: no; Reference: 3121D324T1
Type - IFC.REVIGRÉS-Dados do fabricante-Wall Covering - FabricanteURL: https://www.revigres.pt/; ReferenciaModelo: Urban; NumeroGlobalDeItemComercial: 3121D324T1; Acabamento: RECT; Material: Grés porcelânico; IdentificadorDoOperadorEconomico: 501840856; UrlFabricanteArtigo: https://www.revigres.pt/colecoes/urban; PaisOrigem: Portugal
Type - IFC.REVIGRÉS-Dados de desempenho-Wall Covering - Rectilinearidade: ± 0.2% máx.± 0.8 mm; Ortogonalidade: ± 0.2% máx.± 1.5 mm; PlanaridadeDaSuperficie: ± 0.3% máx. ± 1.8 mm; QualidadeDaSuperficie: Cumpre; AbsorcaoDeAgua: < 0.05%; ModuloDeRuptura: > 45 N/mm²; ResistenciaAFlexao: > 3500 N; ResistenciaAAbrasaoProfunda: < 120 mm³; DilatacaoTermicaLinear: ≤ 8,0x10-6 °C-1; ResistenciaAoChoqueTermico: Resiste; DurabilidadeResistenciaAoGeloDegelo: Resiste; ResistenciaAoEscorregamentoDIN51130: R9; ResistenciaAoEscorregamentoDIN51097: A; ResistenciaAoEscorregamentoENV51097: A; ResistenciaAoEscorregamentoENV12633: Class 1; ResistenciaAoEscorregamentoANSIA1371: ≥0,42; ResistenciaAoDeslizamentoENV12633: Class 1; ResistenciaAsManchas: Class 5; ResistenciaABaixasConcentracoesDeAcidosEAlcalis: Classe LA; ResistenciaAAltasConcentracoesDeAcidosEAlcalis: Classe HA; LibertacaoDeCadmio: 0; LibertacaoDeChumbo: 0
Type - IFC.REVIGRÉS-Dados de especificação-Wall Covering - VariacaoTonalidade: 2; NivelDeTrafego: 5; EPavimento: Sim; ERevestimento: Sim; EExterno: Sim
Type - IFC.REVIGRÉS-Dados geométricos-Wall Covering - AlturaNominal: 9.8 mm; ComprimentoNominal: 592 mm; LarguraNominal: 1186 mm
Type - IFC.REVIGRÉS-Dados de sustentabilidade-Wall Covering - PotencialPrivacaoDeAguaConsumoDeAguaPonderado: 4.5; EnergiaTermicaExportada: 0; ItemENovo: Sim; ItemEParcialmenteReciclado: 0.19; ItemEReciclado: Sim; VidaÚtilEsperada: 50; SubstanciasPerigosas: Não; PotencialDeEsgotamentoAbioticoDosRecursosFosseis: 203; PotencialDeEsgotamentoAbioticoDosRecursosNaoFosseisMineraisEMetais: 0.000701; PotencialDeAquecimentoGlobalBiogenico: -0.48; CombustiveisFosseisComPotencialDeAquecimentoGlobal: 13.9; PotencialDeAquecimentoGlobalUsoDoSoloEMudancaDeUsoDoSolo: 0.0246; PotencialDeEutrofizacaoFraccaoDeNutrientesQueAtingemOCompartimentoFinalDeAguaDoce: 0.000189; PotencialDeEutrofizacaoFraccaoDeNutrientesQueAtingemOCompartimentoFinalMarinho: 0.0122; EnergiaRecuperada: 0.00739; ConsumoDeAguaDoce: 0.113; UtilizacaoLiquidaDeAguaDoce: 0.113; ResiduosPerigososEliminados: 0.00221; ResiduosNaoPerigososEliminados: 1.83; MassaTotalDeResiduosRadioactivosEliminados: 0.000394; EnergiaElectricaExportada: 1.55; MateriaisParaRecuperacaoDeEnergia: 0.00739; MateriaisParaReciclagem: 0.0253; UnidadeEPD: 1 m²
Type - IFC.REVIGRÉS-Dados gerais-Wall Covering - Nome: REVIGRÉS-URBAN-BASE-59.2X118.6-RECT-URBAN CRAFT; TipoProduto: Prensado a seco: grupo BIa UGL | Grés porcelânico técnico; NumeroDeRegistoDAP: EPD-REV-20240006-CCC1-EN; ReferenciaDAP: -; UrlDOP: -
Classification: C3010 (Uniformat)
Pset_QuantityTakeOff - sets with these values: 2
Pset_WallCommon - ExtendToStructure: no; LoadBearing: no
IFC.REVIGRÉS-Dados do fabricante-Wall Covering - Type: Basic Wall: REVIGRÉS-URBAN-BASE-59,2X118,6-RECT-CRAFT
IFC.REVIGRÉS-Dados de desempenho-Wall Covering - Type: Basic Wall: REVIGRÉS-URBAN-BASE-59,2X118,6-RECT-CRAFT
IFC.REVIGRÉS-Dados de especificação-Wall Covering - Type: Basic Wall: REVIGRÉS-URBAN-BASE-59,2X118,6-RECT-CRAFT
IFC.REVIGRÉS-Dados geométricos-Wall Covering - Type: Basic Wall: REVIGRÉS-URBAN-BASE-59,2X118,6-RECT-CRAFT
IFC.REVIGRÉS-Dados de sustentabilidade-Wall Covering - Type: Basic Wall: REVIGRÉS-URBAN-BASE-59,2X118,6-RECT-CRAFT

# IfcWallStandardCase: Basic Wall:REVIGRÉS-URBAN-BASE-59,2X118,6-RECT-FOG, Basic Wall:REVIGRÉS-URBAN-BASE-59,2X118,6-RECT-FOG:23050
In: Level 1
Type - PredefinedType: STANDARD; Material: REVIGRÉS-URBAN-BASE-60X120-RECT-FOG 9.8 mm
Type - Pset_ElementShading - Roughness: 304.8 mm
Type - Pset_ManufacturerTypeInformation - Manufacturer: REVIGRÉS
Type - Pset_ProductRequirements - Category: Walls
Type - Pset_QuantityTakeOff - Reference: 3121D321T1
Type - Pset_ReinforcementBarPitchOfWall - Reference: 3121D321T1
Type - Pset_WallCommon - IsExternal: no; Reference: 3121D321T1
Type - IFC.REVIGRÉS-Dados do fabricante-Wall Covering - FabricanteURL: https://www.revigres.pt/; ReferenciaModelo: Urban; NumeroGlobalDeItemComercial: 3121D321T1; Acabamento: RECT; Material: Grés porcelânico; IdentificadorDoOperadorEconomico: 501840856; UrlFabricanteArtigo: https://www.revigres.pt/colecoes/urban; PaisOrigem: Portugal
Type - IFC.REVIGRÉS-Dados de desempenho-Wall Covering - Rectilinearidade: ± 0.2% máx.± 0.8 mm; Ortogonalidade: ± 0.2% máx.± 1.5 mm; PlanaridadeDaSuperficie: ± 0.3% máx. ± 1.8 mm; QualidadeDaSuperficie: Cumpre; AbsorcaoDeAgua: < 0.05%; ModuloDeRuptura: > 45 N/mm²; ResistenciaAFlexao: > 3500 N; ResistenciaAAbrasaoProfunda: < 120 mm³; DilatacaoTermicaLinear: ≤ 8,0x10-6 °C-1; ResistenciaAoChoqueTermico: Resiste; DurabilidadeResistenciaAoGeloDegelo: Resiste; ResistenciaAoEscorregamentoDIN51130: R9; ResistenciaAoEscorregamentoDIN51097: A; ResistenciaAoEscorregamentoENV51097: A; ResistenciaAoEscorregamentoENV12633: Class 1; ResistenciaAoEscorregamentoANSIA1371: ≥0,42; ResistenciaAoDeslizamentoENV12633: Class 1; ResistenciaAsManchas: Class 5; ResistenciaABaixasConcentracoesDeAcidosEAlcalis: Classe LA; ResistenciaAAltasConcentracoesDeAcidosEAlcalis: Classe HA; LibertacaoDeCadmio: 0; LibertacaoDeChumbo: 0
Type - IFC.REVIGRÉS-Dados de especificação-Wall Covering - VariacaoTonalidade: 2; NivelDeTrafego: 5; EPavimento: Sim; ERevestimento: Sim; EExterno: Sim
Type - IFC.REVIGRÉS-Dados geométricos-Wall Covering - AlturaNominal: 9.8 mm; ComprimentoNominal: 592 mm; LarguraNominal: 1186 mm
Type - IFC.REVIGRÉS-Dados de sustentabilidade-Wall Covering - PotencialPrivacaoDeAguaConsumoDeAguaPonderado: 4.5; EnergiaTermicaExportada: 0; ItemENovo: Sim; ItemEParcialmenteReciclado: 0.23; ItemEReciclado: Sim; VidaÚtilEsperada: 50; SubstanciasPerigosas: Não; PotencialDeEsgotamentoAbioticoDosRecursosFosseis: 203; PotencialDeEsgotamentoAbioticoDosRecursosNaoFosseisMineraisEMetais: 0.000701; PotencialDeAquecimentoGlobalBiogenico: -0.48; CombustiveisFosseisComPotencialDeAquecimentoGlobal: 13.9; PotencialDeAquecimentoGlobalUsoDoSoloEMudancaDeUsoDoSolo: 0.0246; PotencialDeEutrofizacaoFraccaoDeNutrientesQueAtingemOCompartimentoFinalDeAguaDoce: 0.000189; PotencialDeEutrofizacaoFraccaoDeNutrientesQueAtingemOCompartimentoFinalMarinho: 0.0122; EnergiaRecuperada: 0.00739; ConsumoDeAguaDoce: 0.113; UtilizacaoLiquidaDeAguaDoce: 0.113; ResiduosPerigososEliminados: 0.00221; ResiduosNaoPerigososEliminados: 1.83; MassaTotalDeResiduosRadioactivosEliminados: 0.000394; EnergiaElectricaExportada: 1.55; MateriaisParaRecuperacaoDeEnergia: 0.00739; MateriaisParaReciclagem: 0.0253; UnidadeEPD: 1 m²
Type - IFC.REVIGRÉS-Dados gerais-Wall Covering - Nome: REVIGRÉS-URBAN-BASE-59.2X118.6-RECT-URBAN FOG; TipoProduto: Prensado a seco: grupo BIa UGL | Grés porcelânico técnico; NumeroDeRegistoDAP: EPD-REV-20240006-CCC1-EN; ReferenciaDAP: -; UrlDOP: -
Classification: C3010 (Uniformat)
Pset_QuantityTakeOff - sets with these values: 2
Pset_WallCommon - ExtendToStructure: no; LoadBearing: no
IFC.REVIGRÉS-Dados do fabricante-Wall Covering - Type: Basic Wall: REVIGRÉS-URBAN-BASE-59,2X118,6-RECT-FOG
IFC.REVIGRÉS-Dados de desempenho-Wall Covering - Type: Basic Wall: REVIGRÉS-URBAN-BASE-59,2X118,6-RECT-FOG
IFC.REVIGRÉS-Dados de especificação-Wall Covering - Type: Basic Wall: REVIGRÉS-URBAN-BASE-59,2X118,6-RECT-FOG
IFC.REVIGRÉS-Dados geométricos-Wall Covering - Type: Basic Wall: REVIGRÉS-URBAN-BASE-59,2X118,6-RECT-FOG
IFC.REVIGRÉS-Dados de sustentabilidade-Wall Covering - Type: Basic Wall: REVIGRÉS-URBAN-BASE-59,2X118,6-RECT-FOG

# IfcWallStandardCase: Basic Wall:REVIGRÉS-URBAN-BASE-59,2X118,6-RECT-GRIS, Basic Wall:REVIGRÉS-URBAN-BASE-59,2X118,6-RECT-GRIS:23066
In: Level 1
Type - PredefinedType: STANDARD; Material: REVIGRÉS-URBAN-BASE-60X120-RECT-GRIS 9.8 mm
Type - Pset_ElementShading - Roughness: 304.8 mm
Type - Pset_ManufacturerTypeInformation - Manufacturer: REVIGRÉS
Type - Pset_ProductRequirements - Category: Walls
Type - Pset_QuantityTakeOff - Reference: 3121D322T1
Type - Pset_ReinforcementBarPitchOfWall - Reference: 3121D322T1
Type - Pset_WallCommon - IsExternal: no; Reference: 3121D322T1
Type - IFC.REVIGRÉS-Dados do fabricante-Wall Covering - FabricanteURL: https://www.revigres.pt/; ReferenciaModelo: Urban; NumeroGlobalDeItemComercial: 3121D322T1; Acabamento: RECT; Material: Grés porcelânico; IdentificadorDoOperadorEconomico: 501840856; UrlFabricanteArtigo: https://www.revigres.pt/colecoes/urban; PaisOrigem: Portugal
Type - IFC.REVIGRÉS-Dados de desempenho-Wall Covering - Rectilinearidade: ± 0.2% máx.± 0.8 mm; Ortogonalidade: ± 0.2% máx.± 1.5 mm; PlanaridadeDaSuperficie: ± 0.3% máx. ± 1.8 mm; QualidadeDaSuperficie: Cumpre; AbsorcaoDeAgua: < 0.05%; ModuloDeRuptura: > 45 N/mm²; ResistenciaAFlexao: > 3500 N; ResistenciaAAbrasaoProfunda: < 120 mm³; DilatacaoTermicaLinear: ≤ 8,0x10-6 °C-1; ResistenciaAoChoqueTermico: Resiste; DurabilidadeResistenciaAoGeloDegelo: Resiste; ResistenciaAoEscorregamentoDIN51130: R9; ResistenciaAoEscorregamentoDIN51097: A; ResistenciaAoEscorregamentoENV51097: A; ResistenciaAoEscorregamentoENV12633: Class 1; ResistenciaAoEscorregamentoANSIA1371: ≥0,42; ResistenciaAoDeslizamentoENV12633: Class 1; ResistenciaAsManchas: Class 5; ResistenciaABaixasConcentracoesDeAcidosEAlcalis: Classe LA; ResistenciaAAltasConcentracoesDeAcidosEAlcalis: Classe HA; LibertacaoDeCadmio: 0; LibertacaoDeChumbo: 0
Type - IFC.REVIGRÉS-Dados de especificação-Wall Covering - VariacaoTonalidade: 2; NivelDeTrafego: 5; EPavimento: Sim; ERevestimento: Sim; EExterno: Sim
Type - IFC.REVIGRÉS-Dados geométricos-Wall Covering - AlturaNominal: 9.8 mm; ComprimentoNominal: 592 mm; LarguraNominal: 1186 mm
Type - IFC.REVIGRÉS-Dados de sustentabilidade-Wall Covering - PotencialPrivacaoDeAguaConsumoDeAguaPonderado: 4.5; EnergiaTermicaExportada: 0; ItemENovo: Sim; ItemEParcialmenteReciclado: 0.23; ItemEReciclado: Sim; VidaÚtilEsperada: 50; SubstanciasPerigosas: Não; PotencialDeEsgotamentoAbioticoDosRecursosFosseis: 203; PotencialDeEsgotamentoAbioticoDosRecursosNaoFosseisMineraisEMetais: 0.000701; PotencialDeAquecimentoGlobalBiogenico: -0.48; CombustiveisFosseisComPotencialDeAquecimentoGlobal: 13.9; PotencialDeAquecimentoGlobalUsoDoSoloEMudancaDeUsoDoSolo: 0.0246; PotencialDeEutrofizacaoFraccaoDeNutrientesQueAtingemOCompartimentoFinalDeAguaDoce: 0.000189; PotencialDeEutrofizacaoFraccaoDeNutrientesQueAtingemOCompartimentoFinalMarinho: 0.0122; EnergiaRecuperada: 0.00739; ConsumoDeAguaDoce: 0.113; UtilizacaoLiquidaDeAguaDoce: 0.113; ResiduosPerigososEliminados: 0.00221; ResiduosNaoPerigososEliminados: 1.83; MassaTotalDeResiduosRadioactivosEliminados: 0.000394; EnergiaElectricaExportada: 1.55; MateriaisParaRecuperacaoDeEnergia: 0.00739; MateriaisParaReciclagem: 0.0253; UnidadeEPD: 1 m²
Type - IFC.REVIGRÉS-Dados gerais-Wall Covering - Nome: REVIGRÉS-URBAN-BASE-59.2X118.6-RECT-URBAN GRIS; TipoProduto: Prensado a seco: grupo BIa UGL | Grés porcelânico técnico; NumeroDeRegistoDAP: EPD-REV-20240006-CCC1-EN; ReferenciaDAP: -; UrlDOP: -
Classification: C3010 (Uniformat)
Pset_QuantityTakeOff - sets with these values: 2
Pset_WallCommon - ExtendToStructure: no; LoadBearing: no
IFC.REVIGRÉS-Dados do fabricante-Wall Covering - Type: Basic Wall: REVIGRÉS-URBAN-BASE-59,2X118,6-RECT-GRIS
IFC.REVIGRÉS-Dados de desempenho-Wall Covering - Type: Basic Wall: REVIGRÉS-URBAN-BASE-59,2X118,6-RECT-GRIS
IFC.REVIGRÉS-Dados de especificação-Wall Covering - Type: Basic Wall: REVIGRÉS-URBAN-BASE-59,2X118,6-RECT-GRIS
IFC.REVIGRÉS-Dados geométricos-Wall Covering - Type: Basic Wall: REVIGRÉS-URBAN-BASE-59,2X118,6-RECT-GRIS
IFC.REVIGRÉS-Dados de sustentabilidade-Wall Covering - Type: Basic Wall: REVIGRÉS-URBAN-BASE-59,2X118,6-RECT-GRIS

# IfcWallStandardCase: Basic Wall:REVIGRÉS-URBAN-BASE-59,2X118,6-RECT-OFFWHITE, Basic Wall:REVIGRÉS-URBAN-BASE-59,2X118,6-RECT-OFFWHITE:23082
In: Level 1
Type - PredefinedType: STANDARD; Material: REVIGRÉS-URBAN-BASE-60X120-RECT-OFFWHITE 9.8 mm
Type - Pset_ElementShading - Roughness: 304.8 mm
Type - Pset_ManufacturerTypeInformation - Manufacturer: REVIGRÉS
Type - Pset_ProductRequirements - Category: Walls
Type - Pset_QuantityTakeOff - Reference: 3121D323T1
Type - Pset_ReinforcementBarPitchOfWall - Reference: 3121D323T1
Type - Pset_WallCommon - IsExternal: no; Reference: 3121D323T1
Type - IFC.REVIGRÉS-Dados do fabricante-Wall Covering - FabricanteURL: https://www.revigres.pt/; ReferenciaModelo: Urban; NumeroGlobalDeItemComercial: 3121D323T1; Acabamento: RECT; Material: Grés porcelânico; IdentificadorDoOperadorEconomico: 501840856; UrlFabricanteArtigo: https://www.revigres.pt/colecoes/urban; PaisOrigem: Portugal
Type - IFC.REVIGRÉS-Dados de desempenho-Wall Covering - Rectilinearidade: ± 0.2% máx.± 0.8 mm; Ortogonalidade: ± 0.2% máx.± 1.5 mm; PlanaridadeDaSuperficie: ± 0.3% máx. ± 1.8 mm; QualidadeDaSuperficie: Cumpre; AbsorcaoDeAgua: < 0.05%; ModuloDeRuptura: > 45 N/mm²; ResistenciaAFlexao: > 3500 N; ResistenciaAAbrasaoProfunda: < 120 mm³; DilatacaoTermicaLinear: ≤ 8,0x10-6 °C-1; ResistenciaAoChoqueTermico: Resiste; DurabilidadeResistenciaAoGeloDegelo: Resiste; ResistenciaAoEscorregamentoDIN51130: R9; ResistenciaAoEscorregamentoDIN51097: A; ResistenciaAoEscorregamentoENV51097: A; ResistenciaAoEscorregamentoENV12633: Class 1; ResistenciaAoEscorregamentoANSIA1371: ≥0,42; ResistenciaAoDeslizamentoENV12633: Class 1; ResistenciaAsManchas: Class 5; ResistenciaABaixasConcentracoesDeAcidosEAlcalis: Classe LA; ResistenciaAAltasConcentracoesDeAcidosEAlcalis: Classe HA; LibertacaoDeCadmio: 0; LibertacaoDeChumbo: 0
Type - IFC.REVIGRÉS-Dados de especificação-Wall Covering - VariacaoTonalidade: 2; NivelDeTrafego: 5; EPavimento: Sim; ERevestimento: Sim; EExterno: Sim
Type - IFC.REVIGRÉS-Dados geométricos-Wall Covering - AlturaNominal: 9.8 mm; ComprimentoNominal: 592 mm; LarguraNominal: 1186 mm
Type - IFC.REVIGRÉS-Dados de sustentabilidade-Wall Covering - PotencialPrivacaoDeAguaConsumoDeAguaPonderado: 4.5; EnergiaTermicaExportada: 0; ItemENovo: Sim; ItemEParcialmenteReciclado: 0.03; ItemEReciclado: Sim; VidaÚtilEsperada: 50; SubstanciasPerigosas: Não; PotencialDeEsgotamentoAbioticoDosRecursosFosseis: 203; PotencialDeEsgotamentoAbioticoDosRecursosNaoFosseisMineraisEMetais: 0.000701; PotencialDeAquecimentoGlobalBiogenico: -0.48; CombustiveisFosseisComPotencialDeAquecimentoGlobal: 13.9; PotencialDeAquecimentoGlobalUsoDoSoloEMudancaDeUsoDoSolo: 0.0246; PotencialDeEutrofizacaoFraccaoDeNutrientesQueAtingemOCompartimentoFinalDeAguaDoce: 0.000189; PotencialDeEutrofizacaoFraccaoDeNutrientesQueAtingemOCompartimentoFinalMarinho: 0.0122; EnergiaRecuperada: 0.00739; ConsumoDeAguaDoce: 0.113; UtilizacaoLiquidaDeAguaDoce: 0.113; ResiduosPerigososEliminados: 0.00221; ResiduosNaoPerigososEliminados: 1.83; MassaTotalDeResiduosRadioactivosEliminados: 0.000394; EnergiaElectricaExportada: 1.55; MateriaisParaRecuperacaoDeEnergia: 0.00739; MateriaisParaReciclagem: 0.0253; UnidadeEPD: 1 m²
Type - IFC.REVIGRÉS-Dados gerais-Wall Covering - Nome: REVIGRÉS-URBAN-BASE-59.2X118.6-RECT-URBAN OFFWHITE; TipoProduto: Prensado a seco: grupo BIa UGL | Grés porcelânico técnico; NumeroDeRegistoDAP: EPD-REV-20240006-CCC1-EN; ReferenciaDAP: -; UrlDOP: -
Classification: C3010 (Uniformat)
Pset_QuantityTakeOff - sets with these values: 2
Pset_WallCommon - ExtendToStructure: no; LoadBearing: no
IFC.REVIGRÉS-Dados do fabricante-Wall Covering - Type: Basic Wall: REVIGRÉS-URBAN-BASE-59,2X118,6-RECT-OFFWHITE
IFC.REVIGRÉS-Dados de desempenho-Wall Covering - Type: Basic Wall: REVIGRÉS-URBAN-BASE-59,2X118,6-RECT-OFFWHITE
IFC.REVIGRÉS-Dados de especificação-Wall Covering - Type: Basic Wall: REVIGRÉS-URBAN-BASE-59,2X118,6-RECT-OFFWHITE
IFC.REVIGRÉS-Dados geométricos-Wall Covering - Type: Basic Wall: REVIGRÉS-URBAN-BASE-59,2X118,6-RECT-OFFWHITE
IFC.REVIGRÉS-Dados de sustentabilidade-Wall Covering - Type: Basic Wall: REVIGRÉS-URBAN-BASE-59,2X118,6-RECT-OFFWHITE

# IfcWallStandardCase: Basic Wall:REVIGRÉS-URBAN-BASE-59,2X59,2-RECT-ANTISLIP ANTRACITE, Basic Wall:REVIGRÉS-URBAN-BASE-59,2X59,2-RECT-ANTISLIP ANTRACITE:26599
In: Level 1
Type - PredefinedType: STANDARD; Material: REVIGRÉS-URBAN-BASE-60X60-RECT-ANTISLIP ANTRACITE 10.5 mm
Type - Pset_ElementShading - Roughness: 304.8 mm
Type - Pset_ManufacturerTypeInformation - Manufacturer: REVIGRÉS
Type - Pset_ProductRequirements - Category: Walls
Type - Pset_QuantityTakeOff - Reference: 31211349U1
Type - Pset_ReinforcementBarPitchOfWall - Reference: 31211349U1
Type - Pset_WallCommon - IsExternal: no; Reference: 31211349U1
Type - IFC.REVIGRÉS-Dados do fabricante-Wall Covering - FabricanteURL: https://www.revigres.pt/; ReferenciaModelo: Urban; NumeroGlobalDeItemComercial: 31211349U1; Acabamento: RECT; Material: Grés porcelânico; IdentificadorDoOperadorEconomico: 501840856; UrlFabricanteArtigo: https://www.revigres.pt/colecoes/urban; PaisOrigem: Portugal
Type - IFC.REVIGRÉS-Dados de desempenho-Wall Covering - Rectilinearidade: ± 0.2% máx.± 0.8 mm; Ortogonalidade: ± 0.2% máx.± 1.5 mm; PlanaridadeDaSuperficie: ± 0.3% máx. ± 1.8 mm; QualidadeDaSuperficie: Cumpre; AbsorcaoDeAgua: < 0.05%; ModuloDeRuptura: > 45 N/mm²; ResistenciaAFlexao: > 3500 N; ResistenciaAAbrasaoProfunda: < 120 mm³; DilatacaoTermicaLinear: ≤ 8,0x10-6 °C-1; ResistenciaAoChoqueTermico: Resiste; DurabilidadeResistenciaAoGeloDegelo: Resiste; ResistenciaAoEscorregamentoDIN51130: R9; ResistenciaAoEscorregamentoDIN51097: A; ResistenciaAoEscorregamentoENV51097: A; ResistenciaAoEscorregamentoENV12633: Class 1; ResistenciaAoEscorregamentoANSIA1371: ≥0,42; ResistenciaAoDeslizamentoENV12633: Class 1; ResistenciaAsManchas: Class 5; ResistenciaABaixasConcentracoesDeAcidosEAlcalis: Classe LA; ResistenciaAAltasConcentracoesDeAcidosEAlcalis: Classe HA; LibertacaoDeCadmio: 0; LibertacaoDeChumbo: 0
Type - IFC.REVIGRÉS-Dados de especificação-Wall Covering - VariacaoTonalidade: 2; NivelDeTrafego: 5; EPavimento: Sim; ERevestimento: Sim; EExterno: Sim
Type - IFC.REVIGRÉS-Dados geométricos-Wall Covering - AlturaNominal: 8.5 mm; ComprimentoNominal: 59.2 mm; LarguraNominal: 59.2 mm
Type - IFC.REVIGRÉS-Dados de sustentabilidade-Wall Covering - PotencialPrivacaoDeAguaConsumoDeAguaPonderado: 4.5; EnergiaTermicaExportada: 0; ItemENovo: Sim; ItemEParcialmenteReciclado: 0.03; ItemEReciclado: Sim; VidaÚtilEsperada: 50; SubstanciasPerigosas: Não; PotencialDeEsgotamentoAbioticoDosRecursosFosseis: 203; PotencialDeEsgotamentoAbioticoDosRecursosNaoFosseisMineraisEMetais: 0.000701; PotencialDeAquecimentoGlobalBiogenico: -0.48; CombustiveisFosseisComPotencialDeAquecimentoGlobal: 13.9; PotencialDeAquecimentoGlobalUsoDoSoloEMudancaDeUsoDoSolo: 0.0246; PotencialDeEutrofizacaoFraccaoDeNutrientesQueAtingemOCompartimentoFinalDeAguaDoce: 0.000189; PotencialDeEutrofizacaoFraccaoDeNutrientesQueAtingemOCompartimentoFinalMarinho: 0.0122; EnergiaRecuperada: 0.00739; ConsumoDeAguaDoce: 0.113; UtilizacaoLiquidaDeAguaDoce: 0.113; ResiduosPerigososEliminados: 0.00221; ResiduosNaoPerigososEliminados: 1.83; MassaTotalDeResiduosRadioactivosEliminados: 0.000394; EnergiaElectricaExportada: 1.55; MateriaisParaRecuperacaoDeEnergia: 0.00739; MateriaisParaReciclagem: 0.0253; UnidadeEPD: 1 m²
Type - IFC.REVIGRÉS-Dados gerais-Wall Covering - Nome: REVIGRÉS-URBAN-BASE-59.2X59.2-RECT-ANTISLIP URBAN ANTRACITE; TipoProduto: Prensado a seco: grupo BIa UGL | Grés porcelânico técnico; NumeroDeRegistoDAP: EPD-REV-20240006-CCC1-EN; ReferenciaDAP: -; UrlDOP: -
Classification: C3010 (Uniformat)
Pset_QuantityTakeOff - sets with these values: 2
Pset_WallCommon - ExtendToStructure: no; LoadBearing: no
IFC.REVIGRÉS-Dados do fabricante-Wall Covering - Type: Basic Wall: REVIGRÉS-URBAN-BASE-59,2X59,2-RECT-ANTISLIP ANTRACITE
IFC.REVIGRÉS-Dados de desempenho-Wall Covering - Type: Basic Wall: REVIGRÉS-URBAN-BASE-59,2X59,2-RECT-ANTISLIP ANTRACITE
IFC.REVIGRÉS-Dados de especificação-Wall Covering - Type: Basic Wall: REVIGRÉS-URBAN-BASE-59,2X59,2-RECT-ANTISLIP ANTRACITE
IFC.REVIGRÉS-Dados geométricos-Wall Covering - Type: Basic Wall: REVIGRÉS-URBAN-BASE-59,2X59,2-RECT-ANTISLIP ANTRACITE
IFC.REVIGRÉS-Dados de sustentabilidade-Wall Covering - Type: Basic Wall: REVIGRÉS-URBAN-BASE-59,2X59,2-RECT-ANTISLIP ANTRACITE

# IfcWallStandardCase: Basic Wall:REVIGRÉS-URBAN-BASE-59,2X59,2-RECT-ANTISLIP BONE, Basic Wall:REVIGRÉS-URBAN-BASE-59,2X59,2-RECT-ANTISLIP BONE:26607
In: Level 1
Type - PredefinedType: STANDARD; Material: REVIGRÉS-URBAN-BASE-60X60-RECT-ANTISLIP BONE 10.5 mm
Type - Pset_ElementShading - Roughness: 304.8 mm
Type - Pset_ManufacturerTypeInformation - Manufacturer: REVIGRÉS
Type - Pset_ProductRequirements - Category: Walls
Type - Pset_QuantityTakeOff - Reference: 31211331T1
Type - Pset_ReinforcementBarPitchOfWall - Reference: 31211331T1
Type - Pset_WallCommon - IsExternal: no; Reference: 31211331T1
Type - IFC.REVIGRÉS-Dados do fabricante-Wall Covering - FabricanteURL: https://www.revigres.pt/; ReferenciaModelo: Urban; NumeroGlobalDeItemComercial: 31211331T1; Acabamento: RECT; Material: Grés porcelânico; IdentificadorDoOperadorEconomico: 501840856; UrlFabricanteArtigo: https://www.revigres.pt/colecoes/urban; PaisOrigem: Portugal
Type - IFC.REVIGRÉS-Dados de desempenho-Wall Covering - Rectilinearidade: ± 0.2% máx.± 0.8 mm; Ortogonalidade: ± 0.2% máx.± 1.5 mm; PlanaridadeDaSuperficie: ± 0.3% máx. ± 1.8 mm; QualidadeDaSuperficie: Cumpre; AbsorcaoDeAgua: < 0.05%; ModuloDeRuptura: > 45 N/mm²; ResistenciaAFlexao: > 3500 N; ResistenciaAAbrasaoProfunda: < 120 mm³; DilatacaoTermicaLinear: ≤ 8,0x10-6 °C-1; ResistenciaAoChoqueTermico: Resiste; DurabilidadeResistenciaAoGeloDegelo: Resiste; ResistenciaAoEscorregamentoDIN51130: R9; ResistenciaAoEscorregamentoDIN51097: A; ResistenciaAoEscorregamentoENV51097: A; ResistenciaAoEscorregamentoENV12633: Class 1; ResistenciaAoEscorregamentoANSIA1371: ≥0,42; ResistenciaAoDeslizamentoENV12633: Class 1; ResistenciaAsManchas: Class 5; ResistenciaABaixasConcentracoesDeAcidosEAlcalis: Classe LA; ResistenciaAAltasConcentracoesDeAcidosEAlcalis: Classe HA; LibertacaoDeCadmio: 0; LibertacaoDeChumbo: 0
Type - IFC.REVIGRÉS-Dados de especificação-Wall Covering - VariacaoTonalidade: 2; NivelDeTrafego: 5; EPavimento: Sim; ERevestimento: Sim; EExterno: Sim
Type - IFC.REVIGRÉS-Dados geométricos-Wall Covering - AlturaNominal: 8.5 mm; ComprimentoNominal: 59.2 mm; LarguraNominal: 59.2 mm
Type - IFC.REVIGRÉS-Dados de sustentabilidade-Wall Covering - PotencialPrivacaoDeAguaConsumoDeAguaPonderado: 4.5; EnergiaTermicaExportada: 0; ItemENovo: Sim; ItemEParcialmenteReciclado: 0.19; ItemEReciclado: Sim; VidaÚtilEsperada: 50; SubstanciasPerigosas: Não; PotencialDeEsgotamentoAbioticoDosRecursosFosseis: 203; PotencialDeEsgotamentoAbioticoDosRecursosNaoFosseisMineraisEMetais: 0.000701; PotencialDeAquecimentoGlobalBiogenico: -0.48; CombustiveisFosseisComPotencialDeAquecimentoGlobal: 13.9; PotencialDeAquecimentoGlobalUsoDoSoloEMudancaDeUsoDoSolo: 0.0246; PotencialDeEutrofizacaoFraccaoDeNutrientesQueAtingemOCompartimentoFinalDeAguaDoce: 0.000189; PotencialDeEutrofizacaoFraccaoDeNutrientesQueAtingemOCompartimentoFinalMarinho: 0.0122; EnergiaRecuperada: 0.00739; ConsumoDeAguaDoce: 0.113; UtilizacaoLiquidaDeAguaDoce: 0.113; ResiduosPerigososEliminados: 0.00221; ResiduosNaoPerigososEliminados: 1.83; MassaTotalDeResiduosRadioactivosEliminados: 0.000394; EnergiaElectricaExportada: 1.55; MateriaisParaRecuperacaoDeEnergia: 0.00739; MateriaisParaReciclagem: 0.0253; UnidadeEPD: 1 m²
Type - IFC.REVIGRÉS-Dados gerais-Wall Covering - Nome: REVIGRÉS-URBAN-BASE-59.2X59.2-RECT-ANTISLIP URBAN BONE; TipoProduto: Prensado a seco: grupo BIa UGL | Grés porcelânico técnico; NumeroDeRegistoDAP: EPD-REV-20240006-CCC1-EN; ReferenciaDAP: -; UrlDOP: -
Classification: C3010 (Uniformat)
Pset_QuantityTakeOff - sets with these values: 2
Pset_WallCommon - ExtendToStructure: no; LoadBearing: no
IFC.REVIGRÉS-Dados do fabricante-Wall Covering - Type: Basic Wall: REVIGRÉS-URBAN-BASE-59,2X59,2-RECT-ANTISLIP BONE
IFC.REVIGRÉS-Dados de desempenho-Wall Covering - Type: Basic Wall: REVIGRÉS-URBAN-BASE-59,2X59,2-RECT-ANTISLIP BONE
IFC.REVIGRÉS-Dados de especificação-Wall Covering - Type: Basic Wall: REVIGRÉS-URBAN-BASE-59,2X59,2-RECT-ANTISLIP BONE
IFC.REVIGRÉS-Dados geométricos-Wall Covering - Type: Basic Wall: REVIGRÉS-URBAN-BASE-59,2X59,2-RECT-ANTISLIP BONE
IFC.REVIGRÉS-Dados de sustentabilidade-Wall Covering - Type: Basic Wall: REVIGRÉS-URBAN-BASE-59,2X59,2-RECT-ANTISLIP BONE

# IfcWallStandardCase: Basic Wall:REVIGRÉS-URBAN-BASE-59,2X59,2-RECT-ANTISLIP CRAFT, Basic Wall:REVIGRÉS-URBAN-BASE-59,2X59,2-RECT-ANTISLIP CRAFT:26615
In: Level 1
Type - PredefinedType: STANDARD; Material: REVIGRÉS-URBAN-BASE-60X60-RECT-ANTISLIP CRAFT 10.5 mm
Type - Pset_ElementShading - Roughness: 304.8 mm
Type - Pset_ManufacturerTypeInformation - Manufacturer: REVIGRÉS
Type - Pset_ProductRequirements - Category: Walls
Type - Pset_QuantityTakeOff - Reference: 31211335T1
Type - Pset_ReinforcementBarPitchOfWall - Reference: 31211335T1
Type - Pset_WallCommon - IsExternal: no; Reference: 31211335T1
Type - IFC.REVIGRÉS-Dados do fabricante-Wall Covering - FabricanteURL: https://www.revigres.pt/; ReferenciaModelo: Urban; NumeroGlobalDeItemComercial: 31211335T1; Acabamento: RECT; Material: Grés porcelânico; IdentificadorDoOperadorEconomico: 501840856; UrlFabricanteArtigo: https://www.revigres.pt/colecoes/urban; PaisOrigem: Portugal
Type - IFC.REVIGRÉS-Dados de desempenho-Wall Covering - Rectilinearidade: ± 0.2% máx.± 0.8 mm; Ortogonalidade: ± 0.2% máx.± 1.5 mm; PlanaridadeDaSuperficie: ± 0.3% máx. ± 1.8 mm; QualidadeDaSuperficie: Cumpre; AbsorcaoDeAgua: < 0.05%; ModuloDeRuptura: > 45 N/mm²; ResistenciaAFlexao: > 3500 N; ResistenciaAAbrasaoProfunda: < 120 mm³; DilatacaoTermicaLinear: ≤ 8,0x10-6 °C-1; ResistenciaAoChoqueTermico: Resiste; DurabilidadeResistenciaAoGeloDegelo: Resiste; ResistenciaAoEscorregamentoDIN51130: R9; ResistenciaAoEscorregamentoDIN51097: A; ResistenciaAoEscorregamentoENV51097: A; ResistenciaAoEscorregamentoENV12633: Class 1; ResistenciaAoEscorregamentoANSIA1371: ≥0,42; ResistenciaAoDeslizamentoENV12633: Class 1; ResistenciaAsManchas: Class 5; ResistenciaABaixasConcentracoesDeAcidosEAlcalis: Classe LA; ResistenciaAAltasConcentracoesDeAcidosEAlcalis: Classe HA; LibertacaoDeCadmio: 0; LibertacaoDeChumbo: 0
Type - IFC.REVIGRÉS-Dados de especificação-Wall Covering - VariacaoTonalidade: 2; NivelDeTrafego: 5; EPavimento: Sim; ERevestimento: Sim; EExterno: Sim
Type - IFC.REVIGRÉS-Dados geométricos-Wall Covering - AlturaNominal: 8.5 mm; ComprimentoNominal: 59.2 mm; LarguraNominal: 59.2 mm
Type - IFC.REVIGRÉS-Dados de sustentabilidade-Wall Covering - PotencialPrivacaoDeAguaConsumoDeAguaPonderado: 4.5; EnergiaTermicaExportada: 0; ItemENovo: Sim; ItemEParcialmenteReciclado: 0.23; ItemEReciclado: Sim; VidaÚtilEsperada: 50; SubstanciasPerigosas: Não; PotencialDeEsgotamentoAbioticoDosRecursosFosseis: 203; PotencialDeEsgotamentoAbioticoDosRecursosNaoFosseisMineraisEMetais: 0.000701; PotencialDeAquecimentoGlobalBiogenico: -0.48; CombustiveisFosseisComPotencialDeAquecimentoGlobal: 13.9; PotencialDeAquecimentoGlobalUsoDoSoloEMudancaDeUsoDoSolo: 0.0246; PotencialDeEutrofizacaoFraccaoDeNutrientesQueAtingemOCompartimentoFinalDeAguaDoce: 0.000189; PotencialDeEutrofizacaoFraccaoDeNutrientesQueAtingemOCompartimentoFinalMarinho: 0.0122; EnergiaRecuperada: 0.00739; ConsumoDeAguaDoce: 0.113; UtilizacaoLiquidaDeAguaDoce: 0.113; ResiduosPerigososEliminados: 0.00221; ResiduosNaoPerigososEliminados: 1.83; MassaTotalDeResiduosRadioactivosEliminados: 0.000394; EnergiaElectricaExportada: 1.55; MateriaisParaRecuperacaoDeEnergia: 0.00739; MateriaisParaReciclagem: 0.0253; UnidadeEPD: 1 m²
Type - IFC.REVIGRÉS-Dados gerais-Wall Covering - Nome: REVIGRÉS-URBAN-BASE-59.2X59.2-RECT-ANTISLIP URBAN CRAFT; TipoProduto: Prensado a seco: grupo BIa UGL | Grés porcelânico técnico; NumeroDeRegistoDAP: EPD-REV-20240006-CCC1-EN; ReferenciaDAP: -; UrlDOP: -
Classification: C3010 (Uniformat)
Pset_QuantityTakeOff - sets with these values: 2
Pset_WallCommon - ExtendToStructure: no; LoadBearing: no
IFC.REVIGRÉS-Dados do fabricante-Wall Covering - Type: Basic Wall: REVIGRÉS-URBAN-BASE-59,2X59,2-RECT-ANTISLIP CRAFT
IFC.REVIGRÉS-Dados de desempenho-Wall Covering - Type: Basic Wall: REVIGRÉS-URBAN-BASE-59,2X59,2-RECT-ANTISLIP CRAFT
IFC.REVIGRÉS-Dados de especificação-Wall Covering - Type: Basic Wall: REVIGRÉS-URBAN-BASE-59,2X59,2-RECT-ANTISLIP CRAFT
IFC.REVIGRÉS-Dados geométricos-Wall Covering - Type: Basic Wall: REVIGRÉS-URBAN-BASE-59,2X59,2-RECT-ANTISLIP CRAFT
IFC.REVIGRÉS-Dados de sustentabilidade-Wall Covering - Type: Basic Wall: REVIGRÉS-URBAN-BASE-59,2X59,2-RECT-ANTISLIP CRAFT

# IfcWallStandardCase: Basic Wall:REVIGRÉS-URBAN-BASE-59,2X59,2-RECT-ANTISLIP FOG, Basic Wall:REVIGRÉS-URBAN-BASE-59,2X59,2-RECT-ANTISLIP FOG:26623
In: Level 1
Type - PredefinedType: STANDARD; Material: REVIGRÉS-URBAN-BASE-60X60-RECT-ANTISLIP FOG 10.5 mm
Type - Pset_ElementShading - Roughness: 304.8 mm
Type - Pset_ManufacturerTypeInformation - Manufacturer: REVIGRÉS
Type - Pset_ProductRequirements - Category: Walls
Type - Pset_QuantityTakeOff - Reference: 31211332T1
Type - Pset_ReinforcementBarPitchOfWall - Reference: 31211332T1
Type - Pset_WallCommon - IsExternal: no; Reference: 31211332T1
Type - IFC.REVIGRÉS-Dados do fabricante-Wall Covering - FabricanteURL: https://www.revigres.pt/; ReferenciaModelo: Urban; NumeroGlobalDeItemComercial: 31211332T1; Acabamento: RECT; Material: Grés porcelânico; IdentificadorDoOperadorEconomico: 501840856; UrlFabricanteArtigo: https://www.revigres.pt/colecoes/urban; PaisOrigem: Portugal
Type - IFC.REVIGRÉS-Dados de desempenho-Wall Covering - Rectilinearidade: ± 0.2% máx.± 0.8 mm; Ortogonalidade: ± 0.2% máx.± 1.5 mm; PlanaridadeDaSuperficie: ± 0.3% máx. ± 1.8 mm; QualidadeDaSuperficie: Cumpre; AbsorcaoDeAgua: < 0.05%; ModuloDeRuptura: > 45 N/mm²; ResistenciaAFlexao: > 3500 N; ResistenciaAAbrasaoProfunda: < 120 mm³; DilatacaoTermicaLinear: ≤ 8,0x10-6 °C-1; ResistenciaAoChoqueTermico: Resiste; DurabilidadeResistenciaAoGeloDegelo: Resiste; ResistenciaAoEscorregamentoDIN51130: R9; ResistenciaAoEscorregamentoDIN51097: A; ResistenciaAoEscorregamentoENV51097: A; ResistenciaAoEscorregamentoENV12633: Class 1; ResistenciaAoEscorregamentoANSIA1371: ≥0,42; ResistenciaAoDeslizamentoENV12633: Class 1; ResistenciaAsManchas: Class 5; ResistenciaABaixasConcentracoesDeAcidosEAlcalis: Classe LA; ResistenciaAAltasConcentracoesDeAcidosEAlcalis: Classe HA; LibertacaoDeCadmio: 0; LibertacaoDeChumbo: 0
Type - IFC.REVIGRÉS-Dados de especificação-Wall Covering - VariacaoTonalidade: 2; NivelDeTrafego: 5; EPavimento: Sim; ERevestimento: Sim; EExterno: Sim
Type - IFC.REVIGRÉS-Dados geométricos-Wall Covering - AlturaNominal: 8.5 mm; ComprimentoNominal: 59.2 mm; LarguraNominal: 59.2 mm
Type - IFC.REVIGRÉS-Dados de sustentabilidade-Wall Covering - PotencialPrivacaoDeAguaConsumoDeAguaPonderado: 4.5; EnergiaTermicaExportada: 0; ItemENovo: Sim; ItemEParcialmenteReciclado: 0.23; ItemEReciclado: Sim; VidaÚtilEsperada: 50; SubstanciasPerigosas: Não; PotencialDeEsgotamentoAbioticoDosRecursosFosseis: 203; PotencialDeEsgotamentoAbioticoDosRecursosNaoFosseisMineraisEMetais: 0.000701; PotencialDeAquecimentoGlobalBiogenico: -0.48; CombustiveisFosseisComPotencialDeAquecimentoGlobal: 13.9; PotencialDeAquecimentoGlobalUsoDoSoloEMudancaDeUsoDoSolo: 0.0246; PotencialDeEutrofizacaoFraccaoDeNutrientesQueAtingemOCompartimentoFinalDeAguaDoce: 0.000189; PotencialDeEutrofizacaoFraccaoDeNutrientesQueAtingemOCompartimentoFinalMarinho: 0.0122; EnergiaRecuperada: 0.00739; ConsumoDeAguaDoce: 0.113; UtilizacaoLiquidaDeAguaDoce: 0.113; ResiduosPerigososEliminados: 0.00221; ResiduosNaoPerigososEliminados: 1.83; MassaTotalDeResiduosRadioactivosEliminados: 0.000394; EnergiaElectricaExportada: 1.55; MateriaisParaRecuperacaoDeEnergia: 0.00739; MateriaisParaReciclagem: 0.0253; UnidadeEPD: 1 m²
Type - IFC.REVIGRÉS-Dados gerais-Wall Covering - Nome: REVIGRÉS-URBAN-BASE-59.2X59.2-RECT-ANTISLIP URBAN FOG; TipoProduto: Prensado a seco: grupo BIa UGL | Grés porcelânico técnico; NumeroDeRegistoDAP: EPD-REV-20240006-CCC1-EN; ReferenciaDAP: -; UrlDOP: -
Classification: C3010 (Uniformat)
Pset_QuantityTakeOff - sets with these values: 2
Pset_WallCommon - ExtendToStructure: no; LoadBearing: no
IFC.REVIGRÉS-Dados do fabricante-Wall Covering - Type: Basic Wall: REVIGRÉS-URBAN-BASE-59,2X59,2-RECT-ANTISLIP FOG
IFC.REVIGRÉS-Dados de desempenho-Wall Covering - Type: Basic Wall: REVIGRÉS-URBAN-BASE-59,2X59,2-RECT-ANTISLIP FOG
IFC.REVIGRÉS-Dados de especificação-Wall Covering - Type: Basic Wall: REVIGRÉS-URBAN-BASE-59,2X59,2-RECT-ANTISLIP FOG
IFC.REVIGRÉS-Dados geométricos-Wall Covering - Type: Basic Wall: REVIGRÉS-URBAN-BASE-59,2X59,2-RECT-ANTISLIP FOG
IFC.REVIGRÉS-Dados de sustentabilidade-Wall Covering - Type: Basic Wall: REVIGRÉS-URBAN-BASE-59,2X59,2-RECT-ANTISLIP FOG

# IfcWallStandardCase: Basic Wall:REVIGRÉS-URBAN-BASE-59,2X59,2-RECT-ANTISLIP GRIS, Basic Wall:REVIGRÉS-URBAN-BASE-59,2X59,2-RECT-ANTISLIP GRIS:26631
In: Level 1
Type - PredefinedType: STANDARD; Material: REVIGRÉS-URBAN-BASE-60X60-RECT-ANTISLIP GRIS 10.5 mm
Type - Pset_ElementShading - Roughness: 304.8 mm
Type - Pset_ManufacturerTypeInformation - Manufacturer: REVIGRÉS
Type - Pset_ProductRequirements - Category: Walls
Type - Pset_QuantityTakeOff - Reference: 31211333T1
Type - Pset_ReinforcementBarPitchOfWall - Reference: 31211333T1
Type - Pset_WallCommon - IsExternal: no; Reference: 31211333T1
Type - IFC.REVIGRÉS-Dados do fabricante-Wall Covering - FabricanteURL: https://www.revigres.pt/; ReferenciaModelo: Urban; NumeroGlobalDeItemComercial: 31211333T1; Acabamento: RECT; Material: Grés porcelânico; IdentificadorDoOperadorEconomico: 501840856; UrlFabricanteArtigo: https://www.revigres.pt/colecoes/urban; PaisOrigem: Portugal
Type - IFC.REVIGRÉS-Dados de desempenho-Wall Covering - Rectilinearidade: ± 0.2% máx.± 0.8 mm; Ortogonalidade: ± 0.2% máx.± 1.5 mm; PlanaridadeDaSuperficie: ± 0.3% máx. ± 1.8 mm; QualidadeDaSuperficie: Cumpre; AbsorcaoDeAgua: < 0.05%; ModuloDeRuptura: > 45 N/mm²; ResistenciaAFlexao: > 3500 N; ResistenciaAAbrasaoProfunda: < 120 mm³; DilatacaoTermicaLinear: ≤ 8,0x10-6 °C-1; ResistenciaAoChoqueTermico: Resiste; DurabilidadeResistenciaAoGeloDegelo: Resiste; ResistenciaAoEscorregamentoDIN51130: R9; ResistenciaAoEscorregamentoDIN51097: A; ResistenciaAoEscorregamentoENV51097: A; ResistenciaAoEscorregamentoENV12633: Class 1; ResistenciaAoEscorregamentoANSIA1371: ≥0,42; ResistenciaAoDeslizamentoENV12633: Class 1; ResistenciaAsManchas: Class 5; ResistenciaABaixasConcentracoesDeAcidosEAlcalis: Classe LA; ResistenciaAAltasConcentracoesDeAcidosEAlcalis: Classe HA; LibertacaoDeCadmio: 0; LibertacaoDeChumbo: 0
Type - IFC.REVIGRÉS-Dados de especificação-Wall Covering - VariacaoTonalidade: 2; NivelDeTrafego: 5; EPavimento: Sim; ERevestimento: Sim; EExterno: Sim
Type - IFC.REVIGRÉS-Dados geométricos-Wall Covering - AlturaNominal: 8.5 mm; ComprimentoNominal: 59.2 mm; LarguraNominal: 59.2 mm
Type - IFC.REVIGRÉS-Dados de sustentabilidade-Wall Covering - PotencialPrivacaoDeAguaConsumoDeAguaPonderado: 4.5; EnergiaTermicaExportada: 0; ItemENovo: Sim; ItemEParcialmenteReciclado: 0.03; ItemEReciclado: Sim; VidaÚtilEsperada: 50; SubstanciasPerigosas: Não; PotencialDeEsgotamentoAbioticoDosRecursosFosseis: 203; PotencialDeEsgotamentoAbioticoDosRecursosNaoFosseisMineraisEMetais: 0.000701; PotencialDeAquecimentoGlobalBiogenico: -0.48; CombustiveisFosseisComPotencialDeAquecimentoGlobal: 13.9; PotencialDeAquecimentoGlobalUsoDoSoloEMudancaDeUsoDoSolo: 0.0246; PotencialDeEutrofizacaoFraccaoDeNutrientesQueAtingemOCompartimentoFinalDeAguaDoce: 0.000189; PotencialDeEutrofizacaoFraccaoDeNutrientesQueAtingemOCompartimentoFinalMarinho: 0.0122; EnergiaRecuperada: 0.00739; ConsumoDeAguaDoce: 0.113; UtilizacaoLiquidaDeAguaDoce: 0.113; ResiduosPerigososEliminados: 0.00221; ResiduosNaoPerigososEliminados: 1.83; MassaTotalDeResiduosRadioactivosEliminados: 0.000394; EnergiaElectricaExportada: 1.55; MateriaisParaRecuperacaoDeEnergia: 0.00739; MateriaisParaReciclagem: 0.0253; UnidadeEPD: 1 m²
Type - IFC.REVIGRÉS-Dados gerais-Wall Covering - Nome: REVIGRÉS-URBAN-BASE-59.2X59.2-RECT-ANTISLIP URBAN GRIS; TipoProduto: Prensado a seco: grupo BIa UGL | Grés porcelânico técnico; NumeroDeRegistoDAP: EPD-REV-20240006-CCC1-EN; ReferenciaDAP: -; UrlDOP: -
Classification: C3010 (Uniformat)
Pset_QuantityTakeOff - sets with these values: 2
Pset_WallCommon - ExtendToStructure: no; LoadBearing: no
IFC.REVIGRÉS-Dados do fabricante-Wall Covering - Type: Basic Wall: REVIGRÉS-URBAN-BASE-59,2X59,2-RECT-ANTISLIP GRIS
IFC.REVIGRÉS-Dados de desempenho-Wall Covering - Type: Basic Wall: REVIGRÉS-URBAN-BASE-59,2X59,2-RECT-ANTISLIP GRIS
IFC.REVIGRÉS-Dados de especificação-Wall Covering - Type: Basic Wall: REVIGRÉS-URBAN-BASE-59,2X59,2-RECT-ANTISLIP GRIS
IFC.REVIGRÉS-Dados geométricos-Wall Covering - Type: Basic Wall: REVIGRÉS-URBAN-BASE-59,2X59,2-RECT-ANTISLIP GRIS
IFC.REVIGRÉS-Dados de sustentabilidade-Wall Covering - Type: Basic Wall: REVIGRÉS-URBAN-BASE-59,2X59,2-RECT-ANTISLIP GRIS

# IfcWallStandardCase: Basic Wall:REVIGRÉS-URBAN-BASE-59,2X59,2-RECT-ANTISLIP OFFWHITE, Basic Wall:REVIGRÉS-URBAN-BASE-59,2X59,2-RECT-ANTISLIP OFFWHITE:26639
In: Level 1
Type - PredefinedType: STANDARD; Material: REVIGRÉS-URBAN-BASE-60X60-RECT-ANTISLIP OFFWHITE 10.5 mm
Type - Pset_ElementShading - Roughness: 304.8 mm
Type - Pset_ManufacturerTypeInformation - Manufacturer: REVIGRÉS
Type - Pset_ProductRequirements - Category: Walls
Type - Pset_QuantityTakeOff - Reference: 31211334T1
Type - Pset_ReinforcementBarPitchOfWall - Reference: 31211334T1
Type - Pset_WallCommon - IsExternal: no; Reference: 31211334T1
Type - IFC.REVIGRÉS-Dados do fabricante-Wall Covering - FabricanteURL: https://www.revigres.pt/; ReferenciaModelo: Urban; NumeroGlobalDeItemComercial: 31211334T1; Acabamento: RECT; Material: Grés porcelânico; IdentificadorDoOperadorEconomico: 501840856; UrlFabricanteArtigo: https://www.revigres.pt/colecoes/urban; PaisOrigem: Portugal
Type - IFC.REVIGRÉS-Dados de desempenho-Wall Covering - Rectilinearidade: ± 0.2% máx.± 0.8 mm; Ortogonalidade: ± 0.2% máx.± 1.5 mm; PlanaridadeDaSuperficie: ± 0.3% máx. ± 1.8 mm; QualidadeDaSuperficie: Cumpre; AbsorcaoDeAgua: < 0.05%; ModuloDeRuptura: > 45 N/mm²; ResistenciaAFlexao: > 3500 N; ResistenciaAAbrasaoProfunda: < 120 mm³; DilatacaoTermicaLinear: ≤ 8,0x10-6 °C-1; ResistenciaAoChoqueTermico: Resiste; DurabilidadeResistenciaAoGeloDegelo: Resiste; ResistenciaAoEscorregamentoDIN51130: R9; ResistenciaAoEscorregamentoDIN51097: A; ResistenciaAoEscorregamentoENV51097: A; ResistenciaAoEscorregamentoENV12633: Class 1; ResistenciaAoEscorregamentoANSIA1371: ≥0,42; ResistenciaAoDeslizamentoENV12633: Class 1; ResistenciaAsManchas: Class 5; ResistenciaABaixasConcentracoesDeAcidosEAlcalis: Classe LA; ResistenciaAAltasConcentracoesDeAcidosEAlcalis: Classe HA; LibertacaoDeCadmio: 0; LibertacaoDeChumbo: 0
Type - IFC.REVIGRÉS-Dados de especificação-Wall Covering - VariacaoTonalidade: 2; NivelDeTrafego: 5; EPavimento: Sim; ERevestimento: Sim; EExterno: Sim
Type - IFC.REVIGRÉS-Dados geométricos-Wall Covering - AlturaNominal: 8.5 mm; ComprimentoNominal: 59.2 mm; LarguraNominal: 59.2 mm
Type - IFC.REVIGRÉS-Dados de sustentabilidade-Wall Covering - PotencialPrivacaoDeAguaConsumoDeAguaPonderado: 4.5; EnergiaTermicaExportada: 0; ItemENovo: Sim; ItemEParcialmenteReciclado: 0.29; ItemEReciclado: Sim; VidaÚtilEsperada: 50; SubstanciasPerigosas: Não; PotencialDeEsgotamentoAbioticoDosRecursosFosseis: 203; PotencialDeEsgotamentoAbioticoDosRecursosNaoFosseisMineraisEMetais: 0.000701; PotencialDeAquecimentoGlobalBiogenico: -0.48; CombustiveisFosseisComPotencialDeAquecimentoGlobal: 13.9; PotencialDeAquecimentoGlobalUsoDoSoloEMudancaDeUsoDoSolo: 0.0246; PotencialDeEutrofizacaoFraccaoDeNutrientesQueAtingemOCompartimentoFinalDeAguaDoce: 0.000189; PotencialDeEutrofizacaoFraccaoDeNutrientesQueAtingemOCompartimentoFinalMarinho: 0.0122; EnergiaRecuperada: 0.00739; ConsumoDeAguaDoce: 0.113; UtilizacaoLiquidaDeAguaDoce: 0.113; ResiduosPerigososEliminados: 0.00221; ResiduosNaoPerigososEliminados: 1.83; MassaTotalDeResiduosRadioactivosEliminados: 0.000394; EnergiaElectricaExportada: 1.55; MateriaisParaRecuperacaoDeEnergia: 0.00739; MateriaisParaReciclagem: 0.0253; UnidadeEPD: 1 m²
Type - IFC.REVIGRÉS-Dados gerais-Wall Covering - Nome: REVIGRÉS-URBAN-BASE-59.2X59.2-RECT-ANTISLIP URBAN OFFWHITE; TipoProduto: Prensado a seco: grupo BIa UGL | Grés porcelânico técnico; NumeroDeRegistoDAP: EPD-REV-20240006-CCC1-EN; ReferenciaDAP: -; UrlDOP: -
Classification: C3010 (Uniformat)
Pset_QuantityTakeOff - sets with these values: 2
Pset_WallCommon - ExtendToStructure: no; LoadBearing: no
IFC.REVIGRÉS-Dados do fabricante-Wall Covering - Type: Basic Wall: REVIGRÉS-URBAN-BASE-59,2X59,2-RECT-ANTISLIP OFFWHITE
IFC.REVIGRÉS-Dados de desempenho-Wall Covering - Type: Basic Wall: REVIGRÉS-URBAN-BASE-59,2X59,2-RECT-ANTISLIP OFFWHITE
IFC.REVIGRÉS-Dados de especificação-Wall Covering - Type: Basic Wall: REVIGRÉS-URBAN-BASE-59,2X59,2-RECT-ANTISLIP OFFWHITE
IFC.REVIGRÉS-Dados geométricos-Wall Covering - Type: Basic Wall: REVIGRÉS-URBAN-BASE-59,2X59,2-RECT-ANTISLIP OFFWHITE
IFC.REVIGRÉS-Dados de sustentabilidade-Wall Covering - Type: Basic Wall: REVIGRÉS-URBAN-BASE-59,2X59,2-RECT-ANTISLIP OFFWHITE

# IfcWallStandardCase: Basic Wall:REVIGRÉS-URBAN-BASE-59,2X59,2-RECT-ANTRACITE, Basic Wall:REVIGRÉS-URBAN-BASE-59,2X59,2-RECT-ANTRACITE:22901
In: Level 1
Type - PredefinedType: STANDARD; Material: REVIGRÉS-URBAN-BASE-60X60-RECT-ANTRACITE 10.5 mm
Type - Pset_ElementShading - Roughness: 304.8 mm
Type - Pset_ManufacturerTypeInformation - Manufacturer: REVIGRÉS
Type - Pset_ProductRequirements - Category: Walls
Type - Pset_QuantityTakeOff - Reference: 31211348U1
Type - Pset_ReinforcementBarPitchOfWall - Reference: 31211348U1
Type - Pset_WallCommon - IsExternal: no; Reference: 31211348U1
Type - IFC.REVIGRÉS-Dados do fabricante-Wall Covering - FabricanteURL: https://www.revigres.pt/; ReferenciaModelo: Urban; NumeroGlobalDeItemComercial: 31211348U1; Acabamento: RECT; Material: Grés porcelânico; IdentificadorDoOperadorEconomico: 501840856; UrlFabricanteArtigo: https://www.revigres.pt/colecoes/urban; PaisOrigem: Portugal
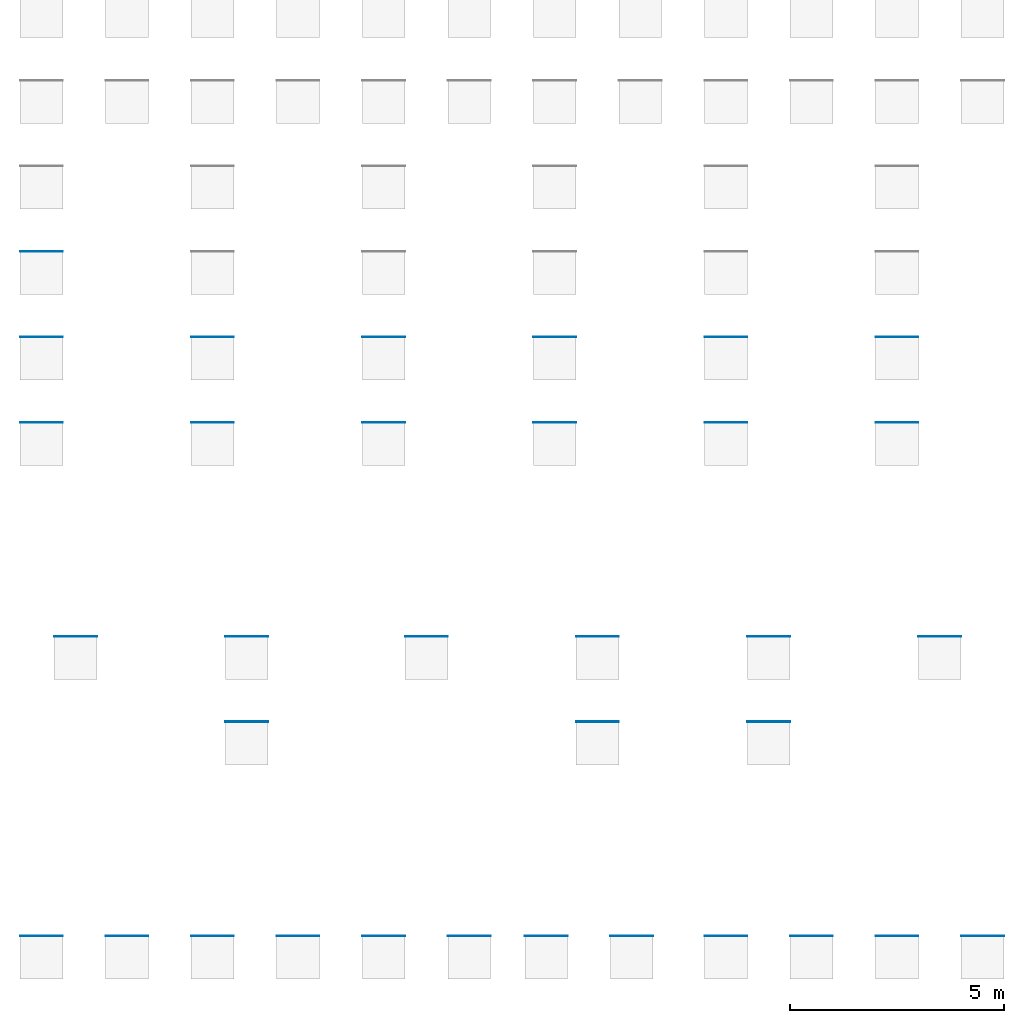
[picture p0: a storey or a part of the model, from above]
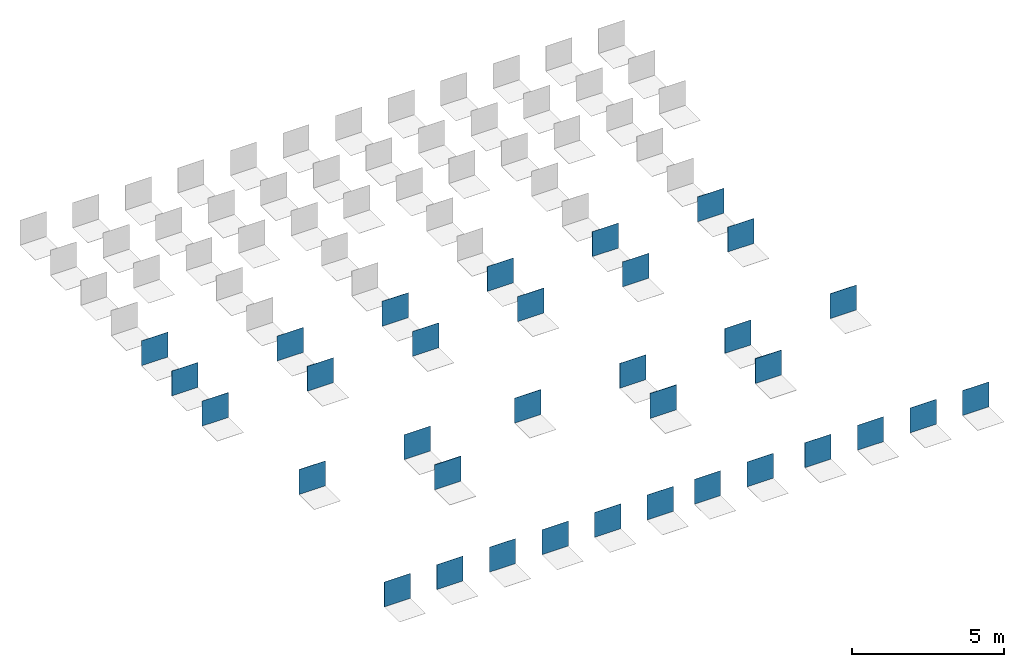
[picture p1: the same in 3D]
Properties of the parts of a building model (IFC2X3), part 12 of 12

# IfcWallStandardCase: Basic Wall:REVIGRÉS-URBAN-BASE-88,9X88,9-RECT-OFFWHITE, Basic Wall:REVIGRÉS-URBAN-BASE-88,9X88,9-RECT-OFFWHITE:23183
Type - IFC.REVIGRÉS-Dados de sustentabilidade-Wall Covering - PotencialPrivacaoDeAguaConsumoDeAguaPonderado: 4.5; EnergiaTermicaExportada: 0; ItemENovo: Sim; ItemEParcialmenteReciclado: 0.03; ItemEReciclado: Sim; VidaÚtilEsperada: 50; SubstanciasPerigosas: Não; PotencialDeEsgotamentoAbioticoDosRecursosFosseis: 203; PotencialDeEsgotamentoAbioticoDosRecursosNaoFosseisMineraisEMetais: 0.000701; PotencialDeAquecimentoGlobalBiogenico: -0.48; CombustiveisFosseisComPotencialDeAquecimentoGlobal: 13.9; PotencialDeAquecimentoGlobalUsoDoSoloEMudancaDeUsoDoSolo: 0.0246; PotencialDeEutrofizacaoFraccaoDeNutrientesQueAtingemOCompartimentoFinalDeAguaDoce: 0.000189; PotencialDeEutrofizacaoFraccaoDeNutrientesQueAtingemOCompartimentoFinalMarinho: 0.0122; EnergiaRecuperada: 0.00739; ConsumoDeAguaDoce: 0.113; UtilizacaoLiquidaDeAguaDoce: 0.113; ResiduosPerigososEliminados: 0.00221; ResiduosNaoPerigososEliminados: 1.83; MassaTotalDeResiduosRadioactivosEliminados: 0.000394; EnergiaElectricaExportada: 1.55; MateriaisParaRecuperacaoDeEnergia: 0.00739; MateriaisParaReciclagem: 0.0253; UnidadeEPD: 1 m²
Type - IFC.REVIGRÉS-Dados gerais-Wall Covering - Nome: REVIGRÉS-URBAN-BASE-88.9X88.9-RECT-URBAN OFFWHITE; TipoProduto: Prensado a seco: grupo BIa UGL | Grés porcelânico técnico; NumeroDeRegistoDAP: EPD-REV-20240006-CCC1-EN; ReferenciaDAP: -; UrlDOP: -
Classification: C3010 (Uniformat)
Pset_QuantityTakeOff - sets with these values: 2
Pset_WallCommon - ExtendToStructure: no; LoadBearing: no
IFC.REVIGRÉS-Dados do fabricante-Wall Covering - Type: Basic Wall: REVIGRÉS-URBAN-BASE-88,9X88,9-RECT-OFFWHITE
IFC.REVIGRÉS-Dados de desempenho-Wall Covering - Type: Basic Wall: REVIGRÉS-URBAN-BASE-88,9X88,9-RECT-OFFWHITE
IFC.REVIGRÉS-Dados de especificação-Wall Covering - Type: Basic Wall: REVIGRÉS-URBAN-BASE-88,9X88,9-RECT-OFFWHITE
IFC.REVIGRÉS-Dados geométricos-Wall Covering - Type: Basic Wall: REVIGRÉS-URBAN-BASE-88,9X88,9-RECT-OFFWHITE
IFC.REVIGRÉS-Dados de sustentabilidade-Wall Covering - Type: Basic Wall: REVIGRÉS-URBAN-BASE-88,9X88,9-RECT-OFFWHITE
